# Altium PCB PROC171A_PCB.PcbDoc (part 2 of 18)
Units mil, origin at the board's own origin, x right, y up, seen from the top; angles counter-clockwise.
Board outline 7700 x 2300 mil, 6 copper layers (Top Layer, GND 1, SIG 1, SIG 2, GND 2, Bottom Layer), stack 61.062 mil thick; 945 components, 692 nets, 11945 pads, 1734 vias.

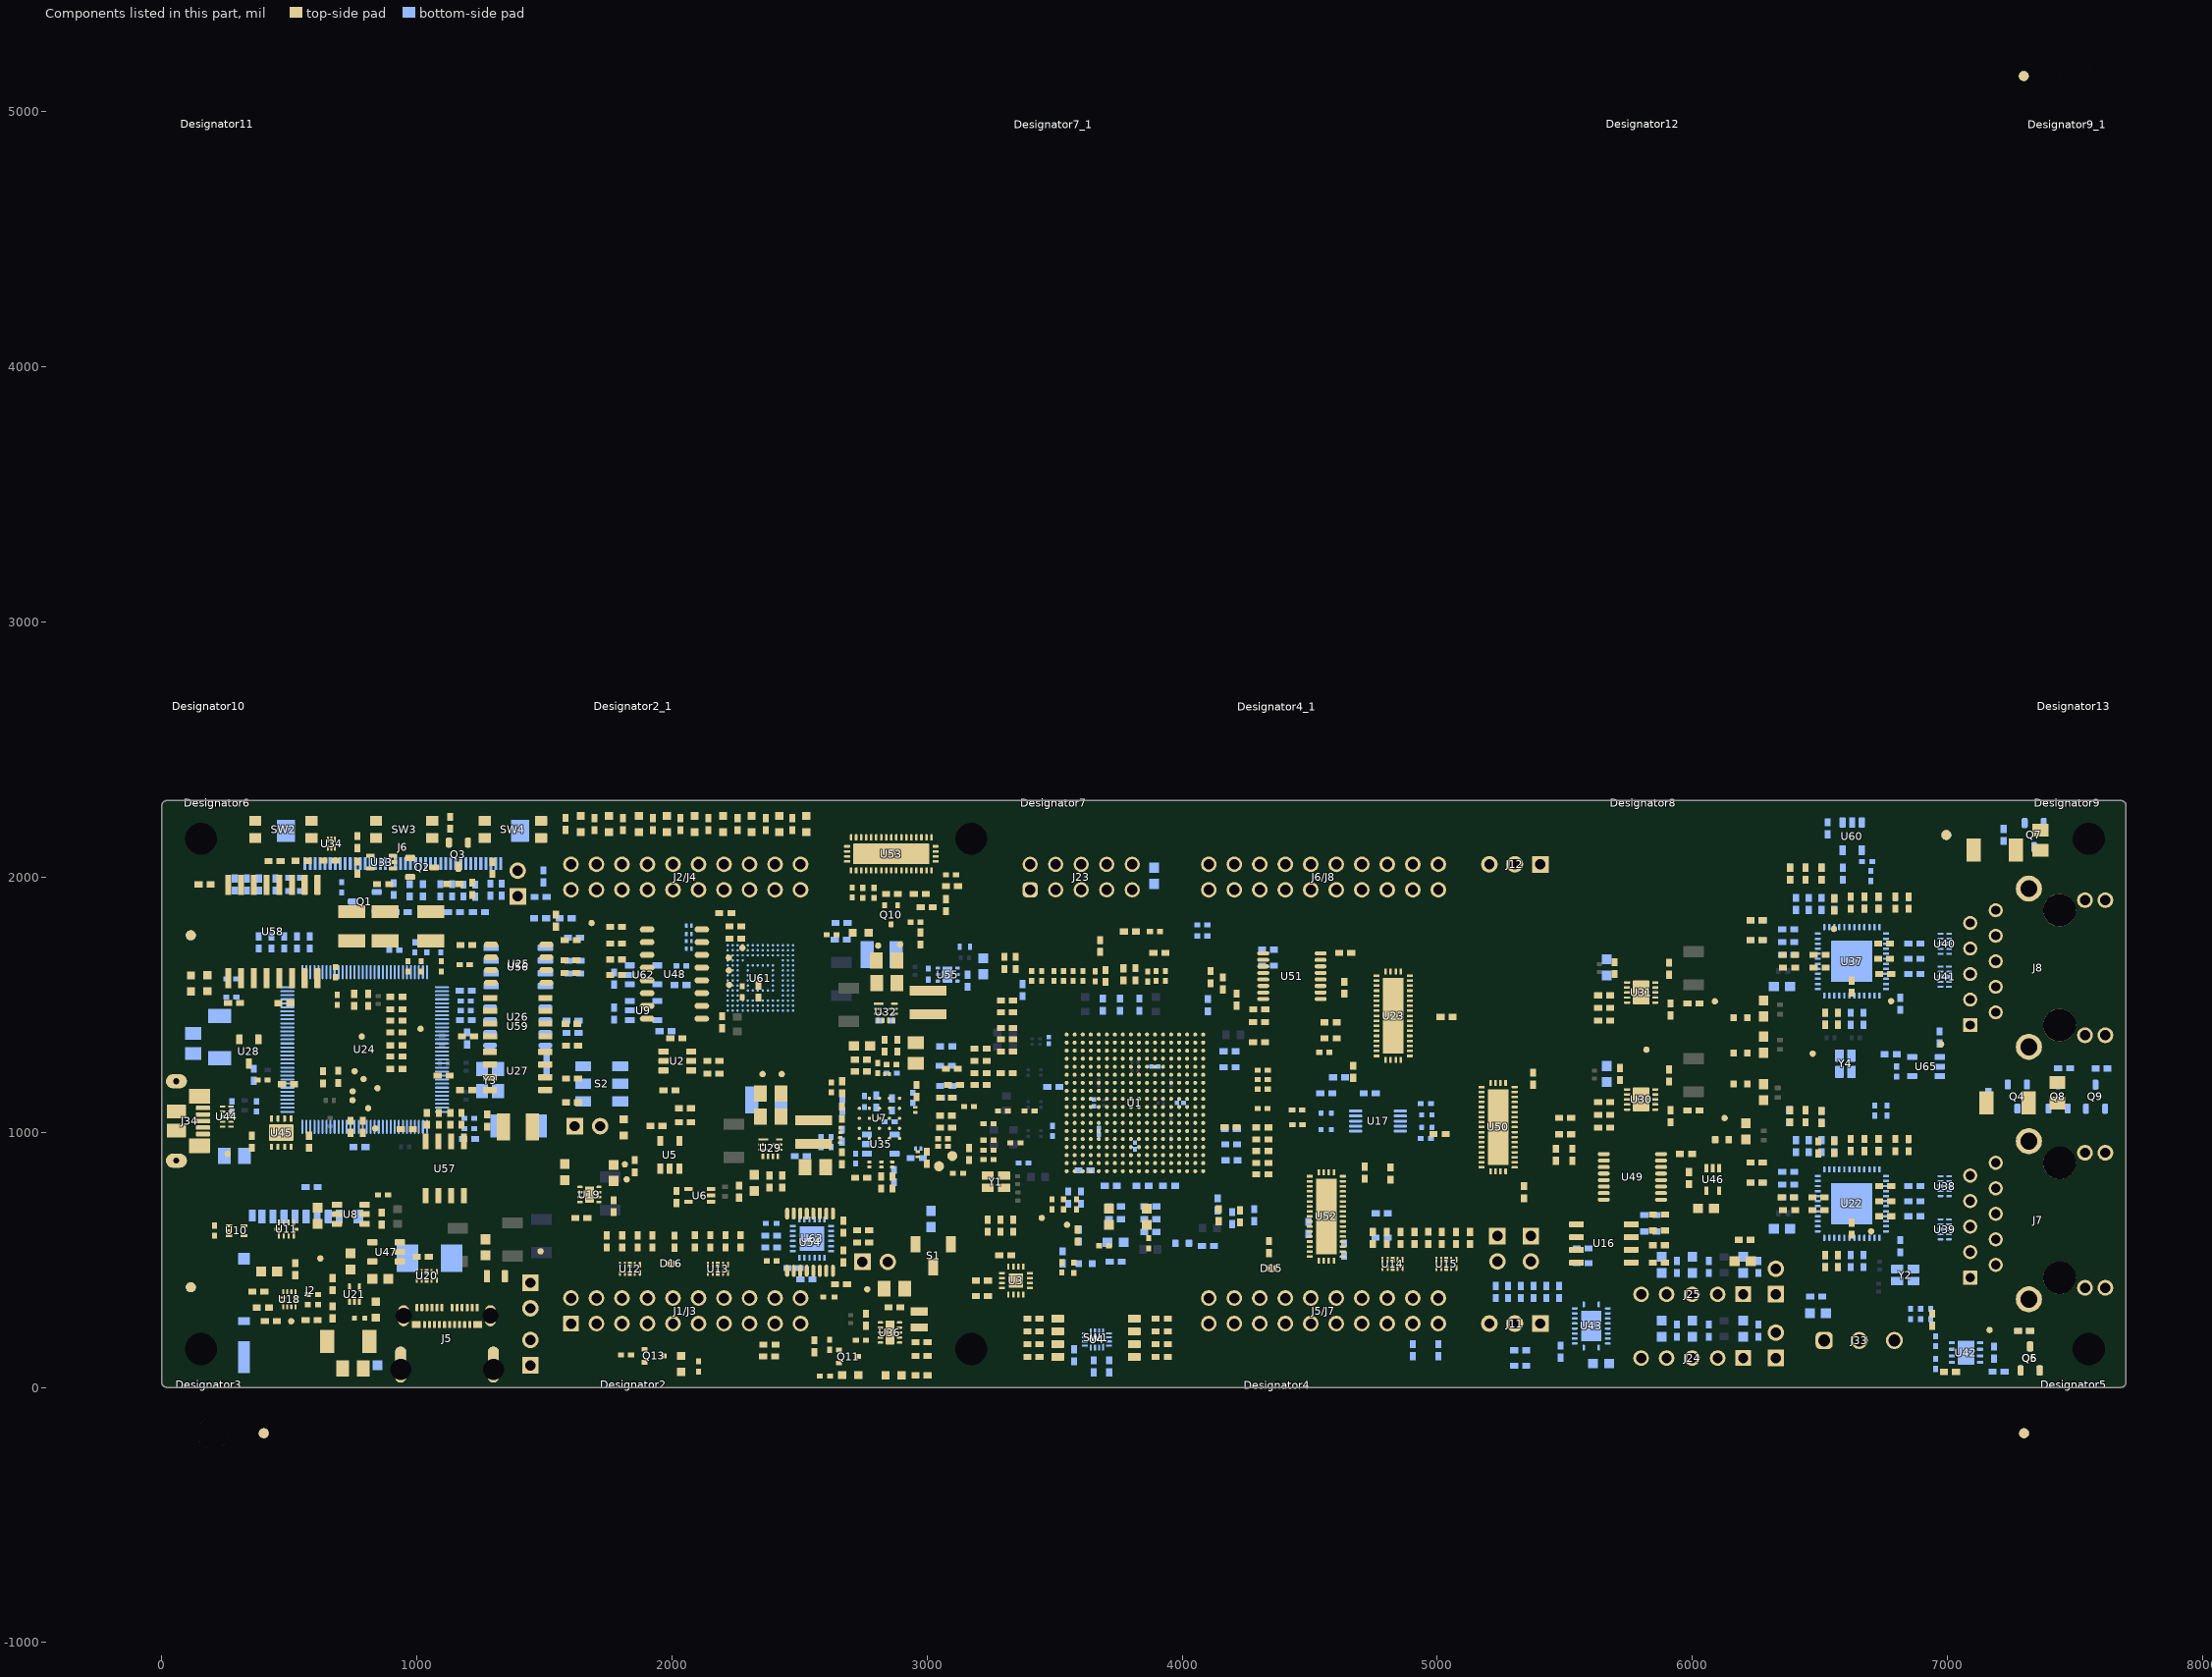
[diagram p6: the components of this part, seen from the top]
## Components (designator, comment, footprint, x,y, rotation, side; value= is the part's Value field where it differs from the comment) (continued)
C257 "GRM155R71E104KE14D" 0402 3617.11,851 r180 bottom value=0.1uF
C258 "KGM05CR51A106MH" FP-KGM05CR51A106MH_0402-MFG 2754.67,1120.32 r90 bottom value=10µF
C259 "885012105010" 0402 2870.35,828.59 r270 bottom value=0.1uF
C260 "885012105010" 0402 2662.59,404.5 r0 top value=0.1uF
C261 "KGM05CR51A106MH" FP-KGM05CR51A106MH_0402-MFG 2615.34,354.8 r180 top value=10µF
C262 "GRM155R71E104KE14D" 0402 168.23,1971.27 r180 top value=0.1uF
C263 "885012105010" 0402 6589.21,2013.14 r270 bottom value=0.1uF
C264 "885012105010" 0402 2338.77,1551.57 r270 top value=0.1uF
C265 "KGM05CR51A106MH" FP-KGM05CR51A106MH_0402-MFG 2274.78,1550.65 r270 top value=10µF
C266 "C1005X6S1C105K050BC" 0402 2664.95,1820.24 r0 bottom value=1uF
C267 "885012105010" 0402 2033.53,1577 r0 bottom value=0.1uF
C268 "885012105010" 0402 2389,548.03 r180 bottom value=0.1uF
C269 "KGM05CR51A106MH" FP-KGM05CR51A106MH_0402-MFG 2389,642.68 r180 bottom value=10µF
C270 "885012105010" 0402 6777.35,1305.89 r180 bottom value=0.1uF
C271 "885012105010" 0402 2862.44,1108.7 r90 bottom value=0.1uF
C272 "885012105010" 0402 2667.72,1107.14 r270 bottom value=0.1uF
"CAUTION HOT SURFACE" "CAUTION HOT SURFACE" IEC_HotSurface_Small 4010.45,1541.41 r0 top
D1 "SMBJ6.5CA" SMB-Bi 1049.65,505.45 r0 bottom value=6.5V
D2 "150060VS75000" WL-SMCW_GREEN 1810.94,1018.81 r270 top value=Green
D3 "150060VS75000" WL-SMCW_GREEN 178.78,1584.03 r90 top value=Green
D4 "150060VS75000" WL-SMCW_GREEN 2526.43,2208.3 r90 top value=Green
D5 "150060VS75000" WL-SMCW_GREEN 2036.27,91.9 r270 top value=Green
D6 "150060VS75000" WL-SMCW_GREEN 2868.49,47.06 r0 top value=Green
D7 "150060VS75000" WL-SMCW_GREEN 2421.16,2208.3 r90 top value=Green
D8 "150060VS75000" WL-SMCW_GREEN 2312.35,2208.3 r90 top value=Green
D9 "150060VS75000" WL-SMCW_GREEN 2200.52,2208.3 r90 top value=Green
D10 "150060VS75000" WL-SMCW_GREEN 2088.59,2208.3 r90 top value=Green
D11 "150060VS75000" WL-SMCW_GREEN 1980.11,2208.3 r90 top value=Green
D12 "150060VS75000" WL-SMCW_GREEN 1870.7,2208.3 r90 top value=Green
D13 "150060VS75000" WL-SMCW_GREEN 1753.16,2208.3 r90 top value=Green
D14 "150060VS75000" WL-SMCW_GREEN 1642.17,2208.3 r90 top value=Green
D15 "TPD1E01B04DPYR" DPY0002A 4351.58,466.66 r180 top
D16 "TPD1E01B04DPYR" DPY0002A 1997.72,485.1 r180 top
Designator2 "Comment" BRAKE_WAY_HOLES1X3 1848.57,-39.37 r0 top
Designator2_1 "Comment" BRAKE_WAY_HOLES1X3 1848.57,2620.63 r0 top
Designator3 "Comment" BRAKE_WAY_HOLES1X3 184.09,-39.37 r0 top
Designator4 "Comment" BRAKE_WAY_HOLES1X3 4372.53,-40.63 r0 top
Designator4_1 "Comment" BRAKE_WAY_HOLES1X3 4372.53,2619.37 r0 top
Designator5 "Comment" BRAKE_WAY_HOLES1X3 7494.59,-39.37 r0 top
Designator6 "Comment" BRAKE_WAY_HOLES1X3 218.32,2340.63 r180 top
Designator7 "Comment" BRAKE_WAY_HOLES1X3 3496.1,2339.37 r180 top
Designator7_1 "Comment" BRAKE_WAY_HOLES1X3 3496.1,4999.37 r180 top
Designator8 "Comment" BRAKE_WAY_HOLES1X3 5807.39,2340.63 r180 top
Designator9 "Comment" BRAKE_WAY_HOLES1X3 7469.96,2339.37 r180 top
Designator9_1 "Comment" BRAKE_WAY_HOLES1X3 7469.96,4999.37 r180 top
Designator10 "Comment" BRAKE_WAY_HOLES1X3 184.09,2620.63 r0 top
Designator11 "Comment" BRAKE_WAY_HOLES1X3 217.32,5000.63 r180 top
Designator12 "Comment" BRAKE_WAY_HOLES1X3 5806.39,5000.63 r180 top
Designator13 "Comment" BRAKE_WAY_HOLES1X3 7494.59,2620.63 r0 top
DS1 "150060RS75000" WL-SMCW_RED 2739.41,1781.37 r180 top value=Red
DS2 "150060RS75000" WL-SMCW_RED 2698.87,47.97 r180 top value=Red
DS3 "150060RS75000" WL-SMCW_RED 115.08,1583.47 r90 top value=Red
DS4 "150060RS75000" WL-SMCW_RED 838.68,304.16 r270 top value=Red
FB1 "BLM18EG121SN1D" FP-BLM18EG121SN1D_0603-MFG 4000.08,564.71 r180 bottom
FB2 "BLM18EG121SN1D" FP-BLM18EG121SN1D_0603-MFG 3621.02,485 r180 bottom
FB3 "BLM18EG121SN1D" FP-BLM18EG121SN1D_0603-MFG 6188.68,1310.55 r0 top
FB4 "BLM18EG121SN1D" FP-BLM18EG121SN1D_0603-MFG 6115.92,970.9 r0 top
FB5 "BLM18EG121SN1D" FP-BLM18EG121SN1D_0603-MFG 6188.68,1449.44 r0 top
FB6 "BLM18EG121SN1D" FP-BLM18EG121SN1D_0603-MFG 6188.68,1188.64 r0 top
FID1 "Fiducial" Fiducial10-20 6995.38,2165 r90 top
FID2 "Fiducial" Fiducial10-20 113.79,392.07 r90 top
FID3 "Fiducial" Fiducial10-20 113.79,1771.83 r90 top
FID4 "Fiducial" Fiducial10-20 6995.38,2165 r90 bottom
FID5 "Fiducial" Fiducial10-20 113.79,392.07 r90 bottom
FID6 "Fiducial" Fiducial10-20 113.79,1771.83 r90 bottom
FID7 "Fiducial" Fiducial10-20 400,-180 r90 top
FID8 "Fiducial" Fiducial10-20 7300,-180 r270 top
FID9 "Fiducial" Fiducial10-20 7299,5140 r270 top
FID10 "Fiducial" Fiducial10-20 7299,5140 r90 bottom
FID11 "Fiducial" Fiducial10-20 7300,-180 r90 bottom
FID12 "Fiducial" Fiducial10-20 400,-180 r270 bottom
J1 "PBC02SAAN" Sullins_PBC02SAAN 1395.54,1975 r180 top locked
J1/J3 "SSQ-110-03-T-D" BoosterPack_40pin_J1J3 2054.17,300 r270 bottom locked
J2 "DM3BT-DSF-PEJS" Hirose_DM3BT-DSF-PEJS 570,362.52 r180 bottom locked
J2/J4 "SSQ-110-03-T-D" BoosterPack_40pin_J2J4 2054.17,2000 r270 bottom locked
J5 "2012670005" FP-2012670005_CONN_USB_9MM39_8MM21-MFG 1118.35,154.53 r0 top locked
J5/J7 "SSQ-110-03-T-D" BoosterPack_40pin_J5J7 4554.17,300 r270 bottom locked
J6 "FH12A-40S-0.5SH(55)" FP-FH12A-40S-0.5SH(55)_FFC40-MFG 945.63,2200 r180 bottom locked
J6/J8 "SSQ-110-03-T-D" BoosterPack_40pin_J6J8 4554.17,2000 r270 bottom locked
J7 "LPJG16314A4NL" FP-LPJG16314A4NL_CONN_RJ45-MFG 7444,655 r90 top locked
J8 "LPJG16314A4NL" FP-LPJG16314A4NL_CONN_RJ45-MFG 7444,1645 r90 top locked
J9 "PBC02SAAN" Sullins_PBC02SAAN 1445,136.05 r180 top
J10 "PBC02SAAN" Sullins_PBC02SAAN 1445,360 r0 top
J11 "PBC03SAAN" PBC03SAAN 5304.17,250 r180 top locked
J12 "PBC03SAAN" PBC03SAAN 5304.17,2050 r180 top locked
J13 "PBC02SAAN" Sullins_PBC02SAAN 5235.83,543.25 r0 top
J14 "PBC02SAAN" Sullins_PBC02SAAN 5367.11,543.25 r0 top
J15 "PBC02SAAN" Sullins_PBC02SAAN 6327.06,165 r180 top
J16 "PBC02SAAN" Sullins_PBC02SAAN 6327.06,415 r180 top
J17 "PBC02SAAN" Sullins_PBC02SAAN 1668.62,1023.77 r90 top
J18 "PBC02SAAN" Sullins_PBC02SAAN 2796.34,491.93 r90 top
J23 "PRPC005DAAN-RC" Sullins_xxPC005DAAN-RC 3604.17,2000 r90 top locked
J24 "PEC05SAAN" Sullins_PxC05SAAN 5999.18,115 r180 top locked
J25 "PEC05SAAN" Sullins_PxC05SAAN 5999.18,365 r180 top locked
J33 "OSTTE030161" On-Shore_OSTTE030161 6654.17,183.86 r0 top locked
J34 "1051640001" Molex_1051640001 0,1044.08 r270 top
L1 "BLM21PG300SN1D" FP-BLM21PG300SN1D_0805-MFG 1309.67,435.62 r0 top
L2 "74438356022" WE-MAPI_4020 2555.75,1000.74 r90 top value=2.2uH
L3 "74438356022" WE-MAPI_4020 3003.77,1508.9 r90 top value=2.2uH
L4 "74405020100" FP-74405020100_SMT_IND_2MM0_1MM6-MFG 2968.49,266.14 r90 top
LBL1 "THT-14-423-10" Label_650x200 6610,2187.06 r0 top
Logo1 "CE Mark" CE_Mark_5mm 564.56,1375.69 r0 top
Logo2 "Texas Instruments" TI_Stacked_Overlay_Small 5135,1778.31 r0 top locked
Logo3 "FCC disclaimer" FCC_disclaimer 9836.36,4289 r270 bottom
Logo4 "WEEE logo" WEEE_Minimum 6005,838.02 r180 bottom
Q1 "IRLML6401TRPBF" SOT-23 795.63,1904.12 r180 bottom value=-12V
Q2 "IRLML6401TRPBF" SOT-23 1021,2038 r0 top value=-12V
Q3 "IRLML6401TRPBF" SOT-23 1163.12,2088.08 r270 top value=-12V
Q4 "BSS123" SOT-23 7274.1,1140 r270 bottom value=100V
Q5 "BSS123" SOT-23 7324,113.66 r90 top value=100V
Q6 "BSS123" SOT-23 7324,113.66 r90 bottom value=100V
Q7 "BSS123" SOT-23 7340,2165 r270 bottom value=100V
Q8 "BSS123" SOT-23 7433.87,1140.67 r90 bottom value=100V
Q9 "BSS123" SOT-23 7580.33,1139.39 r90 bottom value=100V
Q10 "BSS223PWH6327" SOT-323 2859.06,1852.03 r270 top value=-20V
Q11 "BSS123W-7-F" SOT-323 2692.53,120.9 r0 top value=100V
Q13 "BSS123W-7-F" SOT-323 1930,123.39 r0 top value=100V
R1 "ERJ-2RKF1002X" 0402 3237.47,633.24 r270 top value=10.0k
R2 "CRCW04022K67FKED" 0402 3337.66,633.24 r90 top value=2.67k
R3 "ERJ-2GE0R00X" 0402L 3575.19,468.53 r90 top value=0
R4 "ERJ-2GE0R00X" 0402L 3240.9,969.06 r180 top value=0
R5 "ERJ-2GE0R00X" 0402 1773.66,1464.57 r270 bottom value=0
R6 "ERJ-2RKF1002X" 0402 2162.72,1229.13 r180 top value=10.0k
R7 "ERJ-2GE0R00X" 0402L 3410,1612.48 r270 top value=0
R8 "ERJ-2RKF1002X" 0402 3576.64,125.28 r90 bottom value=10.0k
R9 "CRCW040222R0JNED" 0402 3097.27,1248.26 r0 top value=22
R10 "ERJ-2RKF1002X" 0402 3215,358.58 r0 top value=10.0k
R11 "ERJ-2RKF1002X" 0402 3306.84,517.07 r0 top value=10.0k
R12 "CRCW040222R0JNED" 0402 3074.77,1135.05 r0 top value=22
R13 "CRCW040222R0JNED" 0402 3105.15,1185.36 r0 top value=22
R14 "ERJ-2RKF1002X" 0402 3417.2,119.51 r0 top value=10.0k
R15 "ERJ-2RKF1002X" 0402 3417.2,169.51 r0 top value=10.0k
R16 "ERJ-2RKF1002X" 0402 3417.2,219.51 r0 top value=10.0k
R17 "ERJ-2RKF1002X" 0402 3417.2,269.43 r0 top value=10.0k
R18 "ERJ-2GE0R00X" 0402 2050.8,1039.07 r0 top value=0
R19 "ERJ-2RKF49R9X" 0402 2262.84,767.39 r270 top value=49.9
R20 "ERJ-2RKF1002X" 0402 2050.8,1094.07 r180 top value=10.0k
R21 "ERJ-2GEJ102X" 0402 1545,1829.63 r90 top value=1.0k
R22 "ERJ-2GEJ102X" 0402 3920,119.51 r180 top value=1.0k
R23 "ERJ-2GEJ102X" 0402 3920,169.51 r180 top value=1.0k
R24 "ERJ-2GEJ102X" 0402 3920,219.51 r180 top value=1.0k
R25 "ERJ-2GEJ102X" 0402 3920,269.51 r180 top value=1.0k
R26 "ERJ-2GE0R00X" 0402L 2624.76,1175.79 r90 top value=0
R27 "CRCW020122R0FNED" "FP-CRCW020122R0FNED_0201 (0603 metric)-MFG" 2820.72,873.38 r90 top
R28 "CRCW020122R0FNED" "FP-CRCW020122R0FNED_0201 (0603 metric)-MFG" 2660.72,1008.32 r270 top
R29 "CRCW020122R0FNED" "FP-CRCW020122R0FNED_0201 (0603 metric)-MFG" 2954.22,1087.86 r270 top
R30 "CRCW020122R0FNED" "FP-CRCW020122R0FNED_0201 (0603 metric)-MFG" 2965.47,935.56 r180 bottom
R31 "CRCW040210K0FKED" 0402L 3240.9,893.53 r0 top value=10.0k
R32 "ERJ-6GEY0R00V" 0805_HV 749.55,73.93 r180 top value=0
R33 "ERJ-2GE0R00X" 0402L 3659.54,1611.36 r90 top value=0
R34 "ERJ-2GE0R00X" 0402L 3573,1612.48 r90 top value=0
R35 "ERJ-2GE0R00X" 0402L 3611,1612.48 r90 top value=0
R36 "ERJ-2GE0R00X" 0402L 3535,1612.48 r90 top value=0
R37 "ERJ-2GE0R00X" 0402L 3497,1612.48 r90 top value=0
R38 "ERJ-2GE0R00X" 0402L 3449,1612.48 r90 top value=0
R39 "CRCW040210K0FKED" 0402L 867.24,754.8 r180 top value=10.0k
R40 "CRCW040210K0FKED" 0402L 206.73,614.21 r90 top value=10.0k
R41 "CRCW040210K0FKED" 0402L 3678.01,1730 r90 bottom value=10.0k
R42 "ERJ-2RKF1002X" 0402 3164.53,914.8 r270 top value=10.0k
R43 "ERJ-2RKF1002X" 0402 2665.66,987 r270 bottom value=10.0k
R44 "ERJ-2GE0R00X" 0402L 3869.54,564.73 r90 top value=0
R45 "ERJ-2GE0R00X" 0402L 3528.72,469.92 r90 top value=0
R46 "CRCW040222R0JNED" 0402 3347.99,1663.62 r270 top value=22
R47 "CRCW040222R0JNED" 0402 3303.11,1663.55 r270 top value=22
R48 "CRCW040222R0JNED" 0402 3373.91,1557.47 r270 bottom value=22
R49 "CRCW040222R0JNED" 0402 3312.84,1409.18 r0 top value=22
R50 "CRCW040222R0JNED" 0402 3312.84,1516.7 r0 top value=22
R51 "CRCW040222R0JNED" 0402 3312.84,1469.53 r0 top value=22
R52 "CRCW040222R0JNED" 0402 3313.3,1316.91 r0 top value=22
R53 "CRCW040222R0JNED" 0402 3075,1336.34 r0 bottom value=22
R54 "CRCW040222R0JNED" 0402 3209.68,1327.26 r0 top value=22
R55 "CRCW04024K70JNED" 0402 2382.33,167.34 r180 top value=4.7k
R56 "CRCW04024K70JNED" 0402 2380.96,121 r180 top value=4.7k
R57 "CRCW040222R0JNED" 0402 3209.68,1279.26 r0 top value=22
R58 "CRCW040222R0JNED" 0402 3209.68,1231.26 r0 top value=22
R59 "CRCW040222R0JNED" 0402 3075,1181.51 r0 bottom value=22
R60 "CRCW040222R0JNED" 0402 3077.77,1135.05 r0 bottom value=22
R61 "ERJ-2RKF33R0X" 0402L 4955.28,975.79 r0 bottom value=33.0
R62 "ERJ-2RKF33R0X" 0402L 4955.28,1111.7 r0 bottom value=33.0
R63 "ERJ-2GEJ152X" FP-ERJ-2GEJ152X_0402-MFG 4959.21,1019.06 r0 bottom value=1.5k
R64 "ERJ-2GEJ152X" FP-ERJ-2GEJ152X_0402-MFG 4959.21,1068.43 r0 bottom value=1.5k
R65 "CRCW040222R0JNED" 0402 4314.45,834.48 r180 top value=22
R66 "CRCW040222R0JNED" 0402 4314.45,878.82 r180 top value=22
R67 "CRCW040222R0JNED" 0402 4314.45,926.55 r180 top value=22
R68 "CRCW040222R0JNED" 0402 4314.45,972.1 r180 top value=22
R69 "CRCW040222R0JNED" 0402 4189.92,1020.57 r180 top value=22
R70 "CRCW040222R0JNED" 0402 4314.45,1019.06 r180 top value=22
R71 "ERJ-2RKF33R0X" 0402L 4315.34,1092.85 r180 top value=33.0
R72 "ERJ-2RKF33R0X" 0402L 4451.61,1086.73 r180 top value=33.0
R73 "ERJ-2GEJ152X" FP-ERJ-2GEJ152X_0402-MFG 4564.79,1010.55 r180 bottom value=1.5k
R74 "ERJ-2GEJ152X" FP-ERJ-2GEJ152X_0402-MFG 4564.79,1074.9 r180 bottom value=1.5k
R75 "ERJ-2GE0R00X" 0402L 4451.61,1029.87 r180 bottom value=0
R76 "ERJ-2GE0R00X" 0402L 4452.24,1029.87 r180 top value=0
R77 "ERJ-2GE0R00X" 0402L 4315.93,1205.86 r180 top value=0
R78 "ERJ-2GE0R00X" 0402L 4557.16,1313.21 r180 top value=0
R79 "ERJ-2GE0R00X" 0402L 4449.67,1086.88 r180 bottom value=0
R80 "ERJ-2GE0R00X" 0402L 4315.93,1168.86 r180 top value=0
R81 "CRCW040222R0JNED" 0402 4302.01,1481.77 r180 top value=22
R82 "CRCW040222R0JNED" 0402 4212.87,1519.61 r270 top value=22
R83 "CRCW040222R0JNED" 0402 4301.24,1353.13 r180 top value=22
R84 "CRCW040222R0JNED" 0402 4301.24,1431.45 r180 top value=22
R85 "CRCW040222R0JNED" 0402 4159.49,1583.39 r270 top value=22
R86 "CRCW040222R0JNED" 0402 4110.9,1607.92 r270 top value=22
R87 "ERJ-2GE0R00X" 0402L 4078.97,1769.24 r180 bottom value=0
R88 "ERJ-2GE0R00X" 0402L 4078.97,1812.24 r180 bottom value=0
R89 "ERJ-2GE0R00X" 0402L 592.82,324.31 r0 top value=0
R90 "ERJ-2GE0R00X" 0402L 592.82,364.41 r0 top value=0
R91 "CRCW0402200KJNED" 0402 587.51,263.69 r0 top value=200k
R92 "ERJ-2RKF1002X" 0402 669.95,404.69 r270 top value=10.0k
R93 "ERJ-2RKF1002X" 0402 669.95,294.31 r90 top value=10.0k
R94 "CRCW0402909KFKED" 0402 427.85,260.08 r180 top value=909k
R95 "CRCW04024K70JNED" 0402 396.4,312.6 r0 top value=4.7k
R96 "ERJ-2GEJ102X" 0402 5986.5,820 r270 top value=1.0k
R97 "ERJ-2GEJ102X" 0402 523.29,463.41 r270 top value=1.0k
R98 "ERJ-2RKF1002X" 0402 1645,663.27 r0 top value=10.0k
R99 "CRCW040222R0JNED" 0402 3074.04,1064.94 r0 top value=22
R100 "ERJ-2GE0R00X" 0402 6375.51,745.04 r0 bottom value=0
R101 "ERJ-2GE0R00X" 0402 6506.28,945 r270 bottom value=0
R102 "ERJ-2GE0R00X" 0402 6375.51,795.04 r0 bottom value=0
R103 "ERJ-2GE0R00X" 0402 6375.51,845.04 r0 bottom value=0
R104 "ERJ-2GE0R00X" 0402 6406.28,945 r270 bottom value=0
R105 "ERJ-2GE0R00X" 0402 6456.28,945 r270 bottom value=0
R106 "ERJ-2GE0R00X" 0402 6493.31,940.44 r90 top value=0
R107 "ERJ-2RKF1152X" 0402 6815,553.37 r90 bottom value=11.5k
R108 "CRCW04022K49FKED" 0402 6251.3,802.65 r180 top value=2.49k
R109 "CRCW04022K49FKED" 0402 6251.38,880.96 r180 top value=2.49k
R110 "CRCW04022K49FKED" 0402 6729.39,950.08 r90 top value=2.49k
R111 "CRCW04022K49FKED" 0402 6796.28,949.68 r90 top value=2.49k
R112 "CRCW04022K49FKED" 0402 6674.39,950.08 r90 top value=2.49k
R113 "CRCW04022K49FKED" 0402 6506.28,1059.68 r90 top value=2.49k
R114 "CRCW04022K49FKED" 0402 6520,495 r270 top value=2.49k
R115 "CRCW04022K49FKED" 0402 6383.01,1062.96 r90 top value=2.49k
R116 "CRCW04022K49FKED" 0402 6443.01,1062.97 r90 top value=2.49k
R117 "ERJ-2GE0R00X" 0402 6570,495 r90 bottom value=0
R118 "ERJ-2GE0R00X" 0402 6520,495 r90 bottom value=0
R119 "ERJ-2GE0R00X" 0402 6620,495 r90 bottom value=0
R120 "CRCW04022K49FKED" 0402 6251.3,802.65 r0 bottom value=2.49k
R121 "CRCW04022K49FKED" 0402 6251.49,880.85 r0 bottom value=2.49k
R122 "CRCW04022K49FKED" 0402 6729.39,950.08 r270 bottom value=2.49k
R123 "CRCW04022K49FKED" 0402 6848,949.68 r270 top value=2.49k
R124 "CRCW04022K49FKED" 0402 6674.39,950.08 r270 bottom value=2.49k
R125 "CRCW04022K49FKED" 0402 6506.28,1059.68 r270 bottom value=2.49k
R126 "CRCW04022K49FKED" 0402 6570.85,495 r90 top value=2.49k
R127 "CRCW04022K49FKED" 0402 6379.14,1062.97 r270 bottom value=2.49k
R128 "CRCW04022K49FKED" 0402 6443.01,1062.97 r270 bottom value=2.49k
R129 "ERJ-2GE0R00X" 0402 380.5,1744.01 r270 bottom value=0
R130 "ERJ-2GE0R00X" 0402L 1205.5,1054.21 r180 bottom value=0
R131 "ERJ-2GE0R00X" 0402 430.5,1744.01 r270 bottom value=0
R132 "ERJ-2GEJ101X" 0402L 1205.5,1014.22 r0 bottom value=100
R133 "CRCW040233R2FKED" 0402 480.5,1744.01 r270 bottom value=33.2
R134 "CRCW040233R2FKED" 0402 530.5,1744.01 r270 bottom value=33.2
R135 "CRCW040233R2FKED" 0402 580.5,1744.01 r270 bottom value=33.2
R136 "CRCW0402330KFKED" 0402L 275.17,1101.38 r90 bottom value=330k
R137 "CRCW0402330KFKED" 0402L 371.47,1101.38 r270 bottom value=330k
R138 "CRCW04021K00FKED" 0402L 1187.62,1656.39 r0 bottom value=1.00k
R139 "CRCW04021K00FKED" 0402L 1093.35,1724.68 r90 bottom value=1.00k
R140 "CRCW04021K00FKED" 0402L 1039.13,1724.68 r90 bottom value=1.00k
R141 "CRCW04021K00FKED" 0402L 992.24,1724.68 r90 bottom value=1.00k
R142 "CRCW040249R9FKED" 0402L 1191.36,1514.93 r0 bottom value=49.9
R143 "CRCW040210K0FKED" 0402L 1191.36,1476.93 r0 bottom value=10.0k
R144 "CRCW04021K00FKED" 0402L 395.32,1204.12 r180 top value=1.00k
R145 "CRCW04024K87FKED" 0402L 911.79,1713.62 r0 bottom value=4.87k
R146 "ERJ-2RKF1002X" 0402 2504.87,906.39 r0 bottom value=10.0k
R147 "ERJ-2RKF1002X" 0402 5654.13,1117.63 r180 top value=10.0k
R148 "ERJ-6ENF1822V" 0805_HV 2562.66,862.92 r180 top value=18.2k
R149 "ERJ-2GE0R00X" 0402 5654.13,1017.63 r0 top value=0
R150 "ERJ-2GE0R00X" 0402 5654.13,1067.63 r0 top value=0
R151 "CRCW04023K57FKED" 0402 6004.13,1085.98 r0 top value=3.57k
R152 "CRCW04021K69FKED" 0402 5914.13,1062.36 r90 top value=1.69k
R153 "CRCW04022K49FKED" 0402 2432.33,806.68 r270 top value=2.49k
R154 "CRCW04024K99FKED" 0402 2382.33,806.68 r90 top value=4.99k
R155 "ERJ-2RKF1002X" 0402 5654.13,1536.82 r180 top value=10.0k
R156 "ERJ-2RKF1002X" 0402 2836.57,1437.88 r180 bottom value=10.0k
R157 "ERJ-2GE0R00X" 0402 5654.13,1436.82 r0 top value=0
R158 "ERJ-2GE0R00X" 0402 5654.13,1486.82 r0 top value=0
R159 "CRCW04021K87FKED" 0402 6004.13,1505.17 r0 top value=1.87k
R160 "ERJ-6ENF1822V" 0805_HV 2956.47,1310.85 r90 top value=18.2k
R161 "CRCW04024K99FKED" 0402 5914.13,1481.55 r90 top value=4.99k
R162 "CRCW040215K4FKED" 0402 2884,1339.3 r270 top value=15.4k
R163 "CRCW04024K99FKED" 0402 2834,1339.3 r90 top value=4.99k
R164 "CRCW040222R0JNED" 0402 3699.91,1612.61 r270 top value=22
R165 "ERJ-2GE0R00X" 0402L 3491.78,1005.11 r90 bottom value=0
R166 "CRCW040222R0JNED" 0402 3769.66,1618.82 r270 top value=22
R167 "ERJ-2GE0R00X" 0402L 3240.9,1034.08 r0 top value=0
R168 "ERJ-2GE0R00X" 0402L 3297.5,1083.59 r0 top value=0
R169 "ERJ-2GE0R00X" 0402L 3935,1612.48 r270 top value=0
R170 "ERJ-2GE0R00X" 0402L 3893.31,1786.65 r0 top value=0
R171 "ERJ-2GE0R00X" 0402L 3897,1612.48 r270 top value=0
R172 "ERJ-2GE0R00X" 0402L 3864.43,1609.98 r270 top value=0
R173 "ERJ-2RKF1002X" 0402 3910.59,1702.62 r180 top value=10.0k
R174 "ERJ-2RKF1002X" 0402 3795.44,1786.65 r180 top value=10.0k
R175 "CRCW04024K70JNED" 0402 4904.17,146.03 r270 bottom value=4.7k
R176 "CRCW04024K70JNED" 0402 5004.17,146.03 r270 bottom value=4.7k
R177 "ERJ-2RKF1002X" 0402 909.28,1953.16 r270 bottom value=10.0k
R178 "ERJ-2RKF1002X" 0402 868,1973 r180 top value=10.0k
R179 "ERJ-2RKF1002X" 0402 766.92,2137.39 r90 top value=10.0k
R180 "ERJ-2GE0R00X" 0402L 706,1960 r90 bottom value=0
R181 "ERJ-2RKF1002X" 0402 1130,2213 r90 top value=10.0k
R182 "ERJ-2RKF1002X" 0402 1228.48,1946.94 r270 bottom value=10.0k
R183 "ERJ-2RKF1002X" 0402 1616,1762 r180 bottom value=10.0k
R184 "ERJ-2RKF1002X" 0402 1216.66,1954.05 r270 top value=10.0k
R185 "ERJ-2RKF1002X" 0402 1243.82,1862.94 r180 bottom value=10.0k
R186 "ERJ-2RKF1002X" 0402 1145.21,1862.94 r180 bottom value=10.0k
R187 "ERJ-2RKF1002X" 0402 1049.67,1862.94 r180 bottom value=10.0k
R188 "ERJ-2RKF1002X" 0402 940.27,1862.94 r0 bottom value=10.0k
R189 "ERJ-2GE0R00X" 0402L 3586.2,717.13 r270 top value=0
R190 "ERJ-2GE0R00X" 0402L 3535,717.13 r270 top value=0
R191 "CRCW04024K70JNED" 0402 1483.38,1838.89 r180 bottom value=4.7k
R192 "CRCW04024K70JNED" 0402 1583.39,1838.79 r0 bottom value=4.7k
R193 "ERJ-2GE0R00X" 0402L 2740.82,184.29 r180 top value=0
R194 "ERJ-2RKF1002X" 0402 2978.49,177.56 r0 top value=10.0k
R195 "ERJ-2RKF1003X" 0402 2978.49,122.56 r0 top value=100k
R196 "ERJ-2GE0R00X" 0402 6375.51,1695.04 r0 bottom value=0
R197 "ERJ-2GE0R00X" 0402 6506.28,1895 r270 bottom value=0
R198 "ERJ-2GE0R00X" 0402 6375.51,1745.04 r0 bottom value=0
R199 "ERJ-2GE0R00X" 0402 6375.51,1795.04 r0 bottom value=0
R200 "ERJ-2GE0R00X" 0402 6406.28,1895 r270 bottom value=0
R201 "ERJ-2GE0R00X" 0402 6456.28,1895 r270 bottom value=0
R202 "ERJ-2RKF1152X" 0402 6815,1503.37 r90 bottom value=11.5k
R203 "CRCW04022K49FKED" 0402 6251.38,1752.65 r180 top value=2.49k
R204 "CRCW04022K49FKED" 0402 6251.38,1830.96 r180 top value=2.49k
R205 "CRCW04022K49FKED" 0402 6506.28,2013.05 r90 top value=2.49k
R206 "CRCW04022K49FKED" 0402 6796.28,1899.68 r90 top value=2.49k
R207 "CRCW04022K49FKED" 0402 6674.39,1900.08 r90 top value=2.49k
R208 "CRCW04022K49FKED" 0402 6729.39,1900.08 r90 top value=2.49k
R209 "CRCW04022K49FKED" 0402 6520,1445 r270 top value=2.49k
R210 "CRCW04022K49FKED" 0402 6383.01,2012.97 r90 top value=2.49k
R211 "CRCW04022K49FKED" 0402 6443.01,2012.97 r90 top value=2.49k
R212 "ERJ-2GE0R00X" 0402 6570,1445 r90 bottom value=0
R213 "ERJ-2GE0R00X" 0402 6520,1445 r90 bottom value=0
R214 "ERJ-2GE0R00X" 0402 6620,1445 r90 bottom value=0
R215 "CRCW04022K49FKED" 0402 6251.3,1752.65 r0 bottom value=2.49k
R216 "CRCW04022K49FKED" 0402 6251.38,1830.96 r0 bottom value=2.49k
R217 "CRCW04022K49FKED" 0402 6506.28,2013.05 r270 bottom value=2.49k
R218 "CRCW04022K49FKED" 0402 6848,1899.68 r270 top value=2.49k
R219 "CRCW04022K49FKED" 0402 6674.39,1900.08 r270 bottom value=2.49k
R220 "CRCW04022K49FKED" 0402 6729.39,1900.08 r270 bottom value=2.49k
R221 "CRCW04022K49FKED" 0402 6570.97,1444.88 r90 top value=2.49k
R222 "CRCW04022K49FKED" 0402 6383.01,2012.97 r270 bottom value=2.49k
R223 "CRCW04022K49FKED" 0402 6443.01,2012.97 r270 bottom value=2.49k
R224 "CRCW0402220RJNED" 0402 7160.2,1135 r270 bottom value=220
R225 "ERJ-2GE0R00X" 0402L 6715,1084.62 r270 bottom value=0
R226 "CRCW0402220RJNED" 0402 7300.38,221.46 r180 top value=220
R227 "ERJ-2GE0R00X" 0402L 6762.73,1085 r270 bottom value=0
R228 "CRCW0402220RJNED" 0402 7300.38,221.46 r180 bottom value=220
R229 "ERJ-2GE0R00X" 0402L 6846.59,947.67 r270 bottom value=0
R230 "CRCW0402220RJNED" 0402 7220,2165 r270 bottom value=220
R231 "ERJ-2GE0R00X" 0402L 6700,2004.69 r270 bottom value=0
R232 "CRCW0402220RJNED" 0402 7457.49,1251.28 r0 bottom value=220
R233 "ERJ-2GE0R00X" 0402L 6795,1896.38 r270 bottom value=0
R234 "CRCW0402220RJNED" 0402 7603.95,1250 r0 bottom value=220
R235 "ERJ-2GE0R00X" 0402L 6848,1896.38 r270 bottom value=0
R236 "ERJ-2RKF4992X" 0402 6259.18,222.12 r90 bottom value=49.9k
R237 "ERJ-2RKF4992X" 0402 6064.18,222.13 r90 bottom value=49.9k
R238 "ERJ-2RKF4992X" 0402 5940,222.13 r90 bottom value=49.9k
R239 "ERJ-2RKF4992X" 0402 6259.18,472.12 r90 bottom value=49.9k
R240 "ERJ-2RKF4992X" 0402 6064.18,472.13 r90 bottom value=49.9k
R241 "ERJ-2RKF4992X" 0402 5940,472.13 r90 bottom value=49.9k
R242 "ERJ-2RKF4992X" 0402 6485.13,355.53 r0 bottom value=49.9k
R243 "ERJ-2RKF4992X" 0402 6205,578.2 r180 top value=49.9k
R244 "CRCW040210K0FKED" 0402L 6935,287.55 r90 bottom value=10.0k
R245 "ERJ-2GE0R00X" 0402L 3377.95,879.39 r180 bottom value=0
R246 "CRCW040261R9FKED" 0402L 6952.8,91.77 r90 bottom value=61.9
R247 "CRCW040261R9FKED" 0402L 6952.8,181.14 r270 bottom value=61.9
R248 "ERJ-2GE0R00X" 0402L 6855,287.55 r90 bottom value=0
R249 "CRCW040222R0JNED" 0402 7200,61.46 r180 bottom value=22
R250 "CRCW040210K0FKED" 0402L 6895,287.55 r270 bottom value=10.0k
R251 "CRCW040251K1FKED" 0402 631.97,1215.23 r90 top value=51.1k
R252 "CRCW040230K0FKED" 0402 691.97,1217.17 r270 top value=30.0k
R253 "ERJ-6GEY0R00V" 0805_HV 122.89,1348.06 r90 bottom value=0
R254 "ERJ-6ENF1004V" 0805_HV 7430.57,1155 r90 top value=1.00Meg
R255 "ERJ-6ENF1004V" 0805_HV 7364,2145 r90 top value=1.00Meg
R256 "ERJ-2GEJ102X" 0402 4816.77,838.02 r90 top value=1.0k
R257 "ERJ-2RKF5100X" 0402 1853.71,866.9 r270 top value=510
R258 "ERJ-2RKF1002X" 0402 2998.31,1881.79 r0 top value=10.0k
R259 "ERJ-2GEJ361X" 0402L 272.6,1530 r0 bottom value=360
R260 "ERJ-2GEJ361X" 0402L 272.6,1601.11 r0 bottom value=360
R261 "CRCW04021K00FKED" 0402L 965,1650 r270 top value=1.00k
R262 "ERJ-2RKF2200X" 0402 2367.5,2207.37 r270 top value=220
R263 "ERJ-2RKF2200X" 0402 2257.41,2207.37 r270 top value=220
R264 "ERJ-2RKF2200X" 0402 2142.37,2207.37 r270 top value=220
R265 "ERJ-2GEJ361X" 0402L 2625.92,1774.32 r180 top value=360
R266 "ERJ-2RKF2200X" 0402 2033.08,2207.37 r270 top value=220
R267 "ERJ-2RKF2200X" 0402 1925,2207.37 r270 top value=220
R268 "ERJ-2RKF1002X" 0402 2973.53,1759.53 r270 top value=10.0k
R269 "ERJ-2RKF1002X" 0402 2248.54,1807.28 r180 top value=10.0k
R270 "ERJ-2RKF1002X" 0402 1780.93,1676.88 r0 top value=10.0k
R271 "ERJ-2RKF1002X" 0402 1780.93,1804.54 r0 top value=10.0k
R272 "ERJ-2GEJ511X" 0402L 2955,1823.35 r180 top value=510
R273 "ERJ-2RKF2200X" 0402 1807.38,2207.37 r270 top value=220
R274 "ERJ-2RKF1002X" 0402 1780.93,1739.85 r0 top value=10.0k
R275 "ERJ-2RKF1002X" 0402 2248.54,1759.04 r180 top value=10.0k
R276 "ERJ-2RKF1002X" 0402 1780.93,1616.57 r0 top value=10.0k
R277 "ERJ-2RKF2200X" 0402 1696.59,2207.37 r270 top value=220
R278 "ERJ-2GEJ102X" 0402 2209.15,1859.15 r180 top value=1.0k
R279 "ERJ-2RKF2200X" 0402 1583.17,2208.5 r270 top value=220
R280 "CRCW040222R0JNED" 0402 3074.69,1018.53 r0 top value=22
R281 "CRCW040222R0JNED" 0402 3073.87,1260.59 r0 bottom value=22
R282 "CRCW040222R0JNED" 0402 4143,674.68 r90 top value=22
R283 "CRCW040222R0JNED" 0402 4195.58,663.32 r90 bottom value=22
R284 "CRCW040222R0JNED" 0402 4282.93,674.68 r90 bottom value=22
R285 "CRCW040222R0JNED" 0402 4226.22,670 r90 top value=22
R286 "ERJ-2GE0R00X" 0402L 4315.93,1243.37 r180 top value=0
R287 "ERJ-2RKF1002X" 0402 5530,911.55 r90 top value=10.0k
R288 "ERJ-2RKF1002X" 0402 4581.73,1430.9 r0 top value=10.0k
R289 "ERJ-2GEJ102X" 0402 5465.31,911.55 r90 top value=1.0k
R290 "ERJ-2GEJ102X" 0402 4581.73,1367.93 r0 top value=1.0k
R291 "ERJ-2RKF1002X" 0402 4565,1152.36 r0 bottom value=10.0k
R292 "ERJ-2RKF1002X" 0402 5501.38,1057.02 r180 top value=10.0k
R293 "ERJ-2GEJ102X" 0402 4615.26,1215.33 r180 bottom value=1.0k
R294 "ERJ-2GEJ102X" 0402 5501.38,992.02 r180 top value=1.0k
R295 "ERJ-2RKF1002X" 0402 1990,1163.59 r0 top value=10.0k
R296 "ERJ-2RKF1002X" 0402 2017.48,1367.85 r180 top value=10.0k
R297 "CRCW040222R0JNED" 0402 3817.25,1619.25 r270 top value=22
R298 "ERJ-2RKF1002X" 0402 4336.51,1715.49 r180 bottom value=10.0k
R299 "ERJ-2RKF1002X" 0402 1023.5,512.5 r0 top value=10.0k
R300 "ERJ-2GEJ102X" 0402 4336.51,1652.52 r180 bottom value=1.0k
R301 "ERJ-2RKF1002X" 0402 919.69,1437.81 r0 top value=10.0k
R302 "ERJ-2GEJ361X" 0402L 2599.61,45 r180 top value=360
R303 "ERJ-2GEJ511X" 0402L 2617.63,167.05 r270 top value=510
R304 "ERJ-2GEJ102X" 0402 2558.18,161.5 r90 top value=1.0k
R305 "ERJ-2RKF1002X" 0402 6620,950 r270 top value=10.0k
R306 "ERJ-2RKF1002X" 0402 6620,1900.08 r270 top value=10.0k
R307 "ERJ-2GE0R00X" 0402L 3693.94,555 r0 top value=0
R308 "CRCW04021K00FKED" 0402L 1016.99,1650 r270 top value=1.00k
R309 "CRCW04021K00FKED" 0402L 1095.89,1650 r270 top value=1.00k
R310 "CRCW04021K00FKED" 0402L 1186.77,1656.39 r0 top value=1.00k
R311 "CRCW04021K00FKED" 0402L 681.33,1627.52 r270 top value=1.00k
R312 "CRCW04021K00FKED" 0402L 688.16,1518.99 r270 top value=1.00k
R313 "CRCW0402130RFKED" 0402 2471.37,2207.37 r270 top value=130
R314 "ERJ-2GEJ361X" 0402L 2103.52,81.9 r90 top value=360
R315 "CRCW0402130RFKED" 0402 2978.49,47.31 r0 top value=130
R316 "ERJ-2RKF1002X" 0402 5570,545.04 r0 bottom value=10.0k
R317 "ERJ-2GEJ511X" 0402L 1819.99,127.49 r0 top value=510
R318 "ERJ-2RKF1002X" 0402 5868.93,488.21 r180 top value=10.0k
R319 "ERJ-2RKF1002X" 0402 5835.31,675 r180 bottom value=10.0k
R320 "ERJ-2RKF1002X" 0402 5868.93,676.73 r180 top value=10.0k
R321 "ERJ-2RKF1002X" 0402 5868.93,556.99 r180 top value=10.0k
R322 "ERJ-2RKF1002X" 0402 5835.31,611.02 r180 bottom value=10.0k
R323 "ERJ-2RKF1002X" 0402 5868.93,615 r180 top value=10.0k
R324 "CRCW040233R2FKED" 0402 1602.32,1674.24 r180 top value=33.2
R325 "CRCW040233R2FKED" 0402 1602.74,1624.01 r180 top value=33.2
R326 "CRCW040233R2FKED" 0402 1605.89,1424.77 r180 top value=33.2
R327 "CRCW040233R2FKED" 0402 1607.87,1210 r180 top value=33.2
R328 "CRCW040233R2FKED" 0402 5325,85 r0 bottom value=33.2
R329 "CRCW040233R2FKED" 0402 5325,145.09 r0 bottom value=33.2
R330 "CRCW040233R2FKED" 0402 5229.44,373.51 r270 bottom value=33.2
R331 "CRCW040233R2FKED" 0402 5277.45,373.51 r270 bottom value=33.2
R332 "CRCW040233R2FKED" 0402 5327.45,373.51 r270 bottom value=33.2
R333 "CRCW040233R2FKED" 0402 5377.45,373.51 r270 bottom value=33.2
R334 "CRCW040233R2FKED" 0402 5428.06,373.51 r270 bottom value=33.2
R335 "CRCW040233R2FKED" 0402 5478.01,373.51 r270 bottom value=33.2
R336 "ERJ-2RKF1002X" 0402 919.69,1248.06 r0 top value=10.0k
R337 "ERJ-2RKF1002X" 0402 919.69,1340.53 r0 top value=10.0k
R338 "ERJ-2RKF1002X" 0402 919.69,1296.56 r0 top value=10.0k
R339 "ERJ-2RKF1002X" 0402 919.69,1530.84 r0 top value=10.0k
R340 "ERJ-2RKF1002X" 0402 919.69,1481.93 r0 top value=10.0k
R341 "ERJ-2RKF1002X" 0402 919.69,1390.96 r0 top value=10.0k
R342 "ERJ-2GE0R00X" 0402 287,1971 r90 bottom value=0
R343 "ERJ-2GE0R00X" 0402 334.13,1971 r90 bottom value=0
R344 "ERJ-2GE0R00X" 0402 381.31,1971.27 r90 bottom value=0
R345 "ERJ-2GE0R00X" 0402 445,1971 r90 bottom value=0
R346 "ERJ-2GE0R00X" 0402 971.74,1948.38 r90 bottom value=0
R347 "ERJ-2GE0R00X" 0402 1024.02,1948.38 r90 bottom value=0
R348 "ERJ-2GE0R00X" 0402 1092.26,1948.38 r90 bottom value=0
R349 "ERJ-2GE0R00X" 0402 442.38,2063 r180 top value=0
R350 "ERJ-2GE0R00X" 0402 1138.11,1948.38 r90 bottom value=0
R351 "ERJ-2GE0R00X" 0402 1142.74,1973.49 r180 top value=0
R352 "ERJ-2GE0R00X" 0402 1296,2036 r90 top value=0
R353 "ERJ-2GE0R00X" 0402 548.38,2064 r180 top value=0
R354 "ERJ-2GE0R00X" 0402 1182.29,1947.37 r90 bottom value=0
R355 "ERJ-2GE0R00X" 0402 1288.1,1951.05 r90 bottom value=0
R356 "ERJ-2GE0R00X" 0402 1331.93,1951.05 r90 bottom value=0
R357 "ERJ-2GE0R00X" 0402 1496,2003 r90 bottom value=0
R358 "ERJ-2GE0R00X" 0402 1485,1923 r180 bottom value=0
R359 "ERJ-2GE0R00X" 0402 1610.28,1389.97 r0 bottom value=0
R360 "ERJ-2GE0R00X" 0402L 3489.29,717.13 r270 top value=0
R361 "CRCW020122R0FNED" "FP-CRCW020122R0FNED_0201 (0603 metric)-MFG" 2964.2,913.72 r270 top
R362 "RC0603FR-073K16L" 0603 3220.04,1650.81 r90 bottom value=3.16k
R363 "CRCW04021K50FKED" 0402 3159.18,1594.03 r90 bottom value=1.50k
R364 "ERJ-2RKF1002X" 0402 3019,1550.16 r0 bottom value=10.0k
R365 "CRCW020122R0FNED" "FP-CRCW020122R0FNED_0201 (0603 metric)-MFG" 2863.91,873.38 r90 top
R366 "CRCW020122R0FNED" "FP-CRCW020122R0FNED_0201 (0603 metric)-MFG" 2773.92,873.38 r90 top
R367 "ERJ-2RKF4992X" 0402 2666.59,898.31 r90 top value=49.9k
R368 "ERJ-2RKF4992X" 0402 2741.8,822.18 r0 top value=49.9k
R369 "ERJ-2RKF4992X" 0402 2863.91,802.7 r90 top value=49.9k
R370 "ERJ-2RKF4992X" 0402 2999.42,900.18 r90 top value=49.9k
R371 "ERJ-2RKF4992X" 0402 2959.45,898.17 r0 bottom value=49.9k
R372 "CRCW04024K70JNED" 0402 2959.2,1162.07 r90 top value=4.7k
R373 "ERJ-2RKF4992X" 0402 2666.41,1076.56 r270 top value=49.9k
R374 "ERJ-2RKF4992X" 0402 2820.1,802.7 r90 top value=49.9k
R375 "CRCW040210K0FKED" 0402L 2860.31,1265.09 r0 top value=10.0k
R376 "CRCW020122R0FNED" "FP-CRCW020122R0FNED_0201 (0603 metric)-MFG" 2659.78,969.17 r90 top
R377 "ERJ-2GE0R00X" 0402L 3240.9,929.6 r0 top value=0
R378 "ERJ-2GE0R00X" 0402L 3346.47,958.84 r0 top value=0
R379 "ERJ-2GE0R00X" 0402L 3401.94,1083.62 r0 top value=0
R380 "ERJ-2GE0R00X" 0402L 3121.15,838.71 r0 top value=0
R381 "CRCW020122R0FNED" "FP-CRCW020122R0FNED_0201 (0603 metric)-MFG" 2843.19,1227.66 r180 top
R382 "CRCW040222R0JNED" 0402 2740.42,1238.46 r0 top value=22
R383 "CRCW040210K0FKED" 0402L 3093.74,2009.27 r0 top value=10.0k
R384 "CRCW040210K0FKED" 0402L 2792.16,1938.42 r270 top value=10.0k
R385 "CRCW040210K0FKED" 0402L 2748.06,1938.42 r270 top value=10.0k
R386 "CRCW040210K0FKED" 0402L 2706.97,1939.68 r270 top value=10.0k
R387 "CRCW040210K0FKED" 0402L 2719.82,896.93 r270 bottom value=10.0k
R388 "CRCW040210K0FKED" 0402L 2853.37,1041.46 r180 bottom value=10.0k
R389 "ERJ-2RKF1002X" 0402 3074.01,1890.2 r90 top value=10.0k
R390 "ERJ-2RKF1002X" 0402 2971.45,1933.65 r180 top value=10.0k
R391 "ERJ-2GEJ102X" 0402 3097.34,1964.83 r180 top value=1.0k
R392 "ERJ-2GEJ102X" 0402 2862.46,1934.22 r0 top value=1.0k
R393 "CRCW040222R0JNED" 0402 3210.21,1184.7 r0 top value=22
R394 "ERJ-2GE0R00X" 0402L 2390.85,495.6 r0 top value=0
R395 "ERJ-2RKF1002X" 0402 2749.31,615.17 r0 top value=10.0k
R396 "ERJ-2RKF1002X" 0402 2749.3,567.58 r0 top value=10.0k
R397 "ERJ-2GEJ102X" 0402 2671.47,629.92 r270 top value=1.0k
R398 "ERJ-2GEJ102X" 0402 2671.47,513.6 r90 top value=1.0k
R399 "CRCW04024K70JNED" 0402 754.13,1518.67 r270 top value=4.7k
R400 "CRCW04024K70JNED" 0402 809.19,1518.67 r270 top value=4.7k
R401 "CRCW040222R0JNED" 0402 3678.01,1730 r270 top value=22
R402 "ERJ-2GE0R00X" 0402L 3164.64,1100.9 r0 top value=0
R403 "ERJ-2GE0R00X" 0402L 3062.78,944.62 r0 top value=0
R404 "ERJ-2GE0R00X" 0402L 3062.78,974.88 r0 top value=0
R405 "ERJ-2GE0R00X" 0402 960.54,1011.75 r180 top value=0
R406 "CRCW12100000Z0EAHP" 1210 1054.16,1807.58 r90 top value=0
R407 "CRCW04024K70JNED" 0402 1131.33,1052.57 r90 top value=4.7k
R408 "CRCW04024K70JNED" 0402 1039.15,1052.57 r90 top value=4.7k
R409 "ERJ-2GE0R00X" 0402 1617.41,1622.73 r0 bottom value=0
R410 "CRCW12100000Z0EAHP" 1210 875.14,1807.58 r90 top value=0
R411 "ERJ-2GE0R00X" 0402 1617.87,1672.84 r0 bottom value=0
R412 "CRCW12100000Z0EAHP" 1210 745.39,1807.58 r90 top value=0
R413 "ERJ-2GE0R00X" 0402 1085.82,1052.57 r90 top value=0
R414 "ERJ-2GE0R00X" 0402 1174.89,1052.57 r90 top value=0
R415 "CRCW12100000Z0EAHP" 1210 1396.11,1021.01 r0 top value=0
R416 "ERJ-2GE0R00X" 0402 1275.96,1046.03 r90 top value=0
R417 "ERJ-2RKF1002X" 0402 6530.67,2191.29 r90 bottom value=10.0k
R418 "CRCW040210K0FKED" 0402L 6684.93,2060.88 r0 bottom value=10.0k
R419 "ERJ-2RKF1002X" 0402 2661.94,1755.01 r0 bottom value=10.0k
R420 "ERJ-2RKF1002X" 0402 1773.53,1602.86 r270 bottom value=10.0k
R421 "CRCW040210K0FKED" 0402L 2036.82,1652.21 r0 bottom value=10.0k
R422 "ERJ-2RKF1002X" 0402 2527.03,423.89 r0 bottom value=10.0k
R423 "ERJ-2RKF1002X" 0402 2476.41,468.17 r0 bottom value=10.0k
R424 "ERJ-2RKF1002X" 0402 6968.46,1371.69 r270 bottom value=10.0k
R425 "CRCW040210K0FKED" 0402L 6800.32,1237.87 r90 bottom value=10.0k
R426 "ERJ-2RKF1002X" 0402 2389,595.1 r180 bottom value=10.0k
R427 "ERJ-2GE0R00X" 0402 1192.08,1439.56 r180 bottom value=0
R428 "ERJ-2GE0R00X" 0402 1610.28,1437.67 r180 bottom value=0
R429 "CRCW020122R0FNED" "FP-CRCW020122R0FNED_0201 (0603 metric)-MFG" 2066.55,1776.94 r180 bottom
R430 "CRCW020122R0FNED" "FP-CRCW020122R0FNED_0201 (0603 metric)-MFG" 2066.55,1749.33 r180 bottom
R431 "CRCW020122R0FNED" "FP-CRCW020122R0FNED_0201 (0603 metric)-MFG" 2066.55,1719.72 r180 bottom
R432 "CRCW020122R0FNED" "FP-CRCW020122R0FNED_0201 (0603 metric)-MFG" 2066.55,1810.15 r180 bottom
R433 "CRCW040222R0JNED" 0402 3312.81,1364.34 r0 top value=22
R434 "ERA-2APB621X" FP-ERA-2APB621X_0402-MFG 776.05,270.76 r180 top value=620
R435 "CRCW040210K0FKED" 0402L 2861.34,1230.99 r0 bottom value=10.0k
R436 "CRCW040222R0JNED" 0402 3312.39,1231.67 r0 top value=22
R437 "ERJ-2GEJ102X" 0402 2740.42,1284.43 r0 top value=1.0k
R438 "ERJ-2RKF1003X" 0402 2667.19,1176.34 r270 top value=100k
R439 "ERJ-2RKF1002X" 0402 378.9,374.61 r0 top value=10.0k
R440 "ERJ-2GE0R00X" 0402L 2807.13,1251.1 r90 top value=0
R441 "ERJ-2RKF1002X" 0402 4782.43,682.33 r180 bottom value=10.0k
R442 "ERJ-2GEJ102X" 0402 4781.84,586.3 r180 bottom value=1.0k
R443 "ERJ-2GE0R00X" 0402L 2944.26,1135.05 r270 bottom value=0
R444 "ERJ-2GE0R00X" 0402L 2624.41,961.88 r270 bottom value=0
R445 "ERJ-2GE0R00X" 0402L 2584.41,961.88 r270 bottom value=0
S1 "CAS-120TA" SW_CAS-120TA 3024.1,515.79 r270 top
S2 "CAS-D20TA" SW_CAS-D20TA 1724.71,1190 r180 bottom
SW1 "416131160804" FP-416131160804_SMT_SW-MFG 3662.3,194.51 r90 top
SW2 "434351045816" FP-434351045816_SMT_SW_4MM7_4MM5-MFG 477,2187 r180 top
SW3 "434351045816" FP-434351045816_SMT_SW_4MM7_4MM5-MFG 950,2187 r180 top
SW4 "434351045816" FP-434351045816_SMT_SW_4MM7_4MM5-MFG 1376.76,2187 r180 top
TP1 "TP_SM_1MM" TP_SM_1MM 3099.06,906.94 r90 top
TP2 "TP_SM_1MM" TP_SM_1MM 3046.89,866.63 r90 top
TP3 "TESTPOINT" TP_25MIL-SMT 621.55,505.45 r90 top
TP4 "TESTPOINT" TP_25MIL-SMT 1485,533.1 r180 top
TP5 "TESTPOINT" TP_25MIL-SMT 507.51,259.31 r90 top
TP6 "TESTPOINT" TP_25MIL-SMT 2765.45,384.45 r90 top
TP7 "TESTPOINT" TP_25MIL-SMT 6700.57,611.5 r180 top
TP8 "TESTPOINT" TP_25MIL-SMT 1822.57,815.29 r90 top
TP9 "TESTPOINT" TP_25MIL-SMT 2893.73,1735.51 r90 top
TP10 "TESTPOINT" TP_25MIL-SMT 2430,1228.07 r90 top
TP11 "TESTPOINT" TP_25MIL-SMT 6088.14,1513.04 r90 top
TP12 "TESTPOINT" TP_25MIL-SMT 6126.43,1055.82 r90 top
TP13 "TESTPOINT" TP_25MIL-SMT 1815.59,873.93 r90 top
TP14 "TESTPOINT" TP_25MIL-SMT 2808.54,1731.68 r90 top
TP15 "TESTPOINT" TP_25MIL-SMT 2355,1228.07 r90 top
TP16 "TESTPOINT" TP_25MIL-SMT 6471.65,1308.13 r90 top
TP17 "TESTPOINT" TP_25MIL-SMT 5820,1323.71 r90 top
TP18 "TESTPOINT" TP_25MIL-SMT 1685,1820 r90 top
TP19 "TESTPOINT" TP_25MIL-SMT 6779.03,1513.91 r0 top
TP20 "TESTPOINT" TP_25MIL-SMT 6555,1797.09 r270 top
TP21 "TESTPOINT" TP_25MIL-SMT 6975,1345.45 r90 top
TP22 "TESTPOINT" TP_25MIL-SMT 7165,225 r90 top
TP23 "TESTPOINT" TP_25MIL-SMT 258.56,915 r0 top
TP24 "TESTPOINT" TP_25MIL-SMT 748.48,1160.35 r0 top
TP25 "TESTPOINT" TP_25MIL-SMT 809.21,1094.23 r90 top
TP26 "TESTPOINT" TP_25MIL-SMT 756.03,1239.11 r0 top
TP27 "TESTPOINT" TP_25MIL-SMT 837.37,1015 r180 top
TP28 "TESTPOINT" TP_25MIL-SMT 791.17,1208.54 r270 top
TP29 "TESTPOINT" TP_25MIL-SMT 747.83,1125.66 r270 top
TP30 "TESTPOINT" TP_25MIL-SMT 845.57,1172.78 r270 top
TP31 "TESTPOINT" TP_25MIL-SMT 1014.53,1405.29 r90 top
TP32 "TESTPOINT" TP_25MIL-SMT 784.17,1375 r270 top
TP33 "TESTPOINT" TP_25MIL-SMT 3449.69,663.97 r90 top
TP34 "TESTPOINT" TP_25MIL-SMT 3548.66,637.21 r90 top
TP35 "TESTPOINT" TP_25MIL-SMT 2276.01,1722.81 r0 top
TP36 "TESTPOINT" TP_25MIL-SMT 2223.1,1683.84 r0 top
TP37 "TESTPOINT" TP_25MIL-SMT 2223.1,1634.27 r0 top
TP38 "TESTPOINT" TP_25MIL-SMT 2224.18,1577.6 r0 top
U1 "AM263PxC" ZCZ0324A-MFG 3814.85,1115.08 r0 top locked
U2 "SN74LVC1G11DBVR" DBV0006A_N 2021.24,1279.45 r0 top
U3 "TCA6408ARGTR" RGT0016A 3348.05,418.7 r90 top
U4 "SN74AVC4T245RSVR" RSV0016A 3666.07,187.78 r90 bottom
U5 "SN74LVC1G08DBVR" DBV0005A_N 1991.31,911.4 r90 top
U6 "SN74LVC1G17DCKR" DCK0005A_N 2108.67,752.39 r180 top
U7 "IS25LX256-JHLE" FP-IS25LX256-JHLE_TFBGA24-IPC_C 2813.29,1054.55 r0 top locked
U8 "TPS22918TDBVTQ1" DBV0006A_N 741.03,678.6 r180 top
U9 "SN74LVC1G08DBVR" DBV0005A_N 1888.61,1477.4 r0 bottom
U10 "TPD2E001DRLR" DRL0005A 292.78,614.21 r0 top
U11 "TPD6E001RSER" RSE0010A 488.2,620 r270 top
U12 "TPD4E02B04DQAR" DQA0010A#1 1835,464.48 r90 top
U13 "TPD4E02B04DQAR" DQA0010A#1 2180,465 r90 top
U14 "TPD4E02B04DQAR" DQA0010A#1 4825,484.12 r90 top
U15 "TPD4E02B04DQAR" DQA0010A#1 5035.4,484.26 r90 top
U16 "CAT24M01WI-GT3" SOIC-8 5652.8,564.14 r180 top
U17 "TS5A23159DGSR" DGS0010A_N 4767.68,1043.75 r0 bottom
U18 "TUSB320LIRWBR" RWB0012A 500.2,345.08 r0 top
U19 "TPS22965TDSGRQ1" DSG0008B 1676.92,755.91 r0 top
U20 "TPD4E02B04DQAR" DQA0010A#1 1038.54,436.99 r270 top
U21 "SN74AHC1G02DRLR" DRL0005A 755.3,365 r90 top
U22 "DP83869HMRGZT" RGZ0048B-MFG 6625.18,720.04 r180 bottom
U23 "TS3DDR3812RUAR" RUA0042A-MFG 4827.2,1456.5 r0 top
U24 "TM4C1294NCPDTT3" PDT0128A 795.5,1324.37 r0 bottom locked
U25 "ISO7220CDR" D0008B_N 1398.97,1660.47 r0 top
U26 "ISO7721DR" D0008B_HV 1395.62,1451.5 r180 top
U27 "ISO7721DR" D0008B_HV 1395,1240.27 r180 top
U28 "LM4040C25QDBZR" DBZ0003A_N 341.5,1316.65 r270 top
U29 "TPS62913RPUR" RPU0010A-MFG 2385.89,941.68 r180 top
U30 "TPS74801DRCR" DRC0010J 5799.13,1128.43 r0 top
U31 "TPS74801DRCR" DRC0010J 5799.13,1547.62 r0 top
U32 "TPS62913RPUR" RPU0010A-MFG 2837.56,1474.3 r180 top
U33 "SN74LVC1G07DCKT" DCK0005A_N 862,2059 r180 top
U34 "SN74LVC2G17DSF2" DSF0006A 665,2131.22 r270 top
U35 "SN74LVC1G08DBVR" DBV0005A_N 2818.52,953.35 r0 bottom
U36 "TPS62177DQCR" DQC0010A 2854.71,214.96 r0 top
U37 "DP83869HMRGZT" RGZ0048B-MFG 6625.18,1670.04 r180 bottom
U38 "TPD4E05U06DQAR" DQA0010A#2 6989.58,788.94 r180 bottom
U39 "TPD4E05U06DQAR" DQA0010A#2 6989.31,619.6 r180 bottom
U40 "TPD4E05U06DQAR" DQA0010A#2 6989.58,1738.94 r180 bottom
U41 "TPD4E05U06DQAR" DQA0010A#2 6989.31,1609.6 r180 bottom
U42 "TCAN1044VDRBTQ1" DRB0008J 7072.8,136.46 r180 bottom
U43 "TXB0108RGYR" RGY0020A 5603.66,240.62 r0 bottom
U44 "TPD4E02B04DQAR" DQA0010A#1 255,1060.81 r180 top
U45 "TPS79601DRBR" DRB0008B 468.69,998.32 r90 top
U46 "SN74LVC1G04DCKR" DCK0005A_N 6080,815 r270 top
U47 "SN74LVC1G08DBVR" DBV0005A_N 879.5,531 r180 top
U48 "TPIC2810D" D0016A_N 2010,1620 r180 top locked
U49 "SN74CB3Q3257PWR" PW0016A_L 5765,825.23 r0 top
U50 "TS3DDR3812RUAR" RUA0042A-MFG 5238.39,1020.04 r180 top
U51 "SN74CB3Q3257PWR" PW0016A_L 4430.26,1611.66 r0 top
U52 "TS3DDR3812RUAR" RUA0042A-MFG 4565,670 r180 top
U53 "TS3DDR3812RUAR" RUA0042A-MFG 2859.79,2091.04 r90 top locked
U54 "SN74CB3Q3257PWR" PW0016A_L 2541.2,569.21 r270 top
U55 "TLV75801PDRVR" DRV0006A 3080.26,1618 r180 bottom
U56 "ISO1641BDR" D0008A-MFG 1397.72,1648.36 r0 bottom
U57 "ISO1641BDR" D0008A-MFG 1109.51,857.47 r90 top
U58 "ISO6760DWR" DW0016A-MFG 435.25,1786.67 r90 top
U59 "ISO7220CDR" D0008B_N 1395.39,1415 r0 bottom
U60 "SN74LVC1G08DBVR" DBV0005A_N 6626.26,2159.77 r270 bottom
U61 "MTFC8GAMALBH-AAT" FP-MTFC8GAMALBH-AAT_TFBGA153-MFG 2346.33,1604.8 r270 bottom locked
U62 "SN74LVC1G08DBVR" DBV0005A_N 1888.61,1616.57 r0 bottom
U63 "TCA6416ARTWR" RTW0024B 2548.96,583.47 r270 bottom
U65 "SN74LVC1G08DBVR" DBV0005A_N 6915.81,1257.25 r180 bottom
Y1 "ABM10W-25.0000MHZ-4-D1X-T3" Abracon_ABM10W 3270,806.21 r90 top
Y2 "ABM10W-25.0000MHZ-4-D1X-T3" Abracon_ABM10W 6834.6,440.5 r90 bottom
Y3 "NX3225GA-16.000M-STD-CRG-1" NDK_NX3225GA 1287.13,1204.32 r180 bottom
Y4 "ABM10W-25.0000MHZ-4-D1X-T3" Abracon_ABM10W 6600,1268.41 r0 bottom
ZZ1 "This Assembly Note is for PCB labels only" AssemblyNoteLabel 139,3742 r0 top
ZZ2 "These assemblies are ESD sensitive, ESD precautions shall be observed." AssemblyNote 139,3642 r0 top
ZZ3 "These assemblies must be clean and free from flux and all contaminants. Use of no clean flux is not acceptable." AssemblyNote 139,3542 r0 top
ZZ4 "These assemblies must comply with workmanship standards IPC-A-610 Class 2, unless otherwise specified." AssemblyNote 139,3442 r0 top
? "Comment" MISTRAL_LOGO_25 6689.32,1155.04 r0 top
? "Comment" MHNP_M3_PANHEAD_PHILLIPS 3173.18,150 r0 top
? "Comment" MHNP_M3_PANHEAD_PHILLIPS 7554.17,150 r0 top
? "Comment" MHNP_M3_PANHEAD_PHILLIPS 7554.17,2150 r0 top locked
? "Comment" MHNP_M3_PANHEAD_PHILLIPS 3173.18,2150 r0 top locked
? "Comment" MHNP_M3_PANHEAD_PHILLIPS 154.17,2150 r0 top
? "Comment" MHNP_M3_PANHEAD_PHILLIPS 154.17,150 r0 top locked

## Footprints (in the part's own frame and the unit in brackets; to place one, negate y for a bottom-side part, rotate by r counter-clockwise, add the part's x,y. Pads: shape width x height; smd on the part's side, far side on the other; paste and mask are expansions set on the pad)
0201 [mm] "Data from Kemet datasheet CC101_COM dated 7/28/11"
  rect 0.46x0.42 smd mask+0.048: 1(-0.33,0) 2(0.33,0)
  body extent -0.31,-0.16 0.31,0.16, height 0.26
0402 [mm] "0402 from SM-752 data"
  rect 0.8x0.6 smd: 1(-0.6,0) 2(0.6,0)
  silkscreen extent -1.22,-0.52 1.22,0.52, body extent -0.55,-0.3 0.55,0.3, height 0.6
0402_070 [mil] "SMD, 2-Leads, Body 1.2x0.7mm, Height 0.7mm"
  rect 15x24 smd: 1(-20,0) 2(20,0)
  body extent -24,-14 24,14, height 28
0402L [mm] "0402 from SM-752 data"
  rect 0.6x0.5 smd: 1(-0.5,0) 2(0.5,0)
  body extent -0.55,-0.3 0.55,0.3, height 0.6
0603 [mm] "0603 from SM-752 data"
  rect 1x0.95 smd: 1(-0.8,0) 2(0.8,0)
  silkscreen extent -1.52,-0.69 1.52,0.69, body extent -0.87,-0.47 0.87,0.47, height 1
0805_HV [mil] "0805 with 30mil clearance between pads"
  rect 50x63 smd: 1(-40,0) 2(40,0)
  silkscreen extent -74,-40 74,40, body extent -43,-29 43,29, height 57
1210 [mm] "1210 from SM-752 data"
  rect 1.3x2.7 smd: 1(-1.45,0) 2(1.45,0)
  silkscreen extent -2.32,-1.57 2.32,1.57, body extent -1.7,-1.35 1.7,1.35, height 1.35
1210_270 [mm] "1210"
  rect 1.3x2.7 smd: 1(-1.45,0) 2(1.45,0)
  silkscreen extent -2.32,-1.57 2.32,1.57, body extent -1.7,-1.35 1.7,1.35, height 2.7
1808 [mm] "Chip Capacitor, Body 4.6x2.0mm, IPC Medium Density"
  rect 1.4x2.3 smd: 1(-2.1,0) 2(2.1,0)
  silkscreen extent -3.1,-1.45 3.1,1.45, body extent -2.47,-1.2 2.47,1.2, height 2.03
Abracon_ABM10W [mm] "SMD, 4-Leads, Body 2x2.5mm"
  rrect12% 0.85x1.2 smd: 1(-0.6,0.813) 2(-0.6,-0.813) 3(0.6,-0.813) 4(0.6,0.813)
  body extent -1.05,-1.3 1.05,1.3, height 0.6
AssemblyNote [mil] "Assembly Note"
AssemblyNoteLabel [mil] "Assembly Note for PCB Labels"
BoosterPack_40pin_J1J3 [mm] "Receptacle, 2.54mm, 10x2, TH"
  rrect6% 1.55x1.55 hole 1.02: 1(1.27,11.43)
  round 1.55 hole 1.02: 2(1.27,8.89) 3(1.27,6.35) 4(1.27,3.81) 5(1.27,1.27) 6(1.27,-1.27) 7(1.27,-3.81) 8(1.27,-6.35) 9(1.27,-8.89) 10(1.27,-11.43) 21(-1.27,11.43) 22(-1.27,8.89) 23(-1.27,6.35) 24(-1.27,3.81) 25(-1.27,1.27) 26(-1.27,-1.27) 27(-1.27,-3.81) 28(-1.27,-6.35) 29(-1.27,-8.89) 30(-1.27,-11.43)
  silkscreen extent -7.62,-12.95 7.62,12.95, body extent -2.48,-12.95 2.48,12.95, height 8.51
BoosterPack_40pin_J2J4 [mm] "Receptacle, 2.54mm, 10x2, TH"
  round 1.55 hole 1.02: 11(-1.27,-11.43) 12(-1.27,-8.89) 13(-1.27,-6.35) 14(-1.27,-3.81) 15(-1.27,-1.27) 16(-1.27,1.27) 17(-1.27,3.81) 18(-1.27,6.35) 19(-1.27,8.89) 20(-1.27,11.43) 31(1.27,-11.43) 32(1.27,-8.89) 33(1.27,-6.35) 34(1.27,-3.81) 35(1.27,-1.27) 36(1.27,1.27) 37(1.27,3.81) 38(1.27,6.35) 39(1.27,8.89) 40(1.27,11.43)
  silkscreen extent -7.62,-12.95 2.48,12.95, body extent -2.48,-12.95 2.48,12.95, height 8.51
BoosterPack_40pin_J5J7 [mm] "Receptacle, 2.54mm, 10x2, TH"
  round 1.55 hole 1.02: 41(1.27,11.43) 42(1.27,8.89) 43(1.27,6.35) 44(1.27,3.81) 45(1.27,1.27) 46(1.27,-1.27) 47(1.27,-3.81) 48(1.27,-6.35) 49(1.27,-8.89) 50(1.27,-11.43) 61(-1.27,11.43) 62(-1.27,8.89) 63(-1.27,6.35) 64(-1.27,3.81) 65(-1.27,1.27) 66(-1.27,-1.27) 67(-1.27,-3.81) 68(-1.27,-6.35) 69(-1.27,-8.89) 70(-1.27,-11.43)
  silkscreen extent -2.48,-12.95 7.62,12.95, body extent -2.48,-12.95 2.48,12.95, height 8.51
BoosterPack_40pin_J6J8 [mm] "Receptacle, 2.54mm, 10x2, TH"
  round 1.55 hole 1.02: 51(-1.27,-11.43) 52(-1.27,-8.89) 53(-1.27,-6.35) 54(-1.27,-3.81) 55(-1.27,-1.27) 56(-1.27,1.27) 57(-1.27,3.81) 58(-1.27,6.35) 59(-1.27,8.89) 60(-1.27,11.43) 71(1.27,-11.43) 72(1.27,-8.89) 73(1.27,-6.35) 74(1.27,-3.81) 75(1.27,-1.27) 76(1.27,1.27) 77(1.27,3.81) 78(1.27,6.35) 79(1.27,8.89) 80(1.27,11.43)
  silkscreen extent -7.62,-12.95 2.48,12.95, body extent -2.48,-12.95 2.48,12.95, height 8.51
BRAKE_WAY_HOLES1X3 [mil]
  round 27 hole 32 unplated mask+5.5: ""(-50,49.37) ""(0,49.37) ""(50,49.37)
CE_Mark_5mm [mil] "Minimum text height for CE Mark"
  silkscreen extent -138,-98 138,98
D0008A-MFG [mm]
  rrect17% 1.55x0.6 smd paste+0 mask+0: 1(-2.7,1.905) 2(-2.7,0.635) 3(-2.7,-0.635) 4(-2.7,-1.905) 5(2.7,-1.905) 6(2.7,-0.635) 7(2.7,0.635) 8(2.7,1.905)
  silkscreen extent -4.17,-2.5 1.5,2.5, body extent -3,-2.45 3,2.45, height 1.75
D0008B_HV [mm] "SOIC, 8-Leads, Body 4.9x3.9mm, Pitch 1.27mm, HV / Isolation option"
  rrect17% 1.4x0.6 smd: 1(-2.75,1.905) 2(-2.75,0.635) 3(-2.75,-0.635) 4(-2.75,-1.905) 5(2.75,-1.905) 6(2.75,-0.635) 7(2.75,0.635) 8(2.75,1.905)
  silkscreen extent -3.3,-2.5 0.9,2.5, body extent -3,-2.45 3,2.45, height 1.63
D0008B_N [mil] "SOIC, 8-Leads, Body 4.9x3.9mm, Pitch 1.27mm, IPC Medium Density"
  oval 55x23.62 smd: 1(-108.5,75) 2(-108.5,25) 3(-108.5,-25) 4(-108.5,-75) 5(108.5,-75) 6(108.5,-25) 7(108.5,25) 8(108.5,75)
  silkscreen extent -130,-98 35,98, body extent -118,-96 118,96, height 64
D0016A_N [mm] "SOIC, 16-Leads, Body 9.9x3.9mm, Pitch 1.27mm, IPC Medium Density"
  oval 1.45x0.6 smd: 1(-2.725,4.445) 2(-2.725,3.175) 3(-2.725,1.905) 4(-2.725,0.635) 5(-2.725,-0.635) 6(-2.725,-1.905) 7(-2.725,-3.175) 8(-2.725,-4.445) 9(2.725,-4.445) 10(2.725,-3.175) 11(2.725,-1.905) 12(2.725,-0.635) 13(2.725,0.635) 14(2.725,1.905) 15(2.725,3.175) 16(2.725,4.445)
  silkscreen extent -3.3,-5 0.9,5, body extent -3,-4.95 3,4.95, height 1.6
DBV0005A_N [mm] "SOT23, 5-Leads, Body 2.9x1.6mm, Pitch 0.95mm, Lead Span 2.8mm, IPC Medium Density"
  rrect17% 1x0.6 smd: 1(-1.375,0.95) 2(-1.375,0) 3(-1.375,-0.95) 4(1.375,-0.95) 5(1.375,0.95)
  silkscreen extent -0.25,-1.55 0.25,1.55, body extent -1.42,-1.46 1.42,1.46, height 1.09
DBV0006A_N [mm] "SOT23, 6-Leads, Body 2.9x1.6mm, Pitch 0.95mm, Lead Span 2.8mm, IPC Medium Density"
  rrect17% 1x0.6 smd: 1(-1.375,0.95) 2(-1.375,0) 3(-1.375,-0.95) 4(1.375,-0.95) 5(1.375,0) 6(1.375,0.95)
  silkscreen extent -1.68,-1.55 0.5,1.55, body extent -1.42,-1.46 1.42,1.46, height 1.12
DBZ0003A_N [mm] "SOT23, 3-Leads, Body 2.9x1.3mm, Pitch 0.95mm, Lead Span 2.4mm, IPC Medium Density"
  rrect17% 1x0.6 smd: 1(-1.2,0.95) 2(-1.2,-0.95) 3(1.2,0)
  silkscreen extent 0.2,-1.5 0.7,1.5, body extent -1.26,-1.46 1.26,1.46, height 0.98
DCK0005A_N [mm] "SOT353, 5-Leads, Body 2x1.3mm, Pitch 0.65mm, Lead Span 2.1mm, IPC Medium Density"
  rrect25% 0.85x0.4 smd: 1(-1.125,0.65) 2(-1.125,0) 3(-1.125,-0.65) 4(1.125,-0.65) 5(1.125,0.65)
  silkscreen extent -1.48,-1.02 0.55,1.1, body extent -1.14,-1 1.14,1, height 0.95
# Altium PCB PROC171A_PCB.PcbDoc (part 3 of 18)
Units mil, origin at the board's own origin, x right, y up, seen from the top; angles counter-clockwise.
Board outline 7700 x 2300 mil, 6 copper layers (Top Layer, GND 1, SIG 1, SIG 2, GND 2, Bottom Layer), stack 61.062 mil thick; 945 components, 692 nets, 11945 pads, 1734 vias.

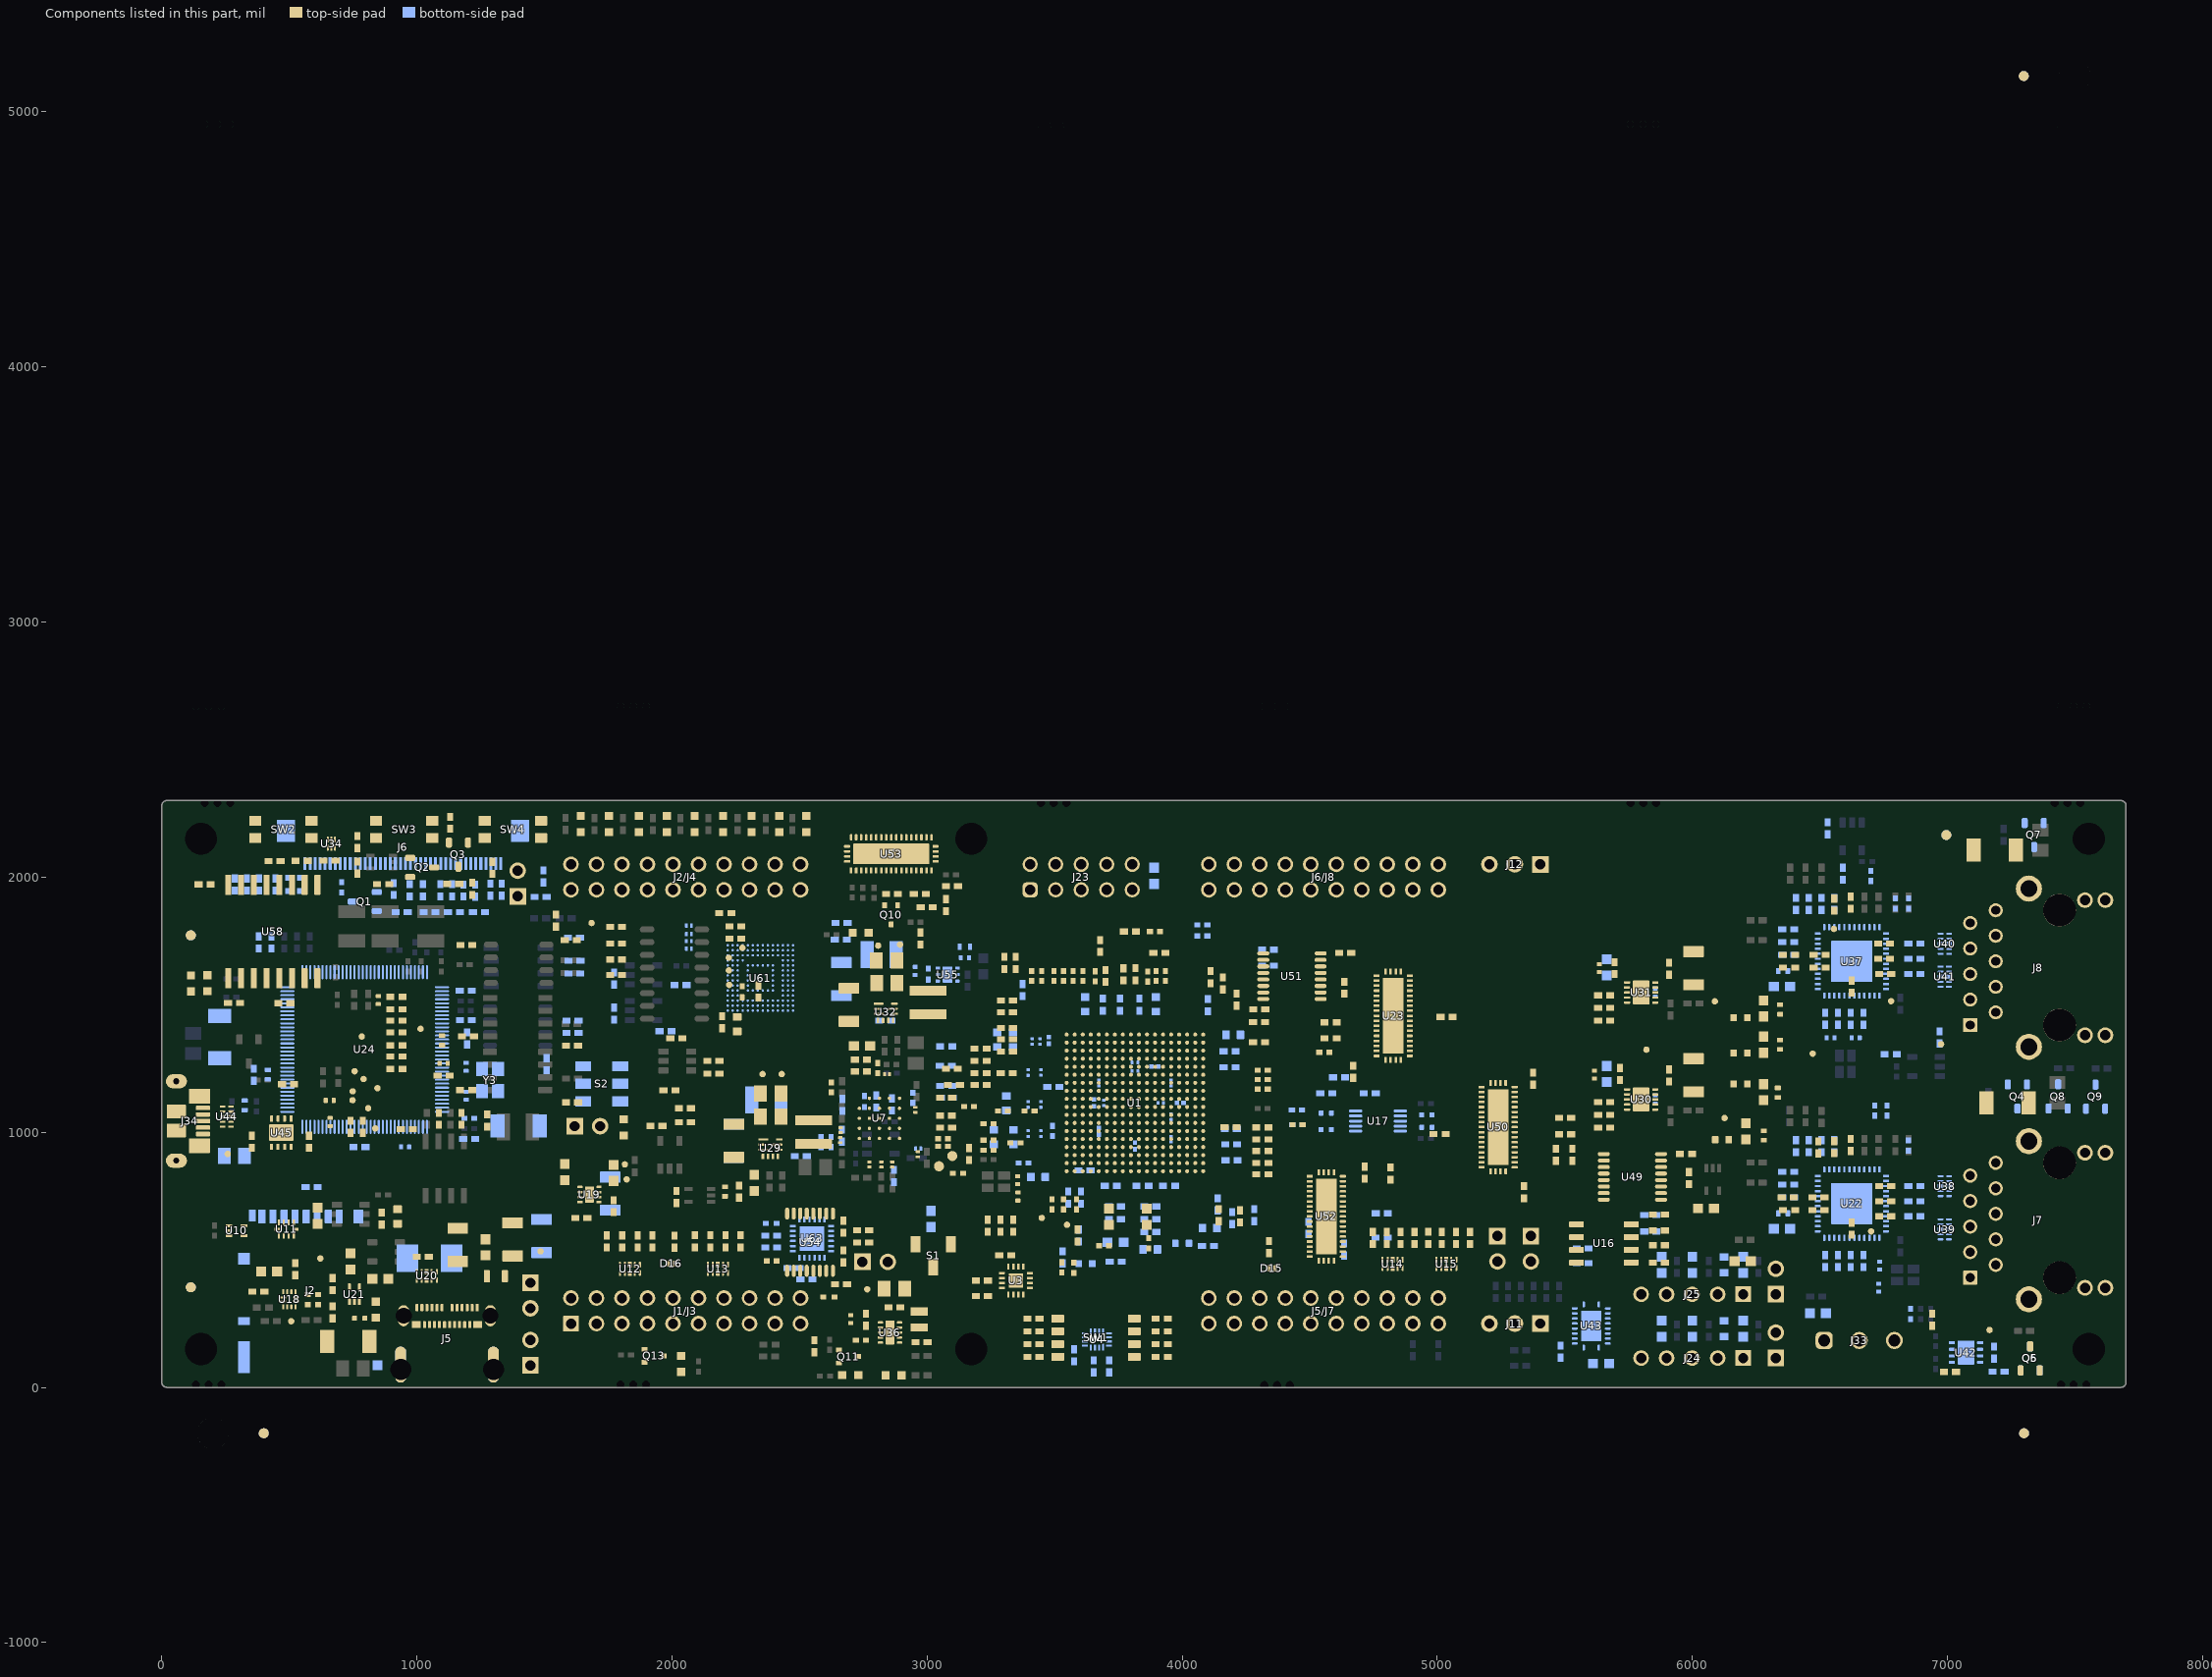
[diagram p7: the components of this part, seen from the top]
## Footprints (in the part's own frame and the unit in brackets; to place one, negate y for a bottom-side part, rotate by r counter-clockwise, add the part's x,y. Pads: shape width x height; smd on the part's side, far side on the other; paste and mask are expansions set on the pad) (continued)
DGS0010A_N [mm] "TSSOP, 10-Leads, Body 3x3mm, Pitch 0.5mm, IPC Medium Density"
  oval 1.35x0.3 smd: 1(-2.225,1) 2(-2.225,0.5) 3(-2.225,0) 4(-2.225,-0.5) 5(-2.225,-1) 6(2.225,-1) 7(2.225,-0.5) 8(2.225,0) 9(2.225,0.5) 10(2.225,1)
  silkscreen extent -2.75,-1.55 0.9,1.55, body extent -2.45,-1.5 2.45,1.5, height 0.96
DPY0002A [mm] "X1SON-2"
  rrect57% 0.35x0.6 smd paste-0.5 mask-0.05: 1(-0.325,0) 2(0.325,0)
  rrect50% 0.3x0.5 on Top Paste: 1S(-0.35,0) 2S(0.35,0)
  silkscreen extent -0.85,-0.02 -0.8,0.02, body extent -0.5,-0.3 0.5,0.3, height 0.45
DQA0010A#1 [mm] "SON, 10-Leads, Body 1x2.5mm, Pitch 0.5mm, TI Recommended"
  rrect50% 0.565x0.2 smd: 1(-0.417,1) 2(-0.417,0.5) 4(-0.417,-0.5) 5(-0.417,-1) 6(0.417,-1) 7(0.417,-0.5) 9(0.417,0.5) 10(0.417,1)
  rrect28% 0.565x0.36 on Top Paste: 3(-0.417,0) 8(0.417,0)
  rrect25% 0.565x0.4 smd paste-0.2: 3(-0.417,0) 8(0.417,0)
  silkscreen extent -0.67,-1.45 0.55,1.45, body extent -0.55,-1.3 0.55,1.3, height 0.56
DQA0010A#2 [mm] "SON, 10-Leads, Body 1x2.5mm, Pitch 0.5mm, TI Recommended"
  rrect50% 0.565x0.2 smd: 1(-0.417,1) 2(-0.417,0.5) 4(-0.417,-0.5) 5(-0.417,-1) 6(0.417,-1) 7(0.417,-0.5) 9(0.417,0.5) 10(0.417,1)
  rrect28% 0.565x0.36 on Bottom Paste: 3(-0.417,0) 8(0.417,0)
  rrect25% 0.565x0.4 smd paste-0.2: 3(-0.417,0) 8(0.417,0)
  silkscreen extent -0.67,-1.45 0.55,1.45, body extent -0.55,-1.3 0.55,1.3, height 0.56
DQC0010A [mm] "SON, 10-Leads, Body 2x3mm, Pitch 0.5mm, Thermal Pad 2.4x0.84mm"
  rrect40% 0.5x0.25 smd: 1(-0.95,1) 2(-0.95,0.5) 3(-0.95,0) 4(-0.95,-0.5) 5(-0.95,-1) 6(0.95,-1) 7(0.95,-0.5) 8(0.95,0) 9(0.95,0.5) 10(0.95,1)
  rrect12% 0.8x1.08 on Top Paste: 11(0,-0.64) 11(0,0.64)
  rrect12% 0.84x2.4 smd paste-0.42: 11(0,0)
  silkscreen extent -1.18,-1.68 1.17,1.68, body extent -1,-1.5 1,1.5, height 0.77
DRB0008B [mm] "SON, 8-Leads, Body 3x3mm, Pitch 0.65mm, Thermal Pad 2.4x1.65mm, TI Recommended"
  rrect33% 0.6x0.3 smd: 1(-1.4,0.975) 2(-1.4,0.325) 3(-1.4,-0.325) 4(-1.4,-0.975) 5(1.4,-0.975) 6(1.4,-0.325) 7(1.4,0.325) 8(1.4,0.975)
  rrect50% 1.47x1.06 on Top Paste: 9(0,0.63) 9(0,-0.63)
  rrect6% 1.65x2.4 smd paste-1.2: 9(0,0)
  silkscreen extent -1.73,-1.73 1.73,1.73, body extent -1.5,-1.5 1.5,1.5, height 0.96
DRB0008J [mm] "VSON-8"
  rrect33% 0.6x0.31 smd: 1(-1.4,0.975) 2(-1.4,0.325) 3(-1.4,-0.325) 4(-1.4,-0.975) 5(1.4,-0.975) 6(1.4,-0.325) 7(1.4,0.325) 8(1.4,0.975)
  rrect6% 1.65x2.4 smd paste-1.2: 9(0,0)
  silkscreen extent -1.73,-1.73 1.73,1.73, body extent -1.55,-1.55 1.55,1.55, height 1.01
DRC0010J [mm] "VSON-10"
  rrect42% 0.6x0.24 smd: 1(-1.4,1) 2(-1.4,0.5) 3(-1.4,0) 4(-1.4,-0.5) 5(-1.4,-1) 6(1.4,-1) 7(1.4,-0.5) 8(1.4,0) 9(1.4,0.5) 10(1.4,1)
  rrect12% 1.65x2.4 smd paste-1 mask-2: 11(0,0)
  Top Layer region: -0.375,-1.65 -0.375,-1.2 -0.775,-1.2 -0.794,-1.196 -0.81,-1.185 -0.821,-1.169 -0.825,-1.15 -0.825,-1.15 -0.825,1.15 -0.821,1.169 -0.81,1.185 -0.794,1.196 -0.775,1.2 -0.775,1.2 -0.375,1.2 -0.375,1.65 -0.371,1.669 -0.36,1.685 -0.344,1.696 -0.325,1.7 -0.325,1.7 -0.325,1.7 -0.175,1.7 -0.175,1.7 -0.156,1.696 -0.14,1.685 -0.129,1.669 -0.125,1.65 -0.125,1.65 -0.125,1.2 0.125,1.2 0.125,1.65 0.129,1.669 0.14,1.685 0.156,1.696 0.175,1.7 0.175,1.7 0.175,1.7 0.325,1.7 0.325,1.7 0.344,1.696 0.36,1.685 0.371,1.669 0.375,1.65 0.375,1.65 0.375,1.2 0.775,1.2 0.794,1.196 0.81,1.185 0.821,1.169 0.825,1.15 0.825,1.15 0.825,-1.15 0.821,-1.169 0.81,-1.185 0.794,-1.196 0.775,-1.2 0.775,-1.2 0.375,-1.2 0.375,-1.65 0.371,-1.669 0.36,-1.685 0.344,-1.696 0.325,-1.7 0.325,-1.7 0.175,-1.7 0.156,-1.696 0.14,-1.685 0.129,-1.669 0.125,-1.65 0.125,-1.65 0.125,-1.2 -0.125,-1.2 -0.125,-1.65 -0.129,-1.669 -0.14,-1.685 -0.156,-1.696 -0.175,-1.7 -0.175,-1.7 -0.325,-1.7 -0.344,-1.696 -0.36,-1.685 -0.371,-1.669 -0.375,-1.65
  body extent -1.5,-1.5 1.5,1.5, height 1
DRL0005A [mm] "SOTFL, 5-Flat Leads, Body 1.2x1.6x0.6mm, Pitch 0.5mm, TI recommended"
  rrect33% 0.67x0.3 smd: 1(-0.74,0.5) 2(-0.74,0) 3(-0.74,-0.5) 4(0.74,-0.5) 5(0.74,0.5)
  silkscreen extent -0.9,-0.95 0.5,0.95, body extent -0.85,-0.85 0.85,0.85, height 0.62
DRV0006A [mm] "SON, 6-Leads, Body 2x2mm, Pitch 0.65mm, Thermal Pad 1.6x1mm, TI Recommended"
  rrect33% 0.45x0.3 smd: 1(-0.975,0.65) 2(-0.975,0) 3(-0.975,-0.65) 4(0.975,-0.65) 5(0.975,0) 6(0.975,0.65)
  rrect14% 1x0.7 on Bottom Paste: 7(0,-0.45) 7(0,0.45)
  rrect10% 1x1.6 smd paste-0.5: 7(0,0)
  silkscreen extent -1.05,-1.2 1.05,1.2, body extent -1.05,-1.05 1.05,1.05, height 0.81
DSF0006A [mm] "TI recommended land pattern"
  rrect59% 0.6x0.17 smd mask+0.045: 1(-0.4,0.35) 2(-0.4,0) 3(-0.4,-0.35) 4(0.4,-0.35) 5(0.4,0) 6(0.4,0.35)
  silkscreen extent -0.6,-0.63 0.6,0.63, body extent -0.5,-0.5 0.5,0.5, height 0.48
DSG0008B [mm] "SON, 8-Leads, Body 2x2mm, Pitch 0.5mm, Thermal Pad 1.6x0.9mm, TI Recommended"
  rrect14% 0.9x0.7 on Top Paste: 0(0,-0.45) 0(0,0.45)
  rrect40% 0.5x0.25 smd: 1(-0.95,0.75) 2(-0.95,0.25) 3(-0.95,-0.25) 4(-0.95,-0.75) 5(0.95,-0.75) 6(0.95,-0.25) 7(0.95,0.25) 8(0.95,0.75)
  rrect11% 0.9x1.6 smd paste-0.45: 9(0,0)
  silkscreen extent -1.07,-1.15 1.07,1.15, body extent -1,-1 1,1, height 0.77
DW0016A-MFG [mm]
  rrect17% 2x0.6 smd paste+0 mask+0: 1(-4.65,4.445) 2(-4.65,3.175) 3(-4.65,1.905) 4(-4.65,0.635) 5(-4.65,-0.635) 6(-4.65,-1.905) 7(-4.65,-3.175) 8(-4.65,-4.445) 9(4.65,-4.445) 10(4.65,-3.175) 11(4.65,-1.905) 12(4.65,-0.635) 13(4.65,0.635) 14(4.65,1.905) 15(4.65,3.175) 16(4.65,4.445)
  silkscreen extent -6.32,-5.25 3.15,5.25, body extent -5.16,-5.15 5.17,5.15, height 2.6
FCC_disclaimer [mil]
Fiducial10-20 [mm]
  round 1 smd mask+0.5: 1(0,0)
  Top Layer keep-out circle w1.178: c0,0 r0.5
FP-2012670005_CONN_USB_9MM39_8MM21-MFG [mm]
  rrect100% 1.1x2.1 hole 1.6 slot 0.6 at 0 deg paste-2539.97 mask+0: 1(-4.32,3.205) 2(4.32,3.205)
  rrect100% 0.6x2.1 hole 2.1 slot 0.6 at 0 deg paste-2539.97 mask+0: 3(-4.62,-2.155) 4(4.62,-2.155)
  rrect100% 1.1x3.6 smd paste-1000 mask+0: 3(-4.62,-1.655) 4(4.62,-1.655)
  rrect100% 1.1x3.6 smd far side paste-1000 mask+0: 3(-4.62,-1.655) 4(4.62,-1.655)
  rrect33% 0.3x0.7 smd paste+0 mask+0: A1(-3,4.015) A2(-2.5,4.015) A3(-2,4.015) A4(-1.5,4.015) A5(-1,4.015) A6(-0.5,4.015) A7(0.5,4.015) A8(1,4.015) A9(1.5,4.015) A10(2,4.015) A11(2.5,4.015) A12(3,4.015) B2(2.25,2.315) B3(1.75,2.315) B4(1.25,2.315) B5(0.75,2.315) B6(0.25,2.315) B7(-0.25,2.315) B8(-0.75,2.315) B9(-1.25,2.315) B10(-1.75,2.315) B11(-2.25,2.315)
  rrect14% 0.9x0.7 smd paste+0 mask+0: B1(3.05,2.315) B12(-3.05,2.315)
  silkscreen extent -4.77,0.52 4.77,5.03, body extent -5.27,-4.33 5.27,4.46, height 0.25
FP-74405020100_SMT_IND_2MM0_1MM6-MFG [mm]
  rect 0.8x1.7 smd paste+0 mask+0: 1(-0.8,0) 2(0.8,0)
  body extent -1.3,-1 1.3,1, height 0.25
FP-416131160804_SMT_SW-MFG [mm]
  rrect13% 0.76x1.27 smd paste+0 mask+0: 1(-1.905,-3.81) 2(-0.635,-3.81) 3(0.635,-3.81) 4(1.905,-3.81) 5(1.905,3.81) 6(0.635,3.81) 7(-0.635,3.81) 8(-1.905,3.81)
  silkscreen extent -3.27,-4.12 3.27,2.93, body extent -3.37,-4.54 3.37,4.54, height 0.25
FP-434351045816_SMT_SW_4MM7_4MM5-MFG [mm]
  rrect10% 1.2x1 smd paste+0 mask+0: 1(2.8,0.85) 2(2.8,-0.85) 3(-2.8,0.85) 4(-2.8,-0.85)
  silkscreen extent -2.4,0.73 4.07,1.85, body extent -3.5,-2.95 3.5,1.95, height 0.25
FP-BLM18EG121SN1D_0603-MFG [mm]
  rrect15% 0.65x0.7 smd paste+0 mask+0: 1(-0.675,0) 2(0.675,0)
  silkscreen extent -0.87,-0.8 0.87,0.8, body extent -0.8,-0.4 0.8,0.4, height 0.95
FP-BLM21PG300SN1D_0805-MFG [mm]
  rrect17% 0.6x1.2 smd paste-1000 mask-1000: 1(-0.9,0) 2(0.9,0)
  silkscreen extent -0.23,-0.72 0.23,0.72, body extent -1.3,-0.82 1.3,0.82, height 0.25
FP-CL10A335KP8NNNC_0603-MFG [mm]
  rrect13% 0.76x0.85 smd paste+0 mask+0: 1(-0.72,0) 2(0.72,0)
  silkscreen extent -0.85,-0.8 0.85,0.8, body extent -0.8,-0.4 0.8,0.4, height 0.9
"FP-CRCW020122R0FNED_0201 (0603 metric)-MFG" [mm]
  rrect36% 0.28x0.43 smd paste+0 mask+0: 1(-0.255,0) 2(0.255,0)
  body extent -0.5,-0.32 0.5,0.32, height 0.25
FP-ERA-2APB621X_0402-MFG [mm]
  rrect21% 0.475x0.5 smd paste+0 mask+0: 1(-0.512,0) 2(0.512,0)
  silkscreen extent -0.5,-0.63 0.5,0.63, body extent -0.85,-0.4 0.85,0.4, height 0.25
FP-ERJ-2GEJ152X_0402-MFG [mm]
  rrect21% 0.475x0.5 smd paste+0 mask+0: 1(-0.512,0) 2(0.513,0)
  silkscreen extent -0.53,-0.63 0.53,0.63, body extent -0.5,-0.25 0.5,0.25, height 0.4
FP-FH12A-40S-0.5SH(55)_FFC40-MFG [mm]
  rrect33% 0.3x1.3 smd paste-1000 mask+0: 1(9.75,-3.725) 2(9.25,-3.725) 3(8.75,-3.725) 4(8.25,-3.725) 5(7.75,-3.725) 6(7.25,-3.725) 7(6.75,-3.725) 8(6.25,-3.725) 9(5.75,-3.725) 10(5.25,-3.725) 11(4.75,-3.725) 12(4.25,-3.725) 13(3.75,-3.725) 14(3.25,-3.725) 15(2.75,-3.725) 16(2.25,-3.725) 17(1.75,-3.725) 18(1.25,-3.725) 19(0.75,-3.725) 20(0.25,-3.725) 21(-0.25,-3.725) 22(-0.75,-3.725) 23(-1.25,-3.725) 24(-1.75,-3.725) 25(-2.25,-3.725) 26(-2.75,-3.725) 27(-3.25,-3.725) 28(-3.75,-3.725) 29(-4.25,-3.725) 30(-4.75,-3.725) 31(-5.25,-3.725) 32(-5.75,-3.725) 33(-6.25,-3.725) 34(-6.75,-3.725) 35(-7.25,-3.725) 36(-7.75,-3.725) 37(-8.25,-3.725) 38(-8.75,-3.725) 39(-9.25,-3.725) 40(-9.75,-3.725)
  rrect6% 1.8x2.2 smd paste+0 mask+0: 41(-11.65,-0.475) 42(11.65,-0.475)
  silkscreen extent -12.35,-4.32 12.35,3.2, body extent -12.25,-3.82 12.25,2.95, height 3.5
FP-GCM155R72A272KA37D_0402-MFG [mm]
  rrect25% 0.4x0.5 smd paste+0 mask+0: 1(-0.4,0) 2(0.4,0)
  silkscreen extent -0.53,-0.65 0.53,0.65, body extent -0.5,-0.25 0.5,0.25, height 0.55
FP-GJM1555C1H8R0DB01D_0402-MFG [mm]
  rrect25% 0.4x0.5 smd paste+0 mask+0: 1(-0.4,0) 2(0.4,0)
  silkscreen extent -0.53,-0.63 0.53,0.63, body extent -0.5,-0.25 0.5,0.25, height 0.55
FP-GJM1555C1H120JB01D_0402-MFG [mm]
  rrect25% 0.4x0.5 smd paste+0 mask+0: 1(-0.4,0) 2(0.4,0)
  silkscreen extent -0.53,-0.63 0.53,0.63, body extent -0.7,-0.38 0.7,0.38, height 0.25
FP-GJM1555C1H150FB01D_0402-MFG [mm]
  rrect25% 0.4x0.5 smd paste+0 mask+0: 1(-0.4,0) 2(0.4,0)
  silkscreen extent -0.53,-0.63 0.53,0.63, body extent -0.7,-0.38 0.7,0.38, height 0.25
FP-GQM1875C2E101JB12D_0603-MFG [mm]
  rrect13% 0.75x0.9 smd paste+0 mask+0: 1(-0.775,0) 2(0.775,0)
  silkscreen extent -1,-0.67 1,0.67, body extent -0.8,-0.4 0.8,0.4, height 0.8
FP-GRM32EC72A106KE05L_1210-MFG [mm]
  rrect9% 1.1x2.05 smd paste+0 mask+0: 1(-1.65,0) 2(1.65,0)
  silkscreen extent -0.72,-1.35 0.72,1.35, body extent -2.3,-1.45 2.3,1.45, height 0.25
FP-GRM033C80J105ME05D_0201-MFG [mm]
  rrect33% 0.3x0.35 smd paste+0 mask+0: 1(-0.282,0) 2(0.282,0)
  silkscreen extent -0.35,-0.58 0.35,0.58, body extent -0.3,-0.15 0.3,0.15, height 0.39
FP-GRM155C71A105KE11D_0402-MFG [mm]
  rrect25% 0.4x0.5 smd paste+0 mask+0: 1(-0.4,0) 2(0.4,0)
  silkscreen extent -0.55,-0.65 0.55,0.65, body extent -0.5,-0.25 0.5,0.25, height 0.6
FP-GRM155R71H104KE14D_0402-MFG [mm]
  rrect25% 0.4x0.5 smd paste+0 mask+0: 1(-0.4,0) 2(0.4,0)
  silkscreen extent -0.5,-0.65 0.5,0.65, body extent -0.5,-0.25 0.5,0.25, height 0.55
FP-GRM1555C1E103JE01D_0402-MFG [mm]
  rrect22% 0.45x0.6 smd paste+0 mask+0: 1(-0.475,0) 2(0.475,0)
  silkscreen extent -0.58,-0.73 0.58,0.72, body extent -0.8,-0.43 0.8,0.43, height 0.25
FP-IS25LX256-JHLE_TFBGA24-IPC_C [mm]
  round 0.34 smd paste+0 mask+0: A2(-1,2) A3(0,2) A4(1,2) A5(2,2) B1(-2,1) B2(-1,1) B3(0,1) B4(1,1) B5(2,1) C1(-2,0) C2(-1,0) C3(0,0) C4(1,0) C5(2,0) D1(-2,-1) D2(-1,-1) D3(0,-1) D4(1,-1) D5(2,-1) E1(-2,-2) E2(-1,-2) E3(0,-2) E4(1,-2) E5(2,-2)
  silkscreen extent -3.62,-4 3,4, body extent -3,-4 3,4, height 1.2
FP-KGM05CR51A106MH_0402-MFG [mm]
  rrect20% 0.6x0.5 smd paste+0 mask+0: 1(-0.55,0) 2(0.55,0)
  silkscreen extent -0.6,-0.63 0.6,0.63, body extent -0.5,-0.25 0.5,0.25, height 0.7
FP-LPJG16314A4NL_CONN_RJ45-MFG [mm]
  rrect7% 1.4x1.4 hole 0.9 paste-2539.97 mask+0: 1(-5.715,9.015)
  round 1.4 hole 0.9 paste-2539.97 mask+0: 2(-4.445,6.475) 3(-3.175,9.015) 4(-1.905,6.475) 5(-0.635,9.015) 6(0.635,6.475) 7(1.905,9.015) 8(3.175,6.475) 9(4.445,9.015) 10(5.715,6.475)
  round 1.57 hole 1.02 paste-2539.97 mask+0: 11(6.725,-2.415) 12(6.725,-4.445) 13(-6.725,-2.415) 14(-6.725,-4.445)
  round 2.6 hole 1.7 paste-2539.97 mask+0: 15(-7.875,3.175) 16(7.875,3.175)
  round 3.25 hole 3.25 unplated paste-2539.97 mask+0: ""(-5.715,0.125) ""(5.715,0.125)
  silkscreen extent -9.65,-10.75 8.1,10.75, body extent -9.28,-10.85 9.28,10.85, height 0.25
FP-MTFC8GAMALBH-AAT_TFBGA153-MFG [mm]
  round 0.24 smd paste+0 mask+0: A1(-3.25,3.25) A2(-2.75,3.25) A3(-2.25,3.25) A4(-1.75,3.25) A5(-1.25,3.25) A6(-0.75,3.25) A7(-0.25,3.25) A8(0.25,3.25) A9(0.75,3.25) A10(1.25,3.25) A11(1.75,3.25) A12(2.25,3.25) A13(2.75,3.25) A14(3.25,3.25) B1(-3.25,2.75) B2(-2.75,2.75) B3(-2.25,2.75) B4(-1.75,2.75) B5(-1.25,2.75) B6(-0.75,2.75) B7(-0.25,2.75) B8(0.25,2.75) B9(0.75,2.75) B10(1.25,2.75) B11(1.75,2.75) B12(2.25,2.75) B13(2.75,2.75) B14(3.25,2.75) C1(-3.25,2.25) C2(-2.75,2.25) C3(-2.25,2.25) C4(-1.75,2.25) C5(-1.25,2.25) C6(-0.75,2.25) C7(-0.25,2.25) C8(0.25,2.25) C9(0.75,2.25) C10(1.25,2.25) C11(1.75,2.25) C12(2.25,2.25) C13(2.75,2.25) C14(3.25,2.25) D1(-3.25,1.75) D2(-2.75,1.75) D3(-2.25,1.75) D4(-1.75,1.75) D12(2.25,1.75) D13(2.75,1.75) D14(3.25,1.75) E1(-3.25,1.25) E2(-2.75,1.25) E3(-2.25,1.25) E5(-1.25,1.25) E6(-0.75,1.25) E7(-0.25,1.25) E8(0.25,1.25) E9(0.75,1.25) E10(1.25,1.25) E12(2.25,1.25) E13(2.75,1.25) E14(3.25,1.25) F1(-3.25,0.75) F2(-2.75,0.75) F3(-2.25,0.75) F5(-1.25,0.75) F10(1.25,0.75) F12(2.25,0.75) F13(2.75,0.75) F14(3.25,0.75) G1(-3.25,0.25) G2(-2.75,0.25) G3(-2.25,0.25) G5(-1.25,0.25) G10(1.25,0.25) G12(2.25,0.25) G13(2.75,0.25) G14(3.25,0.25) H1(-3.25,-0.25) H2(-2.75,-0.25) H3(-2.25,-0.25) H5(-1.25,-0.25) H10(1.25,-0.25) H12(2.25,-0.25) H13(2.75,-0.25) H14(3.25,-0.25) J1(-3.25,-0.75) J2(-2.75,-0.75) J3(-2.25,-0.75) J5(-1.25,-0.75) J10(1.25,-0.75) J12(2.25,-0.75) J13(2.75,-0.75) J14(3.25,-0.75) K1(-3.25,-1.25) K2(-2.75,-1.25) K3(-2.25,-1.25) K5(-1.25,-1.25) K6(-0.75,-1.25) K7(-0.25,-1.25) K8(0.25,-1.25) K9(0.75,-1.25) K10(1.25,-1.25) K12(2.25,-1.25) K13(2.75,-1.25) K14(3.25,-1.25) L1(-3.25,-1.75) L2(-2.75,-1.75) L3(-2.25,-1.75) L12(2.25,-1.75) L13(2.75,-1.75) L14(3.25,-1.75) M1(-3.25,-2.25) M2(-2.75,-2.25) M3(-2.25,-2.25) M4(-1.75,-2.25) M5(-1.25,-2.25) M6(-0.75,-2.25) M7(-0.25,-2.25) M8(0.25,-2.25) M9(0.75,-2.25) M10(1.25,-2.25) M11(1.75,-2.25) M12(2.25,-2.25) M13(2.75,-2.25) M14(3.25,-2.25) N1(-3.25,-2.75) N2(-2.75,-2.75) N3(-2.25,-2.75) N4(-1.75,-2.75) N5(-1.25,-2.75) N6(-0.75,-2.75) N7(-0.25,-2.75) N8(0.25,-2.75) N9(0.75,-2.75) N10(1.25,-2.75) N11(1.75,-2.75) N12(2.25,-2.75) N13(2.75,-2.75) N14(3.25,-2.75) P1(-3.25,-3.25) P2(-2.75,-3.25) P3(-2.25,-3.25) P4(-1.75,-3.25) P5(-1.25,-3.25) P6(-0.75,-3.25) P7(-0.25,-3.25) P8(0.25,-3.25) P9(0.75,-3.25) P10(1.25,-3.25) P11(1.75,-3.25) P12(2.25,-3.25) P13(2.75,-3.25) P14(3.25,-3.25)
  silkscreen extent -6.42,-6.55 5.8,6.55, body extent -5.75,-6.5 5.75,6.5, height 1.1
Hirose_DM3BT-DSF-PEJS [mm] "Conncetor, micro SD, 8+2 Pos, R/A, SMT"
  rrect14% 0.7x1.4 smd: 1(-3.2,7.8) 2(-2.1,7.8) 3(-1,7.8) 4(0.1,7.8) 5(1.2,7.8) 6(2.3,7.8) 7(3.4,7.8) 8(4.5,7.8)
  rrect8% 1.2x0.8 smd: 9(6.3,-2.6)
  rrect14% 0.7x1.2 smd: 10(5.45,7.9)
  rrect10% 1x1.4 smd: S1(-5.1,7.8)
  rrect8% 1.2x1.2 smd: S2(6.3,3.6)
  rrect8% 1.2x3.2 smd: S3(6.3,-6.2)
  rrect8% 1x1 smd: S4(-7,-7)
  Top Layer region: -7.75,-8.15 -5.75,-8.15 -5.75,-7.65 -6.1,-7.65 -6.25,-7.5 -6.25,-6.25 -7.75,-6.25
  body extent -6.93,-7.98 6.93,7.98, height 2.38
IEC_HotSurface_Small [mil]
  silkscreen extent -107,-93 107,92
Label_650x200 [mil] "Thermal Transfer Label"
  round 1 on Mech13: 0(0,0)
  silkscreen extent -325,-100 325,100, body extent -325,-100 325,100, height 1
MHNP_M3_PANHEAD_PHILLIPS [mil]
  round 121 hole 126 unplated mask+5.5: ""(0,0)
  Keep-Out Layer circle w1: c0,0 r126
MISTRAL_LOGO_25 [mil]
  silkscreen extent 0,0 297,162
Molex_1051640001 [mm] "Receptacle, USB 2.0, Micro B, 5 Pos, 0.65mm Pitch, R/A, SMT"
  rrect22% 0.45x1.38 smd: 1(1.3,4.11) 2(0.65,4.11) 3(0,4.11) 4(-0.65,4.11) 5(-1.3,4.11)
  rrect7% 1.475x2.1 smd: 6(-2.462,3.75) 11(2.462,3.75)
  rrect100% 1.4x2.1 hole 0.6 slot 1.3 at 90 deg: 7(-3.95,1.45) 10(3.95,1.45)
  rrect7% 1.375x1.9 smd: 8(-0.937,1.45) 9(0.937,1.45)
  silkscreen extent 1.2,5.1 1.4,5.4, body extent -4.1,-0.7 4.1,4.47, height 2.45
NDK_NX3225GA [mm] "NDK"
  rect 1.2x1.4 smd: 1(-0.8,1.1) 2(-0.8,-1.1) 3(0.8,-1.1) 4(0.8,1.1)
  silkscreen extent -1.9,-0.1 1.4,2, body extent -1.3,-1.65 1.3,1.65, height 0.9
On-Shore_OSTTE030161 [mm] "Terminal Block, 3.5mm, 3x1, TH"
  rrect50% 1.7x1.7 hole 1.2: 1(-3.5,0)
  round 1.7 hole 1.2: 2(0,0) 3(3.5,0)
  silkscreen extent -5.25,-3.6 5.25,4.05, body extent -5.75,-3.6 5.75,3.4, height 8.4
PBC03SAAN [mm] "Sullins 100mil, 1x3, 230 mil above insulator"
  rect 1.65x1.65 hole 1.016: 1(-2.54,0)
  round 1.65 hole 1.016: 2(0,0) 3(2.54,0)
  silkscreen extent -3.81,-1.27 3.81,1.27, body extent -3.81,-1.27 3.81,1.27, height 8.38
PDT0128A [mm] "Thin QFP, 128-Leads, Body 14x14mm, Pitch 0.4mm"
  oval 1.4x0.2 smd: 1(-7.7,6.2) 2(-7.7,5.8) 3(-7.7,5.4) 4(-7.7,5) 5(-7.7,4.6) 6(-7.7,4.2) 7(-7.7,3.8) 8(-7.7,3.4) 9(-7.7,3) 10(-7.7,2.6) 11(-7.7,2.2) 12(-7.7,1.8) 13(-7.7,1.4) 14(-7.7,1) 15(-7.7,0.6) 16(-7.7,0.2) 17(-7.7,-0.2) 18(-7.7,-0.6) 19(-7.7,-1) 20(-7.7,-1.4) 21(-7.7,-1.8) 22(-7.7,-2.2) 23(-7.7,-2.6) 24(-7.7,-3) 25(-7.7,-3.4) 26(-7.7,-3.8) 27(-7.7,-4.2) 28(-7.7,-4.6) 29(-7.7,-5) 30(-7.7,-5.4) 31(-7.7,-5.8) 32(-7.7,-6.2) 65(7.7,-6.2) 66(7.7,-5.8) 67(7.7,-5.4) 68(7.7,-5) 69(7.7,-4.6) 70(7.7,-4.2) 71(7.7,-3.8) 72(7.7,-3.4) 73(7.7,-3) 74(7.7,-2.6) 75(7.7,-2.2) 76(7.7,-1.8) 77(7.7,-1.4) 78(7.7,-1) 79(7.7,-0.6) 80(7.7,-0.2) 81(7.7,0.2) 82(7.7,0.6) 83(7.7,1) 84(7.7,1.4) 85(7.7,1.8) 86(7.7,2.2) 87(7.7,2.6) 88(7.7,3) 89(7.7,3.4) 90(7.7,3.8) 91(7.7,4.2) 92(7.7,4.6) 93(7.7,5) 94(7.7,5.4) 95(7.7,5.8) 96(7.7,6.2)
  oval 0.2x1.4 smd: 33(-6.2,-7.7) 34(-5.8,-7.7) 35(-5.4,-7.7) 36(-5,-7.7) 37(-4.6,-7.7) 38(-4.2,-7.7) 39(-3.8,-7.7) 40(-3.4,-7.7) 41(-3,-7.7) 42(-2.6,-7.7) 43(-2.2,-7.7) 44(-1.8,-7.7) 45(-1.4,-7.7) 46(-1,-7.7) 47(-0.6,-7.7) 48(-0.2,-7.7) 49(0.2,-7.7) 50(0.6,-7.7) 51(1,-7.7) 52(1.4,-7.7) 53(1.8,-7.7) 54(2.2,-7.7) 55(2.6,-7.7) 56(3,-7.7) 57(3.4,-7.7) 58(3.8,-7.7) 59(4.2,-7.7) 60(4.6,-7.7) 61(5,-7.7) 62(5.4,-7.7) 63(5.8,-7.7) 64(6.2,-7.7) 97(6.2,7.7) 98(5.8,7.7) 99(5.4,7.7) 100(5,7.7) 101(4.6,7.7) 102(4.2,7.7) 103(3.8,7.7) 104(3.4,7.7) 105(3,7.7) 106(2.6,7.7) 107(2.2,7.7) 108(1.8,7.7) 109(1.4,7.7) 110(1,7.7) 111(0.6,7.7) 112(0.2,7.7) 113(-0.2,7.7) 114(-0.6,7.7) 115(-1,7.7) 116(-1.4,7.7) 117(-1.8,7.7) 118(-2.2,7.7) 119(-2.6,7.7) 120(-3,7.7) 121(-3.4,7.7) 122(-3.8,7.7) 123(-4.2,7.7) 124(-4.6,7.7) 125(-5,7.7) 126(-5.4,7.7) 127(-5.8,7.7) 128(-6.2,7.7)
  silkscreen extent -7.7,-6.3 6.3,6.99, body extent -8,-8 8,8, height 1.07
PW0016A_L [mm] "TSOP, 16-Leads, Body 5x4.4mm, Pitch 0.65mm, IPC High Density"
  oval 1.2x0.4 smd: 1(-2.85,2.275) 2(-2.85,1.625) 3(-2.85,0.975) 4(-2.85,0.325) 5(-2.85,-0.325) 6(-2.85,-0.975) 7(-2.85,-1.625) 8(-2.85,-2.275) 9(2.85,-2.275) 10(2.85,-1.625) 11(2.85,-0.975) 12(2.85,-0.325) 13(2.85,0.325) 14(2.85,0.975) 15(2.85,1.625) 16(2.85,2.275)
  silkscreen extent -2,-2.55 1.85,2.55, body extent -3.21,-2.5 3.21,2.5, height 1
RGT0016A [mm] "QFN, 16-Leads, Body 3x3mm, Pitch 0.5mm, Thermal Pad 1.45x1.45mm, TI Recommended"
  rrect42% 0.6x0.24 smd: 1(-1.4,0.75) 2(-1.4,0.25) 3(-1.4,-0.25) 4(-1.4,-0.75) 9(1.4,-0.75) 10(1.4,-0.25) 11(1.4,0.25) 12(1.4,0.75)
  rrect42% 0.24x0.6 smd: 5(-0.75,-1.4) 6(-0.25,-1.4) 7(0.25,-1.4) 8(0.75,-1.4) 13(0.75,1.4) 14(0.25,1.4) 15(-0.25,1.4) 16(-0.75,1.4)
  rrect7% 1.34x1.34 on Top Paste: 17(0,0)
  rrect7% 1.45x1.45 smd paste-0.725: 17(0,0)
  silkscreen extent -1.72,-1.73 1.72,1.73, body extent -1.5,-1.5 1.5,1.5, height 1
RGY0020A [mm] "QFN, 20-Leads, Body 4.5x3.5mm, Pitch 0.5mm, Thermal Pad 3.05x2.05mm, TI Recommended"
  oval 0.24x0.6 smd: 1(-0.75,2.15) 10(-0.75,-2.15) 11(0.75,-2.15) 20(0.75,2.15)
  oval 0.6x0.24 smd: 2(-1.65,1.75) 3(-1.65,1.25) 4(-1.65,0.75) 5(-1.65,0.25) 6(-1.65,-0.25) 7(-1.65,-0.75) 8(-1.65,-1.25) 9(-1.65,-1.75) 12(1.65,-1.75) 13(1.65,-1.25) 14(1.65,-0.75) 15(1.65,-0.25) 16(1.65,0.25) 17(1.65,0.75) 18(1.65,1.25) 19(1.65,1.75)
  rect 2.05x3.05 smd paste-1.025: 21(0,0)
  silkscreen extent -1.97,-2.47 1.97,2.48, body extent -1.75,-2.25 1.75,2.25, height 1
RGZ0048B-MFG [mm]
  rrect42% 0.6x0.24 smd paste+0 mask+0: 1(-3.4,2.75) 2(-3.4,2.25) 3(-3.4,1.75) 4(-3.4,1.25) 5(-3.4,0.75) 6(-3.4,0.25) 7(-3.4,-0.25) 8(-3.4,-0.75) 9(-3.4,-1.25) 10(-3.4,-1.75) 11(-3.4,-2.25) 12(-3.4,-2.75) 25(3.4,-2.75) 26(3.4,-2.25) 27(3.4,-1.75) 28(3.4,-1.25) 29(3.4,-0.75) 30(3.4,-0.25) 31(3.4,0.25) 32(3.4,0.75) 33(3.4,1.25) 34(3.4,1.75) 35(3.4,2.25) 36(3.4,2.75)
  rrect42% 0.24x0.6 smd paste+0 mask+0: 13(-2.75,-3.4) 14(-2.25,-3.4) 15(-1.75,-3.4) 16(-1.25,-3.4) 17(-0.75,-3.4) 18(-0.25,-3.4) 19(0.25,-3.4) 20(0.75,-3.4) 21(1.25,-3.4) 22(1.75,-3.4) 23(2.25,-3.4) 24(2.75,-3.4) 37(2.75,3.4) 38(2.25,3.4) 39(1.75,3.4) 40(1.25,3.4) 41(0.75,3.4) 42(0.25,3.4) 43(-0.25,3.4) 44(-0.75,3.4) 45(-1.25,3.4) 46(-1.75,3.4) 47(-2.25,3.4) 48(-2.75,3.4)
  rrect2% 4.1x4.1 smd paste-1000 mask+0: 49(0,0)
  silkscreen extent -4.38,-3.57 3.57,3.57, body extent -3.5,-3.5 3.5,3.5, height 1.02
RPU0010A-MFG [mm]
  rrect50% 0.65x0.2 smd paste+0 mask+0: 1(-0.875,0.25) 3(-0.875,-0.75) 5(0.875,-0.25)
  rrect50% 1x0.2 smd paste+0 mask+0: 2(-0.7,-0.25) 4(0.7,-0.75) 6(0.7,0.25)
  rrect40% 0.25x0.55 smd paste+0 mask+0: 7(0.75,0.925) 8(0.25,0.925) 9(-0.25,0.925) 10(-0.75,0.925)
  silkscreen extent -1.97,-1.5 1,1.6, body extent -1.3,-1.15 1.3,1.3, height 0.25
RSE0010A [mm] "QFN, 10-Leads, Body 1.5x2mm, Pitch 0.5mm, TI Recommended"
  rect 0.55x0.2 smd: 1(-0.675,0.75) 2(-0.675,0.25) 3(-0.675,-0.25) 4(-0.675,-0.75) 6(0.675,-0.75) 7(0.675,-0.25) 8(0.675,0.25) 9(0.675,0.75)
  rect 0.3x0.6 smd: 5(0,-0.9) 10(0,0.9)
  silkscreen extent -1.07,-1.17 0.77,1.18, body extent -0.77,-1.02 0.78,1.03, height 0.61
RSV0016A [mm] "QFN, 16-Leads, Body 1.8x2.6mm, Pitch 0.4mm, TI Recommended"
  rect 0.7x0.2 smd: 1(-0.75,0.6)
  rect 0.6x0.2 smd: 2(-0.8,0.2) 3(-0.8,-0.2) 4(-0.8,-0.6) 9(0.8,-0.6) 10(0.8,-0.2) 11(0.8,0.2) 12(0.8,0.6)
  rect 0.2x0.6 smd: 5(-0.6,-1.2) 6(-0.2,-1.2) 7(0.2,-1.2) 8(0.6,-1.2) 13(0.6,1.2) 14(0.2,1.2) 15(-0.2,1.2) 16(-0.6,1.2)
  silkscreen extent -1.08,-1.33 1.08,1.45, body extent -0.92,-1.32 0.92,1.33, height 0.56
RTW0024B [mm] "QFN, 24-Leads, Body 4x4mm, Pitch 0.5mm, Thermal Pad 2.45x2.45mm, TI Recommended"
  rrect42% 0.6x0.24 smd: 1(-1.9,1.25) 2(-1.9,0.75) 3(-1.9,0.25) 4(-1.9,-0.25) 5(-1.9,-0.75) 6(-1.9,-1.25) 13(1.9,-1.25) 14(1.9,-0.75) 15(1.9,-0.25) 16(1.9,0.25) 17(1.9,0.75) 18(1.9,1.25)
  rrect42% 0.24x0.6 smd: 7(-1.25,-1.9) 8(-0.75,-1.9) 9(-0.25,-1.9) 10(0.25,-1.9) 11(0.75,-1.9) 12(1.25,-1.9) 19(1.25,1.9) 20(0.75,1.9) 21(0.25,1.9) 22(-0.25,1.9) 23(-0.75,1.9) 24(-1.25,1.9)
  rrect4% 2.45x2.45 smd paste-1.225: 25(0,0)
  silkscreen extent -2.22,-2.22 2.22,2.22, body extent -2.07,-2.07 2.07,2.07, height 0.81
RUA0042A-MFG [mm]
  rrect40% 0.6x0.25 smd paste+0 mask+0: 1(-1.65,4) 2(-1.65,3.5) 3(-1.65,3) 4(-1.65,2.5) 5(-1.65,2) 6(-1.65,1.5) 7(-1.65,1) 8(-1.65,0.5) 9(-1.65,0) 10(-1.65,-0.5) 11(-1.65,-1) 12(-1.65,-1.5) 13(-1.65,-2) 14(-1.65,-2.5) 15(-1.65,-3) 16(-1.65,-3.5) 17(-1.65,-4) 22(1.65,-4) 23(1.65,-3.5) 24(1.65,-3) 25(1.65,-2.5) 26(1.65,-2) 27(1.65,-1.5) 28(1.65,-1) 29(1.65,-0.5) 30(1.65,0) 31(1.65,0.5) 32(1.65,1) 33(1.65,1.5) 34(1.65,2) 35(1.65,2.5) 36(1.65,3) 37(1.65,3.5) 38(1.65,4)
  rrect40% 0.25x0.6 smd paste+0 mask+0: 18(-0.75,-4.4) 19(-0.25,-4.4) 20(0.25,-4.4) 21(0.75,-4.4) 39(0.75,4.4) 40(0.25,4.4) 41(-0.25,4.4) 42(-0.75,4.4)
  rrect5% 2.05x7.55 smd paste-1000 mask+0: 43(0,0)
  silkscreen extent -2.65,-4.55 1.8,4.55, body extent -2.05,-4.8 2.05,4.8, height 0.25
RWB0012A [mm] "QFN, 12-Leads, Body 1.6x1.6mm, Pitch 0.4mm"
  rrect57% 0.7x0.2 smd paste-0.1: 1(-0.65,0.2) 2(-0.65,-0.2) 7(0.65,-0.2) 8(0.65,0.2)
  rrect57% 0.2x0.5 smd: 3(-0.6,-0.75) 4(-0.2,-0.75) 5(0.2,-0.75) 6(0.6,-0.75) 9(0.6,0.75) 10(0.2,0.75) 11(-0.2,0.75) 12(-0.6,0.75)
  silkscreen extent -0.92,-0.91 0.92,0.91, body extent -0.8,-0.8 0.8,0.8, height 0.4
SMB-Bi [mil] "Molded Diode, 2-Leads, Body 5.4x3.6mm, IPC Medium Density, based on OnSemi component dimensions"
  rect 85x107.99 smd: 1(-87.01,0) 2(87.01,0)
  silkscreen extent -125,-79 125,79, body extent -104,-73 104,73, height 89
SOIC-8 [mm] "duplicate of SO-8.  SOIC, 8-Leads, Body 5.0x4.0mm (max), Pitch 1.27mm, IPC Medium Density"
  rrect17% 1.45x0.6 smd: 1(-2.725,1.905) 2(-2.725,0.635) 3(-2.725,-0.635) 4(-2.725,-1.905) 5(2.725,-1.905) 6(2.725,-0.635) 7(2.725,0.635) 8(2.725,1.905)
  silkscreen extent -3.5,-2.5 0.9,2.5, body extent -3,-2.45 3,2.45, height 1.63
SOT-23 [mm] "SOT23, 3-Leads, Body 2.9x1.3mm, Pitch 0.95mm, Lead Span 2.5mm, IPC Medium Density"
  rrect50% 1x0.6 smd: 1(-1.2,0.95) 2(-1.2,-0.95) 3(1.2,0)
  silkscreen extent -1.63,-1.5 0.7,1.5, body extent -1.16,-1.45 1.21,1.45, height 1
SOT-323 [mm] "Diodes Inc recommended land pattern.  2016-02-24"
  rrect21% 0.6x0.47 smd: 1(-0.95,0.65) 2(-0.95,-0.65) 3(0.95,0)
  silkscreen extent -1.14,-1.22 0.77,1.22, body extent -1.13,-1.13 1.12,1.12, height 1.13
Sullins_PBC02SAAN [mm] "Sullins 100mil, 1x2, 230 mil above insulator"
  rect 1.65x1.65 hole 1.016: 1(0,1.27)
  round 1.65 hole 1.016: 2(0,-1.27)
  silkscreen extent -1.37,-2.54 1.27,3.1, body extent -1.27,-2.54 1.27,2.54, height 8.38
Sullins_PxC05SAAN [mm] "Header, 2.54mm, 5x1, TH"
  rect 1.55x1.55 hole 1.016: 1(-5.08,0)
  round 1.55 hole 1.016: 2(-2.54,0) 3(0,0) 4(2.54,0) 5(5.08,0)
  silkscreen extent -6.35,-1.75 6.35,1.27, body extent -6.35,-1.27 6.35,1.27, height 5.84
Sullins_xxPC005DAAN-RC [mm] "Header, 2.54mm, 5x2, TH"
  rrect50% 1.5x1.5 hole 1: 1(-1.27,5.08)
  round 1.5 hole 1: 2(1.27,5.08) 3(-1.27,2.54) 4(1.27,2.54) 5(-1.27,0) 6(1.27,0) 7(-1.27,-2.54) 8(1.27,-2.54) 9(-1.27,-5.08) 10(1.27,-5.08)
  body extent -2.5,-6.35 2.5,6.35, height 8.34
SW_CAS-120TA [mm] "COPAL ELECTRONICS"
  rect 1.6x1 smd: 1(-1.15,1.75) 2(1.15,0) 3(-1.15,-1.75)
  silkscreen extent -2,-2.85 1.4,2.93, body extent -1.4,-2.85 1.4,2.85, height 2.51
SW_CAS-D20TA [mm] "SMD, 6-Leads, Body 5.4x3.9mm, Pitch 1.75mm"
  rect 1.6x1 smd: 1(-1.85,1.75) 2(-1.85,0) 3(-1.85,-1.75) 4(1.85,1.75) 5(1.85,0) 6(1.85,-1.75)
  silkscreen extent -1.95,-2.7 1.95,2.9, body extent -2.1,-2.7 2.1,2.7, height 2.5
TI_Stacked_Overlay_Small [mil]
  silkscreen extent -418,-98 418,98
TP_25MIL-SMT [mil]
  round 25 smd mask-2.5: 1(0,0)
TP_SM_1MM [mm] "1mm Test Point, SMT"
  round 1 smd paste-0.5: 1(0,0)
WE-MAPI_4020 [mm] "SMD, 2-Leads, Body 4.1x4.1mm"
  rect 0.98x3.7 smd: 1(-1.185,0) 2(1.185,0)
  silkscreen extent -2.15,-2.15 2.15,2.15, body extent -2.15,-2.15 2.15,2.15, height 2.1
WEEE_Minimum [mil] "WEEElie bin"
  silkscreen extent -95,-172 99,104
WL-SMCW_GREEN [mm] "WURTH"
  rect 0.8x0.8 smd: 1(-0.8,0) 2(0.8,0)
  silkscreen extent -1.9,-0.8 1.2,0.8, body extent -0.85,-0.45 0.85,0.45, height 0.8
WL-SMCW_RED [mm] "WURTH"
  rect 0.8x0.8 smd: 1(-0.8,0) 2(0.8,0)
  silkscreen extent -1.9,-0.8 1.2,0.8, body extent -0.85,-0.45 0.85,0.45, height 0.8
ZCZ0324A-MFG [mm]
  round 0.4 smd paste+0 mask+0.05: A1(-6.8,6.8) A2(-6,6.8) A3(-5.2,6.8) A4(-4.4,6.8) A5(-3.6,6.8) A6(-2.8,6.8) A7(-2,6.8) A8(-1.2,6.8) A9(-0.4,6.8) A10(0.4,6.8) A11(1.2,6.8) A12(2,6.8) A13(2.8,6.8) A14(3.6,6.8) A15(4.4,6.8) A16(5.2,6.8) A17(6,6.8) A18(6.8,6.8) B1(-6.8,6) B2(-6,6) B3(-5.2,6) B4(-4.4,6) B5(-3.6,6) B6(-2.8,6) B7(-2,6) B8(-1.2,6) B9(-0.4,6) B10(0.4,6) B11(1.2,6) B12(2,6) B13(2.8,6) B14(3.6,6) B15(4.4,6) B16(5.2,6) B17(6,6) B18(6.8,6) C1(-6.8,5.2) C2(-6,5.2) C3(-5.2,5.2) C4(-4.4,5.2) C5(-3.6,5.2) C6(-2.8,5.2) C7(-2,5.2) C8(-1.2,5.2) C9(-0.4,5.2) C10(0.4,5.2) C11(1.2,5.2) C12(2,5.2) C13(2.8,5.2) C14(3.6,5.2) C15(4.4,5.2) C16(5.2,5.2) C17(6,5.2) C18(6.8,5.2) D1(-6.8,4.4) D2(-6,4.4) D3(-5.2,4.4) D4(-4.4,4.4) D5(-3.6,4.4) D6(-2.8,4.4) D7(-2,4.4) D8(-1.2,4.4) D9(-0.4,4.4) D10(0.4,4.4) D11(1.2,4.4) D12(2,4.4) D13(2.8,4.4) D14(3.6,4.4) D15(4.4,4.4) D16(5.2,4.4) D17(6,4.4) D18(6.8,4.4) E1(-6.8,3.6) E2(-6,3.6) E3(-5.2,3.6) E4(-4.4,3.6) E5(-3.6,3.6) E6(-2.8,3.6) E7(-2,3.6) E8(-1.2,3.6) E9(-0.4,3.6) E10(0.4,3.6) E11(1.2,3.6) E12(2,3.6) E13(2.8,3.6) E14(3.6,3.6) E15(4.4,3.6) E16(5.2,3.6) E17(6,3.6) E18(6.8,3.6) F1(-6.8,2.8) F2(-6,2.8) F3(-5.2,2.8) F4(-4.4,2.8) F5(-3.6,2.8) F6(-2.8,2.8) F7(-2,2.8) F8(-1.2,2.8) F9(-0.4,2.8) F10(0.4,2.8) F11(1.2,2.8) F12(2,2.8) F13(2.8,2.8) F14(3.6,2.8) F15(4.4,2.8) F16(5.2,2.8) F17(6,2.8) F18(6.8,2.8) G1(-6.8,2) G2(-6,2) G3(-5.2,2) G4(-4.4,2) G5(-3.6,2) G6(-2.8,2) G7(-2,2) G8(-1.2,2) G9(-0.4,2) G10(0.4,2) G11(1.2,2) G12(2,2) G13(2.8,2) G14(3.6,2) G15(4.4,2) G16(5.2,2) G17(6,2) G18(6.8,2) H1(-6.8,1.2) H2(-6,1.2) H3(-5.2,1.2) H4(-4.4,1.2) H5(-3.6,1.2) H6(-2.8,1.2) H7(-2,1.2) H8(-1.2,1.2) H9(-0.4,1.2) H10(0.4,1.2) H11(1.2,1.2) H12(2,1.2) H13(2.8,1.2) H14(3.6,1.2) H15(4.4,1.2) H16(5.2,1.2) H17(6,1.2) H18(6.8,1.2) J1(-6.8,0.4) J2(-6,0.4) J3(-5.2,0.4) J4(-4.4,0.4) J5(-3.6,0.4) J6(-2.8,0.4) J7(-2,0.4) J8(-1.2,0.4) J9(-0.4,0.4) J10(0.4,0.4) J11(1.2,0.4) J12(2,0.4) J13(2.8,0.4) J14(3.6,0.4) J15(4.4,0.4) J16(5.2,0.4) J17(6,0.4) J18(6.8,0.4) K1(-6.8,-0.4) K2(-6,-0.4) K3(-5.2,-0.4) K4(-4.4,-0.4) K5(-3.6,-0.4) K6(-2.8,-0.4) K7(-2,-0.4) K8(-1.2,-0.4) K9(-0.4,-0.4) K10(0.4,-0.4) K11(1.2,-0.4) K12(2,-0.4) K13(2.8,-0.4) K14(3.6,-0.4) K15(4.4,-0.4) K16(5.2,-0.4) K17(6,-0.4) K18(6.8,-0.4) L1(-6.8,-1.2) L2(-6,-1.2) L3(-5.2,-1.2) L4(-4.4,-1.2) L5(-3.6,-1.2) L6(-2.8,-1.2) L7(-2,-1.2) L8(-1.2,-1.2) L9(-0.4,-1.2) L10(0.4,-1.2) L11(1.2,-1.2) L12(2,-1.2) L13(2.8,-1.2) L14(3.6,-1.2) L15(4.4,-1.2) L16(5.2,-1.2) L17(6,-1.2) L18(6.8,-1.2) M1(-6.8,-2) M2(-6,-2) M3(-5.2,-2) M4(-4.4,-2) M5(-3.6,-2) M6(-2.8,-2) M7(-2,-2) M8(-1.2,-2) M9(-0.4,-2) M10(0.4,-2) M11(1.2,-2) M12(2,-2) M13(2.8,-2) M14(3.6,-2) M15(4.4,-2) M16(5.2,-2) M17(6,-2) M18(6.8,-2) N1(-6.8,-2.8) N2(-6,-2.8) N3(-5.2,-2.8) N4(-4.4,-2.8) N5(-3.6,-2.8) N6(-2.8,-2.8) N7(-2,-2.8) N8(-1.2,-2.8) N9(-0.4,-2.8) N10(0.4,-2.8) N11(1.2,-2.8) N12(2,-2.8) N13(2.8,-2.8) N14(3.6,-2.8) N15(4.4,-2.8) N16(5.2,-2.8) N17(6,-2.8) N18(6.8,-2.8) P1(-6.8,-3.6) P2(-6,-3.6) P3(-5.2,-3.6) P4(-4.4,-3.6) P5(-3.6,-3.6) P6(-2.8,-3.6) P7(-2,-3.6) P8(-1.2,-3.6) P9(-0.4,-3.6) P10(0.4,-3.6) P11(1.2,-3.6) P12(2,-3.6) P13(2.8,-3.6) P14(3.6,-3.6) P15(4.4,-3.6) P16(5.2,-3.6) P17(6,-3.6) P18(6.8,-3.6) R1(-6.8,-4.4) R2(-6,-4.4) R3(-5.2,-4.4) R4(-4.4,-4.4) R5(-3.6,-4.4) R6(-2.8,-4.4) R7(-2,-4.4) R8(-1.2,-4.4) R9(-0.4,-4.4) R10(0.4,-4.4) R11(1.2,-4.4) R12(2,-4.4) R13(2.8,-4.4) R14(3.6,-4.4) R15(4.4,-4.4) R16(5.2,-4.4) R17(6,-4.4) R18(6.8,-4.4) T1(-6.8,-5.2) T2(-6,-5.2) T3(-5.2,-5.2) T4(-4.4,-5.2) T5(-3.6,-5.2) T6(-2.8,-5.2) T7(-2,-5.2) T8(-1.2,-5.2) T9(-0.4,-5.2) T10(0.4,-5.2) T11(1.2,-5.2) T12(2,-5.2) T13(2.8,-5.2) T14(3.6,-5.2) T15(4.4,-5.2) T16(5.2,-5.2) T17(6,-5.2) T18(6.8,-5.2) U1(-6.8,-6) U2(-6,-6) U3(-5.2,-6) U4(-4.4,-6) U5(-3.6,-6) U6(-2.8,-6) U7(-2,-6) U8(-1.2,-6) U9(-0.4,-6) U10(0.4,-6) U11(1.2,-6) U12(2,-6) U13(2.8,-6) U14(3.6,-6) U15(4.4,-6) U16(5.2,-6) U17(6,-6) U18(6.8,-6) V1(-6.8,-6.8) V2(-6,-6.8) V3(-5.2,-6.8) V4(-4.4,-6.8) V5(-3.6,-6.8) V6(-2.8,-6.8) V7(-2,-6.8) V8(-1.2,-6.8) V9(-0.4,-6.8) V10(0.4,-6.8) V11(1.2,-6.8) V12(2,-6.8) V13(2.8,-6.8) V14(3.6,-6.8) V15(4.4,-6.8) V16(5.2,-6.8) V17(6,-6.8) V18(6.8,-6.8)
  silkscreen extent -8.15,-7.55 7.55,7.55, body extent -8.05,-8.05 8.05,8.05, height 0.25

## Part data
C1 C2 C3 C4 C5 C6 C14 C23 C25 C52 C53 C68 C236: library part CMP-0042976-1, "Cap Ceramic 3.3uF 10V X5R ±10% Pad SMD 0603 +85°C T/R", Digikey Part Number=1276-1892-1-ND, Manufacturer=Samsung, Mouser Part Number=187-CL10A335KP8NNNC, Operating Temperature Range="-55°C to +85°C", TempCo=15%, Temperature Characteristic=X5R, Tolerance_%=10%, ValueDisplayed=3.3uF
C7 C8 C9 C10 C11 C12 C13 C15 C16 C17 C18 C24 C26 C27 C28 C34 C35 C36 C37 C38 C43 C48 C57 C60 C61 C62 C64 C65 C69 C70 C71 C78 C79 C80 C90 C91 C98 C99 C100 C111 C117 C119 C121 C125 C127 C131 C133 C134 C136 C137 C138 C139 C140 C141 C142 C145 C147 C150 C151 C154 C155 C163 C165 C174 C176 C181 C182 C183 C184 C186 C188 C194 C196 C198 C202 C204 C208 C210 C223 C225 C226 C233 C237 C238 C239 C240 C241 C242 C243 C244 C245 C246 C250 C251 C252 C257 C262: library part CMP-0006659-2, "CAP, CERM, 0.1 uF, 25 V, +/- 10%, X7R, 0402", Cap_Case=0402, Manufacturer=MuRata, Supplier Part Number 1=490-10698-1-ND, TempCo=X7R, Tolerance_%=10%, Value1=Unknown, Value2=25V, ValueDisplayed=0.1uF
C19 C20 C21 C22 C29 C30 C31 C32 C39 C40 C41 C42 C44 C45 C46 C47: library part CMP-0093721-1, "Chip Multilayer Ceramic Capacitors for General Purpose, 0201, 1.0uF, X6S, 22%, 20%, 6.3V", Manufacturer=Murata, Operating Temperature Range="-55°C to +105°C", TempCo=22%, Temperature Characteristic=X6S, Tolerance_%=20%, ValueDisplayed=1.0uF
C33 C76 C77 C89: library part CMP-0007498-4, "CAP, CERM, 4.7 uF, 10 V, +/- 20%, X7R, 0603", Cap_Case=0603, Manufacturer=MuRata, TempCo=X7R, Tolerance_%=20%, Value1=Unknown, Value2=10V, ValueDisplayed=4.7uF
C49 C50 C51 C54 C55 C56: library part CMP-0064970-1, "CAP, CERM, 0.1 uF, 16 V,+/- 10%, X7R, 0201", Cap_Case=0201, Manufacturer=MuRata, Supplier Part Number 1=81-GRM033Z71C104KE4D, TempCo=X7R, Tolerance_%=10%, Value1=Unknown, Value2=16V, ValueDisplayed=0.1uF
C58 C59 C112 C113 C189 C190: library part CMP-0035228-1, "Multi-Layer Ceramic Capacitor 12pF C0G  ±5% 0402 Paper T/R", Manufacturer=Murata, Operating Temperature Range="-55°C to +125°C", TempCo=30ppm/°C, Temperature Characteristic=C0G, Tolerance_%=5%, ValueDisplayed=12pF
C63 C115 C123 C129 C135 C149 C152 C192 C200 C206: library part CMP-0035343-1, "Chip Multilayer Ceramic Capacitors for General Purpose, 0402, 10000pF, C0G, 30ppm/°C, 5%, 25V", Manufacturer=Murata, Operating Temperature Range="-55°C to +125°C", TempCo=30ppm/°C, Temperature Characteristic=C0G, Tolerance_%=5%, ValueDisplayed=10000pF
C66 C259 C260 C263 C264 C267 C268 C270 C271 C272: library part CMP-0006221-2, "CAP, CERM, 0.1 uF, 10 V, +/- 20%, X5R, 0402", Cap_Case=0402, Manufacturer="Wurth Elektronik", Supplier Part Number 1=732-7487-1-ND, TempCo=X5R, Tolerance_%=20%, Value1=Unknown, Value2=10V, ValueDisplayed=0.1uF
C67 C161 C172: library part CMP-0064936-4, "CAP, CERM, 4.7 uF, 16 V,+/- 10%, X7R, 0603", Cap_Case=0603, Manufacturer=MuRata, TempCo=X7R, Tolerance_%=10%, Value1=Unknown, Value2=16V, ValueDisplayed=4.7uF
C72 C73 C74 C75 C81 C82 C83 C84 C85 C86 C87 C88 C92 C93 C94 C95 C96 C97: library part CMP-0006456-2, "CAP, CERM, 330 pF, 50 V, +/- 5%, C0G/NP0, 0402", Cap_Case=0402, Manufacturer=MuRata, Supplier Part Number 1=490-1295-1-ND, TempCo=C0G/NP0, Tolerance_%=5%, Value1=Unknown, Value2=50V, ValueDisplayed=330pF
C101 C106 C108 C110 C211 C212 C213 C224 C248 C249: library part CMP-0007469-4, "CAP, CERM, 0.1 uF, 100 V, +/- 10%, X7R, 0603", Cap_Case=0603, Manufacturer=MuRata, Supplier Part Number 1=490-3285-1-ND, TempCo=X7R, Tolerance_%=10%, Value1=Unknown, Value2=100V, ValueDisplayed=0.1uF
C102 C104 C105 C107 C164 C167 C168 C175 C179 C180: library part CMP-0087970-1, "10µF ±10% 100V Ceramic Capacitor X7S 1210 (3225 Metric)", Manufacturer=Murata, TempCo=22%, Tolerance_%=10%, ValueDisplayed=10uF
C103: library part CMP-0007470-5, "CAP, CERM, 0.1 uF, 100 V, +/- 10%, X7R, 0603", Cap_Case=0603, Manufacturer=MuRata, Supplier Part Number 1=490-6439-1-ND, TempCo=X7R, Tolerance_%=10%, Value1=Unknown, Value2=100V, ValueDisplayed=0.1uF
C109: library part CMP-0006412-2, "CAP, CERM, 1000 pF, 50 V, +/- 5%, C0G/NP0, 0402", Cap_Case=0402, Manufacturer=MuRata, Supplier Part Number 1=490-3244-1-ND, TempCo=C0G/NP0, Tolerance_%=5%, Value1=Unknown, Value2=50V, ValueDisplayed=1000pF
C114 C122 C128 C191 C199 C205: library part CMP-0007497-5, "CAP, CERM, 10 uF, 10 V, +/- 20%, X7R, 0603", Cap_Case=0603, Manufacturer=MuRata, Supplier Part Number 1=81-GRM188Z71A106MA3D, TempCo=X7R, Tolerance_%=20%, Value1=Unknown, Value2=10V, ValueDisplayed=10uF
C116 C118 C120 C124 C126 C130 C132 C193 C195 C197 C201 C203 C207 C209: library part CMP-0006624-2, "CAP, CERM, 1 uF, 6.3 V, +/- 20%, X7R, 0402", Cap_Case=0402, Manufacturer=MuRata, Supplier Part Number 1=490-9665-1-ND, TempCo=X7R, Tolerance_%=20%, Value1=Unknown, Value2=6.3V, ValueDisplayed=1uF
C143 C144: library part CMP-0035284-1, "Multi-Layer Ceramic Capacitor 8pF C0G  ±0.5pF 0402 Paper T/R", Manufacturer=Murata, Operating Temperature Range="-55°C to +125°C", TempCo=30ppm/°C, Temperature Characteristic=C0G, ValueDisplayed=8pF
C146 C148 C156 C162 C173 C187 C232: library part CMP-0035346-1, "1µF ±10% 10V Ceramic Capacitor X7S 0402 (1005 Metric)", Digikey Part Number=490-14457-1-ND, Manufacturer=Murata, Mouser Part Number=81-GRM155C71A105KE1D, Operating Temperature Range="-55°C to +125°C", TempCo=22%, Temperature Characteristic=X7S, Tolerance_%=10%, ValueDisplayed=1uF
C153 C231: library part CMP-0006526-2, "CAP, CERM, 2.2 uF, 16 V, +/- 10%, X6S, 0402", Cap_Case=0402, Manufacturer=MuRata, Supplier Part Number 1=GRM155C81C225KE11D-ND, TempCo=X6S, Tolerance_%=10%, Value1=Unknown, Value2=16V, ValueDisplayed=2.2uF
C157 C158 C169 C170 C185: library part CMP-0008377-2, "CAP, CERM, 22 uF, 10 V, +/- 20%, X7R, 0805", Cap_Case=0805, Manufacturer=MuRata, Supplier Part Number 1=81-GRM21BZ71A226ME5L, TempCo=X7R, Tolerance_%=20%, Value1=Unknown, Value2=10V, ValueDisplayed=22uF
C159 C171: library part CMP-0009221-2, "CAP, CERM, 47 uF, 10 V, +/- 20%, X7R, 1210", Cap_Case=1210, Manufacturer=MuRata, Supplier Part Number 1=490-6543-1-ND, TempCo=X7R, Tolerance_%=20%, Value1=Unknown, Value2=10V, ValueDisplayed=47uF
C160 C177: library part CMP-0007424-4, "CAP, CERM, 0.47 uF, 25 V, +/- 10%, X7R, 0603", Cap_Case=0603, Manufacturer=MuRata, Supplier Part Number 1=490-3291-1-ND, TempCo=X7R, Tolerance_%=10%, Value1=Unknown, Value2=25V, ValueDisplayed=0.47uF
C166 C178: library part CMP-0035196-1, "Ceramic Capacitor for Automotive 2.7nF ±10% 100VDC X7R 0402 Paper T/R", Manufacturer=Murata, Operating Temperature Range="-55°C to +125°C", TempCo=15%, Temperature Characteristic=X7R, Tolerance_%=0.1%, ValueDisplayed=2.7nF
C214 C216 C217 C219 C220 C221: library part CMP-0007173-4, "CAP, CERM, 1000 pF, 50 V, +/- 5%, C0G/NP0, 0603", Cap_Case=0603, Manufacturer=MuRata, Supplier Part Number 1=490-1451-1-ND, TempCo=C0G/NP0, Tolerance_%=5%, Value1=Unknown, Value2=50V, ValueDisplayed=1000pF
C215 C218: library part CMP-0035320-1, "Ceramic Capacitor 100pF ±5% 250VDC C0G 0603 Paper T/R", Manufacturer=Murata, Operating Temperature Range="-55°C to +125°C", TempCo=30ppm/°C, Temperature Characteristic=C0G, Tolerance_%=0.05%, ValueDisplayed=100pF
C222: library part CMP-0006692-2, "CAP, CERM, 4700 pF, 50 V, +/- 10%, X7R, 0402", Cap_Case=0402, Manufacturer=MuRata, Supplier Part Number 1=490-1308-1-ND, TempCo=X7R, Tolerance_%=10%, Value1=Unknown, Value2=50V, ValueDisplayed=4700pF
C227: library part CMP-0008378-2, "CAP, CERM, 10 uF, 25 V, +/- 10%, X7R, 0805", Cap_Case=0805, Manufacturer=MuRata, Supplier Part Number 1=81-GRM21BZ71E106KE5L, TempCo=X7R, Tolerance_%=10%, Value1=Unknown, Value2=25V, ValueDisplayed=10uF
C228: library part CMP-0035231-1, "Multi-Layer Ceramic Capacitor 15pF C0G  ±1% 0402 Paper T/R", Manufacturer=Murata, Operating Temperature Range="-55°C to +125°C", TempCo=30ppm/°C, Temperature Characteristic=C0G, Tolerance_%=1%, ValueDisplayed=15pF
C229 C230 C234 C235 C247: library part CMP-0009436-2, "CAP, CERM, 1000 pF, 2000 V, +/- 10%, X7R, 1808", Cap_Case=1808, Manufacturer=MuRata, Supplier Part Number 1=490-8145-1-ND, TempCo=X7R, Tolerance_%=10%, Value1=Unknown, Value2=2000V, ValueDisplayed=1000pF
C253 C255: library part CMP-0096855-1, "Chip Multilayer Ceramic Capacitors for General Purpose, 0402, 0.10uF, X7R, 15%, 10%, 50V", Manufacturer=Murata, Operating Temperature Range="-55°C to +125°C", TempCo=15%, Temperature Characteristic=X7R, Tolerance_%=10%, ValueDisplayed=0.10uF
C254 C258 C261 C265 C269: library part CMP-0043010-1, "10 µF ±20% 10V Ceramic Capacitor X5R 0402 (1005 Metric)", Digikey Part Number=478-KGM05CR51A106MHCT-ND, Manufacturer="KYOCERA AVX", Mouser Part Number=581-KGM05CR51A106MH, Operating Temperature Range="-55°C to +85°C", TempCo=15%, Temperature Characteristic=X5R, Tolerance_%=20%, ValueDisplayed=10uF
C256: library part CMP-0006610-2, "CAP, CERM, 2.2 uF, 25 V, +/- 10%, X5R, 0402", Cap_Case=0402, Manufacturer=MuRata, Supplier Part Number 1=GRM155R61E225KE11D-ND, TempCo=X5R, Tolerance_%=10%, Value1=Unknown, Value2=25V, ValueDisplayed=2.2uF
C266: library part CMP-0006286-2, "CAP, CERM, 1 uF, 16 V, +/- 10%, X6S, 0402", Cap_Case=0402, Manufacturer=TDK, Supplier Part Number 1=445-9086-1-ND, TempCo=X6S, Tolerance_%=10%, Value1="0.011416 ohm", Value2=16V, ValueDisplayed=1uF
"CAUTION HOT SURFACE": library part CMP-0074837-2, "IEC 61010-1 Hot Surface Warning", Manufacturer="Texas Instruments"
D1: library part CMP-0005599-2, "Diode, TVS, Bi, 6.5 V, SMB", Manufacturer=Littelfuse, Value1=600W
D2 D3 D4 D5 D6 D7 D8 D9 D10 D11 D12 D13 D14: library part CMP-0002894-2, "LED, Green, SMD", Color=green, Manufacturer="Wurth Elektronik", Value1=W, Value2=2V
D15 D16: library part CMP-0073602-3, "1-Channel ESD Protection Diode for USB Type-C and Thunderbolt 3, DPY0002A (X1SON-2)", Alternate Manufacturer="Texas Instruments", Alternate PartNumber=TPD1E01B04DPYT, Operating Temperature Range="-40 to 125 C", Rating=Catalog
DS1 DS2 DS3 DS4: library part CMP-0002947-3, "LED, Red, SMD", Color=Red, Manufacturer="Wurth Elektronik", Power_TotalModule=72mW, Value1=0.072W, Value2=2V
FB1 FB2 FB3 FB4 FB5 FB6: library part CMP-0089199-1, "120 Ohms @ 100MHz 1  Ferrite Bead 0603 (1608 Metric) 2A 40mOhm", Digikey Part Number=490-3991-1-ND, Impedance At Frequency="120Ω @ 100MHz", Manufacturer=Murata, Mouser Part Number=81-BLM18EG121SN1D, Operating Temperature Range="-55°C to +125°C", Tolerance_%=25%
FID1 FID2 FID3 FID4 FID5 FID6 FID7 FID8 FID9 FID10 FID11 FID12: library part CMP-0077181-1, "Fiducial mark.  There is nothing to buy or mount.", Manufacturer=N/A
J1 J9 J10 J13 J14 J15 J16 J17 J18: library part CMP-0054566-1, "Header, 100mil, 2x1, Gold, TH", Color=Black, Current_A=3A, Manufacturer="Sullins Connector Solutions", Supplier Part Number 1=S1011E-02-ND, Voltage_V=1.8kV
J1/J3: library part CMP-0003837-4, "Receptacle, 2.54mm, 10x2, Tin, TH", Alternate Manufacturer="Major League Electronics", Alternate PartNumber=CRD-081413-A-G, Manufacturer=Samtec, Supplier Part Number 1=SAM1204-10-ND
J2: library part CMP-0080007-1, "Conncetor, micro SD, 8+2 Pos, R/A, SMT", Manufacturer="Hirose Electric Co. Ltd.", Supplier Part Number 1=HR1942CT-ND
J2/J4: library part CMP-0078266-4, "Receptacle, 2.54mm, 10x2, Tin, TH", Alternate Manufacturer="Major League Electronics", Alternate PartNumber=CRD-081413-A-G, Manufacturer=Samtec, Supplier Part Number 1=SAM1204-10-ND
J5: library part CMP-0093552-1, "USB-C (USB TYPE-C) USB 3.2 Gen 2 (USB 3.1 Gen 2, Superspeed + (USB 3.1)) Receptacle Connector 24 Position Surface Mount, Right Angle; Through Hole", Digikey Part Number=WM17992CT-ND, Manufacturer=Molex, Mouser Part Number=538-201267-0005, Operating Temperature Range="-40°C to +105°C", Voltage_V=30V
J5/J7: library part CMP-0081070-3, "Receptacle, 2.54mm, 10x2, Tin, TH", Alternate Manufacturer="Major League Electronics", Alternate PartNumber=CRD-081413-A-G, Manufacturer=Samtec, Supplier Part Number 1=SAM1204-10-ND
J6: library part CMP-0093156-1, Current_A=500mA, Digikey Part Number=HFK140CT-ND, Manufacturer=Hirose, Mouser Part Number=798-FH12A-40S0.5SH55, Operating Temperature Range="-40°C to +85°C", Voltage_V=50V
J6/J8: library part CMP-0081071-3, "Receptacle, 2.54mm, 10x2, Tin, TH", Alternate Manufacturer="Major League Electronics", Alternate PartNumber=CRD-081413-A-G, Manufacturer=Samtec, Supplier Part Number 1=SAM1204-10-ND
J7 J8: library part CMP-0093483-1, "RJ45 Connector with 1000 Base-TX Inetgrated Magnetic", Manufacturer=Link-PP, Operating Temperature Range="0°C to +70°C"
J11 J12: library part CMP-0002334-1, "Header, 100mil, 3x1, Gold, TH", Manufacturer="Sullins Connector Solutions", Supplier Part Number 1=S1011E-03-ND
J23: library part CMP-0080722-2, "Header, 2.54mm, 5x2, Gold, TH", Color=Black, Current_A=3A, Manufacturer="Sullins Connector Solutions", Supplier Part Number 1=S2011EC-05-ND, Voltage_V=1kV
J24 J25: library part CMP-0054597-1, "Header, 2.54mm, 5x1, Tin, TH", Color=Black, Current_A=3A, Manufacturer="Sullins Connector Solutions", Supplier Part Number 1=S1012E-05-ND, Voltage_V=1.8kV
J33: library part CMP-0075352-1, "Terminal Block, 3.5mm, 3x1, Tin, R/A, TH", Color=Blue, Current_A=10A, Manufacturer="On-Shore Technology", Supplier Part Number 1=ED2636-ND, Voltage_V=125V
J34: library part CMP-0055311-1, "Receptacle, USB 2.0, Micro B, 5 Position, R/A, SMT", Color=Black, Current_A=1.8A, Manufacturer=Molex, Supplier Part Number 1=WM11263CT-ND, Voltage_V=30V
L1: library part CMP-0098084-1, "Chip Ferrite Bead, 0805, 30Ω @ 100MHz, 0.014Ω, , 4A", Impedance At Frequency="30Ω @ 100MHz", Manufacturer=Murata, Operating Temperature Range="-55°C to +125°C", Test Frequency=100MHz
L2 L3: library part CMP-0064169-1, "Inductor, Shielded, 2.2 uH, 4.7 A, 0.029 ohm, SMD", Manufacturer="Wurth Elektronik", Supplier Part Number 1=732-8232-1-ND, Value1="0.029 ohm", Value2=4.7A, ValueDisplayed=2.2uH
L4: library part CMP-0078538-1, "10µH Semi-Shielded Wirewound Inductor 580mA 816 mOhm Max Nonstandard", Manufacturer="Wurth Electronics"
LBL1: library part CMP-0003625-1, "Thermal Transfer Printable Labels, 0.650\" W x 0.200\" H - 10,000 per roll", Manufacturer=Brady, Supplier Part Number 1=97C5133
Logo1: library part CMP-0074844-1
Logo2: library part CMP-0074838-1, "Texas Instrument Corporate Signature"
Logo3: library part CMP-0074847-1, "FCC_disclaimer"
Logo4: library part CMP-0074769-1
Q1 Q2 Q3: library part CMP-0078819-2, "MOSFET, P-CH, -12 V, -4.3 A, SOT-23", Alternate Manufacturer=None, Manufacturer="Infineon Technologies", Value1="0.05 ohm", Value2="10 nC"
Q4 Q5 Q6 Q7 Q8 Q9: library part CMP-0000947-2, "MOSFET, N-CH, 100 V, 0.17 A, SOT-23", Alternate Manufacturer=None, Manufacturer="Fairchild Semiconductor", Supplier Part Number 1=BSS123NCT-ND, Value1=1, Value2="1.8 nC"
Q10: library part CMP-0000010-3, "MOSFET, P-CH, -20 V, -0.39 A, SOT-323", Alternate Manufacturer=None, Manufacturer="Infineon Technologies", Value1=1
Q11 Q13: library part CMP-0000948-2, "MOSFET, N-CH, 100 V, 0.17 A, SOT-323", Alternate Manufacturer=None, Manufacturer="Diodes Inc.", Supplier Part Number 1=BSS123W-FDICT-ND, Value1=1
R1 R6 R8 R10 R11 R14 R15 R16 R17 R20 R42 R43 R92 R93 R98 R146 R147 R155 R156 R173 R174 R177 R178 R179 R181 R182 R183 R184 R185 R186 R187 R188 R194 R258 R268 R269 R270 R271 R274 R275 R276 R287 R288 R291 R292 R295 R296 R298 R299 R301 R305 R306 R316 R318 R319 R320 R321 R322 R323 R336 R337 R338 R339 R340 R341 R364 R389 R390 R395 R396 R417 R419 R420 R422 R423 R424 R426 R439 R441: library part CMP-0026658-1, "RES, 10.0 k, 1%, 0.1 W, 0402", Manufacturer=Panasonic, Power_W=100mW, Supplier Part Number 1=P10.0KLCT-ND, TempCo="100 ppm/C", Tolerance_%=1%, Value2=0.1W, Value_Code=10k0, ValueDisplayed=10.0k
R2: library part CMP-0026240-2, "RES, 2.67 k, 1%, 0.063 W, AEC-Q200 Grade 0, 0402", Manufacturer=Vishay-Dale, Power_W=63mW, Supplier Part Number 1=541-2.67KLCT-ND, TempCo="100 ppm/C", Tolerance_%=1%, Value2=0.063W, Value_Code=2k67, ValueDisplayed=2.67k
R3 R4 R5 R7 R18 R26 R33 R34 R35 R36 R37 R38 R44 R45 R75 R76 R77 R78 R79 R80 R87 R88 R89 R90 R100 R101 R102 R103 R104 R105 R106 R117 R118 R119 R129 R130 R131 R149 R150 R157 R158 R165 R167 R168 R169 R170 R171 R172 R180 R189 R190 R193 R196 R197 R198 R199 R200 R201 R212 R213 R214 R225 R227 R229 R231 R233 R235 R245 R248 R286 R307 R342 R343 R344 R345 R346 R347 R348 R349 R350 R351 R352 R353 R354 R355 R356 R357 R358 R359 R360 R377 R378 R379 R380 R394 R402 R403 R404 R405 R409 R411 R413 R414 R416 R427 R428 R440 R443 R444 R445: library part CMP-0026992-3, "RES, 0, 5%, 0.1 W, AEC-Q200 Grade 0, 0402", Manufacturer=Panasonic, Power_W=100mW, Supplier Part Number 1=P0.0JCT-ND, TempCo="600 ppm/C", Tolerance_%=5%, Value2=0.1W, Value_Code=0000, ValueDisplayed=0
R9 R12 R13 R46 R47 R48 R49 R50 R51 R52 R53 R54 R57 R58 R59 R60 R65 R66 R67 R68 R69 R70 R81 R82 R83 R84 R85 R86 R99 R164 R166 R249 R280 R281 R282 R283 R284 R285 R297 R382 R393 R401 R433 R436: library part CMP-0026880-3, "RES, 22, 5%, 0.063 W, AEC-Q200 Grade 0, 0402", Manufacturer=Vishay-Dale, Power_W=63mW, Supplier Part Number 1=541-22JCT-ND, TempCo="200 ppm/C", Tolerance_%=5%, Value2=0.063W, Value_Code=22R0, ValueDisplayed=22
R19: library part CMP-0026703-1, "RES, 49.9, 1%, 0.1 W, AEC-Q200 Grade 0, 0402", Manufacturer=Panasonic, Power_W=100mW, Supplier Part Number 1=P49.9LCT-ND, TempCo="100 ppm/C", Tolerance_%=1%, Value2=0.1W, Value_Code=49R9, ValueDisplayed=49.9
R21 R22 R23 R24 R25 R96 R97 R256 R278 R289 R290 R293 R294 R300 R304 R391 R392 R397 R398 R437 R442: library part CMP-0078193-1, "RES, 1.0 k, 5%, 0.1 W, AEC-Q200 Grade 0, 0402", Manufacturer=Panasonic, Power_W=100mW, Supplier Part Number 1=P1.0KJCT-ND, TempCo="200 ppm/C", Tolerance_%=5%, Value2=0.1W, Value_Code=1k00, ValueDisplayed=1.0k
R27 R28 R29 R30 R361 R365 R366 R376 R381 R429 R430 R431 R432: library part CMP-0087090-2, "RES Thick Film SMD 22Ω 1% 1/20W 0201 200ppm/°C", Manufacturer=Vishay, Power_W=50mW, TempCo=200ppm/°C, Tolerance_%=1%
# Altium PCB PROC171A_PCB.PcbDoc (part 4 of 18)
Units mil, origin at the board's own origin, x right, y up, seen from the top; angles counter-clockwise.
Board outline 7700 x 2300 mil, 6 copper layers (Top Layer, GND 1, SIG 1, SIG 2, GND 2, Bottom Layer), stack 61.062 mil thick; 945 components, 692 nets, 11945 pads, 1734 vias.

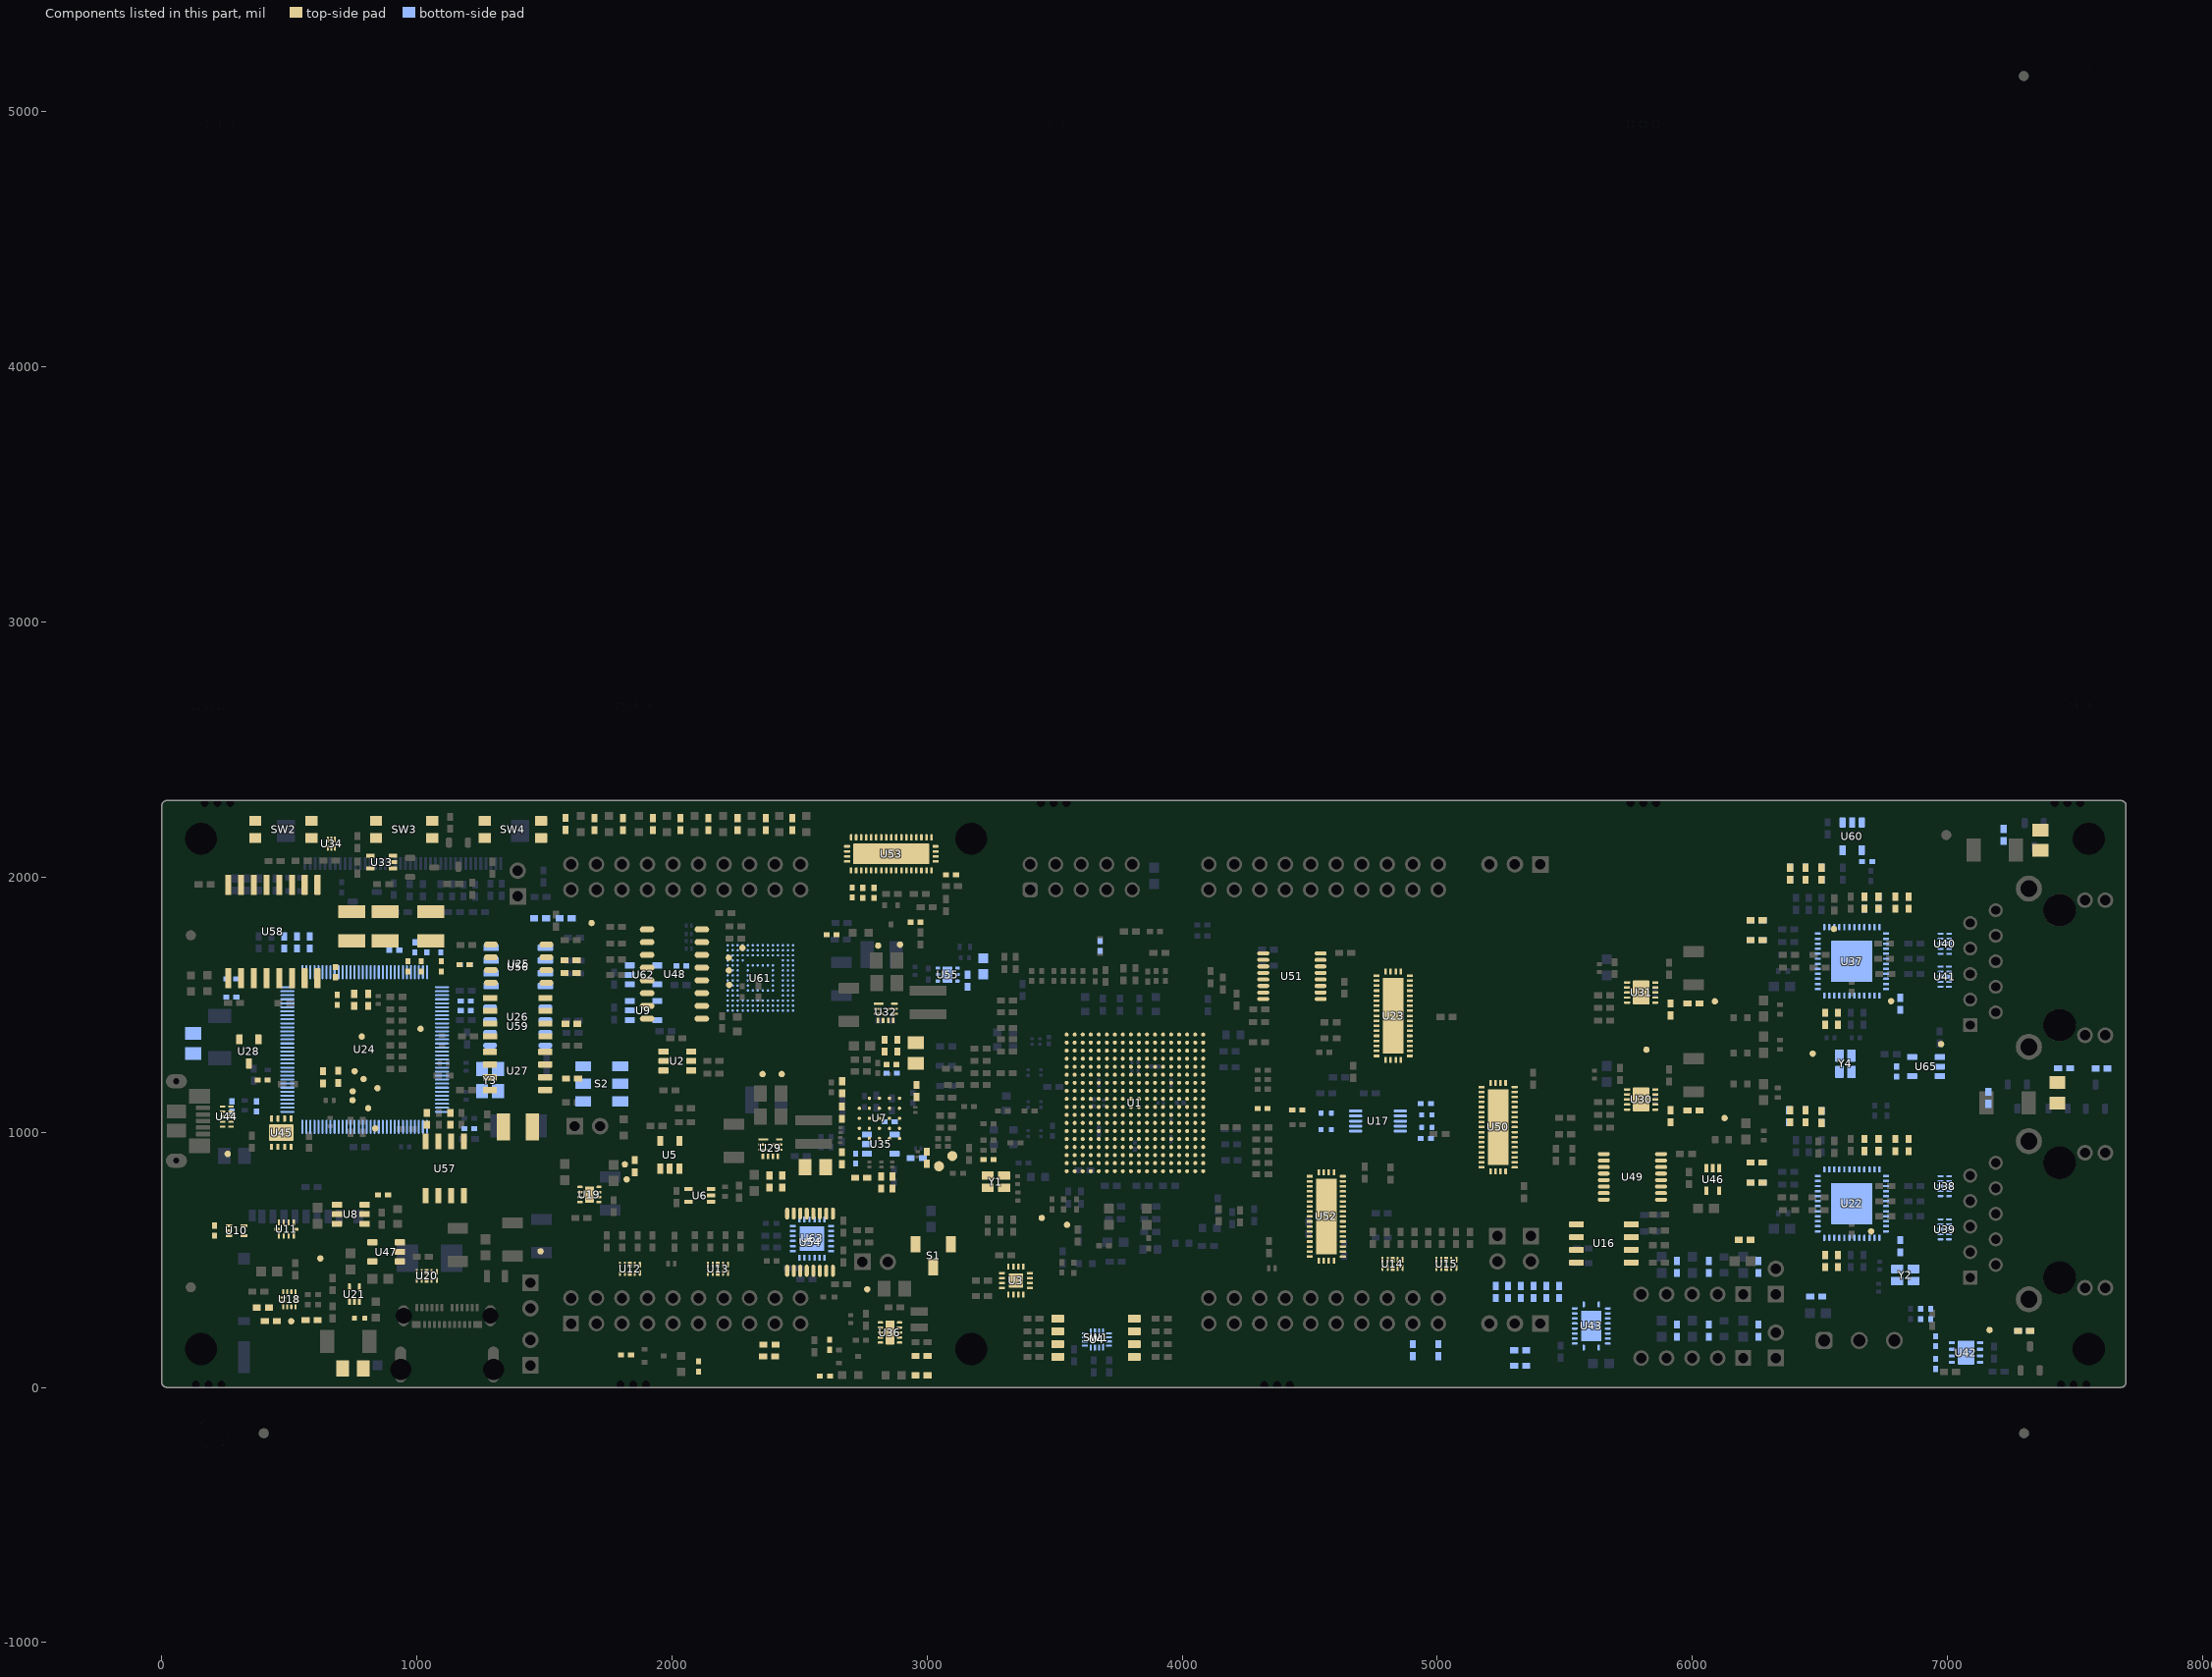
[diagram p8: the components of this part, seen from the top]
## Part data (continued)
R31 R39 R40 R41 R143 R244 R250 R375 R383 R384 R385 R386 R387 R388 R418 R421 R425 R435: library part CMP-0025958-3, "RES, 10.0 k, 1%, 0.063 W, AEC-Q200 Grade 0, 0402", Manufacturer=Vishay-Dale, Power_W=63mW, Supplier Part Number 1=541-10.0KLCT-ND, TempCo="100 ppm/C", Tolerance_%=1%, Value2=0.063W, Value_Code=10k0, ValueDisplayed=10.0k
R32 R253: library part CMP-0020616-3, "RES, 0, 5%, 0.125 W, AEC-Q200 Grade 0, 0805", Manufacturer=Panasonic, Power_W=125mW, Supplier Part Number 1=P0.0ACT-ND, TempCo="600 ppm/C", Tolerance_%=5%, Value2=0.125W, Value_Code=0000, ValueDisplayed=0
R55 R56 R95 R175 R176 R191 R192 R372 R399 R400 R407 R408: library part CMP-0026938-5, "RES, 4.7 k, 5%, 0.063 W, AEC-Q200 Grade 0, 0402", Manufacturer=Vishay-Dale, Power_W=63mW, Supplier Part Number 1=541-4.7KJCT-ND, TempCo="200 ppm/C", Tolerance_%=5%, Value2=0.063W, Value_Code=4k70, ValueDisplayed=4.7k
R61 R62 R71 R72: library part CMP-0026696-1, "RES, 33.0, 1%, 0.1 W, 0402", Manufacturer=Panasonic, Power_W=100mW, Supplier Part Number 1=P33.0LCT-ND, TempCo="100 ppm/C", Tolerance_%=1%, Value2=0.1W, Value_Code=33R0, ValueDisplayed=33.0
R63 R64 R73 R74: library part CMP-0042990-1, "Res Thick Film 0402 1.5K Ohm 5% 1/10W ±200ppm/°C Molded SMD Punched Carrier T/R", Digikey Part Number=P1.5KJCT-ND, Manufacturer=Panasonic, Mouser Part Number=667-ERJ-2GEJ152X, Octopart Part Number=cecc048b4d5c110b, Operating Temperature Range="-55°C to +155°C", Power_W=100mW, TempCo=200ppm/°C, Tolerance_%=5%, Voltage=50V
R91: library part CMP-0026873-2, "RES, 200 k, 5%, 0.063 W, AEC-Q200 Grade 0, 0402", Manufacturer=Vishay-Dale, Power_W=63mW, Supplier Part Number 1=541-200KJCT-ND, TempCo="200 ppm/C", Tolerance_%=5%, Value2=0.063W, Value_Code=200k
R94: library part CMP-0026603-2, "RES, 909 k, 1%, 0.063 W, AEC-Q200 Grade 0, 0402", Manufacturer=Vishay-Dale, Power_W=63mW, Supplier Part Number 1=541-909KLCT-ND, TempCo="100 ppm/C", Tolerance_%=1%, Value2=0.063W, Value_Code=909k
R107 R202: library part CMP-0082348-1, "RES, 11.5 k, 1%, 0.1 W, AEC-Q200 Grade 0, 0402", Manufacturer=Panasonic, Power_W=100mW, TempCo="100 ppm/C", Tolerance_%=1%, Value2=0.1W, Value_Code=11k5, ValueDisplayed=11.5k
R108 R109 R110 R111 R112 R113 R114 R115 R116 R120 R121 R122 R123 R124 R125 R126 R127 R128 R153 R203 R204 R205 R206 R207 R208 R209 R210 R211 R215 R216 R217 R218 R219 R220 R221 R222 R223: library part CMP-0026237-2, "RES, 2.49 k, 1%, 0.063 W, AEC-Q200 Grade 0, 0402", Manufacturer=Vishay-Dale, Power_W=63mW, Supplier Part Number 1=541-2.49KLCT-ND, TempCo="100 ppm/C", Tolerance_%=1%, Value2=0.063W, Value_Code=2k49, ValueDisplayed=2.49k
R132: library part CMP-0026993-2, "RES, 100, 5%, 0.1 W, AEC-Q200 Grade 0, 0402", Manufacturer=Panasonic, Power_W=100mW, Supplier Part Number 1=P100JCT-ND, TempCo="200 ppm/C", Tolerance_%=5%, Value2=0.1W, Value_Code=100R, ValueDisplayed=100
R133 R134 R135 R324 R325 R326 R327 R328 R329 R330 R331 R332 R333 R334 R335: library part CMP-0026299-2, "RES, 33.2, 1%, 0.063 W, AEC-Q200 Grade 0, 0402", Manufacturer=Vishay-Dale, Power_W=63mW, Supplier Part Number 1=541-33.2LCT-ND, TempCo="100 ppm/C", Tolerance_%=1%, Value2=0.063W, Value_Code=33R2, ValueDisplayed=33.2
R136 R137: library part CMP-0078210-2, "RES, 330 k, 1%, 0.063 W, AEC-Q200 Grade 0, 0402", Manufacturer=Vishay-Dale, Power_W=63mW, Supplier Part Number 1=541-330KLCT-ND, TempCo="100 ppm/C", Tolerance_%=1%, Value2=0.063W, Value_Code=330k
R138 R139 R140 R141 R144 R261 R308 R309 R310 R311 R312: library part CMP-0026071-3, "RES, 1.00 k, 1%, 0.063 W, AEC-Q200 Grade 0, 0402", Manufacturer=Vishay-Dale, Power_W=63mW, Supplier Part Number 1=541-1.00KLCT-ND, TempCo="100 ppm/C", Tolerance_%=1%, Value2=0.063W, Value_Code=1k00, ValueDisplayed=1.00k
R142: library part CMP-0026404-2, "RES, 49.9, 1%, 0.063 W, AEC-Q200 Grade 0, 0402", Manufacturer=Vishay-Dale, Power_W=63mW, Supplier Part Number 1=541-49.9LCT-ND, TempCo="100 ppm/C", Tolerance_%=1%, Value2=0.063W, Value_Code=49R9, ValueDisplayed=49.9
R145: library part CMP-0026413-2, "RES, 4.87 k, 1%, 0.063 W, AEC-Q200 Grade 0, 0402", Manufacturer=Vishay-Dale, Power_W=63mW, Supplier Part Number 1=541-4.87KLCT-ND, TempCo="100 ppm/C", Tolerance_%=1%, Value2=0.063W, Value_Code=4k87, ValueDisplayed=4.87k
R148 R160: library part CMP-0021602-3, "RES, 18.2 k, 1%, 0.125 W, AEC-Q200 Grade 0, 0805", Manufacturer=Panasonic, Power_W=125mW, Supplier Part Number 1=P18.2KCCT-ND, TempCo="100 ppm/C", Tolerance_%=1%, Value2=0.125W, Value_Code=18k2, ValueDisplayed=18.2k
R151: library part CMP-0026336-2, "RES, 3.57 k, 1%, 0.063 W, AEC-Q200 Grade 0, 0402", Manufacturer=Vishay-Dale, Power_W=63mW, Supplier Part Number 1=541-3.57KLCT-ND, TempCo="100 ppm/C", Tolerance_%=1%, Value2=0.063W, Value_Code=3k57, ValueDisplayed=3.57k
R152: library part CMP-0026093-3, "RES, 1.69 k, 1%, 0.063 W, AEC-Q200 Grade 0, 0402", Manufacturer=Vishay-Dale, Power_W=63mW, Supplier Part Number 1=541-1.69KLCT-ND, TempCo="100 ppm/C", Tolerance_%=1%, Value2=0.063W, Value_Code=1k69, ValueDisplayed=1.69k
R154 R161 R163: library part CMP-0026414-2, "RES, 4.99 k, 1%, 0.063 W, AEC-Q200 Grade 0, 0402", Manufacturer=Vishay-Dale, Power_W=63mW, Supplier Part Number 1=541-4.99KLCT-ND, TempCo="100 ppm/C", Tolerance_%=1%, Value2=0.063W, Value_Code=4k99, ValueDisplayed=4.99k
R159: library part CMP-0026097-2, "RES, 1.87 k, 1%, 0.063 W, AEC-Q200 Grade 0, 0402", Manufacturer=Vishay-Dale, Power_W=63mW, Supplier Part Number 1=541-1.87KLCT-ND, TempCo="100 ppm/C", Tolerance_%=1%, Value2=0.063W, Value_Code=1k87, ValueDisplayed=1.87k
R162: library part CMP-0026028-3, "RES, 15.4 k, 1%, 0.063 W, AEC-Q200 Grade 0, 0402", Manufacturer=Vishay-Dale, Power_W=63mW, Supplier Part Number 1=541-15.4KLCT-ND, TempCo="100 ppm/C", Tolerance_%=1%, Value2=0.063W, Value_Code=15k4, ValueDisplayed=15.4k
R195 R438: library part CMP-0026659-2, "RES, 100 k, 1%, 0.1 W, 0402", Manufacturer=Panasonic, Power_W=100mW, TempCo="100 ppm/C", Tolerance_%=1%, Value2=0.1W, Value_Code=100k
R224 R226 R228 R230 R232 R234: library part CMP-0026878-3, "RES, 220, 5%, 0.063 W, AEC-Q200 Grade 0, 0402", Manufacturer=Vishay-Dale, Power_W=63mW, Supplier Part Number 1=541-220JCT-ND, TempCo="200 ppm/C", Tolerance_%=5%, Value2=0.063W, Value_Code=220R, ValueDisplayed=220
R236 R237 R238 R239 R240 R241 R242 R243 R367 R368 R369 R370 R371 R373 R374: library part CMP-0026702-1, "RES, 49.9 k, 1%, 0.1 W, AEC-Q200 Grade 0, 0402", Manufacturer=Panasonic, Power_W=100mW, Supplier Part Number 1=P49.9KLCT-ND, TempCo="100 ppm/C", Tolerance_%=1%, Value2=0.1W, Value_Code=49k9, ValueDisplayed=49.9k
R246 R247: library part CMP-0026491-2, "RES, 61.9, 1%, 0.063 W, AEC-Q200 Grade 0, 0402", Manufacturer=Vishay-Dale, Power_W=63mW, Supplier Part Number 1=541-61.9LCT-ND, TempCo="100 ppm/C", Tolerance_%=1%, Value2=0.063W, Value_Code=61R9, ValueDisplayed=61.9
R251: library part CMP-0026437-2, "RES, 51.1 k, 1%, 0.063 W, AEC-Q200 Grade 0, 0402", Manufacturer=Vishay-Dale, Power_W=63mW, Supplier Part Number 1=541-51.1KLCT-ND, TempCo="100 ppm/C", Tolerance_%=1%, Value2=0.063W, Value_Code=51k1, ValueDisplayed=51.1k
R252: library part CMP-0078244-2, "RES, 30.0 k, 1%, 0.063 W, AEC-Q200 Grade 0, 0402", Manufacturer=Vishay-Dale, Power_W=63mW, Supplier Part Number 1=541-30.0KLCT-ND, TempCo="100 ppm/C", Tolerance_%=1%, Value2=0.063W, Value_Code=30k0, ValueDisplayed=30.0k
R254 R255: library part CMP-0021522-3, "RES, 1.00 M, 1%, 0.125 W, AEC-Q200 Grade 0, 0805", Manufacturer=Panasonic, Power_W=125mW, Supplier Part Number 1=P1.00MCCT-ND, TempCo="100 ppm/C", Tolerance_%=1%, Value2=0.125W, Value_Code=1M00, ValueDisplayed=1.00M
R257: library part CMP-0026704-1, "RES, 510, 1%, 0.1 W, 0402", Manufacturer=Panasonic, Power_W=100mW, Supplier Part Number 1=P510LCT-ND, TempCo="100 ppm/C", Tolerance_%=1%, Value2=0.1W, Value_Code=510R, ValueDisplayed=510
R259 R260 R265 R302 R314: library part CMP-0078194-1, "RES, 360, 5%, 0.1 W, AEC-Q200 Grade 0, 0402", Manufacturer=Panasonic, Power_W=100mW, Supplier Part Number 1=P360JCT-ND, TempCo="200 ppm/C", Tolerance_%=5%, Value2=0.1W, Value_Code=360R, ValueDisplayed=360
R262 R263 R264 R266 R267 R273 R277 R279: library part CMP-0026680-1, "RES, 220, 1%, 0.1 W, AEC-Q200 Grade 0, 0402", Manufacturer=Panasonic, Power_W=100mW, Supplier Part Number 1=P220LCT-ND, TempCo="100 ppm/C", Tolerance_%=1%, Value2=0.1W, Value_Code=220R, ValueDisplayed=220
R272 R303 R317: library part CMP-0078212-1, "RES, 510, 5%, 0.1 W, AEC-Q200 Grade 0, 0402", Manufacturer=Panasonic, Power_W=100mW, Supplier Part Number 1=P510JCT-ND, TempCo="200 ppm/C", Tolerance_%=5%, Value2=0.1W, Value_Code=510R, ValueDisplayed=510
R313 R315: library part CMP-0025998-3, "RES, 130, 1%, 0.063 W, AEC-Q200 Grade 0, 0402", Manufacturer=Vishay-Dale, Power_W=63mW, Supplier Part Number 1=541-130LCT-ND, TempCo="100 ppm/C", Tolerance_%=1%, Value2=0.063W, Value_Code=130R, ValueDisplayed=130
R362: library part CMP-0023078-5, "RES, 3.16 k, 1%, 0.1 W, 0603", Manufacturer=Yageo, Power_W=100mW, Supplier Part Number 1=311-3.16KHRCT-ND, TempCo="100 ppm/C", Tolerance_%=1%, Value2=0.1W, Value_Code=3k16, ValueDisplayed=3.16k
R363: library part CMP-0026088-3, "RES, 1.50 k, 1%, 0.063 W, AEC-Q200 Grade 0, 0402", Manufacturer=Vishay-Dale, Power_W=63mW, Supplier Part Number 1=541-1.50KLCT-ND, TempCo="100 ppm/C", Tolerance_%=1%, Value2=0.063W, Value_Code=1k50, ValueDisplayed=1.50k
R406 R410 R412 R415: library part CMP-0015017-3, "RES, 0, 1%, 0.75 W, AEC-Q200 Grade 0, 1210", Manufacturer=Vishay-Dale, Power_W=750mW, Supplier Part Number 1=541-0.0NCT-ND, TempCo=ppm/C, Tolerance_%=1%, Value2=0.75W, Value_Code=0
R434: library part CMP-0093717-1, "620 Ohms ±0.1% 0.063W, 1/16W Chip Resistor 0402 (1005 Metric) Automotive AEC-Q200 Thin Film", Digikey Part Number=P620CNCT-ND, Manufacturer=Panasonic, Mouser Part Number=667-ERA-2APB621X, Operating Temperature Range="-55°C to +155°C", Power_W=63mW, TempCo=15ppm/°C, Tolerance_%=0.1%
S1: library part CMP-0002139-2, "Switch, Slide, SPDT  100mA, SMT", CurrentRating_mA=100A, Manufacturer="Copal Electronics", Supplier Part Number 1=CAS120JCT-ND
S2: library part CMP-0002233-1, "Switch, Dual SPDT,  2 Pos, 0.1A, 6VDC, SMD", CurrentRating_mA=100A, Manufacturer="Copal Electronics", Supplier Part Number 1=CASD20JCT-ND
SW1: library part CMP-0093176-1, "Dip Switch SPST 4 Position Surface Mount Slide (Standard) Actuator 25mA 24VDC", Coil Resistance_ohm=100mΩ, Contact Current Rating=25mA, Digikey Part Number=732-3854-1-ND, Manufacturer=Wurth, Mouser Part Number=710-416131160804, Operating Temperature Range="-40°C to +85°C"
SW2 SW3 SW4: library part CMP-0093456-1, "Tactile Switch SPST-NO Side Actuated Surface Mount, Right Angle", Coil Resistance_ohm=100mΩ, Contact Current Rating=50mA, Digikey Part Number=732-7057-1-ND, Manufacturer="Wurth Electronics", Mouser Part Number=710-434351045816, Operating Force=160gf, Operating Temperature Range="-40°C to +85°C"
TP1 TP2: library part CMP-0003825-1, "1mm Test Point, SMT", Manufacturer=Any
TP3 TP4 TP5 TP6 TP7 TP8 TP9 TP10 TP11 TP12 TP13 TP14 TP15 TP16 TP17 TP18 TP19 TP20 TP21 TP22 TP23 TP24 TP25 TP26 TP27 TP28 TP29 TP30 TP31 TP32 TP33 TP34 TP35 TP36 TP37 TP38: library part CMP-0078143-3, "TEST POINT.  No entry in BOM.", Manufacturer=N/A
U1: library part CMP-0001698-2, "Sitara™ Microcontroller", Frequency_Fixed=200MHz, Manufacturer="Texas Instruments", Max Supply Voltage=3.465V, Min Supply Voltage=1.14V, Operating Temperature Range=to
U2: library part CMP-0051219-1, "Single 3-Input Positive-AND Gate, DBV0006A, LARGE T&R", F @ Nom Voltage(Max)(Mhz)=150, Generic Part Number=SN74LVC1G11, ICC @ Nom Voltage(Max)(mA)=0.01, Manufacturer="Texas Instruments", Operating Temperature Range(C)="-40 to 125,-40 to 85", Rating=Catalog, tpd @ Nom Voltage(Max)(ns)=20,7.8,6.2,4.6, Voltage(Nom)(V)=1.8,2.5,3.3,5
U3: library part CMP-0043157-2, "Low-Voltage 8-Bit I2C and SMBus I/O Expander, 1.65 to 5.5 V, -40 to 85 degC, 16-pin QFN (RGT), Green (RoHS & no Sb/Br)", 5V Tolerant I/O=Yes, Manufacturer="Texas Instruments", Max Frequency(kHz)=400
U4: library part CMP-0066450-2, "4-Bit Dual-Supply Bus Transceiver with Configurable Voltage-Level Shifting and 3-State Outputs, RSV0016A (UQFN-16)", Alternate Manufacturer="Texas Instruments"
U5 U9 U35 U47 U60 U62 U65: library part CMP-0051588-2, "Single 2-Input Positive-AND Gate, DBV0005A, LARGE T&R", Alternate Manufacturer="Texas Instruments", F @ Nom Voltage(Max)(Mhz)=150, Generic Part Number=SN74LVC1G08, ICC @ Nom Voltage(Max)(mA)=0.01, Operating Temperature Range(C)="-40 to 125,-40 to 85", Rating=Catalog, tpd @ Nom Voltage(Max)(ns)=4.5,6,4,5, Voltage(Nom)(V)=1.8,2.5,3.3,5
U6: library part CMP-0051704-3, "Single Schmitt-Trigger Buffer, DCK0005A, LARGE T&R", F @ Nom Voltage(Max)(Mhz)=150, Generic Part Number=SN74LVC1G17, ICC @ Nom Voltage(Max)(mA)=0.01, Manufacturer="Texas Instruments", Operating Temperature Range(C)="-40 to 125,-40 to 85", Rating=Catalog, tpd @ Nom Voltage(Max)(ns)=11,6.5,5.5,5, Voltage(Nom)(V)=1.8,2.5,3.3,5
U7: library part CMP-0125522-1, "FLASH Memory IC 256Mbit SPI - Octal I/O 133 MHz 6 ns 24-TFBGA (6x8)", Digikey Part Number=706-IS25LX256-JHLE-ND, Frequency_Fixed=133MHz, Manufacturer=ISSI, Max Supply Voltage=3.6V, Min Supply Voltage=2.7V, Mouser Part Number=870-IS25LX256-JHLE, Nominal Supply Current=0.13-48mA, Operating Temperature Range="-40°C to +105°C"
U8: library part CMP-0081995-1, "5.5V, 2A, 52mΩ Automotive High-Side Load Switch with Adjustable Rise Time & Quick Output Discharge, DBV0006A (SOT-23-6)", Alternate Manufacturer="Texas Instruments", Alternate PartNumber=TPS22918TDBVRQ1, Operating Temperature Range="-40 to 105 C", Rating=Automotive
U10: library part CMP-0043096-2, "Low-Capacitance + / - 15 kV ESD-Protection Array for High-Speed Data Interfaces, 2 Channels, -40 to +85 degC, 5-pin SOT (DRL), Green (RoHS & no Sb/Br)", Breakdown Voltage(Min)(V)=11, IO Capacitance(Typ)(pF)=1.5, IO Leakage Current(nA)=1, Manufacturer="Texas Instruments"
U11: library part CMP-0043123-1, "Low-Capacitance + / - 15 kV ESD Protection Array for High-Speed Data Interfaces, 6 Channels, -40 to +85 degC, 10-pin UQFN (RSE), Green (RoHS & no Sb/Br)", Breakdown Voltage(Min)(V)=11, IO Capacitance(Typ)(pF)=1.5, IO Leakage Current(nA)=1, Manufacturer="Texas Instruments"
U12 U13 U14 U15 U20 U44: library part CMP-0073612-3, "4-Channel ESD Protection Diode for USB Type-C and HDMI 2.0, DQA0010A (USON-10)", Alternate Manufacturer="Texas Instruments"
U16: library part CMP-0005327-2, "1024-Kb I2C CMOS Serial EEPROM, SOIC-8", Manufacturer="ON Semiconductor", Supplier Part Number 1=CAT24M01WI-GT3OSTR-ND
U17: library part CMP-0067419-2, "2-Channel, 2:1 Analog Switch with Low On-State Resistance (1ohm) and Powered Off Protection, DGS0010A (VSSOP-10)", Alternate Manufacturer="Texas Instruments", Alternate PartNumber=TS5A23159DGST, Operating Temperature Range="-40 to 85 C", Rating=Catalog
U18: library part CMP-0073635-2, "USB Type-C Configuration Channel Logic and Port Control, RWB0012A (X2QFN-12)", Alternate Manufacturer="Texas Instruments", Operating Temperature Range="-40 to 85 C", Rating=Catalog
U19: library part CMP-0073678-3, "5.5V, 4A, 16mΩ Automotive Load Switch With Adjustable Rise Time and Optional Quick Output Discharge, DSG0008B (WSON-8)", Alternate Manufacturer="Texas Instruments", Alternate PartNumber=TPS22965TDSGTQ1
U21: library part CMP-0051530-2, "Single 2-Input Positive-NOR Gate, DRL0005A, LARGE T&R", Alternate Manufacturer="Texas Instruments", F @ Nom Voltage(Max)(Mhz)=75, Generic Part Number=SN74AHC1G02, ICC @ Nom Voltage(Max)(mA)=0.01, Operating Temperature Range(C)="-40 to 125,-40 to 85", Rating=Catalog, tpd @ Nom Voltage(Max)(ns)=11.4,7.5, Voltage(Nom)(V)=3.3,5
U22 U37: library part CMP-0091377-1, "1/1 Transceiver Ethernet 48-VQFN (7x7)", Digikey Part Number=296-53377-1-ND, Manufacturer="Texas Instruments", Max Supply Voltage=3.45V, Min Supply Voltage=990mV, Mouser Part Number=595-DP83869HMRGZT, Operating Temperature Range="-40°C to +125°C"
U23 U50 U52 U53: library part CMP-0093539-2, "IC MUX/DEMUX DDR3 1:2 42WQFN", Digikey Part Number=296-28307-1-ND, Manufacturer="Texas Instruments", Max Supply Voltage=3.6V, Min Supply Voltage=3V, Mouser Part Number=595-TS3DDR3812RUAR, Nominal Supply Current=300uA, On State Resistance=8Ω, Operating Temperature Range="-40°C to +85°C"
U24: library part CMP-0029856-2, "Tiva C Series Microcontroller, 1024 KB Flash, 256 KB SRAM, 12 Bit, 20 Channels, -40 to 105 degC, 128-Pin TQFP (PDT), Green (RoHS & no Sb/Br), Tray", Manufacturer="Texas Instruments", Temperature Range="-40 to 105 degC"
U25 U59: library part CMP-0029369-1, "25 Mbps Dual Channels, 2 / 0, Digital Isolator, 3.3 V / 5 V, -40 to +125 degC, 8-pin SOIC (D), Green (RoHS & no Sb/Br)", Insulation Rating(VRMS)=2500, Manufacturer="Texas Instruments", Rating=Catalog, Supply Voltage(s)(V)="3.3, 5"
U26 U27: library part CMP-0076059-2, "High Speed, Robust EMC Dual-Channel Digital Isolator, D0008B (SOIC-8)", Alternate Manufacturer="Texas Instruments", Alternate PartNumber=ISO7721D, Operating Temperature Range="-55 to 125 C", Rating=Catalog
U28: library part CMP-0033001-1, "Precision Micropower Shunt Voltage Reference, 0.5% accuracy, 2.5 V, 15 ppm / degC, 15 mA, -40 to 125 degC, 3-pin SOT-23 (DBZ), Green (RoHS & no Sb/Br)", Manufacturer="Texas Instruments", Rating=Catalog, Temp Coeff(Max)(ppm/ degree C)=100, Temp Coeff(Typ)(ppm/ degree C)=15
U29 U32: library part CMP-0089785-1, "3V to 17V, 3A Micro Noise (20µVRMS) and Micro Ripple (200µVPP) buck converter", Manufacturer="Texas Instruments", Max Supply Voltage=17V, Min Supply Voltage=3V, Nominal Supply Current=5mA, Operating Temperature Range="-40°C to +150°C", Output Voltage=0.8-5.5V, Switching Frequency=1/2.2MHz
U30 U31: library part CMP-0036365-5, "Single Output LDO, 1.5A, Adj. (0.8 to 3.6V), Programmable Soft-Start, DRC0010J (VSON-10)", Manufacturer="Texas Instruments", Operating Temperature Range="-40 to 125 C", Power Good=TRUE, Rating=Catalog
U33: library part CMP-0051392-2, "Single Buffer/Driver With Open-Drain Output, DCK0005A, SMALL T&R", F @ Nom Voltage(Max)(Mhz)=150, Generic Part Number=SN74LVC1G07, ICC @ Nom Voltage(Max)(mA)=0.01, Manufacturer="Texas Instruments", Operating Temperature Range(C)="-40 to 125,-40 to 85", Rating=Catalog, tpd @ Nom Voltage(Max)(ns)=8.6,6,4.7,4, Voltage(Nom)(V)=1.8,2.5,3.3,5
U34: library part CMP-0051904-4, "Dual Schmitt-Trigger Buffer, DSF0006A, LARGE T&R", F @ Nom Voltage(Max)(Mhz)=150, Generic Part Number=SN74LVC2G17, ICC @ Nom Voltage(Max)(mA)=0.01, Manufacturer="Texas Instruments", Operating Temperature Range(C)="-40 to 125,-40 to 85", Rating=Catalog, tpd @ Nom Voltage(Max)(ns)=9.3,5.7,5.4,4.3, Voltage(Nom)(V)=1.8,2.5,3.3,5
U36: library part CMP-0067107-3, "28V, 0.5A Step-Down Converter with SNOOZE Mode, DQC0010A (WSON-10)", Alternate Manufacturer="Texas Instruments", Alternate PartNumber=TPS62177DQCT
U38 U39 U40 U41: library part CMP-0073613-3, "4-Channel Ultra-Low-Capacitance IEC ESD Protection Diode, DQA0010A (USON-10)", Alternate Manufacturer="Texas Instruments"
U42: library part CMP-0079884-2, "Automotive High Speed CAN Transceiver, DRB0008J (VSON-8)", Alternate Manufacturer="Texas Instruments", Alternate PartNumber=TCAN1044VDRBRQ1
U43: library part CMP-0074359-2, "8-Bit Bidirectional Voltage-Level Shifter with Auto Direction Sensing and +/-15-kV ESD Protect, RGY0020A (VQFN-20)", Alternate Manufacturer="Texas Instruments"
U45: library part CMP-0036402-3, "Single Output High PSRR LDO, 1 A, Adjustable 1.2 to 5.5 V Output, 2.7 to 5.5 V Input, 8-pin SON (DRB), -40 to 125 degC, Green (RoHS & no Sb/Br)", Manufacturer="Texas Instruments"
U46: library part CMP-0051684-3, "Single Inverter, DCK0005A, LARGE T&R", F @ Nom Voltage(Max)(Mhz)=150, Generic Part Number=SN74LVC1G04, ICC @ Nom Voltage(Max)(mA)=0.01, Manufacturer="Texas Instruments", Operating Temperature Range(C)="-40 to 125,-40 to 85", Rating=Catalog, tpd @ Nom Voltage(Max)(ns)=7.5,5.2,4.2,3.7, Voltage(Nom)(V)=1.8,2.5,3.3,5
U48: library part CMP-0044782-1, "8-Bit LED Driver with I2C Interface, D0016A, TUBE", Generic Part Number=TPIC2810, Manufacturer="Texas Instruments", Operating Temperature Range(C)="-40 to 125", Rating=Catalog
U49 U51 U54: library part CMP-0076540-1, "4-Bit One-of-2 FET Multiplexer/Demultiplexer 2.5-V/3.3-V Low-Voltage, High-Bandwidth Bus Switch, PW0016A (TSSOP-16)", Alternate Manufacturer="Texas Instruments"
U55: library part CMP-0084398-1, "500-mA LDO, DRV0006A (WSON-6)", Alternate Manufacturer="Texas Instruments", Alternate PartNumber=TLV75801PDRVT, Operating Temperature Range="-40 to 125 C", Rating=Catalog
U56 U57: library part CMP-0031336-1, "Hot-swappable, robust-EMC bidirectional I2C isolator with unidirectional clock 8-SOIC -40 to 125", Digikey Part Number=296-ISO1641BDRCT-ND, Manufacturer="Texas Instruments", Max Supply Voltage=5.5V, Min Supply Voltage=2.25V, Mouser Part Number=595-ISO1641BDR, Operating Temperature Range="-40°C to +125°C"
U58: library part CMP-0096103-1, "General purpose, 50-Mbps, six-channel (6/0) digital isolator 16-SOIC -40 to 125", Digikey Part Number=296-ISO6760DWRCT-ND, Manufacturer="Texas Instruments", Max Supply Voltage=5.5V, Min Supply Voltage=1.71V, Mouser Part Number=595-ISO6760DWR, Operating Temperature Range="-40°C to +125°C"
U61: library part CMP-0091989-1, "FLASH - NAND Memory IC 64Gb (8G x 8) MMC 153-TFBGA (11.5x13)", Digikey Part Number=MTFC8GAMALBH-AAT-ND, Manufacturer="Micron Technology", Max Supply Voltage=3.6V, Min Supply Voltage=2.7V, Mouser Part Number=340-349135-TRAY, Operating Temperature Range="-40°C to +105°C"
U63: library part CMP-0043175-2, "Low-Voltage 16-Bit I2C and SMBus I/O Expander, 16 Outputs, 1.65 to 5.5 V, -40 to 85 degC, 24-pin QFN (RTW), Green (RoHS & no Sb/Br)", 5V Tolerant I/O=Yes, Manufacturer="Texas Instruments", Max Frequency(kHz)=400
Y1: library part CMP-0084811-1, "Crystal, 25 MHz, 10 ppm, 4 pF, SMD", Frequency Stability="20 ppm", Frequency Tolerance="10 ppm", Frequency_Fixed=25MHz, Load Capacitance="4 pF", Manufacturer="Abracon Corporation", PartNumber=ABM10W-25.0000MHZ-8-K1Z-T3
Y2 Y4: library part CMP-0084811-1, "Crystal, 25 MHz, 10 ppm, 4 pF, SMD", Frequency_Fixed=25MHz, Frequency Stability="20 ppm", Frequency Tolerance="10 ppm", Load Capacitance="4 pF", Manufacturer="Abracon Corporation"
Y3: library part CMP-0004635-3, "Crystal, 16 MHz, 8pF, SMD", Frequency_Fixed=16MHz, Frequency Stability=+/-30ppm, Manufacturer=NDK, Supplier Part Number 1=644-1157-1-ND
ZZ1: library part CMP-0003616-3
ZZ2: library part CMP-0077236-1
ZZ3: library part CMP-0077237-1
ZZ4: library part CMP-0077238-1

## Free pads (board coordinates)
  round 65.36 on Mech16: 1(-281.58,414) 1(249.42,53) 1(1196.42,275) 1(1203.42,-873) 1(1504.42,253)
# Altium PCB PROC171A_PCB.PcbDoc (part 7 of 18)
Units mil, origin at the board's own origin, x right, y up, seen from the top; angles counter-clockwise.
Board outline 7700 x 2300 mil, 6 copper layers (Top Layer, GND 1, SIG 1, SIG 2, GND 2, Bottom Layer), stack 61.062 mil thick; 945 components, 692 nets, 11945 pads, 1734 vias.

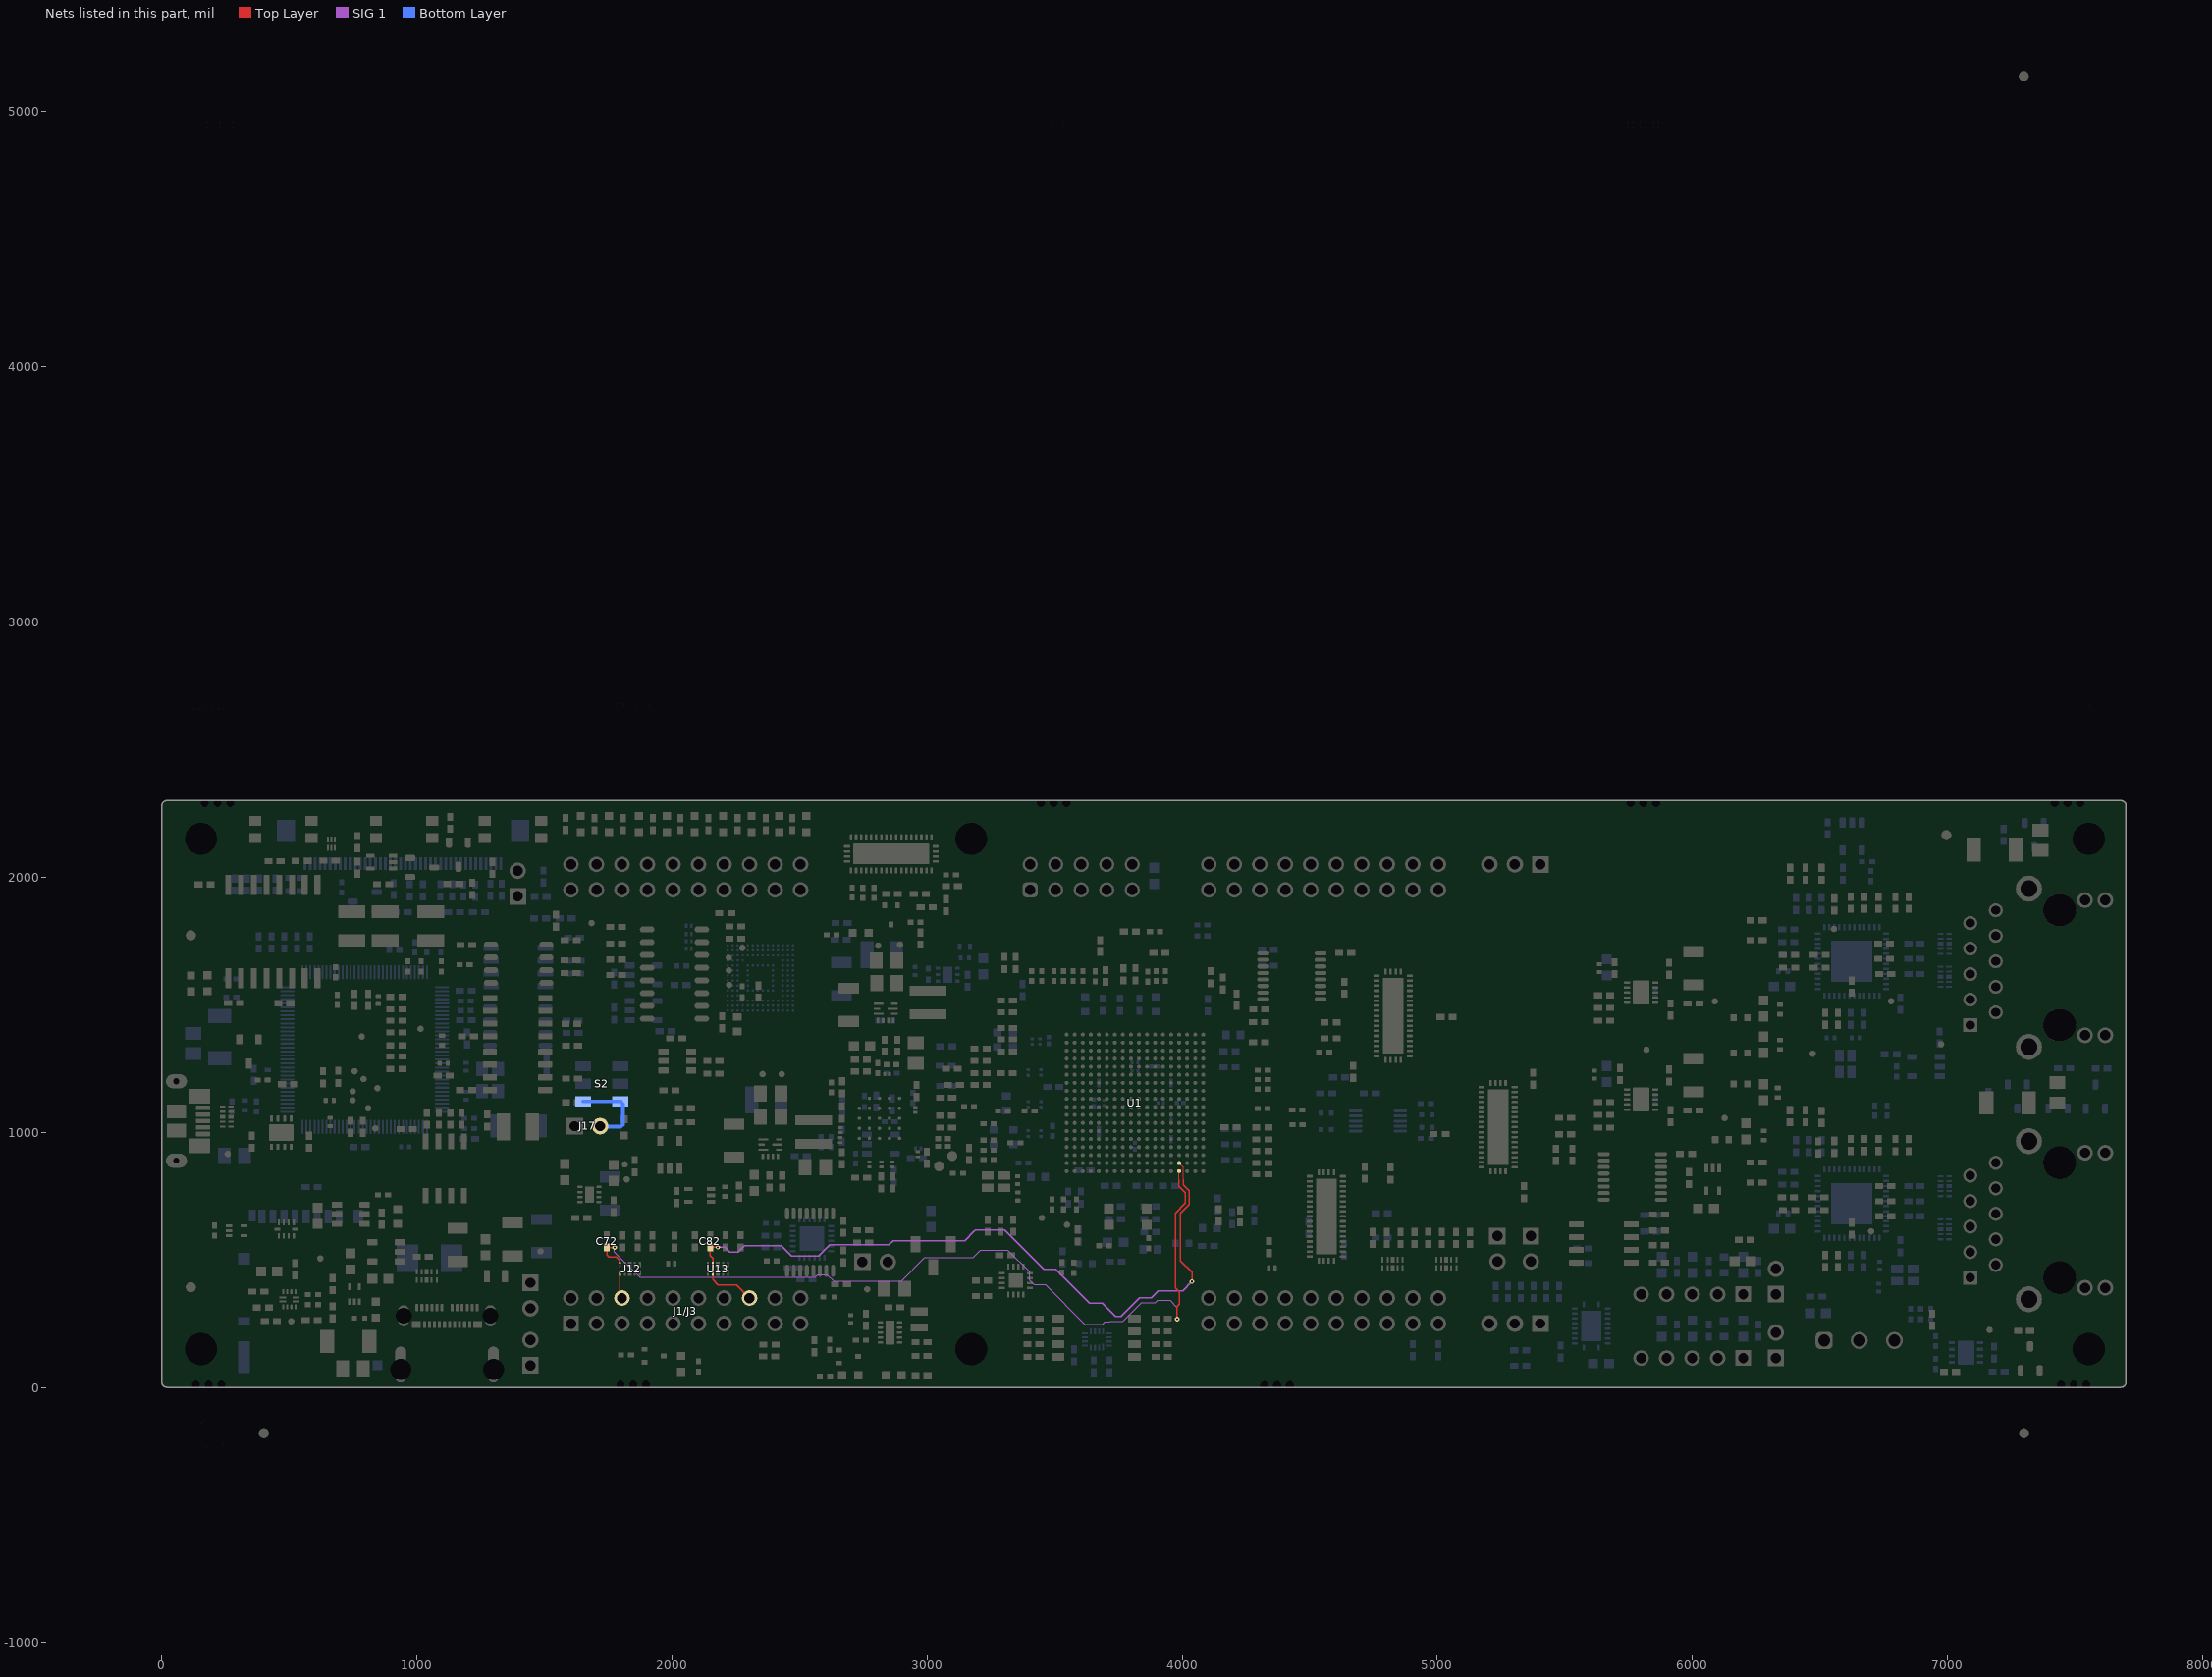
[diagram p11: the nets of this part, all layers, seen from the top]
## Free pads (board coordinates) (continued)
  round 1 on Mech16: 1(4842.79,1050) 1(4842.79,1050) 1(4842.79,1060) 1(4842.79,1060) 1(4842.79,1070) 1(4842.79,1070) 1(4843.42,1369) 1(4843.42,1369) 1(4843.42,1375) 1(4843.42,1375) 1(4843.42,1381) 1(4843.42,1381) 1(4843.58,590.78) 1(4843.58,590.78) 1(4843.58,600.78) 1(4843.58,600.78) 1(4843.58,610.78) 1(4843.58,610.78) 1(4843.58,820.79) 1(4843.58,820.79) 1(4843.58,830.79) 1(4843.58,830.79) 1(4843.58,840.79) 1(4843.58,840.79) 1(4843.79,1054) 1(4843.79,1054) 1(4843.79,1057) 1(4843.79,1057) 1(4843.79,1063) 1(4843.79,1063) 1(4843.79,1066) 1(4843.79,1066) 1(4844.17,1530) 1(4844.17,1530) 1(4844.17,1532) 1(4844.17,1532) 1(4844.17,1538) 1(4844.17,1538) 1(4844.17,1540) 1(4844.17,1540) 1(4844.17,1615) 1(4844.17,1615) 1(4844.17,1620) 1(4844.17,1620) 1(4844.17,1630) 1(4844.17,1630) 1(4844.17,1635) 1(4844.17,1635) 1(4844.32,1459.06) 1(4844.32,1459.06) 1(4844.32,1461.06) 1(4844.32,1461.06) 1(4844.32,1467.06) 1(4844.32,1467.06) 1(4844.32,1469.06) 1(4844.32,1469.06) 1(4844.58,594.78) 1(4844.58,594.78) 1(4844.58,597.78) 1(4844.58,597.78) 1(4844.58,603.78) 1(4844.58,603.78) 1(4844.58,606.78) 1(4844.58,606.78) 1(4844.58,824.79) 1(4844.58,824.79) 1(4844.58,827.79) 1(4844.58,827.79) 1(4844.58,833.79) 1(4844.58,833.79) 1(4844.58,836.79) 1(4844.58,836.79) 1(4846.42,1370) 1(4846.42,1370) 1(4846.42,1372) 1(4846.42,1372) 1(4846.42,1378) 1(4846.42,1378) 1(4846.42,1380) 1(4846.42,1380) 1(4847.17,1529) 1(4847.17,1529) 1(4847.17,1535) 1(4847.17,1535) 1(4847.17,1541) 1(4847.17,1541) 1(4847.32,1458.06) 1(4847.32,1458.06) 1(4847.32,1464.06) 1(4847.32,1464.06) 1(4847.32,1470.06) 1(4847.32,1470.06) 1(4847.79,1050) 1(4847.79,1050) 1(4847.79,1055) 1(4847.79,1055) 1(4847.79,1065) 1(4847.79,1065) 1(4847.79,1070) 1(4847.79,1070) 1(4848.17,1619) 1(4848.17,1619) 1(4848.17,1622) 1(4848.17,1622) 1(4848.17,1628) 1(4848.17,1628) 1(4848.17,1631) 1(4848.17,1631) 1(4848.58,590.78) 1(4848.58,590.78) 1(4848.58,595.78) 1(4848.58,595.78) 1(4848.58,605.78) 1(4848.58,605.78) 1(4848.58,610.78) 1(4848.58,610.78) 1(4848.58,820.79) 1(4848.58,820.79) 1(4848.58,825.79) 1(4848.58,825.79) 1(4848.58,835.79) 1(4848.58,835.79) 1(4848.58,840.79) 1(4848.58,840.79) 1(4849.17,1525) 1(4849.17,1525) 1(4849.17,1535) 1(4849.17,1535) 1(4849.17,1545) 1(4849.17,1545) 1(4849.17,1615) 1(4849.17,1615) 1(4849.17,1625) 1(4849.17,1625) 1(4849.17,1635) 1(4849.17,1635) 1(4849.32,1454.06) 1(4849.32,1454.06) 1(4849.32,1464.06) 1(4849.32,1464.06) 1(4849.32,1474.06) 1(4849.32,1474.06) 1(4849.42,1369) 1(4849.42,1369) 1(4849.42,1375) 1(4849.42,1375) 1(4849.42,1381) 1(4849.42,1381) 1(4850.17,1529) 1(4850.17,1529) 1(4850.17,1532) 1(4850.17,1532) 1(4850.17,1538) 1(4850.17,1538) 1(4850.17,1541) 1(4850.17,1541) 1(4850.32,1458.06) 1(4850.32,1458.06) 1(4850.32,1461.06) 1(4850.32,1461.06) 1(4850.32,1467.06) 1(4850.32,1467.06) 1(4850.32,1470.06) 1(4850.32,1470.06) 1(4851.17,1619) 1(4851.17,1619) 1(4851.17,1625) 1(4851.17,1625) 1(4851.17,1631) 1(4851.17,1631) 1(4851.42,1365) 1(4851.42,1365) 1(4851.42,1375) 1(4851.42,1375) 1(4851.42,1385) 1(4851.42,1385) 1(4852.42,1369) 1(4852.42,1369) 1(4852.42,1372) 1(4852.42,1372) 1(4852.42,1378) 1(4852.42,1378) 1(4852.42,1381) 1(4852.42,1381) 1(4854.17,1525) 1(4854.17,1525) 1(4854.17,1530) 1(4854.17,1530) 1(4854.17,1540) 1(4854.17,1540) 1(4854.17,1545) 1(4854.17,1545) 1(4854.17,1620) 1(4854.17,1620) 1(4854.17,1622) 1(4854.17,1622) 1(4854.17,1628) 1(4854.17,1628) 1(4854.17,1630) 1(4854.17,1630) 1(4854.32,1454.06) 1(4854.32,1454.06) 1(4854.32,1459.06) 1(4854.32,1459.06) 1(4854.32,1469.06) 1(4854.32,1469.06) 1(4854.32,1474.06) 1(4854.32,1474.06) 1(4856.42,1365) 1(4856.42,1365) 1(4856.42,1370) 1(4856.42,1370) 1(4856.42,1380) 1(4856.42,1380) 1(4856.42,1385) 1(4856.42,1385) 1(4857.17,1619) 1(4857.17,1619) 1(4857.17,1625) 1(4857.17,1625) 1(4857.17,1631) 1(4857.17,1631) 1(4859.17,1615) 1(4859.17,1615) 1(4859.17,1625) 1(4859.17,1625) 1(4859.17,1635) 1(4859.17,1635) 1(4860.17,1619) 1(4860.17,1619) 1(4860.17,1622) 1(4860.17,1622) 1(4860.17,1628) 1(4860.17,1628) 1(4860.17,1631) 1(4860.17,1631) 1(4864.17,1615) 1(4864.17,1615) 1(4864.17,1620) 1(4864.17,1620) 1(4864.17,1630) 1(4864.17,1630) 1(4864.17,1635) 1(4864.17,1635) 1(4876.02,1220) 1(4876.02,1224) 1(4876.02,1236) 1(4876.02,1240) 1(4876.02,1760) 1(4876.02,1764) 1(4876.02,1776) 1(4876.02,1780) 1(4894.17,240) 1(4894.17,240) 1(4894.17,260) 1(4894.17,260) 1(4894.17,340) 1(4894.17,340) 1(4894.17,360) 1(4894.17,360) 1(4894.17,1940) 1(4894.17,1940) 1(4894.17,1960) 1(4894.17,1960) 1(4894.17,2040) 1(4894.17,2040) 1(4894.17,2060) 1(4894.17,2060) 1(4898.17,244) 1(4898.17,244) 1(4898.17,256) 1(4898.17,256) 1(4898.17,344) 1(4898.17,344) 1(4898.17,356) 1(4898.17,356) 1(4898.17,1944) 1(4898.17,1944) 1(4898.17,1956) 1(4898.17,1956) 1(4898.17,2044) 1(4898.17,2044) 1(4898.17,2056) 1(4898.17,2056) 1(4910.17,244) 1(4910.17,244) 1(4910.17,256) 1(4910.17,256) 1(4910.17,344) 1(4910.17,344) 1(4910.17,356) 1(4910.17,356) 1(4910.17,1944) 1(4910.17,1944) 1(4910.17,1956) 1(4910.17,1956) 1(4910.17,2044) 1(4910.17,2044) 1(4910.17,2056) 1(4910.17,2056) 1(4914.17,240) 1(4914.17,240) 1(4914.17,260) 1(4914.17,260) 1(4914.17,340) 1(4914.17,340) 1(4914.17,360) 1(4914.17,360) 1(4914.17,1940) 1(4914.17,1940) 1(4914.17,1960) 1(4914.17,1960) 1(4914.17,2040) 1(4914.17,2040) 1(4914.17,2060) 1(4914.17,2060) 1(4994.17,240) 1(4994.17,240) 1(4994.17,260) 1(4994.17,260) 1(4994.17,340) 1(4994.17,340) 1(4994.17,360) 1(4994.17,360) 1(4994.17,1940) 1(4994.17,1940) 1(4994.17,1960) 1(4994.17,1960) 1(4998.17,244) 1(4998.17,244) 1(4998.17,256) 1(4998.17,256) 1(4998.17,344) 1(4998.17,344) 1(4998.17,356) 1(4998.17,356) 1(4998.17,1944) 1(4998.17,1944) 1(4998.17,1956) 1(4998.17,1956) 1(5010.17,244) 1(5010.17,244) 1(5010.17,256) 1(5010.17,256) 1(5010.17,344) 1(5010.17,344) 1(5010.17,356) 1(5010.17,356) 1(5010.17,1944) 1(5010.17,1944) 1(5010.17,1956) 1(5010.17,1956) 1(5014.17,240) 1(5014.17,240) 1(5014.17,260) 1(5014.17,260) 1(5014.17,340) 1(5014.17,340) 1(5014.17,360) 1(5014.17,360) 1(5014.17,1940) 1(5014.17,1940) 1(5014.17,1960) 1(5014.17,1960) 1(5079.17,637.95) 1(5079.17,637.95) 1(5079.17,642.95) 1(5079.17,642.95) 1(5079.17,652.95) 1(5079.17,652.95) 1(5079.17,657.95) 1(5079.17,657.95) 1(5083.17,641.95) 1(5083.17,641.95) 1(5083.17,644.95) 1(5083.17,644.95) 1(5083.17,650.95) 1(5083.17,650.95) 1(5083.17,653.95) 1(5083.17,653.95) 1(5084.17,637.95) 1(5084.17,637.95) 1(5084.17,647.95) 1(5084.17,647.95) 1(5084.17,657.95) 1(5084.17,657.95) 1(5086.17,641.95) 1(5086.17,641.95) 1(5086.17,647.95) 1(5086.17,647.95) 1(5086.17,653.95) 1(5086.17,653.95) 1(5089.17,642.95) 1(5089.17,642.95) 1(5089.17,644.95) 1(5089.17,644.95) 1(5089.17,650.95) 1(5089.17,650.95) 1(5089.17,652.95) 1(5089.17,652.95) 1(5092.17,641.95) 1(5092.17,641.95) 1(5092.17,647.95) 1(5092.17,647.95) 1(5092.17,653.95) 1(5092.17,653.95) 1(5094.17,637.95) 1(5094.17,637.95) 1(5094.17,647.95) 1(5094.17,647.95) 1(5094.17,657.95) 1(5094.17,657.95) 1(5095.17,641.95) 1(5095.17,641.95) 1(5095.17,644.95) 1(5095.17,644.95) 1(5095.17,650.95) 1(5095.17,650.95) 1(5095.17,653.95) 1(5095.17,653.95) 1(5099.17,637.95) 1(5099.17,637.95) 1(5099.17,642.95) 1(5099.17,642.95) 1(5099.17,652.95) 1(5099.17,652.95) 1(5099.17,657.95) 1(5099.17,657.95) 1(5104.17,655) 1(5104.17,655) 1(5104.17,660) 1(5104.17,660) 1(5104.17,670) 1(5104.17,670) 1(5104.17,675) 1(5104.17,675) 1(5108.17,659) 1(5108.17,659) 1(5108.17,662) 1(5108.17,662) 1(5108.17,668) 1(5108.17,668) 1(5108.17,671) 1(5108.17,671) 1(5109.17,655) 1(5109.17,655) 1(5109.17,665) 1(5109.17,665) 1(5109.17,675) 1(5109.17,675) 1(5111.17,659) 1(5111.17,659) 1(5111.17,665) 1(5111.17,665) 1(5111.17,671) 1(5111.17,671) 1(5114.17,660) 1(5114.17,660) 1(5114.17,662) 1(5114.17,662) 1(5114.17,668) 1(5114.17,668) 1(5114.17,670) 1(5114.17,670) 1(5117.17,659) 1(5117.17,659) 1(5117.17,665) 1(5117.17,665) 1(5117.17,671) 1(5117.17,671) 1(5119.17,655) 1(5119.17,655) 1(5119.17,665) 1(5119.17,665) 1(5119.17,675) 1(5119.17,675) 1(5120.17,659) 1(5120.17,659) 1(5120.17,662) 1(5120.17,662) 1(5120.17,668) 1(5120.17,668) 1(5120.17,671) 1(5120.17,671) 1(5124.17,655) 1(5124.17,655) 1(5124.17,660) 1(5124.17,660) 1(5124.17,670) 1(5124.17,670) 1(5124.17,675) 1(5124.17,675) 1(5131.17,1496) 1(5131.17,1496) 1(5131.17,1501) 1(5131.17,1501) 1(5131.17,1511) 1(5131.17,1511) 1(5131.17,1516) 1(5131.17,1516) 1(5135.17,1500) 1(5135.17,1500) 1(5135.17,1503) 1(5135.17,1503) 1(5135.17,1509) 1(5135.17,1509) 1(5135.17,1512) 1(5135.17,1512) 1(5136.17,1496) 1(5136.17,1496) 1(5136.17,1506) 1(5136.17,1506) 1(5136.17,1516) 1(5136.17,1516) 1(5138.17,1500) 1(5138.17,1500) 1(5138.17,1506) 1(5138.17,1506) 1(5138.17,1512) 1(5138.17,1512) 1(5141.17,1501) 1(5141.17,1501) 1(5141.17,1503) 1(5141.17,1503) 1(5141.17,1509) 1(5141.17,1509) 1(5141.17,1511) 1(5141.17,1511) 1(5144.17,1500) 1(5144.17,1500) 1(5144.17,1506) 1(5144.17,1506) 1(5144.17,1512) 1(5144.17,1512) 1(5146.17,1496) 1(5146.17,1496) 1(5146.17,1506) 1(5146.17,1506) 1(5146.17,1516) 1(5146.17,1516) 1(5147.17,1500) 1(5147.17,1500) 1(5147.17,1503) 1(5147.17,1503) 1(5147.17,1509) 1(5147.17,1509) 1(5147.17,1512) 1(5147.17,1512) 1(5149.17,845) 1(5149.17,845) 1(5149.17,850) 1(5149.17,850) 1(5149.17,860) 1(5149.17,860) 1(5149.17,865) 1(5149.17,865) 1(5149.17,2146.26) 1(5149.17,2146.26) 1(5149.17,2151.26) 1(5149.17,2151.26) 1(5149.17,2161.26) 1(5149.17,2161.26) 1(5149.17,2166.26) 1(5149.17,2166.26) 1(5151.17,1496) 1(5151.17,1496) 1(5151.17,1501) 1(5151.17,1501) 1(5151.17,1511) 1(5151.17,1511) 1(5151.17,1516) 1(5151.17,1516) 1(5153.17,849) 1(5153.17,849) 1(5153.17,852) 1(5153.17,852) 1(5153.17,858) 1(5153.17,858) 1(5153.17,861) 1(5153.17,861) 1(5153.17,2150.26) 1(5153.17,2150.26) 1(5153.17,2153.26) 1(5153.17,2153.26) 1(5153.17,2159.26) 1(5153.17,2159.26) 1(5153.17,2162.26) 1(5153.17,2162.26) 1(5154.17,210) 1(5154.17,210) 1(5154.17,215) 1(5154.17,215) 1(5154.17,225) 1(5154.17,225) 1(5154.17,230) 1(5154.17,230) 1(5154.17,845) 1(5154.17,845) 1(5154.17,855) 1(5154.17,855) 1(5154.17,865) 1(5154.17,865) 1(5154.17,1957.77) 1(5154.17,1957.77) 1(5154.17,1962.77) 1(5154.17,1962.77) 1(5154.17,1972.77) 1(5154.17,1972.77) 1(5154.17,1977.77) 1(5154.17,1977.77) 1(5154.17,2146.26) 1(5154.17,2146.26) 1(5154.17,2156.26) 1(5154.17,2156.26) 1(5154.17,2166.26) 1(5154.17,2166.26) 1(5156.17,849) 1(5156.17,849) 1(5156.17,855) 1(5156.17,855) 1(5156.17,861) 1(5156.17,861) 1(5156.17,2150.26) 1(5156.17,2150.26) 1(5156.17,2156.26) 1(5156.17,2156.26) 1(5156.17,2162.26) 1(5156.17,2162.26) 1(5158.17,214) 1(5158.17,214) 1(5158.17,217) 1(5158.17,217) 1(5158.17,223) 1(5158.17,223) 1(5158.17,226) 1(5158.17,226) 1(5158.17,1961.77) 1(5158.17,1961.77) 1(5158.17,1964.77) 1(5158.17,1964.77) 1(5158.17,1970.77) 1(5158.17,1970.77) 1(5158.17,1973.77) 1(5158.17,1973.77) 1(5159.17,210) 1(5159.17,210) 1(5159.17,220) 1(5159.17,220) 1(5159.17,230) 1(5159.17,230) 1(5159.17,850) 1(5159.17,850) 1(5159.17,852) 1(5159.17,852) 1(5159.17,858) 1(5159.17,858) 1(5159.17,860) 1(5159.17,860) 1(5159.17,1957.77) 1(5159.17,1957.77) 1(5159.17,1967.77) 1(5159.17,1967.77) 1(5159.17,1977.77) 1(5159.17,1977.77) 1(5159.17,2151.26) 1(5159.17,2151.26) 1(5159.17,2153.26) 1(5159.17,2153.26) 1(5159.17,2159.26) 1(5159.17,2159.26) 1(5159.17,2161.26) 1(5159.17,2161.26) 1(5161.17,214) 1(5161.17,214) 1(5161.17,220) 1(5161.17,220) 1(5161.17,226) 1(5161.17,226) 1(5161.17,1961.77) 1(5161.17,1961.77) 1(5161.17,1967.77) 1(5161.17,1967.77) 1(5161.17,1973.77) 1(5161.17,1973.77) 1(5162.17,849) 1(5162.17,849) 1(5162.17,855) 1(5162.17,855) 1(5162.17,861) 1(5162.17,861) 1(5162.17,2150.26) 1(5162.17,2150.26) 1(5162.17,2156.26) 1(5162.17,2156.26) 1(5162.17,2162.26) 1(5162.17,2162.26) 1(5164.17,215) 1(5164.17,215) 1(5164.17,217) 1(5164.17,217) 1(5164.17,223) 1(5164.17,223) 1(5164.17,225) 1(5164.17,225) 1(5164.17,845) 1(5164.17,845) 1(5164.17,855) 1(5164.17,855) 1(5164.17,865) 1(5164.17,865) 1(5164.17,1962.77) 1(5164.17,1962.77) 1(5164.17,1964.77) 1(5164.17,1964.77) 1(5164.17,1970.77) 1(5164.17,1970.77) 1(5164.17,1972.77) 1(5164.17,1972.77) 1(5164.17,2146.26) 1(5164.17,2146.26) 1(5164.17,2156.26) 1(5164.17,2156.26) 1(5164.17,2166.26) 1(5164.17,2166.26) 1(5165.17,849) 1(5165.17,849) 1(5165.17,852) 1(5165.17,852) 1(5165.17,858) 1(5165.17,858) 1(5165.17,861) 1(5165.17,861) 1(5165.17,2150.26) 1(5165.17,2150.26) 1(5165.17,2153.26) 1(5165.17,2153.26) 1(5165.17,2159.26) 1(5165.17,2159.26) 1(5165.17,2162.26) 1(5165.17,2162.26) 1(5166.17,1498) 1(5166.17,1498) 1(5166.17,1503) 1(5166.17,1503) 1(5166.17,1513) 1(5166.17,1513) 1(5166.17,1518) 1(5166.17,1518) 1(5167.17,214) 1(5167.17,214) 1(5167.17,220) 1(5167.17,220) 1(5167.17,226) 1(5167.17,226) 1(5167.17,1961.77) 1(5167.17,1961.77) 1(5167.17,1967.77) 1(5167.17,1967.77) 1(5167.17,1973.77) 1(5167.17,1973.77) 1(5167.65,1360) 1(5167.65,1360) 1(5167.65,1365) 1(5167.65,1365) 1(5167.65,1375) 1(5167.65,1375) 1(5167.65,1380) 1(5167.65,1380) 1(5169.17,210) 1(5169.17,210) 1(5169.17,220) 1(5169.17,220) 1(5169.17,230) 1(5169.17,230) 1(5169.17,845) 1(5169.17,845) 1(5169.17,850) 1(5169.17,850) 1(5169.17,860) 1(5169.17,860) 1(5169.17,865) 1(5169.17,865) 1(5169.17,1957.77) 1(5169.17,1957.77) 1(5169.17,1967.77) 1(5169.17,1967.77) 1(5169.17,1977.77) 1(5169.17,1977.77) 1(5169.17,2146.26) 1(5169.17,2146.26) 1(5169.17,2151.26) 1(5169.17,2151.26) 1(5169.17,2161.26) 1(5169.17,2161.26) 1(5169.17,2166.26) 1(5169.17,2166.26) 1(5170.17,214) 1(5170.17,214) 1(5170.17,217) 1(5170.17,217) 1(5170.17,223) 1(5170.17,223) 1(5170.17,226) 1(5170.17,226) 1(5170.17,1502) 1(5170.17,1502) 1(5170.17,1505) 1(5170.17,1505) 1(5170.17,1511) 1(5170.17,1511) 1(5170.17,1514) 1(5170.17,1514) 1(5170.17,1961.77) 1(5170.17,1961.77) 1(5170.17,1964.77) 1(5170.17,1964.77) 1(5170.17,1970.77) 1(5170.17,1970.77) 1(5170.17,1973.77) 1(5170.17,1973.77) 1(5171.17,1498) 1(5171.17,1498) 1(5171.17,1508) 1(5171.17,1508) 1(5171.17,1518) 1(5171.17,1518) 1(5171.65,1364) 1(5171.65,1364) 1(5171.65,1367) 1(5171.65,1367) 1(5171.65,1373) 1(5171.65,1373) 1(5171.65,1376) 1(5171.65,1376) 1(5172.65,1360) 1(5172.65,1360) 1(5172.65,1370) 1(5172.65,1370) 1(5172.65,1380) 1(5172.65,1380) 1(5173.17,1502) 1(5173.17,1502) 1(5173.17,1508) 1(5173.17,1508) 1(5173.17,1514) 1(5173.17,1514) 1(5174.17,210) 1(5174.17,210) 1(5174.17,215) 1(5174.17,215) 1(5174.17,225) 1(5174.17,225) 1(5174.17,230) 1(5174.17,230) 1(5174.17,863.56) 1(5174.17,863.56) 1(5174.17,868.56) 1(5174.17,868.56) 1(5174.17,878.56) 1(5174.17,878.56) 1(5174.17,883.56) 1(5174.17,883.56) 1(5174.17,1957.77) 1(5174.17,1957.77) 1(5174.17,1962.77) 1(5174.17,1962.77) 1(5174.17,1972.77) 1(5174.17,1972.77) 1(5174.17,1977.77) 1(5174.17,1977.77) 1(5174.65,1364) 1(5174.65,1364) 1(5174.65,1370) 1(5174.65,1370) 1(5174.65,1376) 1(5174.65,1376) 1(5176.17,1503) 1(5176.17,1503) 1(5176.17,1505) 1(5176.17,1505) 1(5176.17,1511) 1(5176.17,1511) 1(5176.17,1513) 1(5176.17,1513) 1(5177.65,1365) 1(5177.65,1365) 1(5177.65,1367) 1(5177.65,1367) 1(5177.65,1373) 1(5177.65,1373) 1(5177.65,1375) 1(5177.65,1375) 1(5178.17,867.56) 1(5178.17,867.56) 1(5178.17,870.56) 1(5178.17,870.56) 1(5178.17,876.56) 1(5178.17,876.56) 1(5178.17,879.56) 1(5178.17,879.56) 1(5179.17,863.56) 1(5179.17,863.56) 1(5179.17,873.56) 1(5179.17,873.56) 1(5179.17,883.56) 1(5179.17,883.56) 1(5179.17,1502) 1(5179.17,1502) 1(5179.17,1508) 1(5179.17,1508) 1(5179.17,1514) 1(5179.17,1514) 1(5180.65,1364) 1(5180.65,1364) 1(5180.65,1370) 1(5180.65,1370) 1(5180.65,1376) 1(5180.65,1376) 1(5181.17,867.56) 1(5181.17,867.56) 1(5181.17,873.56) 1(5181.17,873.56) 1(5181.17,879.56) 1(5181.17,879.56) 1(5181.17,1498) 1(5181.17,1498) 1(5181.17,1508) 1(5181.17,1508) 1(5181.17,1518) 1(5181.17,1518) 1(5182.17,-117) 1(5182.17,-117) 1(5182.17,-97) 1(5182.17,-97) 1(5182.17,1502) 1(5182.17,1502) 1(5182.17,1505) 1(5182.17,1505) 1(5182.17,1511) 1(5182.17,1511) 1(5182.17,1514) 1(5182.17,1514) 1(5182.65,1360) 1(5182.65,1360) 1(5182.65,1370) 1(5182.65,1370) 1(5182.65,1380) 1(5182.65,1380) 1(5183.65,1364) 1(5183.65,1364) 1(5183.65,1367) 1(5183.65,1367) 1(5183.65,1373) 1(5183.65,1373) 1(5183.65,1376) 1(5183.65,1376) 1(5184.17,631.96) 1(5184.17,631.96) 1(5184.17,636.96) 1(5184.17,636.96) 1(5184.17,646.96) 1(5184.17,646.96) 1(5184.17,651.96) 1(5184.17,651.96) 1(5184.17,868.56) 1(5184.17,868.56) 1(5184.17,870.56) 1(5184.17,870.56) 1(5184.17,876.56) 1(5184.17,876.56) 1(5184.17,878.56) 1(5184.17,878.56) 1(5184.17,950) 1(5184.17,950) 1(5184.17,955) 1(5184.17,955) 1(5184.17,965) 1(5184.17,965) 1(5184.17,970) 1(5184.17,970) 1(5186.17,-113) 1(5186.17,-113) 1(5186.17,-101) 1(5186.17,-101) 1(5186.17,1498) 1(5186.17,1498) 1(5186.17,1503) 1(5186.17,1503) 1(5186.17,1513) 1(5186.17,1513) 1(5186.17,1518) 1(5186.17,1518) 1(5187.17,-107) 1(5187.17,-107) 1(5187.17,867.56) 1(5187.17,867.56) 1(5187.17,873.56) 1(5187.17,873.56) 1(5187.17,879.56) 1(5187.17,879.56) 1(5187.65,1360) 1(5187.65,1360) 1(5187.65,1365) 1(5187.65,1365) 1(5187.65,1375) 1(5187.65,1375) 1(5187.65,1380) 1(5187.65,1380) 1(5188.17,635.96) 1(5188.17,635.96) 1(5188.17,638.96) 1(5188.17,638.96) 1(5188.17,644.96) 1(5188.17,644.96) 1(5188.17,647.96) 1(5188.17,647.96) 1(5188.17,954) 1(5188.17,954) 1(5188.17,957) 1(5188.17,957) 1(5188.17,963) 1(5188.17,963) 1(5188.17,966) 1(5188.17,966) 1(5189.17,-107) 1(5189.17,-107) 1(5189.17,631.96) 1(5189.17,631.96) 1(5189.17,641.96) 1(5189.17,641.96) 1(5189.17,651.96) 1(5189.17,651.96) 1(5189.17,863.56) 1(5189.17,863.56) 1(5189.17,873.56) 1(5189.17,873.56) 1(5189.17,883.56) 1(5189.17,883.56) 1(5189.17,950) 1(5189.17,950) 1(5189.17,960) 1(5189.17,960) 1(5189.17,970) 1(5189.17,970) 1(5189.17,1240) 1(5189.17,1240) 1(5189.17,1245) 1(5189.17,1245) 1(5189.17,1255) 1(5189.17,1255) 1(5189.17,1260) 1(5189.17,1260) 1(5190.17,867.56) 1(5190.17,867.56) 1(5190.17,870.56) 1(5190.17,870.56) 1(5190.17,876.56) 1(5190.17,876.56) 1(5190.17,879.56) 1(5190.17,879.56) 1(5191.17,635.96) 1(5191.17,635.96) 1(5191.17,641.96) 1(5191.17,641.96) 1(5191.17,647.96) 1(5191.17,647.96) 1(5191.17,954) 1(5191.17,954) 1(5191.17,960) 1(5191.17,960) 1(5191.17,966) 1(5191.17,966) 1(5192.17,-112) 1(5192.17,-112) 1(5192.17,-110) 1(5192.17,-110) 1(5192.17,-104) 1(5192.17,-104) 1(5192.17,-102) 1(5192.17,-102) 1(5193.17,1244) 1(5193.17,1244) 1(5193.17,1247) 1(5193.17,1247) 1(5193.17,1253) 1(5193.17,1253) 1(5193.17,1256) 1(5193.17,1256) 1(5194.17,636.96) 1(5194.17,636.96) 1(5194.17,638.96) 1(5194.17,638.96) 1(5194.17,644.96) 1(5194.17,644.96) 1(5194.17,646.96) 1(5194.17,646.96) 1(5194.17,863.56) 1(5194.17,863.56) 1(5194.17,868.56) 1(5194.17,868.56) 1(5194.17,878.56) 1(5194.17,878.56) 1(5194.17,883.56) 1(5194.17,883.56) 1(5194.17,955) 1(5194.17,955) 1(5194.17,957) 1(5194.17,957) 1(5194.17,963) 1(5194.17,963) 1(5194.17,965) 1(5194.17,965) 1(5194.17,1240) 1(5194.17,1240) 1(5194.17,1250) 1(5194.17,1250) 1(5194.17,1260) 1(5194.17,1260) 1(5195.17,-107) 1(5195.17,-107) 1(5196.17,1244) 1(5196.17,1244) 1(5196.17,1250) 1(5196.17,1250) 1(5196.17,1256) 1(5196.17,1256) 1(5197.17,-107) 1(5197.17,-107) 1(5197.17,635.96) 1(5197.17,635.96) 1(5197.17,641.96) 1(5197.17,641.96) 1(5197.17,647.96) 1(5197.17,647.96) 1(5197.17,954) 1(5197.17,954) 1(5197.17,960) 1(5197.17,960) 1(5197.17,966) 1(5197.17,966) 1(5198.17,-113) 1(5198.17,-113) 1(5198.17,-101) 1(5198.17,-101) 1(5199.17,631.96) 1(5199.17,631.96) 1(5199.17,641.96) 1(5199.17,641.96) 1(5199.17,651.96) 1(5199.17,651.96) 1(5199.17,950) 1(5199.17,950) 1(5199.17,960) 1(5199.17,960) 1(5199.17,970) 1(5199.17,970) 1(5199.17,1245) 1(5199.17,1245) 1(5199.17,1247) 1(5199.17,1247) 1(5199.17,1253) 1(5199.17,1253) 1(5199.17,1255) 1(5199.17,1255) 1(5200.17,635.96) 1(5200.17,635.96) 1(5200.17,638.96) 1(5200.17,638.96) 1(5200.17,644.96) 1(5200.17,644.96) 1(5200.17,647.96) 1(5200.17,647.96) 1(5200.17,954) 1(5200.17,954) 1(5200.17,957) 1(5200.17,957) 1(5200.17,963) 1(5200.17,963) 1(5200.17,966) 1(5200.17,966) 1(5202.17,-117) 1(5202.17,-117) 1(5202.17,-97) 1(5202.17,-97) 1(5202.17,1244) 1(5202.17,1244) 1(5202.17,1250) 1(5202.17,1250) 1(5202.17,1256) 1(5202.17,1256) 1(5204.17,631.96) 1(5204.17,631.96) 1(5204.17,636.96) 1(5204.17,636.96) 1(5204.17,646.96) 1(5204.17,646.96) 1(5204.17,651.96) 1(5204.17,651.96) 1(5204.17,950) 1(5204.17,950) 1(5204.17,955) 1(5204.17,955) 1(5204.17,965) 1(5204.17,965) 1(5204.17,970) 1(5204.17,970) 1(5204.17,1240) 1(5204.17,1240) 1(5204.17,1250) 1(5204.17,1250) 1(5204.17,1260) 1(5204.17,1260) 1(5205.17,1244) 1(5205.17,1244) 1(5205.17,1247) 1(5205.17,1247) 1(5205.17,1253) 1(5205.17,1253) 1(5205.17,1256) 1(5205.17,1256) 1(5207.17,1763) 1(5207.17,1763) 1(5207.17,1768) 1(5207.17,1768) 1(5207.17,1778) 1(5207.17,1778) 1(5207.17,1783) 1(5207.17,1783) 1(5209.1,126) 1(5209.1,126) 1(5209.1,131) 1(5209.1,131) 1(5209.1,141) 1(5209.1,141) 1(5209.1,146) 1(5209.1,146) 1(5209.17,1240) 1(5209.17,1240) 1(5209.17,1245) 1(5209.17,1245) 1(5209.17,1255) 1(5209.17,1255) 1(5209.17,1260) 1(5209.17,1260) 1(5211.17,1767) 1(5211.17,1767) 1(5211.17,1770) 1(5211.17,1770) 1(5211.17,1776) 1(5211.17,1776) 1(5211.17,1779) 1(5211.17,1779) 1(5212.17,1763) 1(5212.17,1763) 1(5212.17,1773) 1(5212.17,1773) 1(5212.17,1783) 1(5212.17,1783) 1(5213.1,130) 1(5213.1,130) 1(5213.1,133) 1(5213.1,133) 1(5213.1,139) 1(5213.1,139) 1(5213.1,142) 1(5213.1,142) 1(5214.1,126) 1(5214.1,126) 1(5214.1,136) 1(5214.1,136) 1(5214.1,146) 1(5214.1,146) 1(5214.17,1767) 1(5214.17,1767) 1(5214.17,1773) 1(5214.17,1773) 1(5214.17,1779) 1(5214.17,1779) 1(5216.1,130) 1(5216.1,130) 1(5216.1,136) 1(5216.1,136) 1(5216.1,142) 1(5216.1,142) 1(5217.17,1768) 1(5217.17,1768) 1(5217.17,1770) 1(5217.17,1770) 1(5217.17,1776) 1(5217.17,1776) 1(5217.17,1778) 1(5217.17,1778) 1(5219.1,131) 1(5219.1,131) 1(5219.1,133) 1(5219.1,133) 1(5219.1,139) 1(5219.1,139) 1(5219.1,141) 1(5219.1,141) 1(5220.17,1767) 1(5220.17,1767) 1(5220.17,1773) 1(5220.17,1773) 1(5220.17,1779) 1(5220.17,1779) 1(5222.1,130) 1(5222.1,130) 1(5222.1,136) 1(5222.1,136) 1(5222.1,142) 1(5222.1,142) 1(5222.17,1763) 1(5222.17,1763) 1(5222.17,1773) 1(5222.17,1773) 1(5222.17,1783) 1(5222.17,1783) 1(5223.17,1767) 1(5223.17,1767) 1(5223.17,1770) 1(5223.17,1770) 1(5223.17,1776) 1(5223.17,1776) 1(5223.17,1779) 1(5223.17,1779) 1(5224.1,126) 1(5224.1,126) 1(5224.1,136) 1(5224.1,136) 1(5224.1,146) 1(5224.1,146) 1(5225.1,130) 1(5225.1,130) 1(5225.1,133) 1(5225.1,133) 1(5225.1,139) 1(5225.1,139) 1(5225.1,142) 1(5225.1,142) 1(5227.17,1763) 1(5227.17,1763) 1(5227.17,1768) 1(5227.17,1768) 1(5227.17,1778) 1(5227.17,1778) 1(5227.17,1783) 1(5227.17,1783) 1(5229.1,126) 1(5229.1,126) 1(5229.1,131) 1(5229.1,131) 1(5229.1,141) 1(5229.1,141) 1(5229.1,146) 1(5229.1,146) 1(5235.97,1752.36) 1(5235.97,1752.36) 1(5235.97,1757.36) 1(5235.97,1757.36) 1(5235.97,1767.36) 1(5235.97,1767.36) 1(5235.97,1772.36) 1(5235.97,1772.36) 1(5239.97,1756.36) 1(5239.97,1756.36) 1(5239.97,1759.36) 1(5239.97,1759.36) 1(5239.97,1765.36) 1(5239.97,1765.36) 1(5239.97,1768.36) 1(5239.97,1768.36) 1(5240.97,1752.36) 1(5240.97,1752.36) 1(5240.97,1762.36) 1(5240.97,1762.36) 1(5240.97,1772.36) 1(5240.97,1772.36) 1(5242.97,1756.36) 1(5242.97,1756.36) 1(5242.97,1762.36) 1(5242.97,1762.36) 1(5242.97,1768.36) 1(5242.97,1768.36) 1(5245.97,1757.36) 1(5245.97,1757.36) 1(5245.97,1759.36) 1(5245.97,1759.36) 1(5245.97,1765.36) 1(5245.97,1765.36) 1(5245.97,1767.36) 1(5245.97,1767.36) 1(5248.97,1756.36) 1(5248.97,1756.36) 1(5248.97,1762.36) 1(5248.97,1762.36) 1(5248.97,1768.36) 1(5248.97,1768.36) 1(5250.97,1752.36) 1(5250.97,1752.36) 1(5250.97,1762.36) 1(5250.97,1762.36) 1(5250.97,1772.36) 1(5250.97,1772.36) 1(5251.97,1756.36) 1(5251.97,1756.36) 1(5251.97,1759.36) 1(5251.97,1759.36) 1(5251.97,1765.36) 1(5251.97,1765.36) 1(5251.97,1768.36) 1(5251.97,1768.36) 1(5255.97,1752.36) 1(5255.97,1752.36) 1(5255.97,1757.36) 1(5255.97,1757.36) 1(5255.97,1767.36) 1(5255.97,1767.36) 1(5255.97,1772.36) 1(5255.97,1772.36) 1(5274.17,-3.86) 1(5274.17,-3.86) 1(5274.17,1.14) 1(5274.17,1.14) 1(5274.17,11.14) 1(5274.17,11.14) 1(5274.17,16.14) 1(5274.17,16.14) 1(5278.17,0.14) 1(5278.17,0.14) 1(5278.17,3.14) 1(5278.17,3.14) 1(5278.17,9.14) 1(5278.17,9.14) 1(5278.17,12.14) 1(5278.17,12.14) 1(5278.17,770) 1(5278.17,770) 1(5278.17,775) 1(5278.17,775) 1(5278.17,785) 1(5278.17,785) 1(5278.17,790) 1(5278.17,790) 1(5279.17,-3.86) 1(5279.17,-3.86) 1(5279.17,6.14) 1(5279.17,6.14) 1(5279.17,16.14) 1(5279.17,16.14) 1(5281.17,0.14) 1(5281.17,0.14) 1(5281.17,6.14) 1(5281.17,6.14) 1(5281.17,12.14) 1(5281.17,12.14) 1(5282.17,774) 1(5282.17,774) 1(5282.17,777) 1(5282.17,777) 1(5282.17,783) 1(5282.17,783) 1(5282.17,786) 1(5282.17,786) 1(5283.17,770) 1(5283.17,770) 1(5283.17,780) 1(5283.17,780) 1(5283.17,790) 1(5283.17,790) 1(5284.17,1.14) 1(5284.17,1.14) 1(5284.17,3.14) 1(5284.17,3.14) 1(5284.17,9.14) 1(5284.17,9.14) 1(5284.17,11.14) 1(5284.17,11.14) 1(5285.17,774) 1(5285.17,774) 1(5285.17,780) 1(5285.17,780) 1(5285.17,786) 1(5285.17,786) 1(5287.17,0.14) 1(5287.17,0.14) 1(5287.17,6.14) 1(5287.17,6.14) 1(5287.17,12.14) 1(5287.17,12.14) 1(5288.17,775) 1(5288.17,775) 1(5288.17,777) 1(5288.17,777) 1(5288.17,783) 1(5288.17,783) 1(5288.17,785) 1(5288.17,785) 1(5289.17,-3.86) 1(5289.17,-3.86) 1(5289.17,6.14) 1(5289.17,6.14) 1(5289.17,16.14) 1(5289.17,16.14) 1(5290.17,0.14) 1(5290.17,0.14) 1(5290.17,3.14) 1(5290.17,3.14) 1(5290.17,9.14) 1(5290.17,9.14) 1(5290.17,12.14) 1(5290.17,12.14) 1(5291.17,774) 1(5291.17,774) 1(5291.17,780) 1(5291.17,780) 1(5291.17,786) 1(5291.17,786) 1(5293.17,770) 1(5293.17,770) 1(5293.17,780) 1(5293.17,780) 1(5293.17,790) 1(5293.17,790) 1(5294.17,-3.86) 1(5294.17,-3.86) 1(5294.17,1.14) 1(5294.17,1.14) 1(5294.17,11.14) 1(5294.17,11.14) 1(5294.17,16.14) 1(5294.17,16.14) 1(5294.17,774) 1(5294.17,774) 1(5294.17,777) 1(5294.17,777) 1(5294.17,783) 1(5294.17,783) 1(5294.17,786) 1(5294.17,786) 1(5298.17,770) 1(5298.17,770) 1(5298.17,775) 1(5298.17,775) 1(5298.17,785) 1(5298.17,785) 1(5298.17,790) 1(5298.17,790) 1(5314.93,-147.71) 1(5314.93,-147.71) 1(5314.93,-127.71) 1(5314.93,-127.71) 1(5314.93,-47.71) 1(5314.93,-47.71) 1(5314.93,-27.71) 1(5314.93,-27.71) 1(5314.93,303.47) 1(5314.93,303.47) 1(5314.93,323.47) 1(5314.93,323.47) 1(5314.93,403.47) 1(5314.93,403.47) 1(5314.93,423.47) 1(5314.93,423.47) 1(5315.17,773) 1(5315.17,773) 1(5315.17,778) 1(5315.17,778) 1(5315.17,788) 1(5315.17,788) 1(5315.17,793) 1(5315.17,793) 1(5315.43,528.04) 1(5315.43,528.04) 1(5315.43,548.04) 1(5315.43,548.04) 1(5315.43,628.04) 1(5315.43,628.04) 1(5315.43,648.04) 1(5315.43,648.04) 1(5315.43,979.22) 1(5315.43,979.22) 1(5315.43,999.22) 1(5315.43,999.22) 1(5315.43,1079.22) 1(5315.43,1079.22) 1(5315.43,1099.22) 1(5315.43,1099.22) 1(5315.43,1198.55) 1(5315.43,1198.55) 1(5315.43,1218.55) 1(5315.43,1218.55) 1(5315.43,1298.55) 1(5315.43,1298.55) 1(5315.43,1318.55) 1(5315.43,1318.55) 1(5315.43,1649.73) 1(5315.43,1649.73) 1(5315.43,1669.73) 1(5315.43,1669.73) 1(5315.43,1749.73) 1(5315.43,1749.73) 1(5315.43,1769.73) 1(5315.43,1769.73) 1(5315.43,1877.68) 1(5315.43,1877.68) 1(5315.43,1897.68) 1(5315.43,1897.68) 1(5315.43,1977.68) 1(5315.43,1977.68) 1(5315.43,1997.68) 1(5315.43,1997.68) 1(5315.43,2328.86) 1(5315.43,2328.86) 1(5315.43,2348.86) 1(5315.43,2348.86) 1(5315.43,2428.86) 1(5315.43,2428.86) 1(5315.43,2448.86) 1(5315.43,2448.86) 1(5319.17,777) 1(5319.17,777) 1(5319.17,780) 1(5319.17,780) 1(5319.17,786) 1(5319.17,786) 1(5319.17,789) 1(5319.17,789) 1(5320.17,773) 1(5320.17,773) 1(5320.17,783) 1(5320.17,783) 1(5320.17,793) 1(5320.17,793) 1(5322.17,777) 1(5322.17,777) 1(5322.17,783) 1(5322.17,783) 1(5322.17,789) 1(5322.17,789) 1(5325.17,778) 1(5325.17,778) 1(5325.17,780) 1(5325.17,780) 1(5325.17,786) 1(5325.17,786) 1(5325.17,788) 1(5325.17,788) 1(5328.17,777) 1(5328.17,777) 1(5328.17,783) 1(5328.17,783) 1(5328.17,789) 1(5328.17,789) 1(5330.17,773) 1(5330.17,773) 1(5330.17,783) 1(5330.17,783) 1(5330.17,793) 1(5330.17,793) 1(5331.17,777) 1(5331.17,777) 1(5331.17,780) 1(5331.17,780) 1(5331.17,786) 1(5331.17,786) 1(5331.17,789) 1(5331.17,789) 1(5334.93,-147.71) 1(5334.93,-147.71) 1(5334.93,-127.71) 1(5334.93,-127.71) 1(5334.93,-47.71) 1(5334.93,-47.71) 1(5334.93,-27.71) 1(5334.93,-27.71) 1(5334.93,303.47) 1(5334.93,303.47) 1(5334.93,323.47) 1(5334.93,323.47) 1(5334.93,403.47) 1(5334.93,403.47) 1(5334.93,423.47) 1(5334.93,423.47) 1(5335.17,773) 1(5335.17,773) 1(5335.17,778) 1(5335.17,778) 1(5335.17,788) 1(5335.17,788) 1(5335.17,793) 1(5335.17,793) 1(5335.43,528.04) 1(5335.43,528.04) 1(5335.43,548.04) 1(5335.43,548.04) 1(5335.43,628.04) 1(5335.43,628.04) 1(5335.43,648.04) 1(5335.43,648.04) 1(5335.43,979.22) 1(5335.43,979.22) 1(5335.43,999.22) 1(5335.43,999.22) 1(5335.43,1079.22) 1(5335.43,1079.22) 1(5335.43,1099.22) 1(5335.43,1099.22) 1(5335.43,1198.55) 1(5335.43,1198.55) 1(5335.43,1218.55) 1(5335.43,1218.55) 1(5335.43,1298.55) 1(5335.43,1298.55) 1(5335.43,1318.55) 1(5335.43,1318.55) 1(5335.43,1649.73) 1(5335.43,1649.73) 1(5335.43,1669.73) 1(5335.43,1669.73) 1(5335.43,1749.73) 1(5335.43,1749.73) 1(5335.43,1769.73) 1(5335.43,1769.73) 1(5335.43,1877.68) 1(5335.43,1877.68) 1(5335.43,1897.68) 1(5335.43,1897.68) 1(5335.43,1977.68) 1(5335.43,1977.68) 1(5335.43,1997.68) 1(5335.43,1997.68) 1(5335.43,2328.86) 1(5335.43,2328.86) 1(5335.43,2348.86) 1(5335.43,2348.86) 1(5335.43,2428.86) 1(5335.43,2428.86) 1(5335.43,2448.86) 1(5335.43,2448.86) 1(5344.17,10) 1(5344.17,10) 1(5344.17,15) 1(5344.17,15) 1(5344.17,25) 1(5344.17,25) 1(5344.17,30) 1(5344.17,30) 1(5348.17,14) 1(5348.17,14) 1(5348.17,17) 1(5348.17,17) 1(5348.17,23) 1(5348.17,23) 1(5348.17,26) 1(5348.17,26) 1(5349.17,10) 1(5349.17,10) 1(5349.17,20) 1(5349.17,20) 1(5349.17,30) 1(5349.17,30) 1(5351.17,14) 1(5351.17,14) 1(5351.17,20) 1(5351.17,20) 1(5351.17,26) 1(5351.17,26) 1(5354.17,15) 1(5354.17,15) 1(5354.17,17) 1(5354.17,17) 1(5354.17,23) 1(5354.17,23) 1(5354.17,25) 1(5354.17,25) 1(5357.17,14) 1(5357.17,14) 1(5357.17,20) 1(5357.17,20) 1(5357.17,26) 1(5357.17,26) 1(5359.17,10) 1(5359.17,10) 1(5359.17,20) 1(5359.17,20) 1(5359.17,30) 1(5359.17,30) 1(5360.17,14) 1(5360.17,14) 1(5360.17,17) 1(5360.17,17) 1(5360.17,23) 1(5360.17,23) 1(5360.17,26) 1(5360.17,26) 1(5364.17,10) 1(5364.17,10) 1(5364.17,15) 1(5364.17,15) 1(5364.17,25) 1(5364.17,25) 1(5364.17,30) 1(5364.17,30) 1(5374.17,2195.58) 1(5374.17,2195.58) 1(5374.17,2200.58) 1(5374.17,2200.58) 1(5374.17,2210.58) 1(5374.17,2210.58) 1(5374.17,2215.58) 1(5374.17,2215.58) 1(5378.17,2199.58) 1(5378.17,2199.58) 1(5378.17,2202.58) 1(5378.17,2202.58) 1(5378.17,2208.58) 1(5378.17,2208.58) 1(5378.17,2211.58) 1(5378.17,2211.58) 1(5379.17,2195.58) 1(5379.17,2195.58) 1(5379.17,2205.58) 1(5379.17,2205.58) 1(5379.17,2215.58) 1(5379.17,2215.58) 1(5381.17,2199.58) 1(5381.17,2199.58) 1(5381.17,2205.58) 1(5381.17,2205.58) 1(5381.17,2211.58) 1(5381.17,2211.58) 1(5384.17,2200.58) 1(5384.17,2200.58) 1(5384.17,2202.58) 1(5384.17,2202.58) 1(5384.17,2208.58) 1(5384.17,2208.58) 1(5384.17,2210.58) 1(5384.17,2210.58) 1(5387.17,2199.58) 1(5387.17,2199.58) 1(5387.17,2205.58) 1(5387.17,2205.58) 1(5387.17,2211.58) 1(5387.17,2211.58) 1(5389.17,714.63) 1(5389.17,714.63) 1(5389.17,719.63) 1(5389.17,719.63) 1(5389.17,729.63) 1(5389.17,729.63) 1(5389.17,734.63) 1(5389.17,734.63) 1(5389.17,2195.58) 1(5389.17,2195.58) 1(5389.17,2205.58) 1(5389.17,2205.58) 1(5389.17,2215.58) 1(5389.17,2215.58) 1(5390.17,2199.58) 1(5390.17,2199.58) 1(5390.17,2202.58) 1(5390.17,2202.58) 1(5390.17,2208.58) 1(5390.17,2208.58) 1(5390.17,2211.58) 1(5390.17,2211.58) 1(5393.17,718.63) 1(5393.17,718.63) 1(5393.17,721.63) 1(5393.17,721.63) 1(5393.17,727.63) 1(5393.17,727.63) 1(5393.17,730.63) 1(5393.17,730.63) 1(5394.17,714.63) 1(5394.17,714.63) 1(5394.17,724.63) 1(5394.17,724.63) 1(5394.17,734.63) 1(5394.17,734.63) 1(5394.17,2195.58) 1(5394.17,2195.58) 1(5394.17,2200.58) 1(5394.17,2200.58) 1(5394.17,2210.58) 1(5394.17,2210.58) 1(5394.17,2215.58) 1(5394.17,2215.58) 1(5396.17,718.63) 1(5396.17,718.63) 1(5396.17,724.63) 1(5396.17,724.63) 1(5396.17,730.63) 1(5396.17,730.63) 1(5399.17,719.63) 1(5399.17,719.63) 1(5399.17,721.63) 1(5399.17,721.63) 1(5399.17,727.63) 1(5399.17,727.63) 1(5399.17,729.63) 1(5399.17,729.63) 1(5402.17,718.63) 1(5402.17,718.63) 1(5402.17,724.63) 1(5402.17,724.63) 1(5402.17,730.63) 1(5402.17,730.63) 1(5404.17,714.63) 1(5404.17,714.63) 1(5404.17,724.63) 1(5404.17,724.63) 1(5404.17,734.63) 1(5404.17,734.63) 1(5405.17,718.63) 1(5405.17,718.63) 1(5405.17,721.63) 1(5405.17,721.63) 1(5405.17,727.63) 1(5405.17,727.63) 1(5405.17,730.63) 1(5405.17,730.63) 1(5409.17,714.63) 1(5409.17,714.63) 1(5409.17,719.63) 1(5409.17,719.63) 1(5409.17,729.63) 1(5409.17,729.63) 1(5409.17,734.63) 1(5409.17,734.63) 1(5414.17,1390) 1(5414.17,1390) 1(5414.17,1395) 1(5414.17,1395) 1(5414.17,1405) 1(5414.17,1405) 1(5414.17,1410) 1(5414.17,1410) 1(5418.17,1394) 1(5418.17,1394) 1(5418.17,1397) 1(5418.17,1397) 1(5418.17,1403) 1(5418.17,1403) 1(5418.17,1406) 1(5418.17,1406) 1(5419.17,1390) 1(5419.17,1390) 1(5419.17,1400) 1(5419.17,1400) 1(5419.17,1410) 1(5419.17,1410) 1(5421.17,1394) 1(5421.17,1394) 1(5421.17,1400) 1(5421.17,1400) 1(5421.17,1406) 1(5421.17,1406) 1(5424.17,1395) 1(5424.17,1395) 1(5424.17,1397) 1(5424.17,1397) 1(5424.17,1403) 1(5424.17,1403) 1(5424.17,1405) 1(5424.17,1405) 1(5427.17,1394) 1(5427.17,1394) 1(5427.17,1400) 1(5427.17,1400) 1(5427.17,1406) 1(5427.17,1406) 1(5429.17,1390) 1(5429.17,1390) 1(5429.17,1400) 1(5429.17,1400) 1(5429.17,1410) 1(5429.17,1410) 1(5430.17,1394) 1(5430.17,1394) 1(5430.17,1397) 1(5430.17,1397) 1(5430.17,1403) 1(5430.17,1403) 1(5430.17,1406) 1(5430.17,1406) 1(5434.17,1390) 1(5434.17,1390) 1(5434.17,1395) 1(5434.17,1395) 1(5434.17,1405) 1(5434.17,1405) 1(5434.17,1410) 1(5434.17,1410) 1(5504.7,-12.67) 1(5504.7,-12.67) 1(5504.7,7.33) 1(5504.7,7.33) 1(5504.7,67.64) 1(5504.7,67.64) 1(5504.7,87.64) 1(5504.7,87.64) 1(5504.7,147.96) 1(5504.7,147.96) 1(5504.7,167.96) 1(5504.7,167.96) 1(5504.7,228.27) 1(5504.7,228.27) 1(5504.7,248.27) 1(5504.7,248.27) 1(5505.2,663.07) 1(5505.2,663.07) 1(5505.2,683.07) 1(5505.2,683.07) 1(5505.2,743.39) 1(5505.2,743.39) 1(5505.2,763.39) 1(5505.2,763.39) 1(5505.2,823.7) 1(5505.2,823.7) 1(5505.2,843.7) 1(5505.2,843.7) 1(5505.2,904.02) 1(5505.2,904.02) 1(5505.2,924.02) 1(5505.2,924.02) 1(5505.2,1333.59) 1(5505.2,1333.59) 1(5505.2,1353.59) 1(5505.2,1353.59) 1(5505.2,1413.9) 1(5505.2,1413.9) 1(5505.2,1433.9) 1(5505.2,1433.9) 1(5505.2,1494.22) 1(5505.2,1494.22) 1(5505.2,1514.22) 1(5505.2,1514.22) 1(5505.2,1574.53) 1(5505.2,1574.53) 1(5505.2,1594.53) 1(5505.2,1594.53) 1(5505.2,2012.72) 1(5505.2,2012.72) 1(5505.2,2032.72) 1(5505.2,2032.72) 1(5505.2,2093.04) 1(5505.2,2093.04) 1(5505.2,2113.04) 1(5505.2,2113.04) 1(5505.2,2173.35) 1(5505.2,2173.35) 1(5505.2,2193.35) 1(5505.2,2193.35) 1(5505.2,2253.67) 1(5505.2,2253.67) 1(5505.2,2273.67) 1(5505.2,2273.67) 1(5524.7,-12.67) 1(5524.7,-12.67) 1(5524.7,7.33) 1(5524.7,7.33) 1(5524.7,67.64) 1(5524.7,67.64) 1(5524.7,87.64) 1(5524.7,87.64) 1(5524.7,147.96) 1(5524.7,147.96) 1(5524.7,167.96) 1(5524.7,167.96) 1(5524.7,228.27) 1(5524.7,228.27) 1(5524.7,248.27) 1(5524.7,248.27) 1(5525.2,663.07) 1(5525.2,663.07) 1(5525.2,683.07) 1(5525.2,683.07) 1(5525.2,743.39) 1(5525.2,743.39) 1(5525.2,763.39) 1(5525.2,763.39) 1(5525.2,823.7) 1(5525.2,823.7) 1(5525.2,843.7) 1(5525.2,843.7) 1(5525.2,904.02) 1(5525.2,904.02) 1(5525.2,924.02) 1(5525.2,924.02) 1(5525.2,1333.59) 1(5525.2,1333.59) 1(5525.2,1353.59) 1(5525.2,1353.59) 1(5525.2,1413.9) 1(5525.2,1413.9) 1(5525.2,1433.9) 1(5525.2,1433.9) 1(5525.2,1494.22) 1(5525.2,1494.22) 1(5525.2,1514.22) 1(5525.2,1514.22) 1(5525.2,1574.53) 1(5525.2,1574.53) 1(5525.2,1594.53) 1(5525.2,1594.53) 1(5525.2,2012.72) 1(5525.2,2012.72) 1(5525.2,2032.72) 1(5525.2,2032.72) 1(5525.2,2093.04) 1(5525.2,2093.04) 1(5525.2,2113.04) 1(5525.2,2113.04) 1(5525.2,2173.35) 1(5525.2,2173.35) 1(5525.2,2193.35) 1(5525.2,2193.35) 1(5525.2,2253.67) 1(5525.2,2253.67) 1(5525.2,2273.67) 1(5525.2,2273.67) 1(5539.73,-131.57) 1(5539.73,-131.57) 1(5539.73,-111.57) 1(5539.73,-111.57) 1(5539.73,387.33) 1(5539.73,387.33) 1(5539.73,407.33) 1(5539.73,407.33) 1(5540.23,544.18) 1(5540.23,544.18) 1(5540.23,564.18) 1(5540.23,564.18) 1(5540.23,1063.07) 1(5540.23,1063.07) 1(5540.23,1083.07) 1(5540.23,1083.07) 1(5540.23,1214.69) 1(5540.23,1214.69) 1(5540.23,1234.69) 1(5540.23,1234.69) 1(5540.23,1733.59) 1(5540.23,1733.59) 1(5540.23,1753.59) 1(5540.23,1753.59) 1(5540.23,1893.82) 1(5540.23,1893.82) 1(5540.23,1913.82) 1(5540.23,1913.82) 1(5540.23,2412.72) 1(5540.23,2412.72) 1(5540.23,2432.72) 1(5540.23,2432.72) 1(5559.73,-121.57) 1(5559.73,-121.57) 1(5559.73,397.33) 1(5559.73,397.33) 1(5560.23,554.18) 1(5560.23,554.18) 1(5560.23,1073.07) 1(5560.23,1073.07) 1(5560.23,1224.69) 1(5560.23,1224.69) 1(5560.23,1743.59) 1(5560.23,1743.59) 1(5560.23,1903.82) 1(5560.23,1903.82) 1(5560.23,2422.72) 1(5560.23,2422.72) 1(5574.77,27.49) 1(5574.77,27.49) 1(5574.77,47.49) 1(5574.77,47.49) 1(5574.77,107.8) 1(5574.77,107.8) 1(5574.77,127.8) 1(5574.77,127.8) 1(5574.77,188.12) 1(5574.77,188.12) 1(5574.77,208.12) 1(5574.77,208.12) 1(5574.77,268.43) 1(5574.77,268.43) 1(5574.77,288.43) 1(5574.77,288.43) 1(5575.27,703.23) 1(5575.27,703.23) 1(5575.27,723.23) 1(5575.27,723.23) 1(5575.27,783.55) 1(5575.27,783.55) 1(5575.27,803.55) 1(5575.27,803.55) 1(5575.27,863.86) 1(5575.27,863.86) 1(5575.27,883.86) 1(5575.27,883.86) 1(5575.27,944.18) 1(5575.27,944.18) 1(5575.27,964.18) 1(5575.27,964.18) 1(5575.27,1373.75) 1(5575.27,1373.75) 1(5575.27,1393.75) 1(5575.27,1393.75) 1(5575.27,1454.06) 1(5575.27,1454.06) 1(5575.27,1474.06) 1(5575.27,1474.06) 1(5575.27,1534.38) 1(5575.27,1534.38) 1(5575.27,1554.38) 1(5575.27,1554.38) 1(5575.27,1614.69) 1(5575.27,1614.69) 1(5575.27,1634.69) 1(5575.27,1634.69) 1(5575.27,2052.88) 1(5575.27,2052.88) 1(5575.27,2072.88) 1(5575.27,2072.88) 1(5575.27,2133.19) 1(5575.27,2133.19) 1(5575.27,2153.19) 1(5575.27,2153.19) 1(5575.27,2213.51) 1(5575.27,2213.51) 1(5575.27,2233.51) 1(5575.27,2233.51) 1(5575.27,2293.82) 1(5575.27,2293.82) 1(5575.27,2313.82) 1(5575.27,2313.82) 1(5594.77,27.49) 1(5594.77,27.49) 1(5594.77,47.49) 1(5594.77,47.49) 1(5594.77,107.8) 1(5594.77,107.8) 1(5594.77,127.8) 1(5594.77,127.8) 1(5594.77,188.12) 1(5594.77,188.12) 1(5594.77,208.12) 1(5594.77,208.12) 1(5594.77,268.43) 1(5594.77,268.43) 1(5594.77,288.43) 1(5594.77,288.43) 1(5595.27,703.23) 1(5595.27,703.23) 1(5595.27,723.23) 1(5595.27,723.23) 1(5595.27,783.55) 1(5595.27,783.55) 1(5595.27,803.55) 1(5595.27,803.55) 1(5595.27,863.86) 1(5595.27,863.86) 1(5595.27,883.86) 1(5595.27,883.86) 1(5595.27,944.18) 1(5595.27,944.18) 1(5595.27,964.18) 1(5595.27,964.18) 1(5595.27,1373.75) 1(5595.27,1373.75) 1(5595.27,1393.75) 1(5595.27,1393.75) 1(5595.27,1454.06) 1(5595.27,1454.06) 1(5595.27,1474.06) 1(5595.27,1474.06) 1(5595.27,1534.38) 1(5595.27,1534.38) 1(5595.27,1554.38) 1(5595.27,1554.38) 1(5595.27,1614.69) 1(5595.27,1614.69) 1(5595.27,1634.69) 1(5595.27,1634.69) 1(5595.27,2052.88) 1(5595.27,2052.88) 1(5595.27,2072.88) 1(5595.27,2072.88) 1(5595.27,2133.19) 1(5595.27,2133.19) 1(5595.27,2153.19) 1(5595.27,2153.19) 1(5595.27,2213.51) 1(5595.27,2213.51) 1(5595.27,2233.51) 1(5595.27,2233.51) 1(5595.27,2293.82) 1(5595.27,2293.82) 1(5595.27,2313.82) 1(5595.27,2313.82) 1(5674.77,-114.09) 1(5674.77,-114.09) 1(5674.77,389.85) 1(5674.77,389.85) 1(5675.27,561.66) 1(5675.27,561.66) 1(5675.27,1065.59) 1(5675.27,1065.59) 1(5675.27,1232.17) 1(5675.27,1232.17) 1(5675.27,1736.11) 1(5675.27,1736.11) 1(5675.27,1911.3) 1(5675.27,1911.3) 1(5675.27,2415.24) 1(5675.27,2415.24) 1(5679.77,-124.09) 1(5679.77,-124.09) 1(5679.77,-119.09) 1(5679.77,-119.09) 1(5679.77,-109.09) 1(5679.77,-109.09) 1(5679.77,-104.09) 1(5679.77,-104.09) 1(5679.77,379.85) 1(5679.77,379.85) 1(5679.77,384.85) 1(5679.77,384.85) 1(5679.77,394.85) 1(5679.77,394.85) 1(5679.77,399.85) 1(5679.77,399.85) 1(5680.27,551.66) 1(5680.27,551.66) 1(5680.27,556.66) 1(5680.27,556.66) 1(5680.27,566.66) 1(5680.27,566.66) 1(5680.27,571.66) 1(5680.27,571.66) 1(5680.27,1055.59) 1(5680.27,1055.59) 1(5680.27,1060.59) 1(5680.27,1060.59) 1(5680.27,1070.59) 1(5680.27,1070.59) 1(5680.27,1075.59) 1(5680.27,1075.59) 1(5680.27,1222.17) 1(5680.27,1222.17) 1(5680.27,1227.17) 1(5680.27,1227.17) 1(5680.27,1237.17) 1(5680.27,1237.17) 1(5680.27,1242.17) 1(5680.27,1242.17) 1(5680.27,1726.11) 1(5680.27,1726.11) 1(5680.27,1731.11) 1(5680.27,1731.11) 1(5680.27,1741.11) 1(5680.27,1741.11) 1(5680.27,1746.11) 1(5680.27,1746.11) 1(5680.27,1901.3) 1(5680.27,1901.3) 1(5680.27,1906.3) 1(5680.27,1906.3) 1(5680.27,1916.3) 1(5680.27,1916.3) 1(5680.27,1921.3) 1(5680.27,1921.3) 1(5680.27,2405.24) 1(5680.27,2405.24) 1(5680.27,2410.24) 1(5680.27,2410.24) 1(5680.27,2420.24) 1(5680.27,2420.24) 1(5680.27,2425.24) 1(5680.27,2425.24) 1(5684.77,-119.09) 1(5684.77,-119.09) 1(5684.77,-109.09) 1(5684.77,-109.09) 1(5684.77,384.85) 1(5684.77,384.85) 1(5684.77,394.85) 1(5684.77,394.85) 1(5685.27,556.66) 1(5685.27,556.66) 1(5685.27,566.66) 1(5685.27,566.66) 1(5685.27,1060.59) 1(5685.27,1060.59) 1(5685.27,1070.59) 1(5685.27,1070.59) 1(5685.27,1227.17) 1(5685.27,1227.17) 1(5685.27,1237.17) 1(5685.27,1237.17) 1(5685.27,1731.11) 1(5685.27,1731.11) 1(5685.27,1741.11) 1(5685.27,1741.11) 1(5685.27,1906.3) 1(5685.27,1906.3) 1(5685.27,1916.3) 1(5685.27,1916.3) 1(5685.27,2410.24) 1(5685.27,2410.24) 1(5685.27,2420.24) 1(5685.27,2420.24) 1(5689.77,-124.09) 1(5689.77,-124.09) 1(5689.77,-119.09) 1(5689.77,-119.09) 1(5689.77,-109.09) 1(5689.77,-109.09) 1(5689.77,-104.09) 1(5689.77,-104.09) 1(5689.77,379.85) 1(5689.77,379.85) 1(5689.77,384.85) 1(5689.77,384.85) 1(5689.77,394.85) 1(5689.77,394.85) 1(5689.77,399.85) 1(5689.77,399.85) 1(5690.27,551.66) 1(5690.27,551.66) 1(5690.27,556.66) 1(5690.27,556.66) 1(5690.27,566.66) 1(5690.27,566.66) 1(5690.27,571.66) 1(5690.27,571.66) 1(5690.27,1055.59) 1(5690.27,1055.59) 1(5690.27,1060.59) 1(5690.27,1060.59) 1(5690.27,1070.59) 1(5690.27,1070.59) 1(5690.27,1075.59) 1(5690.27,1075.59) 1(5690.27,1222.17) 1(5690.27,1222.17) 1(5690.27,1227.17) 1(5690.27,1227.17) 1(5690.27,1237.17) 1(5690.27,1237.17) 1(5690.27,1242.17) 1(5690.27,1242.17) 1(5690.27,1726.11) 1(5690.27,1726.11) 1(5690.27,1731.11) 1(5690.27,1731.11) 1(5690.27,1741.11) 1(5690.27,1741.11) 1(5690.27,1746.11) 1(5690.27,1746.11) 1(5690.27,1901.3) 1(5690.27,1901.3) 1(5690.27,1906.3) 1(5690.27,1906.3) 1(5690.27,1916.3) 1(5690.27,1916.3) 1(5690.27,1921.3) 1(5690.27,1921.3) 1(5690.27,2405.24) 1(5690.27,2405.24) 1(5690.27,2410.24) 1(5690.27,2410.24) 1(5690.27,2420.24) 1(5690.27,2420.24) 1(5690.27,2425.24) 1(5690.27,2425.24) 1(5694.77,-114.09) 1(5694.77,-114.09) 1(5694.77,389.85) 1(5694.77,389.85) 1(5695.27,561.66) 1(5695.27,561.66) 1(5695.27,1065.59) 1(5695.27,1065.59) 1(5695.27,1232.17) 1(5695.27,1232.17) 1(5695.27,1736.11) 1(5695.27,1736.11) 1(5695.27,1911.3) 1(5695.27,1911.3) 1(5695.27,2415.24) 1(5695.27,2415.24)
  round 20 on Mech16: 1(3152.22,641.96) 1(3670.75,-89.16) 1(3764.17,1537.19) 1(3774.17,1769.09) 1(3854.17,1562.19) 1(3867.6,-89.16) 1(4329.17,1090) 1(4364.17,2250) 1(4394.17,71.38) 1(4534.17,1075) 1(4569.17,1085) 1(4574.17,495) 1(4594.17,1310) 1(4624.17,1334) 1(4646.17,1415) 1(4691.93,2250) 1(4692.74,48.88) 1(4703.85,1019.68) 1(4876.02,1230) 1(4876.02,1770)
  round 12 on Mech16: 1(3152.22,641.96) 1(3764.17,1537.19) 1(3774.17,1769.09) 1(3854.17,1562.19) 1(4329.17,1090) 1(4364.17,2250) 1(4394.17,71.38) 1(4534.17,1075) 1(4569.17,1085) 1(4574.17,495) 1(4594.17,1310) 1(4624.17,1334) 1(4646.17,1415) 1(4691.93,2250) 1(4692.74,48.88) 1(4703.85,1019.68) 1(4876.02,1230) 1(4876.02,1770)
  round 2.5 on Mech16: 1(3286.65,783.06) 1(3286.65,783.06) 1(3286.65,931.06) 1(3286.65,931.06) 1(3366.65,783.06) 1(3366.65,783.06) 1(3366.65,931.06) 1(3366.65,931.06) 1(3954.17,348.4) 1(3954.17,348.4) 1(3954.17,496.4) 1(3954.17,496.4) 1(4034.17,348.4) 1(4034.17,348.4) 1(4034.17,496.4) 1(4034.17,496.4) 1(4910.94,835) 1(4910.94,835) 1(4910.94,1435) 1(4910.94,1435) 1(4935.94,810) 1(4935.94,810) 1(4935.94,1460) 1(4935.94,1460) 1(5085.94,810) 1(5085.94,810) 1(5085.94,1460) 1(5085.94,1460) 1(5110.94,835) 1(5110.94,835) 1(5110.94,1435) 1(5110.94,1435) 1(5218.5,215.99) 1(5218.5,215.99) 1(5238.41,166.3) 1(5238.41,166.3) 1(5249.54,155.16) 1(5249.54,155.16) 1(5253.3,181.19) 1(5253.3,181.19) 1(5254.69,252.18) 1(5254.69,252.18) 1(5263.04,243.83) 1(5263.04,243.83) 1(5264.44,170.06) 1(5264.44,170.06) 1(5274.18,232.7) 1(5274.18,232.7) 1(5277.94,258.72) 1(5277.94,258.72) 1(5285,86.59) 1(5285,86.59) 1(5289.07,247.59) 1(5289.07,247.59) 1(5299.23,135.26) 1(5299.23,135.26) 1(5304.91,36.89) 1(5304.91,36.89) 1(5315.94,190.94) 1(5315.94,190.94) 1(5316.04,25.76) 1(5316.04,25.76) 1(5319.8,51.79) 1(5319.8,51.79) 1(5321.19,122.78) 1(5321.19,122.78) 1(5327.07,179.8) 1(5327.07,179.8) 1(5329.55,114.42) 1(5329.55,114.42) 1(5330.83,205.83) 1(5330.83,205.83) 1(5330.94,40.65) 1(5330.94,40.65) 1(5335.42,171.45) 1(5335.42,171.45) 1(5336.84,1418.42) 1(5336.84,1418.42) 1(5336.84,1469.61) 1(5336.84,1469.61) 1(5340.68,103.29) 1(5340.68,103.29) 1(5341.97,194.7) 1(5341.97,194.7) 1(5342.07,708.42) 1(5342.07,708.42) 1(5342.07,759.61) 1(5342.07,759.61) 1(5344.44,129.32) 1(5344.44,129.32) 1(5348.65,1469.61) 1(5348.65,1469.61) 1(5348.65,1490.67) 1(5348.65,1490.67) 1(5353.88,759.61) 1(5353.88,759.61) 1(5353.88,780.67) 1(5353.88,780.67) 1(5355.57,118.18) 1(5355.57,118.18) 1(5357.23,2135.39) 1(5357.23,2135.39) 1(5357.23,2186.57) 1(5357.23,2186.57) 1(5364.4,1469.61) 1(5364.4,1469.61) 1(5364.4,1490.67) 1(5364.4,1490.67) 1(5365.74,5.85) 1(5365.74,5.85) 1(5369.04,2114.33) 1(5369.04,2114.33) 1(5369.04,2135.39) 1(5369.04,2135.39) 1(5369.63,759.61) 1(5369.63,759.61) 1(5369.63,780.67) 1(5369.63,780.67) 1(5382.44,61.53) 1(5382.44,61.53) 1(5384.78,2114.33) 1(5384.78,2114.33) 1(5384.78,2135.39) 1(5384.78,2135.39) 1(5386.05,1397.36) 1(5386.05,1397.36) 1(5386.05,1418.42) 1(5386.05,1418.42) 1(5391.28,687.36) 1(5391.28,687.36) 1(5391.28,708.42) 1(5391.28,708.42) 1(5393.57,50.4) 1(5393.57,50.4) 1(5397.33,76.42) 1(5397.33,76.42) 1(5401.8,1397.36) 1(5401.8,1397.36) 1(5401.8,1418.42) 1(5401.8,1418.42) 1(5401.93,42.04) 1(5401.93,42.04) 1(5406.44,2186.57) 1(5406.44,2186.57) 1(5406.44,2207.64) 1(5406.44,2207.64) 1(5407.03,687.36) 1(5407.03,687.36) 1(5407.03,708.42) 1(5407.03,708.42) 1(5408.47,65.29) 1(5408.47,65.29) 1(5422.19,2186.57) 1(5422.19,2186.57) 1(5422.19,2207.64) 1(5422.19,2207.64) 1(5423.45,1469.61) 1(5423.45,1469.61) 1(5423.45,1490.67) 1(5423.45,1490.67) 1(5428.68,759.61) 1(5428.68,759.61) 1(5428.68,780.67) 1(5428.68,780.67) 1(5439.2,1469.61) 1(5439.2,1469.61) 1(5439.2,1490.67) 1(5439.2,1490.67) 1(5443.84,2114.33) 1(5443.84,2114.33) 1(5443.84,2135.39) 1(5443.84,2135.39) 1(5444.43,759.61) 1(5444.43,759.61) 1(5444.43,780.67) 1(5444.43,780.67) 1(5451.01,1418.42) 1(5451.01,1418.42) 1(5451.01,1469.61) 1(5451.01,1469.61) 1(5456.24,708.42) 1(5456.24,708.42) 1(5456.24,759.61) 1(5456.24,759.61) 1(5459.59,2114.33) 1(5459.59,2114.33) 1(5459.59,2135.39) 1(5459.59,2135.39) 1(5471.4,2135.39) 1(5471.4,2135.39) 1(5471.4,2186.57) 1(5471.4,2186.57)
  round 15.62 on Mech16: 1(3783.19,-279.05)

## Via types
v1: diameter 18, hole 8, Top Layer to Bottom Layer, tented both sides, 1603 vias
v2: diameter 19.68, hole 7.87, Top Layer to Bottom Layer, tented both sides, 104 vias
v3: diameter 19.68, hole 7.87, Top Layer to Bottom Layer, 24 vias
v4: diameter 18, hole 8, Top Layer to Bottom Layer, 3 vias

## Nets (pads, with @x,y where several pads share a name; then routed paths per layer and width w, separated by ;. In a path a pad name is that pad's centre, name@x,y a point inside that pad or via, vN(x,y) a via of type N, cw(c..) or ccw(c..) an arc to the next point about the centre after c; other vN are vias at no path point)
ADC_EXT_VREF: J17.2 S2.3 S2.6 | length 334.2
  Bottom Layer w15: S2.6@1651.87,1121.1 S2.3@1797.54,1121.1 1807.32,1111.33 1807.32,1030.01 1798.53,1021.22 1721.17,1021.22 J17.2@1718.62,1023.77
AM263P_ADC0_AIN0: C72.1 J1/J3.23 U1.V15 U12.1 U12.10 | length 3450.6
  Top Layer w4: 3988.08,815.87 U1.V15@3988.08,847.36
  Top Layer w5.3: v1(1775,548.33) C72.1@1745,548.33 1745,519.48 1753.65,510.82 1781.73,510.82 1795.63,496.93 U12.10@1795.63,480.91 U12.1@1795.63,448.04 1795.63,358.54 J1/J3.23@1804.17,350 ; v1(3980.2,267.5) 3980.2,316.28 3989.69,325.77 3989.69,373 3983.32,379.37 3972.78,389.91 3972.78,683.06 4012.02,722.3 4012.02,763.67 3988.08,787.62 3988.08,815.87
  SIG 1 w4.75: v1(1775,548.33) 1775,530.95 1873.95,432 2560.61,432 2571.02,442.4 2608.08,442.4 2633.76,416.72 2899.13,416.72 2990.57,508.16 3180.34,508.16 3210.71,538.54 3316.31,538.54 3401.85,453 3401.85,420.82 3420.39,402.28 3463.11,402.28 3618,247.39 3688.62,247.39 3697.57,256.33 3715.03,256.33 3717.18,258.48 3768.57,258.48 3841.31,331.22 3894.22,331.22 3903.95,340.95 3952.45,340.95 3980.2,313.2 v1(3980.2,267.5)
AM263P_ADC0_AIN1: C82.1 J1/J3.28 U1.U15 U13.2 U13.9 | length 2981.4
  Top Layer w4: U1.U15@3988.08,878.86 4003.83,863.11 4003.83,815.87
  Top Layer w5.3: v1@2180,548.85 C82.1@2150,548.85 2150,516.35 2160.31,506.03 U13.9@2160.31,481.44 U13.2@2160.31,448.56 2160.31,421.62 2180.83,401.1 2253.07,401.1 J1/J3.28@2304.17,350 ; 4003.98,815.87 4003.98,794.2 4028.17,770.01 4028.17,716.33 3993.84,681.99 3993.84,495.65 4038.32,451.17 4038.32,415.19 v1(4037.93,414.81)
  SIG 1 w5.3: v1(2180,548.85) 2207.48,548.85 2227,529.33 2258.52,529.33 2284.77,555.57 2428.12,555.57 2469.39,514.3 2574.61,514.3 2619.67,559.36 2850.55,559.36 2866.48,575.28 3148.64,575.28 3185.4,612.05 ; 3185.43,612.05 3190.42,617.03 3304.13,617.03 3458.93,462.23 3503.62,462.23 3636.27,329.58 3687.8,329.58 3738.51,278.86 3760.13,278.86 3833.19,351.92 3879.92,351.92 3906.69,378.69 4001.81,378.69 v1(4037.93,414.81)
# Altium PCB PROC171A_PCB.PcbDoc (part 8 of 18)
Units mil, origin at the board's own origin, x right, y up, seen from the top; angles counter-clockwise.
Board outline 7700 x 2300 mil, 6 copper layers (Top Layer, GND 1, SIG 1, SIG 2, GND 2, Bottom Layer), stack 61.062 mil thick; 945 components, 692 nets, 11945 pads, 1734 vias.

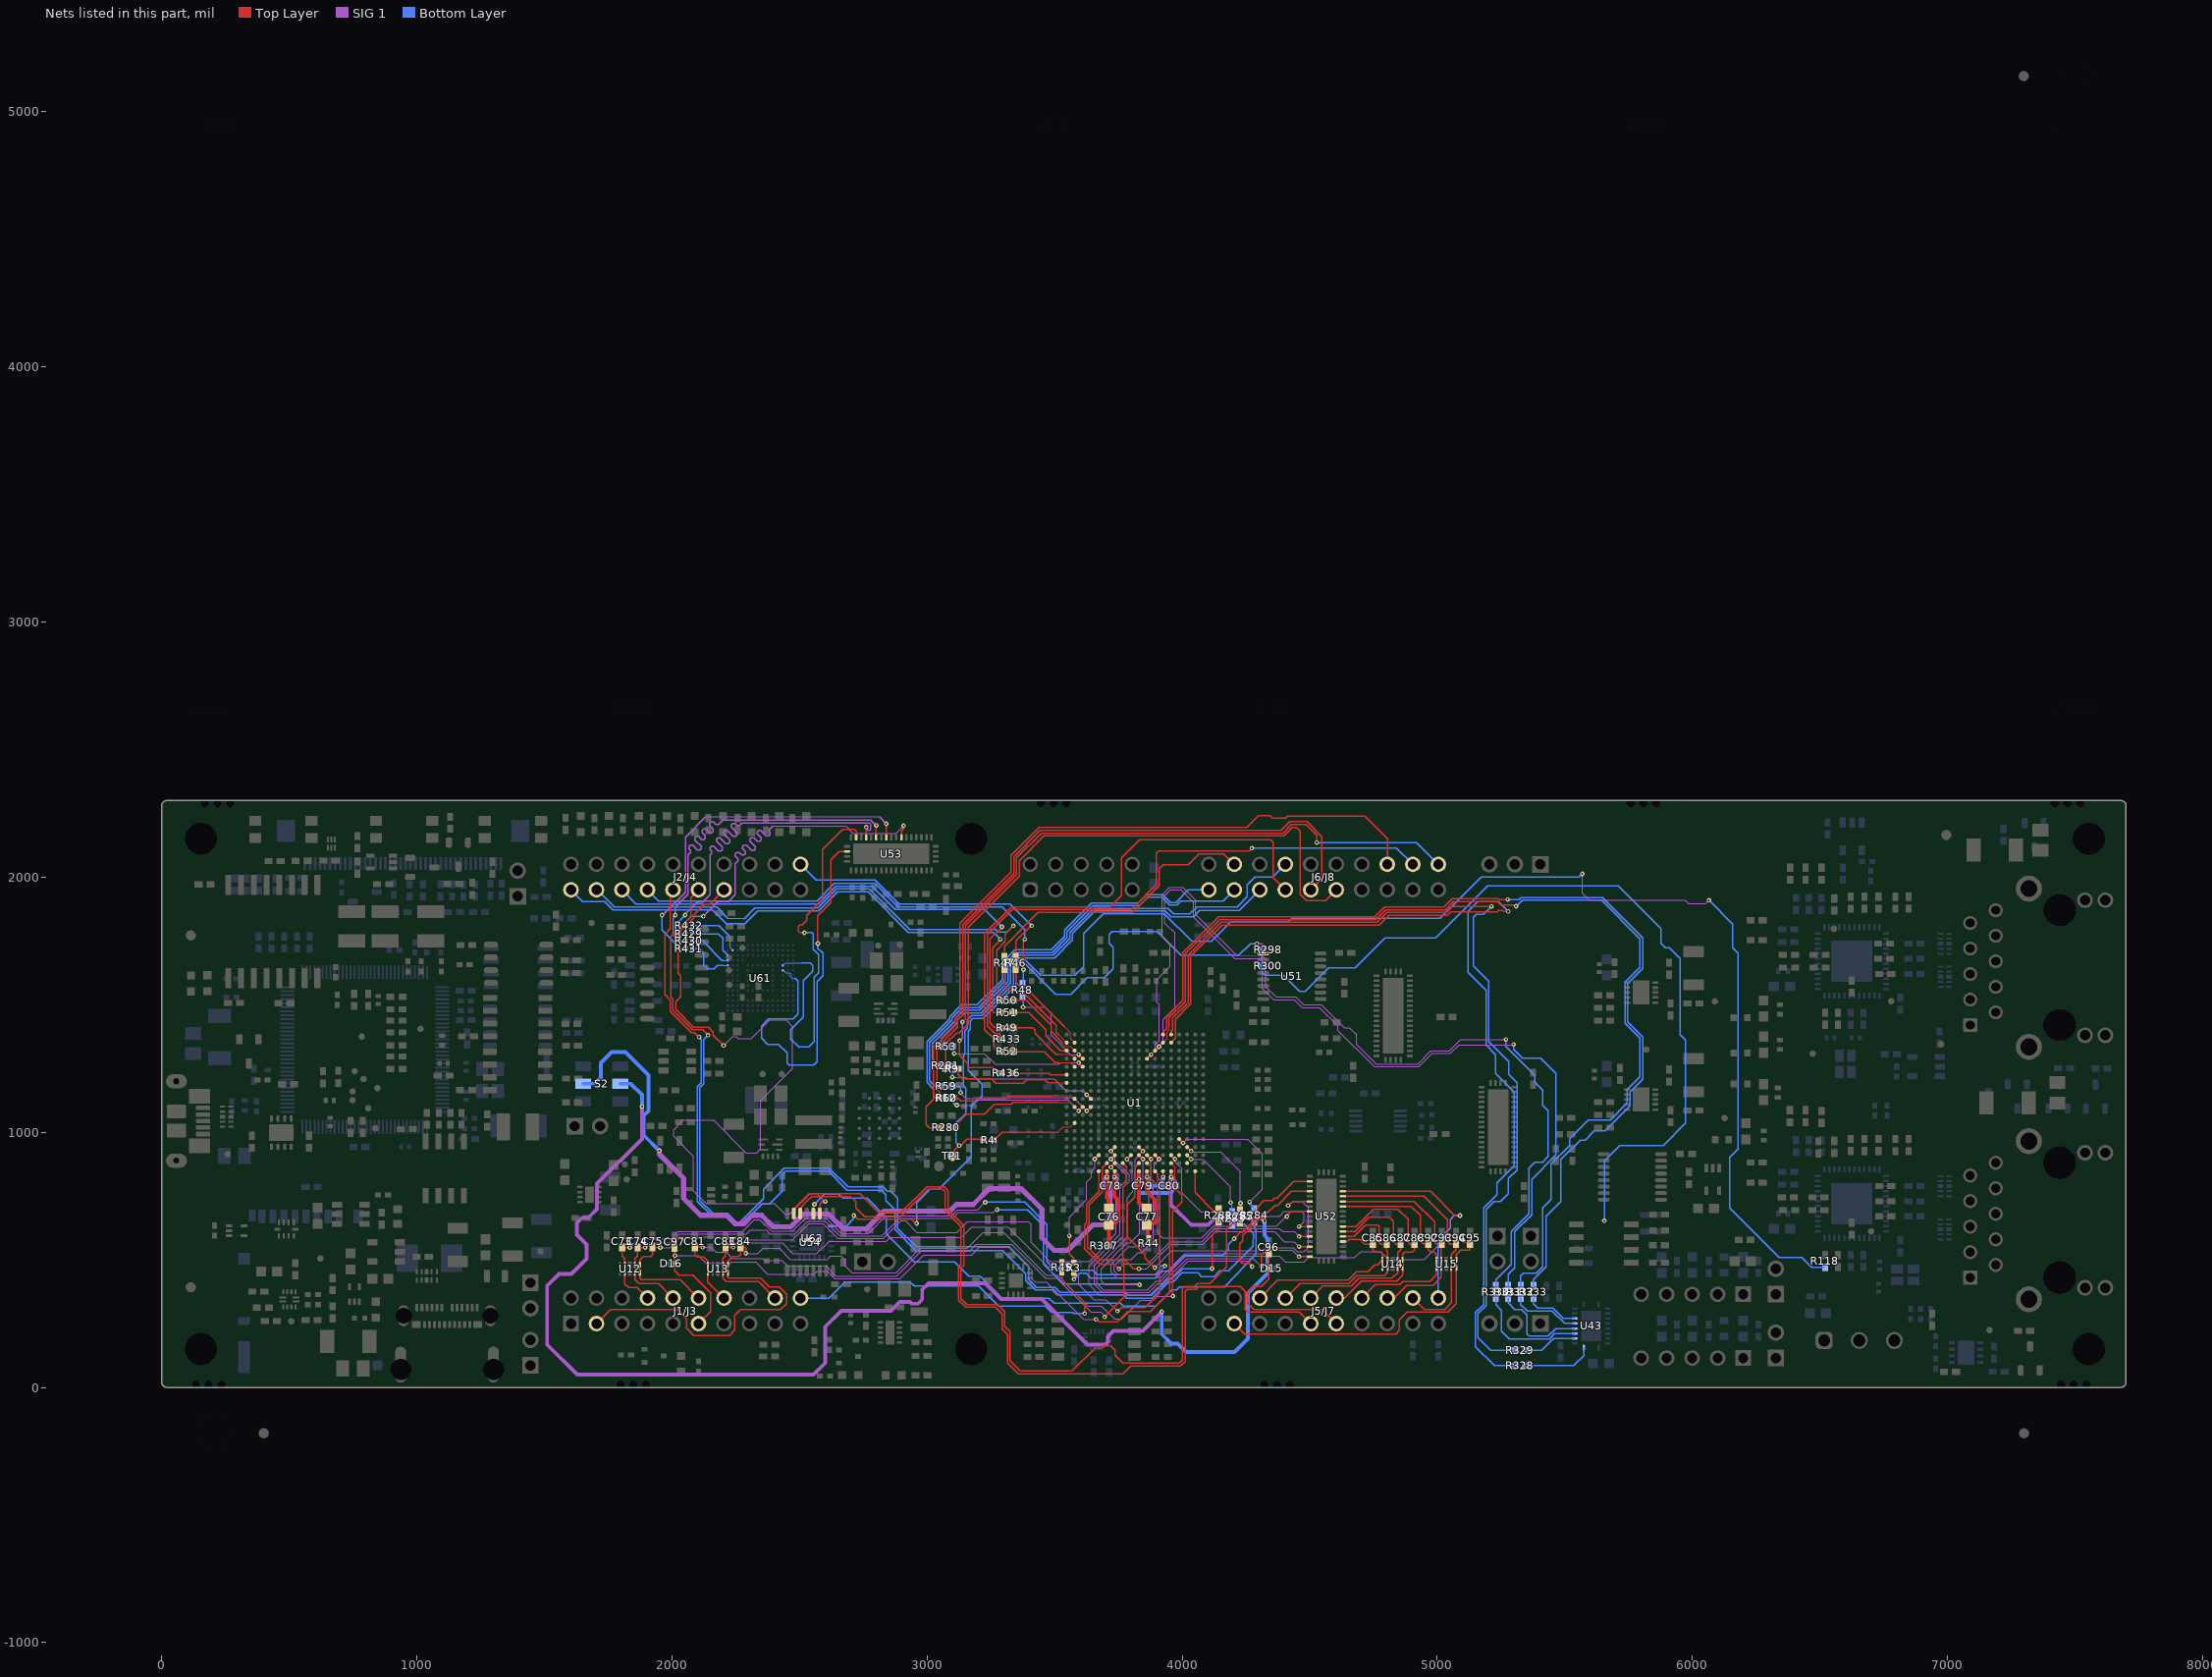
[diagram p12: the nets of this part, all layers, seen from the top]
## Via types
v1: diameter 18, hole 8, Top Layer to Bottom Layer, tented both sides, 1603 vias
v2: diameter 19.68, hole 7.87, Top Layer to Bottom Layer, tented both sides, 104 vias
v3: diameter 19.68, hole 7.87, Top Layer to Bottom Layer, 24 vias
v4: diameter 18, hole 8, Top Layer to Bottom Layer, 3 vias

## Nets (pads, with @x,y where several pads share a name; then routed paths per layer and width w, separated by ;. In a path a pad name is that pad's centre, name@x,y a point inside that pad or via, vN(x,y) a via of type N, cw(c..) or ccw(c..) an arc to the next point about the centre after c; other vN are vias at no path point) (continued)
AM263P_ADC0_AIN2: U1.T14 U52.32 | length 790.2
  Top Layer w5.3: v1(4458.39,630.63) U52.32@4500.04,630.63
  Top Layer w10: U1.T14@3956.58,910.35 v1(3972.33,894.61)
  SIG 1 w4.75: v1(3972.33,894.61) 3972.33,885.08 3999.43,857.98 3999.43,762.5 4073.08,688.86 4305.29,688.86 4323.32,670.83 4381.38,670.83 4399.8,689.25 4465.75,689.25 4477.03,677.97 4477.03,649.27 v1(4458.39,630.63)
AM263P_ADC0_AIN2_LIN1_TXD: C88.1 J5/J7.66 U14.5 U14.6 U52.7 | length 873.4
  Top Layer w5.3: J5/J7.66@4604.17,350 4635.87,350 4703.06,417.19 4841.67,417.19 4864.37,439.89 U14.5@4864.37,467.68 U14.6@4864.37,500.55 4864.37,521.74 4871.94,529.31 4902.1,529.31 4910,537.21 4910,560.42 C88.1@4911.11,561.53 4893.47,561.53 4885,570 4885,658.91 4846.33,697.58 4749.37,697.58 4682.42,630.63 U52.7@4629.96,630.63
AM263P_ADC0_AIN3: C84.1 J1/J3.2 U1.U14 U13.5 U13.6 | length 3949.2
  Top Layer w4: U1.U14@3956.58,878.86 3972.4,863.04 3972.4,816.09 3972.18,815.87
  Top Layer w5.3: J1/J3.2@1704.17,250 1759.17,305 2022.85,305 2057.7,270.15 2057.7,231.07 2085.4,203.37 2226.16,203.37 2246.16,223.37 2246.16,281.95 2269.09,304.88 2424.91,304.88 2449.05,329.02 2449.05,363.97 2420.06,392.97 2382.1,392.97 2347.72,427.35 2224.46,427.35 2219.37,432.44 U13.6@2219.37,481.44 2219.37,494.53 2238.22,513.38 2261.62,513.38 2269,520.76 C84.1@2269,548.85 2286.31,548.85 2289.41,545.75 v1(2289.41,525.59) ; v1(3963.8,357.77) 3962.18,359.38 3962.18,688.13 3999.52,725.47 3999.52,753.11 3972.18,780.46 3972.18,815.87
  SIG 1 w4.75: v1(2289.41,525.59) 2290.99,524.01 2336.11,524.01 2357.35,545.25 2420.66,545.25 2463.73,502.18 2609.18,502.18 2621.48,514.47 2663.63,514.47 2679.36,498.75 2679.36,475.87 2706.03,449.2 2878,449.2 2973.79,544.99 3157.68,544.99 3219.4,606.71 3299.85,606.71 3467.48,439.08 3512.17,439.08 3632,319.25 3683.52,319.25 3734.24,268.53 3764.4,268.53 3837.47,341.6 3887.89,341.6 3904.06,357.77 v1(3963.8,357.77)
AM263P_ADC1_AIN0: C73.1 J1/J3.24 U1.T11 U12.2 U12.9 | length 3548.7
  Top Layer w5.3: v1(1835,548.33) C73.1@1805,548.33 1805,515.82 1815.31,505.51 1815.31,405.72 1830,391.04 1863.14,391.04 J1/J3.24@1904.17,350
  Top Layer w10: U1.T11@3862.09,910.35 v1(3877.84,894.61)
  SIG 1 w4.75: v1(1835,548.33) 1868.5,581.83 1994.64,581.83 2024.06,611.25 2276.97,611.25 2322.58,656.86 2344.56,656.86 2389.37,612.05 2472.24,612.05 2522.24,662.05 2604.38,662.05 2662.51,603.92 2770.23,603.92 2839.23,672.92 3096,672.92 3118.98,695.9 3198.34,695.9 v1(3228.03,725.58) ; v1(3877.84,894.61) 3877.84,792.22 3888.06,782 3888.06,574.31 3842.27,528.52 3827.48,528.52 3799.98,501.02 3757.27,501.02 3738.02,481.78 3736.78,480.54 3732.87,476.63 3732.87,456.31 3747.29,441.9 3900.58,441.9 3932.06,473.38 v1(3932.06,475.69)
  Bottom Layer w5.3: v1(3228.03,725.58) 3382.64,725.58 3469.57,638.65 3469.57,493.7 3504.61,458.66 3649.62,458.66 3665.84,442.44 3894,442.44 3912.56,461 3912.56,469.38 3918.78,475.6 3931.97,475.6 v1(3932.06,475.69)
AM263P_ADC1_AIN1: C83.1 J1/J3.29 U1.U11 U13.4 U13.7 | length 2844.3
  Top Layer w4: U1.U11@3862.09,878.86 3877.84,863.11 3877.84,818.36 3880.34,815.87
  Top Layer w5.3: v1@2240,548.85 C83.1@2210,548.85 2210,515.31 2199.68,505 U13.7@2199.68,481.44 U13.4@2199.68,448.56 2199.68,428.15 2213.11,414.72 2339.45,414.72 J1/J3.29@2404.17,350 ; v1(3746.24,298.98) 3747.96,298.98 3761.59,312.6 3854.57,312.6 3912.24,370.28 3912.24,600.79 3912.15,600.88 3912.15,717.06 3912.24,717.15 3912.24,783.96 3880.34,815.87
  SIG 1 w4.75: v1(2240,548.85) 2258.02,566.87 2431.42,566.87 2473.67,524.63 2567.66,524.63 2616.46,573.42 2840.97,573.42 2854.95,587.4 3134.6,587.4 3175.66,628.47 3317.88,628.47 3473.79,472.55 3554.06,472.55 3574.45,452.16 3594.84,431.77 3594.84,403.13 3653.65,344.32 3700.9,344.32 v1(3746.24,298.98)
AM263P_ADC1_AIN2: U1.T12 U52.29 | length 973.5
  Top Layer w5.3: v1(4411.13,670) 4411.13,673.36 4427.46,689.69 U52.29@4500.04,689.68
  Top Layer w10: U1.T12@3893.59,910.35 v1(3909.34,894.61)
  SIG 1 w4: 3890.46,850 3890.46,874.7 3909.34,893.58 v1(3909.34,894.61)
  SIG 1 w4.75: 3890.46,850 3904.9,835.56 3904.9,605 3923.79,586.11 4077.9,586.11 4123.81,632.03 4369.81,632.03 4407.78,670 v1(4411.13,670)
AM263P_ADC1_AIN2_SDFM0_D2: C92.1 J5/J7.67 U15.1 U15.10 U52.11 | length 926.3
  Top Layer w5.3: U52.11@4629.96,709.37 4897.79,709.37 4933.44,673.72 4933.44,574.11 4945.18,562.38 C92.1@4965,562.38 4965,540 4975,530 4988.59,530 4996.03,522.56 U15.10@4996.03,500.69 U15.1@4996.03,467.82 4996.03,440.53 4970.21,414.7 4865.21,414.7 4852.93,402.43 4756.6,402.43 J5/J7.67@4704.17,350
AM263P_ADC1_AIN3: C97.1 D16.1 J1/J3.6 U1.V12 | length 3136.8
  Top Layer w4: U1.V12@3893.59,847.36 3905,835.95 3905,822.02 3911.16,815.87
  Top Layer w5.3: C97.1@2010,547.76 2011.57,546.19 v1(2011.57,516.57) 2011.04,516.04 2011.04,490.55 2010.51,490.03 2010.51,457.6 2028.08,440.03 2082.25,440.03 2151,371.28 2151,296.83 J1/J3.6@2104.17,250 ; v1(3662.42,266.64) 3665.23,266.64 3675.81,256.06 3745.82,256.06 3787.78,298.02 3876.43,298.02 3951.58,373.17 3951.58,775.44 3911.16,815.87
  SIG 1 w4.75: v1(2011.57,516.57) 2102.93,516.57 2134.4,485.1 2227.96,485.1 2233.72,490.87 2327.69,490.87 2374.29,444.26 2557.26,444.26 2568.43,455.43 2609.27,455.43 2637.92,426.77 2894.97,426.77 2986.41,518.21 3174.31,518.21 3204.95,548.85 3320.22,548.85 3411.9,457.17 3411.9,424.98 3424.55,412.33 3467.27,412.33 3612.97,266.64 v1(3662.42,266.64)
AM263P_ADC2_AIN0: C74.1 J1/J3.25 U1.R10 U12.4 U12.7 | length 3387.4
  Top Layer w5.3: v1(1895,548.33) C74.1@1865,548.33 1865,514.79 1854.68,504.48 U12.7@1854.68,480.91 U12.4@1854.68,448.04 1854.68,422.25 1870,406.94 1947.24,406.94 J1/J3.25@2004.17,350
  Top Layer w10: U1.R10@3830.6,941.85 v1(3846.35,926.1)
  SIG 1 w4.75: v1(1895,548.33) 1914.25,567.58 1995.86,567.58 2029.49,601.2 2291.98,601.2 2307.72,616.95 2370.26,616.95 2385.21,602 2481.74,602 2531.74,652 2598.93,652 2657.06,593.87 2822.53,593.87 2891.52,662.87 3100.16,662.87 3123.14,685.85 3260.71,685.85 3271.36,696.5 v1(3274.95,696.5) ; v1(3832.75,402.43) 3696.51,402.43 3682.23,416.7 3682.23,464.48 3783.89,566.14 3796.1,566.14 3832.75,602.79 3832.75,778.4 3815,796.15 3815,894.76 v1(3846.35,926.1)
  Bottom Layer w5.3: v1(3274.95,696.5) 3393.99,696.5 3455.71,634.78 3455.71,484.14 3535.56,404.29 3830.88,404.29 v1(3832.75,402.43)
AM263P_ADC2_AIN1: U1.T10 U52.38 | length 1406.9
  Top Layer w5.3: v1(4458.39,512.52) U52.38@4500.04,512.52
  Top Layer w10: U1.T10@3830.6,910.35 v1(3846.35,894.61)
  SIG 1 w4: v1(3846.35,894.61) 3847,893.95 3847,815.87
  SIG 1 w4.75: 3847,815.87 3847,799.35 3870.75,775.6 3870.75,581.13 3841.51,551.89 3791.41,551.89 3722.31,482.79 3722.31,450.92 3742.28,430.95 3916.07,430.95 4010.44,525.32 4319.85,525.32 4331.45,536.92 4431.9,536.92 4456.3,512.52 v1(4458.39,512.52)
AM263P_ADC2_AIN1_MCAN5_RX: C85.1 J5/J7.63 U14.1 U14.10 U52.4 | length 798.2
  Top Layer w5.3: J5/J7.63@4304.17,350 4374.17,420 4650.72,420 4683.57,452.85 4728.83,452.85 4755.22,479.24 4765.78,479.24 4778.42,491.88 4778.42,495.68 4783.39,500.66 4785.53,500.66 U14.10@4785.63,500.55 ; U52.4@4629.96,571.57 4630.14,571.76 4646,571.76 4654.69,580.45 4696.71,580.45 4715.63,561.53 C85.1@4747.11,561.53 4747.11,538.93 4755.01,531.03 4778.29,531.03 4785.63,523.69 U14.10@4785.63,500.55 ; U14.1@4785.63,467.68 U14.10@4785.63,500.55
AM263P_ADC2_AIN2: U1.U10 U52.27 | length 1464.1
  Top Layer w5.3: U1.U10@3830.6,878.86 3813.63,861.89 3813.63,745.2 3785.48,717.06 3785.48,589.52 3854.78,520.22 3854.78,507.45 v1(3892.72,469.51) ; v1(4415.63,712.91) 4416.63,712.91 4432.77,729.06 U52.27@4500.04,729.06
  SIG 1 w4.75: v1(3892.72,469.51) 3958.79,535.58 4315.89,535.58 4328.49,548.18 4434.86,548.18 4451.27,531.77 4477.64,531.77 4495.75,549.88 4495.75,703.31 4470,729.06 4432.77,729.06 4429.21,725.5 v1(4415.63,712.91)
AM263P_ADC2_AIN2_SDFM0_CLK2: C93.1 J5/J7.68 U15.2 U15.9 U52.12 | length 879.3
  Top Layer w5.3: U52.12@4629.96,729.06 4909.46,729.06 4990,648.51 4990,570 4998.33,561.67 5015.48,561.67 C93.1@5017.97,561.67 5015.72,559.42 U15.2@5015.72,467.82 5015.72,432.26 4983.46,400 4879.37,400 4829.37,350 J5/J7.68@4804.17,350
AM263P_ADC2_AIN3: C95.1 J5/J7.42 U1.T9 U15.5 U15.6 | length 3419
  Top Layer w5.3: J5/J7.42@4204.17,250 4245.85,208.32 4836.86,208.32 4852.06,223.52 4852.06,265 4881.8,294.74 5041.07,294.74 5074.77,328.45 U15.5@5074.77,467.82 U15.6@5074.77,500.69 5074.77,519.94 5092.55,537.72 5123.8,537.72 5128.54,542.46 C95.1@5128.54,561.67 5124.09,566.12 5111.88,566.12 v1(5101.72,576.29)
  Top Layer w10: v1(3783.35,894.61) U1.T9@3799.1,910.35
  SIG 1 w4.75: v1(3783.35,894.61) 3804.95,873.01 3804.95,791.99 3806.82,790.12 3806.82,766.43 3785,744.61 3785,587.4 3665.68,468.08 3665.68,406.97 3690.28,382.37 3864.55,382.37 3899.48,417.3 3916.63,417.3 4014.6,515.27 4380.93,515.27 4404.26,491.94 4478.29,491.94 4495.4,509.06 4676.74,509.06 4700.21,532.53 4777.82,532.53 4809.77,500.59 4948.7,500.59 5024.4,576.29 v1(5101.72,576.29)
AM263P_ADC3_AIN0: C75.1 J1/J3.26 U1.U7 U12.5 U12.6 | length 2824.4
  Top Layer w5.3: v1(1954,548.33) C75.1@1924,548.33 1924,520.24 1916.62,512.86 1887.02,512.86 1874.37,500.2 U12.6@1874.37,480.91 U12.5@1874.37,448.04 1874.37,428.47 1880,422.84 2031.34,422.84 J1/J3.26@2104.17,350
  Top Layer w10: v1(3720.36,863.11) U1.U7@3736.11,878.86
  SIG 1 w4: v1@3720.36,862.49 v1(3720.36,863.11)
  SIG 1 w4.75: v1(1954,548.33) 1990.82,548.33 2032.75,590.25 2286.87,590.25 2298.68,578.45 2472.4,578.45 2535.9,641.95 2591.84,641.95 2650.31,583.47 2829.03,583.47 2898.38,652.82 2914.87,652.82 2959.62,608.07 3116.64,608.07 3157.14,648.57 3397.39,648.57 3407.02,638.93 3407.02,567.96 3481,493.99 3637.06,493.99 3695.11,552.04 3741.83,604.69 3741.83,786.42 3750.08,794.67 3750.08,832.77 v1@3720.36,862.49
AM263P_ADC3_AIN1: U1.U8 U52.36 | length 1218
  Top Layer w5.3: U1.U8@3767.61,878.86 3782.13,864.33 3782.13,798.59 3768.05,784.5 3768.05,506.27 3809.61,464.7 v1(3830.03,464.7) ; v1(4458.39,551.89) U52.36@4500.04,551.89
  SIG 1 w4.75: v1(3830.03,464.7) 3860.69,464.7 3957.08,561.09 4081.3,561.09 4130.17,609.96 4136.7,609.96 4136.84,610.1 4362.33,610.1 4401.28,571.14 4439.14,571.14 v1(4458.39,551.89)
AM263P_ADC3_AIN1_MCAN5_TX: C86.1 J5/J7.64 U14.2 U14.9 U52.5 | length 812.1
  Top Layer w5.3: J5/J7.64@4404.17,350 4462.03,407.86 4653.57,407.86 4684.1,438.39 4792.53,438.39 4805.31,451.17 U14.2@4805.31,467.68 U14.9@4805.31,500.55 4805.31,533.2 4802.11,536.4 C86.1@4802.11,561.53 4780.42,561.53 4772.38,569.58 4772.38,630 4765.84,636.54 4719.02,636.54 4673.74,591.26 U52.5@4629.96,591.26
AM263P_ADC3_AIN2: U1.T7 U52.25 | length 1817.1
  Top Layer w5.3: v1(4274.32,473.35) 4274,473.35 4262.17,485.18 4235.93,485.18 4226.54,494.58 4226.54,563.49 4237.5,574.46 4237.5,595.21 4325.55,683.26 4333.87,683.26 4364,713.38 4373.5,713.38 4428.54,768.43 U52.25@4500.04,768.43
  Top Layer w10: v1(3720.36,894.61) U1.T7@3736.11,910.35
  SIG 1 w4.75: v1(3720.36,894.61) 3720.36,893.05 3781.11,832.3 3781.11,811.39 3756.08,786.36 3756.08,598.79 3634.41,477.12 3634.41,402.25 3674.38,362.27 3875.67,362.27 3906.97,393.58 3921.53,393.58 4023.13,495.17 4252.49,495.17 v1(4274.32,473.35)
AM263P_ADC3_AIN2_SDFM0_D3: C94.1 J5/J7.69 U15.4 U15.7 U52.13 | length 987.1
  Top Layer w5.3: U52.13@4629.96,748.74 4948.18,748.74 5040.31,656.61 5040.31,573.23 5051.87,561.67 C94.1@5073,561.67 5073,538 5055.09,520.09 U15.7@5055.09,500.69 U15.4@5055.09,467.82 5055.09,331.25 5029.53,305.69 4948.48,305.69 J5/J7.69@4904.17,350
AM263P_ADC3_AIN3: C96.1 D15.2 J5/J7.46 U1.R7 | length 2071.7
  Top Layer w5.3: v1(4310.31,473.53) 4310.31,518.74 4317.89,526.31 C96.1@4339.72,526.31 4339.72,467.6 D15.2@4338.78,466.66 4338.78,423.78 4310,395 4282.16,395 4257.41,370.25 4257.41,329.77 4281.66,305.53 4548.64,305.53 J5/J7.46@4604.17,250
  Top Layer w10: v1(3720.36,926.1) U1.R7@3736.11,941.85
  SIG 1 w4: v1(3720.36,926.1) 3736.86,909.61 3736.86,888.39 3791.97,833.28 3791.97,815.87 3791.97,808.04
  SIG 1 w4.75: 3791.97,808.04 3768.32,784.39 3768.32,590.88 3655.63,478.18 3655.63,402.81 3686.12,372.32 3870.48,372.32 3905.14,406.97 3920.72,406.97 4018.96,505.22 4278.62,505.22 v1(4310.31,473.53)
AM263P_ADC4_AIN0: C81.1 J1/J3.27 U1.U6 U13.1 U13.10 | length 2855.7
  Top Layer w5.3: v1@2120,548.85 C81.1@2090,548.85 2090,520 2098.65,511.35 2124.65,511.35 2140.63,495.36 U13.10@2140.63,481.44 U13.1@2140.63,448.56 2140.63,413.54 J1/J3.27@2204.17,350 ; v1(3696.42,275.58) 3696.42,278.47 3771.65,353.7 3771.65,485.44 3757.09,500 3679.58,500 3629.29,550.3 3629.29,634.29 3635.93,640.93 3635.93,714.5 3687.64,766.21 3687.64,861.89 U1.U6@3704.61,878.86
  SIG 1 w4.75: v1(2120,548.85) 2152.78,548.85 2172.03,529.6 2212.13,529.6 2236.64,505.09 2355.91,505.09 2363.18,497.82 2430.85,497.82 2452.96,475.71 2603.2,475.71 2642.08,436.82 2879.84,436.82 2977.54,534.52 3166.56,534.52 3193.23,561.19 3330.96,561.19 3463.64,428.52 3508.52,428.52 3642.53,294.5 3680.39,294.5 3696.42,278.47 v1(3696.42,275.58)
AM263P_ADC4_AIN1: U1.V5 U52.34 | length 1318.7
  Top Layer w5.3: U1.V5@3673.12,847.36 3673.12,766.68 3625.33,718.89 3625.33,645.32 3618.69,638.68 3618.69,544.2 3680.24,482.64 3733.79,482.64 v1(3752.12,464.31) ; v1(4458.39,591.26) U52.34@4500.04,591.26
  SIG 1 w4.75: v1(3752.12,464.31) 3752.12,465.22 3770.85,483.95 3865.73,483.95 3952.91,571.14 4077.13,571.14 4127.98,621.98 4382.08,621.98 4393.55,610.51 4439.14,610.51 v1(4458.39,591.26)
AM263P_ADC4_AIN1_LIN1_RXD: C87.1 J5/J7.65 U14.4 U14.7 U52.6 | length 837
  Top Layer w5.3: J5/J7.65@4504.17,350 4551.43,397.26 4662,397.26 4692.53,427.79 4822.45,427.79 4844.69,450.03 U14.4@4844.69,467.68 U14.7@4844.69,500.55 4844.69,527.99 4856.7,540 C87.1@4856.7,561.53 4838.47,561.53 4827.2,572.8 4827.2,651.1 4812.48,665.82 4732.61,665.82 4677.73,610.94 U52.6@4629.96,610.94
AM263P_ADC_CAL0: U1.U16
AM263P_ADC_CAL1: U1.T15
AM263P_ADC_VREFHI_G01: C77.1 C79.1 C80.1 S2.2 U1.V10 U1.V14 | length 6137.1
  Top Layer w15: U1.V10@3830.6,847.36 3831.11,846.85 v1(3831.11,816.77) 3831.11,810.33 3830.6,809.82 3830.6,723.99 3841.97,712.62 3850.13,712.62 3853.51,709.23 C77.1@3853.51,701.07 ; v1(3956.58,825) U1.V14@3956.58,847.36
  SIG 1 w15: v1(1882.41,1100.31) 1882.41,974.18 1706.52,798.29 1706.52,699.08 1672.28,664.84 1647.46,664.84 1627.34,644.73 1627.34,598.77 1665.77,560.34 1665.77,503.94 1606.09,444.26 1557.23,444.26 1510.73,397.76 1510.73,167.42 1628.33,49.82 2555.01,49.82 2600.42,95.23 2600.42,237.51 2663.58,300.67 2858.14,300.67 2892.09,334.63 2933.05,334.63 2939.75,327.93 2964.08,327.93 2980.76,344.62 2980.76,382.28 3006.98,408.5 3227.15,408.5 3288.73,346.92 3448.85,346.92 3627.73,168.03 3699.21,168.03 3709.39,178.21 3709.39,200.81 3730.44,221.86 3845.61,221.86 v1(3920,296.24) ; v1(3956.58,825) 3956.01,824.43 3956.01,822.3 3955.63,821.92 3955.63,719.49 3956.05,719.06 3956.05,716.42 4035.38,637.09 4101.11,637.09 4128.47,664.46 4308.23,664.46 4317.03,655.65 4317.17,655.65 4321.54,651.28 v1(4322.35,651.28)
  Bottom Layer w15: S2.2@1797.54,1190 1839.19,1190 1882.41,1146.78 v1(1882.41,1100.31) ; v1(3831.11,816.77) 3823.14,808.8 3823.14,789.94 3825.13,789.94 3829.44,785.63 3829.44,771.54 3838.22,762.75 3955.21,762.75 3964,771.54 3964,785.63 3968.31,789.94 C80.1@3972.24,789.94 3972.24,809.34 v1(3956.58,825) ; v1(3920,296.24) 3920,208.77 3957.29,171.48 3983.03,171.48 4016.69,137.82 4204.86,137.82 4257.94,190.9 4257.94,355 4258.29,355.35 4258.29,369.71 4334.93,446.35 4334.93,583.65 4322.35,596.23 v1(4322.35,651.28)
AM263P_ADC_VREFHI_G2: C76.1 C78.1 S2.5 U1.V6 | length 3368.9
  Top Layer w15: U1.V6@3704.61,847.36 v1(3704.61,825) 3704.61,742.32 3713.32,733.62 3713.32,698.14 C76.1@3713.17,698
  SIG 1 w8: 3704.49,800.8 3707.05,798.24 ; v1@3704.49,824.87 v1(3704.61,825)
  SIG 1 w20: v1(1950.75,927.95) 1950.75,914.12 2045.27,819.6 2045.27,741.3 2112.03,674.54 2214.47,674.54 2247.99,641.02 2281.74,641.02 2315.26,674.54 2351.88,674.54 2396.69,629.72 2464.91,629.72 2514.92,679.72 2613.41,679.72 2671.54,621.6 2762.14,621.6 2831.48,690.94 3089.02,690.94 3114.63,716.55 3180.64,716.55 3243.26,779.17 3369.01,779.17 3450,698.18 3450,585.76 3498.56,537.2 3550.76,537.2 3650.66,637.09 3700.33,637.09 3715.62,652.38 3715.62,789.67 3707.05,798.24 ; 3704.49,800.8 v1@3704.49,824.87
  Bottom Layer w15: S2.5@1651.87,1190 1697.96,1190 1721.8,1213.85 1721.8,1272.05 1763.82,1314.08 1816.93,1314.08 1907.31,1223.69 1907.31,1083.75 1889.85,1066.3 1889.85,988.19 v1@1950.09,927.95 ; C78.1@3696.74,789.94 3696.74,817.13 v1(3704.61,825)
AM263P_ADC_VREFLO_G01: C77.2 C79.2 C80.2 R44.2 U1.V11 U1.V13 | length 450
  Top Layer w4: v1(3925.09,825) U1.V13@3925.09,847.36
  Top Layer w15: C77.2@3861.07,637.7 3868.69,645.32 3893.65,645.32 3894.93,646.6 3894.93,733.21 3862.67,765.48 3862.67,815.87 3862.67,824.43 v1(3862.09,825) U1.V11@3862.09,847.36 ; C77.2@3864.29,628.58 3864.29,597.52 3867.19,594.61 3867.19,586.76 R44.2@3869.54,584.42
  Bottom Layer w15: v1(3862.09,825) 3862.09,824.19 3868.43,817.85 C79.2@3868.43,789.94 C80.2@3925,789.94 3925,824.91 v1(3925.09,825)
AM263P_ADC_VREFLO_G2: C76.2 C78.2 R307.2 U1.V7 | length 362.7
  Top Layer w15: R307.2@3713.62,555 3713.17,555.45 3713.17,635.99 3724.37,647.19 3740.05,647.19 3748.83,655.98 3748.83,733.91 3734.71,748.04 3734.71,815.87 3734.71,825.81 3736.11,827.21 U1.V7@3736.11,847.36
  Bottom Layer w15: v1(3734.71,825) 3735.28,824.43 3736.68,824.43 3743.98,817.13 C78.2@3743.98,789.94
AM263P_BP_MUX_SEL: R298.2 R300.2 U51.1 U63.7 | length 6337
  Top Layer w5.3: v1(2712.86,673.84) 2728.46,658.23 2940.7,658.23 2956.38,642.55 v1(2959.07,642.55) ; v1(4293.16,1739.19) 4294.02,1738.32 4312.76,1738.32 4317.8,1733.28 4317.8,1701.49 U51.1@4318.06,1701.23
  Bottom Layer w5.3: U63.7@2623.77,632.69 2683.9,632.69 2712.27,661.06 2712.27,673.24 v1(2712.86,673.84) ; v1(2959.07,642.55) 2959.07,723.56 3011.71,776.2 3045.69,776.2 3173.69,904.21 3173.69,1100.96 3215.19,1142.45 3215.19,1188.62 3161.21,1242.6 3161.21,1396.25 3169.22,1404.26 3169.22,1436.23 3179.91,1446.92 3219.93,1446.92 3348.77,1575.76 3348.77,1644.44 3366.83,1662.51 3382.13,1662.51 3503.4,1541.24 3562.92,1541.24 3627.8,1606.12 3694.35,1606.12 3729.57,1641.35 3729.57,1724.32 3713.62,1740.28 3713.62,1775.16 3725.58,1787.12 3902.05,1787.12 3994.92,1694.25 4222.83,1694.25 4267.91,1739.33 4309.78,1739.33 4312.89,1736.22 R298.2@4312.89,1715.49 R300.2@4312.89,1652.52 4312.89,1626.91 4324,1615.8 4397.07,1615.8 4461.07,1551.8 4481.43,1551.8 4573.29,1643.66 4677.59,1643.66 4795.94,1762 4993.86,1762 5197.32,1965.47 5710.03,1965.47 5876.5,1799 5876.5,1741.5 5894,1724 5908.74,1724 5951,1681.74 5951,1383.57 5972.85,1361.72 5972.85,1035.35 5885.7,948.2 5714.61,948.2 5655,888.59 5655,653.69 v1(5654.39,653.09)
AM263P_CLKOUT0: R4.2 R118.1 TP1.1 | length 5917
  Top Layer w5.3: TP1.1@3099.06,906.94 3105.3,913.18 3105.3,929.18 3126.31,950.19 3134.53,950.19 3142.67,958.33 3156.79,972.45 3217.83,972.45 R4.2@3221.22,969.06
  SIG 1 w4.75: v1(5568.36,2012.89) 5568.36,1937.74 5596.85,1909.25 5970.75,1909.25 5984.25,1895.75 6051.33,1895.75 v1(6065,1909.42)
  Bottom Layer w5.3: v1(3126.08,947.76) 3114.14,959.7 3114.14,1035.32 3151.1,1072.28 3151.1,1172.52 3141.87,1181.75 3141.87,1300.8 3148.67,1307.6 3148.67,1398.7 3158.48,1408.5 3158.48,1440.98 3175.02,1457.52 3215.54,1457.52 3338.17,1580.15 3338.17,1648.83 3362.44,1673.11 3386.52,1673.11 3444.63,1615 3580,1615 3613.9,1648.9 3613.9,1778.89 3691.48,1856.47 3929.07,1856.47 4038.21,1747.34 4113.29,1747.34 4190.89,1824.93 4415.03,1824.93 4429.02,1838.92 5010.58,1838.92 5172.52,2000.87 5556.33,2000.87 v1(5568.36,2012.89) ; v1(6065,1909.42) 6157.91,1816.51 6157.91,1723.92 6179.31,1702.52 6179.31,934.87 6146.9,902.46 6146.9,703.11 6340.09,509.92 6428.75,509.92 6467.3,471.38 R118.1@6520,471.38
AM263P_CLKOUT0_R: R4.1 U1.M2 | length 345.9
  Top Layer w4: 3515.64,1002.84 3533.39,1020.59 3562.88,1020.59 U1.M2@3578.63,1036.34
  Top Layer w5.3: R4.1@3260.59,969.06 3262.56,969.06 3293.6,1000.11 3512.9,1000.11 3515.64,1002.84
AM263P_DAC_OUT1: J1/J3.30 R45.1 | length 1389.3
  Top Layer w5.3: R45.1@3528.72,450.24 3528.72,420.58 3617.7,331.6 3617.7,289.13 v1(3617.78,289.05)
  Bottom Layer w5.3: J1/J3.30@2504.17,350 2615.95,350 2679.17,413.22 2933.13,413.22 2949.15,397.2 3202.61,397.2 3281.82,317.98 3464.43,317.98 3488.94,293.47 3571.12,293.47 3575.55,289.05 v1(3617.78,289.05)
AM263P_DAC_OUT2: R3.1 U52.23 | length 1158.8
  Top Layer w5.3: R3.1@3575.19,448.84 3575.58,448.46 v1(3575.58,423.81) ; v1(4204.17,583.26) 4227.69,606.78 4234.08,606.78 4294.17,666.87 4294.17,705.98 4319.99,731.8 4352.43,731.8 4362.41,741.77 4371.91,741.77 4437.93,807.8 U52.23@4500.04,807.8
  Bottom Layer w5.3: v1(3575.58,423.81) 3598.94,447.15 3623.25,447.15 3641.79,428.61 3895.16,428.61 3922.22,455.67 3945.93,455.67 4006.84,516.57 4157.73,516.57 4182.08,540.92 4182.08,561.18 v1(4204.17,583.26)
AM263P_DAC_OUT2_SDFM0_CLK3: J5/J7.70 U52.14 | length 870.1
  Top Layer w5.3: U52.14@4629.96,768.43 4973.69,768.43 5069.14,672.97 5087.95,672.97 v1(5088.74,673.76)
  Bottom Layer w5.3: J5/J7.70@5004.17,350 5004.17,577.29 5050.6,623.72 5050.6,657.19 5067.17,673.76 v1(5088.74,673.76)
AM263P_DAC_OUT_R: R3.2 R45.2 U1.T5 | length 523.2
  Top Layer w5.3: R45.2@3528.72,489.61 3573.8,489.61 R3.2@3574.55,488.85 ; v1(3557.81,594.15) 3557.81,521.62 3574.55,504.87 R3.2@3574.55,488.85 ; R3.2@3575.19,488.21 R3.2@3574.55,488.85
  Top Layer w10: v1(3657.37,894.61) U1.T5@3673.12,910.35
  SIG 1 w4: 3636.96,815.87 3645,823.91 3645,848.34 3657.37,860.71 v1(3657.37,894.61)
  SIG 1 w4.75: v1(3557.81,594.15) 3557.81,667.03 3626.32,735.54 3626.32,805.23 3636.96,815.87
AM263P_EMMC0_CLK_MUX: U53.40 U61.M6 | length 1619
  Top Layer w5.3: v1(2571.7,1739.46) 2571.7,1848.92 2622.73,1899.94 2622.73,2067.48 2656.13,2100.88 U53.40@2686.56,2100.88
  Bottom Layer w3.4: U61.M6@2435.29,1634.18 2444.97,1624.5 2460.46,1624.5 2464.47,1620.49 ; 2464.43,1620.49 2464.43,1610.75 2464.46,1610.71 2464.46,1610.57 2470.22,1604.82 2481.93,1604.82
  Bottom Layer w5.3: 2481.93,1604.82 2494.42,1592.33 2494.42,1463.14 2475.34,1444.06 2379.32,1444.06 2350.74,1415.48 2350.74,1382.11 2350.74,1368.63 2374.92,1344.45 2417.67,1344.45 2451.55,1310.56 2451.55,1270.73 2458.63,1263.66 2554.86,1263.66 2568.83,1277.63 2568.83,1590.29 2591.82,1613.28 2591.82,1701.57 2571.7,1721.69 v1(2571.7,1739.46)
AM263P_EMMC0_CMD_MUX: U53.37 U61.M5 | length 1619.6
  Top Layer w5.3: v1(2519.19,1782.19) 2499.54,1782.19 2495.38,1786.35 2495.38,1808.38 2498.48,1811.49 2509.14,1811.49 2528.12,1830.46 2528.12,1850.31 2590.93,1913.12 2590.93,2107.74 2669.77,2186.59 2714.68,2186.59 2721.99,2179.27 U53.37@2721.99,2156
  Bottom Layer w3.4: U61.M5@2434.92,1654.01 2441.81,1660.91 ; 2441.9,1660.82 2444.91,1663.84 2507.2,1663.84 2508.01,1663.03
  Bottom Layer w5.3: 2508.01,1663.77 2542.76,1663.77 2552.39,1654.15 2552.39,1630.83 2514.92,1593.36 2514.92,1451.26 2465.98,1402.32 2465.98,1382.11 2465.98,1365.72 2497.14,1334.56 2536.55,1334.56 2557.58,1355.6 2557.58,1382.11 2557.58,1608.21 2574.89,1625.52 2574.89,1695.83 2553.79,1716.93 2553.79,1776.2 2547.81,1782.19 v1(2519.19,1782.19)
AM263P_EMMC0_D0: R429.1 U61.A3 | length 204.6
  Bottom Layer w5.3: R429.1@2076.59,1776.94 2182.95,1776.94 2198.63,1761.25 2198.63,1714.22 2218.38,1694.48 U61.A3@2218.38,1693.38
AM263P_EMMC0_D0_MUX: R429.2 U53.35 | length 1418
  Top Layer w5.3: U53.35@2761.36,2156 v1(2761.37,2196)
  SIG 1 w5.3: v1(2051.87,1851.18) 2051.87,1854.41 2100.05,1902.59 2121.44,1902.59 2149.2,1930.35 2149.2,2087.06 2155.26,2093.12 2155.26,2101.73 2149.22,2107.77 2149.22,2116.38 2154.96,2122.12 2163.58,2122.12 2183.11,2102.59 2191.72,2102.59 2197.46,2108.33 2197.46,2116.94 2174.55,2139.86 2174.55,2148.47 2180.29,2154.21 2188.9,2154.21 2211.82,2131.3 2220.43,2131.3 2226.17,2137.04 2226.17,2145.65 2203.26,2168.56 2203.26,2177.18 2209,2182.92 2217.61,2182.92 2240.53,2160 2249.14,2160 2254.88,2165.75 2254.88,2174.36 2232.95,2196.29 2232.95,2204.9 2238.69,2210.64 2247.3,2210.64 2255.74,2202.21 2264.35,2202.21 2273.8,2211.66 2776.14,2211.66 2779.62,2208.18 2779.62,2187.11 2775.89,2183.38 2771.5,2183.38 2761.37,2193.51 v1(2761.37,2196)
  Bottom Layer w5.3: v1(2051.87,1851.18) 2025.55,1824.86 2025.55,1788.8 2037.41,1776.94 R429.2@2056.51,1776.94
AM263P_EMMC0_D1: R430.1 U61.A4 | length 173.1
  Bottom Layer w3.4: 2204.66,1673.7 U61.A4@2218.38,1673.7
  Bottom Layer w5.3: R430.1@2076.59,1749.33 2120.2,1749.33 2195.84,1673.7 2204.66,1673.7
AM263P_EMMC0_D1_MUX: R430.2 U53.33 | length 1444.7
  Top Layer w5.3: U53.33@2800.73,2156 v1(2800.74,2202.71)
  SIG 1 w5.3: v1@2013.35,1849.94 2013.35,1882.68 2063.14,1932.47 2063.14,2067 2063.16,2087.76 2072.28,2096.87 2072.28,2105.49 2067.44,2110.32 2067.44,2118.93 2073.19,2124.67 2081.8,2124.67 2099.8,2106.67 2108.41,2106.67 2114.15,2112.41 2114.15,2121.03 2090.27,2144.91 2090.27,2153.52 2096.01,2159.27 2104.62,2159.27 2116.45,2147.44 2125.06,2147.44 2130.8,2153.18 2130.8,2161.79 2118.98,2173.62 2118.98,2182.23 2124.72,2187.97 2133.33,2187.97 2147.21,2174.1 2155.82,2174.1 2161.56,2179.84 2161.56,2188.45 2147.68,2202.33 2147.68,2210.94 2153.43,2216.68 2162.04,2216.68 2172.76,2205.97 2181.37,2205.97 2199.43,2224.03 2779.41,2224.03 v1(2800.74,2202.71)
  Bottom Layer w5.3: v1(2013.35,1851.18) 2005.33,1843.15 2005.33,1773.06 2029.06,1749.33 R430.2@2056.51,1749.33
AM263P_EMMC0_D2: R431.1 U61.A5 | length 208.4
  Bottom Layer w3.4: 2201.3,1654.01 U61.A5@2218.38,1654.01
  Bottom Layer w5.3: R431.1@2076.59,1719.72 2107.64,1719.72 2125,1702.37 2125,1654.55 2139.29,1640.25 2164.28,1640.25 2178.04,1654.01 2201.3,1654.01
AM263P_EMMC0_D2_MUX: R431.2 U53.31 | length 1414
  Top Layer w5.3: U53.31@2840.1,2156 v1(2840.09,2208.88)
  SIG 1 w4.75: 2132.04,2236.15 2812.82,2236.15
  SIG 1 w5.3: v1(1960.83,1851.18) 1963.38,1851.18 2052.54,1940.33 2052.54,2126.92 ; 2052.56,2126.95 2052.56,2156.68 2132.04,2236.15 ; 2812.82,2236.15 v1(2840.09,2208.88)
  Bottom Layer w5.3: v1(1960.83,1851.18) 1960.83,1792.68 2033.8,1719.72 R431.2@2056.51,1719.72
AM263P_EMMC0_D3: R432.1 U61.B2 | length 226.7
  Bottom Layer w3.4: 2228.53,1765.41 2228.2,1765.09 2228.2,1722.93 U61.B2@2238.07,1713.07
  Bottom Layer w5.3: R432.1@2076.59,1810.15 2183.49,1810.15 2228.22,1765.41
AM263P_EMMC0_D3_MUX: R432.2 U53.28 | length 1395
  Top Layer w5.3: U53.28@2899.16,2156 2899.22,2156.06 2899.22,2179.04 2908.2,2188.02 v1(2908.21,2201.38)
  SIG 1 w4.75: 2395.73,2199.77 2681.56,2199.77 2710.13,2171.2 2878.53,2171.2 v1@2908.21,2200.88
  SIG 1 w5.3: v1(2122.97,1846.47) 2180.73,1904.23 2222.64,1904.23 2248.52,1930.11 2248.52,2052.55 2259.21,2063.25 2259.21,2071.86 2248.03,2083.05 2248.03,2091.66 2253.77,2097.4 2262.38,2097.4 2273.66,2086.13 2282.27,2086.13 2288.01,2091.87 2288.01,2100.48 2276.74,2111.76 2276.74,2120.37 2282.48,2126.11 2291.09,2126.11 2312.15,2105.06 2320.76,2105.06 2326.5,2110.8 2326.5,2119.41 2305.45,2140.47 2305.45,2149.08 2311.19,2154.82 2319.8,2154.82 2334.76,2139.86 2343.37,2139.86 2349.12,2145.6 2349.12,2154.21 2334.15,2169.18 2334.15,2177.79 2339.9,2183.53 2348.51,2183.53 2369.56,2162.47 2378.18,2162.47 2383.92,2168.22 2383.92,2176.83 2382.66,2178.09 2382.66,2186.7 2395.73,2199.77 ; v1@2908.21,2200.88 v1(2908.21,2201.38)
  Bottom Layer w5.3: R432.2@2056.51,1810.15 2056.51,1827.07 2075.91,1846.47 v1(2122.97,1846.47)
AM263P_EPWM0_A: J2/J4.11 R46.1 | length 1153.3
  Top Layer w5.3: R46.1@3347.99,1687.24 3347.99,1750.3 v1@3407.86,1810.17
  Bottom Layer w5.3: J2/J4.11@2504.17,2050 2564.82,1989.36 2795.63,1989.36 2891.06,1893.93 3325.41,1893.93 v1(3410.06,1809.27)
AM263P_EPWM0_A_R: R46.2 U1.B2 | length 396.2
  Top Layer w4: 3538.93,1414.29 3562.88,1390.34 3562.88,1367.05 U1.B2@3578.63,1351.3
  Top Layer w5.3: R46.2@3348.42,1641.72 3348.42,1587.04 3363.41,1572.05 3381.17,1572.05 3538.93,1414.29
AM263P_EPWM0_B: J6/J8.59 R47.1 | length 1148.9
  Top Layer w5.3: R47.1@3303.11,1687.17 3303.11,1729.93 3435.86,1862.69 3805.98,1862.69 3910.48,1967.18 3910.48,2032.84 3926.33,2048.69 4024.01,2048.69 4066.36,2091.04 4163.14,2091.04 J6/J8.59@4204.17,2050
AM263P_EPWM0_B_R: R47.2 U1.B1 | length 419.9
  Top Layer w4: 3515.26,1382.42 3516.01,1382.42 U1.B1@3547.13,1351.3
  Top Layer w5.3: R47.2@3303.11,1639.93 3303.11,1572.56 3323.1,1552.57 3373.87,1552.57 3506.5,1419.93 3506.5,1391.18 3515.26,1382.42
AM263P_EPWM1_A: J2/J4.37 R48.1 | length 1820.9
  Top Layer w5.3: v1(3377.87,1637.38) 3377.87,1747.78 3383,1752.91 v1(3383,1756.35)
  Bottom Layer w5.3: J2/J4.37@1904.17,1950 1948.04,1906.14 2568.11,1906.14 2636.76,1974.78 2795.21,1974.78 2886.67,1883.33 3293.67,1883.33 3383,1794 v1(3383,1756.35) ; R48.1@3373.91,1577.15 3377.87,1581.11 v1(3377.87,1637.38)
AM263P_EPWM1_A_R: R48.2 U1.D3 | length 413.8
  Top Layer w10: v1(3594.38,1304.06) U1.D3@3610.13,1288.31
  SIG 1 w4: v1(3376.47,1490.47) 3462.55,1490.47 3486.2,1466.82 3486.2,1380.22 3562.36,1304.06 v1(3594.38,1304.06)
  Bottom Layer w5.3: R48.2@3373.91,1533.84 3376.83,1530.93 v1@3376.83,1489.38
AM263P_EPWM1_B: J2/J4.38 R49.1 | length 2053.1
  Top Layer w5.3: R49.1@3289.22,1409.18 3265.83,1409.18 3247.06,1427.96 3247.06,1758.17 v1(3293.79,1804.9)
  Bottom Layer w5.3: J2/J4.38@1804.17,1950 1858.96,1895.21 2572.18,1895.21 2641.15,1964.18 2784.11,1964.18 2875.57,1872.73 3225.96,1872.73 v1(3293.79,1804.9)
AM263P_EPWM1_B_R: R49.2 U1.D2 | length 299.1
  Top Layer w4: 3515.64,1305.38 3561.56,1305.38 U1.D2@3578.63,1288.31
  Top Layer w5.3: R49.2@3336.46,1409.18 3413.55,1409.18 3423.09,1399.65 3423.09,1387.86 3491,1319.95 3505.57,1305.38 3515.64,1305.38
AM263P_EPWM2_A: J2/J4.39 R50.1 | length 2135.7
  Top Layer w5.3: R50.1@3289.22,1516.7 3289.22,1547.2 3272.65,1563.78 3272.65,1714.54 3306.37,1748.26 3306.37,1777.37 v1(3338.27,1809.27)
  Bottom Layer w5.3: J2/J4.39@1704.17,1950 1706.96,1950 1774.19,1882.77 2176.41,1882.77 2219.63,1839.55 2221.17,1838.02 2223.33,1838 2282.08,1837.44 2284.3,1837.44 2325.4,1878.54 2570.5,1878.54 2645.54,1953.58 2772.57,1953.58 2931.96,1794.19 3269.36,1794.19 3279.32,1784.23 3313.22,1784.23 v1(3338.27,1809.27)
AM263P_EPWM2_A_R: R50.2 U1.C2 | length 341
  Top Layer w4: 3529.96,1345.78 3540.19,1335.55 3562.88,1335.55 U1.C2@3578.63,1319.8
  Top Layer w5.3: R50.2@3336.46,1516.7 3388.62,1516.7 3486.25,1419.07 3486.25,1396.25 3529.96,1352.54 3529.96,1345.78
AM263P_EPWM2_B: J2/J4.40 R51.1 | length 2191.6
  Top Layer w5.3: v1@3285.67,1751.24 3285.17,1751.24 3282.13,1748.2 3282.13,1747.7 3257.66,1723.23 3257.66,1472.63 3260.76,1469.53 R51.1@3291.14,1469.53
  Bottom Layer w5.3: J2/J4.40@1604.17,1950 1649.13,1905.04 1736.24,1905.04 1769.12,1872.17 2158.57,1872.17 2212.62,1818.12 2285.61,1818.12 2335.43,1867.94 2574.89,1867.94 2649.93,1942.98 2768.18,1942.98 2927.57,1783.59 3259.6,1783.59 3274.69,1768.5 v1(3286.84,1756.35)
AM263P_EPWM2_B_R: R51.2 U1.C1 | length 286
  Top Layer w5.3: R51.2@3336.88,1469.02 3398.5,1469.02 3465.77,1401.75 3465.77,1377.91 3523.87,1319.8 U1.C1@3547.13,1319.8
AM263P_EPWM3_A: J6/J8.77 R52.1 | length 2074.5
  Top Layer w5.3: R52.1@3289.68,1316.91 3280.52,1326.07 3273.27,1326.07 3259.11,1340.23 3259.11,1369.14 3225.68,1402.56 3225.68,1779.4 3330.17,1883.89 3718.55,1883.89 3761.17,1926.51 3761.17,2075 3833.3,2147.13 4346.71,2147.13 4356.72,2137.13 4356.72,1997.46 J6/J8.77@4404.17,1950
AM263P_EPWM3_A_R: R52.2 U1.E2 | length 266.6
  Top Layer w4: 3515.64,1272.56 3562.88,1272.56 U1.E2@3578.63,1256.81
  Top Layer w5.3: R52.2@3336.92,1316.91 3338.39,1315.44 3459.09,1315.44 3501.97,1272.56 3515.64,1272.56
AM263P_EPWM3_B: J6/J8.78 R53.1 | length 1593.8
  Bottom Layer w5.3: R53.1@3055.32,1341.34 3055.32,1367.06 3119.43,1431.17 3119.43,1439.67 3147.88,1468.12 3211.15,1468.12 3327.57,1584.54 3327.57,1653.22 3358.05,1683.71 3499.45,1683.71 3570.48,1754.74 3570.48,1778.89 3658.66,1867.07 3933.76,1867.07 3955.93,1844.91 4044.74,1844.91 4068.75,1868.92 4223.09,1868.92 J6/J8.78@4304.17,1950
AM263P_EPWM3_B_R: R53.2 U1.E3 | length 563.6
  Top Layer w10: v1(3594.38,1272.56) U1.E3@3610.13,1256.81
  SIG 1 w4: 3523,1272.56 v1(3594.38,1272.56)
  SIG 1 w4.75: v1(3106.04,1308.64) 3106.46,1308.22 3226,1308.22 3267.22,1267 3518,1267 3523,1272
  Bottom Layer w5.3: R53.2@3094.69,1336.34 3096.87,1336.34 3106.04,1327.18 v1(3106.04,1308.64)
AM263P_EPWM4_A: J6/J8.52 R433.1 | length 2347.7
  Top Layer w5.3: 3242.84,1781.56 3236.28,1775.01 3236.28,1416.77 3268.14,1384.91 3284.23,1384.91 3288.52,1380.62 3288.52,1365.01 R433.1@3289.18,1364.34 ; 3243.5,1782.22 3334.56,1873.29 3801.59,1873.29 3899.52,1971.22 3899.52,2094.24 3908.34,2103.06 4263.05,2103.06 v1(4273.66,2113.67)
  Bottom Layer w5.3: v1(4273.66,2113.67) 4840.5,2113.67 J6/J8.52@4904.17,2050
AM263P_EPWM7_B: J6/J8.51 R436.1 | length 2854.8
  Top Layer w5.3: v1(3127.18,1359.13) 3126.58,1306.53 3126.58,1302.14 3160.26,1268.46 3160.26,1259.22 3166.37,1253.12 3256.09,1253.12 3268.38,1240.83 3280.91,1240.83 R436.1@3290.61,1231.13 ; v1(3138.95,1431.58) 3150.74,1443.36 3150.74,1809.39 3350.4,2009.05 3350.4,2074.89 3447.93,2172.42 4394.69,2172.42 4428.24,2205.96 4485.25,2205.96 4527.81,2163.41 v1(4527.81,2135.25)
  SIG 1 w5.3: v1@3127.03,1356.69 3138.95,1368.61 v1(3138.95,1431.58)
  Bottom Layer w5.3: v1(4527.81,2135.25) 4918.92,2135.25 J6/J8.51@5003.54,2050.64
AM263P_EPWM7_B_R: R436.2 U1.F1 | length 203.5
  Top Layer w5.3: R436.2@3341.77,1231.15 3477.47,1231.15 3483.99,1224.63 U1.F1@3542.6,1224.63
AM263P_EPWM9_A: J6/J8.75 R9.1 | length 2519.7
  Top Layer w5.3: R9.1@3073.65,1248.26 3073.65,1348.2 3114.71,1389.25 3125.59,1389.25 3161.34,1425 3161.34,1804.99 3361,2004.66 3361,2064.29 3458.53,2161.82 4399.09,2161.82 4432.04,2194.77 4449.25,2194.77 4462.95,2181.07 4462.95,1933.19 4487.68,1908.46 4562.63,1908.46 J6/J8.75@4604.17,1950
AM263P_EPWM9_A_R: R9.2 U1.G1 | length 473.1
  Top Layer w4: 3515.64,1193.82 U1.G1@3547.13,1193.82
  Top Layer w5.3: R9.2@3120.89,1248.26 3120.89,1226.7 3138.19,1209.4 3252.26,1209.4 3269.78,1191.88 3376.97,1191.88 3391.03,1205.95 3461.92,1205.95 3474.05,1193.82 3515.64,1193.82
AM263P_EPWM9_B: J6/J8.76 R12.1 | length 2589.6
  Top Layer w5.3: R12.1@3051.15,1135.05 3051.15,1154.05 3038.86,1166.34 3038.86,1331.24 3119.18,1411.57 3119.18,1412.19 3119.43,1412.43 3119.43,1439.67 3130.86,1451.11 3131.03,1451.11 3140.14,1460.22 3140.14,1813.78 3339.8,2013.44 3339.8,2079.28 3443.54,2183.02 4387.26,2183.02 4421.4,2217.16 4489.05,2217.16 4547.34,2158.87 4547.34,1993.16 J6/J8.76@4504.17,1950
AM263P_EPWM9_B_R: R12.2 U1.J2 | length 500.8
  Top Layer w4: 3515.64,1144.7 3564.76,1144.7 U1.J2@3578.63,1130.83
  Top Layer w5.3: R12.2@3098.4,1135.05 3118.95,1135.05 3131.99,1122 3185.18,1122 3193.51,1130.34 3306.41,1130.34 3317.49,1141.43 3491,1141.43 3496.43,1141.43 3499.7,1144.7 3515.64,1144.7
AM263P_EPWM12_A: J6/J8.53 R280.1 | length 2935.6
  Top Layer w5.3: R280.1@3049.29,1017.58 3009.05,1017.58 2996.12,1030.51 2996.12,1099.74 3025.35,1128.97 3025.35,1333.35 3108.83,1416.82 3108.83,1444.06 3129.35,1464.58 3129.35,1582.91 ; 3129.54,1582.91 3129.54,1819.46 3329.2,2019.12 3329.2,2085.2 3438.81,2194.81 4252.63,2194.81 4299.39,2241.58 4344.03,2241.58 4354.92,2230.69 4404.13,2230.69 4412.04,2238.61 4716.05,2238.61 4804.17,2150.49 J6/J8.53@4804.17,2050
AM263P_EPWM12_A_R: R280.2 U1.K2 | length 526.8
  Top Layer w4: 3515.64,1116.95 3561.01,1116.95 U1.K2@3578.63,1099.33
  Top Layer w5.3: R280.2@3100.47,1017.58 3153.11,1070.22 3165.45,1070.22 3165.64,1070.41 3225.88,1070.41 3264.61,1109.14 3329.71,1109.14 3337.7,1117.13 3512.82,1117.13 3512.99,1116.95 3515.64,1116.95
AM263P_EPWM12_B: J6/J8.57 R281.1 | length 1873.8
  Bottom Layer w5.3: R281.1@3037.12,1269.75 3020.86,1286.01 3020.86,1347.59 3108.83,1435.56 3108.83,1444.06 3143.49,1478.72 3205.72,1478.72 3316.97,1589.96 3316.97,1657.61 3353.66,1694.31 3495.06,1694.31 3559.88,1759.13 3559.88,1783.28 3654.27,1877.67 3944.31,1877.67 3966.21,1855.77 4030.05,1855.77 4057.93,1883.66 4215.5,1883.66 4254.82,1922.98 4254.82,1970 4284.82,2000 4354.17,2000 J6/J8.57@4404.17,2050 ; R281.1@3037.15,1269.75 R281.1@3044.58,1262.32
AM263P_EPWM12_B_R: R281.2 U1.J4 | length 623.1
  Top Layer w10: v1(3625.87,1146.57) U1.J4@3641.62,1130.83
  SIG 1 w4: 3578.32,1162.63 3609.82,1162.63 v1(3625.87,1146.57)
  SIG 1 w4.75: v1(3099.4,1215.66) 3152.36,1215.66 3157.66,1210.36 3497.79,1210.36 3545.53,1162.63 3578.32,1162.63
  Bottom Layer w5.3: R281.2@3097.49,1260.59 3099.4,1258.68 v1(3099.4,1215.66)
AM263P_EPWM13_A: J6/J8.79 R59.1 | length 1725.8
  Bottom Layer w5.3: R59.1@3051.38,1181.51 3030.75,1181.51 3010.26,1202 3010.26,1351.98 3098.23,1439.95 3098.23,1448.45 3139.1,1489.32 3201.33,1489.32 3306.37,1594.35 3306.37,1662.01 3349.27,1704.91 3490.67,1704.91 3549.28,1763.52 3549.28,1787.67 3649.88,1888.27 3832.78,1888.27 3865.62,1921.12 3919,1921.12 3950.24,1889.88 3979.5,1889.88 3995.45,1905.82 4159.99,1905.82 J6/J8.79@4204.17,1950
AM263P_EPWM13_A_R: R59.2 U1.K4 | length 609.7
  Top Layer w10: v1(3625.87,1083.58) U1.K4@3641.62,1099.33
  SIG 1 w4.75: v1(3131.58,1155.59) 3128.48,1155.59 3130.03,1154.04 3151.19,1132.88 3182.23,1132.88 3185.4,1136.05 3515.64,1136.05 3573.4,1136.05 3575.85,1133.61 v1(3625.87,1083.58)
  Bottom Layer w5.3: R59.2@3098.62,1181.51 3124.1,1181.51 3131.58,1174.03 v1(3131.58,1155.59)
AM263P_EPWM13_B: J6/J8.80 R60.1 | length 1694.6
  Bottom Layer w5.3: R60.1@3056.12,1135.05 3030.7,1135.05 3025.58,1140.16 3025.58,1169.7 2999.66,1195.62 2999.66,1356.38 3087.63,1444.34 3087.63,1452.84 3134.71,1499.92 3196.94,1499.92 3295.77,1598.74 3295.77,1666.4 3344.88,1715.51 3486.28,1715.51 3538.68,1767.91 3538.68,1792.06 3645.49,1898.87 3826.85,1898.87 3859.69,1931.72 3923.39,1931.72 3954.63,1900.48 3975.11,1900.48 4024.64,1950 J6/J8.80@4104.17,1950
AM263P_EPWM13_B_R: R60.2 U1.K3 | length 564.7
  Top Layer w10: v1(3594.38,1083.58) U1.K3@3610.13,1099.33
  SIG 1 w4.75: v1(3116.11,1106.47) 3116.22,1106.36 3169.92,1106.36 3189.56,1126 3491,1126 3551.96,1126 3579.87,1098.09 v1(3594.38,1083.58)
  Bottom Layer w5.3: R60.2@3101.4,1135.05 3101.4,1114.84 3107.33,1108.9 3113.68,1108.9 v1(3116.11,1106.47)
AM263P_EPWM14_A: J2/J4.35 R282.1 | length 4057.2
  Top Layer w5.3: J2/J4.35@2104.17,1950 2074.62,1920.45 2074.62,1846.32 1994.67,1766.37 1994.67,1531.6 2003.88,1522.4 2003.88,1478.04 2080.36,1401.56 2120.72,1401.56 v1(2141.83,1380.45) ; v1(4117.05,465.61) 4117.89,466.45 4117.89,597.56 4143,622.67 R282.1@4143,651.06
  Bottom Layer w5.3: v1(2141.83,1380.45) v1(2141.83,1380.45) 2125,1363.69 2125,1190.1 2109.83,1174.93 2109.83,733.1 2160.62,682.31 2217.09,682.31 2251.04,648.37 2267.21,648.37 2358.7,739.86 2358.7,777.37 2440.56,859.22 2615.5,859.22 2689.43,785.29 2826.91,785.29 2843.64,768.57 2857.72,768.57 2885.15,741.15 2885.15,622.6 2956.87,550.87 3320.62,550.87 3397.72,473.77 3397.72,423.25 3428.79,392.18 3502.7,392.18 3522.4,372.48 3776.04,372.48 3788.12,360.39 3878.65,360.39 3942.12,423.87 3959.1,423.87 4000.84,465.61 v1(4117.05,465.61)
AM263P_EPWM14_A_R: R282.2 U1.V17 | length 204.1
  Top Layer w5.3: U1.V17@4051.07,847.36 4051.07,763.99 4120.69,694.37 R282.2@4143,694.37
AM263P_EPWM14_B: J2/J4.36 R283.1 | length 4174.8
  Top Layer w5.3: J2/J4.36@2004.17,1950 1993.83,1939.66 1993.83,1797.86 1971.59,1775.63 1971.59,1539.69 1993.28,1518.01 1993.28,1473.65 2075.97,1390.96 2088.59,1390.96 v1(2106.62,1372.93)
  Bottom Layer w5.3: v1(2106.62,1372.93) 2106.62,1371.24 2114.4,1363.47 2114.4,1194.49 2099.23,1179.32 2099.23,728.71 2156.22,671.71 2156.83,671.71 2157.32,671.23 2213.19,671.23 2246.65,637.77 2271.6,637.77 2352.91,719.08 2382.08,719.08 2431.73,768.73 2431.73,832.09 2446.46,846.83 2612.91,846.83 2686.59,773.15 2821.31,773.15 2839.16,755.3 2839.16,731.91 2874.55,696.52 2874.55,618.2 2956.16,536.59 3296.37,536.59 3387.12,445.84 3387.12,418.86 3424.4,381.58 3490.77,381.58 3510.48,361.88 3771.65,361.88 3783.73,349.79 3883.04,349.79 3946.51,413.27 3963.49,413.27 3998.62,448.39 4061.7,448.39 4076.06,434.02 4125.13,434.02 4147.39,456.29 4181.34,456.29 4277.77,552.71 4279.6,603.95 4243.85,639.7 R283.1@4195.58,639.7
AM263P_EPWM14_B_R: R283.2 U1.T16 | length 321.7
  Top Layer w10: U1.T16@4019.57,910.35 v1(4035.32,894.61)
  SIG 1 w4.75: v1(4035.32,894.61) 4081.83,894.61 4190,786.43 v1(4190,724.36)
  Bottom Layer w4.75: v1@4192.03,723.35 4192.03,718.75 4195.58,715.19 R283.2@4195.58,686.94
AM263P_EPWM15_A: R284.1 U54.4 | length 2227.5
  Top Layer w5.3: U54.4@2554,681.41 2554,709.92 2558.64,714.57 v1(2558.64,718.01)
  Bottom Layer w5.3: v1(2558.64,718.01) 2598.51,757.87 2654.05,757.87 2670.73,741.18 2765.21,741.18 2841.2,665.2 2841.2,601.15 2949.85,492.5 3108.36,492.5 3164.31,436.55 3208.23,436.55 3294.99,349.78 3477.6,349.78 3497.53,329.85 3758.7,329.85 3770.56,317.99 3896.21,317.99 3959.68,381.47 3976.67,381.47 3988.27,393.07 4165.98,393.07 4167.58,394.67 4288.65,521.52 4288.73,521.6 4290.2,523.14 4290.2,618.62 4283.14,625.67 R284.1@4283.14,654.64
AM263P_EPWM15_A_BP: J2/J4.34 U54.3 | length 3029.9
  Top Layer w5.3: v1(2202.56,1340.16) 2161.35,1381.37 2161.35,1382.11 2161.35,1392.76 2143.18,1410.94 2141.96,1412.16 2084.75,1412.16 2014.48,1482.43 2014.48,1511.23 2033.72,1530.48 2033.72,1613.06 2023.5,1623.28 2023.5,1778.33 2085.22,1840.06 2085.22,1851.32 2129.23,1895.33 2149.5,1895.33 J2/J4.34@2204.17,1950 ; U54.3@2579.59,681.41 2579.59,719.53 2587.9,727.83 2599.56,727.83 v1(2600.42,728.69)
  SIG 1 w4.75: v1(2202.56,1340.16) 2238.16,1375.76 2251.18,1375.76 2258.79,1368.15 2311.86,1368.15 2383.32,1439.61 2447.08,1439.61 2472.42,1414.27 2472.42,1249.49 2348.3,1125.37 2348.3,935.59 2332.34,919.63 2290.88,919.63 2162.26,1048.26 2044.3,1048.26 2006.22,1010.18 2006.22,983.52 2083.51,906.24 2083.51,771 2134.64,719.87 2400.88,719.87 2441.24,679.51 2463.31,679.51 2542.61,758.81 2568.42,758.81 2598.54,728.69 v1(2600.42,728.69)
AM263P_EPWM15_A_R: R284.2 U1.P15 | length 611.6
  Top Layer w10: U1.P15@3988.08,973.35 v1(4003.83,957.6)
  SIG 1 w4: v1(4003.83,957.6) 4018.83,972.6 4041.54,972.6
  SIG 1 w4.75: 4041.8,972.86 4255.88,972.86 4314.45,914.29 4314.45,777.05 v1(4264.2,726.8)
  Bottom Layer w5.3: v1(4264.2,726.8) 4266.63,724.37 4266.63,718.54 4282.93,702.24 R284.2@4282.93,694.37
AM263P_EPWM15_B: R285.1 U54.7 | length 3049.8
  Top Layer w5.3: U54.7@2477.23,681.41 2477.23,697.16 2538.88,758.81 2735.45,758.81 2808.71,685.56 2898.09,685.56 2999.55,787.02 3066.87,787.02 3082.49,771.39 3082.49,695.98 3143.93,634.53 3143.93,478.25 3133.45,467.77 3133.45,346.61 3155.63,324.43 3276.55,324.43 3304.62,296.36 3304.62,240.26 3325.74,219.14 3325.74,104.04 3365.93,63.85 3568.5,63.85 3657.33,152.67 3681.89,152.67 3691.98,162.76 3719.43,162.76 3736.48,145.71 3736.48,126.66 3768.64,94.5 3988.89,94.5 4000.29,105.9 4000.29,387.36 4007.93,395 4048.05,395 4060.32,407.26 4108.58,407.26 4173.1,471.79 4173.1,618.19 4201.3,646.38 R285.1@4226.22,646.38
AM263P_EPWM15_B_BP: J5/J7.45 U54.6 | length 3164.7
  Top Layer w5.3: U54.6@2502.82,681.41 2504.82,683.41 2504.82,706.02 2531.13,732.34 2547.01,748.21 2700.1,748.21 2720.55,727.76 2720.55,702.97 2754.69,668.83 2896.81,668.83 3004.4,776.42 3062.48,776.42 3071.89,767 3071.89,691.59 3133.33,630.14 3133.33,482.64 3122.85,472.16 3122.85,342.22 3151.24,313.83 3267.82,313.83 3294.02,287.63 3294.02,228.21 3315.14,207.08 3315.14,95.39 3357.28,53.25 3768.41,53.25 3798.5,83.34 3993.84,83.34 4012.02,101.53 4012.02,376.85 4019.57,384.4 4053.64,384.4 4064.24,395 4227.85,395 4246.81,376.04 4246.81,307.48 4259.42,294.88 4459.3,294.88 J5/J7.45@4504.17,250
AM263P_EPWM15_B_R: R285.2 U1.R16 | length 402.2
  Top Layer w4.75: R285.2@4226.22,693.62 4226.22,719.42 v1(4228.56,721.75)
  Top Layer w10: U1.R16@4019.57,941.85 v1(4035.32,926.1)
  SIG 1 w4.75: v1(4035.32,926.1) 4037.75,923.67 4151.15,923.67 4228.56,846.27 v1(4228.56,721.75)
AM263P_EQEP0_A: R328.1 U1.B14 | length 3909
  Top Layer w5.3: U1.B14@3956.58,1351.3 3973.55,1368.27 3973.55,1442.96 4034.3,1503.71 4034.3,1690.61 4156.26,1812.57 4773.13,1812.57 4811.66,1851.09 5040.05,1851.09 5052.65,1863.69 5234.89,1863.69 5240.3,1869.1 5256.43,1869.1 5259.88,1865.65 v1(5278.53,1865.65)
  Bottom Layer w5.3: v1(5278.53,1865.65) 5239.36,1904.82 5159.86,1904.82 5120.1,1865.06 5120.1,1626.91 5191.17,1555.84 5191.17,1341.71 5228.38,1304.5 5228.38,1230 5301.68,1156.71 5301.68,867.97 5234.87,801.16 5234.87,756.18 5181.28,702.59 5181.28,325.13 5149.33,293.18 5149.33,159.5 5223.84,85 R328.1@5301.38,85
AM263P_EQEP0_A_R: R328.2 U43.1 | length 273.1
  Bottom Layer w5.3: R328.2@5348.62,85 5534.13,85 5574.13,125 U43.1@5574.13,155.98
AM263P_EQEP0_B: R329.1 U1.A14 | length 3654
  Top Layer w5.3: U1.A14@3956.58,1382.8 3956.85,1383.06 3956.85,1396.15 3962.95,1402.25 3962.95,1447.35 4023.7,1508.1 4023.7,1695 4151.87,1823.17 4765.54,1823.17 4804.06,1861.69 5035.66,1861.69 5059.26,1885.3 v1(5212.73,1885.3)
  Bottom Layer w5.3: v1(5212.73,1885.3) 5180.67,1853.25 5153.42,1853.25 5141.98,1841.81 5141.98,1652.51 5201.77,1592.72 5201.77,1354.98 5279.52,1277.22 5279.52,1226.22 5312.28,1193.47 5312.28,852.44 5277.71,817.88 5277.71,759.1 5247.88,729.26 5222.94,729.26 5191.88,698.2 5191.88,320.74 5159.93,288.79 5159.93,194.63 5209.47,145.09 R329.1@5301.38,145.09
AM263P_EQEP0_B_R: R329.2 U43.3 | length 209.3
  Bottom Layer w5.3: R329.2@5348.62,145.09 5409.09,145.09 5455.41,191.41 U43.3@5538.7,191.41
AM263P_EQEP0_INDEX: R330.1 U1.D11 | length 3645
  Top Layer w10: U1.D11@3862.09,1288.31 v1(3877.84,1304.06)
  SIG 1 w4: v1(3877.84,1304.06) 3894.34,1320.55 3894.34,1343.12 3910.09,1358.87 3910.09,1414.29
  SIG 1 w4.75: 3910.09,1414.29 3910.09,1501.49 3901.4,1510.18 3901.4,1598.41 3953.46,1650.48 3953.46,1735.45 3921.52,1767.39 3921.52,1931.31 3950.58,1960.37 4002.35,1960.37 4053.33,1909.4 4053.33,1853.66 4216.22,1690.77 4312.87,1692.8 4328.67,1677.01 4328.67,1569.21 4367.73,1530.14 4445.76,1530.14 4475.69,1500.21 4545.06,1500.21 4635.28,1410 4654.74,1410 4682.9,1381.84 4682.9,1344.88 4760.88,1266.9 4923.45,1266.9 4975.26,1318.71 5047.28,1318.71 5092.57,1364 5269.03,1364 v1(5269.14,1363.89)
  Bottom Layer w5.3: R330.1@5229.44,397.13 5229.44,421.97 5289.73,482.26 5289.73,611.02 5359.88,681.17 5359.88,860.04 5382.23,882.4 5412.4,882.4 5435,905 5435,1084.57 5413.5,1106.07 5413.5,1165.36 5382.23,1196.63 5382.23,1222.76 5269.14,1335.86 v1(5269.14,1363.89)
AM263P_EQEP0_INDEX_R: R330.2 U43.4 | length 447
  Bottom Layer w5.3: R330.2@5229.44,349.89 5229.44,323.53 5251.92,301.05 5251.92,219.93 5281.63,190.23 5439.23,190.23 5460.1,211.1 U43.4@5538.7,211.1
AM263P_EQEP0_STROBE: R331.1 U1.C12 | length 3598
  Top Layer w10: U1.C12@3893.59,1319.8 v1(3909.34,1335.55)
  SIG 1 w4: v1(3909.34,1335.55) 3925.83,1352.05 3925.83,1430
  SIG 1 w4.75: 3925.83,1430 3925.83,1442.32 3971.39,1487.88 3971.39,1780.89 3932.05,1820.23 3932.05,1927.63 3954.74,1950.32 3995.05,1950.32 4042.42,1902.95 4043.39,1844 4206.84,1680.55 4303.35,1680.55 4314.45,1669.45 4314.45,1563.43 4357.91,1519.97 4438.89,1519.97 4469.49,1489.37 4537.62,1489.37 4610.15,1416.84 4610.15,1398.81 4678.19,1330.76 4679.12,1330.76 4753.03,1256.85 4927.61,1256.85 4979.43,1308.66 5051.44,1308.66 5085.28,1342.5 5297.17,1342.5 v1(5299.19,1344.52)
  Bottom Layer w5.3: R331.1@5277.45,397.13 5277.45,442.72 5304.1,469.37 5304.1,610.4 5370.48,676.78 5370.48,815.42 5465.38,910.33 5465.38,1229.97 5405.35,1290 5334.9,1290 5299.19,1325.71 v1(5299.19,1344.52)
AM263P_EQEP0_STROBE_R: R331.2 U43.5 | length 389.8
  Bottom Layer w5.3: R331.2@5277.45,349.89 5277.45,331.1 5303.54,305 5330,305 5351.33,283.67 5351.33,209.7 5360.2,200.83 5434.84,200.83 5464.8,230.78 U43.5@5538.7,230.78
AM263P_EQEP2_A: R332.1 U1.B13 | length 4013.9
  Top Layer w4: U1.B13@3925.09,1351.3 3940.83,1367.05 3940.83,1392.36 3949.66,1401.19 3949.66,1414.29
  Top Layer w5.3: 3949.66,1414.29 3949.66,1449.05 4013.1,1512.49 4013.1,1699.39 4147.48,1833.77 4758.43,1833.77 4796.95,1872.29 5031.26,1872.29 5063.8,1904.82 5236.7,1904.82 5250.28,1891.24 5300.05,1891.24 5305.32,1885.97 v1(5308.76,1885.97)
  Bottom Layer w5.3: v1(5308.76,1885.97) 5310.2,1885.97 5333.66,1909.42 5643.13,1909.42 5794.52,1758.03 5794.52,1646.1 5736.23,1587.8 5736.23,1427.78 5794.52,1369.49 5794.52,1217.08 5744.4,1166.96 5744.4,1114.36 5678.15,1048.11 5591.4,1048.11 5518.6,975.3 5518.6,948.55 5445.79,875.74 5445.79,735.68 5413.06,702.96 5413.06,473.21 5387.95,448.1 5338.15,448.1 5327.45,437.4 R332.1@5327.45,397.13
AM263P_EQEP2_A_R: R332.2 U43.6 | length 266.9
  Bottom Layer w5.3: R332.2@5327.45,349.89 5327.45,325.16 5352.6,300 5449.54,300 5499.07,250.47 U43.6@5538.7,250.47
AM263P_EQEP2_B: R333.1 U1.A13 | length 3939.4
  Top Layer w5.3: U1.A13@3925.09,1382.8 3926.32,1384.03 3926.32,1393.32 3938.37,1405.37 3938.37,1452.75 4002.5,1516.88 4002.5,1703.79 4143.09,1844.37 4754.04,1844.37 4792.56,1882.89 5026.87,1882.89 5059.41,1915.42 5241.09,1915.42 5244.49,1912.02 v1(5276.04,1912.02)
  Bottom Layer w5.3: v1(5276.04,1912.02) 5321.26,1912.02 5329.27,1920.02 5647.52,1920.02 5805.12,1762.42 5805.12,1641.71 5746.83,1583.41 5746.83,1432.17 5805.12,1373.88 5805.12,1207.45 5755,1157.33 5755,1102.72 5657.28,1005 5614.98,1005 5579.67,969.69 5561.6,969.69 5484.84,892.93 5484.84,727.99 5426.85,670 5426.85,472.01 5377.45,422.6 R333.1@5377.45,397.13
AM263P_EQEP2_B_R: R333.2 U43.7 | length 207.4
  Bottom Layer w5.3: R333.2@5377.45,349.89 5377.45,327.55 5394.4,310.6 5453.93,310.6 5494.38,270.15 U43.7@5538.7,270.15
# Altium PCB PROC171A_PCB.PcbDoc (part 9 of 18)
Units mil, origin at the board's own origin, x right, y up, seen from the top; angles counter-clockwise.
Board outline 7700 x 2300 mil, 6 copper layers (Top Layer, GND 1, SIG 1, SIG 2, GND 2, Bottom Layer), stack 61.062 mil thick; 945 components, 692 nets, 11945 pads, 1734 vias.

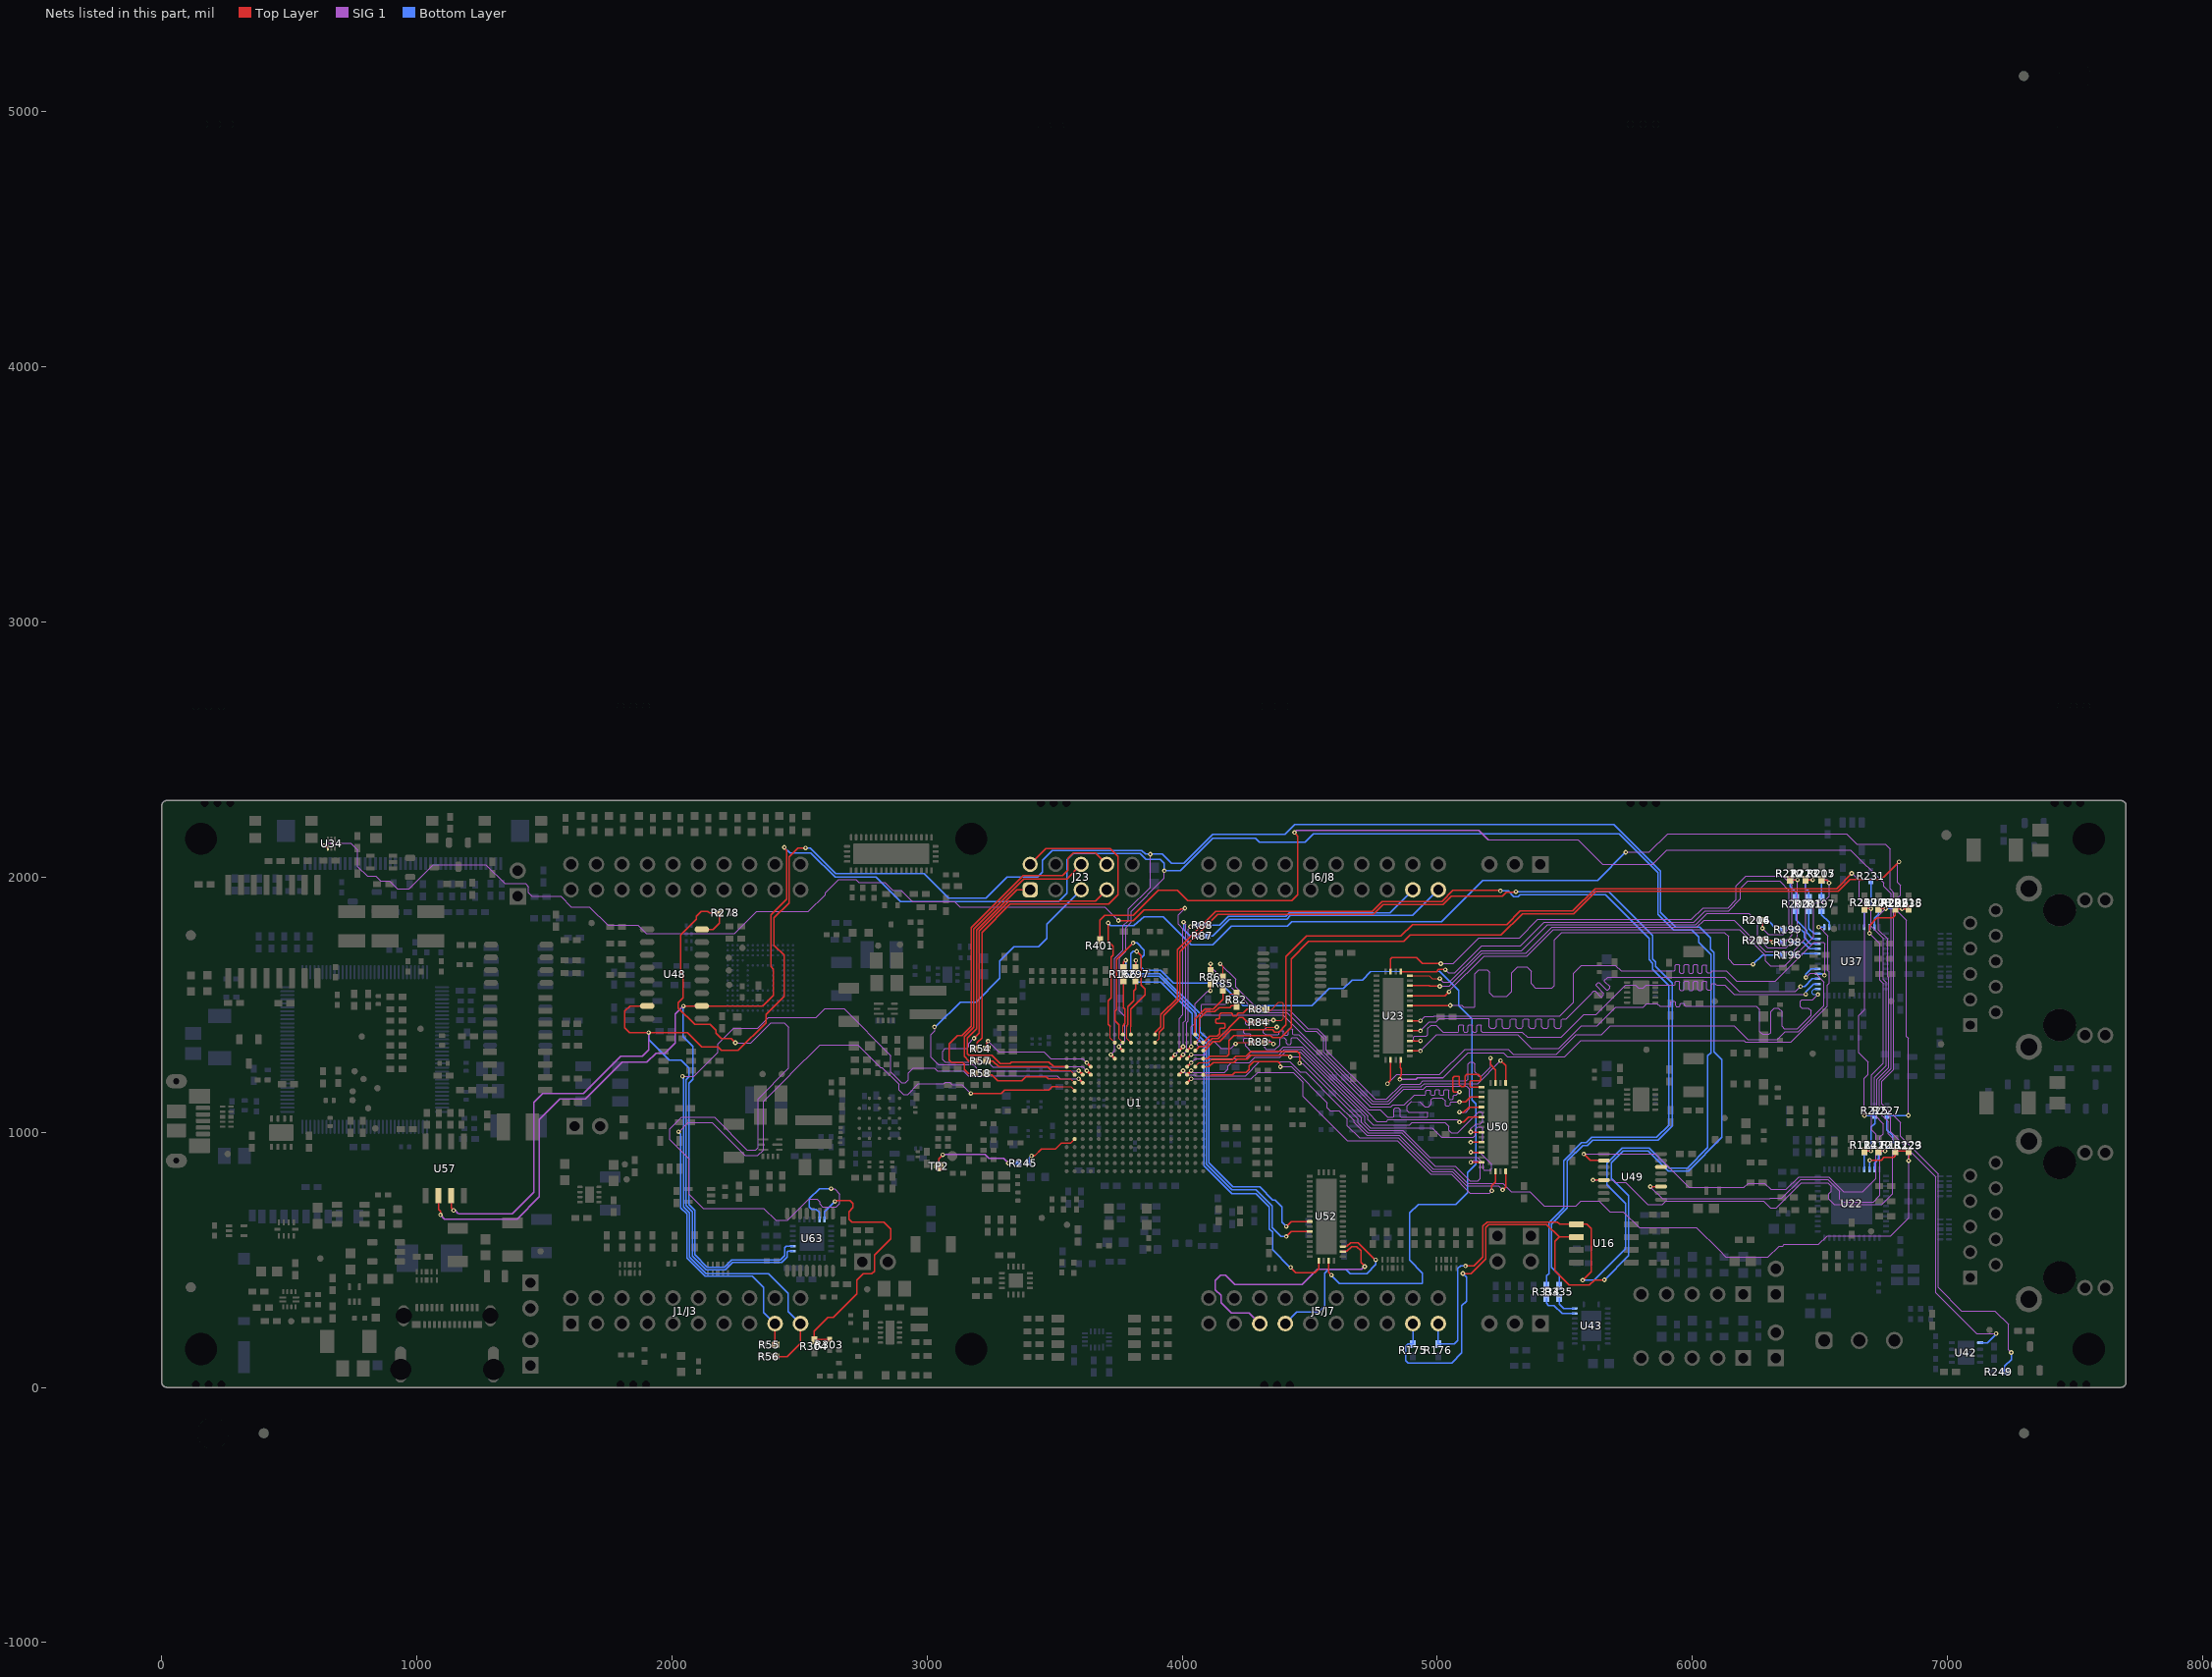
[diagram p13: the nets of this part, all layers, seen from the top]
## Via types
v1: diameter 18, hole 8, Top Layer to Bottom Layer, tented both sides, 1603 vias
v2: diameter 19.68, hole 7.87, Top Layer to Bottom Layer, tented both sides, 104 vias
v3: diameter 19.68, hole 7.87, Top Layer to Bottom Layer, 24 vias
v4: diameter 18, hole 8, Top Layer to Bottom Layer, 3 vias

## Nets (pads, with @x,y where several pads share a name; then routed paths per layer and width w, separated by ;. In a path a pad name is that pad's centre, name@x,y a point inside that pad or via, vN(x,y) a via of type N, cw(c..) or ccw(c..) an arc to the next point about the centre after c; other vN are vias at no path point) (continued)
AM263P_EQEP2_INDEX: R334.1 U1.A12 | length 4151.6
  Top Layer w5.3: U1.A12@3893.59,1382.8 3895.28,1384.49 3895.28,1392.88 3916.69,1414.29 3916.69,1461.05 3980.57,1524.93 3980.57,1715.51 4130.63,1865.57 4745.26,1865.57 4783.78,1904.09 5018.09,1904.09 5061.62,1947.62 5246.01,1947.62 v1(5247.69,1945.94)
  Bottom Layer w5.3: v1(5247.69,1945.94) 5277.72,1945.94 5300.15,1923.52 5317.77,1923.52 5324.87,1930.62 5659.38,1930.62 5830,1760 5830,1676.8 5844.52,1662.28 5844.52,1637.83 5907.5,1574.85 5907.5,1027.26 5860.24,980 5604.97,980 5584.06,959.09 5565.99,959.09 5495.44,888.54 5495.44,702.96 5437.45,644.97 5437.45,446.35 5428.06,436.97 R334.1@5428.06,397.13
AM263P_EQEP2_INDEX_R: R334.2 U43.8 | length 147.2
  Bottom Layer w5.3: R334.2@5428.06,349.89 5428.06,330 5436.86,321.2 5458.32,321.2 5489.68,289.84 U43.8@5538.7,289.84
AM263P_EQEP2_STROBE: R335.1 U1.B12 | length 4192.7
  Top Layer w4: U1.B12@3893.59,1351.3 3910,1367.71 3910,1385
  Top Layer w5.3: 3910,1385 3910,1391.99 3927.64,1409.63 3927.64,1457.01 3991.29,1520.66 3991.29,1707.56 4138.7,1854.97 4749.65,1854.97 4788.17,1893.49 5022.48,1893.49 5055.01,1926.02 5255.38,1926.02 5270.45,1941.1 5306.3,1941.1 v1(5308.24,1943.04)
  Bottom Layer w5.3: v1(5308.24,1943.04) 5671.96,1943.04 5843.5,1771.5 5843.5,1679.5 5855.48,1667.52 5855.48,1650.65 5921,1585.12 5921,1025.46 5865,969.46 5865,969.4 5609.36,969.4 5588.45,948.49 5570.38,948.49 5510,888.11 5510,702.53 5448.05,640.58 5448.05,469.67 5478.01,439.71 R335.1@5478.01,397.13
AM263P_EQEP2_STROBE_R: R335.2 U43.9 | length 91.1
  Bottom Layer w5.3: R335.2@5478.01,349.89 5478.01,326.51 5495,309.52 U43.9@5538.7,309.52
AM263P_EXT_REFCLK0: R245.2 TP2.1 | length 363.6
  Top Layer w5.3: TP2.1@3046.89,866.63 3046.89,896.68 v1(3061.63,911.42)
  SIG 1 w5.3: v1(3061.63,911.42) 3062.87,912.67 3227.95,912.67 3243.11,897.5 3299.9,897.5 v1(3318.54,878.86)
  Bottom Layer w5.3: v1@3317.75,877.43 3356.3,877.43 R245.2@3358.26,879.39
AM263P_EXT_REFCLK0_R: R245.1 U1.P2 | length 230.8
  Top Layer w6: v1@3409.5,905.14 3412.6,908.24 3422.07,908.24 3448.46,934.62 3491,934.62 3503.71,934.62 3526.16,957.07 3563.22,957.07 3578.63,972.48 U1.P2@3578.63,973.35
  Bottom Layer w6: R245.1@3397.63,879.39 3399.6,881.36 3399.6,897.62 v1(3409.42,907.44)
AM263P_FSIRX1_CLK: J23.1 U1.E1 | length 1191.5
  Top Layer w5.3: J23.1@3404.17,1950 3351.31,1950 3193.88,1792.57 3193.88,1406.29 3157.31,1369.72 3157.31,1308.22 3164.4,1301.12 3254.65,1301.12 3287.22,1268.54 3324.45,1268.54 3330.96,1275.05 3477.96,1275.05 3496.2,1256.81 U1.E1@3547.13,1256.81
AM263P_FSIRX1_DATA0: J23.5 U1.F3 | length 1619.4
  Top Layer w10: v1(3594.38,1241.06) U1.F3@3610.13,1225.32
  SIG 1 w4: 3515.64,1241.06 v1(3594.38,1241.06)
  SIG 1 w4.75: v1(3028.75,1413.07) 3030.54,1411.28 3030.54,1397.07 3015.66,1382.19 3015.66,1293.34 3044.56,1264.44 3181.29,1264.44 3204.67,1241.06 3515.64,1241.06
  Bottom Layer w5.3: v1(3028.75,1413.07) 3032.18,1413.07 3036.81,1417.7 3037.49,1417.7 3130.32,1510.52 3192.55,1510.52 3285.17,1603.14 3285.17,1670.79 3340.49,1726.11 3436.11,1726.11 3470,1760 3470,1815.83 J23.5@3604.17,1950
AM263P_FSIRX1_DATA1: J23.7 U1.F4 | length 1786.4
  Top Layer w5.3: v1(3184.29,1368.47) 3204.48,1388.67 3204.48,1788.18 3321.8,1905.5 3659.67,1905.5 J23.7@3704.17,1950
  Top Layer w10: v1(3625.87,1241.06) U1.F4@3641.62,1225.32
  SIG 1 w4: 3538.18,1257.18 3604.95,1257.18 3605.32,1256.81 3610.13,1256.81 v1(3625.87,1241.06)
  SIG 1 w4.75: v1(3184.29,1368.47) 3183.67,1368.47 3163.43,1348.23 3163.43,1336.01 3155.32,1327.89 3071.12,1327.89 3060.93,1317.71 3060.93,1284.83 3071.27,1274.49 3238,1274.49 3257.49,1255 3515.64,1255 3536,1255 3538.18,1257.18
AM263P_FSITX1_CLK: J23.2 R54.1 | length 1595.6
  Top Layer w5.3: R54.1@3186.06,1327.26 3187.98,1327.26 3197.14,1336.42 3197.14,1351.52 3215.08,1369.46 3215.08,1783.79 3325.78,1894.49 3711.88,1894.49 3748.22,1930.82 3748.22,2080.28 3717,2111.5 3465.67,2111.5 J23.2@3404.17,2050
AM263P_FSITX1_CLK_R: R54.2 U1.E4 | length 476.6
  Top Layer w5.3: R54.2@3233.31,1327.26 3233.31,1347.96 3239.25,1353.91 v1(3239.25,1357.34)
  Top Layer w10: v1(3625.87,1272.56) U1.E4@3641.62,1256.81
  SIG 1 w4: 3516.64,1288.5 3609.93,1288.5 v1(3625.87,1272.56)
  SIG 1 w4.75: v1(3239.25,1357.34) 3281.1,1315.5 3458.5,1315.5 3485.5,1288.5 3516.64,1288.5
AM263P_FSITX1_DATA0: J23.6 R57.1 | length 1087.5
  Top Layer w5.3: R57.1@3186.06,1279.26 3164.45,1279.26 3146.71,1297 3146.71,1368.05 3146.71,1374.11 3183.28,1410.68 3183.28,1796.96 3379.82,1993.5 3547.67,1993.5 J23.6@3604.17,2050
AM263P_FSITX1_DATA0_R: R57.2 U1.F2 | length 367.7
  Top Layer w4: 3515.64,1242.94 3561.01,1242.94 U1.F2@3578.63,1225.32
  Top Layer w5.3: R57.2@3233.31,1279.26 3258.46,1279.26 3280.45,1257.28 3472.21,1257.28 3486.55,1242.94 3515.64,1242.94
AM263P_FSITX1_DATA1: J23.8 R58.1 | length 1395.3
  Top Layer w5.3: R58.1@3186.06,1231.26 3162.28,1231.26 3146.69,1246.85 3146.69,1266.68 3140.31,1273.07 3096.41,1273.07 3086.08,1283.4 3086.08,1345.64 3119.1,1378.65 3136.26,1378.65 3172.68,1415.07 3172.68,1801.35 3377.83,2006.5 3532,2006.5 3553,2027.5 3553,2074 3573,2094 3660.17,2094 J23.8@3704.17,2050
AM263P_FSITX1_DATA1_R: R58.2 U1.G2 | length 372.7
  Top Layer w4: 3515.64,1209.57 3562.88,1209.57 U1.G2@3578.63,1193.82
  Top Layer w5.3: R58.2@3233.31,1231.26 3239.42,1225.14 3253.53,1225.14 3276.19,1202.48 3372.36,1202.48 3386.66,1216.78 3468.18,1216.78 3475.39,1209.57 3515.64,1209.57
AM263P_I2C1_SCL: J5/J7.49 R175.1 U1.D7 U16.6 U48.15 U57.3 U63.19 | length 12956
  Top Layer w5.3: U57.3@1134.51,751.17 1134.51,703.27 v1(1144.22,693.57) ; U48.15@1902.72,1495 1836.12,1495 1815.31,1474.19 1815.31,1409.36 1834.1,1390.57 v1(1908.57,1390.57) 2061.37,1390.57 2116.89,1335.05 2180.06,1335.05 2194.47,1320.63 2259.71,1320.63 2368.82,1429.75 2368.82,1461.98 2439.32,1532.48 2439.32,1694.13 2400.25,1733.2 2400.25,1840.08 2459.36,1899.19 2459.36,2078.89 2494.29,2113.81 2523.18,2113.81 v1(2523.43,2114.06) ; v1(5100.26,446.35) 5132.72,446.35 5189.5,503.14 5189.5,626.88 5200.52,637.89 5429.02,637.89 5477.76,589.14 ; U16.6@5545.51,589.14 5477.76,589.14 ; v1(5655,421.38) 5617.19,421.38 5596.29,400.48 5516.71,400.48 5460.6,456.59 5460.6,571.98 5477.76,589.14
  Top Layer w10: v1(3720.36,1304.06) U1.D7@3736.11,1288.31
  SIG 1 w4: v1(3720.36,1304.06) 3735.36,1319.06 3735.36,1414.29
  SIG 1 w4.75: 3735.36,1414.29 3735.36,1681.04 3768.42,1714.1 3768.42,1809.46 3788.96,1830 3788.96,1874.36 3875.05,1960.45 v1(3875.05,2090.05)
  SIG 1 w5.3: v1(1144.22,693.57) 1144.52,693.87 1150.08,693.87 1161.1,682.86 1161.23,682.86 1164.08,680 1374.68,680 1458.96,764.27 1458.96,1117.01 1493.24,1151.3 1652.8,1151.3 1800.19,1298.68 1884.78,1298.68 1908.57,1322.47 v1(1908.57,1390.57)
  Bottom Layer w5.3: v1(1908.57,1390.57) 1908.57,1364.17 1990.18,1282.56 2036.19,1282.56 2066.43,1252.31 2066.43,1216.29 2055.87,1205.73 2055.87,712.1 2079.4,688.57 2079.4,515.53 2134.33,460.6 2210.09,460.6 2238.88,489.39 2430.65,489.39 2451.91,510.65 2451.91,529.97 2456.2,534.26 U63.19@2474.16,534.26 ; v1(2523.43,2114.06) 2525.03,2113.81 2542.42,2113.81 2641.86,2014.38 2988.14,2014.38 3085.39,1917.13 3231.37,1917.13 3314.22,1999.98 3433.73,1999.98 3452.63,2018.87 3452.63,2064.92 3491.48,2103.78 3841.8,2103.78 3855.52,2090.05 v1(3875.05,2090.05) 3920.9,2090.05 3957.41,2053.54 4006.05,2053.54 4119.88,2167.38 4402.11,2167.38 4441,2206.27 5691.94,2206.27 5875.6,2022.6 5875.6,1861.33 5933.8,1803.13 6029.61,1803.13 6070.97,1761.78 6070.97,1716.79 6083.8,1703.95 6083.8,1316.2 6115.71,1284.29 6115.71,979.72 5984.47,848.48 5905.04,848.48 5827.42,926.1 5728.23,926.1 5682.27,880.14 5682.27,819.31 5749.4,752.17 5749.4,515.78 v1(5655,421.38) ; J5/J7.49@4904.17,250 4904.17,169.65 4885.38,169.65 4876.63,160.91 4876.63,104.53 4885.51,95.65 5056.73,95.65 5096.33,135.25 5096.33,320.86 5113.88,338.4 5113.88,432.22 5100.26,445.84 v1(5100.26,446.35)
AM263P_I2C1_SDA: J5/J7.50 R176.1 U1.C8 U16.5 U48.2 U57.2 U63.20 | length 12349.3
  Top Layer w5.3: U57.2@1084.51,751.17 1084.51,698.33 1092.5,690.34 v1(1092.5,675.88) ; v1(2044.99,1494.52) 2045.03,1494.57 2116.85,1494.57 U48.2@2117.28,1495 2355.72,1495 2397.81,1537.09 2397.81,1638.97 2387.33,1649.45 2387.33,1851.36 2448.76,1912.79 2448.76,2104.87 2440.58,2113.06 v1(2440.58,2116.49) ; v1(5110.77,475.86) 5143.13,475.86 5178.9,511.64 5178.9,631.27 5196.12,648.49 5471.25,648.49 5480.59,639.14 U16.5@5545.51,639.14 5586.18,639.14 5603.66,621.66 5603.66,453.66 v1(5570,420)
  Top Layer w10: v1(3751.86,1335.55) U1.C8@3767.61,1319.8
  SIG 1 w4: v1(3751.86,1335.55) 3775.62,1359.32 3775.62,1425.57
  SIG 1 w4.75: 3775.62,1425.57 3775.62,1453.13 3753.75,1475 3753.75,1685.22 3778.47,1709.93 3778.47,1802.62 3800,1824.15 3800,1866.12 3930,1996.12 v1(3930,2024.75)
  SIG 1 w5.3: v1(1092.5,675.88) 1109.03,659.35 1392.53,659.35 1480.31,747.13 1480.31,1050.57 1560.38,1130.65 1661.35,1130.65 1805.82,1275.11 1902.04,1275.11 1938.03,1310.45 1973.07,1310.45 2012.52,1349.9 2012.52,1462.69 2044.35,1494.52 v1(2044.99,1494.52)
  Bottom Layer w5.3: v1(2044.99,1494.52) 2043.96,1493.49 2043.96,1374.31 2082.6,1335.67 2082.6,1207.77 2066.47,1191.65 2066.47,716.49 2090,692.97 2090,519.92 2138.72,471.2 2205.7,471.2 2234.49,499.99 2424.35,499.99 2441.31,516.95 2441.31,547.87 2447.39,553.95 U63.20@2474.16,553.95 ; v1(2440.58,2116.49) 2460.98,2096.09 2462.53,2094.54 2545.02,2094.54 2546.57,2092.98 2639.6,1999.96 2800.02,1999.96 2895.45,1904.53 3516.69,1904.53 3548.85,1936.68 3548.85,2067.88 3574.14,2093.18 3835.03,2093.18 3857.68,2070.53 3913.88,2070.53 3930,2054.41 v1(3930,2024.75) 3993.14,2024.75 4120.54,2152.16 4287.38,2152.16 4302.31,2137.22 4481.18,2137.22 4514.52,2170.56 5712.65,2170.56 5865,2018.21 5865,1854.37 5926.84,1792.53 5998.02,1792.53 6025,1765.56 6025,1744.48 6073.2,1696.28 6073.2,1311.78 6060.48,1299.05 6060.48,939.48 5980.08,859.08 5909.44,859.08 5830.92,937.6 5724.74,937.6 5665.6,878.46 5665.6,793.26 5738.8,720.06 5738.8,543.9 5614.9,420 v1(5570,420) ; J5/J7.50@5004.17,250 R176.1@5004.17,169.65 5066.82,169.65 5080.73,183.56 5080.73,465.72 5090.88,475.86 v1(5110.77,475.86)
AM263P_I2C3_SCL: J1/J3.9 R55.1 U1.H2 | length 3158.9
  Top Layer w4: 3515.64,1177.69 3563.27,1177.69 U1.H2@3578.63,1162.32
  Top Layer w5.3: R55.1@2404.17,170 J1/J3.9@2404.17,250 ; v1(3171.61,1152.13) 3191.21,1151.54 3290.55,1151.54 3303.47,1164.47 3477.91,1164.47 3491.13,1177.69 3515.64,1177.69
  SIG 1 w4.75: v1(2025.75,1002.09) 2028.24,1002.09 2063.81,1037.66 2157.87,1037.66 2286.49,909.03 2336.73,909.03 2358.9,931.2 2358.9,1120.98 2465.35,1227.43 2465.35,1227.82 2580.45,1342.92 2727.97,1342.92 2816.37,1254.51 2823.95,1254.51 2890.83,1187.63 2890.83,1165.62 2907.96,1148.48 2924.07,1148.48 2964.95,1189.36 3065.88,1189.36 3073.32,1196.8 3088.21,1196.8 3098.1,1186.91 3136.83,1186.91 v1(3171.61,1152.13)
  Bottom Layer w5.3: v1(2025.75,1002.09) 2025.75,1001.56 2034.67,992.64 2034.67,703.32 2058.2,679.79 2058.2,506.75 2129.9,435.06 2315.8,435.06 2360,390.85 2360,294.17 J1/J3.9@2404.17,250
AM263P_I2C3_SDA: J1/J3.10 R56.1 U1.G3 | length 3420.5
  Top Layer w5.3: R56.1@2404.59,121 2452.33,121 2504.17,172.84 J1/J3.10@2504.17,250
  Top Layer w10: v1(3594.38,1209.57) U1.G3@3610.13,1193.82
  SIG 1 w4.75: v1(2041.52,1218.99) 2085.81,1218.99 2180.61,1313.79 2180.61,1345.43 2242.1,1406.92 2336.03,1406.92 2379.04,1449.94 2565.75,1449.94 2599.52,1483.71 2674.26,1483.71 2857.96,1300.01 2857.96,1235.47 2899.29,1194.13 2915.24,1194.13 2926.56,1205.45 2926.56,1232.74 2945.4,1251.58 3028.21,1251.58 3039.58,1240.21 3142.02,1240.21 3161.82,1220.41 3509.8,1220.41 3520.64,1209.57 v1(3594.38,1209.57)
  Bottom Layer w5.3: v1(2041.52,1218.99) 2043.95,1216.56 2043.95,1210.86 2045.27,1209.53 2045.27,707.71 2068.8,684.18 2068.8,511.14 2134.29,445.66 2379.01,445.66 2456.13,368.54 2456.13,298.04 J1/J3.10@2504.17,250
AM263P_ICSSM_MII0_COL: R207.1 R219.2 R231.2 U37.45 U49.11 | length 2477.7
  Top Layer w5.3: v1(5835,786.84) U49.11@5877.2,786.84 ; R207.1@6674.39,1876.46 v1(6700,1876.46)
  SIG 1 w4.75: v1(5835,786.84) 5881.84,740 6304.59,740 6305.65,741.06 6350.52,741.06 6424.46,815 6531.49,815 6578.11,768.37 6578.11,738.69 6589.88,726.92 6710,726.92 6735.75,752.67 6735.75,981.83 6748.64,994.71 6748.64,1033.27 6713.34,1068.57 6713.34,1215.64 6759.37,1261.68 6759.37,1322.67 6759.37,1586.7 6748.64,1597.44 6748.64,1759.67 6700,1808.31 v1(6700,1876.46)
  Bottom Layer w5.3: U37.45@6674.39,1803.9 R219.2@6674.39,1876.46 v1(6700,1876.46) R231.2@6700,1985
AM263P_ICSSM_MII0_CRS: U49.14
AM263P_ICSSM_MII0_RXCLK: R196.1 U23.32 | length 2156.6
  Top Layer w5.3: U23.32@4892.17,1495.87 4892.57,1496.28 5049.85,1496.28 v1(5050.92,1497.34)
  SIG 1 w4.75: v1(5050.92,1497.34) 5096.12,1497.34 5103.05,1490.42 5144.66,1490.42 5147.45,1493.2 5147.45,1621.09 5162.18,1635.82 5196.45,1635.82 5205,1627.27 5205,1547.01 5218.7,1533.31 5272.43,1533.31 5290.93,1551.81 5290.93,1625.68 5314.12,1648.88 5351.12,1648.88 5368.7,1631.3 5368.7,1581.93 5384.34,1566.3 5450.46,1566.3 5458.38,1574.22 5458.38,1753.76 5488.38,1783.75 6124.51,1783.75 6141.53,1766.73 6141.53,1678.12 6161.56,1658.09 v1(6237.52,1658.09)
  Bottom Layer w5.3: v1(6237.52,1658.09) 6274.47,1695.04 R196.1@6351.89,1695.04
AM263P_ICSSM_MII0_RXCLK_R: R196.2 U37.32 | length 94.1
  Bottom Layer w5.3: R196.2@6399.14,1695.04 6426.76,1695.04 6431.29,1699.57 U37.32@6491.32,1699.57
AM263P_ICSSM_MII0_RXD0: R198.1 R203.1 R215.2 U23.41 | length 2227.8
  Top Layer w5.3: U23.41@4817.36,1629.73 4817.36,1679.09 4822.25,1683.98 4918.59,1683.98 4941.56,1661.01 v1(5014.04,1661.01) ; R203.1@6275,1752.65 6307.35,1752.65 v1(6315,1745)
  SIG 1 w4.75: v1(5014.04,1661.01) 5062.28,1661.01 5163.5,1762.24 5322.96,1762.24 5394.72,1834 5996.48,1834 6042.48,1880 6140,1880 6172.02,1912.02 6172.02,1966.31 6210.46,2004.75 6354.09,2004.75 6390,1968.84 6390,1773.91 6361.09,1745 v1(6315,1745)
  Bottom Layer w5.3: R215.2@6274.92,1752.65 6305.55,1752.65 6313.2,1745 v1(6315,1745) v1(6315,1745) R198.1@6351.89,1745.04
AM263P_ICSSM_MII0_RXD0_R: R198.2 U37.33 | length 102.9
  Bottom Layer w5.3: R198.2@6399.14,1745.04 6434.21,1745.04 6460,1719.25 U37.33@6491.32,1719.25
AM263P_ICSSM_MII0_RXD1: R199.1 R204.1 R216.2 U23.39 | length 2149.4
  Top Layer w5.3: U23.39@4856.73,1629.73 4996.54,1629.73 5005.11,1638.3 5030.46,1638.3 v1(5031.87,1636.89) ; v1(6274.92,1798.96) 6275,1799.04 R204.1@6275,1830.96
  SIG 1 w4.75: v1(5031.87,1636.89) 5043.57,1625.19 5068.45,1625.19 5173.76,1730.5 5326.09,1730.5 5419.54,1823.95 6004.95,1823.95 6049.09,1868.09 6142.3,1868.09 6189.44,1915.22 6189.44,1956.52 6217.87,1984.95 6341.59,1984.95 6379.95,1946.59 6379.95,1799.18 6355.77,1775 6298.88,1775 v1(6274.92,1798.96)
  Bottom Layer w5.3: v1@6275,1799.04 R216.2@6275,1830.96 6295.59,1830.95 6331.3,1795.25 6351.68,1795.25 R199.1@6351.89,1795.04
AM263P_ICSSM_MII0_RXD1_R: R199.2 U37.34 | length 126.8
  Bottom Layer w5.3: R199.2@6399.14,1795.04 6425.12,1795.04 6438.01,1782.15 6438.01,1762.74 6461.81,1738.94 U37.34@6491.32,1738.94
AM263P_ICSSM_MII0_RXD2: R200.1 R210.1 R222.2 U23.38 | length 2114.9
  Top Layer w4.75: U23.38@4892.17,1613.98 4941.61,1613.98 4941.72,1614.09 4968.32,1614.09 4980.06,1602.34 v1(5010.25,1602.34)
  Top Layer w5.3: R210.1@6383.01,1989.35 6411.65,1989.35 v1(6411.73,1989.27)
  SIG 1 w4.75: v1(5010.25,1602.34) 5010.25,1599.98 5022.18,1588.05 5048.35,1588.05 5171.92,1711.62 5329.69,1711.62 5431.97,1813.9 6013.95,1813.9 6058.09,1858.04 6221.19,1858.04 6255.67,1823.56 6255.67,1760.83 6293.55,1722.95 6367.95,1722.95 6411.73,1766.73 v1(6411.73,1989.27)
  Bottom Layer w5.3: R200.1@6406.28,1918.62 6406.28,1941.33 6383.01,1964.61 R222.2@6383.01,1989.35 6411.65,1989.35 v1(6411.73,1989.27)
AM263P_ICSSM_MII0_RXD2_R: R200.2 U37.35 | length 159.3
  Bottom Layer w5.3: R200.2@6406.28,1871.38 6406.28,1833.72 6448.61,1791.39 6448.61,1781.98 6471.97,1758.62 U37.35@6491.32,1758.62
AM263P_ICSSM_MII0_RXD3: R201.1 R211.1 R223.2 U23.36 | length 2156.2
  Top Layer w5.3: U23.36@4892.4,1574.37 4969.35,1574.37 4971.38,1572.34 v1(5010.25,1572.34) ; R211.1@6443.01,1989.35 v1(6471.73,1989.27) v1(6471.73,1989.27)
  SIG 1 w4.75: v1(5010.25,1572.34) 5010.67,1572.76 5047.82,1572.76 5176.63,1701.57 5348.06,1701.57 5450.34,1803.85 6018.14,1803.85 6045.92,1831.62 6163.39,1831.62 6286.61,1708.4 6393.83,1708.4 6444.47,1759.03 6444.47,1999.47 6455,2010 6467.22,2010 6471.73,2005.49 v1(6471.73,1989.27)
  Bottom Layer w5.3: R201.1@6456.28,1918.62 6456.28,1943.72 6443.01,1956.99 R223.2@6443.01,1989.35 v1(6471.73,1989.27) v1(6471.73,1989.27)
AM263P_ICSSM_MII0_RXD3_R: R201.2 U37.36 | length 116.2
  Bottom Layer w5.3: R201.2@6456.28,1871.38 6456.28,1798.71 6476.68,1778.31 U37.36@6491.32,1778.31
AM263P_ICSSM_MII0_RXDV: R197.1 R205.1 R217.2 U23.34 | length 2205.4
  Top Layer w5.3: U23.34@4892.17,1535.24 4929.51,1535.24 4929.6,1535.33 5029.41,1535.33 5030.09,1534.65 v1(5045.81,1550.37) ; R205.1@6506.28,1989.43 6526.56,1989.43 6536.12,1979.87 v1(6536.12,1977.35)
  SIG 1 w4.75: v1(5045.81,1550.37) 5045.81,1553.33 5183.53,1691.06 5351.76,1691.06 5454.5,1793.8 6185.09,1793.8 6286.6,1692.28 6286.6,1671.06 6305.11,1652.56 6362.57,1652.56 6475.75,1765.74 6475.75,1890 6485.75,1900 6510.53,1900 6536.12,1925.59 v1(6536.12,1977.35)
  Bottom Layer w5.3: R197.1@6506.28,1918.62 R217.2@6506.28,1989.43 6526.56,1989.43 6536.12,1979.87 v1(6536.12,1977.35)
AM263P_ICSSM_MII0_RXDV_R: R197.2 U37.38 | length 80
  Bottom Layer w5.3: R197.2@6506.28,1871.38 6506.28,1852.66 6536.59,1822.35 U37.38@6536.59,1803.9
AM263P_ICSSM_MII0_RXER: R206.1 R218.2 R235.2 U37.46 U49.2 | length 2656.3
  Top Layer w5.3: v1(5574.59,914.8) 5600.18,889.2 U49.2@5652.8,889.2 ; v1(6694.59,1779.98) 6694.07,1780.5 6694.07,1810.03 6724.04,1840 6785,1840 6795,1850 6795,1874.79 R206.1@6796.28,1876.06 v1(6822.14,1876.06) R218.2@6848,1876.06
  SIG 1 w4.75: v1(5574.59,914.8) 5854.89,914.8 5986.39,783.3 6203.03,783.3 6219.76,800.03 6282.75,800.03 6307.03,775.75 6367.49,775.75 6416.79,825.05 6535.65,825.05 6593.6,767.1 6667.1,767.1 6719.25,819.25 6719.25,992.92 6703.29,1008.88 6703.29,1224.29 6749.32,1270.33 6749.32,1318.51 6749.32,1582.54 6735.75,1596.11 6735.75,1738.3 6694.59,1779.46 v1(6694.59,1779.98)
  Bottom Layer w5.3: U37.46@6694.07,1803.9 6694.33,1803.64 6694.33,1780.24 v1(6694.59,1779.98) ; v1(6822.14,1876.06) 6822.77,1876.69 R235.2@6848,1876.69
AM263P_ICSSM_MII0_RXLINK: R208.1 R220.2 R233.2 U37.47 U49.5 | length 2771.9
  Top Layer w5.3: v1(5610.59,812.43) U49.5@5652.8,812.43 ; R208.1@6729.39,1876.46 v1(6758,1876.46)
  SIG 1 w4.75: v1(5610.59,812.43) 5689.53,812.43 5697.98,803.98 5737.42,803.98 5824.99,716.41 5881.68,716.41 5895.21,729.95 6278.26,729.95 6305.65,702.56 6329.24,702.56 6427.29,800.6 6531.62,800.6 6544.25,787.97 6544.25,768.34 6534.22,758.31 6534.22,738.69 6556.04,716.87 6741.87,716.87 6785,760 6785,975.92 6766.98,993.94 6766.98,1041.66 6723.39,1085.25 6723.39,1208.39 6769.42,1254.42 6769.42,1326.83 6769.42,1605.75 6765,1610.18 6765,1757.52 6730,1792.52 6730,1848.46 v1(6758,1876.46)
  Bottom Layer w5.3: U37.47@6713.76,1803.9 6713.76,1839.3 6729.39,1854.93 R220.2@6729.39,1876.46 v1(6758,1876.46) 6794.76,1876.46 R233.2@6795,1876.69
AM263P_ICSSM_MII0_TXCLK: U23.19 U37.29 | length 2250.5
  Top Layer w5.3: v1(4804.9,1190.34) 4817.36,1202.8 U23.19@4817.36,1283.27
  SIG 1 w4.75: v1(4804.9,1190.34) 4841.27,1226.7 5009.86,1226.7 5108.33,1325.17 5277.83,1325.17 5297.25,1305.75 5466.76,1305.75 5543.63,1382.62 5644.01,1382.62 5678.77,1417.39 6163.72,1417.39 6218.11,1363 6332.22,1363 6364.23,1395 6414.93,1395 6516.08,1496.16 6516.08,1589.48 6482.59,1622.97 6461.5,1622.97 v1(6445,1606.47)
  Bottom Layer w5.3: v1(6445,1606.47) 6445,1619.87 6465.64,1640.51 U37.29@6491.32,1640.51
AM263P_ICSSM_MII0_TXD0: U23.29 U37.28 | length 2253.4
  Top Layer w5.3: U23.29@4892.17,1436.81 v1(4933.82,1436.81)
  SIG 1 w4.75: v1(4933.82,1436.81) 4951.16,1454.15 4985.94,1454.15 4987.44,1455.65 5384.83,1455.65 5480,1456.02 5533.72,1509.74 5533.72,1623.69 5564.22,1654.19 5698.3,1654.19 5720.16,1632.33 5926.54,1632.33 5928.91,1632.33 5932.47,1635.88 5932.47,1654.01 5936.02,1657.56 5946.66,1657.56 5950.22,1654.01 5950.22,1627.66 5953.77,1624.11 5964.41,1624.11 5967.97,1627.66 5967.97,1654.01 5971.52,1657.56 5982.16,1657.56 5985.72,1654.01 5985.72,1627.66 5989.27,1624.11 5999.91,1624.11 6003.47,1627.66 6003.47,1654.01 6007.02,1657.56 6017.66,1657.56 6021.22,1654.01 6021.22,1627.66 6024.77,1624.11 6035.41,1624.11 6038.97,1627.66 6038.97,1651.88 6042.52,1655.43 6053.16,1655.43 6056.72,1651.88 6056.72,1628.78 6060.27,1625.23 6070.91,1625.23 6074.47,1628.78 6078.02,1632.33 6082.5,1632.33 6132.92,1632.33 6172.92,1592.34 6325.23,1592.34 6477.9,1745 6514.23,1745 6520,1739.23 6520,1617.22 v1(6517.78,1615)
  Bottom Layer w5.3: U37.28@6491.32,1620.83 6508.81,1620.83 6514.64,1615 v1(6517.78,1615)
AM263P_ICSSM_MII0_TXD1: U23.27 U37.27 | length 2254.7
  Top Layer w5.3: U23.27@4892.17,1397.44 v1(4933.82,1397.44)
  SIG 1 w4.75: v1(4933.82,1397.44) 4969.53,1433.15 4996.28,1433.15 5008.72,1445.6 5200.6,1445.6 5204.29,1441.91 5204.29,1413.41 5210,1407.7 5225,1407.7 5231.71,1414.41 5231.71,1439.62 5237.09,1445 5250,1445 5255,1440 5255,1412.7 5260,1407.7 5280,1407.7 5286.71,1414.41 5286.71,1439.62 5292.09,1445 5305,1445 5310,1440 5310,1412.7 5315,1407.7 5330,1407.7 5336.71,1414.41 5336.71,1439.62 5342.09,1445 5355,1445 5360,1440 5360,1412.7 5365,1407.7 5380,1407.7 5386.71,1414.41 5386.71,1439.62 5392.09,1445 5405,1445 5410,1440 5410,1412.7 5415,1407.7 5430,1407.7 5436.71,1414.41 5436.71,1439.62 5442.09,1445 5455,1445 5460,1440 5460,1412.7 5465,1407.7 5480,1407.7 5486.71,1414.41 5486.71,1439.62 5492.09,1445 5505,1445 5599.1,1539.1 5613.34,1553.34 5618.36,1553.34 5640.03,1531.66 5645.05,1531.66 5652.58,1539.19 5652.58,1544.21 5622.33,1574.46 5622.33,1579.48 5629.86,1587.01 5634.89,1587.01 5663.28,1558.62 5668.3,1558.62 5675.83,1566.15 5675.83,1571.17 5656.01,1590.99 5656.01,1596.01 5666.73,1606.73 5668.66,1608.66 6126.07,1608.66 6182.43,1552.3 6404.57,1552.3 v1(6423.51,1571.24)
  Bottom Layer w5.3: v1(6423.51,1571.24) 6439.75,1571.24 6469.65,1601.14 U37.27@6491.32,1601.14
AM263P_ICSSM_MII0_TXD2: U23.25 U37.26 | length 2254.7
  Top Layer w5.3: U23.25@4892.17,1358.07 v1(4933.82,1358.07)
  SIG 1 w4.75: v1(4933.82,1358.07) 4908.92,1358.07 4906.14,1360.86 4906.14,1373.15 4910.04,1377.05 4957.85,1377.05 4963.44,1382.64 4963.44,1407.18 4976.14,1419.88 4996.1,1419.88 5022.78,1393.19 5078.8,1393.19 5081.17,1393.19 5084.72,1396.74 5084.72,1417.04 5088.27,1420.59 5098.92,1420.59 5102.47,1417.04 5102.47,1396.74 5106.02,1393.19 5116.67,1393.19 5120.22,1396.74 5120.22,1417.04 5123.77,1420.59 5134.42,1420.59 5137.97,1417.04 5137.97,1396.74 5141.52,1393.19 5152.17,1393.19 5155.72,1396.74 5155.72,1417.04 5159.27,1420.59 5169.92,1420.59 5173.47,1417.04 5173.47,1396.74 5177.02,1393.19 5183.53,1393.19 5333.11,1393.19 5353.14,1373.15 5485.56,1373.15 5573.81,1461.41 5623,1461.41 5737.67,1576.08 5776.45,1576.08 5787.59,1564.93 5807.45,1564.93 5818.58,1576.06 5926.54,1576.06 5928.91,1576.06 5932.47,1579.61 5932.47,1589.43 5936.02,1592.98 5946.66,1592.98 5950.22,1589.43 5950.22,1559.61 5953.77,1556.06 5964.41,1556.06 5967.97,1559.61 5967.97,1589.43 5971.52,1592.98 5982.16,1592.98 5985.72,1589.43 5985.72,1559.61 5989.27,1556.06 5999.91,1556.06 6003.47,1559.61 6003.47,1589.43 6007.02,1592.98 6017.66,1592.98 6021.22,1589.43 6021.22,1559.61 6024.77,1556.06 6035.41,1556.06 6038.97,1559.61 6038.97,1589.43 6042.52,1592.98 6053.16,1592.98 6056.72,1589.43 6056.72,1561.68 6060.27,1558.12 6070.91,1558.12 6074.47,1561.68 6074.47,1579.62 6078.02,1583.17 6088.66,1583.17 6092.22,1579.62 6095.77,1576.06 6106.72,1576.06 6127.94,1576.06 6163.16,1540.85 v1(6444.47,1540.85)
  Bottom Layer w5.3: v1(6444.47,1540.85) 6444.47,1550.71 6475.21,1581.46 U37.26@6491.32,1581.46
AM263P_ICSSM_MII0_TXD3: U23.23 U37.25 | length 2252.6
  Top Layer w5.3: U23.23@4892.17,1318.7 v1(4933.82,1318.7)
  SIG 1 w4.75: v1(4933.82,1318.7) 4998.25,1383.14 5315.23,1383.14 5369,1329.37 5476.17,1329.37 5564.37,1417.57 5626.34,1417.57 5698.9,1490.13 5807.45,1490.13 5821.55,1504.23 5862.22,1504.23 5872.1,1494.36 5910.18,1494.36 5912.56,1494.36 5916.11,1497.91 5916.11,1510.81 5919.66,1514.36 5930.31,1514.36 5933.86,1510.81 5933.86,1495.44 5937.41,1491.89 5948.06,1491.89 5951.61,1495.44 5951.61,1502.56 5955.16,1506.11 5965.81,1506.11 5969.36,1502.56 5969.36,1497.91 5972.91,1494.36 6003.33,1494.36 6250.2,1494.36 6263.7,1480.85 6263.7,1394.54 6274.46,1383.78 6299.87,1383.78 6307.32,1391.23 6307.32,1472.4 6321.29,1486.37 6337.56,1486.37 6351.36,1472.57 6351.36,1415.04 6360.4,1406 6411.71,1406 6465,1459.29 6465,1476.21 6454.84,1486.37 6428.68,1486.37 6422.79,1492.26 6422.79,1514.18 6428.61,1520 6472.17,1520 v1(6492.17,1540)
  Bottom Layer w4.75: U37.25@6491.32,1561.77 6476.68,1561.77 6469.65,1554.74 6469.65,1544.44 6474.09,1540 v1(6492.17,1540)
AM263P_ICSSM_MII0_TXEN: U23.21 U37.37 | length 2248.8
  Top Layer w5.3: v1(4853.2,1207.31) 4854.5,1208.6 4854.5,1219.38 4859.49,1224.38 4859.49,1248 4854.51,1252.98 4854.51,1281.05 U23.21@4856.73,1283.27
  SIG 1 w4.75: 5022.3,1212.99 5120.15,1310.83 5259.44,1310.83 5275.2,1295.08 5499.02,1295.08 5563.8,1359.85 6201.23,1359.85 6208.14,1352.95 6387.47,1352.95 6529.4,1494.88 6529.4,1577.5 6537.03,1585.13 6537.03,1628.1 6532,1633.13 6532,1769.81 6497.91,1803.9 v1(6495,1803.9)
  SIG 1 w5.3: v1(4853.2,1207.31) 4916.62,1207.31 4922.3,1212.99 5022.3,1212.99
  Bottom Layer w5.3: v1(6495,1803.9) U37.37@6516.91,1803.9
AM263P_ICSSM_MII1_COL: R112.1 R124.2 R225.2 U1.C18 U22.45 | length 4305.1
  Top Layer w5.3: U1.C18@4082.57,1319.8 4086.6,1319.8 4122.5,1355.7 4146.29,1355.7 4191.74,1401.15 4354.6,1401.15 4362.85,1392.9 4379.03,1392.9 4406.55,1420.41 4406.55,1688.5 4487.14,1769.1 4857.79,1769.1 4902.74,1814.05 5272.23,1814.05 5325.08,1866.9 5530.18,1866.9 5618.28,1955 6564.92,1955 v1(6624.77,2014.85) ; R112.1@6674.39,926.46 v1(6700,926.46)
  SIG 1 w4.75: v1(6624.77,2014.85) 6655.14,1984.49 6655.14,1912.02 6675.34,1891.82 6675.34,1481.02 6652.14,1457.82 6652.14,1311.31 6689.32,1274.13 6689.32,1225.94 6674.39,1211 v1(6674.39,1065)
  Bottom Layer w5.3: U22.45@6674.39,853.9 R124.2@6674.39,926.46 v1(6700,926.46) 6700,1020 6715,1035 R225.2@6715,1064.94 6674.45,1064.94 v1(6674.39,1065)
AM263P_ICSSM_MII1_RXCLK: U1.E16 U50.31 | length 1530.3
  Top Layer w5.3: v1(5131.16,1000.35) U50.31@5173.43,1000.35
  Top Layer w10: U1.E16@4019.57,1256.81 v1(4035.32,1272.56)
  SIG 1 w4: v1(4035.32,1272.56) 4051.82,1289.06 4114.06,1289.06
  SIG 1 w4.75: 4114.06,1289.06 4250.66,1289.06 4265.61,1304 4379.88,1304 4400.29,1324.4 4466.88,1324.4 4728.5,1062.79 4728.5,1048.88 4749.39,1027.99 4891.44,1027.99 4901.66,1038.21 5029.44,1038.21 5045,1022.66 5045,1007.89 5055.05,997.84 5080.12,997.84 5163.56,1081.29 5170.68,1081.29 5177.73,1074.24 5177.73,1041.58 5168.72,1032.57 5150.46,1032.57 5131.16,1013.27 v1(5131.16,1000.35)
AM263P_ICSSM_MII1_RXD0: U1.F18 U50.42 | length 1523.7
  Top Layer w4: U1.F18@4082.57,1225.32 4113.77,1225.32 4114.06,1225.03
  Top Layer w5.3: 4114.06,1225.03 4115.16,1223.93 4196.2,1223.93 4206.8,1234.53 4250.64,1234.53 4262.08,1245.97 4262.08,1260.07 4279.71,1277.7 4375.74,1277.7 4384.12,1269.32 4384.12,1257.69 v1(4384.99,1256.82) ; v1(5256.31,774.31) 5256.31,775.07 5267.91,786.67 U50.42@5267.91,846.81
  SIG 1 w4.75: v1(4384.99,1256.82) 4427.22,1256.82 4569.17,1114.87 4569.17,1096.28 4580.55,1084.9 4614.61,1084.9 4647.95,1051.56 4647.95,1025.3 4695.51,977.74 4847.67,977.74 4979.44,845.97 5058.54,845.97 5114.71,789.8 5239.39,789.8 5254.89,774.31 v1(5256.31,774.31)
AM263P_ICSSM_MII1_RXD1: U1.G16 U50.40 | length 1526
  Top Layer w5.3: v1(5213.86,770.56) 5213.86,790.31 5228.54,805 U50.40@5228.54,846.81
  Top Layer w10: U1.G16@4019.57,1193.82 v1(4035.32,1209.57)
  SIG 1 w4.75: v1(4035.32,1209.57) 4270.86,1209.57 4296.38,1235.08 4434.74,1235.08 4474.51,1195.31 4474.51,1140.59 4647.41,967.69 4843.5,967.69 4975.28,835.92 5054.38,835.92 5129.22,761.08 5204.38,761.08 v1(5213.86,770.56)
AM263P_ICSSM_MII1_RXD2: U1.E17 U50.37 | length 1529.3
  Top Layer w4: U1.E17@4051.07,1256.81 4066.82,1272.56 4101.95,1272.56 4113.62,1284.23 4114.06,1284.23
  Top Layer w5.3: 4114.06,1284.23 4197.31,1284.23 4210.63,1297.55 4250.64,1297.55 4270.36,1317.28 4450.47,1317.28 4460,1307.75 v1(4460,1271.09) ; v1(5131.77,882.24) U50.37@5173.43,882.24
  SIG 1 w4.75: v1(4460,1271.09) 4461.55,1269.54 4471.38,1269.54 4690.23,1050.69 4690.23,1036.35 4728.73,997.84 4860.42,997.84 4990.73,867.53 5070.26,867.53 5127.8,810 5158.56,810 5167.94,819.38 5167.94,876.31 5154.35,889.89 5141.18,889.89 5133.53,882.24 v1(5131.77,882.24)
AM263P_ICSSM_MII1_RXD3: U1.E18 U50.35 | length 1525.8
  Top Layer w4: U1.E18@4082.57,1256.81 4104.96,1256.81
  Top Layer w5.3: 4104.96,1256.81 4121.72,1273.58 4202.45,1273.58 4215.82,1286.95 4255.03,1286.95 4270.57,1302.49 4414.23,1302.49 4421.61,1295.1 v1(4423.69,1295.1) ; v1(5131.77,921.61) U50.35@5173.43,921.61
  SIG 1 w4.75: v1(4423.69,1295.1) 4463.21,1295.1 4702.13,1056.19 4702.13,1038.66 4732.9,1007.89 4864.58,1007.89 4970.98,901.49 5157.7,901.49 5180,879.19 5180,854.78 5182.78,851.99 5211.08,851.99 5213.86,854.78 5213.86,875 5167.25,921.61 v1(5131.77,921.61)
AM263P_ICSSM_MII1_RXDV: U1.F16 U50.33 | length 1526.7
  Top Layer w5.3: v1(5131.16,960.98) U50.33@5173.43,960.98
  Top Layer w10: U1.F16@4019.57,1225.32 v1(4035.32,1241.06)
  SIG 1 w4.75: v1(4035.32,1241.06) 4041.58,1234.81 4166.03,1234.81 4180,1248.78 4180,1259.38 4193.93,1273.3 4265,1273.3 4285.64,1293.95 4384.05,1293.95 4404.45,1314.35 4462.72,1314.35 4716.57,1060.5 4716.57,1038.43 4737.06,1017.94 4979.18,1017.94 5016.02,981.1 5142.47,981.1 5150.41,989.04 5150.41,1010.7 5159.71,1020 5173.32,1020 5177.73,1015.59 5177.73,969.09 5169.62,960.98 v1(5131.16,960.98)
AM263P_ICSSM_MII1_RXER: R111.1 R123.2 R229.2 U1.F15 U22.46 | length 3814.2
  Top Layer w5.3: v1(6695,890) 6740,890 6751.09,901.09 6789.71,901.09 6795,906.38 6795,924.79 R111.1@6796.28,926.06 R123.2@6848,926.06 v1(6848,888.56)
  Top Layer w10: U1.F15@3988.08,1225.32 v1(4003.83,1241.06)
  SIG 1 w4.75: v1(4003.83,1241.06) 4019.95,1224.94 4048.81,1224.94 4051.93,1221.82 4248.36,1221.82 4302.6,1276.07 4415.5,1276.07 4415.71,1275.85 4422.39,1275.85 4461.67,1236.58 4483.31,1236.58 4607.66,1112.23 ; 4607.66,1112.2 4674.65,1045.21 4674.65,1037.26 4724.12,987.79 4851.83,987.79 4983.6,856.02 5062.71,856.02 5118.87,799.85 5257.98,799.85 5290.49,767.35 5362.68,767.35 5418.23,711.81 5544.89,711.81 5563.54,730.46 5635.19,730.46 5676.79,688.86 5729.23,688.86 5791.46,626.63 6015.33,626.63 6104.93,537.03 6131.2,510.75 6296.63,510.75 6340.08,554.2 6354.6,554.2 6360.4,560 6494.35,560 6528.88,594.53 6777.57,594.53 6848,664.96 v1(6848,888.56)
  Bottom Layer w5.3: U22.46@6694.07,853.9 6694.07,889.07 v1(6695,890) ; R229.2@6846.59,927.98 6846.59,889.97 v1(6848,888.56)
AM263P_ICSSM_MII1_RXLINK: R110.1 R122.2 R227.2 U1.D18 U22.47 | length 4641
  Top Layer w5.3: U1.D18@4082.57,1288.31 4100.01,1288.31 4109.25,1297.55 4175.56,1297.55 4184.2,1306.2 4184.2,1360.45 4202.39,1378.64 4347.13,1378.64 4354.07,1371.7 4387.81,1371.7 4427.75,1411.63 4428.14,1678.54 4495.93,1747.9 4869.42,1747.9 4893.95,1772.43 5250.17,1772.43 5334.04,1856.3 5534.57,1856.3 5622.67,1944.4 6571.07,1944.4 6617.06,1990.39 6740.39,1990.39 v1(6810,2060) ; R110.1@6729.39,926.46 v1(6755,926.46)
  SIG 1 w4.75: v1(6810,2060) 6803.55,2053.55 6803.55,1979.56 6815.53,1967.58 6815.53,1930 6802.89,1917.36 6802.89,1868.09 6839.95,1831.03 6839.95,1375.84 6846.59,1369.2 v1(6846.59,1065.8)
  Bottom Layer w5.3: U22.47@6713.76,853.9 6713.76,879.37 6729.39,895 R122.2@6729.39,926.46 v1(6755,926.46) 6785,956.46 6785,987.75 6762.73,1010.01 R227.2@6762.73,1065.31 6846.11,1065.31 v1(6846.59,1065.8)
AM263P_ICSSM_MII1_TXCLK: R86.1 U50.18 | length 1588.1
  Top Layer w5.3: R86.1@4111,1632.17 v1(4111,1660.23) ; v1(5248.23,1280.53) 5267.91,1260.84 U50.18@5267.91,1193.26
  SIG 1 w4.75: v1(4111,1660.23) 4111.4,1659.82 4111.4,1648.85 4291.44,1468.82 4411.16,1468.82 4484.34,1395.64 4525.74,1395.64 4555,1366.38 4555,1313.14 4747.54,1120.59 4806.54,1120.59 4864.96,1179.01 4937.09,1179.04 4938.49,1180.43 4949.07,1191.02 5158.72,1191.02 v1(5248.23,1280.53)
AM263P_ICSSM_MII1_TXCLK_R: R86.2 U1.C16 | length 308.1
  Top Layer w4: v1(4110.55,1554.46) 4110.55,1583.95 R86.2@4110.9,1584.29
  Top Layer w10: U1.C16@4019.57,1319.8 v1(4035.32,1335.55)
  SIG 1 w4: v1(4035.32,1335.55) 4035.32,1413.17 4049.91,1427.76 4049.91,1430
  SIG 1 w4.75: 4049.91,1430 4049.91,1503.64 4098.14,1551.88 4104.38,1551.88 4106.97,1554.46 v1(4110.55,1554.46)
AM263P_ICSSM_MII1_TXD0: R81.1 U50.28 | length 1555.1
  Top Layer w4.75: R81.1@4325.63,1481.77 4327.71,1479.69 4348.19,1479.69 4377.41,1508.92 4391.48,1508.92 4396.22,1504.18 4396.22,1446.09 4389.36,1439.24 v1(4357.49,1439.24)
  Top Layer w5.3: v1(5086.77,1039.72) 5087.15,1040.1 5103.84,1040.1 5123.15,1059.41 U50.28@5173.43,1059.41
  SIG 1 w4.75: v1(4357.49,1439.24) 4254.79,1439.24 4252.63,1437.07 4248.78,1433.22 4248.78,1425.1 4252.33,1421.55 4261.58,1421.55 4265.13,1418 4265.13,1407.35 4261.58,1403.8 4244.1,1403.8 4240.55,1400.25 4240.55,1389.6 4244.1,1386.05 4265.23,1386.05 4268.78,1382.5 4268.78,1371.85 4265.23,1368.3 4244.1,1368.3 4240.55,1364.75 4240.55,1354.1 4244.1,1350.55 4245.23,1350.55 4248.78,1347 4248.78,1344.63 4248.78,1337.85 4272.58,1314.05 4375.72,1314.05 4396.13,1334.45 4471.04,1334.45 4729.37,1076.13 4730,1076.13 4763.46,1042.67 4800.88,1042.67 4807.3,1049.09 5077.41,1049.09 v1(5086.77,1039.72)
AM263P_ICSSM_MII1_TXD0_R: R81.2 U1.B18 | length 368.2
  Top Layer w5.3: U1.B18@4082.57,1351.3 4108.55,1377.29 4137.9,1377.29 4139.04,1378.42 4147.27,1386.66 4147.27,1404.55 4150.93,1408.21 4163.61,1408.21 4167.27,1411.87 4167.27,1422.85 4163.61,1426.51 4134.66,1426.51 4131,1430.17 4131,1441.15 4134.66,1444.81 4143.61,1444.81 4147.27,1448.47 4147.27,1462.16 4150.21,1465.11 4152,1466.89 4173.1,1466.89 4194.06,1466.89 4197.72,1463.23 4197.72,1459.06 4201.38,1455.4 4212.35,1455.4 4216.02,1459.06 4216.02,1463.23 4219.68,1466.89 4231.37,1466.89 4238.92,1466.89 4253.81,1481.77 R81.2@4278.38,1481.77
AM263P_ICSSM_MII1_TXD1: R82.1 U50.26 | length 1651.1
  Top Layer w4.75: v1(4177.48,1512.71) 4178.8,1514.04 4178.8,1531.21 4190.82,1543.23 R82.1@4212.87,1543.23
  Top Layer w5.3: v1(5086.77,1079.09) 5104.16,1079.09 5123.85,1098.78 U50.26@5173.43,1098.78
  SIG 1 w4.75: v1(4177.48,1512.71) 4177.48,1509.18 4169.78,1501.48 4169.78,1501.19 4077.69,1501.19 4074.9,1498.41 4074.9,1465.84 4082.02,1458.72 4395.2,1458.72 4743.38,1110.54 4810.7,1110.54 4869.12,1168.96 4945.63,1168.96 4957.64,1180.97 5114.87,1180.97 5127.21,1168.63 5127.21,1094.1 5112.19,1079.09 v1(5086.77,1079.09)
AM263P_ICSSM_MII1_TXD1_R: R82.2 U1.B17 | length 266.9
  Top Layer w4: U1.B17@4051.07,1351.3 4068.69,1368.92 4068.69,1414.29
  Top Layer w5.3: 4068.69,1414.29 4068.69,1446.09 4095.14,1472.55 4127.82,1472.55 4144.59,1489.32 4186.44,1489.32 4193.11,1495.98 R82.2@4212.87,1495.98
AM263P_ICSSM_MII1_TXD2: R83.1 U50.24 | length 1503.9
  Top Layer w4.75: R83.1@4324.87,1353.13 4348.14,1353.13 4354.85,1346.42 v1@4357.02,1346.42
  Top Layer w5.3: v1(5086.77,1118.46) 5110.31,1118.46 5130,1138.15 U50.24@5173.43,1138.15
  SIG 1 w4.75: v1(4357.55,1346.15) 4343.27,1360.42 4327.71,1360.42 4319.2,1351.91 4319.2,1335.51 4330.61,1324.1 4364.69,1324.1 4383.16,1342.57 4383.16,1365.86 4387.84,1370.54 4399.37,1370.54 4407.78,1362.14 4407.78,1350 4413.15,1344.63 4423.05,1344.63 4428.41,1349.98 4428.41,1367.11 4431.84,1370.54 4449.17,1370.54 4730.7,1089.01 4776.07,1089.01 4805.95,1059.14 4826.97,1059.14 4829.75,1061.92 4829.75,1090.18 4836.29,1096.72 4847.67,1096.72 4855.63,1088.76 4855.63,1062.14 4858.63,1059.14 4960.56,1059.14 4963.34,1061.92 4963.34,1075.99 4960.56,1078.78 4888.64,1078.78 4882.39,1085.02 4882.39,1103.87 4898.81,1120.29 4931.51,1119.67 4951.55,1099.63 4966,1099.63 4976.85,1110.49 4976.85,1127.67 4984.19,1135 5019.14,1135 5031.47,1122.67 5031.47,1105.62 5034.26,1102.84 5045.64,1102.84 5050.6,1107.8 5050.6,1115.68 5053.38,1118.46 v1(5086.77,1118.46)
AM263P_ICSSM_MII1_TXD2_R: R83.2 U1.D16 | length 396.3
  Top Layer w4.75: v1@4206.88,1351.06 4208.96,1348.98 4215.3,1348.98 4217.39,1351.06 4275.55,1351.06 R83.2@4277.62,1353.13
  Top Layer w10: U1.D16@4019.57,1288.31 v1(4035.32,1304.06)
  SIG 1 w4.75: v1(4035.32,1304.06) 4089.18,1304.06 4093.43,1308.3 4093.43,1330.34 4087,1336.78 4063.44,1336.78 4059.87,1340.35 4059.87,1351.72 4064.35,1356.2 4125.54,1356.2 4152.86,1328.88 4191.63,1328.88 v1(4209.18,1346.44)
AM263P_ICSSM_MII1_TXD3: R84.1 U50.22 | length 1628.8
  Top Layer w4.75: R84.1@4324.87,1431.45 4324.87,1415.2 4327.65,1412.42 v1(4370.94,1412.42)
  Top Layer w5.3: v1(5086.77,1157.83) 5065.63,1157.83 5060,1163.46 5060,1212.97 5066.68,1219.65 5083.67,1219.65 5086.77,1216.55 5086.77,1186.62 5094.7,1178.69 5102.75,1178.69 5108.69,1184.63 5108.69,1219.52 5115,1225.83 5160.62,1225.83 5169.97,1216.48 5169.97,1205.57 5166.86,1202.46 5131.69,1202.46 5128.59,1199.36 5128.59,1180.62 5131.69,1177.52 U50.22@5173.43,1177.52
  SIG 1 w4.75: v1(4370.94,1412.42) 4331.04,1412.42 4319.11,1400.49 4319.11,1390.44 4327.6,1381.95 4368.31,1381.95 4376.55,1381.95 4380.1,1385.5 4380.1,1395.23 4383.65,1398.78 4394.3,1398.78 4397.85,1395.23 4397.85,1384.14 4401.4,1380.59 4412.05,1380.59 4415.6,1384.14 4415.6,1402.81 4419.15,1406.36 4429.8,1406.36 4433.35,1402.81 4433.35,1385.5 4436.9,1381.95 4457.03,1381.95 4738.48,1100.49 4819.27,1100.49 4825.55,1106.77 4870.64,1106.77 4910.14,1146.27 4939.95,1146.27 4952.48,1146.27 4956.03,1149.82 4956.03,1161.59 4959.58,1165.14 4970.23,1165.14 4973.78,1161.59 4973.78,1148.6 4977.33,1145.05 4987.98,1145.05 4991.53,1148.6 4991.53,1162.72 4995.08,1166.27 5005.73,1166.27 5009.28,1162.72 5009.28,1148.6 5012.83,1145.05 5023.48,1145.05 5027.03,1148.6 5027.03,1162.72 5030.58,1166.27 5041.23,1166.27 5044.78,1162.72 5044.78,1132.06 5048.33,1128.51 5058.98,1128.51 5062.53,1132.06 5062.53,1142.72 5066.08,1146.27 5068.45,1146.27 5075.21,1146.27 v1(5086.77,1157.83)
AM263P_ICSSM_MII1_TXD3_R: R84.2 U1.C17 | length 288.8
  Top Layer w5.3: U1.C17@4051.07,1319.8 4068.04,1336.78 4088.58,1336.78 4118.11,1366.3 4141.9,1366.3 4182.58,1406.98 4182.58,1408.83 4223.26,1449.5 4238.09,1449.5 4256.14,1431.45 R84.2@4277.62,1431.45
AM263P_ICSSM_MII1_TXEN: R85.1 U50.20 | length 1674.4
  Top Layer w4.75: v1(4149,1660.23) 4159.49,1649.74 R85.1@4159.49,1607.02
  Top Layer w5.3: v1(5208.86,1290.74) 5208.86,1264.69 5228.54,1245 U50.20@5228.54,1193.26
  SIG 1 w4.75: v1(4149,1660.23) 4209.95,1599.28 4209.95,1569.19 4300.27,1478.87 4419.59,1478.87 4492.77,1405.69 4529.9,1405.69 4565.05,1370.54 4565.05,1321.78 4756.14,1130.69 4801.06,1130.69 4860.7,1189.09 4862.63,1189.09 4931.65,1189.22 4933.04,1190.61 4943.5,1201.07 5113.45,1201.07 5120.2,1207.82 5120.2,1267.78 5127.41,1275 5139.58,1275 5146.74,1267.84 5146.74,1236.57 5163.5,1219.8 5173.29,1219.8 5208.86,1255.37 v1(5208.86,1290.74)
AM263P_ICSSM_MII1_TXEN_R: R85.2 U1.A17 | length 240.8
  Top Layer w5.3: U1.A17@4051.07,1382.8 4051.07,1414.29 4051.07,1444.18 4090.03,1483.15 4122.33,1483.15 4159.49,1520.3 R85.2@4159.49,1559.77
AM263P_IEP0_EDC_SYNC_OUT0: J6/J8.72 R88.1 | length 862.6
  Bottom Layer w5.3: R88.1@4098.66,1812.24 4147.24,1812.24 4181.13,1846.13 4406.25,1846.13 4420.63,1860.51 4814.68,1860.51 J6/J8.72@4904.17,1950
AM263P_IEP0_EDC_SYNC_OUT0_R: R88.2 U1.D15 | length 565.3
  Top Layer w10: U1.D15@3988.08,1288.31 v1(4003.83,1304.06)
  SIG 1 w4: v1(4003.83,1304.06) 4018.83,1319.06 4018.83,1429.96 4018.86,1430
  SIG 1 w4.75: 4018.86,1430 4024.42,1435.56 4024.42,1796.45 4032.72,1804.75 v1(4032.72,1805.86)
  Bottom Layer w5.3: v1(4032.72,1805.86) 4035.31,1805.86 4041.69,1812.24 R88.2@4059.29,1812.24
AM263P_IEP0_EDIO_DATA_IN_OUT31: J6/J8.71 R87.1 | length 980.4
  Bottom Layer w5.3: R87.1@4098.66,1769.24 4119.24,1769.24 4185.53,1835.53 4410.64,1835.53 4424.63,1849.52 4903.7,1849.52 J6/J8.71@5004.17,1950
AM263P_IEP0_EDIO_DATA_IN_OUT31_R: R87.2 U1.C15 | length 610.4
  Top Layer w10: U1.C15@3988.08,1319.8 v1(4003.83,1335.55)
  SIG 1 w4: v1(4003.83,1335.55) 4004.65,1336.38 4004.65,1430
  SIG 1 w4.75: 4004.65,1430 4013.47,1438.82 4013.47,1814.12 4005.66,1821.93 v1(4005.66,1823.53)
  Bottom Layer w5.3: v1(4005.66,1823.53) 4005.66,1794.87 4031.29,1769.24 R87.2@4059.29,1769.24
AM263P_INT1_PB_GPIO123: U1.D14 U34.4 | length 4481.6
  Top Layer w5.3: v1(635.66,2123.71) 643.9,2115.47 U34.4@651.22,2115.47 ; v1(3750,1830) 3809.17,1830 3850.45,1871.28 3990.85,1871.28 3994.98,1875.42 4008.02,1875.42 v1(4010.45,1877.85)
  Top Layer w10: U1.D14@3956.58,1288.31 v1(3972.33,1304.06)
  SIG 1 w4: v1(3972.33,1304.06) 3988.83,1320.55 3988.83,1414.29 3988.83,1430
  SIG 1 w4.75: v1(635.66,2123.71) 645.95,2134 741.21,2134 768.33,2106.89 768.33,2041.51 805.98,2003.85 838.93,2003.85 858.19,1984.59 893.41,1984.59 923,1955 970,1955 1063.74,2048.74 1270.43,2048.74 1344.17,1975 1424.99,1975 1438.27,1961.73 1438.27,1937.91 1451.32,1924.87 1563.87,1924.87 1605.23,1883.5 1676.77,1883.5 1748.63,1811.63 1867.13,1811.63 1900,1778.77 2246.64,1778.77 2332.82,1864.94 2534.39,1864.94 2601.44,1932 2601.44,1939.47 2653.02,1991.05 2720.59,1991.05 2732.05,1979.58 2835.23,1978.96 2865.57,1948.62 2898.8,1948.62 2942.89,1904.53 3106.89,1904.53 3129.43,1881.99 3386.15,1881.99 3386.67,1882.51 3697.49,1882.51 v1(3750,1830) ; 3988.83,1430 3988.83,1446.08 4003.42,1460.68 4003.42,1795.87 3984.52,1814.77 3984.52,1851.49 4010.45,1877.41 v1(4010.45,1877.85)
AM263P_LED_DRIVER_EN: R278.2 U48.8 U63.5 | length 3362.8
  Top Layer w5.3: U48.8@2117.28,1795 2161.53,1795 2185.53,1819 R278.2@2185.53,1859.15 2147.08,1859.15 2140.23,1866 2114.88,1866 2095.82,1846.93 2095.82,1835.67 2034.1,1773.94 2034.1,1627.67 2044.32,1617.45 2044.32,1526.08 2025.08,1506.84 2025.08,1486.83 2089.14,1422.76 2143.18,1422.76 2148.94,1422.76 2171.95,1399.75 2171.95,1388.2 2178.05,1382.11 2193.4,1366.75 2232.97,1366.75 v1(2248.87,1350.85)
  SIG 1 w4.75: v1(2248.87,1350.85) 2309.54,1350.85 2387.71,1429.01 2439.88,1429.01 2457.52,1411.37 2457.52,1251.27 2337.7,1131.45 2337.7,939.98 2328.92,931.2 2294.31,931.2 2166.65,1058.86 2037.46,1058.86 1991.12,1012.52 1991.12,970.66 2066.47,895.31 2066.47,757.91 2122.22,702.17 2359.29,702.17 2406.84,654.62 2453.41,654.62 2536.75,737.96 2569.03,737.96 2579.67,727.33 2579.67,718.22 2590.68,707.2 2644.38,707.2 2658.44,721.26 2658.44,757.59 2638.35,777.68 2624.47,777.68 v1(2623.53,778.61)
  Bottom Layer w5.3: U63.5@2578.49,658.28 2578.49,685.5 2565.51,698.48 2547.79,698.48 2539.12,707.15 2539.12,739.76 2577.98,778.61 v1(2623.53,778.61)
AM263P_LED_EN: R303.1 R304.2 U63.6 | length 1063.6
  Top Layer w5.3: R303.1@2617.63,186.73 2559.79,186.73 R304.2@2558.18,185.12 2558.18,219.86 2612.1,273.78 2631.56,273.78 2724.79,367 2724.79,420.38 2749.79,445.37 2783.46,445.37 2794.1,456.01 2794.1,519.21 2857.2,582.31 2857.2,620.33 2829.89,647.63 2705.1,647.63 2693.33,659.39 2693.33,688.45 2709.7,704.82 2709.7,721.25 2698.27,732.69 2646.08,732.69 2642.08,728.69 v1(2638.64,728.69)
  Bottom Layer w5.3: U63.6@2598.18,658.28 2598.18,688.22 v1(2638.64,728.69)
AM263P_LIN1_RXD: U1.A9 U52.33 | length 1970
  Top Layer w4: 3797.83,1414.29 3797.83,1384.07 U1.A9@3799.1,1382.8
  Top Layer w5.3: 3797.83,1414.29 3797.83,1483.15 3853.82,1539.13 3853.82,1561.66 3839.11,1576.37 3839.11,1691.5 v1(3821.76,1708.85) ; v1(4408.39,591.26) 4428.07,610.95 U52.33@4500.04,610.94
  Bottom Layer w5.3: v1(3821.76,1708.85) 3807.98,1708.85 3798.35,1699.22 3798.35,1633.95 3821.58,1610.73 3909.32,1610.73 4055,1465.05 4055,1388.67 4095.15,1348.52 4095.15,874.56 4194.89,774.82 4289.15,774.82 4352.47,711.5 4352.47,625.82 4387.04,591.26 v1(4408.39,591.26)
AM263P_LIN1_TXD: R297.1 U52.31 | length 1532.8
  Top Layer w5.3: R297.1@3817.25,1638.93 3817.85,1655.39 3818.03,1655.56 v1(3818.03,1673.05) ; v1(4408.39,630.63) 4428.07,650.32 U52.31@4500.04,650.32
  Bottom Layer w5.3: v1(3818.03,1673.05) 3819.95,1638.17 3835.96,1622.15 3912.89,1622.15 4070,1465.04 4070,1395 4104.45,1360.55 4104.45,880.25 4199.2,785.5 4304.49,785.5 4355.15,734.84 4364.5,734.84 4391.61,707.74 4391.61,646.83 4407.81,630.63 v1(4408.39,630.63)
AM263P_LIN1_TXD_R: R297.2 U1.B9 | length 264.9
  Top Layer w4: 3783.35,1414.29 3783.35,1367.05 U1.B9@3799.1,1351.3
  Top Layer w5.3: 3783.35,1414.29 3783.35,1418.8 3786.5,1421.94 3786.5,1492.41 3809.52,1515.44 3809.52,1553.6 3817.25,1561.33 R297.2@3817.25,1595.63
AM263P_LIN2_RXD: U1.B8 U52.41 | length 3777.4
  Top Layer w4: 3751.86,1380 3751.86,1367.05 U1.B8@3767.61,1351.3
  Top Layer w5.3: 3751.86,1380 3751.86,1422.06 3736.85,1437.07 3736.85,1474.86 3743.45,1481.47 3743.45,1565.9 3743.22,1566.14 3743.22,1677.47 v1(3807.77,1742.01) ; U52.41@4574.84,496.77 4574.84,451.2 4585.49,440.55 v1(4585.49,440)
  Bottom Layer w5.3: v1(3807.77,1742.01) 3823.05,1742.01 3850.95,1714.12 3850.95,1693.84 3839.11,1682 3839.11,1645.82 3850.65,1634.28 3915.75,1634.28 3965.77,1584.26 4150.61,1584.26 4238.54,1496.32 4509.56,1496.32 4576.21,1562.97 4632.03,1562.97 4665.99,1596.94 4706,1596.94 4737.99,1628.93 5009.74,1630.47 5084.02,1556.18 5084.02,1496.18 5135.82,1444.38 5135.82,1127.43 5151.3,1111.96 5151.3,874.15 5118.23,841.09 5118.23,762.55 5073.07,717.39 4925.48,717.39 4891.59,683.5 4891.59,498.74 4942.57,447.75 4942.57,409.76 4939.47,406.65 4616.96,406.65 4585.49,438.13 v1(4585.49,440)
AM263P_LIN2_RXD_PR0_PRU0_GPIO11: J5/J7.43 U52.2 | length 1074.8
  Top Layer w5.3: U52.2@4629.96,532.2 4630.93,533.17 4645.22,533.17 4664.1,552.06 4684.53,552.06 4700.22,536.37 4700.22,489.3 4715.7,473.82 v1(4715.7,473.21)
  SIG 1 w5.3: J5/J7.43@4304.17,250 4263.14,291.04 4193.44,291.04 4152.16,332.32 4152.16,360.05 4130.17,382.03 4130.17,418.52 4151.57,439.92 4169.33,439.92 4206.34,402.91 4470.24,402.91 4530.66,463.33 4702.37,463.33 4712.26,473.21 v1(4715.7,473.21)
AM263P_LIN2_TXD: R166.1 U52.39 | length 1780.6
  Top Layer w5.3: R166.1@3769.66,1642.44 3769.66,1665.2 v1(3778.82,1674.36) ; v1(4425.58,470.61) 4425.58,468.04 4445.11,448.5 4519.71,448.5 4535.47,464.27 U52.39@4535.47,496.77
  Bottom Layer w5.3: v1(3778.82,1674.36) 3778.82,1629.06 3819.32,1588.57 3916.48,1588.57 3918.04,1587.02 4040,1465.06 4040,1388.66 4085.85,1342.81 4085.85,868.87 4195.74,758.98 4290,758.98 4341.87,707.11 4341.87,621.43 4354.64,608.66 4354.64,538.97 4423.01,470.61 v1(4425.58,470.61)
AM263P_LIN2_TXD_PR0_PRU0_GPIO9: J5/J7.44 U52.3 | length 720.1
  Top Layer w5.3: U52.3@4629.96,551.89 4630.45,552.37 4645.7,552.37 4660.26,566.94 4689.63,566.94 4756.6,499.96 v1(4758.89,499.96)
  Bottom Layer w5.3: J5/J7.44@4404.17,250 4449.17,295 4535.31,295 4558.86,318.54 4558.86,446.75 4575.01,462.9 4644.11,461.75 4659.51,446.35 4723.37,446.35 4758.89,481.88 v1(4758.89,499.96)
AM263P_LIN2_TXD_R: R166.2 U1.A8 | length 218.4
  Top Layer w4: U1.A8@3767.61,1382.8 3767.61,1414.29
  Top Layer w5.3: 3767.61,1414.29 3767.61,1418.04 3775.9,1426.33 3775.9,1481.99 3769.66,1488.22 R166.2@3769.66,1595.2
AM263P_MCAN3_RX: R249.1 U1.B7 | length 6198.1
  Top Layer w4: 3718.3,1414.47 3718.54,1414.23 3718.54,1369.1 U1.B7@3736.16,1351.48
  Top Layer w5.3: v1(3710,1820.18) 3710.05,1820.13 3710.05,1748.76 3729.52,1729.29 3729.52,1724.38 3729.57,1724.32 3729.57,1693.81 3721.77,1686.01 3721.77,1569.08 3721.56,1568.87 3721.56,1527.25 3710.06,1515.75 3710.06,1422.71 3718.3,1414.47
  SIG 1 w4.75: v1(5738.52,2097.5) 5831.21,2097.5 5903.56,2169.85 6604.05,2169.85 6643.91,2129.99 6756.07,2129.99 6775.28,2110.79 6775.28,1953.39 6789.52,1939.14 6789.52,1335.16 6789.52,1246.1 6743.49,1200.06 6743.49,1110.67 6815.53,1038.63 6815.53,984.47 6964.3,835.7 6964.3,390.66 7054.96,300 7185.73,300 7238.93,246.79 7238.93,147.52 v1(7250,136.46)
  Bottom Layer w5.3: v1(3710,1820.18) 3720.07,1810.11 3808.02,1810.11 3809.93,1810.11 3811.4,1811.32 3850.38,1843.52 3926.48,1843.52 4035.14,1734.86 4120.54,1735.72 4192.3,1807.48 4412.57,1807.48 4430.26,1825.18 5015.92,1825.18 5177.59,1986.84 5627.87,1986.84 v1(5738.52,2097.5) ; R249.1@7223.62,61.46 7223.62,83.21 7250,109.59 v1(7250,136.46)
AM263P_MCAN3_TX: R401.1 U42.1 | length 5731.2
  Top Layer w5.3: R401.1@3678.01,1749.69 R401.1@3679.98,1751.65 ; R401.1@3678.01,1753.62 3678.01,1830.11 3697.42,1849.52 3807.81,1849.52 3907.15,1948.86 3981.85,1948.86 4022.13,1908.59 4429.83,1908.59 4452.32,1931.08 4452.32,2160.37 v1(4440.49,2175.15)
  SIG 1 w4.75: 5200,2146.14 5552.02,2146.14 5647.16,2051 5844,2051 5899.97,2106.97 6620.38,2106.97 6750,1977.35 6750,1964.45 6779.47,1934.98 6779.47,1330.99 6779.47,1250.26 6733.44,1204.22 6733.44,1101.56 6777.03,1057.97 6777.03,1001.63 6954.25,824.41 6954.25,370.75 7114.32,210.68 v1(7190.65,210.68)
  SIG 1 w5.3: v1(4440.49,2175.15) 4442.45,2175.15 4449.94,2182.64 5163.5,2182.64 5165.06,2181.09 5200,2146.14
  Bottom Layer w5.3: U42.1@7127.91,174.84 7155.75,174.84 7190.65,209.75 v1(7190.65,210.68)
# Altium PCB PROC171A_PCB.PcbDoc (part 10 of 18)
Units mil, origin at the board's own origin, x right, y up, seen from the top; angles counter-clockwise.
Board outline 7700 x 2300 mil, 6 copper layers (Top Layer, GND 1, SIG 1, SIG 2, GND 2, Bottom Layer), stack 61.062 mil thick; 945 components, 692 nets, 11945 pads, 1734 vias.

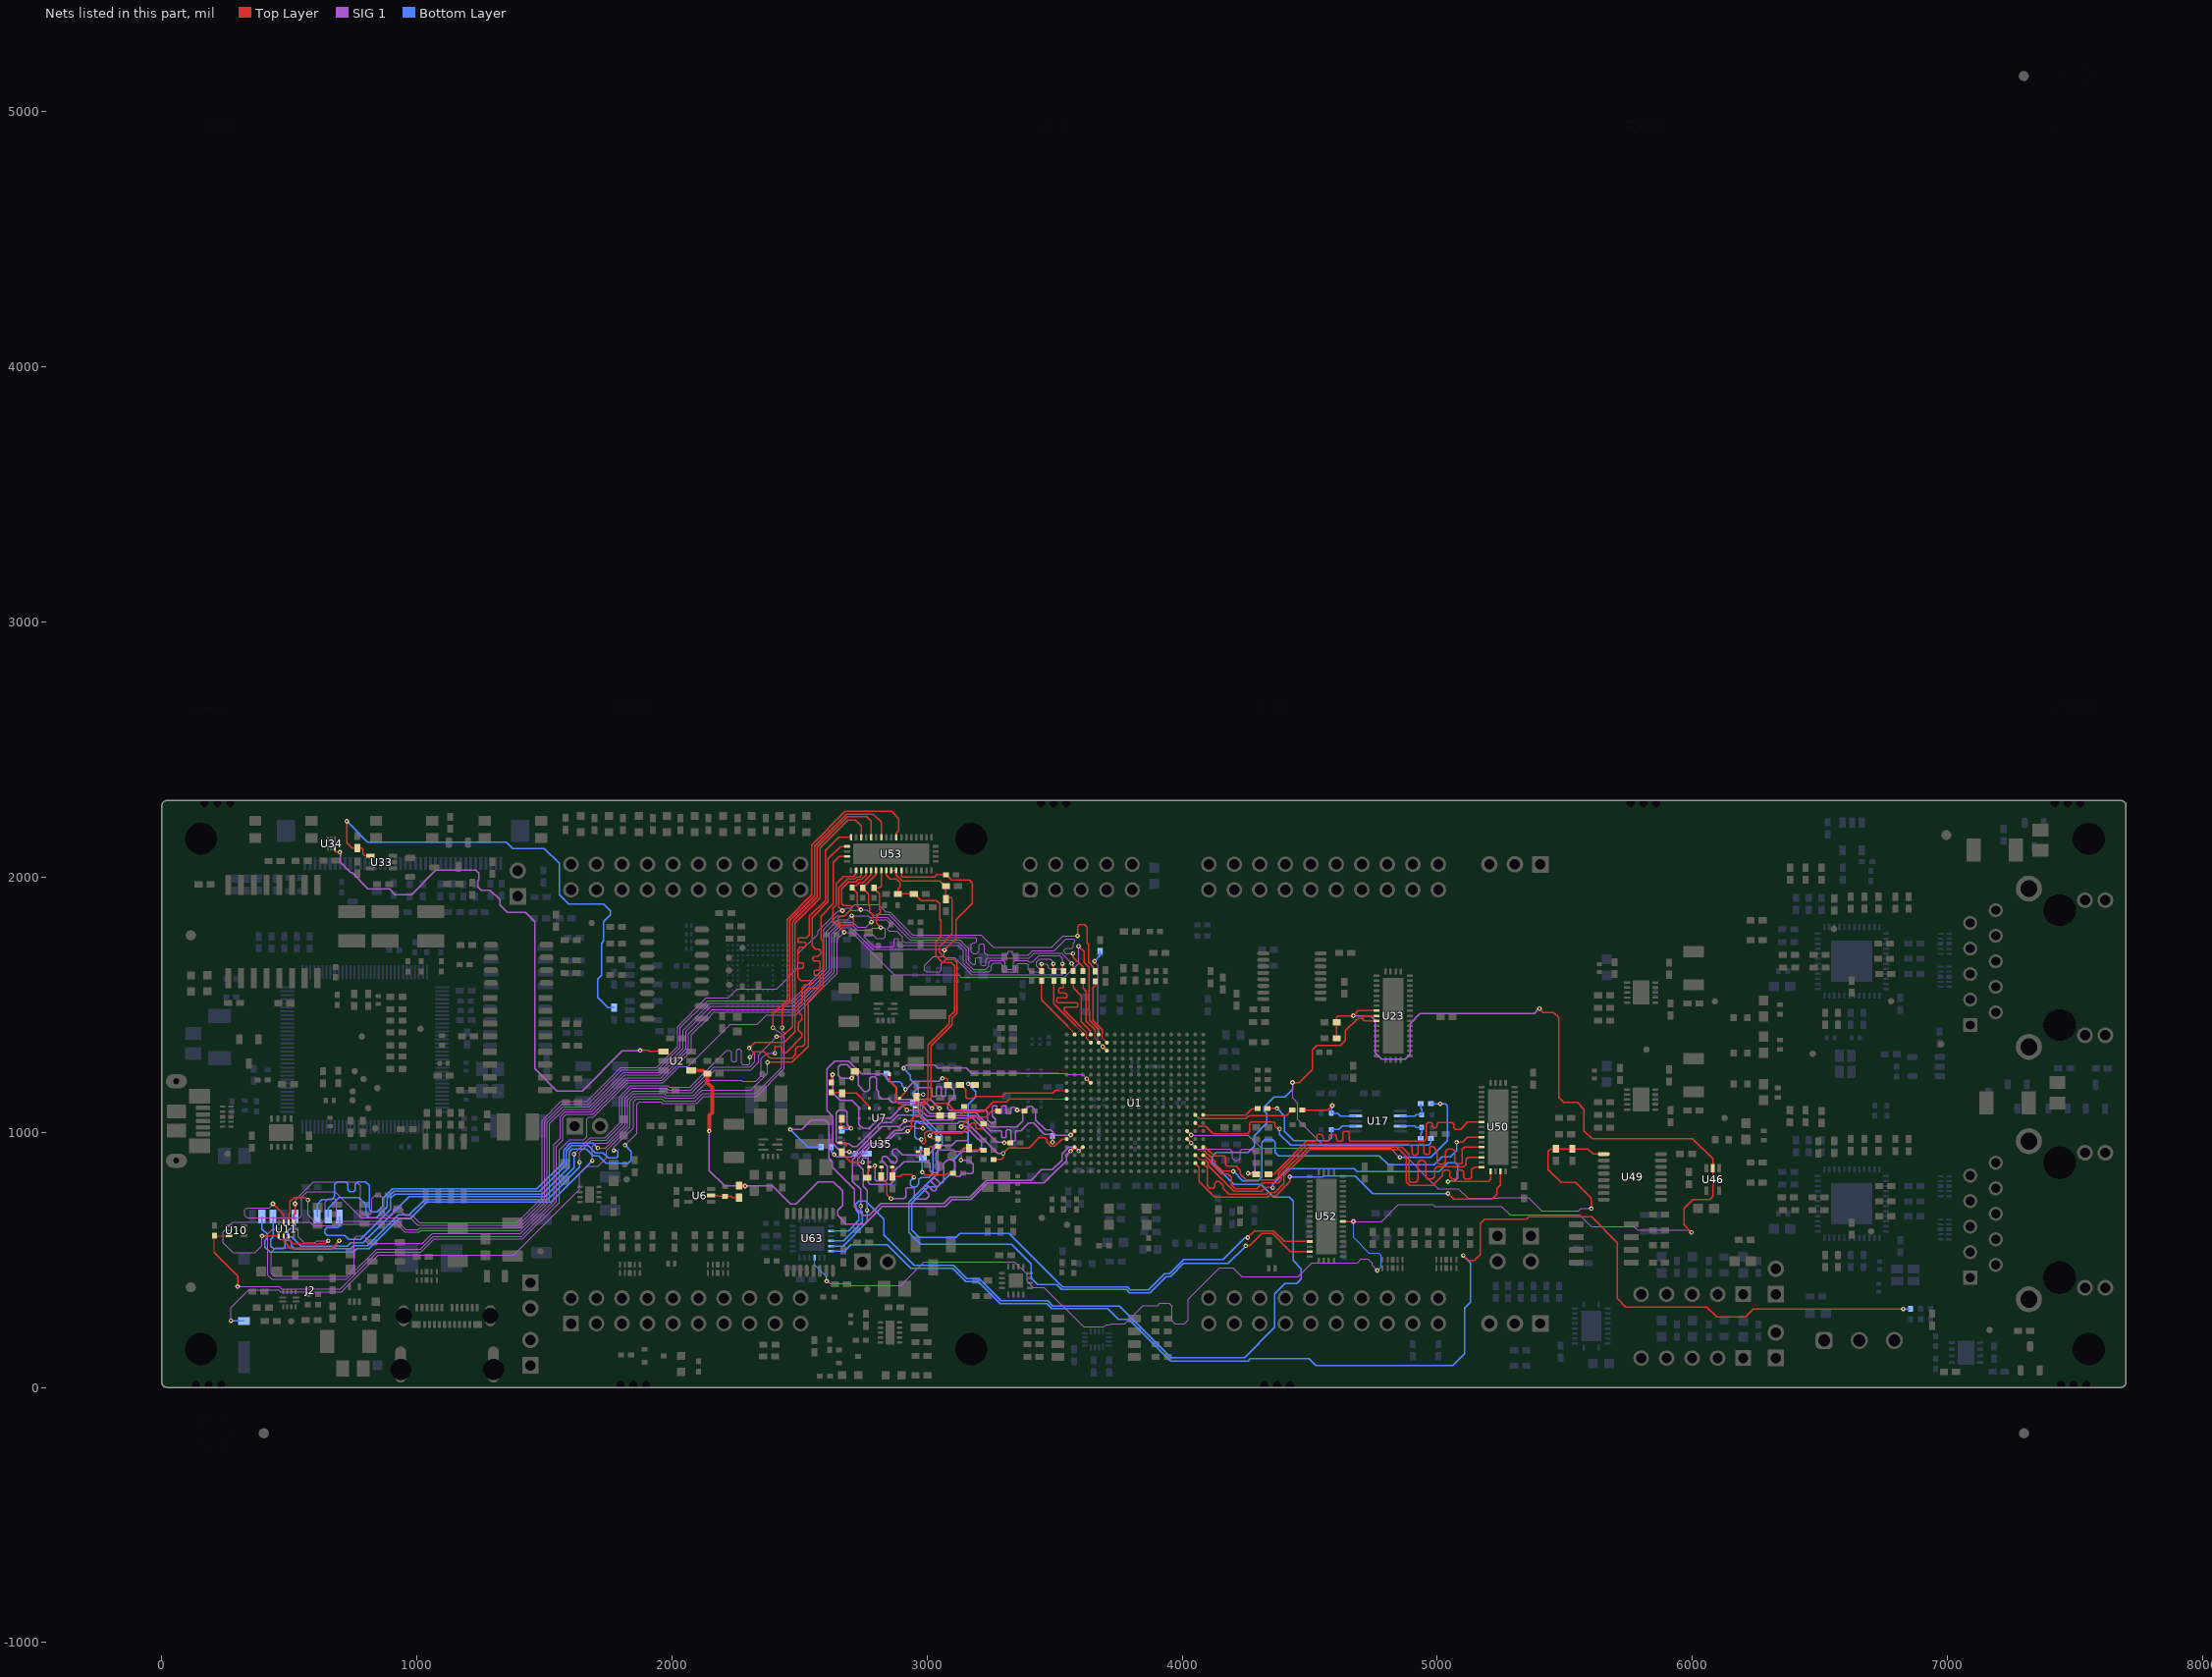
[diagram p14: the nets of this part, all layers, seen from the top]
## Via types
v1: diameter 18, hole 8, Top Layer to Bottom Layer, tented both sides, 1603 vias
v2: diameter 19.68, hole 7.87, Top Layer to Bottom Layer, tented both sides, 104 vias
v3: diameter 19.68, hole 7.87, Top Layer to Bottom Layer, 24 vias
v4: diameter 18, hole 8, Top Layer to Bottom Layer, 3 vias

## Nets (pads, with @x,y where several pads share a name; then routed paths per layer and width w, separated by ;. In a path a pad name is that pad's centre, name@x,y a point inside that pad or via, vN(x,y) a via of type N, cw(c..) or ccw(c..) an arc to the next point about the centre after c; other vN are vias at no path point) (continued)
AM263P_MCAN5_RX: U1.G4 U52.37 | length 3355.3
  Top Layer w5.3: v1(4248.9,554.83) 4263.88,554.83 4312.25,603.19 4353.85,603.19 4424.84,532.2 U52.37@4500.04,532.2
  Top Layer w10: v1(3625.87,1209.57) U1.G4@3641.62,1193.82
  SIG 1 w4: 3515.64,1230.74 3548.57,1230.74 3553.24,1226.06 3609.38,1226.06 v1(3625.87,1209.57)
  SIG 1 w5.3: v1(2908.1,1250.85) 2919.9,1262.64 3031.75,1262.64 3042.39,1252.01 3153.29,1252.01 3174.56,1230.74 3515.64,1230.74
  Bottom Layer w5.3: v1(2908.1,1250.85) 2935.33,1223.62 2935.33,1207.2 2964.58,1177.95 2964.58,1079.48 3059.43,984.63 3059.43,950.66 3042.1,933.34 3042.1,839.53 2928.94,726.37 2928.94,606.73 2974.2,561.47 3330.22,561.47 3408.32,483.36 3408.32,427.64 3433.18,402.78 3507.09,402.78 3526.79,383.08 3780.43,383.08 3792.51,370.99 3874.26,370.99 3937.73,434.47 3954.71,434.47 4005.38,485.13 4180.17,485.13 4248.9,553.86 v1(4248.9,554.83)
AM263P_MCAN5_TX: R393.1 U52.35 | length 2523.5
  Top Layer w5.3: v1(3161.4,1189.84) 3181.45,1189.84 R393.1@3186.59,1184.7 ; v1(4257.03,587.12) 4283.7,613.79 4358.24,613.79 4400.46,571.57 U52.35@4500.04,571.57
  Bottom Layer w5.3: v1(3161.4,1189.84) 3161.51,1189.84 3191.13,1160.22 3191.13,1139.17 3161.94,1109.98 3161.94,949.51 3108.72,896.29 3108.72,854.23 3041.29,786.8 3004.36,786.8 2939.54,721.98 2939.54,616.01 2968.44,587.12 3113.75,587.12 3129.26,602.64 3322.22,602.64 3531.18,393.68 3784.82,393.68 3796.9,381.59 3868.21,381.59 3931.69,445.07 3950.32,445.07 4006.23,500.98 4160.67,500.98 4245.23,585.54 4255.45,585.54 v1(4257.03,587.12)
AM263P_MCAN_STB: R248.2 U63.12 | length 5330.3
  Top Layer w5.3: v1(5101.72,516.99) 5121.65,497.06 5145.27,497.06 5168.3,520.09 5168.3,640.94 5186.45,659.09 5350.16,659.09 5359.07,668 5604.62,668 5705.96,566.66 5705.96,348.37 5739.06,315.27 6056.52,315.27 6096.31,275.48 6207.26,275.48 6239.03,307.24 v1(6826.84,307.24)
  Bottom Layer w5.3: U63.12@2624.13,534.62 2677.25,534.62 2701.47,558.84 2843.98,558.84 2936.34,466.48 3100.81,466.48 3152.4,414.89 3199.9,414.89 3286.21,328.58 3468.82,328.58 3488.82,308.57 3708.92,308.57 3751.32,266.17 3791.66,266.17 3954.71,103.13 4257.79,103.13 4266.49,111.82 4497.18,111.82 4523.95,85.05 5061.12,85.05 5106.93,130.86 5106.93,310.74 5130.3,334.11 5130.3,488.41 v1(5101.72,516.99) ; v1@6826.26,307.24 v1(6826.84,307.24) R248.2@6855,307.24
AM263P_MDIO0_MDC: R61.1 R63.1 U17.9 | length 130.6
  Bottom Layer w5.3: U17.9@4855.28,1024.06 4912.4,1024.06 4917.49,1018.97 4938.94,1018.97 R63.1@4939.04,1019.06 4939.04,998.96 4935.59,995.52 R61.1@4935.59,975.79
AM263P_MDIO0_MDC_R: R61.2 U1.M17 | length 1058.9
  Top Layer w4: U1.M17@4051.07,1036.34 4065.59,1021.81
  Top Layer w5.3: 4065.59,1021.81 4093.28,1021.81 4114.06,1001.03 4121.4,993.69 4255.66,993.69 4265.03,1003.07 4265.03,1035.03 4270.92,1040.92 4357.99,1040.92 4363.87,1035.03 4363.87,1022.8 4366.98,1019.7 4371.75,1019.7 4378.4,1013.04 v1(4381.84,1013.04)
  Bottom Layer w5.3: v1(4381.84,1013.04) 4381.84,992.8 4425.41,949.23 4967.26,949.23 4974.96,956.94 R61.2@4974.96,975.79
AM263P_MDIO0_MDIO: R62.1 R64.1 U17.7 | length 130.5
  Bottom Layer w5.3: U17.7@4855.28,1063.43 4912.49,1063.43 4917.49,1068.43 R64.1@4939.04,1068.43 4939.04,1091.03 4935.59,1094.48 R62.1@4935.59,1111.7
AM263P_MDIO0_MDIO_R: R62.2 U1.N16 | length 1294.4
  Top Layer w10: U1.N16@4019.57,1004.84 v1(4035.32,989.09)
  SIG 1 w4: v1(4035.32,989.09) 4114.06,989.09 4131,989.09
  SIG 1 w4.75: 4131,989.09 4258.35,989.09 4309.9,937.54 4815.65,937.54 4851.26,901.93 v1(4853.62,901.93)
  Bottom Layer w5.3: v1(4853.62,901.93) 4974.46,901.93 5040,967.46 5040,1103 5031.39,1111.61 v1(5011.92,1111.61) 5011.82,1111.7 R62.2@4974.96,1111.7
AM263P_MMC0_CD: R40.1 U1.A5 U10.3 U53.2 | length 5275.8
  Top Layer w4.75: 206.73,527.27 R40.1@206.73,594.53 U10.3@263.65,594.53
  Top Layer w5.3: 206.73,527.27 297.36,436.64 v1(297.36,395) ; v1(2675.17,1783.7) 2658.92,1799.95 2630,1828.87 2630,1838.8 2630,1877.23 2643.93,1891.16 2643.93,1972.58 2673.77,2002.43 2711.32,2002.43 2720.37,2011.48 2720.37,2024.45 U53.2@2721.99,2026.07 ; v1(3593.34,1728.9) 3615,1707.24 3615,1666.25 3635.54,1645.71 3635.54,1515.34 3635.55,1515.28 3636.55,1438.26 3673.12,1401.69 U1.A5@3673.12,1382.8
  SIG 1 w4.75: v1@297.59,394.77 459.45,394.77 469.24,384.98 699.94,384.98 844.57,529.61 1015.56,529.61 1067.88,581.93 1414.98,581.93 1557.84,724.79 1557.84,929.75 1599.1,971 1654.47,971 1666.71,983.24 1666.71,1051.71 1674,1059 1692,1059 1826.76,1193.76 1965.21,1193.76 2028.85,1257.4 2062.18,1257.4 2228.28,1423.5 2334.78,1423.5 2371.71,1460.43 2485.62,1460.43 2648.8,1623.61 2648.8,1757.33 v1(2675.17,1783.7) 2704.67,1783.7 2871.93,1616.44 3124.21,1616.44 3133.71,1606.94 3539.39,1606.94 3594.06,1661.61 3594.06,1728.18 v1(3593.34,1728.9)
AM263P_MMC0_CD_MUX: J2.9 U53.41 | length 3771
  Top Layer w5.3: v1(2374.56,1274.02) 2470.81,1274.02 2533.98,1337.18 2533.98,1376.45 2533.98,1511.43 2592.56,1570.01 2592.56,1749.19 2583.63,1758.11 2583.63,1833.15 2583.63,1845.86 2633.33,1895.55 2633.33,2058.59 2655.93,2081.19 U53.41@2686.56,2081.19
  SIG 1 w4.75: v1(271.44,261.02) 271.44,312.62 341.13,382.31 457.69,382.31 465.35,374.65 704.22,374.65 849.12,519.56 1379.7,519.56 1637.5,777.36 1637.5,837.94 1665.63,866.06 1709.86,866.06 1743.85,900.05 1743.85,928.21 1836.74,1021.11 1836.74,1122.46 1855.31,1141.04 1965.77,1141.04 1972.5,1134.31 2087.91,1134.31 2118.97,1165.38 2309.98,1165.38 2374.56,1229.95 v1(2374.56,1274.02)
  Bottom Layer w5.3: v1(271.44,261.02) 272.3,260.16 J2.9@321.97,260.16
AM263P_MMC0_CLK: R33.2 U11.1 U53.3 | length 4833
  Top Layer w5.3: U11.1@517.72,646.57 517.72,676.24 522.76,681.27 v1(522.76,719.45) ; v1(2668.36,1868.5) 2668.17,1868.5 2654.53,1882.15 2654.53,1957.78 2688.57,1991.83 2715.71,1991.83 2725.05,2001.17 2735.53,2001.17 2741.68,2007.32 U53.3@2741.68,2026.07 ; v1(3590,1770) 3590,1805.93 3597.16,1813.09 3617.68,1813.09 3627.54,1803.23 3627.54,1742.08 3632.71,1736.91 3632.71,1666.46 3652.35,1646.82 3652.35,1638.24 R33.2@3659.54,1631.05
  SIG 1 w4.75: v1(522.76,719.45) 524.7,721.39 524.7,735.57 595.21,806.09 764.45,806.09 780,790.54 780,689.1 791.64,677.46 815.94,677.46 823.99,685.51 823.99,739.81 835.39,751.21 858.79,751.21 871.44,738.56 871.44,680.97 878.15,674.26 900,674.26 907.66,681.93 907.66,698.12 915,705.46 935.75,705.46 945,696.21 945,684.26 955,674.26 982.34,674.26 1010.41,646.19 1393.97,646.19 1490.63,742.85 1490.63,1046.3 1564.66,1120.32 1665.63,1120.32 1799.37,1254.06 1939.62,1254.06 2022.85,1337.29 2022.85,1414.16 2134.82,1526.14 2143.18,1526.14 2219.72,1526.14 2256.12,1562.54 2410.68,1562.54 2494.16,1646.02 2494.16,1699.41 2572.18,1777.43 2572.18,1789.03 2621.95,1838.8 2651.46,1868.31 2668.17,1868.31 v1(2668.36,1868.5) ; v1@2668.45,1868.22 2671.59,1868.22 2682.25,1878.88 2704.53,1878.88 2717.25,1891.6 2808.88,1891.6 2810.79,1889.69 2835.79,1864.7 2836.85,1863.64 2852.91,1863.64 2941.55,1775 2942.94,1773.61 3211.39,1773.61 3260.01,1724.99 3488.2,1724.99 3533.21,1770 v1(3590,1770)
AM263P_MMC0_CLK_MUX: J2.5 U53.39 | length 3761.6
  Top Layer w5.3: v1(2305.75,1294.59) 2326.61,1315.45 2360.73,1315.45 2385.77,1290.42 2470.46,1290.42 2485.1,1305.05 2485.1,1326.89 2494.5,1336.29 2510.53,1336.29 2520.65,1346.41 2520.65,1550.44 2535.68,1565.47 2573.03,1565.47 2581.43,1573.87 2581.43,1609.25 2574.89,1615.78 2560.89,1615.78 2557.78,1618.89 2557.78,1632.28 2560.89,1635.38 2575.45,1635.38 2581.43,1641.35 2581.43,1665.96 2576.68,1670.71 2558.11,1670.71 2552.12,1676.7 2552.12,1682.82 2557.99,1688.69 2571.83,1688.69 2581.96,1698.82 2581.96,1711.43 2576.68,1716.71 2563.49,1716.71 2549.32,1730.88 2549.32,1833.15 2549.32,1841.52 2612.13,1904.34 2612.13,2071.87 2660.82,2120.56 U53.39@2686.56,2120.56
  SIG 1 w4.75: v1(1615.98,914.12) 1615.98,914.45 1679.34,977.81 1680.12,977.81 1680.33,978.02 1736.73,978.02 1795,1036.29 1795,1140.68 1837.75,1183.44 1983.34,1183.44 1990.06,1176.71 2070.35,1176.71 2214.27,1320.63 2227.09,1320.63 2234.25,1313.48 2234.25,1280.57 2238.3,1276.53 2248.73,1276.53 2252.53,1280.32 2252.53,1320.14 2258.78,1326.4 2265.47,1326.4 2271.96,1319.91 2271.96,1270.43 2276.34,1266.06 2300.9,1266.06 2305.75,1270.91 v1(2305.75,1294.59)
  Bottom Layer w5.3: J2.5@522.76,669.61 522.76,634.79 509.41,621.44 502.92,621.44 491.43,609.95 491.43,599.14 501.08,589.49 510.38,589.49 546.06,553.81 728.34,553.81 740.29,565.76 788.8,565.76 970.06,747.02 1502.58,747.02 1615.98,860.43 v1(1615.98,914.12)
AM263P_MMC0_CLK_R: R33.1 U1.B6 | length 266.1
  Top Layer w4: 3687.64,1387.89 3687.64,1368.27 U1.B6@3704.61,1351.3
  Top Layer w5.3: R33.1@3659.54,1591.68 3659.54,1575.93 3650.97,1567.36 3650.97,1438.83 3687.64,1402.16 3687.64,1387.89
AM263P_MMC0_CMD: R34.2 U11.2 U53.4 | length 4896
  Top Layer w5.3: U11.2@498.04,646.57 498.04,678.5 503.23,683.69 503.23,727.54 519.46,743.77 563.58,743.77 v1(573.09,734.25) ; v1(2704.82,1848.92) 2704.82,1845.48 2710.75,1839.55 2710.75,1815.86 2704.08,1809.19 2664.67,1809.19 2658.92,1814.94 2651.41,1822.45 2651.41,1838.8 2651.41,1841.04 2659.16,1848.78 2676.45,1848.78 2703.78,1876.11 2703.78,1886.11 2700.67,1889.22 2672.73,1889.22 2665.13,1896.82 2665.13,1953.39 2692.96,1981.23 2720.1,1981.23 2729.44,1990.57 2743.02,1990.57 2761.36,2008.91 U53.4@2761.36,2026.07 ; v1(3566.83,1661.6) 3566.83,1658.16 3573,1651.99 R34.2@3573,1632.17
  SIG 1 w4.75: v1(573.09,734.25) 573.09,677.22 605.31,645 628.72,645 640,656.28 640,727.32 652.68,740 676.6,740 685,731.6 685,655 689.31,650.69 925.2,650.69 957.03,618.86 1005.9,618.86 1012,624.97 1401.17,624.97 1510.73,734.53 1510.73,1037.97 1572.98,1100.22 1676.37,1100.22 1810.11,1233.96 1948.56,1233.96 2042.95,1328.35 2042.95,1400.05 2143.18,1500.28 2148.21,1505.31 2473.31,1505.31 2606,1638 2606,1787.43 2626.92,1808.35 2651.87,1833.3 2689.19,1833.3 v1(2704.82,1848.92) 2768.24,1848.92 2774.04,1843.12 2782.57,1843.12 2782.64,1843.05 2845.07,1843.05 2846.98,1841.15 2933.23,1754.9 2934.62,1753.51 3129.7,1753.51 3163.48,1719.74 3163.48,1671.72 3178.14,1657.05 3186.14,1657.05 3191.15,1662.07 3191.15,1682.48 3193.93,1685.26 3209.52,1685.26 3212.3,1682.48 3212.3,1656.28 3215.08,1653.5 3228.41,1653.5 3231.19,1656.28 3231.19,1677.22 3237.62,1683.64 3400.47,1683.64 3418.77,1701.95 3526.48,1701.95 v1(3566.83,1661.6)
AM263P_MMC0_CMD_MUX: J2.3 U53.38 | length 3765.4
  Top Layer w5.3: v1(2403.69,1309.94) 2403.69,1333.19 2406.8,1336.29 2426.66,1336.29 2429.76,1333.19 2429.76,1317.74 2435.64,1311.86 2446.9,1311.86 2510.05,1375.01 2510.05,1385.95 2496.52,1399.48 2496.52,1429.36 2510.05,1442.89 2510.05,1458.33 2496.52,1471.86 2496.52,1497.11 2509.57,1510.17 2509.57,1564.57 2522.98,1577.98 2542.9,1577.98 2546,1581.08 2546,1591.98 2542.83,1595.14 2504.59,1595.14 2493.16,1606.58 2493.16,1638.81 2496.86,1642.52 2510.66,1642.52 2515.43,1647.29 2515.43,1660.98 2512.63,1663.77 2496.94,1663.77 2493.16,1667.56 2493.16,1716.21 2501.29,1724.35 2517.73,1724.35 2523.98,1730.6 2523.98,1740.19 2520.64,1743.53 2497.9,1743.53 2493.16,1748.27 2493.16,1758.05 2497.77,1762.66 2527.28,1762.66 2538.72,1774.1 2538.72,1833.15 2538.72,1845.91 2601.53,1908.73 2601.53,2103.35 2654.17,2156 U53.38@2702.31,2156
  SIG 1 w4.75: v1(1709.17,938.04) 1739.4,938.04 1826.05,1024.7 1826.05,1025.41 1826.14,1025.5 1826.14,1126.85 1850.92,1151.64 1970.16,1151.64 1976.89,1144.91 2083.52,1144.91 2143.03,1204.42 2273.09,1204.42 2277.03,1200.48 2329.29,1200.48 2349.67,1220.86 2349.67,1287.4 2372.22,1309.94 v1(2403.69,1309.94)
  Bottom Layer w5.3: J2.3@609.37,669.61 609.37,717.57 628,736.2 666.72,736.2 677.39,746.87 677.39,795.06 688.42,806.09 720.7,806.09 728.57,798.22 728.57,773.79 736.24,766.13 751.5,766.13 758.91,773.54 758.91,796.04 768.97,806.09 799.28,806.09 813.89,791.48 813.89,697.22 822.5,688.61 845.2,688.61 865.47,708.88 865.47,739.37 904.92,778.82 1470.84,778.82 1575.26,883.24 1575.26,930.99 1601.77,957.5 1689.71,957.5 v1(1709.17,938.04)
AM263P_MMC0_CMD_R: R34.1 U1.A4 | length 238.4
  Top Layer w5.3: R34.1@3573,1592.8 3573,1567.42 3605,1535.42 3605,1433.11 3639.62,1398.48 3639.62,1384.79 U1.A4@3641.62,1382.8
AM263P_MMC0_D0: R35.2 R386.1 U11.3 U53.5 | length 5121.3
  Top Layer w5.3: v1(436.14,719.45) 478.35,677.24 U11.3@478.35,646.57 ; v1(2740.42,1872.35) 2740.42,1872.63 2726.86,1886.19 2726.86,1937.51 2706.97,1957.4 2706.97,1961.33 2714.16,1968.53 2722.61,1968.53 2734.05,1979.97 2750.52,1979.97 2781.05,2010.5 U53.5@2781.05,2026.07 ; v1(3571.76,1700) 3572.49,1699.27 3572.49,1687.36 3611,1648.84 R35.2@3611,1632.17
  SIG 1 w4.75: v1(436.14,719.45) 420.83,704.14 334.14,704.14 325,695 325,675 335,665 539.81,665 549.08,674.26 549.08,745.74 569.32,765.98 680,765.98 781.77,664.21 973.75,664.21 1001.82,636.14 1398.14,636.14 1500.68,738.69 1500.68,1042.13 1568.82,1110.27 1669.79,1110.27 1803.53,1244.01 1944.4,1244.01 2032.9,1332.52 2032.9,1408.94 2139.32,1515.36 2468.36,1515.36 2595,1642 2595,1795.68 2638.12,1838.8 2648.58,1849.25 2677.56,1849.25 2697.14,1868.83 2720.09,1868.83 2723.62,1872.35 v1(2740.42,1872.35) 2765.55,1872.35 2784.73,1853.17 2786.73,1853.17 2786.8,1853.1 2806.41,1853.1 2806.56,1853.26 2849.08,1853.26 2937.39,1764.95 2938.78,1763.56 3188.99,1763.56 3193.88,1758.67 3193.88,1748 3188.96,1743.08 3180.09,1743.08 3173.53,1736.52 3173.53,1708.22 3181.71,1700.04 3194.5,1700.04 3204.48,1710.02 3204.48,1734.45 3209.44,1739.41 3222.09,1739.41 3225.68,1735.81 3225.68,1704.29 3236.28,1693.69 3308.07,1693.69 3316.97,1702.59 3316.97,1707.55 3319.75,1710.34 3332.9,1710.34 3335.68,1707.55 3335.68,1696.48 3338.46,1693.69 3396.31,1693.69 3414.61,1712 3497.75,1712 3544.42,1758.67 3574.11,1758.67 3579.33,1753.45 3579.33,1745.49 3574.09,1740.25 3574.09,1724.22 3571.3,1721.44 3544.9,1721.44 3537.18,1713.71 3537.18,1707 3544.18,1700 v1(3571.76,1700)
AM263P_MMC0_D0_MUX: J2.7 U53.36 | length 3764
  Top Layer w5.3: v1(2302.92,1330.48) 2324.88,1352.44 2440.17,1352.44 2464.18,1376.45 2482.56,1394.83 2482.56,1819.74 2495.97,1833.15 2580.33,1917.51 2580.33,2113.16 2690.78,2223.61 2718.42,2223.61 2741.84,2200.18 2741.84,2158.1 U53.36@2743.95,2156
  SIG 1 w4.75: v1(1638.2,882.48) 1638.2,921.68 1684.49,967.97 1740.9,967.97 1805.05,1032.12 1805.05,1135.74 1842.14,1172.84 1978.95,1172.84 1985.67,1166.11 2074.74,1166.11 2164.08,1255.46 2304.51,1255.46 2325.28,1276.22 2325.28,1307.19 2302.92,1329.55 v1(2302.92,1330.48)
  Bottom Layer w5.3: J2.7@436.14,669.61 436.14,589.22 427.31,580.39 427.31,553.97 438.06,543.21 475.59,543.21 482.69,550.32 482.69,569.23 489.55,576.09 501.35,576.09 507.69,569.75 507.69,555.14 519.62,543.21 740.75,543.21 752.7,555.16 806.7,555.16 927.5,675.96 970.21,675.96 1030.67,736.42 1512.41,736.42 1638.2,862.21 v1(1638.2,882.48)
AM263P_MMC0_D0_R: R35.1 U1.B5 | length 267.2
  Top Layer w4: 3657.37,1390.67 3657.37,1367.05 U1.B5@3673.12,1351.3
  Top Layer w5.3: R35.1@3611,1592.8 3611,1566 3624.4,1552.6 3624.4,1435.42 3657.37,1402.45 3657.37,1390.67
AM263P_MMC0_D1: R36.2 R385.1 U11.6 U53.6 | length 5020.7
  Top Layer w5.3: v1(393.42,593.25) 393.59,593.43 U11.6@458.67,593.43 ; v1(2781.35,1823.85) 2781.35,1836.36 2787.97,1842.98 2787.97,1851.54 2775.25,1864.27 2775.25,1887.05 2771.05,1891.25 2771.05,1933.14 2748.06,1956.14 2748.06,1960.07 2755.25,1967.27 2757.22,1967.27 2800.73,2010.78 U53.6@2800.73,2026.07 ; v1(3530.86,1660.05) 3530.86,1636.3 R36.2@3535,1632.17
  SIG 1 w4.75: v1(393.42,593.25) 393.42,554.93 366.39,527.91 278.68,527.91 240,566.59 240,610 276.98,646.98 581.73,646.98 595.25,633.46 676.72,633.46 683.9,640.64 921.04,640.64 952.86,608.81 1010.06,608.81 1015.95,614.7 1405.12,614.7 1520.78,730.36 1520.78,1033.81 1577.14,1090.17 1680.53,1090.17 1814.27,1223.91 1952.72,1223.91 2055.08,1326.27 2055.08,1395.68 2143.18,1483.78 2154.21,1494.81 2477.36,1494.81 2617,1634.45 2617,1781.18 2658.87,1823.05 2661.16,1823.05 2661.36,1823.25 2709.1,1823.25 2728.7,1803.65 2761.15,1803.65 v1(2781.35,1823.85) 2790.51,1833 2840.91,1833 2856.24,1817.68 2856.24,1810.16 2846.37,1800.29 2846.37,1793.92 2852.56,1787.72 2881.1,1787.72 2904.17,1764.65 2904.17,1750.06 2910.77,1743.46 3125.54,1743.46 3153.43,1715.57 3153.43,1666.19 3180.41,1639.21 3229.93,1639.21 3241.53,1650.81 3241.53,1667.52 3247.6,1673.59 3298.34,1673.59 3305.82,1666.12 3305.82,1644.5 3311.58,1638.74 3335.38,1638.74 3338.72,1642.07 3338.72,1666.7 3344.57,1672.56 3395.28,1672.56 3401.22,1666.61 3413.95,1666.61 3439.23,1691.9 3519.54,1691.9 3530.86,1680.58 v1(3530.86,1660.05)
AM263P_MMC0_D1_MUX: J2.8 U53.34 | length 3763.4
  Top Layer w5.3: v1(2410.24,1374.64) 2432.79,1374.64 2471.96,1413.81 2471.96,1824.13 2480.98,1833.15 2569.73,1921.9 2569.73,2117.55 2688.33,2236.15 2764.22,2236.15 2781.05,2219.32 U53.34@2781.05,2156
  SIG 1 w4.75: v1(1688.2,888.4) 1688.2,944.69 1701.41,957.9 1743.55,957.9 1745.06,957.92 1816,1028.86 1816,1131.7 1846.53,1162.24 1974.55,1162.24 1981.28,1155.51 2079.13,1155.51 2168.47,1244.86 2308.91,1244.86 2339.07,1275.02 2339.07,1303.48 v1(2410.24,1374.64)
  Bottom Layer w5.3: J2.8@392.83,669.61 392.83,621.44 412.94,601.34 412.94,585.16 405.02,577.25 405.02,549.54 424.8,529.76 750.7,529.76 765.5,544.56 812.22,544.56 928.51,660.86 973.54,660.86 1038.51,725.82 1525.63,725.82 v1(1688.2,888.4)
AM263P_MMC0_D1_R: R36.1 U1.B4 | length 490
  Top Layer w4: 3601.58,1414.29 3625.87,1390 3625.87,1367.05 U1.B4@3641.62,1351.3
  Top Layer w5.3: R36.1@3535,1592.8 3535.16,1592.64 3535.16,1580.99 3535.12,1580.94 3535.12,1568.69 3532.01,1565.58 3517.93,1565.58 3514.83,1562.48 3514.83,1549.97 3517.93,1546.87 3540.93,1546.87 3547.57,1540.23 3547.57,1530.56 3544.46,1527.46 3511.96,1527.46 3508.85,1524.35 3508.85,1512.26 3513.35,1507.77 3587.55,1507.77 3590.65,1504.66 3590.65,1494.1 3586.1,1489.55 3541.65,1489.55 3536.18,1484.08 3536.18,1479.69 3552.93,1462.95 3601.58,1414.29
AM263P_MMC0_D2: R37.2 R384.1 U11.7 U53.7 | length 5531.2
  Top Layer w5.3: U11.7@478.35,593.43 478.35,571.65 505.48,544.52 665.86,544.52 v1(695.98,574.65) ; R384.1@2792.16,1958.1 2812.53,1958.1 2820.42,1966 U53.7@2820.42,2026.07 ; R384.1@2792.16,1960.07 2792.16,1956.14 2813.04,1935.25 2813.04,1881.69 2814.17,1880.57 2814.17,1874.6 2817.62,1871.14 2817.62,1861.71 2800.88,1844.96 2800.88,1819.59 v1(2818.2,1802.27) ; v1(3494.86,1660.24) 3494.86,1634.3 R37.2@3497,1632.17
  SIG 1 w4.75: v1(695.98,574.65) 687.35,566.01 687.35,557.12 676.74,546.51 446.51,546.51 430.11,530.11 430.11,447.99 441.64,436.46 723,436.46 755,468.46 755,583.25 765,593.25 791.75,593.25 800,585 800,572.73 808.85,563.88 1021.4,563.88 1059.98,602.46 1407.09,602.46 1537.74,733.11 1537.74,951.54 1561.89,975.68 1561.89,1060.7 1581.31,1080.12 1684.69,1080.12 1818.44,1213.86 1956.88,1213.86 2065.13,1322.1 2065.13,1387.4 2143.18,1465.45 2158.25,1480.53 2477.29,1480.53 2627.05,1630.29 2627.05,1777.01 2663.03,1813 2705.14,1813 2725.85,1792.29 2778.84,1792.29 2786.33,1799.78 2815.71,1799.78 v1(2818.2,1802.27) 2829.92,1802.27 2836.32,1795.87 2836.32,1768.02 2828.2,1759.9 2802.74,1759.9 2786.85,1775.79 2758.05,1775.79 2752.97,1770.7 2752.97,1765.17 2791.39,1726.74 2864.95,1726.74 2871.68,1733.47 2871.68,1755.76 2875.82,1759.9 2884.34,1759.9 2888.8,1755.44 2888.8,1729.53 2891.58,1726.74 2904.55,1726.74 2911.21,1733.41 3121.38,1733.41 3143.38,1711.41 3143.38,1662.03 3176.25,1629.16 3243.42,1629.16 3251.58,1637.32 3251.58,1653.74 3261.38,1663.54 3287.1,1663.54 3295.77,1654.88 3295.77,1634.13 3301.21,1628.69 3342.08,1628.69 3348.77,1635.38 3348.77,1654.22 3357.06,1662.51 3391.11,1662.51 3397.12,1656.5 3397.12,1637.97 3406.36,1628.73 3443.78,1628.73 3446.56,1631.51 3446.56,1635.44 3429.75,1652.26 3429.75,1668.2 3441.03,1679.48 3483.07,1679.48 3492.33,1670.22 3492.33,1662.78 v1(3494.86,1660.24)
AM263P_MMC0_D2_MUX: J2.1 U53.32 | length 3762.2
  Top Layer w5.3: v1(2431.8,1409.49) 2431.8,1484.2 2461.36,1513.76 2461.36,1828.52 2465.98,1833.15 2559.13,1926.29 2559.13,2121.94 2683.94,2246.75 2788.94,2246.75 2820.42,2215.27 U53.32@2820.42,2156
  SIG 1 w4.75: v1(1816.37,949.19) 1862.83,995.64 1862.83,1110.01 1872.66,1119.84 1956.99,1119.84 1963.72,1113.11 2096.69,1113.11 2124.66,1141.08 2332.34,1141.08 2440.36,1249.1 2440.36,1387.98 2431.8,1396.55 v1(2431.8,1409.49)
  Bottom Layer w5.3: J2.1@695.98,669.61 695.98,633.83 688.52,626.36 648.03,626.36 639.26,617.59 639.26,604.48 647.69,596.06 717.09,596.06 733.11,580.04 779.9,580.04 897.49,697.63 897.49,741.41 913.7,757.62 1491.33,757.62 1596.46,862.75 1596.46,922.21 1607.89,933.64 1665.49,933.64 1691.21,907.92 1712.5,907.92 1741.9,878.52 1828.28,878.52 1840.53,890.77 1840.53,925.02 v1(1816.37,949.19)
AM263P_MMC0_D2_R: R37.1 U1.A3 | length 257.6
  Top Layer w4: 3584.29,1415.65 3610.12,1389.82 U1.A3@3610.13,1382.8
  Top Layer w5.3: R37.1@3497,1592.8 3496.11,1591.91 3496.11,1572.59 3496.07,1572.55 3496.07,1503.87 3584.29,1415.65
AM263P_MMC0_D3: R38.2 R383.1 U11.8 U53.11 | length 5777.3
  Top Layer w5.3: U11.8@498.04,593.43 498.04,577.3 513.12,562.22 640.25,562.22 v1(652.68,574.65) ; U53.11@2899.16,2026.07 2899.16,2004.24 2903.17,2000.23 3028.68,2000.23 3037.72,2009.27 3076.02,2009.27 3095.92,1989.38 3165.37,1989.38 3177.32,1977.42 3177.32,1897.18 3113.15,1833.01 3113.15,1759.04 v1(3068.27,1714.16) ; R38.2@3449,1632.17 v1(3449,1660.23)
  SIG 1 w4.75: v1(652.68,574.65) 651.96,573.93 607.59,573.93 599.42,565.76 558.64,565.76 535,589.4 535,614.59 524.59,625 504.26,625 495.34,616.08 495.34,589.74 485,579.4 463.85,579.4 455,588.25 455,614.15 450.29,618.86 432.51,618.86 415.82,602.17 415.82,439.18 431.52,423.48 724.23,423.48 842.26,541.51 1013.25,541.51 1064.15,592.41 1411.25,592.41 1547.79,728.95 1547.79,944.32 1571.94,968.46 1571.94,1056.54 1585.47,1070.07 1688.86,1070.07 1822.6,1203.81 1961.05,1203.81 2077.07,1319.84 2077.07,1382.85 2143.18,1448.95 2164.7,1470.48 2481.45,1470.48 2637.1,1626.13 2637.1,1772.85 2667.2,1802.95 2700.98,1802.95 2787.23,1716.69 3065.74,1716.69 v1(3068.27,1714.16) 3068.27,1696.45 3059.46,1687.63 3024.43,1687.63 2990.9,1654.1 2990.9,1635.38 2997.59,1628.68 3047.94,1628.68 3056.58,1637.32 3056.58,1660.34 3080.45,1684.22 3106.98,1684.22 3174.21,1616.99 3530.25,1616.99 3533.03,1619.77 3533.03,1637.2 3530.25,1639.99 3481.5,1639.99 3475.46,1646.02 3475.46,1652.8 3468.03,1660.23 v1(3449,1660.23)
AM263P_MMC0_D3_MUX: J2.2 U53.29 | length 3772.1
  Top Layer w5.3: v1@2395.8,1409.72 2395.8,1463.19 2450.76,1518.15 2450.76,1832.91 2450.99,1833.15 2548.53,1930.68 2548.53,2126.33 2679.55,2257.35 2861.18,2257.35 2888.64,2229.89 2888.64,2181.62 2879.47,2172.45 U53.29@2879.47,2156
  SIG 1 w4.75: v1(1772.09,928.85) 1773.12,929.88 1773.12,941.12 1848.96,1016.96 1848.96,1118.34 1861.05,1130.44 1961.38,1130.44 1968.11,1123.71 2092.3,1123.71 2120.27,1151.68 2327.95,1151.68 2429.76,1253.49 2429.76,1383.59 2417.77,1395.59 2412.71,1395.59 v1(2395.8,1409.49)
  Bottom Layer w5.3: J2.2@652.68,669.61 652.66,702.16 695.03,744.52 772.3,744.52 800.52,716.3 800.52,676.5 812.81,664.21 841.67,664.21 883.75,706.3 883.75,742.67 909.31,768.22 1481.68,768.22 1585.86,872.4 1585.86,926.6 1606.05,946.79 1671.84,946.79 1700.11,918.52 1730.94,918.52 1750.31,899.15 1782.62,899.15 1787.66,904.18 1787.66,924.1 1783.74,928.01 1772.92,928.01 v1(1772.09,928.85)
AM263P_MMC0_D3_R: R38.1 U1.A2 | length 263.7
  Top Layer w4: 3552.24,1414.29 3552.24,1414.13 3572.18,1394.19 3572.18,1390.31 3578.63,1383.86 U1.A2@3578.63,1382.8
  Top Layer w5.3: R38.1@3449,1592.8 3449,1519.25 3552.24,1416.01 3552.24,1414.29
AM263P_MMC0_WP: R41.1 U1.C6 | length 419.3
  Top Layer w10: v1(3688.87,1335.55) U1.C6@3704.61,1319.8
  SIG 1 w4: 3669.62,1414.29 3669.62,1354.8 v1(3688.87,1335.55)
  SIG 1 w4.75: v1(3656.59,1670.19) 3656.59,1668.1 3669.62,1655.07 3669.62,1430 3669.62,1414.29
  Bottom Layer w5.3: v1(3656.59,1670.19) 3678.01,1691.61 R41.1@3678.01,1710.32
AM263P_MMC_MUX_EN: R390.2 R392.2 U53.8 U63.11 | length 2034.7
  Top Layer w5.3: U53.8@2840.1,2026.07 2840.1,2008.48 2855.49,1993.1 2879.58,1993.1 2893.92,1978.76 2893.92,1961.82 2886.08,1953.99 R392.2@2886.08,1934.22 2947.25,1934.22 R390.2@2947.83,1933.65 2951.77,1933.65 2976.89,1908.52 3036.96,1908.52 3049.74,1895.75 3049.74,1834.27 3054.23,1829.78 3054.23,1820.75 3054.34,1820.64 3054.34,1767.74 3033.75,1747.15 3033.75,1692.02 3060.58,1665.2 3093.94,1665.2 3107.13,1652.01 3107.13,1472.83 3087.38,1453.09 3087.38,1425.36 3004.15,1342.13 3004.15,1138.44 2972.79,1107.08 2972.79,1064.49 2969.69,1061.39 2950.26,1061.39 2938.05,1049.18 2938.05,1016.01 2925.72,1003.69 v1(2924,1003.69)
  SIG 1 w5.3: v1(2764.66,693.87) 2764.66,772.99 2749.16,788.49 2749.16,853.7 2739.9,862.96 2739.66,862.96 2728.23,874.4 2728.23,895.53 2779.7,947 2828.2,947 2876.61,995.42 2912.3,995.42 2920.57,1003.69 v1(2924,1003.69)
  Bottom Layer w5.3: U63.11@2623.77,553.95 2670.1,553.95 2764.66,648.51 v1(2764.66,693.87)
AM263P_MMC_MUX_SEL: R389.2 R391.2 U53.9 U53.10 U63.10 | length 2075.3
  Top Layer w5.3: U53.9@2859.79,2026.07 U53.10@2879.47,2026.07 2879.47,2008.94 2903.02,1985.39 3049.22,1985.39 3069.78,1964.83 R391.2@3073.72,1964.83 ; v1(2983.42,1015.2) 2983.42,1102.72 3014.75,1134.05 3014.75,1337.74 3098.23,1421.21 3098.23,1448.45 3117.73,1467.95 3117.73,1664.7 3105.51,1676.92 3077.9,1676.92 3048.75,1706.07 3048.75,1727.83 3099.07,1778.16 3099.07,1916.02 3095.97,1919.12 R389.2@3077.57,1919.12 ; R391.2@3072.15,1962.75 3073.18,1961.72 R389.2@3073.18,1927.45
  SIG 1 w5.3: v1(2740.08,711.06) 2740.08,776.18 2708.26,807.99 2708.26,891.22 2774.64,957.6 2822.39,957.6 2872.65,1007.86 2899.12,1007.86 2914.62,1023.36 2950.03,1023.36 2958.47,1014.92 2983.14,1014.92 v1(2983.42,1015.2)
  Bottom Layer w5.3: U63.10@2623.77,573.63 2672.14,573.63 2745.61,647.1 2745.61,685.86 2740.08,691.4 v1(2740.08,711.06)
AM263P_OSPI0_CLK: R26.1 R438.2 U7.B2 | length 179.1
  Top Layer w5.3: R26.1@2624.76,1156.11 2663.8,1156.11 R438.2@2667.19,1152.72 2722.35,1152.72 2772.48,1102.59 2772.48,1095.36 U7.B2@2773.92,1093.92
AM263P_OSPI0_CLK_R: R26.2 U1.N2 | length 1356.5
  Top Layer w5.3: R26.2@2624.76,1195.48 2624.76,1217.12 2629.76,1222.12 v1(2629.76,1225.55) ; v1(3562.88,989.09) U1.N2@3578.63,1004.84
  SIG 1 w5.3: v1(2629.76,1225.55) 2629.76,1154.43 2658.83,1125.37 2704.88,1125.37 2719.13,1111.12 2719.13,1110.7 2732.96,1096.87 2732.96,1031.05 2749.33,1014.68 2772.94,1014.68 2814.57,1056.3 2856.72,1056.3 2907.01,1106.6 2978.55,1106.6 3011.81,1073.34 3083.82,1073.34 3086.24,1075.75 3193.19,1075.75 3204.95,1063.99 3248.8,1020.14 3351.3,1020.14 3374.44,1043.29 3374.44,1080.27 3396.67,1102.49 3410.57,1102.49 3426.17,1086.9 3426.17,1048.39 3465.36,1009.19 3484.88,1009.19 3504.97,989.09 v1(3562.88,989.09)
AM263P_OSPI0_CSN0: R31.2 R443.2 R444.2 U1.P1 | length 1275
  Top Layer w5.3: R31.2@3261.19,894.73 3292.38,894.73 3298.22,900.56 v1(3298.22,917.02) 3319.86,938.67 3399.68,938.67 3439.14,978.13 3462.41,978.13 3469.85,970.7 3469.85,961.02 3485.3,945.57 3501.01,945.57 3528.79,973.35 U1.P1@3547.13,973.35
  SIG 1 w5.3: v1(2635.9,912.67) 2637.08,912.67 2645.96,903.79 2703.36,903.79 2703.96,904.39 2704.03,904.39 2823,1023.36 2892.41,1023.36 v1(2913.92,1044.87) 2960.89,1044.87 2971.04,1034.72 3118.87,1034.72 3126.88,1042.74 3151.93,1042.74 3277.64,917.02 v1(3298.22,917.02)
  Bottom Layer w5.3: R444.2@2624.41,942.2 2624.41,923.97 v1@2635.71,912.67 ; v1(2913.92,1044.87) 2935.26,1044.87 2945.36,1054.97 R443.2@2945.36,1115.36
AM263P_OSPI0_CSN1: R445.2 U1.R3 | length 1735.3
  Top Layer w5.3: v1(3594.38,926.1) U1.R3@3610.13,941.85
  SIG 1 w5.3: v1(2463.67,1011.01) 2509.93,1011.01 2546.04,1047.12 2601.91,1047.12 2615.24,1033.78 2615.24,897.86 2629.26,883.84 2629.26,862.86 2714.99,777.14 2714.99,708.54 2749.61,673.92 2772.93,673.92 2819.26,720.25 3065.39,720.25 3091.15,746.01 3167.52,746.01 3233.55,812.04 3408.3,812.04 3449.05,852.79 3469.73,852.79 3470.03,852.49 3490.71,852.49 3491,852.79 3529.15,890.94 3529.15,914.51 3556.4,941.75 3578.73,941.75 v1(3594.38,926.1)
  Bottom Layer w5.3: v1(2463.67,1011.01) 2532.48,942.2 R445.2@2584.41,942.2
AM263P_OSPI0_D0: R27.1 R42.1 R374.2 R377.1 | length 1051.3
  Top Layer w5.3: R374.2@2820.1,826.33 2829.26,817.17 2829.26,811.69 2842.05,798.9 2842.05,754.95 2857,740 v1(2858.68,740) ; R374.2@2820.72,826.33 R27.1@2820.72,863.34 ; v1(3132.76,890.89) 3134.63,892.76 3134.63,928.7 3144.34,938.42 R42.1@3164.53,938.42 3173.35,929.6 R377.1@3221.22,929.6
  SIG 1 w5.3: v1(2858.68,740) 2910.31,740 2917.97,747.66 2917.97,779.88 2921.08,782.98 2946.42,782.98 2949.53,779.88 2949.53,741.97 2952.63,738.87 2996.94,738.87 3005.74,747.66 3007.61,749.54 3007.61,758.15 2989.24,776.53 2989.24,785.14 2994.98,790.88 3003.59,790.88 3022.94,771.53 3031.55,771.53 3037.29,777.27 3037.29,785.89 3017.94,805.24 3017.94,813.85 3023.69,819.59 3032.3,819.59 3050.68,801.21 3059.29,801.21 3064.65,806.58 3066.39,808.32 3066.39,878.09 3080.2,891.9 3099.73,891.9 3109.69,881.94 3109.69,832.32 3114.94,827.07 3126.16,827.07 3137.54,838.46 3175.85,838.46 3180.29,842.91 3180.29,874.2 3163.61,890.89 v1(3132.76,890.89)
AM263P_OSPI0_D1: R28.1 R43.1 R373.2 R378.1 | length 1142.7
  Top Layer w5.3: R373.2@2666.41,1052.94 2663.09,1049.63 2663.09,1032.35 2660.72,1029.97 R28.1@2660.72,1018.36 2695.52,1018.36 2698.7,1015.18 v1(2702.13,1015.18) ; v1(3303,958.84) R378.1@3326.79,958.84
  SIG 1 w5.3: v1(2702.13,1015.18) 2685.88,1031.43 2685.88,1078.9 2678.42,1086.37 2654.37,1086.37 2644.59,1076.58 2644.59,962.16 2650.98,955.77 2694.27,955.77 2706.9,943.14 2723.07,943.14 2723.84,943.91 2724.73,943.91 2818.48,1037.66 2858.43,1037.66 2887.18,1066.41 2965.15,1066.41 2983.86,1047.71 3102.53,1047.71 3109.37,1054.55 3178.94,1054.55 3272.76,960.74 3301.11,960.74 v1(3303,958.84)
  Bottom Layer w5.3: R43.1@2665.66,1010.62 2697.58,1010.62 v1(2702.13,1015.18)
AM263P_OSPI0_D2: R29.1 R372.1 R379.1 | length 1054.7
  Top Layer w5.3: R29.1@2954.22,1097.9 2954.22,1109.22 2959.2,1114.2 R372.1@2959.2,1138.44 2959.2,1138.8 2968.36,1147.96 v1(2984.63,1147.96) ; v1(3353.38,1086.92) 3356.82,1086.92 3360.12,1083.62 R379.1@3382.25,1083.62
  SIG 1 w5.3: v1(2984.63,1147.96) 2969.18,1147.96 2959.62,1138.4 2948.46,1138.4 2943.54,1143.31 2943.54,1153.35 2965.69,1175.5 2994.23,1175.5 3015.18,1175.5 3018.84,1171.84 3018.84,1143.15 3022.5,1139.49 3033.48,1139.49 3037.14,1143.15 3037.14,1175.38 3040.8,1179.04 3051.78,1179.04 3055.44,1175.38 3055.44,1143.15 3059.1,1139.49 3070.08,1139.49 3073.74,1143.15 3073.74,1171.84 3077.4,1175.5 3093.98,1175.5 3100.22,1169.26 3105.02,1164.46 3105.02,1137.36 3080.04,1112.37 3080.04,1093.72 3087.4,1086.35 3229.98,1086.35 3237.57,1078.76 3237.57,1048.29 3250.41,1035.45 3262.38,1035.45 3267.6,1040.68 3267.6,1050.76 3255.87,1062.49 3255.87,1100.82 3259.53,1104.48 3270.51,1104.48 3274.17,1100.82 3274.17,1075.89 3277.83,1072.23 3288.81,1072.23 3292.47,1075.89 3292.47,1100.82 3296.13,1104.48 3307.11,1104.48 3310.77,1100.82 3310.77,1075.88 3314.43,1072.22 3325.41,1072.22 3329.07,1075.88 3329.07,1093.71 3332.73,1097.37 3342.93,1097.37 v1(3353.38,1086.92)
AM263P_OSPI0_D3: R30.1 R371.2 R380.1 | length 223.3
  Top Layer w5.3: v1(2981.2,843.58) 2992.29,832.49 3071.9,832.49 3078.11,838.71 R380.1@3101.46,838.71
  Bottom Layer w5.3: R30.1@2975.51,935.56 2975.51,905.73 R371.2@2983.07,898.17 2981.2,896.29 v1(2981.2,843.58)
AM263P_OSPI0_D4: R361.1 R370.2 R403.1 | length 92.5
  Top Layer w5.3: R361.1@2964.2,923.76 R370.2@2999.42,923.81 3008.58,932.97 3008.58,941.52 3011.68,944.62 R403.1@3043.1,944.62
AM263P_OSPI0_D5: R167.1 R365.1 R369.2 | length 1006.3
  Top Layer w5.3: R365.1@2863.91,863.34 R369.2@2863.91,826.33 2893.51,826.33 2901.18,834.01 2937.49,834.01 v1(2948.27,823.24) ; v1(2977.41,972.03) 2978.05,971.39 2978.05,959.38 2981.16,956.27 2989.02,956.27 2994.12,961.38 2994.12,975.2 2990.71,978.62 2990.71,994.88 3001.97,1006.14 3021.4,1006.14 3029.74,997.8 3030.02,997.8 3031.15,996.66 3136.03,996.66 3152.25,1012.88 3161.4,1012.88 3164.05,1012.88 3170.14,1018.97 3170.14,1029.75 3176.23,1035.84 3184.35,1035.84 3190.44,1029.75 3190.44,1018.97 3196.53,1012.88 3210.05,1012.88 3217.03,1012.88 3221.22,1017.07 R167.1@3221.22,1034.08
  Bottom Layer w5.3: v1@2947.88,823.24 2934.61,809.97 2934.61,793.44 2941.34,786.71 2956.83,786.71 2967.34,797.22 2967.34,814.41 2976.17,823.24 3007.61,823.24 3023.7,839.32 3023.7,941.39 3045.69,963.38 3045.69,980.54 2984.76,1041.46 2959.77,1041.46 2951.34,1033.03 2951.34,981.8 2961.1,972.03 v1(2977.41,972.03)
AM263P_OSPI0_D6: R366.1 R368.2 R404.1 | length 948.5
  Top Layer w5.3: R368.2@2765.43,822.18 2765.43,839.99 2773.92,848.48 R366.1@2773.92,863.34 2775.29,864.72 2788.2,864.72 2792.02,868.53 v1(2795.45,868.53) ; v1(3010.32,986.62) 3022.06,974.88 R404.1@3043.1,974.88
  SIG 1 w5.3: v1(2795.45,868.53) 2795.45,814.05 2801.07,808.43 2836.77,808.43 2844.21,815.88 2844.21,867.31 2822.04,889.47 2822.04,897.26 2829.68,904.9 2839.92,904.9 2865.87,878.95 2874.12,878.95 2882.88,887.72 2882.88,897.58 2862.78,917.69 2862.78,926.97 2869.33,933.52 2881.46,933.52 2904.42,910.57 3003.16,910.57 3040.61,948.02 3095.41,948.02 3114.68,967.29 3156.75,967.29 3159.85,970.39 3159.85,996.03 3154.88,1001.01 3024.71,1001.01 v1(3010.32,986.62)
AM263P_OSPI0_D7: R168.1 R367.2 R376.1 | length 1240.4
  Top Layer w5.3: R376.1@2659.78,959.13 2659.87,959.13 2682,959.13 2685.11,956.03 2685.11,950.59 2675.62,941.1 2675.62,930.97 R367.2@2666.59,921.93 2666.59,917.99 2701.37,883.22 2747.02,883.22 v1(2747.75,882.48) ; v1(3133.67,1021.91) 3133.67,1023.45 3170.03,1059.81 3230.27,1059.81 3254.79,1084.33 3277.08,1084.33 R168.1@3277.81,1083.59
  SIG 1 w5.3: v1(2747.75,882.48) 2746.51,883.73 2746.51,896.95 2749.61,900.05 2766.73,900.05 2769.84,896.95 2769.84,802.48 2776.93,795.39 2855.33,795.39 2865.77,805.82 2865.77,840.96 2908.74,883.93 3003.88,883.93 3011.84,875.97 3011.84,850 3020.23,841.61 3039.2,841.61 3047.14,849.55 3047.14,875.74 3034.01,888.87 3034.01,917.84 3047.11,930.94 3102.74,930.94 3109,924.69 3195.72,924.69 3213.87,942.84 3213.87,959.21 3212.74,960.35 3212.74,961.01 3201.3,972.45 3200.64,972.45 3151.18,1021.91 v1(3133.67,1021.91)
AM263P_OSPI0_DQS: R165.1 R381.1 | length 987.5
  Top Layer w5.3: R381.1@2853.23,1227.66 2853.23,1200.02 2878.18,1175.07 2878.18,1152.16 2875.28,1149.26 2875.28,1126.35 2890.98,1110.66 2898.96,1110.66 2921.16,1088.46 v1(2921.16,1086.99)
  SIG 1 w5.3: v1(2921.16,1086.99) 2975.09,1086.99 2999.41,1062.67 3102.5,1062.67 3104.98,1065.15 3188.8,1065.15 3248.73,1005.22 3267.22,1005.22 3288.17,1005.22 3291.83,1001.56 3291.83,982.03 3295.49,978.37 3306.47,978.37 3310.13,982.03 3310.13,1005.88 3313.79,1009.54 3324.77,1009.54 3328.43,1005.88 3328.43,968.79 3332.09,965.13 3343.07,965.13 3346.73,968.79 3346.73,1001.56 3350.39,1005.22 3366.75,1005.22 3367.9,1005.22 3398.39,1035.71 3416.98,1035.71 3460.8,991.9 3481.62,991.9 3491.78,981.74 v1(3491.78,961.22)
  Bottom Layer w5.3: v1(3491.78,961.22) R165.1@3491.78,985.43
AM263P_OSPI0_LBCLK: R382.1 R402.1 | length 841.5
  Top Layer w5.3: v1(2704.37,1212.03) 2714.14,1221.8 2714.14,1235.8 R382.1@2716.8,1238.46 ; v1(3018.97,1093.78) 3018.97,1094.99 3037.16,1113.18 3080.16,1113.18 3106.51,1086.84 3130.89,1086.84 3135.79,1091.74 3135.79,1093.71 3142.99,1100.9 R402.1@3144.95,1100.9
  SIG 1 w5.3: v1(2704.37,1212.03) 2662.72,1212.03 2651.29,1223.46 2651.29,1255.09 2661.24,1265.03 2685.41,1265.03 2730.99,1219.46 2730.99,1183.5 2754.27,1160.22 2766.02,1160.22 2775.29,1169.49 2775.29,1209.57 2782.26,1216.54 2795.1,1216.54 2802.02,1209.61 2802.02,1167.02 2808.82,1160.22 2808.82,1144.84 2822.21,1131.46 2849.05,1131.46 2863.31,1117.2 2994.85,1117.2 3018.26,1093.78 v1(3018.97,1093.78)
AM263P_OSPI0_RST: R99.1 R387.1 U35.1 | length 1039.9
  Top Layer w5.3: v1(3048.97,1093.66) 3049.97,1092.65 3049.97,1085.49 3050.42,1085.04 R99.1@3050.42,1064.94
  SIG 1 w5.3: v1(2695.27,923.31) 2662.42,923.31 2631.19,954.53 2631.19,1062.08 2606.85,1086.43 2606.85,1247.2 2639.18,1279.52 2692.82,1279.52 2743.75,1228.6 2827.4,1228.6 2880.5,1175.5 2880.5,1130.9 2883.61,1127.8 3013.41,1127.8 3047.55,1093.66 v1(3048.97,1093.66)
  Bottom Layer w5.3: v1(2695.27,923.31) 2697.55,923.31 2704.25,916.61 2763.72,916.61 U35.1@2764.38,915.95
AM263P_OSPI0_RST_R: R99.2 U1.J1 | length 479
  Top Layer w4: 3491,1130.83 3515.64,1130.83 U1.J1@3547.13,1130.83
  Top Layer w5.3: R99.2@3095.05,1066.26 3129.63,1066.26 3138.27,1074.9 ; 3138.04,1075.13 3143.92,1081.01 3220.94,1081.01 3259.67,1119.74 3312.7,1119.74 3323.78,1130.83 3491,1130.83
AM263P_OSPI_ECS: R13.1 R435.1 U7.A5 | length 369.2
  Top Layer w5.3: U7.A5@2892.03,1133.29 2913.5,1154.77 2913.5,1165.3 v1(2915.93,1167.73) ; v1(3060.2,1210.91) 3078.11,1210.91 3081.53,1207.49 R13.1@3081.53,1185.36
  SIG 1 w5.3: v1(2915.93,1167.73) 2917.81,1167.73 2949.76,1199.69 3045.88,1199.69 v1@3059.57,1213.38
  Bottom Layer w5.3: R435.1@2841.65,1230.99 2841.65,1209.87 2852.72,1198.8 2892.76,1198.8 2902.13,1189.43 2902.13,1181.54 v1(2915.93,1167.73)
AM263P_OSPI_ECS_R: R13.2 U1.H1 | length 469
  Top Layer w4: 3515.64,1162.32 U1.H1@3547.13,1162.32
  Top Layer w5.3: R13.2@3128.78,1185.36 3132.71,1185.36 3151.1,1166.97 3151.1,1138.91 3157.41,1132.6 3179.7,1132.6 3188.04,1140.94 3295.83,1140.94 3308.75,1153.87 3491,1153.87 3493.88,1153.87 3502.33,1162.32 3515.64,1162.32
AM263P_PORZ: R6.2 R19.1 U1.R2 U2.4 | length 2301.6
  Top Layer w10: v1(3562.88,926.1) U1.R2@3578.63,941.85
  Top Layer w15: U2.4@2075.37,1242.05 2122.24,1242.05 2135.16,1229.13 R6.2@2139.09,1229.13 2139.09,1193.43 2157.4,1175.12 2157.4,1076.8 2146.04,1065.44 v1(2146.04,1005) ; R19.1@2262.84,791.01 2266.35,791.01 2267.16,790.2 2285.24,790.2 2286.45,788.99 v1(2287.26,788.99)
  SIG 1 w5.3: v1(2146.04,1005) 2146.04,849.67 2206.72,788.99 v1(2287.26,788.99) 2288.47,790.2 2393.71,790.2 2464.28,719.64 2486.13,719.64 2572.75,806.25 2633.14,806.25 2669.32,770.06 2669.32,713.38 2649.08,693.14 2649.08,673.74 2683.27,639.55 2754.71,639.55 2824.29,709.13 3071.44,709.13 3097.71,735.41 3171.91,735.41 3237.55,801.05 3458.24,801.05 3491,833.81 3545.62,888.43 3545.62,910.4 3561.32,926.1 v1(3562.88,926.1)
AM263P_PORZ_PB: U2.1 U34.6 | length 2242.4
  Top Layer w5.3: U34.6@678.78,2115.47 679.48,2114.78 679.48,2102.52 683,2099 697,2099 v1(698,2098) ; v1(1875.01,1320.45) 1906.2,1320.45 1909.97,1316.68 1966.94,1316.68 U2.1@1967.11,1316.85
  SIG 1 w5.3: v1@700,2096 700,2058 740.43,2017.57 745.72,2017.57 808.81,1954.48 892.52,1954.48 915,1932 978.74,1932 1074.55,2027.82 1231.57,2027.82 1243.01,2016.38 1243.01,1991.05 1239.4,1987.44 1239.4,1962.11 1252.69,1948.82 1287.83,1948.82 1325.66,1911 1325.66,1891.33 1355.44,1861.54 1426.3,1861.54 1462.32,1825.53 1462.32,1249.63 1550.05,1161.9 1648.41,1161.9 1805.97,1319.46 1874.02,1319.46 v1(1875.01,1320.45)
AM263P_PORZ_RC: C63.2 R19.2 U6.2 | length 113.5
  Top Layer w5.3: U6.2@2152.96,752.39 2178.18,752.39 2181.88,748.69 C63.2@2207.84,748.69 2232.45,748.69 2237.37,743.77 R19.2@2262.84,743.77
AM263P_PR0_MDIO0_MDC: R71.1 R73.1 U17.2 | length 476.9
  Top Layer w5.3: R71.1@4335.03,1092.85 4335.77,1093.59 v1(4371.9,1093.59)
  Bottom Layer w5.3: v1(4371.9,1093.59) 4401.36,1064.13 4401.36,1002.6 4437.25,966.71 4573.86,966.71 4584.97,977.82 R73.1@4584.97,1010.55 4614.85,1010.55 4628.36,1024.06 U17.2@4680.08,1024.06
AM263P_PR0_MDIO0_MDC_R: R71.2 U1.L18 | length 223.4
  Top Layer w5.3: U1.L18@4082.57,1067.84 4249.17,1067.84 4267.46,1086.12 ; 4267.49,1086.09 4274.26,1092.85 R71.2@4295.66,1092.85
AM263P_PR0_MDIO0_MDIO: R72.1 R74.1 U17.4 | length 255
  Top Layer w5.3: R72.1@4471.3,1086.73 4570.89,1086.73 v1(4588.41,1104.25)
  Bottom Layer w5.3: v1(4588.41,1104.25) 4588.41,1100.82 4584.97,1097.37 R74.1@4584.97,1074.9 4608.57,1074.9 4620.04,1063.43 U17.4@4680.08,1063.43
AM263P_PR0_MDIO0_MDIO_R: R72.2 U1.L17 | length 400.7
  Top Layer w5.3: U1.L17@4051.07,1067.84 4065.59,1053.31 4114.06,1053.31 4249.7,1053.31 4261.47,1065.07 4408.3,1065.07 4429.96,1086.73 R72.2@4431.93,1086.73
AM263P_PRU/BP_MUX_EN: R288.2 R290.2 U23.8 U46.2 U52.8 U63.15 | length 7262.1
  Top Layer w5.3: R290.2@4605.35,1367.93 R288.2@4605.35,1430.9 4605.35,1449.54 4612.31,1456.5 v1(4670.59,1456.5) 4690.28,1476.18 U23.8@4762.24,1476.18 ; U52.8@4638.9,650.1 4639.12,650.32 v1(4671.61,650.32) ; v1(5400.67,1484.48) 5415.73,1469.42 5455.79,1469.42 5475.91,1449.3 5475.91,1136.22 5495.85,1116.28 5549.4,1116.28 5575.39,1090.3 5575.39,1006.33 5606.79,974.93 6000.49,974.93 6080,895.42 U46.2@6080,859.29 6080,749 6067.5,736.5 6001.5,736.5 5966.5,701.5 5966.5,637.37 v1(5996.69,607.19)
  SIG 1 w4.75: v1(2606.34,416.42) 2609.66,416.42 2619.4,406.67 2697.11,406.67 2704.11,399.68 2896.3,399.68 2988.55,491.93 3342.83,491.93 3391.8,442.96 3391.8,416.66 3416.22,392.23 3458.95,392.23 3613.84,237.34 3692.78,237.34 3701.73,246.28 3719.19,246.28 3721.34,248.43 3774.66,248.43 3847.4,321.17 3903.49,321.17 3912.55,330.23 3948.14,330.23 3959.37,319 3959.37,260.2 3971.31,248.25 4008.26,248.25 4024.15,264.14 4024.15,345.49 4147.76,469.09 4198.36,469.09 4233.16,434.28 4455.26,434.28 4509.39,488.41 4686.88,488.41 4701.7,503.23 4728.41,503.23 4744.99,486.65 4744.99,477.75 v1(4764.83,457.91) ; v1(4671.61,650.32) 4782.02,650.32 4847.94,716.24 4982.38,716.24 4988.89,709.74 5252.04,709.74 5286.12,675.65 5557.96,675.65 5603.62,629.99 5770.65,629.99 5784.29,616.35 5987.28,616.35 5996.44,607.19 v1(5996.69,607.19)
  SIG 1 w5.3: v1(4670.59,1456.5) 4738.07,1456.5 4756.61,1437.96 4756.61,1311.94 4781.28,1287.28 4874.62,1287.28 4892.92,1305.57 4892.92,1425.59 4931.81,1464.48 4981.67,1464.48 4983.16,1465.97 5380.55,1465.97 v1@5400.26,1485.68
  Bottom Layer w4.75: U63.15@2558.81,508.67 2558.81,481.06 2606.34,433.52 v1(2606.34,416.42) ; v1(4671.61,650.32) 4671.61,587.16 4732.71,526.07 4769.44,526.07 4779.15,516.36 4779.15,472.23 v1(4764.83,457.91)
AM263P_PRU_MUX_SEL: R287.2 R289.2 U23.9 U23.10 U49.1 U63.8 | length 6279.9
  Top Layer w5.3: v1(4432.87,1194.81) 4459.49,1194.81 4511.32,1246.64 4511.32,1323.6 4528.38,1340.65 4620.51,1340.65 4640.24,1360.38 4640.24,1397.6 4689.41,1446.77 4704.17,1446.77 ; U23.10@4762.24,1436.81 4714.13,1436.81 4704.17,1446.77 ; U23.9@4762.24,1456.5 4713.9,1456.5 4704.17,1446.77 ; R289.2@5465.31,934.34 5466.14,935.17 R287.2@5530,935.17 5530.85,934.32 5591.07,934.32 5610.59,914.8 U49.1@5652.8,914.8 ; R289.2@5465.31,935.17 5445,935.17 5435,925.17 5435,853.97 5485.91,803.06 5541.94,803.06 5603.51,741.49 v1(5603.51,701.16)
  SIG 1 w4.75: v1(4432.87,1194.81) 4432.87,1133.78 4452.68,1113.97 4452.68,1048.98 4554.07,947.59 4835.18,947.59 5003.52,779.25 5082.63,779.25 5120.9,740.98 5239.67,740.98 5242.55,743.86 5357.75,743.86 5409.9,691.71 5553.22,691.71 5562.67,701.16 v1(5603.51,701.16)
  Bottom Layer w5.3: U63.8@2623.77,613 2691.82,613 2733.39,654.56 2733.39,683.1 2720.55,695.93 2720.55,719.15 2731.99,730.58 2759.42,730.58 2830.6,659.41 2830.6,596.76 2949.85,477.51 3104.78,477.51 3156.79,425.49 3204.29,425.49 3290.6,339.18 3473.21,339.18 3493.14,319.25 3753.58,319.25 3956.2,116.62 4244.2,116.62 4363.14,235.56 4363.14,367 4402.34,406.2 4449.17,406.2 4467.17,424.2 4467.17,465.63 4436.24,496.57 4436.24,729.76 4420.55,745.45 4359.54,745.45 4308.88,796.1 4203.59,796.1 4115.57,884.12 4115.57,902.28 4133.42,920.12 4258.29,920.12 4283.46,945.29 4283.46,986.56 4332.45,1035.55 4332.45,1072.99 4320.31,1085.13 4320.31,1098.64 4360.22,1138.55 4402.38,1138.55 4432.87,1169.04 v1(4432.87,1194.81)
AM263P_RESETN_PB: R5.1 R179.1 U33.4 | length 1899.2
  Top Layer w5.3: v1(725.32,2218.82) 725.32,2135.29 746.84,2113.77 783.99,2113.77 789.35,2108.41 789.35,2089.41 794.17,2084.59 U33.4@817.71,2084.59
  Bottom Layer w5.3: v1(725.32,2218.82) 807.15,2137 1351,2137 1375.88,2112.12 1499.65,2112.12 1558.18,2053.59 1558.18,1931.13 1595.21,1894.1 1732.2,1894.1 1758.79,1867.51 1758.79,1851.33 1732.8,1825.34 1732.8,1749.23 1725.06,1741.49 1725.06,1615.81 1709.52,1600.27 1709.52,1528.15 1749.48,1488.19 R5.1@1773.66,1488.19
AM263P_RGMII1_RD0: U1.U17 U50.41 | length 1456.4
  Top Layer w5.3: U1.U17@4051.07,878.86 4066.92,863.01 4066.92,807.86 4128.46,746.32 4335.88,746.32 4341.94,752.37 4367.52,752.37 4421.61,806.46 v1(4421.61,825.44) ; v1(5042.25,760) 5064.19,738.05 5214.98,738.05 5234.87,757.94 5234.87,780.48 5248.23,793.84 U50.41@5248.23,846.81
  Bottom Layer w5.3: v1(4421.61,825.44) 4550.1,825.44 4553.31,828.66 4678.37,828.66 4747.02,760 v1(5042.25,760)
AM263P_RGMII1_RD1: U1.T17 U50.39 | length 1458.8
  Top Layer w4: U1.T17@4051.07,910.35 4068.04,893.38 4088.58,893.38
  Top Layer w5.3: 4088.58,893.38 4100.07,881.9 4100.07,871.48 4114.06,857.49 4203.62,767.93 4310.43,767.93 4325.97,783.46 4354.08,783.46 v1(4355.04,782.5) ; v1(5042.25,806.62) 5200.48,806.62 5208.86,815 U50.39@5208.86,846.81
  Bottom Layer w5.3: v1(4355.04,782.5) 4355.04,795.46 4417.19,857.6 4674.33,857.6 4685.56,846.38 5007.17,846.38 5041.65,880.85 5071.86,880.85 5080,872.72 5080,821.62 5065,806.62 v1(5042.25,806.62)
AM263P_RGMII1_RD2: U1.U18 U50.38 | length 1573.6
  Top Layer w5.3: U1.U18@4082.57,878.86 4082.57,876.03 4086.94,871.66 4086.94,871.45 4098.22,860.18 4098.22,815.87 4098.22,791.55 4108.91,780.87 4122.22,780.87 4127.72,786.36 4127.72,800 4135.42,807.7 4145,807.7 4160,792.7 4160,780.71 4183.79,756.92 4331.49,756.92 4337.55,762.97 4363.13,762.97 4398.86,798.71 4398.86,830.3 4500.61,932.05 4851.59,932.05 4878.64,905 4878.64,805.54 4891.48,792.7 4981.47,792.7 5019.79,831.02 5019.79,843.75 5027.3,851.27 5043.73,851.27 5050,845 5050,826.48 5059.26,817.22 5070.4,817.22 5076.16,822.99 5076.16,845 5082.43,851.27 5096.48,851.27 5102.75,845 5102.75,824.02 5109.55,817.22 5128.99,817.22 5135,823.23 5135,852.56 5145,862.56 U50.38@5173.43,862.56
AM263P_RGMII1_RD3: U1.T18 U50.36 | length 1572.6
  Top Layer w5.3: U1.T18@4082.57,910.35 4084.56,908.36 4090.01,908.36 4109.5,888.87 4109.5,881.36 4114.06,876.8 4154.46,836.4 4180.44,836.4 4193.62,823.23 4193.62,792.92 4208.01,778.53 4293.29,778.53 4316.78,802.02 4377.63,802.02 4388.26,812.66 4388.26,834.69 4496.22,942.65 4860,942.65 4890,912.65 4890,809.17 4895.88,803.3 4916.09,803.3 4923.6,810.8 4923.6,881.71 4932.37,890.49 4945.79,890.49 4955,881.28 4955,825 4963.5,816.5 4980.44,816.5 4990,826.05 4990,855 4999.32,864.32 5098.42,864.32 5098.46,864.28 5103.12,864.28 5112.25,873.41 5112.25,894.17 5120,901.93 U50.36@5173.43,901.93
AM263P_RGMII1_RX_CTL: U1.R18 U50.34 | length 1576.4
  Top Layer w4: U1.R18@4082.57,941.85 4084.69,939.73 4092.07,939.73
  Top Layer w5.3: 4092.07,939.73 4125.21,906.59 4131,906.59 4164.72,906.59 4170.33,900.98 4170.33,873.94 4177.75,866.53 4211.68,866.53 4228.03,849.41 4228.03,836.28 4251.68,812.62 4363.79,812.62 4377.66,826.49 4377.66,839.09 4491.83,953.25 4890.02,953.25 4900.6,942.67 4900.6,916.3 4906.9,910 4916.73,910 4923.6,916.86 4923.6,948.6 4928.27,953.27 4943.52,953.27 4948.18,948.61 4948.18,918.55 4954.21,912.53 4965.46,912.53 4970.21,917.28 4970.21,939.73 4974.59,944.11 4983.35,944.11 5000.27,927.2 5000.27,882.83 5008.18,874.92 5024.92,874.92 5032.8,882.8 5032.8,924.97 5042.58,934.75 5059.85,934.75 5068.18,926.42 5068.18,881.61 5073.45,876.34 5093.6,876.34 5097,879.73 5097,931.84 5106.46,941.3 U50.34@5173.43,941.3
AM263P_RGMII1_RXC: U1.R17 U50.32 | length 1456.5
  Top Layer w4: U1.R17@4051.07,941.85 4065.27,927.65 4083.18,927.65
  Top Layer w5.3: 4082.85,927.33 4087.86,927.33 4114.06,901.12 4130.35,884.84 4130.35,875.5 4158.85,847 v1(4200.6,847) ; v1(5076.16,960.98) 5098.77,960.98 5118.46,980.67 U50.32@5173.43,980.67
  Bottom Layer w5.3: v1(4200.6,847) 4238.27,809.34 4297.21,809.34 4312.89,825.02 4312.89,959.86 4323.88,970.85 4354.64,970.85 4365,960.5 4365,921.1 4378.24,907.86 4772.26,907.86 4808.32,871.8 4986.98,871.8 5019.2,904.01 5050.8,904.01 5076.16,929.37 v1(5076.16,960.98)
AM263P_RGMII1_TD0: R65.1 U50.29 | length 1155.5
  Top Layer w5.3: R65.1@4338.08,834.48 4338.67,835.08 4358.67,835.08 4488.37,964.78 4521.39,964.78 4528.28,971.67 4528.28,987.74 4532.77,992.22 4546.12,992.22 4552.9,985.45 4552.9,968.99 4557.11,964.78 4568.94,964.78 4575.18,971.02 4575.18,984.91 4579.44,989.16 4600.29,989.16 4604.81,984.65 4604.81,969.97 4610,964.78 4624.12,964.78 4630,970.65 4630,998.02 4635.87,1003.89 4648.58,1003.89 4654.4,998.07 4654.4,970.1 4659.72,964.78 4948.5,964.78 4957.98,974.26 4957.98,1032.47 4964,1038.49 4975,1038.49 4980,1033.49 4980,1022.95 4985,1017.95 4993.22,1017.95 5000.27,1025 5000.27,1033.76 5005,1038.49 5057.49,1038.49 5064.19,1031.78 5064.19,1019.4 5071.52,1012.07 5090.8,1012.07 5118.46,1039.72 U50.29@5173.43,1039.72
AM263P_RGMII1_TD0_R: R65.2 U1.P16 | length 491.9
  Top Layer w5.3: v1(4257.94,839.32) 4261.38,839.32 4266.22,834.48 R65.2@4290.83,834.48
  Top Layer w10: U1.P16@4019.57,973.35 v1(4035.32,957.6)
  SIG 1 w4.75: v1(4035.32,957.6) 4059.2,933.72 4185.46,933.72 4196.74,922.44 4196.74,898.46 4205.21,890 4220.39,890 4227.97,897.58 4227.97,926.69 4235,933.72 4272.73,933.72 4284.95,921.51 4284.95,878.82
  SIG 1 w5.3: v1(4257.94,839.32) 4274.19,839.32 4284.95,850.08 4284.95,878.82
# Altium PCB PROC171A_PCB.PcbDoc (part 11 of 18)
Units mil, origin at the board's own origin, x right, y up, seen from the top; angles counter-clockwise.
Board outline 7700 x 2300 mil, 6 copper layers (Top Layer, GND 1, SIG 1, SIG 2, GND 2, Bottom Layer), stack 61.062 mil thick; 945 components, 692 nets, 11945 pads, 1734 vias.

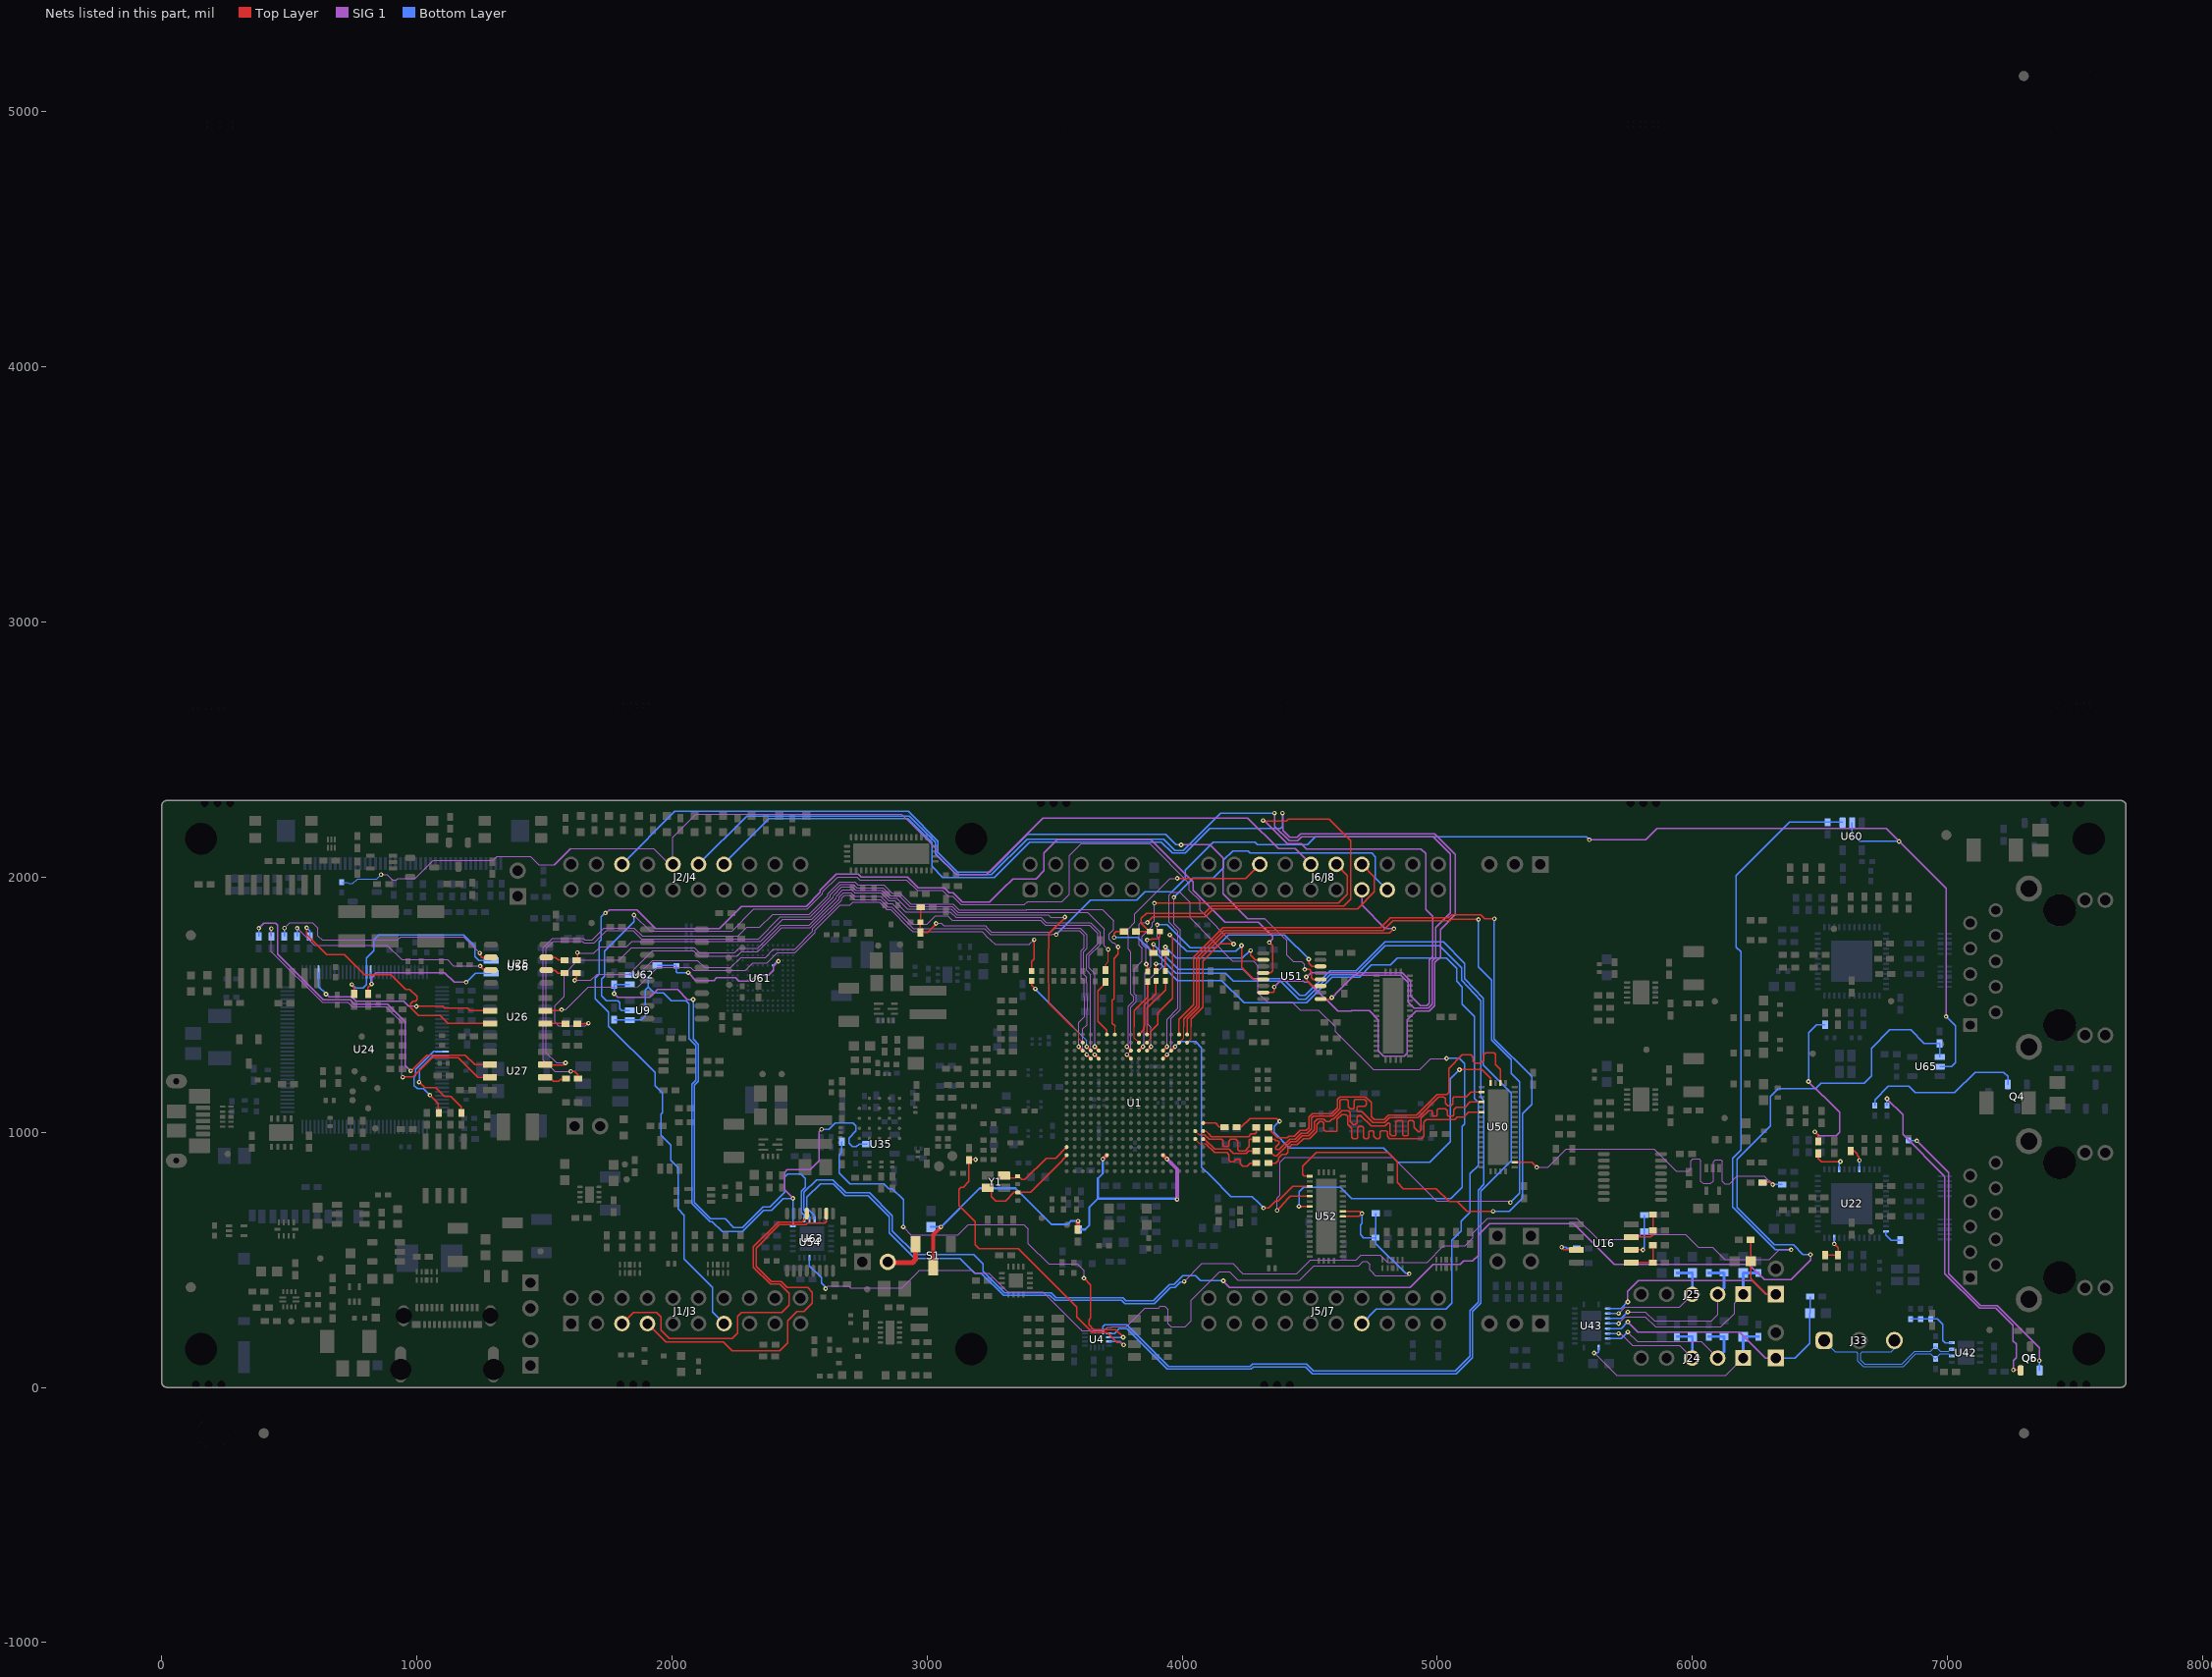
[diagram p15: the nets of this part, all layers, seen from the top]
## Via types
v1: diameter 18, hole 8, Top Layer to Bottom Layer, tented both sides, 1603 vias
v2: diameter 19.68, hole 7.87, Top Layer to Bottom Layer, tented both sides, 104 vias
v3: diameter 19.68, hole 7.87, Top Layer to Bottom Layer, 24 vias
v4: diameter 18, hole 8, Top Layer to Bottom Layer, 3 vias

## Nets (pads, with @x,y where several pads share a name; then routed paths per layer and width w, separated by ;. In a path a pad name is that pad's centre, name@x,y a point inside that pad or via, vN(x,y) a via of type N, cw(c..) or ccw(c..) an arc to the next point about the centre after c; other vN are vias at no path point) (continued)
AM263P_RGMII1_TD1: R66.1 U50.27 | length 1348.4
  Top Layer w5.3: R66.1@4338.08,878.82 4366.99,878.82 4377.59,889.43 4377.59,898.96 4391.9,913.27 4407.24,913.27 4415,921.02 4415,936.37 4430.46,951.83 4451.73,951.83 4475.28,975.38 4500,975.38 4528.28,1003.66 4528.28,1030.56 4539.56,1041.84 4550,1041.84 4555,1036.84 4555,1009.76 4562.01,1002.75 4604.57,1002.75 4607.68,1005.85 4607.68,1050.93 4626.25,1069.5 4641.65,1069.5 4648.23,1062.92 4648.23,1031.26 4665,1014.49 4665,981.36 4670.98,975.38 4684.53,975.38 4687.63,978.48 4687.63,1015.47 4694.23,1022.07 4706.18,1022.07 4711.41,1016.84 4711.41,980.71 4716.74,975.38 4726.97,975.38 4731.5,979.91 4731.5,1001.04 4736.17,1005.7 4747.53,1005.7 4752,1001.23 4752,984.9 4761.52,975.38 4771.27,975.38 4776.02,980.14 4776.02,1002.28 4780,1006.26 4799.14,1006.26 4804.17,1001.23 4804.17,984.39 4813.19,975.38 4937.77,975.38 4947.38,984.99 4947.38,1039.9 4956.57,1049.09 5068.18,1049.09 5078.65,1059.57 5102.75,1059.57 5122.28,1079.09 U50.27@5173.43,1079.09
AM263P_RGMII1_TD1_R: R66.2 U1.P17 | length 315.9
  Top Layer w4: U1.P17@4051.07,973.35 4068.04,956.37 4090.82,956.37
  Top Layer w5.3: 4090.82,956.37 4127.07,920.12 4175,920.12 4183.47,911.65 4183.47,891.36 4189.8,885.03 4202.05,885.03 4210.82,893.79 4224.18,893.79 4227.99,889.99 4227.99,876.22 4237.18,867.03 4255.35,867.03 4267.13,878.82 R66.2@4290.83,878.82
AM263P_RGMII1_TD2: R67.1 U50.25 | length 1436.4
  Top Layer w5.3: R67.1@4338.08,926.55 4347.24,917.38 4351.62,917.38 4361.99,907.01 4370.65,907.01 4426.07,962.43 4447.34,962.43 4470.95,986.04 4494.62,986.04 4517.68,1009.1 4517.68,1039.31 4530.8,1052.44 4554.39,1052.44 4564.79,1042.04 4577.87,1042.04 4588.27,1052.44 4594.19,1052.44 4625.75,1084 4651.75,1084 4658.83,1076.92 4658.83,1041.12 4669.57,1030.38 4678.37,1030.38 4685,1037.01 4685,1059.57 4691.27,1065.83 4700.12,1065.83 4741.89,1024.06 4795.35,1024.06 4807.07,1035.79 4811.46,1035.79 4815.1,1032.15 4815.1,992.82 4821.94,985.98 4833.69,985.98 4838.47,990.75 4838.47,1040.74 4844.36,1046.63 4860,1046.63 4865,1041.63 4865,990.98 4870,985.98 4881.9,985.98 4885,989.08 4885,1041.63 4890,1046.63 4903.09,1046.63 4909.46,1040.27 4909.46,1018.34 4925.39,1002.41 4930.33,1002.41 4936.63,1008.7 4936.63,1055.28 4966.35,1085 4977.8,1085 4980.91,1081.9 4980.91,1066.49 4984.37,1063.04 4995.73,1063.04 5000.27,1067.58 5000.27,1087.35 5005,1092.09 5032.11,1092.09 5039.32,1084.88 5039.32,1067.71 5043.99,1063.04 5060,1063.04 5065.76,1068.79 5065.76,1089.06 5075.31,1098.62 5108.69,1098.62 5128.54,1118.46 U50.25@5173.43,1118.46
AM263P_RGMII1_TD2_R: R67.2 U1.P18 | length 235.7
  Top Layer w5.3: U1.P18@4082.57,973.35 4087.82,973.35 4127.72,933.45 4184.23,933.45 4200.86,916.82 4250.85,916.82 4260.58,926.55 R67.2@4290.83,926.55
AM263P_RGMII1_TD3: R68.1 U50.23 | length 1294.7
  Top Layer w5.3: R68.1@4338.08,972.1 4361.77,972.1 4366.87,967.01 4374.36,967.01 4378.87,962.5 4378.87,954.49 4365.66,941.27 4365.66,936.88 4370.62,931.92 4380.57,931.92 4421.68,973.03 4442.95,973.03 4466.56,996.64 4490.22,996.64 4507.08,1013.49 4507.08,1054.85 4515.27,1063.04 4589.8,1063.04 4618.54,1091.78 4618.54,1122.48 4624.4,1128.34 4645,1128.34 4651.03,1122.31 4651.03,1099.71 4658.2,1092.53 4669.43,1092.53 4673.46,1096.56 4673.46,1123.4 4678.4,1128.34 4714.51,1128.34 4722.01,1120.84 4722.01,1108.44 4716.07,1102.5 4689.76,1102.5 4686.48,1099.22 4686.48,1083.1 4689.58,1080 4704.92,1080 4747.37,1037.55 4793.84,1037.55 4813.53,1057.23 4923.6,1057.23 5004.51,1138.15 5025,1138.15 5031.47,1131.67 5031.47,1113.66 5040.88,1104.25 5053.23,1104.25 5060,1111.03 5060,1133.15 5065,1138.15 5112.09,1138.15 5131.77,1157.83 U50.23@5173.43,1157.83
AM263P_RGMII1_TD3_R: R68.2 U1.N17 | length 369
  Top Layer w4: U1.N17@4051.07,1004.84 4065.59,990.32
  Top Layer w5.3: 4065.59,990.32 4088.13,990.32 4105.96,972.49 4155,972.49 4161.05,966.45 4161.05,947.15 4164.15,944.05 4179.9,944.05 4183,947.15 4183,965.49 4190,972.49 4211.14,972.49 4218.5,965.14 4218.5,932.7 4223.78,927.42 4246.46,927.42 4263,943.96 4263,967.93 4267.17,972.1 R68.2@4290.83,972.1
AM263P_RGMII1_TX_CTL: R69.1 U50.21 | length 1462.6
  Top Layer w5.3: R69.1@4213.54,1020.57 4231.96,1020.57 4265.86,1054.47 4370.41,1054.47 v1(4381.84,1043.04) ; v1(5087.15,1245.35) 5174.44,1245.35 5208.86,1210.94 U50.21@5208.86,1193.26
  Bottom Layer w5.3: v1(4381.84,1043.04) 4360.69,1021.89 4360.69,998.96 4421.02,938.63 4789.3,938.63 4845.53,882.4 4969.93,882.4 5050.6,963.07 5050.6,1208.8 v1(5087.15,1245.35)
AM263P_RGMII1_TX_CTL_R: R69.2 U1.M18 | length 90.3
  Top Layer w5.3: U1.M18@4082.57,1036.34 4130.89,1036.34 4131,1036.23 4145.71,1021.52 4165.35,1021.52 R69.2@4166.3,1020.57
AM263P_RGMII1_TXC: R70.1 U50.19 | length 1424.4
  Top Layer w5.3: R70.1@4338.08,1019.06 4340.76,1019.06 4349.92,1009.9 4349.92,1002.7 4373.75,978.87 4412.53,978.87 4417.29,983.63 4438.56,983.63 4462.17,1007.24 4485.83,1007.24 4496.48,1017.88 4496.48,1059.94 4510.17,1073.64 4585.41,1073.64 4607.94,1096.17 4607.94,1127.68 4619.2,1138.94 4718.92,1138.94 4740.76,1117.1 4740.76,1061.29 4752.55,1049.5 4790.8,1049.5 4809.14,1067.83 4919.21,1067.83 5000.12,1148.75 5038.44,1148.75 5045.12,1155.43 5045.12,1249.61 5098.38,1302.86 5132.07,1302.86 5140.23,1294.7 5140.23,1278.92 5148.05,1271.09 5171.09,1271.09 5180,1280 5180,1301.31 5190,1311.31 5221.82,1311.31 5228.38,1304.75 5228.38,1266.01 5248.23,1246.17 U50.19@5248.23,1193.26
AM263P_RGMII1_TXC_R: R70.2 U1.N18 | length 243.2
  Top Layer w4: U1.N18@4082.57,1004.84 4093.26,1004.84 4104.3,993.8
  Top Layer w5.3: 4104.3,993.8 4115,983.09 4260.05,983.09 4270.92,993.96 4284.6,993.96 4290.65,1000.01 4290.65,1018.88 R70.2@4290.83,1019.06
AM263P_SAFETY_ERRORN: R258.1 R268.1 R272.1 U1.D4 | length 1315.4
  Top Layer w5.3: R258.1@2974.68,1881.79 R272.1@2974.68,1823.35 2973.53,1822.19 R268.1@2973.53,1783.15 3002.13,1783.15 3034.82,1815.84 v1(3034.82,1818.68)
  Top Layer w10: v1(3625.87,1304.06) U1.D4@3641.62,1288.31
  SIG 1 w4: 3610.87,1374.13 3610.87,1325.63 3625.87,1310.63 v1(3625.87,1304.06)
  SIG 1 w4.75: v1(3034.82,1818.68) 3056.69,1818.68 3065.78,1809.59 3229.03,1809.59 3237.62,1800.99 3252.96,1785.65 3486.96,1785.65 3502.41,1801.11 3600.33,1801.11 3625.38,1776.05 3626.77,1774.66 3626.77,1720.91 3614.18,1708.31 3614.18,1619.32 3625.8,1607.7 3625.8,1586.15 3626.61,1480 3626.61,1420.74 3610.87,1405 3610.87,1374.13
AM263P_SD_ENABLE_GPIO122: U1.B16 U9.2 | length 3912.2
  Top Layer w4: U1.B16@4019.57,1351.3 4035.32,1367.05 4035.32,1414.29
  Top Layer w5.3: 4035.32,1414.29 4035.32,1444.77 4081.16,1490.6 4081.16,1671.41 4147.6,1737.85 v1(4201.68,1737.85)
  SIG 1 w4.75: v1(1851.22,1851.18) 1851.75,1851.18 1914.11,1788.82 2235.29,1788.82 2321.46,1874.99 2530.22,1874.99 2591.07,1935.83 2591.39,1943.63 2648.86,2001.1 2724.75,2001.1 2736.21,1989.63 2919.01,1989.63 2960.79,1947.85 3060.16,1947.85 3081.98,1926.03 3099.6,1926.03 3133.59,1892.04 3381.99,1892.04 3394.93,1904.99 3529.31,1904.99 3558.06,1933.74 3558.06,2085 3603.65,2130.59 3872.88,2130.59 4028.48,1974.99 4028.48,1948.47 4069.27,1907.67 4069.27,1871.79 4201.68,1739.38 v1(4201.68,1737.85)
  Bottom Layer w5.3: U9.2@1834.48,1477.4 1803.62,1477.4 1796.09,1484.93 1796.09,1507.54 1788.2,1515.42 1742.97,1515.42 1723.39,1535 1723.39,1599.15 1735.66,1611.42 1735.66,1709.66 1851.22,1825.22 v1(1851.22,1851.18)
AM263P_SDFM0_CLK1: J6/J8.74 U1.A16 | length 1351.8
  Top Layer w5.3: U1.A16@4019.57,1382.8 4019.57,1444.01 4066.16,1490.59 4066.16,1676.88 4170.05,1780.77 4812.99,1780.77 v1(4830.12,1797.9)
  SIG 1 w5.3: J6/J8.74@4704.17,1950 4704.17,1889.68 4795.95,1797.9 v1(4830.12,1797.9)
AM263P_SDFM0_CLK2: U1.B15 U52.26 | length 4049.7
  Top Layer w4: U1.B15@3988.08,1351.3 4005.7,1368.92 4005.7,1414.29
  Top Layer w5.3: 4005.7,1414.29 4005.7,1445.12 4055.56,1494.98 4055.56,1681.89 4165.04,1791.37 4787.96,1791.37 4826.49,1829.89 5048.83,1829.89 5053.7,1834.76 5160.31,1834.76 v1(5161.5,1833.57) ; v1(4372.09,693.86) 4372.19,693.86 4390.85,712.52 4390.85,715.74 4423.85,748.74 U52.26@4500.04,748.74
  SIG 1 w4.75: v1(4372.09,693.86) 4372.09,741.95 4384.05,753.91 4384.05,883.09 4402.89,901.93 4825.9,901.93 4997.44,730.39 5277.27,730.39 5283.04,724.61 v1(5286.63,724.61)
  Bottom Layer w5.3: v1(5161.5,1833.57) 5161.5,1647.98 5212.37,1597.11 5212.37,1361.64 5290.12,1283.89 5290.12,1230.61 5322.88,1197.86 5322.88,760.86 v1(5286.63,724.61)
AM263P_SDFM0_CLK3: U1.A15 U52.22 | length 3867.9
  Top Layer w5.3: U1.A15@3988.08,1382.8 3988.08,1442.49 4044.9,1499.32 4044.9,1686.22 4160.65,1801.97 4778.16,1801.97 4816.68,1840.49 5044.44,1840.49 5057.04,1853.09 5169.74,1853.09 5185.98,1836.86 v1(5224.12,1836.86) ; U52.22@4500.04,827.48 4477.74,827.48 4471.48,833.74 4471.48,867.38 4525.54,921.45 4806.49,921.45 4842.94,885 4842.94,803.2 4867.11,779.03 4995.61,779.03 5047.18,727.45 5079.19,727.45 5116.15,690.49 v1(5218.7,690.49)
  Bottom Layer w5.3: v1(5218.7,690.49) 5282.06,690.49 5333.48,741.9 5333.48,1072.35 5370.37,1109.25 5370.37,1218.63 5222.97,1366.03 5222.97,1835.71 v1(5224.12,1836.86)
AM263P_SDFM0_D2: U1.C13 U52.28 | length 3504.3
  Top Layer w5.3: v1(4457.78,709.37) U52.28@4500.04,709.37
  Top Layer w10: U1.C13@3925.09,1319.8 v1(3940.83,1335.55)
  SIG 1 w4: v1(3940.83,1335.55) 3940.83,1430
  SIG 1 w4.75: 3940.83,1430 3940.83,1443.11 3983.32,1485.6 3983.32,1787.55 3948.21,1822.66 3948.21,1929.58 3958.91,1940.27 3990.89,1940.27 4030.72,1900.44 4030.72,1840.88 4197.69,1670.5 4278.87,1670.5 4297.56,1651.81 4297.56,1547.01 4335.15,1509.43 4432.26,1509.43 4463.19,1478.5 4534.28,1478.5 4600.1,1412.68 4600.1,1394.64 4674.03,1320.71 4674.95,1320.71 4748.86,1246.8 4931.78,1246.8 4974.03,1289.06 v1@5036.55,1289.06
  Bottom Layer w5.3: v1(4457.78,709.37) 4457.78,766.95 4475.83,785 4619.38,785 4663.91,740.48 5053.89,740.48 5097.03,783.61 5097.03,1022.37 5106.67,1032.01 5106.67,1268.33 5085.59,1289.41 v1(5036.55,1289.41)
AM263P_SDFM0_D3: U1.C14 U52.24 | length 1139.6
  Top Layer w5.3: v1(4318.59,702.78) 4338.41,702.78 4366.8,731.17 4376.3,731.17 4433.24,788.11 U52.24@4500.04,788.11
  Top Layer w10: U1.C14@3956.58,1319.8 v1(3972.33,1335.55)
  Bottom Layer w5.3: v1(3972.33,1335.55) 3992.66,1355.88 4052.2,1355.88 4076.55,1331.53 4076.55,863.18 4114.06,825.67 4191.35,748.38 4274.64,748.38 4298.91,724.1 4318.59,704.43 v1(4318.59,702.78)
AM263P_SFDM0_D1: J6/J8.73 U1.D13 | length 1712.4
  Top Layer w10: U1.D13@3925.09,1288.31 v1(3940.83,1304.06)
  SIG 1 w4: v1(3940.83,1304.06) 3957.33,1320.55 3957.33,1414.29 3957.33,1430
  SIG 1 w4.75: 3957.33,1430 3957.33,1445.39 3993.37,1481.43 3993.37,1791.71 3967.46,1817.62 v1(3967.46,1921.03)
  Bottom Layer w5.3: v1(3967.46,1921.03) 3967.9,1921.03 4042.66,1995.78 4121.38,1995.78 4163.14,2037.54 4163.14,2067 4198.17,2102.03 4257.69,2102.03 4265.57,2094.14 4743.17,2094.14 4757.29,2080.03 4757.29,1996.89 J6/J8.73@4804.17,1950
AM263P_SOP0: R42.2 U4.15 | length 1236.4
  Top Layer w5.3: v1(3190.18,893.14) 3166.49,893.13 R42.2@3164.53,891.17 3164.53,807.88 3141.71,785.06 3133.07,785.06 3124.89,776.89 3124.89,713.54 3188.7,649.73 3188.7,558.44 3204.01,543.14 3358.81,543.14 3587.63,314.31 3587.63,275.94 3647.06,216.52 3648.61,214.96 3706.68,214.96 3745.09,176.56 3756.8,176.56 3766.99,166.37 v1(3770.43,166.37)
  Bottom Layer w5.3: U4.15@3713.32,179.91 3756.89,179.91 v1(3770.43,166.37)
AM263P_SOP1: R43.2 U4.14 | length 1814.1
  Top Layer w5.3: v1(3615.16,427.62) 3641.62,401.16 3641.62,271.57 3634.13,264.08 3634.13,244.44 3653.01,225.56 3739.76,225.56 v1(3768.99,196.34)
  SIG 1 w4.75: v1(2906.79,628.56) 2906.79,628.12 2936.89,598.02 3120.8,598.02 3161.3,638.52 3379.5,638.52 3396.97,621.04 3396.97,563.8 3476.84,483.94 3587.94,483.94 3615.16,456.72 v1(3615.16,427.62)
  Bottom Layer w5.3: R43.2@2665.66,963.38 2665.66,922.26 2655.43,912.02 2655.43,839.5 2697.29,797.64 2830.62,797.64 2849.09,779.17 2864.18,779.17 2906.79,736.56 v1(2906.79,628.56) ; U4.14@3713.32,195.65 3768.3,195.65 v1(3768.99,196.34)
AM263P_SOP2: R173.2 U4.13 | length 4681
  Top Layer w5.3: R173.2@3886.97,1702.62 3887.31,1702.96 v1(3887.31,1736.9)
  Bottom Layer w5.3: U4.13@3713.32,211.4 3734.89,211.4 3752.91,229.43 3783.43,229.43 3941.54,71.33 4270.97,71.33 4279.66,80.02 4484.01,80.02 4510.78,53.25 5075.07,53.25 5138.73,116.91 5138.73,297.57 5170.68,329.52 5170.68,768.89 5289.73,887.94 5289.73,1153.66 5180.57,1262.82 5180.57,1525.76 5107.63,1601.94 5107.63,1661.93 5023.54,1746.02 4794.94,1746.02 4681.98,1633.06 4579.39,1633.06 4482.62,1536.29 4460.47,1536.29 4394.44,1602.32 4276.39,1602.32 4240.1,1638.6 3985.61,1638.6 v1(3887.31,1736.9)
AM263P_SOP3: R174.2 U4.12 | length 4789.7
  Top Layer w5.3: v1(3733.14,1763.52) 3733.14,1779.8 3740,1786.65 R174.2@3771.82,1786.65
  Bottom Layer w5.3: U4.12@3689.69,219.28 3689.69,238.19 3696.47,244.97 3782.88,244.97 3945.93,81.93 4266.58,81.93 4275.27,90.62 4488.4,90.62 4515.17,63.85 5069.9,63.85 5128.13,122.08 5128.13,301.96 5160.08,333.91 5160.08,773.28 5183.1,796.3 5183.1,1125.57 5169.97,1138.7 5169.97,1514.46 5095.04,1596.94 5095.04,1645.05 5008.85,1731.24 4795.15,1731.24 4682.05,1618.14 4580.7,1618.14 4483.36,1520.8 4456.85,1520.8 4385.93,1591.72 4201.63,1591.72 4169.31,1624.04 3976.31,1624.04 3892.86,1707.49 3880.67,1707.49 3824.64,1763.52 v1(3733.14,1763.52)
AM263P_SPI0_CLK: R169.1 R173.1 U51.2 | length 534.4
  Top Layer w5.3: v1(3934.01,1726.26) 3934.01,1702.82 R173.1@3934.21,1702.62 3934.21,1632.95 R169.1@3935,1632.17 ; v1(4268.27,1712.07) 4268.64,1711.7 4268.64,1694.82 4287.83,1675.64 U51.2@4318.06,1675.64
  Bottom Layer w5.3: v1(3934.01,1726.26) 3978.4,1681.88 4235.06,1681.88 4265.26,1712.07 v1(4268.27,1712.07)
AM263P_SPI0_CLK_PR0_PRU0_GPIO16: J1/J3.7 U51.4 | length 5135
  Top Layer w5.3: U51.4@4318.06,1624.46 4347.13,1624.46 4355.3,1632.62 4355.3,1730.12 4341.51,1743.9 v1(4341.37,1743.9)
  SIG 1 w5.3: v1(1739.26,1859.42) 1741.49,1859.42 1754.23,1872.17 1863.41,1872.17 1936.44,1799.14 2185.72,1799.14 2271.89,1885.32 2525.95,1885.32 2580.89,1940.26 2581.22,1948.05 2644.59,2011.42 2731.11,2011.42 2742.58,1999.96 2923.63,1999.96 2965.41,1958.18 3066.46,1958.18 3085.73,1938.9 3101.33,1938.9 3137.87,1902.36 3244.87,1902.36 3297.32,1954.81 3336,1993.5 3427.25,1993.5 3458.5,2024.75 3458.5,2094.5 3510.42,2146.42 3877.3,2146.42 4043.24,1980.48 4043.24,1948.31 4167.38,1824.16 4299.5,1824.16 4355.3,1768.36 4355.3,1757.66 4341.55,1743.9 v1(4341.37,1743.9)
  Bottom Layer w5.3: v1(1739.26,1859.42) 1737.65,1859.42 1722.2,1843.97 1722.2,1753.62 1714.46,1745.88 1714.46,1620.2 1698.92,1604.66 1698.92,1523.76 1751.8,1470.88 1751.8,1416.04 1933.36,1234.48 1933.36,1183.2 1962.38,1154.17 1962.38,1075.83 1957.28,1070.72 1957.28,987.66 1995.62,949.32 1995.62,890.05 2024.07,861.6 2024.07,698.93 2047.6,675.4 2047.6,502.36 2158.95,391.01 2158.95,295.22 J1/J3.7@2204.17,250
AM263P_SPI0_CLK_R: R169.2 U1.A11 | length 240.2
  Top Layer w5.3: U1.A11@3862.09,1382.8 3862.09,1485.78 3935,1558.69 R169.2@3935,1592.8
AM263P_SPI0_CS0: U1.C11 U51.14 | length 1295.5
  Top Layer w5.3: v1(4496.18,1678.05) 4496.18,1661.84 4507.97,1650.05 U51.14@4542.46,1650.05
  Top Layer w10: U1.C11@3862.09,1319.8 v1(3877.84,1335.55) ; v1@4496.18,1677.5 v1(4496.18,1678.05)
  SIG 1 w4: 3874.64,1414.29 3877.84,1411.09 v1(3877.84,1335.55)
  SIG 1 w4.75: 3874.64,1414.29 3866.86,1422.07 3866.86,1593.68 3922.14,1648.97 3922.14,1692.38 3910.09,1704.44 3910.09,1756.96 3902.23,1764.82 v1(3902.23,1813.37)
  Bottom Layer w5.3: v1(3902.23,1813.37) 3940.23,1813.37 4030.74,1722.86 4132.02,1723.89 4181.91,1773.78 4400.45,1773.78 4400.87,1773.35 v1(4496.18,1678.05)
AM263P_SPI0_CS0_PR0_PRU0_GPIO8: J2/J4.18 U51.12 | length 3386.6
  Top Layer w5.3: v1(4480.51,1638.13) 4498.23,1638.13 4507.35,1629.01 4507.35,1605.17 4513.65,1598.87 U51.12@4542.46,1598.87
  SIG 1 w4.75: 4324.49,1836.83 4391.49,1769.83 4409.76,1751.56 4409.76,1694.95 4435.66,1669.05 4468.53,1669.05 4479.15,1658.44 4480.54,1657.04 4480.54,1653.11 v1(4480.51,1638.13)
  SIG 1 w5.3: v1(3995.76,2126.62) 4109.15,2126.62 4160,2075.77 4160,1934.19 4257.36,1836.83 4324.49,1836.83
  Bottom Layer w5.3: J2/J4.18@1804.17,2050 2011.52,2257.35 2926.59,2257.35 3043.03,2140.91 3043.03,2096.09 3119.27,2019.85 3245.77,2019.85 3393.3,2167.38 3935.65,2167.38 3976.41,2126.62 v1(3995.76,2126.62)
AM263P_SPI0_D0: R170.1 R174.1 U51.11 | length 3535.7
  Top Layer w5.3: R174.1@3819.23,1786.49 R170.1@3873.46,1786.49 ; R170.1@3873.62,1786.65 3871.65,1786.65 3864.46,1793.84 3864.46,1793.93 3839.85,1818.53 3839.85,1838.11 3859.89,1858.15 4087.87,1858.15 4116.5,1886.77 4633.16,1886.77 4659.76,1913.38 4659.76,2143.38 4579.04,2224.1 4575.22,2227.92 4416.35,2227.92 4408.47,2220.05 4319.52,2220.05 v1(4317.51,2222.05) ; v1(4486.7,1608.71) 4489.13,1606.28 4489.13,1594.95 4510.81,1573.27 U51.11@4542.46,1573.27
  SIG 1 w5.3: v1(4317.51,2222.05) 4320.95,2222.05 4325.55,2217.45 4326.28,2217.45 4411.79,2131.94 4466.73,2131.94 4488.06,2110.6 4936.41,2110.6 4954.28,2092.73 4954.28,1874.01 4982.09,1846.2 4982.09,1688.76 4969.22,1675.89 4969.22,1505.81 4959.68,1496.28 4933.91,1496.28 4896.12,1534.07 4896.12,1591.89 4861.98,1626.02 4504.01,1626.02 v1(4486.7,1608.71)
AM263P_SPI0_D0_PR0_PRU0_GPIO13: J2/J4.15 U51.9 | length 4591.1
  Top Layer w5.3: U51.9@4542.46,1522.09 4581.02,1522.09 v1(4586.69,1527.77)
  SIG 1 w5.3: v1@4362.57,2250.65 4362.57,2199.39 4419.42,2142.54 4453.32,2142.54 4468.11,2157.32 4984.11,2157.32 5050.6,2090.83 5050.6,1859.14 4993.42,1801.97 4993.42,1685.1 4979.82,1671.5 4979.82,1501.42 4964.07,1485.68 4908.91,1485.68 4885.37,1509.22 4885.37,1586.62 4856.57,1615.42 4674.3,1615.42 4614.58,1555.71 ; v1(4586.69,1527.77) 4614.58,1555.66
  Bottom Layer w5.3: J2/J4.15@2104.17,2050 2293.17,2239 2929.95,2239 3032.43,2136.52 3032.43,2091.7 3114.87,2009.25 3252.67,2009.25 3392.5,2149.09 3927,2149.09 3971.34,2104.74 4004.05,2104.74 4150.03,2250.73 v1@4361.94,2250.73
  other v1: 4362.22,2251
AM263P_SPI0_D0_R: R170.2 U1.C10 | length 536.9
  Top Layer w5.3: v1(3862.3,1753.47) 3864.64,1755.81 3879.25,1755.81 3881.9,1758.46 3906.01,1758.46 3912.99,1765.44 R170.2@3912.99,1786.65
  Top Layer w10: U1.C10@3830.6,1319.8 v1(3846.35,1335.55)
  SIG 1 w4: v1(3846.35,1335.55) 3846.35,1339.14 3850.91,1343.7 3850.91,1414.29
  SIG 1 w4.75: 3850.91,1414.29 3853.54,1416.93 3853.54,1625.93 3878.31,1650.69 3878.31,1660.12 3878.31,1670.17 3878.25,1670.22 3878.25,1716.4 3862.28,1732.37 v1@3862.28,1753.44
AM263P_SPI0_D1: U1.B11 U51.5 | length 975.2
  Top Layer w4: U1.B11@3862.09,1351.3 3877.84,1367.05 3877.84,1396.17
  Top Layer w5.3: 3877.84,1396.17 3905,1423.33 3905,1466.97 3962.95,1524.93 3962.95,1761.45 3951.3,1773.11 v1(3951.3,1773.76) ; v1(4232.78,1731.81) 4232.78,1647.19 4281.1,1598.87 U51.5@4318.06,1598.87
  Bottom Layer w5.3: v1(3951.3,1773.76) 4017.42,1710.01 4210.98,1710.01 v1(4232.78,1731.81)
AM263P_SPI0_D1_PR0_PRU0_GPIO14: J2/J4.14 U51.7 | length 5059.3
  Top Layer w5.3: U51.7@4318.06,1547.68 4356.2,1547.68 4360.89,1552.38 v1(4360.89,1569.39)
  SIG 1 w5.3: v1(4360.89,1569.39) 4383.94,1592.44 4475.36,1592.44 4478.61,1589.19 4495.71,1589.19 4609.89,1475 4662.99,1475 4664.01,1476.02 4733.81,1476.02 4769.18,1440.65 4769.18,1318.18 4789.48,1297.88 4869.56,1297.88 4881.97,1310.28 4881.97,1441.07 4915.97,1475.08 4968.46,1475.08 4990.42,1497.03 4990.42,1665.53 5012.13,1687.24 5012.13,1795.11 5070.26,1853.25 5070.26,2089.34 4990.22,2169.38 4464.97,2169.38 4451.21,2155.62 4422.55,2155.62 4395,2183.17 4395,2249.11 v1(4393.11,2251)
  Bottom Layer w5.3: J2/J4.14@2204.17,2050 2204.17,2052.99 2379.58,2228.4 2925.56,2228.4 3018.84,2135.12 3018.84,2041.79 3061.98,1998.65 3264.31,1998.65 3402.18,2136.52 3918.84,2136.52 3961.22,2094.14 4012.62,2094.14 4108.45,2189.97 4385.26,2189.97 4393.1,2197.82 v1(4393.11,2251)
AM263P_SPI1_CLK: J5/J7.47 R171.1 | length 3138
  Top Layer w5.3: R171.1@3897,1632.17 3897.56,1632.72 v1(3897.56,1660.25)
  Bottom Layer w5.3: v1@3897.6,1660.44 3915.69,1660.44 3981.27,1594.86 4155,1594.86 4242.93,1506.92 4486.83,1506.92 4587.44,1607.54 4694.9,1607.54 4740.75,1656.28 4816.64,1655.37 4843.15,1681.88 5036.87,1681.88 5076.16,1642.59 5076.16,1592.12 5098.21,1570.08 5098.21,1501.43 5146.42,1453.22 5146.42,1132.27 5161.9,1116.79 5161.9,869.76 5129.22,837.08 5129.22,686.63 5093.44,650.85 5093.44,612.15 5056.84,575.55 5056.84,329.87 5034.08,307.11 4761.29,307.11 J5/J7.47@4704.17,250
AM263P_SPI1_CLK_R: R171.2 U1.A10 | length 237.5
  Top Layer w5.3: U1.A10@3830.6,1382.8 3851.32,1403.52 3851.32,1497.38 3897,1543.06 R171.2@3897,1592.8
AM263P_SPI1_CS0: J6/J8.58 U1.C9 | length 1143
  Top Layer w5.3: v1(3981.07,1995.18) 4249.35,1995.18 J6/J8.58@4304.17,2050
  Top Layer w10: v1(3783.35,1335.55) U1.C9@3799.1,1319.8
  SIG 1 w4: v1(3783.35,1335.55) 3783.35,1339.14 3788.3,1344.09 3788.3,1414.29
  SIG 1 w4.75: 3788.3,1414.29 3788.3,1494.61 3809.25,1515.55 3809.25,1531.5 3800.17,1540.58 3798.78,1541.97 3798.78,1707.14 3797.39,1708.53 3788.52,1717.4 3788.52,1796.52 3814.95,1822.95 3814.95,1856.66 3952.91,1994.62 3980.52,1994.62 v1(3981.07,1995.18)
AM263P_SPI1_D0: J6/J8.55 R172.1 | length 1203.6
  Top Layer w5.3: v1(3859.06,1658.67) 3859.06,1655.23 3864.43,1649.86 R172.1@3864.43,1629.67 ; v1@3891.27,1897.37 4613.05,1897.37 4647.7,1932.02 4647.7,2006.69 J6/J8.55@4604.39,2050
  SIG 1 w4.75: v1(3859.06,1658.67) 3859.06,1721.38 3842.83,1737.61 3842.83,1767.17 3882.98,1807.32 3882.98,1821.36 3890.9,1829.28 v1(3890.9,1897.74)
AM263P_SPI1_D0_R: R172.2 U1.B10 | length 273.9
  Top Layer w4: 3812.98,1414.29 3812.98,1368.92 U1.B10@3830.6,1351.3
  Top Layer w5.3: 3812.98,1414.29 3812.27,1414.99 3812.27,1476.12 3864.6,1528.44 3864.6,1585.2 R172.2@3857,1592.8
AM263P_SPI1_D1: J6/J8.54 U1.D9 | length 1674.2
  Top Layer w5.3: v1(3863.73,1822.27) 3863.73,1824.15 3884.3,1844.72 4090.28,1844.72 4121.73,1876.17 4688.38,1876.17 4754,1941.79 4754,2000.17 J6/J8.54@4704.17,2050
  Top Layer w10: v1(3783.35,1304.06) U1.D9@3799.1,1288.31
  SIG 1 w4: v1(3783.35,1304.06) 3798.35,1319.06 3798.35,1414.29
  SIG 1 w4.75: 3798.35,1414.29 3798.35,1490.45 3819.3,1511.39 3819.3,1535.66 3812.3,1542.66 3812.3,1639.47 3843.27,1670.44 3843.27,1720.98 3830.63,1733.62 3830.63,1814.72 3835.51,1819.6 3836.91,1821 v1(3863.73,1822.27)
AM263P_TCK: R324.1 U1.B3 | length 2678
  Top Layer w4: 3568.95,1414.29 3594.38,1388.86 3594.38,1367.05 U1.B3@3610.13,1351.3
  Top Layer w5.3: R324.1@1625.94,1674.24 1629.47,1677.78 v1(1629.47,1703.97) ; v1(3540.26,1843.16) 3540.26,1840.9 3478.19,1778.83 3476.63,1777.28 3475.34,1660.46 ccw(c3494.86,1660.24) 3475.34,1660.07 3476.63,1508.82 3476.63,1506.61 3568.95,1414.29
  SIG 1 w4.75: v1(1629.47,1703.97) 1632,1701.44 1693.97,1701.44 1719.97,1727.45 1822.62,1727.45 1843.79,1748.62 2348.58,1748.62 2434.76,1834.79 2546.88,1834.79 2633.23,1921.15 2633.56,1928.94 2665.51,1960.9 2708.1,1960.9 2720.18,1948.81 2822.74,1948.81 2854.15,1917.4 2880.03,1917.4 2923.05,1874.38 3094.4,1874.38 3116.94,1851.84 3474.78,1851.84 3484.59,1842.03 3539.13,1842.03 v1(3540.26,1843.16)
AM263P_TCK_R: R324.2 U25.7 | length 75.9
  Top Layer w5.3: U25.7@1507.47,1685.47 1543.98,1685.47 1555.2,1674.24 R324.2@1578.69,1674.24
AM263P_TCK_XDS: R133.1 U25.2 | length 940.7
  Top Layer w5.3: v4(1246.75,1702.37) 1249.18,1699.94 1249.18,1691.93 1255.64,1685.47 U25.2@1290.47,1685.47
  SIG 1 w4.75: v1(481.2,1800.12) 481.2,1800.47 501.74,1821.01 591.39,1821.01 611.61,1800.78 611.61,1770.01 628.42,1753.2 923.44,1753.2 936.59,1766.35 1182.77,1766.35 v4(1246.75,1702.37)
  Bottom Layer w5.3: R133.1@480.5,1767.63 480.5,1799.41 v1(481.2,1800.12)
AM263P_TDI: R326.1 U1.C5 | length 3214.3
  Top Layer w5.3: R326.1@1629.51,1424.77 1656.09,1424.77 1658.78,1427.46 v1(1672.63,1427.46)
  Top Layer w10: v1(3657.37,1335.55) U1.C5@3673.12,1319.8
  SIG 1 w4: v1(3657.37,1335.55) 3657.37,1414.29
  SIG 1 w4.75: v1(1672.63,1427.46) 1670.49,1427.46 1660.16,1417.13 1555.65,1417.13 1540.75,1432.03 1540.75,1495.39 1577.73,1532.37 1577.73,1620.11 1631.81,1674.18 1793.58,1674.18 1841.94,1722.55 2088.46,1722.55 2107.71,1703.3 2245.02,1703.3 2263.39,1721.68 2335.86,1721.68 2425.67,1811.49 2537.78,1811.49 2644.68,1918.38 2645.01,1926.18 2668.32,1949.49 2705.29,1949.49 2705.48,1949.3 2714.63,1940.15 2716.02,1938.76 2818.58,1938.76 2849.99,1907.35 2872.41,1907.35 2915.43,1864.33 3090.24,1864.33 3112.78,1841.79 3447.4,1841.79 3467.99,1821.21 3641.7,1821.21 3679.24,1783.66 3679.24,1735.33 3635.58,1691.67 3635.58,1643.45 3657.37,1621.66 3657.37,1414.29
AM263P_TDI_R: R326.2 U26.2 | length 79.1
  Top Layer w5.3: U26.2@1503.89,1426.5 1580.54,1426.5 R326.2@1582.27,1424.77
AM263P_TDI_XDS: R135.1 U26.7 | length 994.6
  Top Layer w5.3: v1(568.29,1801.76) 568.29,1775.5 647.02,1696.77 715.44,1696.77 795.29,1616.92 899,1616.92 955.57,1560.35 972.24,1560.35 1000.34,1532.25 1000.34,1518.38 994.78,1512.82 985.63,1512.82 976.21,1503.4 976.21,1487.82 1005.8,1458.23 1091.02,1458.23 1122.75,1426.5 U26.7@1287.35,1426.5
  Bottom Layer w5.3: v1(568.29,1801.76) 580.5,1789.55 R135.1@580.5,1767.63
AM263P_TDO: R7.1 U26.3 | length 2308
  Top Layer w5.3: U26.3@1503.89,1476.5 1563.4,1476.5 v1(1567.18,1480.27) ; R7.1@3410,1632.17 3410,1668.5 3420,1678.5 v1(3420,1754.42)
  SIG 1 w4.75: v1(1567.18,1480.27) 1583.36,1480.27 1672.1,1569.01 1769.47,1569.01 1868.97,1570.7 1944.53,1646.26 2072.26,1646.26 2084.34,1634.18 2287.89,1634.18 2316.97,1663.26 2371.91,1663.26 2412.56,1703.91 2482.35,1703.91 2562.13,1783.69 2562.13,1793.2 2607.74,1838.8 2659.23,1890.3 2697.6,1890.3 2708.95,1901.65 2813.05,1901.65 2814.96,1899.74 2839.95,1874.75 2841.01,1873.69 2857.08,1873.69 2929.66,1801.11 2944.87,1785.89 3215.7,1785.89 3224.89,1776.7 3233.17,1768.43 3266.61,1737.1 3397.25,1737.1 3400.1,1737.28 ccw(c3399.8,1742.02) 3403.16,1738.66 3418.92,1754.42 v1(3420,1754.42)
AM263P_TDO_R: R7.2 U1.C4 | length 368.9
  Top Layer w5.3: R7.2@3410,1592.8 3410.06,1592.74 3410.06,1576.14 v1(3424.12,1562.07)
  Top Layer w10: v1(3625.87,1335.55) U1.C4@3641.62,1319.8
  Bottom Layer w4: 3570.71,1414.29 3625.87,1359.13 v1(3625.87,1335.55)
  Bottom Layer w5.3: v1(3424.12,1562.07) 3424.12,1560.88 3570.71,1414.29
AM263P_TDO_XDS: U24.37 U26.6 | length 768.7
  Top Layer w5.3: v1(998.32,1493.32) 1102.03,1493.32 1109.33,1486.02 1198.12,1486.02 1207.64,1476.5 U26.6@1287.35,1476.5
  SIG 1 w5.3: v1(643.78,1541.58) 655.48,1529.88 744.76,1529.88 761.6,1513.05 948.43,1513.05 968.18,1493.29 v1(998.32,1493.32)
  Bottom Layer w5.3: U24.37@614.4,1627.52 614.4,1570.96 v1(643.78,1541.58)
AM263P_TMS: R325.1 U1.D5 | length 2869.5
  Top Layer w5.3: v1(1618.67,1595.4) 1618.67,1596.47 1626.37,1604.17 R325.1@1626.37,1624.01
  Top Layer w10: v1(3657.37,1304.06) U1.D5@3673.12,1288.31
  SIG 1 w4: 3640.87,1414.29 3640.87,1320.55 v1(3657.37,1304.06)
  SIG 1 w4.75: v1(1618.67,1595.4) 1681.73,1595.4 1706.01,1619.67 1831.73,1619.67 1923.89,1711.84 2084.27,1711.84 2104.93,1691.17 2255.95,1691.17 2271.96,1707.18 2335.57,1707.18 2429.83,1801.44 2541.95,1801.44 2579.31,1838.8 2655.06,1914.55 2655.06,1922.02 2672.49,1939.44 2701.12,1939.44 2714.55,1926.02 2817.11,1926.02 2846.84,1896.29 2862.9,1896.29 2943.35,1815.84 3000.87,1815.84 3033.5,1848.46 3081.36,1848.46 3098.08,1831.74 3443.24,1831.74 3444.63,1830.35 3463.83,1811.16 3637.53,1811.16 3669.19,1779.5 3669.19,1739.5 3624.47,1694.77 3624.47,1634.39 3640.87,1617.99 3640.87,1414.29
AM263P_TMS_R: R325.2 U25.6 | length 76.4
  Top Layer w5.3: U25.6@1507.47,1635.47 1542.07,1635.47 1553.53,1624.01 R325.2@1579.12,1624.01
AM263P_TMS_XDS: R134.1 U25.3 | length 861.1
  Top Layer w5.3: v1(1248.43,1651.45) 1260.92,1638.95 1286.99,1638.95 U25.3@1290.47,1635.47
  SIG 1 w4.75: v1(530.73,1800) 598.57,1732.16 884.17,1732.16 940.1,1676.24 1120.19,1676.24 1142.45,1651.45 v1(1248.43,1651.45)
  Bottom Layer w5.3: v1@530.5,1799.77 v1(530.73,1800) R134.1@530.73,1767.86
AM263P_U52_MUX_SEL: R441.2 R442.2 U52.9 U52.10 U63.16 | length 3500.8
  Top Layer w5.3: U52.9@4629.96,670 4693.86,670 4705,681.14 v1(4705,681.99) 4702.7,681.99 4695,689.68 U52.10@4629.96,689.68
  SIG 1 w4.75: v1(2602.28,386.69) 2612.21,396.62 2692.95,396.62 2699.94,389.63 2901.59,389.63 2964.08,452.12 ; 2964.08,452.16 2970.15,458.24 3177.22,458.24 3187.77,447.69 3242.2,447.69 3314.73,375.15 3454.51,375.15 3601.25,228.41 3601.95,228.41 3607.13,223.22 3695.28,223.22 3708.29,236.23 3723.36,236.23 3724.46,237.34 3781.44,237.34 3854.92,310.82 3907.35,310.82 3914.32,317.78 3932.35,317.78 3945.56,304.57 3945.56,248.36 3956.58,237.34 4011.56,237.34 4034.58,260.35 4034.58,340.75 4097.56,403.72 4097.56,403.9 4146.66,453 4185.05,453 4217.23,420.82 4460.98,420.82 4515.99,475.83 4691.09,475.83 4708.44,493.18 4724.25,493.18 4734.94,482.48 4734.94,460.8 4749.28,446.47 4749.28,446.24 4756.86,438.66 4883.6,438.66 v1(4890,445.07)
  Bottom Layer w5.3: U63.16@2539.12,508.67 2539.12,477.2 2585.84,430.48 2585.84,409.31 2599.85,395.3 2599.85,389.12 v1(2602.28,386.69) ; v1(4705,681.99) 4705,643.01 4698.72,636.73 4698.72,599.05 4711.47,586.3 R442.2@4758.22,586.3 ; R441.2@4758.81,682.33 4758.22,681.74 R442.2@4758.22,586.3 ; v1(4890,445.07) 4888.47,446.6 4875.37,446.6 4758.22,563.75 R442.2@4758.22,586.3
AM263P_UART0_RXD: R327.1 U1.A7 | length 3541.2
  Top Layer w4: U1.A7@3736.11,1382.8 3736.11,1414.29
  Top Layer w5.3: v1(1603.45,1238.33) 1618.61,1238.33 1631.5,1225.45 R327.1@1631.5,1210 ; 3736.11,1414.29 3736.11,1416.7 3726.25,1426.56 3726.25,1516.94 3732.37,1523.07 3732.37,1681.62 3749.04,1698.29 v1(3749.04,1725.82)
  SIG 1 w4.75: v1(1603.45,1238.33) 1540.63,1238.33 1495.68,1283.28 1495.68,1723.44 1531.41,1759.17 1652.96,1759.17 1658.38,1753.75 1686.75,1753.75 1734,1801 1851,1801 1883.28,1768.72 2258.88,1768.72 2293.57,1803.41 2344.68,1803.41 2396.16,1854.89 2538.55,1854.89 2611.49,1927.83 2611.49,1935.3 2657.19,1981 2716.42,1981 2728.51,1968.91 2831.06,1968.91 2862.47,1937.5 2894.07,1937.5 2937.09,1894.48 3102.73,1894.48 3125.26,1871.94 3390.31,1871.94 3390.83,1872.46 3687.96,1872.46 3730.75,1829.67 3730.75,1794.48 3713.62,1777.35 3713.62,1755.82 3727.49,1741.95 3732.91,1741.95 v1(3749.04,1725.82)
AM263P_UART0_RXD_R: R327.2 U27.2 | length 91.8
  Top Layer w5.3: U27.2@1503.27,1215.27 1519.02,1215.27 1534.73,1199.56 1555.79,1199.56 1564.4,1208.17 1582.42,1208.17 R327.2@1584.25,1210
AM263P_UART0_RXD_XDS: R131.1 U27.7 | length 1366.3
  Top Layer w5.3: v1(944.94,1215.8) 946.88,1217.73 985.43,1217.73 1059.74,1292.05 1162.08,1292.05 1238.87,1215.27 U27.7@1286.73,1215.27
  SIG 1 w4.75: v1(429.6,1798.18) 429.6,1708.7 629.35,1508.96 729.79,1508.96 746.66,1492.08 877.83,1492.08 940.1,1429.81 940.1,1224.23 944.94,1219.39 v1(944.94,1215.8)
  Bottom Layer w5.3: R131.1@429.6,1768.53 v1(429.6,1798.18)
AM263P_UART0_TXD: R164.1 U27.3 | length 3156
  Top Layer w4.75: R164.1@3699.91,1636.23 3699.91,1658.68 3710.95,1669.72 3710.95,1715.33 v1(3710.05,1716.24)
  Top Layer w5.3: U27.3@1503.27,1265.27 1504.6,1263.94 1573.52,1263.94 1581.61,1272.03 v1(1582.97,1272.03)
  SIG 1 w4.75: v1(1582.97,1272.03) 1546.77,1272.03 1507.34,1311.46 1507.34,1720.8 1535.66,1749.12 1648.8,1749.12 1654.87,1743.05 1696.05,1743.05 1743.66,1790.66 1847.13,1790.66 1879.12,1758.67 2339.29,1758.67 2419.42,1838.8 2425.46,1844.84 2542.71,1844.84 2621.44,1923.57 2621.77,1931.36 2661.35,1970.95 2712.26,1970.95 2717.04,1966.17 2724.35,1958.86 2826.9,1958.86 2858.31,1927.45 2889.91,1927.45 2932.93,1884.43 3098.56,1884.43 3121.1,1861.89 3394.48,1861.89 3395,1862.41 3628.92,1862.41 3695.53,1795.8 3695.53,1730.76 v1(3710.05,1716.24)
AM263P_UART0_TXD_R: R164.2 U1.A6 | length 235.4
  Top Layer w5.3: R164.2@3699.91,1588.99 3699.91,1585.05 3669.34,1554.48 3669.34,1435.45 3704.61,1400.18 U1.A6@3704.61,1382.8 ; R164.2@3707,1592.8 R164.2@3708.39,1591.41
AM263P_UART0_TXD_XDS: R129.1 U27.6 | length 1395.4
  Top Layer w5.3: v1(975.93,1240.71) 977.2,1240.71 1039.13,1302.65 1189.97,1302.65 1227.35,1265.27 U27.6@1286.73,1265.27
  SIG 1 w5.3: v1(380.73,1800) 401.08,1820.35 446.66,1820.35 454.57,1812.44 454.57,1698.34 633.62,1519.28 738.25,1519.28 755.09,1502.45 885.71,1502.45 954.86,1433.29 954.86,1261.78 v1(975.93,1240.71)
  Bottom Layer w5.3: R129.1@380.5,1767.63 380.5,1799.77 v1(380.73,1800)
AM263P_UART5_RXD: J1/J3.3 U54.5 | length 1419.8
  Top Layer w5.3: J1/J3.3@1804.17,250 1848.57,294.4 1939.91,294.4 1957.79,276.52 1957.79,223.75 1989.6,191.94 2236.1,191.94 2256.93,212.77 2256.93,277.73 2273.48,294.28 2431.33,294.28 2459.65,322.6 2459.65,368.36 2424.45,403.57 2423.95,403.57 2423.02,404.5 2385.56,404.5 2319.53,470.52 2319.53,550.55 2416.72,647.74 2510.24,647.74 2528.41,665.9 U54.5@2528.41,681.41
AM263P_UART5_TXD: J1/J3.4 U54.2 | length 1543
  Top Layer w5.3: J1/J3.4@1904.17,250 1975.67,178.5 2201.29,178.5 2236.93,142.86 2423.24,142.86 2453.9,173.51 2453.9,260.63 2490.91,297.64 2516.94,297.64 2549.13,329.83 2549.13,372.54 2531.79,391.04 2451.97,391.04 2428.84,414.17 2428.77,414.17 2427.84,415.1 2389.95,415.1 2330.13,474.91 2330.13,546.16 2421.11,637.14 2523.98,637.14 2531.09,644.25 2599.47,644.25 2605.18,649.96 U54.2@2605.18,681.41
AM263P_WARMRSTN: R5.2 U1.C3 U9.1 U35.2 U60.2 U62.2 U63.24 U65.2 | length 9922.3
  Top Layer w10: v1(3594.38,1335.55) U1.C3@3610.13,1319.8
  SIG 1 w4: v1(3594.38,1335.55) 3594.38,1408.67
  SIG 1 w4.75: v1(1867.19,1616.67) 1923.86,1673.34 2100.36,1673.34 2127.83,1645.86 2231.09,1645.86 2270.23,1685 2366.01,1685 2398.58,1717.57 2481.8,1717.57 2552.08,1787.86 2552.08,1797.36 2665.16,1910.44 2665.16,1917.91 2676.65,1929.39 2696.96,1929.39 2714.65,1911.7 2817.21,1911.7 2819.12,1909.79 2844.11,1884.8 2845.17,1883.74 2861.24,1883.74 2946.43,1798.54 3225.86,1798.54 3247.14,1777.26 3248.8,1775.6 3491.12,1775.6 3492.76,1777.24 3503.86,1777.24 v1(3506.1,1775) 3522.16,1791.06 3596.17,1791.06 3615.33,1771.89 3615.33,1723.68 3604.13,1712.47 3604.13,1604.79 3615.3,1593.62 3615.3,1531.55 3615.33,1452.45 3594.38,1431.5 3594.38,1408.67
  SIG 1 w5.3: v1(2474.29,740.64) 2474.29,741.92 2441.2,775.01 2441.2,842.35 2451.8,852.95 2541.64,852.95 2576.2,887.51 2576.2,1001.01 v1(2586.31,1011.12) ; v1(5595.85,2146.14) 5816.4,2146.14 5860.88,2190.62 6759.38,2190.62 v1(6810,2140) 6994.62,1955.38 v4(6994.62,1453.26)
  Bottom Layer w5.3: R5.2@1773.66,1440.95 1833.53,1440.95 U9.1@1834.48,1440 1879.55,1440 1895,1455.45 1895,1556.9 1906.8,1568.7 ; U62.2@1834.58,1616.67 v1(1867.19,1616.67) ; v1@1867.6,1616.2 1889.51,1616.2 1906.8,1598.91 1906.8,1568.7 ; U63.24@2474.16,632.69 v1@2474.16,740.51 ; v1(2474.29,740.64) v1@2474.16,740.51 ; v1(2586.31,1011.12) 2615.1,1011.12 2640.5,1036.53 2709.82,1036.53 2721.89,1024.46 2721.89,1006.14 2693.26,977.52 2693.26,956.78 2706.9,943.14 2723.46,943.14 2733.67,953.35 U35.2@2764.38,953.35 ; v1@3506.63,1775 3641.1,1909.47 3822.46,1909.47 3855.32,1942.33 3960.79,1942.33 4012.47,1994 4012.47,2026.69 4122.79,2137.01 4284.82,2137.01 4295.22,2126.62 4491.57,2126.62 4522.44,2157.49 5584.51,2157.49 v1(5595.85,2146.14) ; U60.2@6626.26,2213.9 6626.26,2170.37 6656.63,2140 v1(6810,2140) ; U65.2@6969.94,1257.25 7016.15,1257.25 7031.57,1272.68 7031.57,1416.31 v4(6994.62,1453.26) ; 1906.8,1568.7 1929.85,1545.65 1966.41,1545.65 1996.91,1515.15 2055.41,1515.15 2066.65,1503.92 2066.65,1366.61 2093.2,1340.06 2093.2,1203.27 2078.03,1188.11 2078.03,719.93 2147.44,650.51 2148.05,650.51 2148.54,650.03 2158.09,650.03 2197.13,610.98 2276.51,610.98 2359.79,694.25 2389.69,694.25 2435.95,740.51 v1@2474.16,740.51
AM263P_XDS_I2C2_SDA: R413.2 U24.81 | length 361.2
  Top Layer w5.3: v1(1051.29,1145.5) 1084.31,1112.48 R413.2@1084.31,1073.93
  Bottom Layer w5.3: v1(1051.29,1145.5) 1026.43,1170.36 1001.88,1170.36 989.01,1183.23 989.01,1217.13 995.63,1223.75 995.63,1246.46 1065.67,1316.5 U24.81@1098.65,1316.5
AM263P_XDS_I2C_SCL: R414.2 U24.82 | length 385.9
  Top Layer w5.3: v1(1008.53,1196.29) 1010.18,1196.29 1030.79,1175.67 1073.05,1175.67 1109.26,1139.47 1133.43,1139.47 1173.39,1099.51 R414.2@1173.39,1079.98
  Bottom Layer w5.3: v1(1008.53,1196.29) 1010.18,1197.93 1010.18,1245.81 1065.12,1300.75 U24.82@1098.65,1300.75
AM263P_XTAL_XI: C58.2 U1.T1 Y1.1 | length 421.5
  Top Layer w5.3: Y1.1@3238.01,782.59 3242.89,782.59 3252.23,773.26 3252.23,747.86 3269.27,730.82 3307.28,730.82 3341.03,764.56 C58.2@3354.72,764.56 ; C58.2@3355,764.84 3405.1,764.84 3515.64,875.37 3547.13,906.87 U1.T1@3547.13,910.35
AM263P_XTAL_XO: C59.2 U1.R1 Y1.3 | length 313.3
  Top Layer w5.3: Y1.3@3301.99,829.84 3311.5,820.32 3344.61,820.32 3347.28,822.99 3347.81,822.99 3355,830.19 3355,830.71 3371.4,814.32 3383.73,814.32 3467.98,898.57 3491,898.57 3503.77,898.57 U1.R1@3547.13,941.85 U1.R1@3547.13,941.85
BOOTMODE_XDS_I2C_SCL: R399.1 U24.49 U56.3 | length 834
  Top Layer w5.3: v1(744.97,1579.34) 744.97,1575.9 755,1565.87 R399.1@755,1538.31
  Bottom Layer w5.3: v1(744.97,1579.34) 759.53,1564.78 788.71,1564.78 803.37,1579.44 U24.49@803.37,1627.52 803.37,1682.2 832.03,1710.85 832.03,1754.5 850.31,1772.78 1183.57,1772.78 1227.22,1729.12 1227.22,1689.44 1243.31,1673.36 U56.3@1291.42,1673.36
BOOTMODE_XDS_I2C_SDA: R400.1 U24.50 U56.2 | length 624
  Top Layer w5.3: R400.1@809.19,1542.29 809.19,1567.32 v1(822.9,1581.03)
  SIG 1 w5.3: v1(822.9,1581.03) 822.9,1606.73 841.17,1625 1109.24,1625 1146.01,1588.23 v1(1193.07,1588.23)
  Bottom Layer w5.3: U24.50@819.12,1627.52 819.12,1588.24 822.9,1584.47 v1(822.9,1581.03) ; v1(1193.07,1588.23) 1195.37,1588.23 1230.5,1623.36 U56.2@1291.42,1623.36
BP_PORZ: J2/J4.16 J6/J8.56 R180.2 | length 4350.2
  SIG 1 w4.75: v1(860,2010) 882.78,2010 904.03,1988.75 919.97,1988.75 925.47,1994.25 993.25,1994.25 1064.53,2065.53 1298.1,2065.53 1314.35,2081.78 1444.96,2081.78 1478.39,2048.35 1539.31,2048.35 ; 1603.62,2112.65 1927.24,2112.65 1989.89,2050 J2/J4.16@2004.17,2050 2004.17,2156.68 2094.25,2246.75 2899.97,2246.75 3038.44,2108.28 3038.44,2086.46 3084.72,2040.18 3085.11,2040.18 3115.49,2009.8 3152.36,2009.8
  SIG 1 w5.3: 1539.31,2048.35 1603.62,2112.65 ; 3152.36,2009.8 3232.09,2009.8 3453.38,2231.09 4257.1,2231.09 4377.06,2111.14 4443.04,2111.14 J6/J8.56@4504.17,2050
  Bottom Layer w4.75: R180.2@706,1979.69 727.49,1979.69 732.5,1974.68 748.52,1974.68 767.09,1993.25 843.25,1993.25 v1(860,2010)
CAN_STB: R244.1 R248.1 R250.2 U42.8 | length 238
  Bottom Layer w5.3: R248.1@6855,267.87 R250.2@6895,267.87 R244.1@6935,267.87 6960,267.87 6980.91,246.96 6980.91,184.09 6990.16,174.84 U42.8@7017.68,174.84
CANA_N: J33.1 R246.2 U42.6 | length 601.7
  Bottom Layer w4.1: J33.1@6516.38,183.86 6559.77,140.47 6642.64,140.47 6648.72,134.38 6648.72,103.22 6670.48,81.46 6826.84,81.46 6876.39,131.01 6933.25,131.01 R246.2@6952.8,111.46 6972.35,131.01 7004.62,131.01 7011.97,123.66 U42.6@7017.68,123.66
CANA_P: J33.3 R247.2 U42.7 | length 601.6
  Bottom Layer w4.1: J33.3@6791.97,183.86 6791.97,152.58 6779.86,140.47 6666.4,140.47 6659.62,133.69 6659.62,107.74 6675,92.36 6822.33,92.36 6871.87,141.91 6933.25,141.91 R247.2@6952.8,161.46 6972.35,141.91 7004.62,141.91 7011.97,149.25 U42.7@7017.68,149.25
"CPSW RGMI1/ICSSM_MII1_RST_EN": R424.2 U63.3 U65.1 | length 6447.6
  SIG 1 w5.3: v1(4161.41,417.5) 4161.41,415.26 4184.79,391.87 4893.34,391.87 4983.82,482.35 5038.07,482.35 5089.65,482.35 5102.72,495.42 5138.52,495.42 5160.42,517.32 5160.42,597.69 5204.93,642.2 5533.96,642.2 5693.44,482.72 6221.66,482.72 6282.39,422 6386,422 6462.81,498.81 v1(6462.81,520.52)
  Bottom Layer w5.3: U63.3@2539.12,658.28 2539.12,673.84 2517.92,695.04 2517.92,764.32 2567.19,813.58 2631.16,813.58 2682.36,762.38 2774,762.38 2863.95,672.43 2863.95,613.81 2957.84,519.92 3183.57,519.92 3218.83,484.66 3218.83,455.92 3303.78,370.98 3486.38,370.98 3506.09,351.28 3767.26,351.28 3779.34,339.19 3887.43,339.19 3950.9,402.67 3967.89,402.67 4003.01,437.79 4052.53,437.79 4072.33,417.99 v1@4161.41,417.99 ; v1(6462.81,520.52) 6433.89,520.52 6395.48,558.92 6321.07,558.92 6175.53,704.46 6175.53,894.56 6178.12,897.15 6306.18,1025.21 6306.18,1140 6336.76,1170.58 6483,1170.58 6505.05,1192.62 6674.39,1192.62 6702.36,1220.6 6702.36,1329.31 6774.24,1401.19 6856.03,1401.19 6909.16,1348.06 R424.2@6968.46,1348.06 6969.94,1346.58 U65.1@6969.94,1294.66
"CPSW RGMI2/ICSSM_MII0_RST_EN": R417.2 U60.1 U63.4 | length 6641
  SIG 1 w4.75: v1(4007.93,415.1) 4077.95,485.12 4198.43,485.12 4237.72,445.82 4449.78,445.82 4502.97,499.01 4681.54,499.01 4701.75,519.21 4776.02,519.21 4804.7,490.54 4960.11,490.54 5025.34,555.76 5109.39,555.76 5140.05,586.43 5140.05,606.13 5197.31,663.39 5546.81,663.39 5629.77,580.44 5778.12,580.44 5797.73,600.05 5972.56,600.05 6023.36,549.25 6078.49,549.25 6127.04,500.7 6302.33,500.7 6341.03,539.4 v1(6387.4,539.4)
  Bottom Layer w5.3: U63.4@2558.81,658.28 2558.81,672.47 2528.52,702.76 2528.52,744.72 2581.94,798.14 2631.61,798.14 2677.97,751.78 2769.61,751.78 2851.8,669.59 2851.8,605.54 2951.37,505.97 3128.75,505.97 3187.58,447.15 3212.62,447.15 3299.38,360.38 3481.99,360.38 3501.7,340.68 3762.86,340.68 3774.95,328.59 3891.82,328.59 3955.29,392.07 3972.28,392.07 3992.88,412.67 4005.5,412.67 v1(4007.93,415.1) ; v1(6387.4,539.4) 6325.6,539.4 6157.5,707.5 6157.5,898.07 6189.91,930.48 6189.91,1706.91 6171.85,1724.96 6171.85,2005.85 6380.92,2214.91 6587.85,2214.91 U60.1@6588.86,2213.9
DAC_EXT_VREF: J18.2 S1.3 | length 167.9
  Top Layer w20: J18.2@2852.18,489.31 2943.49,489.31 2955.2,501.02 S1.3@2955.2,561.06
DAC_VREF: C89.1 C90.1 C91.1 S1.2 U1.T6 U1.T13 | length 1803.3
  Top Layer w15: S1.2@3024.1,470.51 3024.1,597.74 3054.5,628.14 v1(3054.5,628.64) ; C91.1@3590,618.62 3590,648.72 3592.33,651.05 v1(3592.33,651.86) ; v1(3688.87,894.61) U1.T6@3704.61,910.35 ; U1.T13@3925.09,910.35 v1(3940.83,894.61)
  SIG 1 w15: v1(3940.83,894.61) 3980.05,855.39 3980,855.33 v1(3980,736.35)
  Bottom Layer w8: C89.1@3015,628.5 3015.14,628.64 3055,628.64 3206.65,780.29 3346.62,780.29 3487.42,639.49 3551.15,639.49 3563.52,651.86 v1(3592.33,651.86) 3592.33,649.16 3595,646.48 C90.1@3595,618.53 3619.62,618.53 3635.58,634.49 3635.58,705.94 3669.59,739.95 ; v1(3688.87,894.61) 3688.87,838.77 3669.59,819.5 3669.59,739.95 ; v1(3980,736.35) 3976.4,739.95 3669.59,739.95
EEPROM_A0: R318.2 R321.2 U16.1 | length 154.4
  Top Layer w5.3: U16.1@5760.08,489.14 5844.38,489.14 R318.2@5845.31,488.21 R321.2@5845.31,556.99
EEPROM_A1: R319.2 R322.2 U16.2 | length 185.7
  Top Layer w5.3: U16.2@5760.08,539.14 v1(5806.02,539.14)
  Bottom Layer w5.3: v1@5802.16,538.72 5811.54,548.1 R322.2@5811.54,610.87 ; R322.2@5811.54,611.17 R319.2@5811.54,674.85
EEPROM_A2: R320.2 R323.2 U16.3 | length 167.7
  Top Layer w5.3: U16.3@5760.08,589.14 5836.53,589.14 5845.31,597.92 R323.2@5845.31,615 R320.2@5845.31,676.73
EEPROM_WP: R316.1 U16.7 | length 123.7
  Top Layer w5.3: v1(5487.62,549.47) 5487.62,547.91 5496.38,539.14 U16.7@5545.51,539.14
  Bottom Layer w5.3: v1(5487.62,549.47) 5502.79,549.47 5507.22,545.04 R316.1@5546.38,545.04
EMMC_RST: R421.1 U61.K5 U62.4 | length 590.8
  SIG 1 w5.3: v1(2063.89,1625.49) 2094.44,1594.93 2143.18,1594.93 2164.41,1594.93 2174.85,1605.38 2248.98,1605.38 2262.25,1592.12 2308.92,1592.12 2331.81,1615 2378.48,1615 2397.71,1634.23 2397.71,1650.89 v1(2417.25,1670.43)
  Bottom Layer w3.4: U61.K5@2395.55,1654.01 2409.17,1667.63 2414.46,1667.63 v1(2417.25,1670.43)
  Bottom Layer w5.3: U62.4@1942.75,1653.97 R421.1@2015.37,1653.97 ; R421.1@2017.14,1652.21 2017.14,1628.59 2020.24,1625.49 v1(2063.89,1625.49)
EMMC_RST_EN: R420.2 U62.1 U63.2 | length 2028.5
  SIG 1 w5.3: v1(1773.53,1543.12) 1787.89,1528.75 1912.95,1528.75 1943.41,1559.21 2022.28,1559.21 2061.56,1519.94 v1(2083.38,1519.94)
  Bottom Layer w5.3: v1(1773.53,1543.12) R420.2@1773.53,1579.24 1773.6,1579.17 U62.1@1834.48,1579.17 ; v1(2083.38,1519.94) 2083.38,1364.87 2103.8,1344.45 2103.8,1198.88 2092.31,1187.39 2088.63,1183.71 2088.63,724.32 2092.31,720.64 2151.83,661.11 2152.44,661.11 2152.93,660.63 2208.8,660.63 2242.26,627.17 2276.65,627.17 2356.63,707.15 2385.14,707.15 2442.33,764.34 2442.33,824.94 2453.61,836.23 2505.69,836.23 2523.36,818.56 2523.36,784.74 2507.32,768.71 2507.32,685.85 2519.44,673.73 U63.2@2519.44,658.28
EQEP0_A: C214.1 J24.1 R236.1 U43.20 | length 828.4
  SIG 1 w4.75: v1(5615,135) 5702.83,47.17 6131.34,47.17 J24.1@6199.18,115
  Bottom Layer w5.3: v1(5615,135) 5615.09,135.09 5628.28,135.09 5633.19,140 U43.20@5633.19,155.98
  Bottom Layer w10: J24.1@6199.18,115 C214.1@6199.18,198.5 R236.1@6259.18,198.5
EQEP0_B: C215.2 J24.2 R237.1 U43.18 | length 637.3
  SIG 1 w4.75: v1(5746.83,217) 5783.83,180 6034.18,180 J24.2@6099.18,115
  Bottom Layer w5.3: U43.18@5668.62,191.41 5721.24,191.41 v1(5746.83,217)
  Bottom Layer w10: R237.1@6064.18,198.5 6124.18,198.5 6124.18,140 J24.2@6099.18,115
EQEP0_INDEX: C216.1 J24.3 R238.1 U43.17 | length 514.2
  SIG 1 w4.75: v1(5710.83,211.1) 5713.26,208.67 5721.33,208.67 5765,165 5949.18,165 J24.3@5999.18,115
  Bottom Layer w5.3: U43.17@5668.62,211.1 v1(5710.83,211.1)
  Bottom Layer w10: R238.1@5940,198.5 C216.1@6000,198.5 6000,115.82 J24.3@5999.18,115
EQEP0_STROBE: C220.1 J15.1 R242.1 U43.16 | length 1068.2
  SIG 1 w5.3: v1(5746.83,256.37) 5786.2,217 6184.58,217 6286.58,115 J15.1@6327.06,115
  Bottom Layer w5.3: U43.16@5668.62,230.78 5721.24,230.78 v1(5746.83,256.37) ; J15.1@6327.06,115 6402.9,115 6460.67,172.77 C220.1@6460.67,290.82 6461.51,291.66 R242.1@6461.51,355.53
EQEP2_A: C217.1 J25.1 R239.1 U43.15 | length 777.5
  SIG 1 w4.75: v1(5710.83,250.47) 5735.98,275.62 5816.23,275.62 5855,236.85 6111.85,236.85 6165,290 6165,330.82 J25.1@6199.18,365
  Bottom Layer w5.3: U43.15@5668.62,250.47 v1(5710.83,250.47)
  Bottom Layer w10: J25.1@6199.18,365 C217.1@6199.18,448.5 R239.1@6259.18,448.5
EQEP2_B: C218.2 J25.2 R240.1 U43.14 | length 700.2
  SIG 1 w4.75: v1(5746.83,295.74) 5816.12,295.74 5851.86,260 6074.18,260 6099.18,285 J25.2@6099.18,365
  Bottom Layer w5.3: U43.14@5668.62,270.15 5721.24,270.15 v1(5746.83,295.74)
  Bottom Layer w10: R240.1@6064.18,448.5 6124.18,448.5 6124.18,390 J25.2@6099.18,365
EQEP2_INDEX: C219.1 J25.3 R241.1 U43.13 | length 505.8
  SIG 1 w4.75: v1(5710.83,289.84) 5736.25,315.27 5754.91,315.27 5755.18,315 5949.18,315 J25.3@5999.18,365
  Bottom Layer w5.3: U43.13@5668.62,289.84 v1(5710.83,289.84)
  Bottom Layer w10: R241.1@5940,448.5 C219.1@6000,448.5 6000,365.82 J25.3@5999.18,365
EQEP2_STROBE: C221.1 J16.1 R243.1 U43.12 | length 1026.2
  Top Layer w5.3: R243.1@6228.62,578.2 C221.1@6228.62,494.67 6228.62,426.16 6289.78,365 J16.1@6327.06,365
  SIG 1 w5.3: v1(5746.83,335.11) 5746.83,376.91 5788.61,418.7 6234.98,418.7 6288.68,365 J16.1@6327.06,365
  Bottom Layer w5.3: U43.12@5668.62,309.52 5721.24,309.52 v1(5746.83,335.11)
ETH1_CLKOUT: R106.2 R213.1 | length 674.4
  Top Layer w5.3: v1(6480,1001.54) 6492.48,989.06 6492.48,964.89 R106.2@6493.31,964.06
  SIG 1 w5.3: v1(6455,1198.82) 6455,1198.58 6511.01,1142.57 6514.26,1142.57 6578.11,1078.71 6578.11,999.23 6564.36,985.48 6496.06,985.48 v1(6480,1001.54)
  Bottom Layer w5.3: v1(6455,1198.82) 6456.28,1200.09 6456.28,1390.04 6487.61,1421.38 R213.1@6520,1421.38
ETH1_CLKOUT_R: R106.1 U22.40 | length 143.4
  Top Layer w5.3: R106.1@6493.31,916.82 6493.31,898.47 6506.77,885 v1(6580,885)
  Bottom Layer w5.3: U22.40@6575.96,853.9 6575.96,880.96 v1(6580,885)
ETH1_GPIO_1: R114.1 R126.2 U22.22 | length 124.8
  Top Layer w5.3: R114.1@6520,518.62 R126.2@6570.85,518.62 6570.97,518.5 6570.97,547.55 v1(6556.28,562.25)
  Bottom Layer w5.3: v1(6556.28,562.25) U22.22@6556.28,586.18
ETH1_LED0: Q5.1 R227.1 | length 1372.2
  Top Layer w5.3: v1(7257.91,68.45) 7284.56,68.45 Q5.1@7286.6,66.42
  SIG 1 w5.3: v1(6762.73,1131.46) 6825.85,1068.34 6825.85,991.55 6990,827.4 6990,445.22 7124.89,310.33 7190,310.33 7257.23,243.1 7257.23,181.91 7269.52,169.62 7269.52,117.13 7257.91,105.52 v1(7257.91,68.45)
  Bottom Layer w5.3: R227.1@6762.73,1104.68 v1(6762.73,1131.46)
ETH1_LED1: Q6.1 R229.1 | length 1171.5
  SIG 1 w5.3: v1(6880,966.71) 7005,841.71 7005,445.21 7129.28,320.92 7194.39,320.92 7360,155.32 v1(7360,105)
  Bottom Layer w5.3: R229.1@6846.59,967.35 6879.36,967.35 v1(6880,966.71) ; v1(7360,105) 7361.4,103.6 Q6.1@7361.4,66.42
ETH1_LED2: Q4.1 R225.1 | length 647.5
  Bottom Layer w5.3: R225.1@6715,1104.31 6715,1126.37 6768.63,1180 6849.04,1180 6874,1155.04 7028.54,1155.04 7108.38,1234.88 7220.44,1234.88 7236.69,1218.62 Q4.1@7236.69,1187.24
ETH1_PWDN: R305.2 U22.44 | length 96
  Top Layer w5.3: R305.2@6620,926.46 6635.61,926.46 6647.07,915 6647.07,909.6 6652.43,904.23 6652.43,892.43 v1(6654.86,890)
  Bottom Layer w5.3: U22.44@6654.7,853.9 v1@6654.7,889.84
ETH1_RBIAS: R107.2 U22.12 | length 78.8
  Bottom Layer w5.3: U22.12@6759.03,611.77 6759.03,597.39 6779.43,576.99 R107.2@6815,576.99
ETH1_RD0: R102.1 R108.1 R120.2 U50.2 | length 1562.3
  Top Layer w5.3: U50.2@5303.35,882.24 5370.31,882.24 v1(5390,862.56) ; R108.1@6274.92,802.65 6307.35,802.65 v1(6315,795)
  SIG 1 w4.75: v1(5390,862.56) 5434.78,862.56 5506.27,934.04 5849.85,934.04 5936.89,847 5984.43,847 5995,857.58 5995,887.63 6002.37,895 6027,895 6033.5,888.5 6033.5,808 6042,799.5 6072,799.5 6082.5,810 6082.5,884.31 6090,891.81 6111.9,891.81 6118.31,885.4 6118.31,807.56 6127.58,798.29 6145.75,798.29 6175.76,828.31 6281.69,828.31 v1(6315,795)
  Bottom Layer w5.3: R120.2@6274.92,802.65 6305.55,802.65 6313.2,795 v1(6315,795) ; v1(6315,795) v1(6315,795) ; v1(6315,795) v1(6315,795) ; v1(6315,795) R102.1@6351.89,795.04 v1(6315,795)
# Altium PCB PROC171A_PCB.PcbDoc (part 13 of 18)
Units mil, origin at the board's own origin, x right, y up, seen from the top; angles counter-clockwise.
Board outline 7700 x 2300 mil, 6 copper layers (Top Layer, GND 1, SIG 1, SIG 2, GND 2, Bottom Layer), stack 61.062 mil thick; 945 components, 692 nets, 11945 pads, 1734 vias.

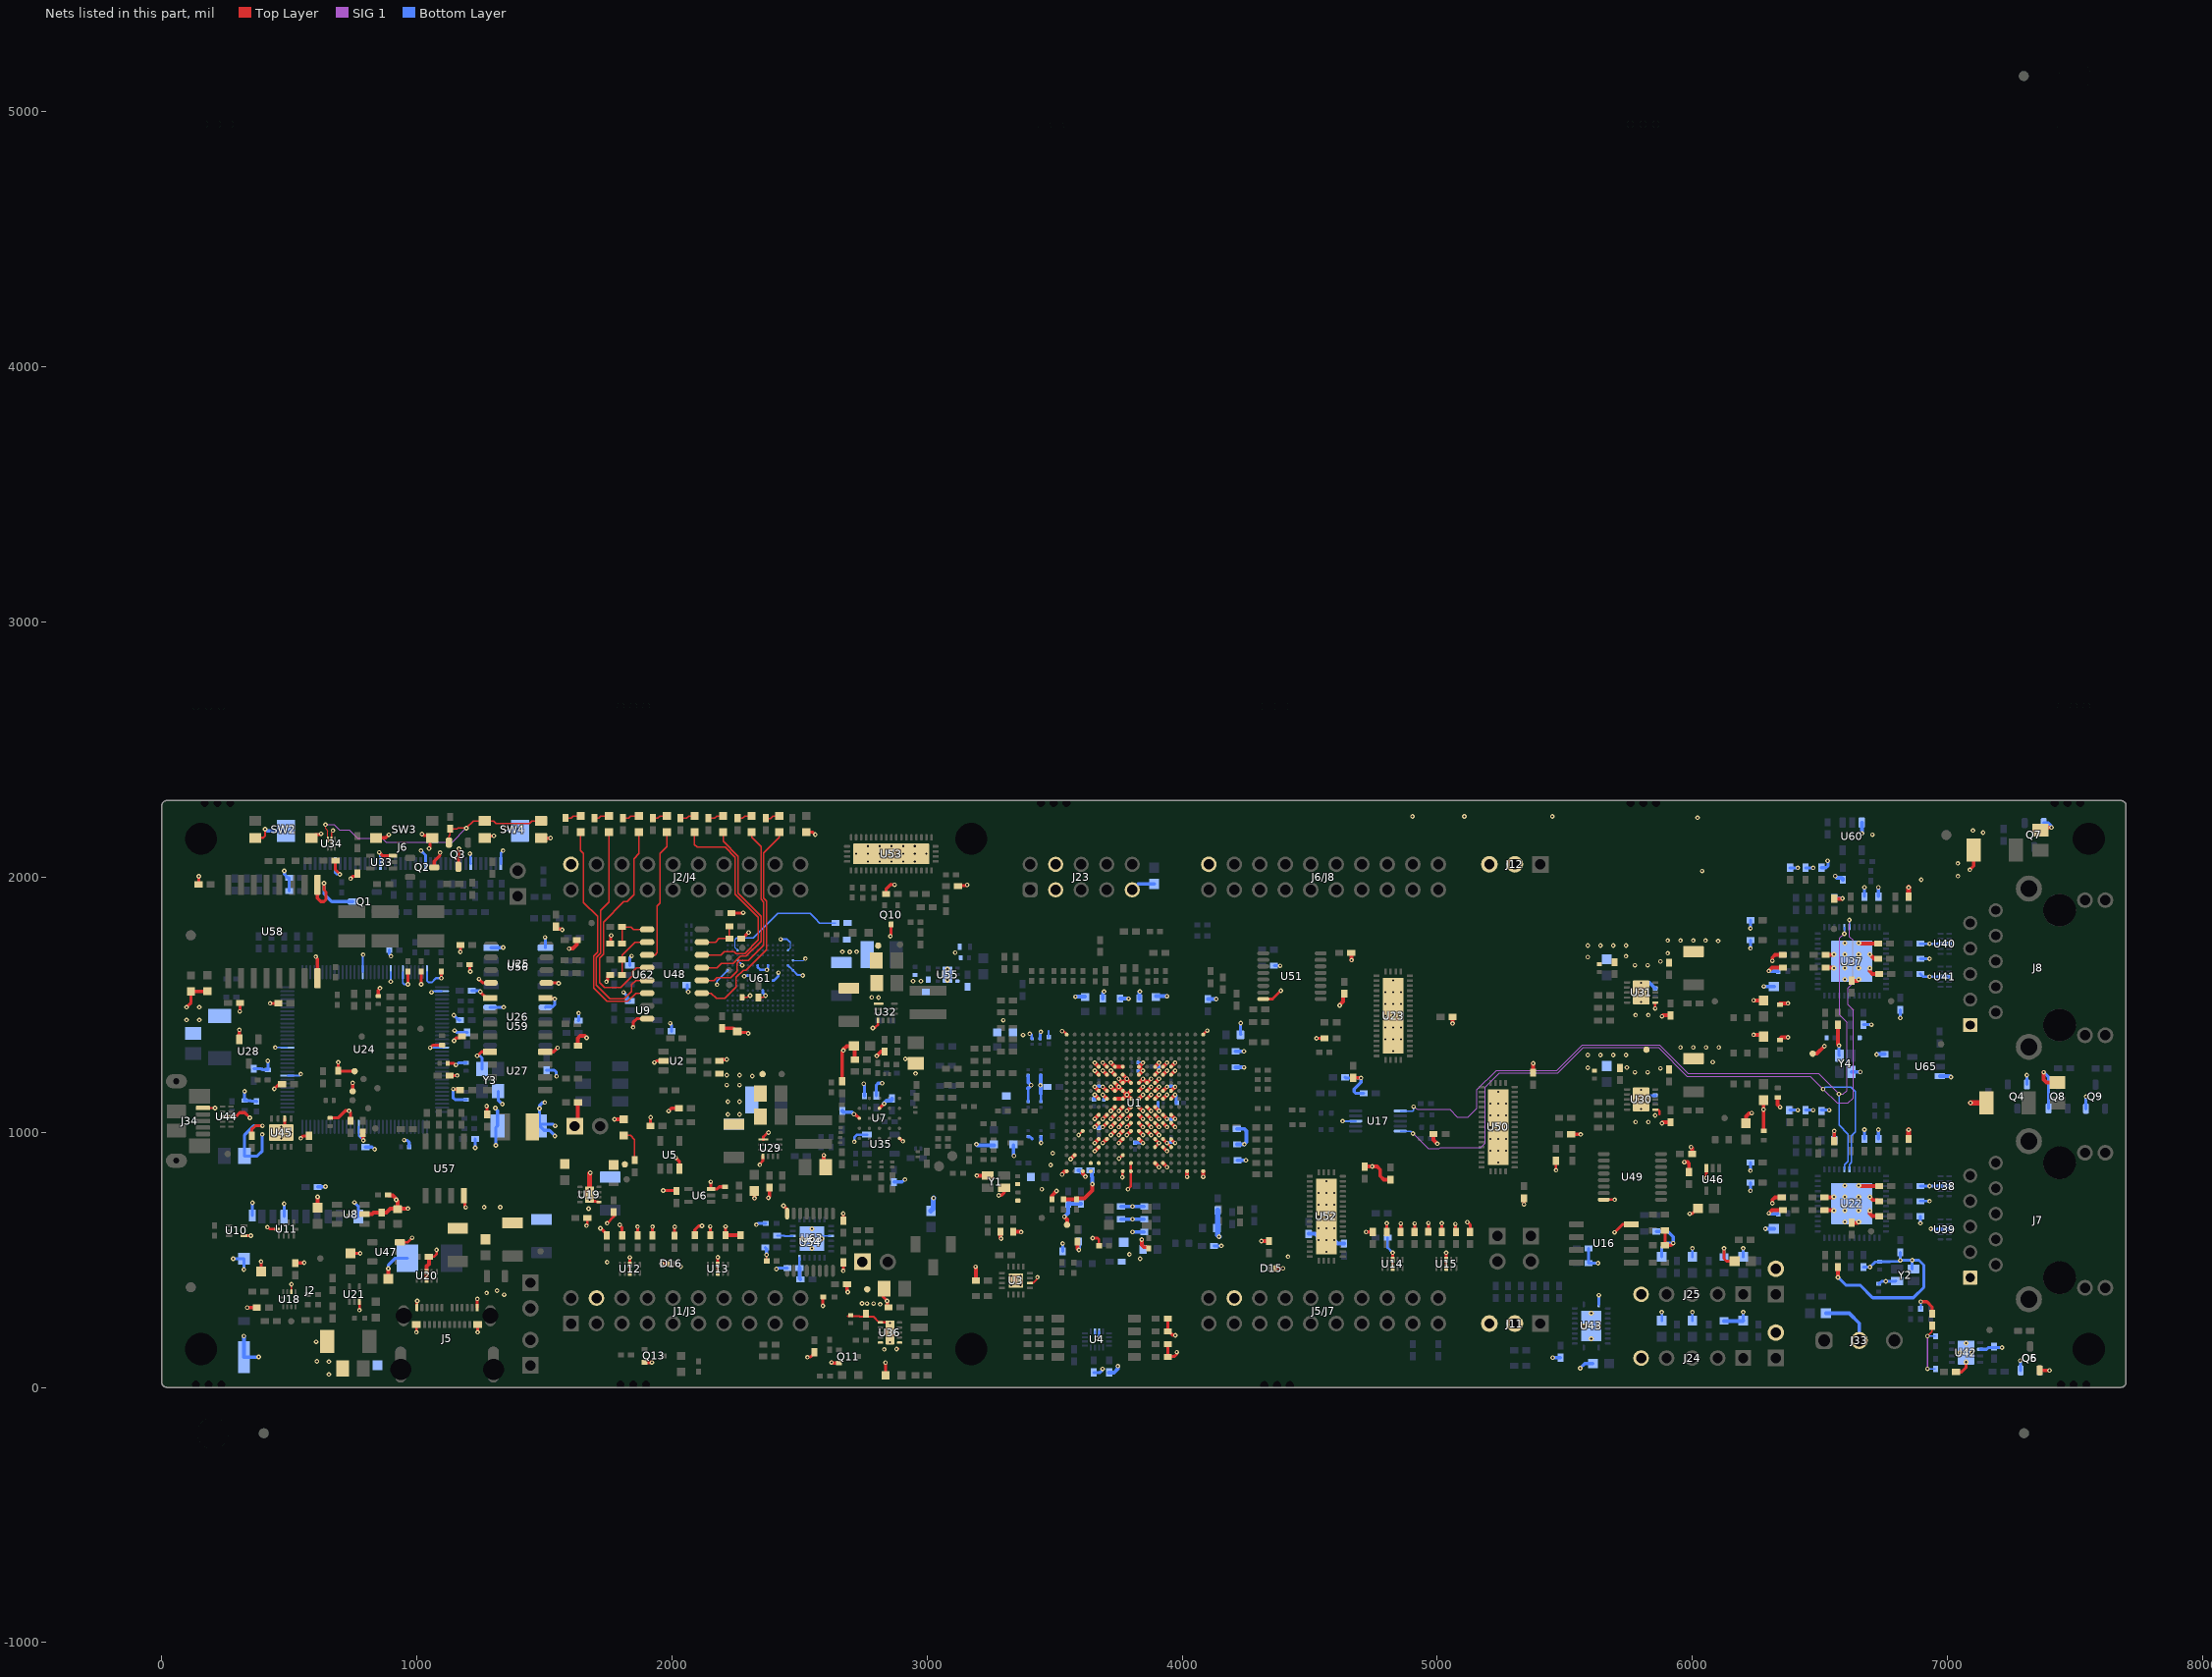
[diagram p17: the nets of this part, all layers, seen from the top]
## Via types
v1: diameter 18, hole 8, Top Layer to Bottom Layer, tented both sides, 1603 vias
v2: diameter 19.68, hole 7.87, Top Layer to Bottom Layer, tented both sides, 104 vias
v3: diameter 19.68, hole 7.87, Top Layer to Bottom Layer, 24 vias
v4: diameter 18, hole 8, Top Layer to Bottom Layer, 3 vias

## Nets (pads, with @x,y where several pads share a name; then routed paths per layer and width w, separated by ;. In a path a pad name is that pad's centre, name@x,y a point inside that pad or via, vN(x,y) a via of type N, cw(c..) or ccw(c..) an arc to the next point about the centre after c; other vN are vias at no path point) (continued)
GND: C1.2 C2.2 C3.2 C4.2 C5.2 C6.2 C7.2 C8.2 C9.2 C10.2 C11.2 C12.2 C13.2 C14.2 C15.2 C16.2 C17.2 C18.2 C19.1 C20.1 C21.1 C22.1 C23.2 C24.2 C25.2 C26.2 C27.2 C28.2 C29.1 C30.1 C31.1 C32.1 C33.2 C34.2 C35.2 C36.2 C37.2 C38.2 C39.1 C40.1 C41.1 C42.1 C43.1 C44.1 C45.1 C46.1 C47.1 C48.2 C49.2 C50.2 C51.2 C52.2 C53.2 C54.2 C55.2 C56.2 C57.1 C58.1 C59.1 C60.1 C61.1 C62.1 C63.1 C64.1 C65.1 C66.2 C67.2 C68.2 C69.2 C70.1 C71.1 C72.2 C73.2 C74.2 C75.2 C81.2 C82.2 C83.2 C84.2 C85.2 C86.2 C87.2 C88.2 C89.2 C90.2 C91.2 C92.2 C93.2 C94.2 C95.2 C96.2 C97.2 C98.2 C99.1 C100.1 C101.2 C102.1 C103.2 C104.1 C105.1 C106.2 C107.1 C108.2 C109.2 C110.2 C111.1 C112.1 C113.1 C114.2 C115.1 C116.2 C117.2 C118.2 C119.2 C120.2 C121.2 C122.2 C123.1 C124.2 C125.2 C126.2 C127.2 C128.2 C129.1 C130.2 C131.2 C132.2 C133.2 C136.1 C137.1 C138.1 C157.2 C158.2 C159.2 C160.2 C161.2 C162.1 C163.2 C164.1 C165.2 C166.1 C167.1 C168.1 C169.2 C170.2 C171.2 C172.2 C173.1 C174.2 C175.1 C176.2 C177.2 C178.1 C179.1 C180.1 C181.1 C182.1 C183.1 C184.1 C185.2 C186.2 C187.1 C188.2 C189.1 C190.1 C191.2 C192.1 C193.2 C194.2 C195.2 C196.2 C197.2 C198.2 C199.2 C200.1 C201.2 C202.2 C203.2 C204.2 C205.2 C206.1 C207.2 C208.2 C209.2 C210.2 C211.2 C212.2 C213.2 C214.2 C215.1 C216.2 C217.2 C218.1 C219.2 C220.2 C221.2 C222.2 C223.1 C224.2 C225.1 C226.1 C229.1 C234.2 C235.1 C236.2 C237.2 C238.1 C239.1 C240.1 C241.1 C242.1 C243.1 C244.1 C245.1 C246.1 C247.1 C248.2 C249.2 C252.2 C253.1 C254.2 C255.1 C256.2 C257.2 C258.2 C259.2 C260.2 C261.2 C262.2 C263.2 C264.2 C265.2 C266.2 C267.2 C268.2 C269.2 C270.2 C271.2 C272.2 D1.1 D2.1 D4.1 D6.1 D15.1 D16.2 J1/J3.22 J2.6 J2.10 J2.S1 J2.S2 J2.S3 J2.S4 J2/J4.20 J5.A1 J5.A12 J5.B1 J5.B12 J5/J7.62 J6.7 J6.16 J6.25 J6.34 J6.40 J6.41 J6.42 J6/J8.60 J7.1 J8.1 J11.2 J11.3 J12.2 J12.3 J15.2 J16.2 J17.1 J18.1 J23.3 J23.4 J23.9 J24.5 J25.5 J33.2 Q1.3 Q2.3 Q3.3 Q4.2 Q5.2 Q6.2 Q7.2 Q8.2 Q9.2 Q10.3 Q11.2 Q13.2 R2.1 R6.1 R20.2 R21.1 R22.1 R23.1 R24.1 R25.1 R32.2 R39.1 R44.1 R95.1 R96.1 R97.1 R98.2 R107.1 R120.1 R121.1 R122.1 R123.1 R124.1 R125.1 R126.1 R127.1 R128.1 R148.1 R152.1 R154.1 R160.1 R161.1 R163.1 R202.1 R215.1 R216.1 R217.1 R218.1 R219.1 R220.1 R221.1 R222.1 R223.1 R250.1 R254.2 R255.2 R256.1 R274.1 R275.1 R276.1 R278.1 R289.1 R290.1 R293.1 R294.1 R299.2 R300.1 R304.1 R307.1 R316.2 R321.1 R322.1 R323.1 R360.1 R363.1 R364.1 R391.1 R392.1 R394.1 R397.1 R398.1 R415.2 R419.2 R423.1 R428.1 R437.1 R438.1 R442.1 SW2.1 SW2.3 SW3.1 SW3.3 SW4.1 SW4.3 TP6.1 TP13.1 TP14.1 TP15.1 TP16.1 TP17.1 TP34.1 U1.A1 U1.A18 U1.E5 U1.E6 U1.E7 U1.E8 U1.E10 U1.E12 U1.E13 U1.E14 U1.F5 U1.F6 U1.F7 U1.F8 U1.F10 U1.F12 U1.F13 U1.F14 U1.G7 U1.G8 U1.G9 U1.G10 U1.G11 U1.G12 U1.H5 U1.H6 U1.H7 U1.H8 U1.H9 U1.H10 U1.H11 U1.H12 U1.H13 U1.H14 U1.J5 U1.J6 U1.J7 U1.J8 U1.J9 U1.J10 U1.J11 U1.J12 U1.J13 U1.J14 U1.K7 U1.K8 U1.K9 U1.K10 U1.K11 U1.K12 U1.L5 U1.L6 U1.L7 U1.L8 U1.L9 U1.L10 U1.L11 U1.L12 U1.L13 U1.L14 U1.M5 U1.M6 U1.M7 U1.M8 U1.M9 U1.M10 U1.M11 U1.M12 U1.M13 U1.M14 U1.N7 U1.N8 U1.N9 U1.N10 U1.N11 U1.N12 U1.P5 U1.P6 U1.P8 U1.P10 U1.P12 U1.P13 U1.P14 U1.R5 U1.R12 U1.R13 U1.R14 U1.T2 U1.T8 U1.U4 U1.U5 U1.U9 U1.U12 U1.U13 U1.V1 U1.V3 U1.V4 U1.V8 U1.V9 U1.V16 U1.V18 U2.2 U3.6 U3.17@3348.05,418.7 U4.10 U4.11 U5.3 U6.3 U7.B3 U7.C1 U7.E5 U8.2 U9.3 U10.4 U11.5 U12.3@1835,448.04 U12.8@1835,480.91 U13.3@2180,448.56 U13.8@2180,481.44 U14.3@4825,467.68 U14.8@4825,500.55 U15.3@5035.4,467.82 U15.8@5035.4,500.69 U16.4 U17.3 U18.10 U19.5 U19.9 U20.3@1038.54,453.43 U20.8@1038.54,420.56 U21.3 U22.49 U23.43 U25.5 U26.4 U27.4 U29.4 U29.7 U30.6 U30.11 U31.6 U31.11 U32.4 U32.7 U33.3 U34.2 U35.3 U36.1 U36.5 U36.6 U36.11@2854.71,214.96 U37.49 U38.3@7006.02,788.94 U38.8@6973.14,788.94 U39.3@7005.75,619.6 U39.8@6972.87,619.6 U40.3@7006.02,1738.94 U40.8@6973.14,1738.94 U41.3@7005.75,1609.6 U41.8@6972.87,1609.6 U42.2 U42.9 U43.11 U43.21 U46.3 U47.3 U48.16 U49.8 U50.43 U51.8 U52.43 U53.43 U54.8 U55.3 U55.7@3080.26,1618 U56.5 U57.4 U58.9 U59.5 U60.3 U61.A6 U61.C4 U61.E7 U61.G5 U61.H10 U61.J5 U61.K8 U61.N2 U61.N5 U61.P4 U61.P6 U62.3 U63.9 U63.25 U65.3 Y1.2 Y1.4 Y2.2 Y2.4 Y4.2 Y4.4 | length 20841.5
  Top Layer w5.3: C265.2@2274.78,1529 2296.55,1529 2303.46,1535.9 v1(2306.01,1535.9) ; C264.2@2338.77,1527.95 2358.45,1527.95 2366.4,1535.9 v1(2366.97,1535.9) ; v1(2370.73,519.51) 2370.73,496.04 R394.1@2371.16,495.6
  Top Layer w6: U34.2@665,2146.97 665.03,2173.45 671.3,2179.72 v1(671.3,2182.96)
  Top Layer w7: U18.10@508.07,374.61 508.24,374.78 508.24,404.06 v1(508.42,404.23)
  Top Layer w8: SW2.1@366.76,2153.54 367.46,2154.23 397.7,2154.23 405,2161.53 v1(405,2187.74) ; 2689.81,279 2690.11,279.3 2696.47,279.3 C187.1@2700.34,283.17 2704.22,279.3 2710.6,279.3 2710.87,279.03 2734.47,279.03 2736.27,277.24 C188.2@2749.27,277.24 ; C188.2@2759.34,284 2757.76,285.25 2753.58,288.59 C188.2@2760.42,288.59 2760.42,284 2767.41,277 2789.78,277 2811.47,255.32 2811.47,255.26 2812.39,254.33 U36.1@2817.31,254.33 ; U36.11@2839.09,254.33 U36.11@2840.48,255.72 ; U3.6@3403.17,408.86 3403.9,409.58 3415.71,409.58 3430.61,424.49 3430.61,429.67 v1(3432.52,431.58) ; v1(5854.25,1065.8) v1@5858.68,1065.8 ; U30.6@5854.25,1089.06 5854.97,1088.34 5866.31,1088.34 5871,1083.65 5871,1070
  Top Layer w10: U10.4@321.92,594.53 v1@349.55,594.53 ; v1(414.16,627.73) 416.32,627.73 424.05,620 U11.5@452.76,620 ; v1(775,302.93) U21.3@774.98,335.87 ; U47.3@933.63,568.4 963.4,568.4 v1(981.5,586.5) ; v1(998.27,216.05) J5.B12@998.27,245.67 ; R299.2@1047.12,512.5 1067.87,512.5 1077.28,521.91 v1(1077.28,538.81) ; v1(1238.42,216.05) J5.B1@1238.42,245.67 ; v1(1664.85,633.79) 1664.85,635.95 1668.62,639.73 R98.2@1668.62,663.27 ; U19.9@1676.92,755.91 1676.92,742.13 1689.64,729.41 1699.16,729.41 1700.3,728.27 1707.67,728.27 1709.56,726.38 U19.5@1714.33,726.38 ; v1(1745.55,643.44) 1771.58,669.46 C109.2@1771.58,686.38 ; v1(2344.33,872.28) 2345.86,873.81 2345.86,877.71 2356.36,888.2 U29.7@2356.36,905.26 ; U29.4@2358.33,971.21 2358.33,982.27 2373.01,996.96 2376.89,996.96 v1(2378.42,998.49) ; v1(2787.39,1408.27) 2788.93,1409.8 2795.77,1409.8 2808.03,1422.06 U32.7@2808.03,1432.06 ; U36.1@2817.31,254.33 U36.11@2839.09,254.33 ; v1(3529.07,1396.22) 3530.6,1394.69 3535.23,1394.69 U1.A1@3547.13,1382.8 ; v1(3648.81,585) 3668.06,585 3674.25,578.8 R307.1@3674.25,555 ; v1(3752.57,896.59) 3753.21,896.59 3766.97,910.35 U1.T8@3767.61,910.35 ; v1(3765.46,823.78) 3766.53,824.85 3766.53,846.29 U1.V8@3767.61,847.36 ; v1(3787.57,776.42) 3787.57,777.36 3799.31,789.1 U1.V9@3799.31,847.15 ; U1.V9@3799.1,847.36 U1.U9@3799.1,878.86 ; U1.R12@3893.59,941.85 v1(3909.34,957.6) ; v1(3940.83,957.6) U1.R14@3956.58,941.85 ; U1.A18@4082.57,1382.8 v1(4098.31,1398.54) ; U51.8@4318.06,1522.09 4354.54,1522.09 v1(4387.02,1554.58) ; v1(5465.31,851.27) R289.1@5465.31,887.92 ; U49.8@5652.8,735.66 v1(5695.59,735.66) ; v1(5854.25,1484.99) U31.6@5854.25,1508.25 ; v1(6124.18,545) 6124.18,504.64 6134.15,494.67 C221.2@6165.63,494.67
  Top Layer w11: J5.A1@1000.24,312.6 1000.24,337.35 v1(1001.77,338.88) ; J5.A12@1236.46,312.6 1236.86,313 1236.86,346.53 v1(1237.41,347.08)
  Top Layer w12: C262.2@144.61,1971.27 144.61,2002.52 v1(145.12,2003.03) ; v1(335,312.6) R95.1@372.78,312.6 ; C101.2@389.29,454.11 v1(389.29,493.25) ; R97.1@523.29,487.03 524.23,487.97 557.56,487.97 v1(558.5,488.91) ; SW2.3@587.24,2153.54 600.69,2166.99 620.01,2166.99 623.01,2170 v1(624.64,2170) ; U58.9@609.99,1969.48 609.99,1917.26 623.38,1903.88 635.79,1903.88 643.9,1911.99 643.9,1941.79 635.79,1949.9 v1(635.79,1976.35) ; C181.1@680.93,2065 680.93,2028.16 v1(698.21,2010.88) ; C110.2@740,525.04 v1(777.78,525.04) ; v1@740.56,1993.93 750.57,2003.94 761.11,2003.94 766.92,2009.75 C182.1@766.92,2013.69 ; SW3.1@840.41,2154.18 878.18,2154.18 v1(890,2166) ; v1@852,2096 863.41,2084.59 U33.3@906.29,2084.59 ; v1(1020,2169) 1021.62,2169 1027.05,2163.58 1054.52,2163.58 SW3.3@1063.9,2154.2 ; v1(1048,2112) 1048,2113.62 1051.64,2117.26 1051.64,2141.94 SW3.3@1060.24,2150.54 ; Q2.3@1068.24,2038 1068.24,2062.13 1089.85,2083.73 1089.85,2094.85 v1(1091,2096) ; Q3.3@1163,2036.76 1163,2108.1 1165.05,2110.14 v1(1165.05,2111.77) ; U57.4@1184.51,751.17 1188.57,747.12 1188.57,710.5 1191.75,707.32 v1(1191.75,705.69) ; SW4.1@1266.53,2153.54 1273.84,2160.85 1300.85,2160.85 v1(1302,2162) ; SW4.3@1487,2152 1487.5,2152.5 1523.5,2152.5 v1(1524,2153) ; U27.4@1503.27,1315.27 1536.17,1315.27 v1(1551.63,1330.73) ; U26.4@1503.89,1526.5 1506.61,1523.78 1539.62,1523.78 v1(1540.77,1522.63) ; U25.5@1507.47,1585.47 1552.32,1585.47 1553.94,1583.85 v1(1555.57,1583.85) ; R21.1@1545,1806 1545,1802.07 1550.81,1796.26 1565.44,1796.26 1568.34,1793.36 v1(1569.96,1793.36) ; v1(1719.23,623.55) 1720.38,622.4 1722.1,622.4 1745,599.51 C72.2@1745,595.57 ; v1(1742.92,1590.2) 1742.92,1591.83 1747.56,1596.47 1747.56,1610.76 1753.37,1616.57 R276.1@1757.31,1616.57 ; R274.1@1757.31,1739.85 1760.49,1743.03 1760.49,1770.26 v1(1761.63,1771.41) ; v1(1795.5,637.09) 1795.5,635.47 1803.94,627.02 1803.94,596.63 C73.2@1805,595.57 ; U12.3@1835,448.04 U12.8@1835,480.91 v1(1835,509.48) ; v1(1847.78,1411.32) 1847.78,1430.31 1862.48,1445 U48.16@1902.72,1445 ; C74.2@1865,595.57 v1(1865,629.98) ; C65.1@1915.6,1024.86 1916.08,1025.34 1916.08,1058.05 v1(1916.55,1058.53) ; C75.2@1924,595.57 v1(1924,629.98) ; v1(1930.96,1273.46) 1932.58,1273.46 1938.57,1279.45 U2.2@1967.11,1279.45 ; v1(1960,485.1) D16.2@1984.92,485.1 ; v1(1965.5,771.98) 1966.44,771.04 2016.63,771.04 C64.1@2017.57,770.1 ; v1(1986.81,1082.99) 1997.89,1094.07 R20.2@2027.18,1094.07 ; C97.2@2010,595 2010.45,595.45 2010.45,628.63 v1(2010.89,629.08) ; v1(2015.15,900) 2028.71,886.44 U5.3@2028.71,857.27 ; C81.2@2090,596.09 2090,617.84 2104.14,631.98 2116.65,631.98 v1(2117.8,633.13) ; C82.2@2150,596.09 v1(2150,630.5) ; v1(2151.9,805.52) 2152.43,804.99 2152.43,778.51 U6.3@2152.96,777.98 2153.12,778.14 2177.21,778.14 2185.16,786.09 C63.1@2207.84,786.09 ; U13.3@2180,448.56 U13.8@2180,481.44 v1(2180,510) ; C57.1@2186.02,1279.45 2191.01,1284.43 2213.85,1284.43 v1(2215,1285.58) ; C237.2@2195.94,1407.76 2241.18,1407.76 2255.95,1392.99 2255.95,1392.01 2293.18,1392.01 2297.51,1387.67 v1(2299.14,1387.67) ; C83.2@2210,598.51 v1(2210,630.5) ; R278.1@2232.77,1859.15 2278.4,1859.15 v1(2279.47,1860.22) ; R275.1@2272.16,1759.04 2276.1,1759.04 2299.98,1782.92 v1(2300.31,1782.92) ; v1(2437.41,711.81) 2437.41,711.6 2451.64,697.37 U54.8@2451.64,681.41 ; D4.1@2526.43,2176.81 2550.34,2176.81 2560.06,2167.09 v1(2561.68,2167.09) ; v1(2531.09,117.94) 2532.24,119.09 2543.34,119.09 2558.18,133.94 R304.1@2558.18,137.88 ; v1(2591.72,319.49) C261.2@2591.72,354.8 ; v1(2671.2,456.8) 2671.34,456.94 2671.34,489.85 R398.1@2671.47,489.98 ; R397.1@2671.48,653.56 v1(2671.5,681.41) ; C260.2@2686.21,404.5 2686.21,377.76 2688.99,374.99 v1(2688.99,373.36) ; v1(2713.43,1070.75) 2714.58,1069.61 2719.12,1069.61 U7.C1@2733.91,1054.81 ; U7.B3@2813.29,1093.92 2831.23,1111.86 v1(2831.71,1111.86) ; C185.2@2828.49,386.3 2828.49,353.9 v1(2843.49,338.9) 2844.18,338.21 2844.18,313.96 C186.2@2844.87,313.27 ; D6.1@2836.99,47.06 v1(2836.99,97.25) ; R392.1@2838.84,1934.22 2838.84,1952.04 2858.05,1971.24 2858.31,1970.98 2871.9,1970.98 v1(2873.05,1969.83) ; v1(2856.17,1768.47) 2856.17,1770.1 2859.06,1772.98 Q10.3@2859.06,1814.63 ; v1(2880.51,150.25) 2882.13,150.25 v1@2884.56,152.67 ; U7.E5@2892.03,975.81 v1(2905.22,964.72) ; R391.1@3120.96,1964.83 3122.09,1965.95 3152.42,1965.95 3155.99,1969.52 v1(3157.61,1969.52) ; v1(3280.93,752.16) 3282.08,753.31 3292.04,753.31 3301.99,763.26 Y1.2@3301.99,782.59 ; R23.1@3943.62,169.51 R22.1@3943.62,119.51 3946.02,121.9 3970.24,121.9 3979.12,130.78 v1(3979.12,137.82) ; R25.1@3943.62,269.51 R24.1@3943.62,219.51 3947.56,219.51 3961.94,205.12 3972.02,205.12 v1(3973.16,203.98) ; D15.1@4364.37,466.66 v1(4395.17,466.66) ; v1(4526.3,1367.86) 4526.37,1367.93 R290.1@4558.11,1367.93 ; v1(4720.59,608.97) 4720.69,608.87 4747.01,608.87 C85.2@4747.11,608.78 ; C86.2@4802.11,607.56 v1@4802.11,641.97 ; C86.2@4802.11,608.78 v1(4802.11,643.18) ; U14.3@4825,467.68 U14.8@4825,500.55 v1(4825,527.91) ; C87.2@4857.11,607.56 v1(4857.11,641.97) ; C88.2@4911.11,607.56 v1(4911.11,641.97) ; C92.2@4965,609.62 v1(4965,644.03) ; C93.2@5017.97,608.92 v1(5017.97,643.32) ; v1(5035.24,527.66) 5035.32,527.58 5035.32,500.78 U15.8@5035.4,500.69 U15.3@5035.4,467.82 ; v1(5071.14,640.2) 5072.07,639.27 5072.07,609.85 C94.2@5073,608.92 ; v1(5117.66,647.46) 5118.74,647.46 5128.54,637.65 C95.2@5128.54,608.92 ; R294.1@5525,992.02 5562.09,992.02 v1(5562.51,991.6) ; v1(5694.94,607.56) 5726.52,639.14 U16.4@5760.08,639.14 ; R323.1@5892.56,615 R321.1@5892.56,556.99 5916.9,556.99 v1(5924.91,565) ; v1(5989.5,680.45) 5990.65,681.6 6001.16,681.6 6017.95,698.38 C248.2@6032.6,698.38 ; v1(6054.41,820.59) U46.3@6054.41,859.29 ; v1(6895,335.87) 6919.4,335.87 6940,315.27 C222.2@6940,288.62 ; C226.1@7033.62,60.4 7055.4,60.4 7072.8,77.8 v2(7072.8,99.05) ; v1(7087.71,2028.68) 7102.48,2043.44 C247.1@7102.48,2106.97 ; Q5.2@7361.4,66.42 v1(7400,66.42) ; R255.2@7364.16,2186.97 7371.98,2194.79 v1(7407.45,2194.79)
  Top Layer w13: U1.P12@3893.59,973.35 v1(3909.34,957.6) ; U1.P13@3925.09,973.35 v1(3940.83,957.6) ; U1.P14@3956.58,973.35 v1(3972.33,957.6)
  Top Layer w15: v1(610.92,746.73) 611.03,746.63 C67.2@611.03,704.19 ; U8.2@795.16,678.6 823.99,678.6 830.8,685.41 C69.2@862.1,685.41 880.37,685.41 896.06,701.1 924.7,701.1 C68.2@924.76,701.16 ; R39.1@886.92,754.8 889.27,752.46 905.39,752.46 918.36,739.48 918.36,735.82 v1(918.93,735.24) 918.93,734.43 924.76,728.61 C68.2@924.76,701.16 ; C249.2@888.36,425.41 v1(888.36,465.6) ; v1(965,701.1) 964.95,701.16 C68.2@924.76,701.16 ; U20.8@1038.54,420.56 U20.3@1038.54,453.43 1038.54,475.02 1047.12,483.6 R299.2@1047.12,512.5 ; v1(1596.89,1719.27) 1597.46,1719.85 1610.88,1719.85 1627.39,1736.35 C138.1@1627.39,1753.19 ; J17.1@1618.62,1023.77 1631.5,1036.64 C136.1@1631.5,1117.23 ; C137.1@1630.71,1340 1630.71,1368.41 1639.5,1377.2 1658.08,1377.2 1664.84,1370.45 v1(1665.65,1370.45) ; v1@1676.92,837.99 v1@1678.1,839.17 ; v1(1774.82,1050.69) 1775.01,1050.5 1810.75,1050.5 D2.1@1810.94,1050.3 ; Q13.2@1892.6,97.8 v1(1921.18,97.8) ; C83.2@2207.63,598.51 2210.05,596.09 C84.2@2269,596.09 ; C160.2@2322.84,770.19 2323.13,769.9 2323.13,741.5 v1(2323.42,741.22) ; v1(2378.24,742.85) 2378.24,743.66 2382.33,747.75 R154.1@2382.33,783.06 ; v1(2595.72,909.64) 2595.72,869.86 R148.1@2602.66,862.92 ; v1(2625.2,97.8) 2627.7,95.31 Q11.2@2655.13,95.31 ; R438.1@2667.19,1199.96 2667.19,1314.82 2672.19,1319.82 v1(2672.19,1320.63) ; v1@2672.19,1325.12 2685.11,1338.05 C177.2@2713.6,1338.05 2716.8,1334.84 R437.1@2716.8,1284.43 ; v1(2803.06,1299.58) 2819.16,1315.68 R163.1@2834,1315.68 ; v1(3190.08,472.6) 3190.08,471.79 3191.38,470.49 C60.1@3191.38,418.33 ; v1(3195,830) 3195.16,829.84 Y1.4@3238.01,829.84 ; C48.2@3287.47,609.62 3287.47,586.74 3290.44,583.78 v1(3290.44,582.96) ; R2.1@3337.66,609.62 3368.46,609.62 v1(3369.27,608.82) ; R360.1@3489.29,736.82 3489.29,751.47 v1(3507.82,770) ; v1(3529.08,834.18) 3529.66,834.76 3529.66,837.28 3539.6,847.22 3546.99,847.22 U1.V1@3547.13,847.36 ; v1(3538.64,668.76) 3538.64,667.95 3548.66,657.93 TP34.1@3548.66,637.21 ; v1(3562.88,894.61) U1.T2@3578.63,910.35 ; C91.2@3590,571.38 3590,543.54 v1(3595,538.54) ; U1.V3@3610.13,847.36 3610.27,847.22 3610.27,837.35 3620.8,826.82 v1(3620.8,826) ; v1(3657.37,926.1) U1.R5@3673.12,941.85 ; v1(3657.37,957.6) U1.P5@3673.12,973.35 ; v1(3657.37,1020.59) U1.M5@3673.12,1036.34 ; v1(3657.37,1052.09) U1.L5@3673.12,1067.84 ; v1(3657.37,1146.57) U1.J5@3673.12,1130.83 ; v1(3657.37,1178.07) U1.H5@3673.12,1162.32 ; v1(3657.37,1241.06) U1.F5@3673.12,1225.32 ; v1(3657.37,1272.56) U1.E5@3673.12,1256.81 ; v1(3688.87,957.6) U1.P6@3704.61,973.35 ; v1(3688.87,1020.59) U1.M6@3704.61,1036.34 ; v1(3688.87,1052.09) U1.L6@3704.61,1067.84 ; v1(3688.87,1146.57) U1.J6@3704.61,1130.83 ; v1(3688.87,1178.07) U1.H6@3704.61,1162.32 ; v1(3688.87,1241.06) U1.F6@3704.61,1225.32 ; v1(3688.87,1272.56) U1.E6@3704.61,1256.81 ; v1(3720.36,989.09) U1.N7@3736.11,1004.84 ; v1(3720.36,1020.59) U1.M7@3736.11,1036.34 ; v1(3720.36,1052.09) U1.L7@3736.11,1067.84 ; v1(3720.36,1083.58) U1.K7@3736.11,1099.33 ; v1(3720.36,1178.07) U1.H7@3736.11,1162.32 ; v1(3720.36,1241.06) U1.F7@3736.11,1225.32 ; v1(3720.36,1272.56) U1.E7@3736.11,1256.81 U1.E8@3767.61,1256.81 ; U1.J7@3736.11,1130.83 U1.J8@3767.61,1130.83 v1(3783.35,1146.57) U1.J9@3799.1,1130.83 ; U1.G7@3736.11,1193.82 v1(3751.86,1178.07) ; U1.H7@3739,1163 3739,1164.4 3751.86,1177.26 v1(3751.86,1178.07) ; v1(3751.86,957.6) U1.P8@3767.61,973.35 ; v1(3751.86,989.09) U1.N8@3767.61,1004.84 ; v1(3751.86,1020.59) U1.M8@3767.61,1036.34 ; v1(3751.86,1052.09) U1.L8@3767.61,1067.84 ; v1(3751.86,1083.58) U1.K8@3767.61,1099.33 ; v1(3751.86,1209.57) U1.G8@3767.61,1193.82 3783.79,1210 v1@3784,1210 ; U1.F8@3767.61,1225.32 v1(3783.35,1209.57) U1.G9@3799.1,1193.82 ; v1@3781,1149 3767.68,1162.32 U1.H8@3767.61,1162.32 v1(3751.86,1178.07) ; v1(3783.35,989.09) U1.N9@3799.1,1004.84 ; v1(3783.35,1020.59) U1.M9@3799.1,1036.34 ; v1(3783.35,1052.09) U1.L9@3799.1,1067.84 ; v1(3783.35,1083.58) U1.K9@3799.1,1099.33 ; v1(3783.35,1146.57) U1.H9@3799.1,1162.32 ; U1.P10@3830.6,973.35 v1(3846.35,957.6) ; U1.N10@3830.6,1004.84 v1(3846.35,989.09) ; U1.M10@3830.6,1036.34 v1(3846.35,1020.59) ; U1.L10@3830.6,1067.84 v1(3846.35,1052.09) ; U1.K10@3830.6,1099.33 v1(3846.35,1083.58) ; U1.J10@3830.6,1130.83 v1(3846.35,1146.57) ; U1.H10@3830.6,1162.32 v1(3846.35,1178.07) ; U1.G10@3830.6,1193.82 v1(3846.35,1209.57) 3861,1194.91 U1.G11@3861,1194 ; U1.F10@3830.6,1225.32 v1(3846.35,1241.06) ; v1(3841.4,579.33) 3841.4,558.12 3850.27,549.25 3867.19,549.25 3869.54,546.91 R44.1@3869.54,545.05 ; v1@3846,1244 3843.61,1244 3830.8,1256.81 U1.E10@3830.6,1256.81 v1(3846.35,1272.56) ; U1.N11@3862.09,1004.84 v1(3877.84,989.09) ; U1.M11@3862.09,1036.34 v1(3877.84,1020.59) ; U1.L11@3862.09,1067.84 v1(3877.84,1052.09) ; U1.K11@3862.09,1099.33 v1(3877.84,1083.58) ; U1.J11@3862.09,1130.83 v1(3877.84,1146.57) ; U1.H11@3862.09,1162.32 v1(3877.84,1178.07) ; U1.G11@3862.09,1193.82 v1(3877.84,1209.57) ; U1.U12@3893.59,878.86 v1(3909.34,863.11) ; U1.N12@3893.59,1004.84 v1(3909.34,989.09) ; U1.M12@3893.59,1036.34 v1(3909.34,1020.59) ; U1.L12@3893.59,1067.84 v1(3909.34,1052.09) ; U1.K12@3893.59,1099.33 v1(3909.34,1083.58) ; U1.J12@3893.59,1130.83 v1(3909.34,1146.57) ; U1.H12@3893.59,1162.32 v1(3909.34,1178.07) ; U1.G12@3893.59,1193.82 v1(3909.34,1209.57) ; U1.F12@3893.59,1225.32 v1(3909.34,1241.06) ; U1.E12@3893.59,1256.81 v1(3909.34,1272.56) ; U1.U13@3925.09,878.86 v1(3940.83,863.11) ; U1.R13@3925.09,941.85 v1(3940.83,926.1) ; U1.M13@3925.09,1036.34 v1(3940.83,1020.59) ; U1.L13@3925.09,1067.84 v1(3940.83,1052.09) ; U1.J13@3925.09,1130.83 v1(3940.83,1146.57) ; U1.H13@3925.09,1162.32 v1(3940.83,1178.07) ; U1.F13@3925.09,1225.32 v1(3940.83,1241.06) ; U1.E13@3925.09,1256.81 v1(3940.83,1272.56) ; U1.M14@3956.58,1036.34 v1(3972.33,1020.59) ; U1.L14@3956.58,1067.84 v1(3972.33,1052.09) ; U1.J14@3956.58,1130.83 v1(3972.33,1146.57) ; U1.H14@3956.58,1162.32 v1(3972.33,1178.07) ; U1.F14@3956.58,1225.32 v1(3972.33,1241.06) ; U1.E14@3956.58,1256.81 v1(3972.33,1272.56) ; v1(4019.57,825) U1.V16@4019.57,847.36 ; v1(4082.57,825) U1.V18@4082.57,847.36 ; v1(4310.56,573.56) C96.2@4339.72,573.56 ; v1(4617.41,1497.45) 4617.41,1498.26 4631.56,1512.41 4631.56,1538.48 C241.1@4635.87,1542.79 ; C246.1@4663.62,1702.53 4663.43,1702.34 4663.43,1675.3 v1(4664.01,1674.73) ; C240.1@4670.38,1213.22 4670.5,1213.11 4700.95,1213.11 v1(4701.07,1212.99) ; C245.1@4715,864.8 4716.1,865.9 v1(4745,865.9) 4763.67,865.9 4776.02,853.55 4776.02,828.46 4790.08,814.4 R256.1@4816.77,814.4 ; C111.1@4985.38,992.82 4985.38,969.7 v1(5000,955.08) ; v1(5060,1426.35) C242.1@5060,1451.95 ; C239.1@5339.88,741.15 C239.1@5339.88,741.15 5339.94,717.44 v1(5340,717.37) ; v1@5375.14,1269.35 5375.46,1269.35 5376.11,1268.69 C238.1@5376.11,1233.4 ; v1(5880.69,1035) 5881.5,1035 5885.23,1038.74 R152.1@5914.13,1038.74 ; v1(5880.69,1454.19) 5881.5,1454.19 5885.23,1457.92 R161.1@5914.13,1457.92 ; v1(5968.5,882.8) 5981.65,882.8 5986.5,877.96 R96.1@5986.5,843.62 ; v1(5994.69,941.85) 5998.62,937.91 C43.1@5998.62,914.8 ; C122.2@6210,1035.15 6210,1062.33 6222.15,1074.49 6232.21,1074.49 v1(6232.78,1075.06) ; v1(6240,1382.25) 6240.57,1381.67 6275.94,1381.67 C114.2@6279,1378.61 ; v1(6240,1517.45) 6240.74,1516.71 C191.2@6279,1516.71 ; C199.2@6278.93,1125.48 v1(6278.93,1089.06) 6278.93,1007 C123.1@6280.09,1005.85 ; v1(6300,682.33) 6312.71,695.04 C133.2@6355.51,695.04 ; v1(6300,1632.33) 6312.71,1645.04 C210.2@6355.51,1645.04 ; v1(6313.62,721.81) 6313.62,735 6323.66,745.04 C119.2@6350.51,745.04 ; v1(6313.62,1671.81) 6313.62,1684.62 6324.04,1695.04 C196.2@6355.51,1695.04 ; C200.1@6334,1131.36 6334,1108.26 v1(6344,1098.26) ; C115.1@6344,1366.9 6348.72,1371.62 6374.43,1371.62 v1(6375,1372.2) ; C192.1@6344,1505 6374.83,1505 v1(6375,1505.17) ; TP16.1@6471.65,1308.13 6488.28,1308.13 v1(6517.76,1337.61) ; C132.2@6517.56,695.04 6551.07,695.04 6553.04,693.07 v2(6554.31,693.07) ; C118.2@6517.56,745.04 6552.34,745.04 v2(6554.31,747.01) ; C209.2@6522.56,1645.04 6552.34,1645.04 v2(6554.31,1643.07) ; C195.2@6522.56,1695.04 6552.34,1695.04 v2(6554.31,1697.01) ; C116.2@6556.28,968.7 v1(6556.28,1005) ; C193.2@6556.28,1915.34 6586.92,1915.34 v1(6588.38,1916.8) ; v1(6570.85,431.38) R126.1@6570.85,471.38 ; R221.1@6570.97,1421.26 6570.97,1343.94 v1(6575,1339.91) ; C130.2@6625,644.09 6647.07,644.09 v2(6652.14,649.17) ; C207.2@6625,1594.09 6647.07,1594.09 v2(6652.14,1599.17) ; v2(6652.14,790.91) 6654.11,788.94 C126.2@6731.79,788.94 ; v2(6652.14,1740.91) 6654.11,1738.94 C203.2@6727.79,1738.94 ; v2(6696.04,693.07) 6696.04,680.77 6705.98,670.83 C124.2@6731.79,670.83 ; v2(6696.04,747.01) 6696.94,746.11 6696.94,744.43 6707.17,734.19 6727.48,734.19 C120.2@6731.79,729.88 ; v2(6696.04,1643.07) 6696.04,1630.77 6705.98,1620.83 C201.2@6731.79,1620.83 ; v2(6696.04,1697.01) 6713.17,1679.88 C197.2@6727.79,1679.88 ; v1(7377.27,1235) 7377.27,1206.56 7388.83,1195 R254.2@7430.57,1195
  Top Layer w20: v2(1676.92,777.56) v1@1676.92,837.99 ; R123.1@6848,973.31 v1(6848,1009.61) ; R218.1@6848,1923.31 v1(6848,1959.61) ; v1(7090,1115) C235.1@7152.32,1115
  Bottom Layer w3.4: U61.N2@2454.6,1713.07 2464.43,1722.89 2464.43,1742.38 2461.36,1745.45 ; U61.P4@2474.29,1673.7 2514.92,1673.7 2521.94,1680.71 v1(2523.3,1680.71)
  Bottom Layer w4: 2461.36,1745.45 2461.36,1746.56
  Bottom Layer w5.3: v1(2176.67,1578.48) 2176.67,1592.62 U61.A6@2218.38,1634.33 ; v3(2587.35,583.47) 2587.35,586.12 2594.54,593.32 U63.9@2623.77,593.32
  Bottom Layer w7: v1@3658.2,198.58 U4.10@3658.2,219.28 ; 3673.95,202.09 U4.11@3673.95,219.28
  Bottom Layer w8: U61.C4@2257.75,1673.7 2275.47,1655.98 v1(2275.47,1654.43) ; v1(2426.35,1756.52) 2451.4,1756.52 2461.36,1746.56 ; U61.N5@2454.6,1654.01 U61.P6@2474.29,1634.33 2492.03,1616.58 2510.77,1616.58 v1(2512.68,1614.67) ; C49.2@3477,1372.99 3477,1397 ; v1@3658.2,198.58 v1@3664.32,192.46 ; v1(3664.32,192.41) v1@3664.32,192.46 ; 3673.95,202.09 v1@3664.32,192.46 ; v1(4628.69,1043.6) U17.3@4679.93,1043.6 ; R250.1@6895,307.24 v1(6895,335.87) ; v1(6930,1609.6) U41.8@6972.87,1609.6 U41.3@7005.75,1609.6
  Bottom Layer w10: J6.7@679.88,2053.35 679.88,2018.27 685.74,2012.41 696.68,2012.41 v1(698.21,2010.88) ; v1(852.49,2096.78) 852.49,2094.61 857.05,2090.06 J6.16@857.05,2053.35 ; v1(1208.3,2092) 1208.3,2089.84 1210.47,2087.67 1210.47,2054.25 J6.34@1211.38,2053.35 ; J6.40@1329.49,2053.35 1329.49,2094.14 1338,2102.66 v1(1338,2104) ; v1(1502.48,1764.15) 1502.48,1761.99 1504.02,1760.44 U56.5@1504.02,1723.36 ; v1(2283.46,1611.64) 2284.99,1613.17 2295.65,1613.17 U61.E7@2297.12,1614.64 ; U61.G5@2336.49,1654.01 2336.49,1645.97 2345.81,1636.65 v1(2372.52,1636.65) 2375.86,1639.99 U61.J5@2375.86,1654.01 ; U61.H10@2356.18,1555.59 2356.18,1546.58 2364.88,1537.88 v1@2364.88,1535.99 ; U61.K8@2395.55,1594.96 2400.08,1594.96 2416.56,1611.44 2416.56,1624.66 v1(2417.34,1625.44) ; v1(2714.99,962.66) 2714.99,979.91 2725.83,990.75 U35.3@2764.38,990.75 ; C40.1@3395.84,1120.03 3395.84,1172.31 ; v1@3406.92,1384.68 3410.48,1381.12 3410.48,1367.87 3411.39,1366.97 C42.1@3412.37,1366.97 ; C29.1@3446.46,1121.9 3446.46,1150.31 ; C30.1@3827.99,1273.75 3829.18,1272.56 v1(3846.35,1272.56) ; v1(3940.83,957.6) 3943.24,960.01 3969.92,960.01 v1(3972.33,957.6) ; v1(3940.83,1052.09) 3954.27,1052.09 C47.1@3956.58,1049.77 3958.9,1052.09 v1(3972.33,1052.09) ; R442.1@4805.46,586.3 4805.46,547.44 v1(4825,527.91) ; C211.2@5880,261.5 v1(5880,295) ; C216.2@6000,261.5 v1(6000,295) ; C219.2@6000,511.5 v1(6000,545) ; C218.1@6124.18,511.5 v1(6124.18,545) ; C214.2@6199.18,261.5 v1(6199.18,295) ; C217.2@6199.18,511.5 v1(6199.18,545) ; v1(6893.84,643.12) C125.2@6893.84,670.83 ; C121.2@6893.84,729.88 v1(6930,729.88) ; C127.2@6893.84,788.94 v1(6930,788.94) U38.8@6973.14,788.94 U38.3@7006.02,788.94 ; C202.2@6893.84,1620.83 6905.06,1609.6 v1(6930,1609.6) ; C198.2@6893.84,1679.88 v1(6930,1679.88) ; C204.2@6893.84,1738.94 v1(6930,1738.94) U40.8@6973.14,1738.94 U40.3@7006.02,1738.94 ; v1(6935,621.55) 6937.16,621.55 6939.12,619.6 U39.8@6972.87,619.6 U39.3@7005.75,619.6
  Bottom Layer w11: v1(6696.04,471.38) 6716.56,491.89 6732.43,491.89 C113.1@6733.44,492.9 6773.97,492.9 6774.82,493.75 6808.95,493.75 6813.1,497.91 v1(6815,497.91)
  Bottom Layer w12: v1(279.76,504.25) J2.S2@321.97,504.25 v1(321.97,462.05) ; J2.10@355.43,673.54 v1(355.43,723.39) ; v1(405,2187.74) 406.62,2187.74 413.07,2181.3 J6.42@486.97,2181.3 ; J2.6@479.45,669.61 v1(479.45,719.45) ; v1(480.11,2024.27) 481.26,2023.12 481.26,2010.78 494.99,1997.05 C184.1@498.92,1997.05 C183.1@498.92,1944.88 ; C71.1@611.42,785.43 612.12,786.14 641.08,786.14 v1(641.79,786.84) ; v1(635.79,1976.35) 635.79,1934.68 666.36,1904.12 Q1.3@748.38,1904.12 ; v1(733.18,675) 734.81,675 740.2,669.61 J2.S1@770.79,669.61 770.79,709.21 v1(755,725) ; v1(888.36,465.6) 888.42,465.66 888.42,479.73 914.14,505.45 D1.1@962.64,505.45 ; v1(1016,2104) 1034.21,2085.79 J6.25@1034.21,2053.35 ; v1(1349,2190) 1350.62,2190 1355.27,2185.36 1400.23,2185.36 J6.41@1404.29,2181.3 ; v1(1501.17,1116.71) 1500.02,1115.56 1491.25,1115.56 1481.79,1106.1 1481.79,1093.88 v1(1480.81,1092.9) 1480.81,1025.73 C234.2@1481.54,1025 ; U59.5@1503.89,1490 1506.11,1492.22 1531.96,1492.22 1540.77,1501.03 v1(1540.77,1522.63) ; C252.2@1508.47,1242.98 1539.15,1242.98 1546.55,1235.58 1546.55,1220.23 v1(1547.7,1219.08) ; v1@1541.04,986.12 1519.76,1007.4 1499.14,1007.4 C234.2@1481.54,1025 ; v1(1542.64,1024.9) 1541.02,1024.9 1534.51,1031.4 1487.94,1031.4 C234.2@1481.54,1025 ; R428.1@1633.91,1437.67 1634.06,1437.83 1634.06,1466.95 v1(1634.22,1467.11) ; v1(1810.37,1548.28) 1824.86,1533.78 1824.86,1520.61 1830.67,1514.8 U9.3@1834.48,1514.8 ; U62.3@1834.48,1653.97 1834.48,1683.66 v1(1841.93,1691.11) ; v1(1993,1427.06) 1993,1425.43 1998.44,1420 C70.1@1998.44,1395.84 ; C267.2@2060.15,1577 2060.15,1555.49 2063.84,1551.8 v1(2063.84,1550.18) ; v1(2330.76,637.61) 2332.38,637.61 2337.45,642.68 C269.2@2367.35,642.68 ; C268.2@2365.38,548.03 2370.73,542.68 v1(2370.73,519.51) ; v1(2409.39,463.51) 2410.73,463.51 2415.4,468.17 R423.1@2452.78,468.17 ; v1(2751.85,1190.24) 2751.85,1188.61 2754.67,1185.8 C258.2@2754.67,1141.98 ; C66.2@2800.7,1143.69 2800.7,1185.06 2807.73,1192.09 v1(2823.73,1192.09) ; C259.2@2870.35,804.97 2870.9,805.52 2902.95,805.52 2911.91,814.48 v1(2913.35,814.48) ; v1@3374.31,1381.2 v1(3375.93,1381.2) ; C45.1@3395.84,981.57 3404.81,981.57 3412.02,974.36 ; C21.1@3443.33,1366.97 3443.33,1389.12 3446.24,1392.04 v1(3446.24,1393.66) ; C38.2@3531.39,533.27 v1(3531.39,564.07) ; C61.1@3653.69,58.35 3677.84,58.35 3686.49,67.01 3686.49,71.63 v1(3687.64,72.77) ; C54.2@3654.78,1128.1 3654.78,1143.99 v1(3657.37,1146.57) ; v1(3657.37,1020.59) 3669.78,1020.59 C56.2@3673,1017.37 3676.22,1020.59 v1(3688.87,1020.59) ; v1(3657.37,1178.07) 3659.37,1180.07 3686.86,1180.07 v1(3688.87,1178.07) ; v1(3688.87,1146.57) 3693.17,1142.27 C46.1@3693.17,1128.1 ; C34.2@3760,658.97 v1(3805.01,658.97) C27.2@3851.69,658.97 ; C36.2@3760,708.97 v1(3805.01,708.97) C28.2@3851.69,708.97 ; v1(3805.01,608.97) C26.2@3851.69,608.97 ; C50.2@3814.85,959.09 3844.85,959.09 v1(3846.35,957.6) ; C31.1@3827.84,1239.57 v1@3844.04,1239.57 ; C22.1@3904.97,1115.08 3904.97,1087.95 v1(3909.34,1083.58) ; v1(3909.34,1241.06) 3909.34,1253.99 C51.2@3905.95,1257.37 3905.95,1269.18 v1(3909.34,1272.56) ; v1(3940.83,1178.07) 3942.84,1180.07 3970.33,1180.07 v1(3972.33,1178.07) ; v1(3972.33,1146.57) 3977.01,1141.9 C55.2@3977.01,1115.08 ; C24.2@4124.58,554.26 4124.86,554.54 4153.3,554.54 v1(4153.58,554.83) ; v1(4229.53,1428.16) 4228.94,1427.57 4228.94,1384.37 C4.2@4230.23,1383.08 ; R300.1@4362.13,1652.52 v1(4384.19,1652.52) ; R293.1@4638.88,1215.33 4641.22,1212.99 v1(4701.07,1212.99) 4701.07,1195.96 4674.13,1169.03 4674.13,1159.09 4681.16,1152.06 C100.1@4711.38,1152.06 ; v1(5452.83,116.42) C223.1@5483.66,116.42 ; v1(5560,75) 5578.47,93.47 C224.2@5610.55,93.47 ; R316.2@5593.62,545.04 C99.1@5593.62,487.03 v1(5630,487.03) ; U43.11@5633.19,325.27 v1(5633.19,361.28) ; v2(5821.77,1128.43) 5836.87,1143.54 5853.6,1143.54 C166.1@5854.25,1144.18 ; R322.1@5858.93,611.02 5903.98,611.02 5924.91,590.09 v1(5924.91,565) 5895.93,565 5880,549.07 C212.2@5880,511.5 ; v1(6227.6,770.73) 6227.68,770.81 R120.1@6227.68,802.65 ; v1(6227.6,1720.73) 6227.68,1720.81 R215.1@6227.68,1752.65 ; v1(6227.68,849.04) 6227.76,849.12 R121.1@6227.76,880.96 ; v1(6227.68,1799.04) 6227.76,1799.12 R216.1@6227.76,1830.96 ; v1(6280,1571.55) v1@6280.31,1571.24 ; v1(6300,1632.33) v1@6300.37,1631.97 ; R127.1@6383.01,1086.59 6413.24,1086.59 v1(6413.32,1086.51) ; R222.1@6383.01,2036.59 6413.24,2036.59 v1(6413.32,2036.51) ; R128.1@6443.01,1086.59 6473.24,1086.59 v1(6473.32,1086.51) ; R223.1@6443.01,2036.59 6473.24,2036.59 v1(6473.32,2036.51) ; R125.1@6506.28,1086.67 6536.51,1086.67 v1(6536.59,1086.59) ; R217.1@6506.28,2036.67 6524.09,2036.67 6532.54,2045.12 6532.54,2060.19 6530.42,2062.31 v1(6530.42,2063.93) ; C117.2@6556.28,968.7 v1(6556.28,1005) ; C194.2@6556.28,1918.7 6584.85,1918.7 6586.75,1916.8 v1(6588.38,1916.8) ; v1(6570.85,431.38) 6601.5,400.73 6657.27,400.73 6706.87,351.13 6866.57,351.13 6907.61,392.17 6907.61,479.05 6887.97,498.69 v1(6861.77,498.69) ; v1(6575,1339.91) 6575,1301.78 Y4.2@6576.38,1300.4 ; Y4.4@6623.62,1236.42 6623.81,1236.24 v1(6658.19,1236.24) ; C131.2@6670,471.38 v1(6696.04,471.38) ; C208.2@6670,1421.38 v1(6701.84,1421.38) ; R124.1@6674.39,973.7 v1(6674.39,1010) ; R219.1@6674.39,1923.7 v1(6674.39,1960) ; R122.1@6729.39,973.7 v1(6729.39,1010) ; R220.1@6729.39,1923.7 v1(6729.39,1960) ; C112.1@6730.7,406.51 6732.67,406.51 6734.55,408.39 6734.55,408.47 6741.57,415.5 v1(6758.1,415.5) 6796.23,415.5 Y2.2@6797.61,416.88 ; R107.1@6815,529.75 v1(6815,497.91) 6860.99,497.91 v1(6861.77,498.69) ; v1(6815,1447.91) R202.1@6815,1479.75 ; Y2.4@6861.59,464.12 6861.77,464.31 v1(6861.77,498.69) ; U42.2@7127.91,149.25 7153.38,149.25 7160.27,156.14 v1(7213.78,156.14) ; v1(7285,105) 7285,103.38 7286.6,101.78 Q6.2@7286.6,66.42 ; v1(7310.69,1224.19) 7311.5,1223.38 Q4.2@7311.5,1187.24 ; v1(7377.27,1235) 7396.47,1215.8 Q8.2@7396.47,1093.42 ; Q7.2@7377.4,2212.24 7395.21,2212.24 7406.3,2201.16 7406.3,2195.94 v1(7407.45,2194.79) ; Q9.2@7542.92,1092.15 v1(7542.92,1140)
  Bottom Layer w13: C20.1@3445.84,981.57 3445.84,959.07 v1(3446.77,958.15)
  Bottom Layer w15: v1(321.97,201.12) J2.S3@321.97,118.43 378.36,118.43 379.19,119.25 v1(380,119.25) ; C272.2@2667.72,1083.52 2667.72,1082.97 2672.03,1078.66 2704.72,1078.66 2712.62,1070.75 v1(2713.43,1070.75) ; v1(2831.71,1111.86) 2832.29,1112.44 2832.29,1114.36 2842,1124.08 2858.12,1124.08 2862.44,1128.39 C271.2@2862.44,1132.32 ; v1(3193.21,952.93) 3194.03,952.93 3197.67,949.29 C2.2@3262.14,949.29 ; C1.2@3338.57,949.29 3338.57,910.13 3340.56,908.15 v1(3340.56,907.34) ; 3395.84,1172.31 v1(3408.05,1184.51) 3396.24,1196.32 C44.1@3396.24,1221.06 ; v1(3444.28,1183.99) 3444.86,1183.42 3444.86,1151.91 3446.46,1150.31 ; v1@3444.86,1183.87 3444.86,1214.68 3446.24,1216.07 C32.1@3446.24,1221.33 ; v1(3538.64,668.76) 3553.63,683.75 C15.2@3553.63,720.13 C7.2@3603.63,720.13 ; v1(3581.64,1531.16) 3582.03,1531.55 C6.2@3619.13,1531.55 ; C257.2@3593.49,851 3597.42,851 3613.48,834.94 3613.48,834.43 3619.3,828.61 3619.3,828.32 3620.23,827.39 v1@3620.23,826.58 ; v1(3595,538.54) C90.2@3595,571.29 ; C16.2@3688.87,1523.53 3688.87,1545.59 3693.8,1550.52 v1(3693.8,1551.34) ; C62.1@3713.69,58.35 3733,58.35 3747.75,73.1 3747.75,82.8 v1(3748.33,83.37) ; C10.2@3756.08,1523.53 v1(3790,1523.53) ; J23.9@3804.17,1950 3827.68,1973.5 C213.2@3890,1973.5 ; C11.2@3831.66,1523.53 3831.66,1548.36 3834.29,1550.99 v1(3834.29,1551.8) ; v1@3844.04,1239.57 3845.53,1241.06 v1(3846.35,1241.06) ; C5.2@3896.57,1532.99 3940.63,1532.99 v1(3940.74,1532.88) ; C12.2@4100.67,1521.84 v1(4133.42,1521.84) ; C18.2@4209.8,1254.06 v1(4242.55,1254.06) ; C13.2@4209.8,1317.07 v1(4242.33,1317.07) ; C17.2@4214.47,1013.32 4214.64,1013.16 4243.69,1013.16 4252.48,1004.37 4252.48,962.79 4243.47,953.78 v1(4243.47,952.97) C8.2@4215.8,952.97 ; C9.2@4217.29,890 v1(4250.04,890) ; C243.1@4495.23,601.69 4521.34,601.69 4532.15,590.89 4532.15,581.48 4534.49,579.14 v2(4534.49,577.87) ; v2(4595.51,577.87) 4609.31,564.07 C244.1@4635,564.07 ; v2(5799.13,1585.02) 5832.59,1585.02 5851.9,1565.71 5851.9,1563.74 5852.28,1563.37 C178.1@5854.25,1563.37 ; C215.1@6124.18,260.51 6198.19,260.51 C214.2@6199.18,261.5 ; v1@6280.31,1571.24 C205.2@6319.86,1571.24 ; v1(6286.36,621.24) C128.2@6319.86,621.24 ; v1(6300,682.33) 6300.37,681.97 C129.1@6331.89,681.97 ; v1@6300.37,1631.97 C206.1@6336.81,1631.97 ; C220.2@6523.66,290.82 6614.35,290.82 6654.17,250.99 J33.2@6654.17,183.86 ; v1(6560.13,2004.17) 6560.95,2004.17 6567.35,1997.77 6584.9,1997.77 6589.21,1993.46 C263.2@6589.21,1989.52 ; v1(6664.61,2171.09) U60.3@6664.61,2212.95 ; v1(6721.89,1304.51) 6722.7,1304.51 6724.08,1305.89 C270.2@6753.73,1305.89 ; U65.3@6969.94,1219.85 7010.15,1219.85 v1(7013.89,1216.11)
  Bottom Layer w20: C89.2@3015,691.5 3023.7,700.2 3023.7,739.93 v1(3025.51,741.74) ; C35.2@4139.44,693.51 4139.44,596.22 v1(4144.81,590.85)
  other v1: 655,50.5 655,100.5 608.25,102 2831.99,148.76 605,178.5 2816.4,325.88 2764.97,328.47 2790.18,328.33 2745.17,328.82 1342.41,363.08 1273.41,370.08 1314.41,379.08 2033.93,473.43 1745.98,490.87 3835.26,504.32 4415,512.52 3793.42,521.68 348.98,594.35 1673.48,700.51 1264.13,706.3 1327.12,706.3 3450,776.33 1679.96,840.73 3484.5,872.02 3492.53,918.09 1541.04,985.16 5777.2,1040 5827.2,1040 2219.21,1070 2265,1070 2219.21,1120 2265,1120 2215,1184.9 2265,1184.9 2315,1220 2215,1223.95 2265,1223.95 2954.63,1230.24 5775,1235 5825,1235 5875,1250 5590,1252.62 5743.28,1253.72 5376.36,1270.08 6080,1275 2915.01,1287.34 5590,1302.62 5640,1302.62 5690,1302.62 5740,1302.62 5953.33,1332.62 6003.33,1332.62 6053.33,1332.62 6103.33,1332.62 3402.06,1386.18 3298.88,1438.86 5777.2,1459.19 5827.2,1459.19 2810,1527.63 2783.08,1528.94 2945.36,1592.43 2975.95,1592.43 5775,1654.19 5825,1654.19 5875,1669.19 5590,1686.81 5740,1690 5903.33,1701.81 3110.01,1703.91 2668.05,1707.4 2696.84,1707.11 2723.75,1707.4 5590,1731.81 5640,1731.81 5690,1731.81 5740,1731.81 6101.09,1749.57 5903.33,1751.81 5953.33,1751.81 6003.33,1751.81 6051.44,1751.81 6897,1990 740.54,1993.93 7041,2004 6038,2024 7040.71,2053.68 6706,2166 7139.57,2174.59 7099.71,2182.68 6020,2233 4903,2238.3 5106,2238.3 5451,2238.3
  other v2: 7050.16,136.46 7095.43,136.46 7072.8,173.86 2854.71,177.56 5603.66,190.43 2854.71,214.96 5573.15,240.62 5634.17,240.62 2854.71,252.37 5603.66,290.82 3329.35,400 3366.75,400 3329.35,437.4 3366.75,437.4 4565,531.81 4565,577.87 4534.49,623.94 4565,623.94 4595.51,623.94 6598.21,649.17 4534.49,670 4565,670 4595.51,670 6598.21,693.07 6652.14,693.07 4534.49,716.06 4565,716.06 4595.51,716.06 1676.92,734.25 6598.21,747.01 6652.14,747.01 4534.49,762.13 4565,762.13 4595.51,762.13 6598.21,790.91 4565,808.19 5238.39,881.85 5207.87,927.91 5238.39,927.91 5268.9,927.91 5207.87,973.97 5238.39,973.97 5268.9,973.97 5207.87,1020.04 5238.39,1020.04 5268.9,1020.04 5207.87,1066.1 5238.39,1066.1 5268.9,1066.1 5799.13,1091.03 5207.87,1112.16 5238.39,1112.16 5268.9,1112.16 5776.49,1128.43 5238.39,1158.22 5799.13,1165.84 4827.2,1318.31 4796.69,1364.37 4827.2,1364.37 4857.72,1364.37 4796.69,1410.44 4827.2,1410.44 4857.72,1410.44 4796.69,1456.5 4827.2,1456.5 4857.72,1456.5 4796.69,1502.56 4827.2,1502.56 4857.72,1502.56 5799.13,1510.22 5776.49,1547.62 5821.77,1547.62 4796.69,1548.62 4827.2,1548.62 4857.72,1548.62 4827.2,1594.69 6598.21,1599.17 6598.21,1643.07 6652.14,1643.07 6598.21,1697.01 6652.14,1697.01 6598.21,1740.91
  other v3: 2548.96,545.09 2510.58,583.47 2548.96,583.47 2548.96,621.86 3080.26,1596.35 3080.26,1639.66 2767.66,2060.52 2813.73,2060.52 2859.79,2060.52 2905.85,2060.52 2951.92,2060.52 2721.6,2091.04 2767.66,2091.04 2813.73,2091.04 2859.79,2091.04 2905.85,2091.04 2951.92,2091.04 2997.98,2091.04 2767.66,2121.55 2813.73,2121.55 2859.79,2121.55 2905.85,2121.55 2951.92,2121.55
GND_XDS: C134.1 C135.2 C139.1 C140.1 C141.1 C142.2 C143.2 C144.2 C145.1 C146.1 C147.1 C148.1 C149.1 C150.1 C151.1 C152.2 C153.1 C154.1 C155.1 C156.1 C227.2 C230.1 C231.2 C232.1 C233.1 C234.1 C250.2 C251.2 D3.1 DS3.1 J34.5 R137.1 R145.1 R252.1 R253.2 R261.2 R308.2 R309.2 R310.2 R416.2 R427.2 TP24.1 TP26.1 U24.10 U24.17 U24.48 U24.55 U24.58 U24.64 U24.66 U24.80 U24.114 U25.4 U26.5 U27.5 U28.2 U44.3@271.44,1060.81 U44.8@238.56,1060.81 U45.6 U45.9@468.69,998.32 U56.4 U58.8 U59.4 Y3.2 Y3.4 | length 3363.2
  Top Layer w8: J34.5@161.81,1095.26 208.68,1095.26 v1(208.94,1095) v1@210,1095
  Top Layer w12: v1@97.31,1490.28 115.08,1508.05 DS3.1@115.08,1551.98 D3.1@178.23,1551.98 ; U44.8@238.56,1060.81 U44.3@271.44,1060.81 272.22,1061.59 289.96,1061.59 304.98,1076.61 325.28,1076.61 v1(345.24,1056.66) ; U28.2@304.1,1363.89 v1(304.1,1401.55) ; v1(306.14,1473.29) 306.61,1473.76 306.61,1505.79 C250.2@307.09,1506.27 ; C231.2@352.83,985.89 352.83,1011.2 366.63,1025 v1(395,1025) ; v1(424.78,1505.36) 424.93,1505.51 456.73,1505.51 C150.1@456.88,1505.66 ; v1(441.26,1170) 459.73,1188.47 C145.1@471.69,1188.47 ; U45.9@468.69,998.32 481.48,1011.12 U45.6@481.48,1053.44 ; v1(545,976.17) 554.72,985.89 C233.1@577.56,985.89 ; v1(603.99,1688.07) 603.99,1686.45 610.25,1680.18 U58.8@610.25,1603.6 ; C232.1@660,1055.9 691.53,1055.9 719.77,1084.14 733.96,1084.14 v1(734.23,1083.87) 734.23,1082.25 740.38,1076.1 C155.1@740.38,1044.84 ; v1(691.97,1274.26) R252.1@691.97,1240.79 692.81,1239.95 755.19,1239.95 TP26.1@756.03,1239.11 ; TP24.1@748.48,1160.35 v1(748.48,1193.83) ; C147.1@787.63,997.6 789.2,996.03 789.2,968.8 v1(790.35,967.65) ; C148.1@848.81,1533.69 848.81,1556.98 855.06,1563.22 v1(855.06,1564.85) ; v1(965,1579.87) R261.2@965,1630.31 ; v1(1016.99,1579.87) R308.2@1016.99,1630.31 ; v1(1052.43,1330.87) 1062.66,1341.1 C149.1@1098.65,1341.1 ; v1(1095.89,1603.83) R309.2@1095.89,1630.31 ; C156.1@1120.75,1270 1144.96,1270 1151.37,1263.59 v1(1152.99,1263.59) ; C153.1@1128.62,1221.57 1129.04,1221.99 1157.48,1221.99 v1(1157.9,1222.41) ; v1(1142.79,1169.59) 1143.93,1168.44 1166.24,1168.44 C139.1@1169.42,1165.27 ; v1(1145.93,1358.38) 1147.08,1359.62 1147.08,1361.59 1155.96,1370.47 1170.03,1370.47 C140.1@1176.4,1376.84 ; v1(1170.52,1706.78) C141.1@1170.52,1733.64 ; R310.2@1206.46,1656.39 1208.06,1654.79 1208.06,1630.82 v1(1209.21,1629.67) ; v1(1236.65,1299.95) 1238.28,1299.95 1253.6,1315.27 U27.5@1286.73,1315.27 ; v4(1243.67,1600.47) 1258.67,1585.47 U25.4@1290.47,1585.47 ; v1(1248.81,1551) 1249.96,1549.86 1249.96,1548.14 1271.61,1526.5 U26.5@1287.35,1526.5 ; v1(1273.74,1102.71) 1274.85,1101.6 1274.85,1070.76 R416.2@1275.96,1069.65
  Bottom Layer w7: v1@444.89,1332.24 U24.17@492.35,1332.24 ; U24.10@492.35,1222.01 v1@539.81,1222.01 ; 771.88,986.12 U24.114@771.88,1021.22 ; U24.48@787.63,1627.52 787.63,1661.88 ; v1(897.86,1590.29) U24.55@897.86,1627.52 ; 945.11,1585.01 U24.58@945.11,1627.52 ; v1(1052.43,1330.87) 1053.64,1332.08 1098.48,1332.08 U24.80@1098.65,1332.24 ; v1(1057.51,1548.71) 1060.48,1548.71 1064.48,1552.72 U24.66@1098.65,1552.72
  Bottom Layer w8: v1(444.7,1332.06) v1@444.89,1332.24 ; v1@539.81,1222.01 545,1227.2 v1(545,1228.07) ; 771.88,986.12 v1(790.35,967.65) ; 787.63,1661.88 787.63,1694.06 v1(789.53,1695.97) ; 945.11,1585.01 950.25,1579.87 v1(965,1579.87) ; U24.64@1039.59,1627.52 1039.59,1593.96 1046.34,1587.22 1058.23,1587.22 1074.84,1603.83 v1(1095.89,1603.83)
  Bottom Layer w12: v1(325,1160.27) C135.2@325,1124.08 348.12,1124.08 350.65,1121.55 370.98,1121.55 R137.1@371.47,1121.06 ; C151.1@360.82,1249.29 390.07,1249.29 394.99,1244.37 C152.2@415.82,1244.37 ; v1(393.98,991.38) 393.98,926.52 374.15,906.68 C227.2@325,906.68 325,989.45 360.55,1025 v1(395,1025) ; C152.2@416.45,1245 v1@416.45,1279.37 ; C154.1@798.6,941.85 824.39,941.85 833.02,933.22 v1(834.64,933.22) ; R145.1@892.1,1713.62 892.1,1698.15 898.65,1691.6 v1(898.65,1689.97) ; v1(950.25,969.22) 951.4,968.07 962.78,968.07 970.06,960.79 C146.1@970.06,942.52 ; v1(1142.79,1169.59) 1142.79,1134.55 1149.82,1127.52 C143.2@1193.21,1127.52 ; v1(1145.08,1458.6) 1145.48,1458.6 1164.52,1439.56 R427.2@1168.46,1439.56 ; v1(1147.7,1398.2) 1149.33,1398.2 1156.11,1391.41 C251.2@1197.04,1391.41 ; v1(1152.99,1263.59) 1154.58,1263.59 1163.02,1272.03 C144.2@1193.07,1272.03 ; C142.2@1214.98,1554.93 1244.89,1554.93 v1(1248.81,1551) ; v1(1228.73,938.98) 1228.93,939.17 1228.93,974.03 C134.1@1229.12,974.22 ; v1(1236.65,1299.95) 1237.8,1298.8 1247.85,1298.8 1255.64,1291.01 Y3.4@1255.64,1247.63 ; U59.4@1286.89,1490 v1(1340,1490) ; U56.4@1291.42,1723.36 1337.77,1723.36 v1(1338.71,1724.3) ; v1(1307.46,1094.67) 1307.46,1093.05 1316.18,1084.33 C234.1@1316.18,1025 1309.67,1018.49 v1(1309.67,948.4) ; Y3.2@1318.63,1161.01 1318.63,1126.37 v1(1335,1110)
  other v1: 415.82,1280 97.5,1439.98 147.5,1439.98 97.5,1489.98 147.5,1489.98
  other v2: 468.69,975.68 431.29,998.32 506.09,998.32 468.69,1020.96
INT1_PB: Q3.2 R181.1 SW4.2 SW4.4 U34.3 | length 1099.8
  Top Layer w4: v1(642,2206) 642,2190.16 651.21,2180.95 U34.3@651.22,2146.97
  Top Layer w5.3: Q3.2@1125.6,2135.24 1125.6,2160.4 1130,2164.8 R181.1@1130,2189.38 1158.08,2189.38 1160.8,2192.1 v1(1193.78,2192.1) 1222.14,2220.46 SW4.2@1266.53,2220.46 1301.65,2220.46 1311.43,2210.69 1442.01,2210.69 1450.25,2218.93 1485.46,2218.93 SW4.4@1487,2220.46
  SIG 1 w4.75: v1(642,2206) 675.49,2206 696.64,2184.85 735.75,2184.85 768.28,2152.32 864.95,2152.32 880.17,2137.1 1138.77,2137.1 v1(1193.78,2192.1)
IO_ADDR: R422.1 R423.2 U63.18 | length 86.3
  Bottom Layer w8: U63.18@2499.75,508.67 2499.75,468.45 R423.2@2500.03,468.17
  Bottom Layer w15: R423.2@2500.03,468.17 2500.03,427.27 R422.1@2503.41,423.89
IO_INT: R426.1 U63.22 | length 62.3
  Bottom Layer w8: R426.1@2412.62,595.1 2440.11,595.1 2441.89,593.32 U63.22@2474.16,593.32
LED_A0: R271.2 R274.2 U48.9 | length 166.8
  Top Layer w5.3: R274.2@1804.55,1739.85 R271.2@1804.55,1804.54 1840.19,1804.54 1849.73,1795 U48.9@1902.72,1795
LED_A1: R270.2 R276.2 U48.10 | length 197.4
  Top Layer w5.3: R276.2@1804.55,1616.57 1804.55,1695.18 1854.37,1745 U48.10@1902.72,1745
LED_A2: R269.2 R275.2 U48.7 | length 161.7
  Top Layer w5.3: U48.7@2117.28,1745 2117.49,1745.2 2169.96,1745.2 2183.79,1759.04 R275.2@2224.92,1759.04 R269.2@2224.92,1807.28
LED_ANODE0: D7.2 R262.1 | length 58.1
  Top Layer w5.3: R262.1@2367.5,2231 2368.5,2230 2386.37,2230 2396.17,2239.8 D7.2@2421.16,2239.8
LED_ANODE1: D8.2 R263.1 | length 58.6
  Top Layer w5.3: R263.1@2257.41,2231 2277.4,2231 2286.21,2239.8 D8.2@2312.35,2239.8
LED_ANODE2: D9.2 R264.1 | length 61.8
  Top Layer w5.3: R264.1@2142.37,2231 2167.26,2231 2176.07,2239.8 D9.2@2200.52,2239.8
LED_ANODE3: D10.2 R266.1 | length 59.2
  Top Layer w5.3: R266.1@2033.08,2231 2057.73,2231 2066.54,2239.8 D10.2@2088.59,2239.8
LED_ANODE4: D11.2 R267.1 | length 58.8
  Top Layer w5.3: R267.1@1925,2231 1944.04,2231 1952.85,2239.8 D11.2@1980.11,2239.8
LED_ANODE5: D12.2 R273.1 | length 67
  Top Layer w5.3: R273.1@1807.38,2231 1829.84,2231 1838.65,2239.8 D12.2@1870.7,2239.8
LED_ANODE6: D13.2 R277.1 | length 60.2
  Top Layer w5.3: R277.1@1696.59,2231 1697.65,2232.05 1713.25,2232.05 1721,2239.8 D13.2@1753.16,2239.8
LED_ANODE7: D14.2 R279.1 | length 62.2
  Top Layer w5.3: R279.1@1583.17,2232.12 1604.79,2232.12 1612.47,2239.8 D14.2@1642.17,2239.8
LED_DRAIN0: D7.1 U48.3 | length 853.2
  Top Layer w5.3: U48.3@2117.28,1545 2143.18,1545 2153.97,1545 2173.73,1525.24 2207.84,1525.24 2251.99,1569.39 2251.99,1607.78 2279.52,1635.31 2289.01,1635.31 2370.11,1716.4 2370.11,1833.15 2370.11,1906.42 2359.32,1917.21 2359.32,2093.71 2421.16,2155.55 D7.1@2421.16,2176.81
LED_DRAIN1: D8.1 U48.4 | length 780.8
  Top Layer w5.3: U48.4@2117.28,1595 2164.94,1595 2176.53,1606.59 2231.08,1606.59 2255.95,1631.45 2255.95,1662.52 2267.38,1673.96 2300.31,1673.96 2359.51,1733.15 2359.51,1902.03 2348.72,1912.82 2348.72,2119.64 2312.35,2156.01 D8.1@2312.35,2176.81
LED_DRAIN2: D9.1 U48.5 | length 764.1
  Top Layer w5.3: U48.5@2117.28,1645 2177.3,1645 2193.59,1661.29 2239.72,1661.29 2268.09,1689.66 2289.74,1689.66 2348.91,1748.82 2348.91,1833.15 2348.91,1847.23 2301,1895.14 2258.97,1937.17 2258.97,2082.01 2200.52,2140.46 D9.1@2200.52,2176.81
LED_DRAIN3: D10.1 U48.6 | length 842
  Top Layer w5.3: D10.1@2088.59,2176.81 2088.59,2128.02 2099,2117.61 2208.38,2117.61 2248.37,2077.62 2248.37,1932.78 2296.6,1884.54 2338.31,1842.84 2338.31,1753.21 2285.35,1700.26 2250.83,1700.26 2243.91,1707.18 2204.59,1707.18 2192.41,1695 U48.6@2117.28,1695
LED_DRAIN4: D11.1 U48.11 | length 531.7
  Top Layer w5.3: U48.11@1902.72,1695 1933.18,1695 1941.31,1703.13 1941.31,1886.63 1953.64,1898.96 1953.64,2092.52 1980.11,2118.99 D11.1@1980.11,2176.81
LED_DRAIN5: D12.1 U48.12 | length 897.8
  Top Layer w5.3: D12.1@1870.7,2176.81 1870.7,2091.81 1850.57,2071.68 1850.57,1930.3 1823.9,1903.62 1811.08,1903.62 1731.51,1824.05 1731.51,1698.75 1715.8,1683.04 1715.8,1586.8 1734.8,1567.8 1799.73,1567.8 1845.23,1613.3 1845.23,1629.2 1861.03,1645 U48.12@1902.72,1645
LED_DRAIN6: D13.1 U48.13 | length 887.2
  Top Layer w5.3: D13.1@1753.16,2176.81 1753.16,1902.54 1719.74,1869.12 1719.74,1701.97 1703.28,1685.51 1703.28,1576.61 1756.29,1523.59 1813.29,1523.59 1842.41,1552.71 1842.41,1578.94 1858.47,1595 U48.13@1902.72,1595
LED_DRAIN7: D14.1 U48.14 | length 890.4
  Top Layer w5.3: D14.1@1642.17,2176.81 1642.17,2104.55 1653.12,2093.6 1653.12,1900.74 1708,1845.86 1708,1705.22 1692.68,1689.9 1692.68,1564.83 1744.51,1512.99 1826.85,1512.99 1858.85,1545 U48.14@1902.72,1545
MDIO_CLOCK: U17.10 U22.42 U37.42 | length 3395.2
  SIG 1 w4.75: v1(4904.79,994.9) 4963.87,935.83 5007.97,935.83 5013.01,940.86 5170.43,940.86 5187.78,958.21 5187.78,1177.47 5243.35,1233.04 5472.76,1233.04 5572.54,1332.83 5866.41,1332.83 5979.23,1220 6461.19,1220 v1(6512.27,1168.92) 6566.85,1114.35 6610.77,1114.35 6631.01,1134.59 6631.01,1479.02 6610,1500.03 6610,1565.56 6628.35,1583.91 6628.35,1753.39 6615.77,1765.97 6615.77,1831.8 v1(6615.49,1832.08)
  Bottom Layer w5.3: U17.10@4855.28,1004.38 4895.34,1004.38 v1(4904.79,994.9) ; v1(6512.27,1168.92) 6514.79,1168.92 6521.73,1175.85 6622.5,1175.85 6639.52,1158.82 6639.52,1001.91 6624.42,986.81 6624.42,881.65 6615.33,872.57 U22.42@6615.33,853.9 ; U37.42@6615.33,1803.9 v1@6615.33,1831.92
MDIO_DATA: U17.6 U22.41 U37.41 | length 3001.5
  SIG 1 w4.75: v1(4906.98,1100.33) 4922.4,1089.58 5049.06,1089.58 5078.8,1059.84 5120,1059.84 5155,1094.84 5155,1166.39 5231.71,1243.09 5468.59,1243.09 5568.38,1342.88 5870.57,1342.88 5983.39,1230.05 6494.27,1230.05 v1(6574.53,1149.79) 6591.66,1149.79 6605.92,1164.06 6605.92,1431.3 6578.11,1459.11 6578.11,1760.77 v1(6595.65,1778.31)
  Bottom Layer w5.3: U17.6@4855.28,1083.12 4903.87,1083.12 4906.98,1086.22 v1(4906.98,1100.33) ; v1(6574.53,1149.79) 6574.53,1027.86 6609.52,992.86 6609.52,886.91 6595.65,873.04 U22.41@6595.65,853.9 ; v1(6595.65,1778.31) U37.41@6595.65,1803.9
NetC222_1: C222.1 R246.1 R247.1 | length 238.7
  Top Layer w5.3: v1(6921.84,201.12) 6940,219.27 C222.1@6940,241.38
  SIG 1 w5.3: v1(6921.84,72.38) v1(6921.84,201.12)
  Bottom Layer w5.3: v1(6921.84,72.38) 6922.14,72.09 R246.1@6952.8,72.09 ; v1(6921.84,201.12) 6922.14,200.83 R247.1@6952.8,200.83
NetC257_1: C257.1 R189.1 R190.1 U1.N3 | length 234.1
  Top Layer w5.3: v1(3594.38,989.09) U1.N3@3610.13,1004.84
  Top Layer w15: R190.1@3535,736.82 R189.1@3586.2,736.82 3586.2,738.78 3588.54,741.13 3617.5,741.13 3648.19,771.82 v1(3648.19,796.75)
  Bottom Layer w15: C257.1@3640.19,850.46 3641.99,850.46 3645.76,846.69 3645.76,826.66 3648.19,824.23 v1(3648.19,796.75)
NetC266_1: C266.1 U61.C2 | length 497.7
  Bottom Layer w3.4: 2249.26,1757.01 2247.89,1755.65 2247.89,1722.93 U61.C2@2257.75,1713.07
  Bottom Layer w5.3: 2249.14,1757.13 2253.98,1761.97 2319.33,1761.97 2414.7,1857.34 2541.86,1857.34 2560.4,1838.8 2578.96,1820.24 C266.1@2641.33,1820.24
NetD2_2: D2.2 R257.1 | length 130.1
  Top Layer w5.3: D2.2@1810.94,987.31 1837.57,987.31 1853.71,971.16 R257.1@1853.71,890.52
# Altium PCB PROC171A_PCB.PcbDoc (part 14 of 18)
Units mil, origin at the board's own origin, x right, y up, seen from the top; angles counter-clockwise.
Board outline 7700 x 2300 mil, 6 copper layers (Top Layer, GND 1, SIG 1, SIG 2, GND 2, Bottom Layer), stack 61.062 mil thick; 945 components, 692 nets, 11945 pads, 1734 vias.

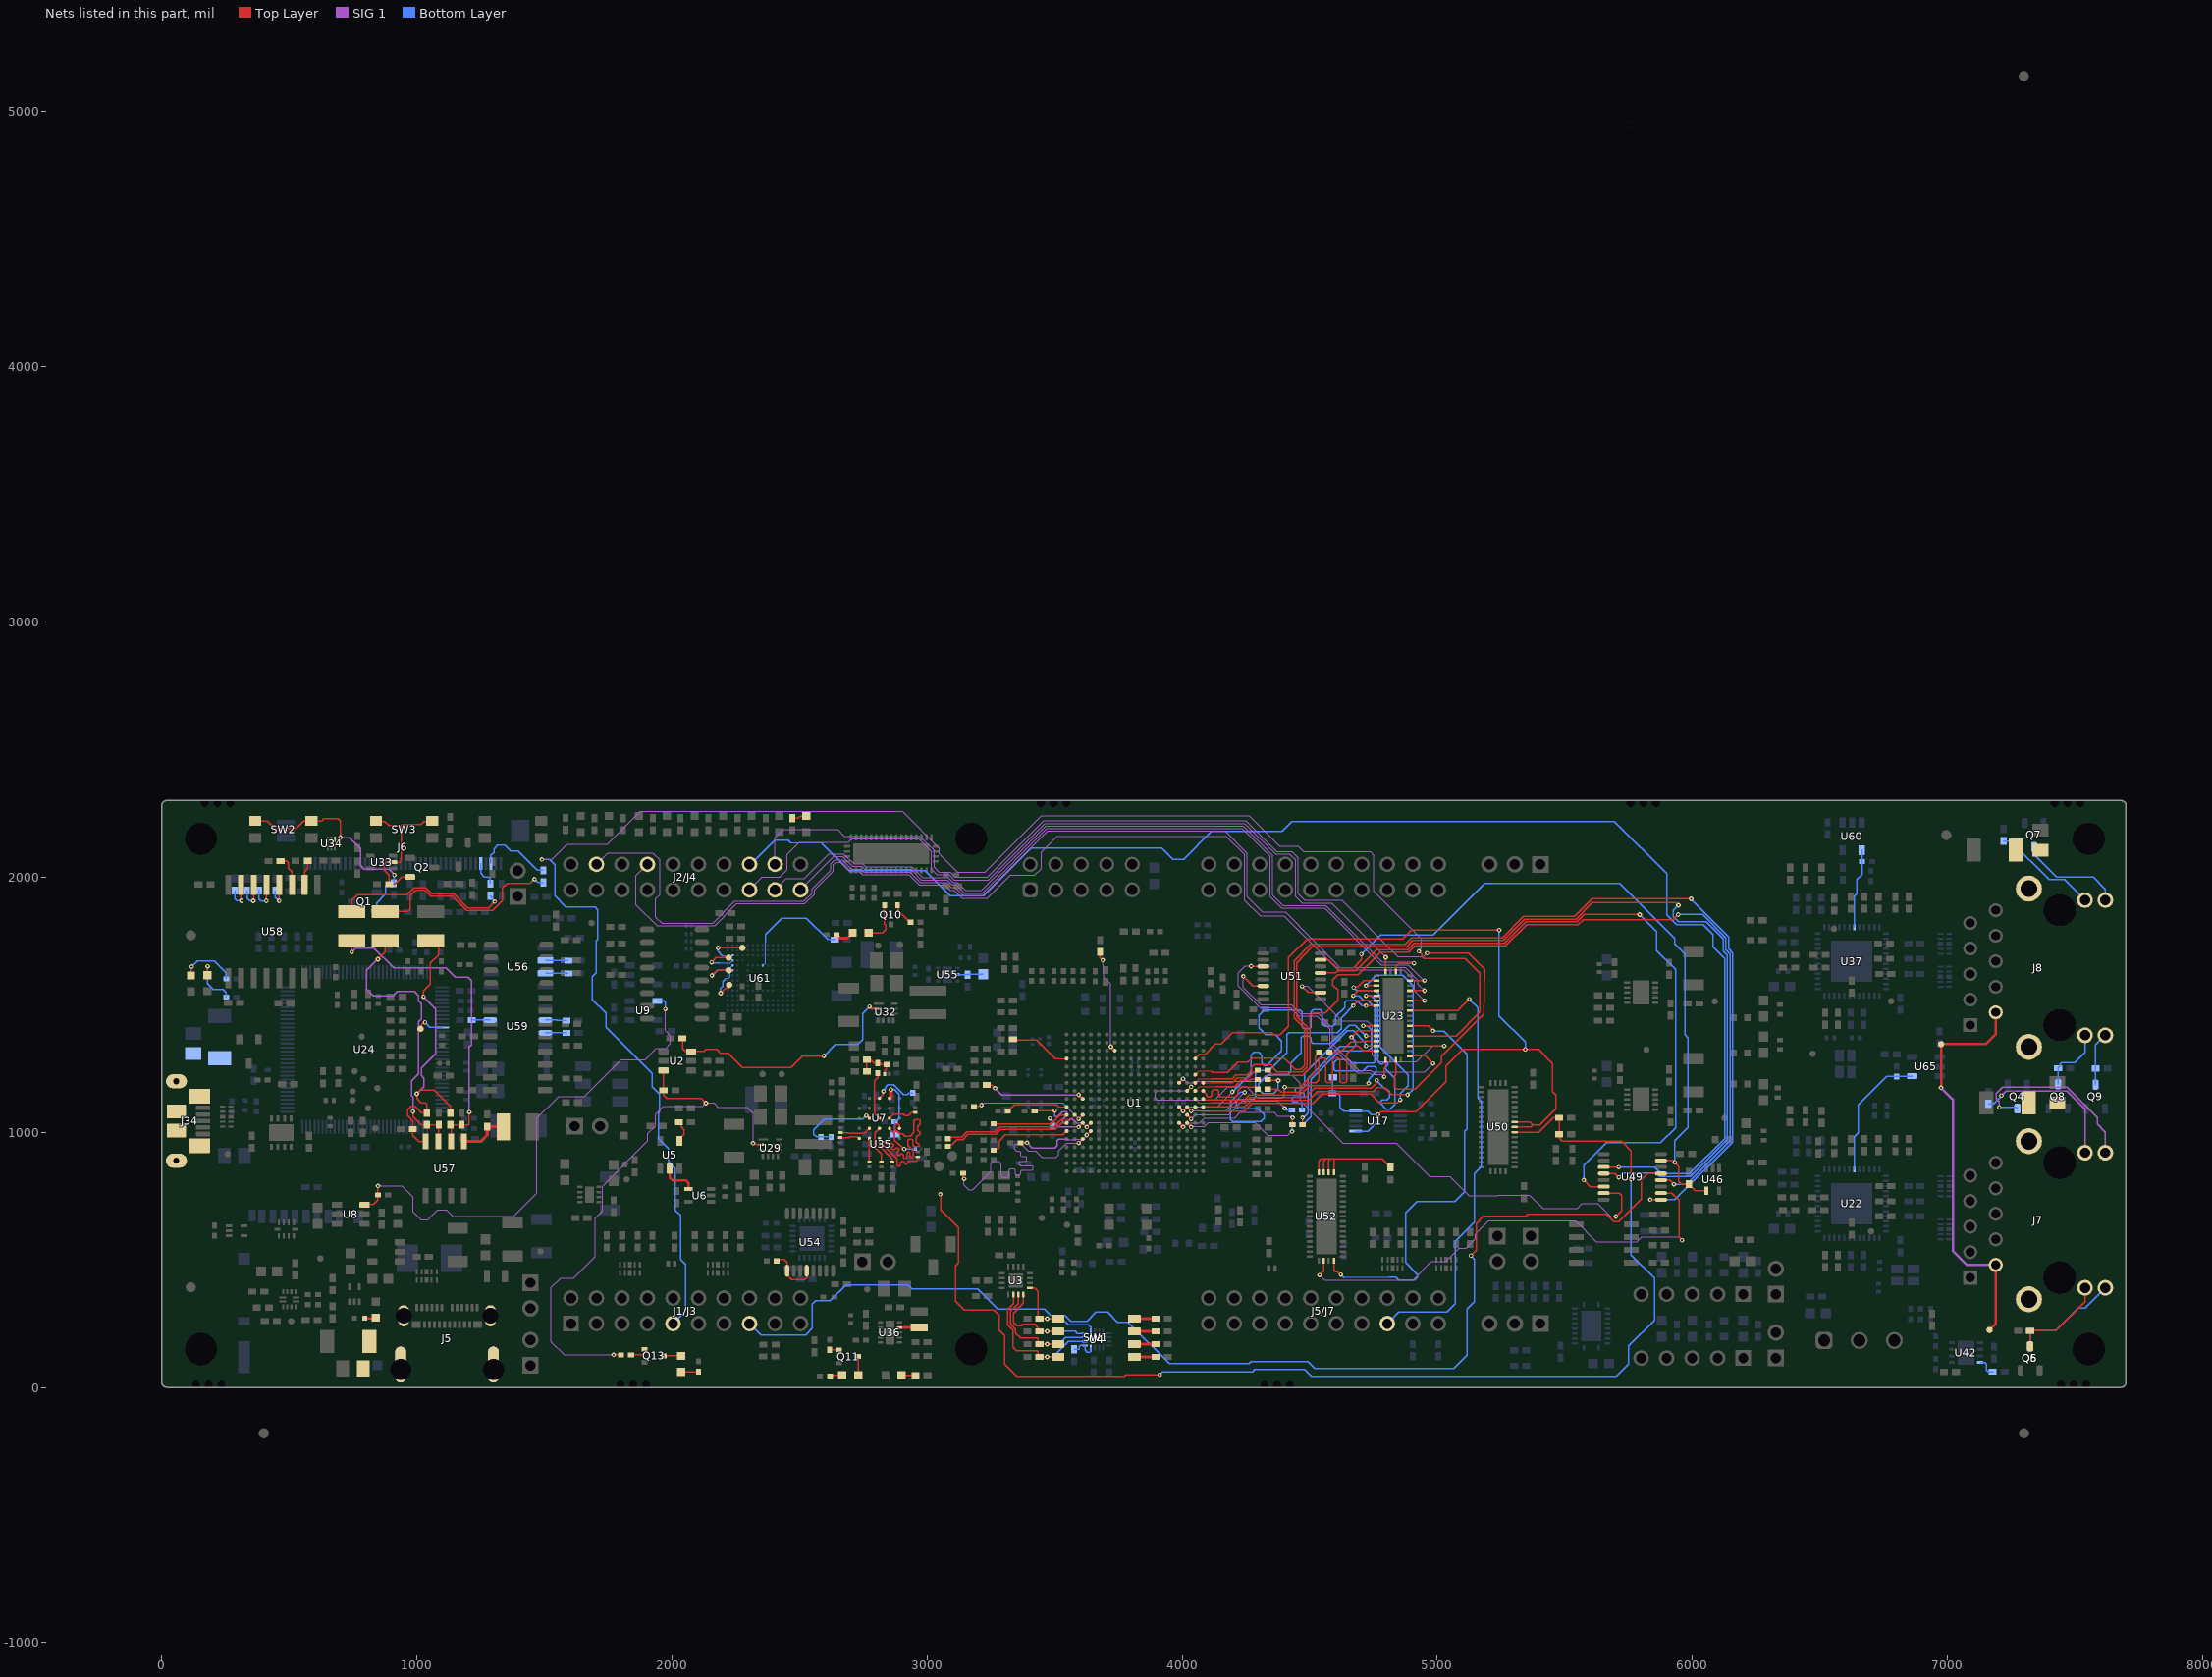
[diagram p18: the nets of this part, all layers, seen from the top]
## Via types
v1: diameter 18, hole 8, Top Layer to Bottom Layer, tented both sides, 1603 vias
v2: diameter 19.68, hole 7.87, Top Layer to Bottom Layer, tented both sides, 104 vias
v3: diameter 19.68, hole 7.87, Top Layer to Bottom Layer, 24 vias
v4: diameter 18, hole 8, Top Layer to Bottom Layer, 3 vias

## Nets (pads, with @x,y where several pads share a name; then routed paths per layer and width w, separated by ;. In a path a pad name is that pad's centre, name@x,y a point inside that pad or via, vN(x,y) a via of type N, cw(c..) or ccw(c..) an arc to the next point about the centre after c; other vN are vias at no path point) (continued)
NetD3_2: D3.2 R259.1 | length 209.3
  Top Layer w5.3: D3.2@178.78,1615.52 179.85,1616.59 v1(179.85,1650.66)
  Bottom Layer w5.3: v1(179.85,1650.66) 179.85,1581.92 201.82,1559.94 240.7,1559.94 252.92,1547.73 R259.1@252.92,1530
NetD4_2: D4.2 R313.1 | length 58.7
  Top Layer w5.3: R313.1@2471.37,2231 2494.33,2231 2503.13,2239.8 D4.2@2526.43,2239.8
NetD5_1: D5.1 Q13.3 | length 68.9
  Top Layer w5.3: Q13.3@1967.4,123.39 D5.1@2036.27,123.39
NetD5_2: D5.2 R314.1 | length 68
  Top Layer w5.3: D5.2@2036.27,60.4 2101.71,60.4 R314.1@2103.52,62.21
NetD6_2: D6.2 R315.1 | length 55
  Top Layer w5.3: D6.2@2899.99,47.06 2900.24,47.31 R315.1@2954.87,47.31
NetDS1_1: DS1.1 Q10.2 | length 169.1
  Top Layer w5.3: DS1.1@2770.91,1781.37 2824.91,1781.37 2837.72,1794.18 2837.72,1810.86 2833.47,1815.12 Q10.2@2833.47,1889.43
NetDS1_2: DS1.2 R265.1 | length 76.4
  Top Layer w12: R265.1@2645.6,1774.32 2647.57,1774.32 2661.07,1760.82 2687.37,1760.82 DS1.2@2707.92,1781.37
NetDS2_1: DS2.1 Q11.3 | length 73.1
  Top Layer w5.3: Q11.3@2729.93,120.9 2729.93,48.41 DS2.1@2730.37,47.97
NetDS2_2: DS2.2 R302.1 | length 49.3
  Top Layer w5.3: R302.1@2619.3,45 2622.27,47.97 DS2.2@2667.38,47.97
NetDS3_2: DS3.2 R260.1 | length 224.4
  Top Layer w5.3: DS3.2@115.08,1614.97 115.08,1646.45 v1@118.65,1650.03
  Bottom Layer w5.3: v1(117.38,1649.19) 139.6,1671.41 206.46,1671.41 252.92,1624.95 R260.1@252.92,1601.11
NetDS4_2: DS4.2 R434.1 | length 43.2
  Top Layer w10: R434.1@796.23,270.76 836.78,270.76 DS4.2@838.68,272.66
NetJ6_36: J6.36 R355.2 | length 104.3
  Bottom Layer w5.3: J6.36@1250.75,2053.35 1250.75,2014.96 1264.74,2000.97 1282.05,2000.97 1287.75,1995.27 1287.75,1975.03 R355.2@1288.1,1974.68
NetJ6_38: J6.38 R357.2 | length 303.1
  Bottom Layer w5.3: J6.38@1290.12,2053.35 1290.12,2084.87 1301.96,2096.72 1301.96,2110.9 1316.06,2125 1344.61,2125 1368.1,2101.52 1396.54,2101.52 1471.43,2026.62 R357.2@1496,2026.62
NetL4_1: L4.1 U36.9 | length 58.3
  Top Layer w10: U36.9@2892.11,234.65 2943.72,234.65 L4.1@2948.45,239.38
NetQ10_1: Q10.1 R272.2 | length 88.2
  Top Layer w5.3: Q10.1@2884.65,1889.43 2887.02,1887.06 2887.02,1869.67 2933.35,1823.35 R272.2@2935.31,1823.35
NetQ11_1: Q11.1 R303.2 | length 37.9
  Top Layer w5.3: R303.2@2617.63,147.36 2618.5,146.49 Q11.1@2655.13,146.49
NetQ13_1: Q13.1 R317.2 | length 70.3
  Top Layer w5.3: R317.2@1839.67,127.49 1885.59,127.49 1892.6,134.5 Q13.1@1892.6,148.98
NetR8_2: R8.2 U4.4 U4.5 | length 114.7
  Bottom Layer w5.3: R8.2@3576.64,148.9 3594.32,148.9 3597.42,152.01 3597.42,159.85 3601.73,164.16 U4.5@3618.83,164.16 3618.83,146.31 3627.93,137.2 3637.86,137.2 3642.45,141.79 U4.4@3642.45,156.28
NetR22_2: R22.2 SW1.1 | length 84.4
  Top Layer w12: SW1.1@3812.01,119.51 R22.2@3896.38,119.51
NetR23_2: R23.2 SW1.2 | length 84.4
  Top Layer w12: SW1.2@3812.01,169.51 R23.2@3896.38,169.51
NetR24_2: R24.2 SW1.3 | length 84.4
  Top Layer w12: SW1.3@3812.01,219.51 R24.2@3896.38,219.51
NetR25_2: R25.2 SW1.4 | length 84.4
  Top Layer w12: SW1.4@3812.01,269.51 R25.2@3896.38,269.51
NetR165_2: R165.2 U1.M3 | length 178.3
  Top Layer w5.3: v1(3594.38,1020.59) U1.M3@3610.13,1036.34
  SIG 1 w5.3: v1(3481.61,1054.11) 3515.13,1020.59 v1(3594.38,1020.59)
  Bottom Layer w5.3: v1(3481.61,1054.11) 3481.61,1053.87 3490.83,1044.65 3490.83,1030.45 R165.2@3492.19,1029.09
NetR167_2: R167.2 U1.L1 | length 302.3
  Top Layer w5.3: R167.2@3260.59,1034.08 3262.76,1031.91 3487.02,1031.91 3515.64,1060.52 3522.95,1067.84 U1.L1@3547.13,1067.84
NetR168_2: R168.2 U1.K1 | length 242.4
  Top Layer w4: 3515.64,1099.42 3547.05,1099.42 U1.K1@3547.13,1099.33
  Top Layer w5.3: R168.2@3317.18,1083.59 3319.15,1083.59 3342.09,1106.53 3508.44,1106.53 3515.55,1099.42 3515.64,1099.42
NetR249_2: R249.2 U42.4 | length 81.8
  Bottom Layer w5.3: U42.4@7127.91,98.07 7147.67,98.07 7153.38,92.36 7153.38,68.08 7160,61.46 R249.2@7180.31,61.46
NetR256_2: R256.2 U52.18 U52.19 U52.20 U52.21 | length 504.7
  Top Layer w5.3: U52.21@4535.47,843.23 4535.47,885.47 4545.28,895.28 4565,895.28 ; U52.20@4555.16,843.23 4555.16,885.44 4565,895.28 ; U52.19@4574.84,843.23 4574.84,888.3 4581.82,895.28 ; U52.18@4594.53,843.23 4594.53,895.28 ; R256.2@4816.77,861.65 4783.14,895.28 4594.53,895.28 ; 4565,895.28 4581.82,895.28 ; 4581.82,895.28 4594.53,895.28
NetR342_1: R342.1 U58.15 | length 123.7
  Top Layer w5.3: U58.15@310.43,1969.57 310.43,1908.57 v1(312,1907)
  Bottom Layer w5.3: R342.1@287,1947.38 287,1915.29 295.29,1907 v1(312,1907)
NetR343_1: R343.1 U58.14 | length 124.6
  Top Layer w5.3: v1(359,1907) 360.25,1905.75 U58.14@360.25,1969.74
  Bottom Layer w5.3: R343.1@334.13,1947.37 334.13,1917.87 345,1907 v1(359,1907)
NetR344_1: R344.1 U58.13 | length 125.3
  Top Layer w5.3: v1@410.25,1907.25 U58.13@410.25,1969.74
  Bottom Layer w5.3: R344.1@381.31,1947.65 381.31,1913.69 389,1906 v1@407,1906
  other v1: 410,1907
NetR345_1: R345.1 U58.12 | length 111
  Top Layer w5.3: U58.12@460.25,1969.74 v1(460.25,1906.75) v1@461,1906
  Bottom Layer w5.3: R345.1@445,1947.38 445,1922 v1(460.25,1906.75)
NetR349_1: R349.1 U58.11 | length 124.9
  Top Layer w5.3: R349.1@466,2063 489.74,2063 496.35,2056.39 496.35,2035.22 510.51,2021.06 U58.11@510.51,1970.49
NetR353_1: R353.1 U58.10 | length 99.1
  Top Layer w5.3: U58.10@560.25,1969.74 560.25,2021.11 572,2032.86 R353.1@572,2064
NetR359_1: R359.1 U59.7 | length 82.7
  Bottom Layer w5.3: U59.7@1503.89,1390 R359.1@1586.63,1390
NetR362_1: R362.1 R363.2 U55.2 | length 102.1
  Bottom Layer w5.3: U55.2@3118.68,1617.97 3158.86,1617.97 R363.2@3159.18,1617.65 3160.81,1619.28 R362.1@3220.04,1619.32
NetR377_2: R377.2 U1.N1 | length 332.9
  Top Layer w5.3: R377.2@3260.59,929.6 3265.73,934.74 3277.24,934.74 3282.45,939.94 3282.45,965.9 3306.05,989.51 3515.64,989.51 3531.8,989.51 U1.N1@3547.13,1004.84
NetR378_2: R378.2 U1.N4 | length 326.5
  Top Layer w5.3: R378.2@3366.16,958.84 v1(3391.73,958.83) ; v1(3625.87,989.09) 3627.77,989.09 3641.62,1002.95 U1.N4@3641.62,1004.84
  SIG 1 w4: 3556.48,970.8 3582.97,970.8 3584.78,972.6 3611.27,972.6 3625.87,987.2 v1(3625.87,989.09)
  SIG 1 w5.3: v1(3391.73,958.83) 3411.94,938.62 3491,938.62 3499.95,938.62 3509.35,948.02 3509.35,967.43 3514.79,972.86 3546.91,972.86 3548.98,970.8 3556.48,970.8
NetR379_2: R379.2 U1.M4 | length 348.2
  Top Layer w5.3: R379.2@3415.53,1083.59 R379.2@3421.62,1083.62 3497.17,1083.62 v1@3498.06,1084.5 ; v1@3498.06,1084.68 v1(3500.62,1084.68) ; v1(3625.87,1020.59) U1.M4@3641.62,1036.34
  SIG 1 w4: 3586.18,1035.59 3610.87,1035.59 v1(3625.87,1020.59)
  SIG 1 w5.3: v1(3500.62,1084.68) 3500.62,1064.93 3503.72,1061.82 3511.26,1061.82 3530.85,1081.41 3543.79,1081.41 3547.95,1077.25 3547.95,1066.47 3530.45,1048.97 3530.45,1041.29 3538.21,1033.53 3543.39,1033.53 3561.61,1051.75 3570.02,1051.75 3584.7,1037.07 3586.18,1035.59
NetR380_2: R380.2 U1.P3 | length 1040.9
  Top Layer w5.3: R380.2@3140.83,838.71 3140.83,825.06 3145.01,820.88 v1(3145.01,817.45) ; v1(3594.38,957.6) U1.P3@3610.13,973.35
  SIG 1 w4: 3546.86,957.6 v1(3594.38,957.6)
  SIG 1 w4.75: v1(3145.01,817.45) 3145.01,794.47 3164.47,775.01 3179.66,775.01 3249.46,844.82 3249.46,877.71 3257.49,885.74 3280.43,885.74 3291.38,874.79 3291.38,826.69 3294.84,823.24 3316.37,823.24 3321.97,828.84 3321.97,851.68 3327.83,857.55 3341.45,857.55 3346.92,852.08 3346.92,836.72 3350.58,833.06 3364.26,833.06 3364.48,833.28 3367.04,835.85 3367.04,847.84 3370.59,851.39 3412.44,851.39 3415.99,854.94 3415.99,865.59 3412.44,869.14 3365.88,869.14 3362.33,872.69 3362.33,883.34 3365.88,886.89 3386.62,886.89 3390.17,890.44 3390.17,901.09 3386.62,904.64 3370.59,904.64 3367.04,908.19 3367.04,910.57 3367.04,921.09 3361.55,926.59 3349.39,926.59 3342.22,933.77 3342.22,947.05 3349.15,953.98 3368.87,953.98 3395.67,927.18 3424.51,927.18 3450.87,900.82 3506.02,900.82 3516.64,911.43 3516.64,927.37 3546.86,957.6
NetR393_2: R393.2 U1.J3 | length 398.6
  Top Layer w5.3: R393.2@3233.83,1184.7 3234.77,1183.76 3254.05,1183.76 3265.45,1172.36 v1(3266.28,1172.36)
  Top Layer w10: v1(3594.38,1146.58) U1.J3@3610.13,1130.83
  SIG 1 w5: v1(3266.28,1172.36) 3292.07,1146.58 v1(3594.38,1146.58)
NetR394_2: R394.2 U54.9 U54.12 | length 208.6
  Top Layer w5.3: R394.2@2410.52,501.44 2440.5,501.44 2451.64,490.31 U54.9@2451.64,457 2451.64,441.25 2469.56,423.33 2521.51,423.33 2528.41,430.22 U54.12@2528.41,457
NetR401_2: R401.2 U1.C7 | length 411.3
  Top Layer w5.3: R401.2@3678.01,1706.38 3678.01,1685.26 v1(3688.64,1674.63)
  Top Layer w10: v1(3720.36,1335.55) U1.C7@3736.11,1319.8
  SIG 1 w4.75: v1(3688.64,1674.63) 3687.54,1674.63 3686.15,1673.24 3691.8,1609.1 3693.19,1607.71 3720.36,1580.54 v1(3720.36,1335.55)
NetR402_2: R402.2 U1.L3 | length 464.1
  Top Layer w5.3: R402.2@3184.32,1100.9 3185.48,1102.05 3205.1,1102.05 3209.8,1106.75 v1(3213.23,1106.75) ; v1(3594.38,1052.09) U1.L3@3610.13,1067.84
  SIG 1 w4.75: v1(3213.23,1106.75) 3214.59,1106.75 3222.64,1114.8 3491,1114.8 3531.66,1114.8 3556.79,1089.67 v1(3594.38,1052.09)
NetR403_2: R403.2 U1.M1 | length 502.7
  Top Layer w5.3: R403.2@3082.47,944.62 3089.01,951.16 3098.22,951.16 3117.51,970.45 3139.8,970.45 3160.61,991.26 3269.76,991.26 3289.21,1010.7 3502.16,1010.7 3515.64,1024.19 3527.79,1036.34 U1.M1@3547.13,1036.34
NetR404_2: R404.2 U1.L2 | length 534.7
  Top Layer w4: 3537.53,1052.09 3562.88,1052.09 U1.L2@3578.63,1067.84
  Top Layer w5.3: R404.2@3082.47,974.88 3088.64,981.05 3135.41,981.05 3156.64,1002.28 3265.79,1002.28 3284.82,1021.3 3497.77,1021.3 3515.64,1039.18 3528.55,1052.09 3537.53,1052.09
NetR405_1: R405.1 R406.1 R407.2 R408.2 U57.8 | length 1249.3
  Top Layer w5.3: v1(1026.05,1531.2) 1026.05,1553.4 1052.73,1580.07 1052.73,1662.86 1085.04,1695.17 1085.04,1727.55 1062.1,1750.49 R406.1@1054.16,1750.49 ; U57.8@1034.51,963.77 1008.25,963.77 984.16,987.86 R405.1@984.16,1011.75 984.16,1045.27 964.95,1064.48 964.95,1088.93 976.75,1100.72 992.92,1100.72 1017.44,1076.19 R408.2@1039.15,1076.19 1039.15,1108.53 1032.63,1115.05 1016.49,1115.05 999.85,1131.69 v1(999.85,1150.84) 1014.08,1165.07 1068.66,1165.07 1131.33,1102.4 R407.2@1131.33,1076.19
  SIG 1 w5.3: v1(999.85,1150.84) 1028.06,1179.05 1028.06,1212.27 1018.28,1222.05 1018.28,1251.98 1074.7,1308.4 1074.7,1482.55 v1(1026.05,1531.2)
NetR407_1: R407.1 R412.1 R414.1 U57.6 | length 1279.9
  Top Layer w5.3: v1(745.15,1706.15) 745.15,1750.25 R412.1@745.39,1750.49 ; U57.6@1134.51,963.77 1134.51,1025.77 R407.1@1131.33,1028.95 R414.1@1174.89,1028.95 1201.32,1028.95 1205.5,1033.13 v1(1205.5,1078.98)
  SIG 1 w5.3: v1(745.15,1706.15) 760.84,1721.84 831.48,1721.84 909.35,1643.97 1114.77,1643.97 1150.04,1608.7 1200.21,1608.7 1213.8,1595.11 1213.8,1342.91 1205.5,1334.61 v1(1205.5,1078.98)
NetR408_1: R408.1 R410.1 R413.1 U57.7 | length 1122.1
  Top Layer w5.3: v1(847.55,1678.16) 875.14,1705.75 R410.1@875.14,1750.49 ; v1(984.83,1081.19) 984.83,1061.83 1017.71,1028.95 R408.1@1039.15,1028.95 R413.1@1085.82,1028.95 1084.51,1027.65 U57.7@1084.51,963.77
  SIG 1 w5.3: v1(847.55,1678.16) 803.37,1633.98 803.37,1562.05 830.36,1535.07 906.82,1535.07 923.1,1551.34 990.75,1551.34 1006.53,1535.56 1006.53,1516.06 1017.84,1504.74 1017.84,1444.4 1005.85,1432.41 1005.85,1355.96 1006.12,1355.69 1006.12,1228.3 980.32,1202.51 980.32,1142.95 984.48,1138.8 984.48,1081.55 v1(984.83,1081.19)
NetR409_1: R409.1 U56.7 | length 90
  Bottom Layer w5.3: U56.7@1504.02,1623.36 1593.16,1623.36 R409.1@1593.78,1622.73
NetR411_1: R411.1 U56.6 | length 90.4
  Bottom Layer w5.3: U56.6@1504.02,1673.36 1504.54,1672.84 R411.1@1594.25,1672.84
NetR415_1: R415.1 R416.1 U57.5 | length 199.1
  Top Layer w12: U57.5@1184.51,963.77 1250.92,963.77 1275.96,988.81 R416.1@1275.96,1022.41 1337.63,1022.41 R415.1@1339.03,1021.01
NetR419_1: R419.1 U61.H5 | length 458.6
  Bottom Layer w3.4: U61.H5@2356.18,1654.01 2366.01,1663.84 2366.01,1746.56
  Bottom Layer w5.3: 2366.01,1746.56 2366.01,1774.99 2429.91,1838.89 2526.88,1838.89 2526.97,1838.8 2610.76,1755.01 R419.1@2638.32,1755.01
NetR427_1: R427.1 U59.3 | length 71.4
  Bottom Layer w5.3: R427.1@1215.7,1439.56 1216.14,1440 U59.3@1286.89,1440
NetR428_2: R428.2 U59.6 | length 83.7
  Bottom Layer w5.3: U59.6@1503.89,1440 1547.21,1440 1549.54,1437.67 R428.2@1586.66,1437.67
NetR433_2: R433.2 U1.D1 | length 242.2
  Top Layer w4: 3515.64,1288.31 U1.D1@3547.13,1288.31
  Top Layer w5.3: R433.2@3336.43,1364.34 3339.71,1361.06 3429.27,1361.06 3491,1299.33 3502.02,1288.31 3515.64,1288.31
NetR440_1: R440.1 U7.C3 | length 190.6
  Top Layer w5.3: R440.1@2807.13,1231.42 2807.13,1215.67 2793.59,1202.13 2793.59,1074.25 U7.C3@2813.29,1054.55
NetR443_1: R443.1 U7.A3 | length 183.3
  Top Layer w5.3: U7.A3@2813.29,1133.73 2813.72,1133.73 2826.95,1146.95 2826.95,1158.01 v1(2829.38,1160.44)
  Bottom Layer w5.3: v1(2829.38,1160.44) 2829.38,1163.88 2838.4,1172.89 2838.4,1179.15 2845.76,1186.51 2869.55,1186.51 2907.85,1148.21 2924.02,1148.21 2929.57,1153.76 R443.1@2944.38,1153.76
NetR444_1: R444.1 R445.1 U7.C2 | length 336.1
  Top Layer w5.3: v1(2762.3,1065.44) 2762.66,1065.44 2773.55,1054.55 U7.C2@2773.92,1054.55
  Bottom Layer w5.3: R444.1@2624.41,981.57 2566.85,981.57 2555.68,992.73 2555.68,1009.61 2597.3,1051.23 2748.09,1051.23 v1(2762.3,1065.44)
NetTP31_1: TP31.1 U24.75 | length 109.6
  Top Layer w5.3: TP31.1@1014.53,1405.29 1018.3,1409.06 1018.3,1420.62 1028.41,1430.74 v1(1031.79,1430.74)
  Bottom Layer w5.3: v1(1031.79,1430.74) 1051.54,1410.98 U24.75@1098.65,1410.98
NetTP35_1: TP35.1 U61.B3 | length 181.3
  Top Layer w5.3: v1(2180.49,1722.55) 2228.58,1722.55 2228.84,1722.81 TP35.1@2276.01,1722.81
  Bottom Layer w3.4: 2196.29,1693.38 2204.63,1693.38 2208.56,1689.45 2208.56,1689.31 2214.31,1683.56 2228.24,1683.56 U61.B3@2238.07,1693.38
  Bottom Layer w5.3: v1(2180.49,1722.55) 2180.49,1709.18 2196.29,1693.38
NetTP36_1: TP36.1 U61.B4 | length 162.9
  Top Layer w5.3: v1(2155.31,1665.99) 2173.16,1683.84 TP36.1@2223.1,1683.84
  Bottom Layer w3.4: 2186.57,1664.16 2214.03,1664.16 2214.31,1663.87 2228.24,1663.87 U61.B4@2238.07,1673.7
  Bottom Layer w5.3: v1(2155.31,1665.99) 2157.15,1664.16 2186.57,1664.16
NetTP37_1: TP37.1 U61.B5 | length 172.3
  Top Layer w5.3: v1(2156.62,1614.76) 2157.09,1614.76 2176.6,1634.27 TP37.1@2223.1,1634.27
  Bottom Layer w3.4: 2204.33,1634.27 2214.25,1644.19 2228.24,1644.19 U61.B5@2238.07,1654.01
  Bottom Layer w5.3: v1(2156.62,1614.76) 2159.74,1614.76 2179.25,1634.27 2204.33,1634.27
NetTP38_1: TP38.1 U61.B6 | length 161.4
  Top Layer w5.3: v1(2190.84,1545.39) 2191.4,1545.39 2223.62,1577.6 TP38.1@2224.18,1577.6
  Bottom Layer w3.4: 2209.63,1600.53 2213.89,1604.78 2222.41,1604.78 2228.11,1610.48 2228.2,1610.57 2228.2,1618.71 2228.11,1618.8 2228.11,1624.38 U61.B6@2238.07,1634.33
  Bottom Layer w4: 2209.17,1600.99 2210.09,1600.99
  Bottom Layer w5.3: v1(2190.84,1545.39) 2190.84,1562.59 2198.63,1570.39 2198.63,1590.45 2209.17,1600.99
OSPI0_D0: R27.2 U7.D3 | length 148.7
  Top Layer w5.3: U7.D3@2813.29,1015.18 2796.54,998.44 2796.54,939.84 2820.72,915.66 R27.2@2820.72,883.42
OSPI0_D1: R28.2 U7.D2 | length 122.8
  Top Layer w5.3: R28.2@2660.72,998.28 2691.13,998.28 2694.28,995.13 2753.86,995.13 U7.D2@2773.92,1015.18
OSPI0_D2: R29.2 U7.C4 | length 116.8
  Top Layer w5.3: U7.C4@2852.66,1054.55 2869.4,1071.29 2907.58,1071.29 2914.32,1064.55 2927.75,1064.55 2940.91,1077.7 2954.1,1077.7 R29.2@2954.22,1077.82
OSPI0_D3: R30.2 U7.D4 | length 151.9
  Top Layer w5.3: U7.D4@2852.66,1015.18 2873.36,994.48 2873.36,966.48 v1(2910.59,934.25)
  Bottom Layer w5.3: v1(2910.59,934.25) 2911.25,934.91 2954.78,934.91 R30.2@2955.43,935.56
OSPI0_D4: R361.2 U7.D5 | length 963.5
  Top Layer w5.3: U7.D5@2892.03,1015.18 2892.47,1015.62 2892.47,1025.73 2886.56,1031.64 2879.58,1031.64 2874.49,1026.55 2874.49,1012.18 2892.21,994.45 2903.1,994.45 2913.39,984.16 2933.81,984.16 2948.67,999.02 2948.67,1044.81 2953.89,1050.03 2969.71,1050.03 2972.82,1046.92 2972.82,1032.21 2963.89,1023.28 2963.89,1007.11 2972.19,998.81 2972.19,994.42 2957.88,980.12 2957.88,961.49 2968.74,950.63 2968.74,946.24 2965.64,943.14 2950.86,943.14 2944.37,949.63 2944.37,970.13 2941.27,973.23 2930.12,973.23 2925.25,968.36 2925.25,947.71 2945.52,927.44 2945.52,904.83 2942.42,901.72 2936.45,901.72 2933.34,904.83 2933.34,918.78 2930.24,921.89 2925.85,921.89 2920.92,916.97 2920.92,900.18 2917.82,897.07 2911.63,897.07 2908.52,900.18 2908.52,909.72 2903.52,914.73 2898.06,914.73 2891.8,908.46 2886.38,908.46 2882.02,912.82 2882.02,922.41 2889.76,930.16 2889.76,934.74 2886.08,938.42 2878.37,938.42 2871.8,931.84 2864,931.84 2860.89,934.94 2860.89,939.33 2868.68,947.12 2868.68,951.51 2863.91,956.27 2857.23,956.27 2852.66,951.7 2846.34,951.7 2834.67,963.36 2827.61,963.36 2824.31,960.06 2824.31,953.75 2882.43,895.63 2882.43,871.93 2886.85,867.5 2892.31,867.5 2896.81,872.01 2896.81,882.48 2900.95,886.62 2907.49,886.62 2910.59,883.51 2910.59,877.83 2913.81,874.61 2918.59,874.61 2929.67,885.69 2957.19,885.69 2964.2,892.7 R361.2@2964.2,903.68
OSPI0_D5: R365.2 U7.E3 | length 113.4
  Top Layer w5.3: U7.E3@2813.29,975.81 2813.29,947.02 2863.91,896.4 R365.2@2863.91,883.42
OSPI0_D6: R366.2 U7.E2 | length 92.4
  Top Layer w5.3: R366.2@2773.92,883.42 U7.E2@2773.92,975.81
OSPI0_D7: R376.2 U7.E1 | length 77.2
  Top Layer w5.3: R376.2@2661.56,978.93 2661.83,978.66 2694.02,978.66 2697.55,982.19 2725.98,982.19 2732.36,975.81 U7.E1@2734.55,975.81
OSPI0_DQS: R375.1 R381.2 R382.2 R437.2 R440.2 | length 171.1
  Top Layer w5.3: R382.2@2764.05,1238.46 R437.2@2764.05,1284.43 2778.38,1284.43 2792.01,1270.8 2795.25,1270.8 R440.2@2807.13,1270.79 ; R440.2@2807.13,1270.79 2814.67,1270.79 2817.72,1270.79 2823.42,1265.09 2840.27,1265.09 R375.1@2840.63,1265.09 2840.63,1248.47 2833.13,1240.96 R381.2@2833.13,1227.68
OSPI0_RST: R388.1 U7.A4 U35.4 | length 245.2
  Top Layer w15: U7.A4@2852.66,1133.29 2858.09,1138.72 2858.09,1166.41 v1(2858.66,1166.99)
  Bottom Layer w5.3: v1(2858.66,1166.99) 2873.97,1166.99 2890.73,1150.22 2890.73,1053.96 2885.42,1048.66 2880.24,1048.66 2872.65,1041.06 U35.4@2872.65,990.75
PG_VDD_1V2: R295.1 R317.1 U2.3 U29.5 | length 2233.7
  Top Layer w5.3: v1(1771.58,127.81) 1771.9,127.49 R317.1@1800.3,127.49 ; U2.3@1967.11,1242.05 1967.11,1164.31 R295.1@1966.38,1163.59 1966.38,1146.84 1979.93,1133.29 2114.03,1133.29 v1(2133.03,1114.29) ; v1(2318.17,956.75) 2321.61,956.75 2326.83,951.52 U29.5@2351.44,951.52
  SIG 1 w4.75: v1(1771.58,127.81) 1577.19,127.81 1526.18,178.82 1526.18,391.43 1563.84,429.08 1615.48,429.08 1699.92,513.53 1699.92,663.23 1728.51,691.82 1728.51,788.94 1905.93,966.36 1905.93,995.2 1936.08,1025.35 1936.08,1071.8 1966.79,1102.51 2121.25,1102.51 v1(2133.03,1114.29) 2164.62,1114.29 2180.23,1098.68 2294.53,1098.68 2318.17,1075.03 v1(2318.17,956.75)
PG_VSYS_3V3: R296.1 U2.6 U32.5 | length 999.9
  Top Layer w5.3: R296.1@2041.1,1367.85 2041.1,1329.7 2053.94,1316.85 U2.6@2075.37,1316.85 2126.3,1316.85 2133.9,1324.45 2175.67,1324.45 2190.08,1310.03 2220.88,1310.03 2276.42,1254.49 2466.27,1254.49 2510.68,1298.9 v1(2595.37,1298.9)
  Top Layer w10: v1(2774.69,1492.62) 2783.16,1484.14 U32.5@2803.11,1484.14
  Bottom Layer w5.3: v1(2595.37,1298.9) 2640.19,1343.72 2728.42,1343.72 2747.31,1362.61 2747.31,1465.24 v1(2774.69,1492.62)
PHY1_RST: R425.1 U22.43 U65.4 | length 517.5
  Bottom Layer w5.3: U22.43@6635.02,853.9 6635.02,982.42 6650.65,998.04 6650.65,1107.31 6761.52,1218.19 6860.01,1218.19 U65.4@6861.67,1219.85
PHY2_RST: R418.1 U37.43 U60.4 | length 314.9
  Bottom Layer w5.3: U37.43@6635.02,1803.9 6635.02,1924.8 6644.66,1934.45 6644.66,1989.76 6665.24,2010.34 6665.24,2104.05 U60.4@6663.66,2105.64
PORZ_DELAY: U5.2 U6.4 | length 140.4
  Top Layer w10: U5.2@1991.31,857.27 1991.31,822.6 2002.28,811.63 2054.88,811.63 2064.38,802.13 U6.4@2064.38,777.98
PORZ_PB: Q1.2 R177.1 SW2.2 SW2.4 U34.1 | length 948.8
  Top Layer w4: U34.1@678.78,2146.97 691.97,2146.97 v1(700,2155)
  Top Layer w5.3: SW2.2@366.76,2220.46 414.3,2220.46 443.92,2190.85 526.58,2190.85 556.2,2220.46 SW2.4@587.24,2220.46 626.93,2220.46 635.47,2229 691,2229 700,2220 v1(700,2155)
  SIG 1 w5.3: v1(700,2155) 736.01,2155 765,2126 765,2124.81 778.65,2111.16 778.65,2045.78 793.43,2031 891,2031 v1@913,2009
  Bottom Layer w5.3: Q1.2@842.87,1866.72 842.87,1899.27 878.13,1934.53 878.13,1965.75 889.17,1976.79 R177.1@909.28,1976.79 909.28,2001.85 912,2004.56 v1(912,2008)
PR0_PRU0_GPIO0: U1.K17 U23.2 | length 1542.8
  Top Layer w4: U1.K17@4051.07,1099.33 4068.69,1081.71 4114.06,1081.71
  Top Layer w5.3: 4114.06,1081.71 4242.57,1081.71 4274.35,1113.49 4512.67,1113.49 4548.71,1149.54 4738.98,1149.54 4772.52,1116 4843.09,1116 4854.33,1127.24 v1(4854.62,1127.24) ; v1(4672.15,1567.23) 4674.58,1569.66 4688.03,1569.66 4712.66,1594.29 U23.2@4762.24,1594.29
  Bottom Layer w5.3: v1(4672.15,1567.23) 4684.3,1555.09 4757.29,1555.09 4776.23,1536.14 4776.23,1334.57 4885.49,1225.31 4885.49,1181.94 4854.47,1150.93 4854.47,1127.38 v1(4854.62,1127.24)
PR0_PRU0_GPIO0_MUX: J2/J4.33 U23.42 | length 3168.8
  Top Layer w5.3: U23.42@4797.68,1629.73 4797.87,1629.92 4797.87,1685.74 v1(4798.05,1685.93)
  SIG 1 w4.75: J2/J4.33@2304.17,1950 2354.15,1999.98 2423.45,1999.98 2451.78,2028.31 2451.78,2089.76 2499.16,2137.13 2691.64,2137.13 2704.72,2150.21 2967.7,2150.21 3018.07,2099.84 3018.07,2030.75 3039.37,2009.45 3086.64,2009.45 3106.66,1989.43 3240.53,1989.43 3461.82,2210.72 4245.54,2210.72 4365.5,2090.76 4421.06,2090.76 4444.93,2066.88 4444.93,1924.26 4470,1899.19 4584.75,1899.19 v1(4798.05,1685.93)
PR0_PRU0_GPIO1: U1.K18 U23.3 | length 1538.3
  Top Layer w5.3: U1.K18@4082.57,1099.33 4245.2,1099.33 4271.31,1125.44 4494.4,1125.44 4529.1,1160.14 4748.73,1160.14 4762.56,1173.97 4792.9,1173.97 4819.92,1146.95 4883.59,1146.95 v1(4883.66,1147.02) ; v1(4720.59,1574.61) U23.3@4762.24,1574.61
  Bottom Layer w5.3: v1(4720.59,1574.61) 4761.04,1615.05 4864.12,1615.05 4904.17,1575 4904.17,1167.53 v1(4883.66,1147.02)
PR0_PRU0_GPIO1_MUX: J2/J4.32 U23.40 | length 3138.3
  Top Layer w5.3: U23.40@4837.05,1629.73 4837.05,1649.49 4849.4,1661.84 v1@4909.05,1661.84
  SIG 1 w4.75: J2/J4.32@2404.17,1950 2448.22,1994.04 2519.19,1995.39 2615.04,2091.24 2673.21,2091.24 2712.56,2051.9 2747.88,2051.9 2759.34,2040.43 2941.21,2040.43 2982.72,1998.92 3082.95,1998.92 3102.5,1979.38 3118.1,1979.38 3149.83,1947.64 3212.96,1947.64 3465.99,2200.67 4238.82,2200.67 4355.09,2084.39 4355.09,1929.05 4395,1889.14 4562.3,1889.14 4784.79,1666.65 4900.7,1666.65 4905.53,1661.82 v1(4909.07,1661.82)
PR0_PRU0_GPIO2: U1.J18 U23.4 | length 1542.5
  Top Layer w5.3: U1.J18@4082.57,1130.83 4086.86,1126.53 4242.42,1126.53 4262.53,1146.64 4462.97,1146.64 4499.01,1182.68 4722.08,1182.68 v1(4731.01,1191.61) ; v1(4670.59,1535.24) 4690.28,1554.92 U23.4@4762.24,1554.92
  Bottom Layer w5.3: v1(4670.59,1535.24) 4692.98,1535.24 4712.83,1515.39 4728.68,1515.39 4755,1489.07 4755,1275.07 4751.15,1271.22 4663.78,1271.22 4650.2,1284.8 4606.38,1284.8 4595,1273.42 4595,1246.63 4600.67,1240.95 4708.91,1240.95 4725.3,1257.35 4754.48,1257.35 4760.72,1251.1 4760.72,1238.11 4731.01,1208.4 v1(4731.01,1191.61)
PR0_PRU0_GPIO2_MUX: J2/J4.31 U23.37 | length 3060
  Top Layer w5.3: U23.37@4892.17,1594.29 4901.33,1594.84 v1(4949.69,1594.84)
  SIG 1 w4.75: J2/J4.31@2504.17,1950 2635.37,2081.19 2667.65,2081.19 2707,2041.85 2743.71,2041.85 2755.18,2030.38 2936.23,2030.38 2977.74,1988.87 3078.79,1988.87 3098.34,1969.32 3113.93,1969.32 3145.67,1937.59 3217.12,1937.59 3470.15,2190.62 4234.65,2190.62 4345.04,2080.23 4345.04,1924.05 4390,1879.09 4558.12,1879.09 4780.76,1656.45 4886.24,1656.45 4947.84,1594.84 v1(4949.69,1594.84)
PR0_PRU0_GPIO3: U1.J17 U23.5 | length 1538.9
  Top Layer w4: U1.J17@4051.07,1130.83 4065.96,1115.93 4114.06,1115.93
  Top Layer w5.3: 4114.06,1115.93 4246.81,1115.93 4266.92,1136.04 4481.8,1136.04 4517.85,1172.08 4742.26,1172.08 4761.6,1191.43 4761.6,1202.61 v1(4762.69,1203.71) ; v1(4720.59,1535.24) U23.5@4762.24,1535.24
  Bottom Layer w5.3: v1(4720.59,1535.24) 4741.8,1535.24 4765.63,1511.4 4765.63,1279.25 4776.56,1268.33 4778.43,1266.45 4783.61,1266.45 4794.49,1277.33 4799.66,1277.33 4807.43,1269.57 4807.43,1264.39 4796.55,1253.51 4796.55,1248.34 4812.73,1232.16 4833.4,1211.49 4833.4,1109.22 4814.59,1090.42 4799.52,1090.42 4777.36,1112.58 4777.36,1120.11 4783.84,1126.6 4802.39,1126.6 4812.61,1136.82 4812.61,1158.59 4800,1171.21 4792.65,1171.21 4762.69,1201.16 v1(4762.69,1203.71)
PR0_PRU0_GPIO3_MUX: J2/J4.19 U23.35 | length 4247.1
  Top Layer w5.3: U23.35@4892.17,1554.92 v1@4949.62,1554.92
  SIG 1 w4.75: J2/J4.19@1704.17,2050 1749.17,2095 1925,2095 1952.52,2067.48 1952.52,1931.18 1936.83,1915.5 1936.83,1843.2 1960.52,1819.52 2160.17,1819.52 2246.34,1905.69 2517.51,1905.69 2549.29,1937.47 2549.29,1953.8 2623.09,2027.6 2623.09,2051.69 2639.18,2067.78 2666.75,2067.78 2702.73,2031.8 2739.55,2031.8 2751.02,2020.33 2932.07,2020.33 2973.58,1978.82 3074.63,1978.82 3094.17,1959.28 3109.77,1959.28 3141.51,1927.54 3221.28,1927.54 3474.31,2180.57 4167.16,2180.57 4255,2092.73 4255,1924.04 4315.04,1864 4404.5,1864 4407.28,1861.22 4604.67,1658.91 4617.18,1646.4 4873.41,1646.4 4925.12,1594.69 4925.12,1579.73 4949.69,1555.16 v1(4949.69,1554.85)
PR0_PRU0_GPIO4: U1.K16 U23.6 | length 1536.3
  Top Layer w5.3: v1(4670.59,1495.87) 4690.28,1515.55 U23.6@4762.24,1515.55
  Top Layer w10: U1.K16@4019.57,1099.33 v1(4035.32,1083.58)
  SIG 1 w4.75: v1(4035.32,1083.58) 4171.86,1083.58 v1(4244.93,1156.66)
  Bottom Layer w5.3: v1(4244.93,1156.66) 4226.95,1156.66 4190.1,1119.81 4190.1,1050.34 4198.67,1041.77 4308.27,1041.77 4321.85,1055.35 4321.85,1068.6 4297.69,1092.76 4219.07,1092.76 4211.79,1100.03 4211.79,1121.09 4220.2,1129.5 4278.94,1129.5 4286.76,1137.33 4286.76,1231.25 4298.19,1242.68 4341.65,1242.68 4409.71,1310.74 4409.71,1382.72 4417.75,1390.76 4609.04,1390.76 4623.28,1405 4623.28,1448.28 v1@4670.59,1495.59
PR0_PRU0_GPIO4_MUX: J2/J4.17 U23.33 | length 4078.9
  Top Layer w5.3: U23.33@4892.17,1515.55 4892.29,1515.68 4949.57,1515.68 v1(4949.69,1515.8)
  SIG 1 w4.75: J2/J4.17@1904.17,2050 1859.69,2005.52 1859.69,1890.49 1940.72,1809.47 2168.12,1809.47 2254.29,1895.64 2521.67,1895.64 2559.5,1933.47 2559.5,1949.8 2633.33,2023.63 2633.33,2047.72 2643.34,2057.73 2661.8,2057.73 2697.78,2021.75 2735.39,2021.75 2746.85,2010.28 2927.9,2010.28 2969.41,1968.77 3070.46,1968.77 3090.01,1949.22 3105.61,1949.22 3137.34,1917.49 3236.7,1917.49 3326.48,2007.27 3421.87,2007.27 3448.18,2033.57 3448.18,2099.21 3509.93,2160.97 4172.55,2160.97 4244.93,2088.58 4244.93,1908.32 4305.75,1847.5 4399,1847.5 4610.15,1636.35 4868.39,1636.35 4911.11,1593.63 4911.11,1554.7 4949.69,1516.11 v1(4949.69,1515.8)
PR0_PRU0_GPIO5: U1.G17 U49.4 | length 4166
  Top Layer w4: U1.G17@4051.07,1193.82 4066.82,1209.57 4114.06,1209.57
  Top Layer w5.3: 4114.06,1209.57 4196.83,1209.57 4211.2,1223.93 4255.03,1223.93 4272.68,1241.58 4272.68,1255.67 4282.71,1265.71 4349.14,1265.71 4358.99,1255.86 4358.99,1249.6 4372.91,1235.68 4469.28,1235.68 4490.12,1256.53 4490.12,1412.6 4449.41,1453.32 4449.41,1663.92 4508.97,1726.7 4879.55,1726.7 4904.07,1751.23 5258.95,1751.23 5342.82,1835.1 5543.35,1835.1 5608,1899.74 5935.26,1899.74 v1(5945,1890) ; U49.4@5652.8,838.02 5696.58,838.02 v1(5711.38,823.23)
  Bottom Layer w5.3: v1(5711.38,823.23) 5728.96,840.81 5860.01,840.81 5873.54,827.28 5993.25,827.28 6136.91,970.94 6136.91,1693.98 6120.62,1710.28 6120.62,1757.66 6053.94,1824.33 5945.45,1824.33 5924.62,1845.16 5924.62,1869.62 v1(5945,1890)
PR0_PRU0_GPIO5_MUX: J2/J4.13 U49.3 | length 5700.4
  Top Layer w5.3: U49.3@5652.8,863.61 v1(5711.38,863.61)
  Bottom Layer w5.3: J2/J4.13@2304.17,2050 2308.74,2050 2403.79,2145.05 2455,2145.05 2465.02,2135.03 2465.57,2134.48 2587.45,2133.48 2589.01,2131.93 2695.95,2024.98 2992.53,2024.98 3089.78,1927.73 3220.73,1927.73 3407.38,2114.38 3919.77,2114.38 3963.61,2070.53 4005.48,2070.53 4113.29,2178.34 4390.92,2178.34 4430.26,2217.68 5690.5,2218.3 5694.89,2218.3 5696.45,2216.75 5899.18,2014.02 5899.18,1852.75 5938.19,1813.73 6043.16,1813.73 6081.57,1775.32 6081.57,1726.55 6126.31,1681.81 6126.31,975.33 5988.86,837.88 5877.94,837.88 5852.2,863.61 v1(5711.38,863.61)
PR0_PRU0_GPIO6: U1.K15 U23.7 | length 1538
  Top Layer w5.3: v1(4720.59,1495.87) U23.7@4762.24,1495.87
  Top Layer w10: U1.K15@3988.08,1099.33 v1(4003.83,1083.58)
  SIG 1 w4.75: v1(4003.83,1083.58) 4020.24,1100 4140.09,1100 4196.74,1156.66 v1(4196.74,1158.55)
  Bottom Layer w5.3: v1(4196.74,1158.55) 4198.64,1158.55 4270.24,1230.15 4270.24,1302.02 4281.65,1313.43 4300,1313.43 4312.89,1300.54 4312.89,1270.44 4321.85,1261.48 4331.72,1261.48 4390,1319.76 4390,1358.24 4366.43,1381.81 4328.12,1381.81 4300.95,1408.98 4300.95,1457.87 4322.2,1479.12 4461.67,1479.12 4469.35,1471.45 4469.35,1413.42 4477.77,1405 4496.97,1405 4504.23,1412.26 4504.23,1470.81 4513.5,1480.07 4540.45,1480.07 4550,1470.52 4550,1425.91 4560.91,1415 4590,1415 4600.62,1425.62 4600.62,1453.05 4636.94,1489.37 4636.94,1508.86 4643.48,1515.39 4685.27,1515.39 4704.79,1495.87 v1(4720.59,1495.87)
PR0_PRU0_GPIO6_MUX: J5/J7.48 U23.31 | length 1805.7
  Top Layer w5.3: U23.31@4892.17,1476.18 5037.8,1476.18 5040,1476.18 5079.97,1476.18 v1(5125.37,1521.58)
  Bottom Layer w5.3: J5/J7.48@4804.17,250 4849.17,295 5036.96,295 5070.13,328.17 5070.13,572.32 5145.92,648.11 5145.92,838.79 5172.5,865.37 5172.5,1121.18 5159.37,1134.31 5159.37,1487.58 v1(5125.37,1521.58)
PR0_PRU0_GPIO8: U1.G15 U49.7 | length 2188.7
  Top Layer w5.3: U49.7@5652.8,761.25 5713.35,761.25 5722.21,752.39 5722.21,691.43 v1(5700.39,669.61)
  Top Layer w10: U1.G15@3988.08,1193.82 v1(4003.83,1209.57)
  SIG 1 w4.75: v1(4003.83,1209.57) 4019.2,1194.19 4041.69,1194.19 4047.02,1199.52 4302.96,1199.52 4327.29,1223.85 4431.06,1223.85 4462.51,1192.39 4462.51,1125.71 4630.59,957.64 4839.34,957.64 4971.11,825.87 5050.22,825.87 5125.06,751.03 5235.51,751.03 5238.39,753.91 5361.91,753.91 5414.07,701.76 5549.05,701.76 5567.7,720.41 5628.94,720.41 5679.74,669.61 v1@5700.18,669.61
PR0_PRU0_GPIO8_MUX: U49.6 U51.13 | length 2806.1
  Top Layer w5.3: U51.13@4542.46,1624.46 4601.64,1624.46 4610.25,1633.06 4679.56,1633.06 4762.6,1716.1 4883.94,1716.1 4908.46,1740.63 5263.34,1740.63 5347.21,1824.5 5547.74,1824.5 5576.49,1853.25 v1(5793.08,1853.25) ; v1(5574.59,812.43) 5600.18,786.84 U49.6@5652.8,786.84
  Bottom Layer w5.3: v1(5574.59,812.43) 5574.59,869.86 5663.53,958.8 5875.3,958.8 5933.8,1017.3 5933.8,1638 5860.24,1711.56 5860.24,1786.09 v1(5793.08,1853.25)
PR0_PRU0_GPIO9: U1.F17 U49.9 | length 4050
  Top Layer w4: U1.F17@4051.07,1225.32 4066.82,1241.06 4113.02,1241.06 4114.06,1240.02
  Top Layer w5.3: 4114.06,1240.02 4119.55,1234.53 4178.39,1234.53 4218.26,1274.39 4257.46,1274.39 4273.91,1290.84 4399.4,1290.84 4414.17,1276.07 4443.95,1246.28 4464.89,1246.28 4479.52,1260.92 4479.52,1408.03 4438.73,1448.82 4438.73,1671.33 4503.08,1737.3 4875.16,1737.3 4899.68,1761.83 5254.56,1761.83 5338.43,1845.7 5538.96,1845.7 5608.26,1915 v1(5995,1915) ; v1(5835,735.66) U49.9@5877.2,735.66
  Bottom Layer w5.3: v1(5835,735.66) 5931.61,735.66 6158.11,962.16 6158.11,1702.77 6141.82,1719.06 6141.82,1766.44 5995,1913.26 v1(5995,1915)
PR0_PRU0_GPIO9_MUX: U49.10 U52.40 | length 1891.3
  Top Layer w5.3: v1(4538.82,440) 4555.16,456.34 U52.40@4555.16,496.77 ; U49.10@5877.2,761.25 5920,761.25 5948,733.25 5948,589.04 5959.13,577.91 v1(5959.13,576.2)
  SIG 1 w4.75: v1(4538.82,440) 4558.07,420.75 4904.54,420.75 4976.46,492.67 5033.8,492.67 5086.84,545.71 5113.55,545.71 5150.1,582.26 5150.1,601.97 5200.65,652.52 5541.15,652.52 5623.29,570.39 5782.28,570.39 5801.9,590 5945.32,590 v1(5959.13,576.2)
PR0_PRU0_GPIO10: R286.1 U49.12 | length 3436.8
  Top Layer w5.3: R286.1@4342.07,1238.88 4357.1,1223.85 4472.43,1223.85 4500.72,1252.14 4500.72,1455.1 4513.72,1468.1 4560.16,1468.1 4610.25,1518.19 4610.25,1557.58 4590.19,1577.64 4590.19,1596.57 4610.61,1616.99 4689.13,1616.99 4777.64,1705.5 4888.33,1705.5 4912.85,1730.03 5267.73,1730.03 5351.6,1813.9 5552.13,1813.9 5571.96,1833.72 5924.62,1833.72 v1(5944.14,1853.25) ; U49.12@5877.2,812.43 5911.5,812.43 v1(5927.62,796.31)
  Bottom Layer w5.3: v1(5927.62,796.31) 5977.28,796.31 6147.51,966.55 6147.51,1698.37 6131.22,1714.67 6131.22,1762.05 6040.02,1853.25 v1(5944.14,1853.25)
PR0_PRU0_GPIO10_MUX: J1/J3.8 U49.13 | length 4577.8
  Top Layer w5.3: v1(5132.07,516.58) 5152.54,537.05 5152.54,642.33 5180.89,670.67 5346.76,670.67 5354.68,678.6 5663.79,678.6 5692.3,650.08 5711.46,650.08 5800,738.62 5800,812.74 5825.28,838.02 U49.13@5877.2,838.02
  Bottom Layer w5.3: J1/J3.8@2304.17,250 2349.17,205 2524.5,205 2550.5,231 2550.5,325.58 2563.93,339.01 2619.95,339.01 2682.55,401.61 2925.52,401.61 2940.54,386.6 3198.21,386.6 3277.43,307.38 3460.04,307.38 3485.63,281.79 3540.87,281.79 3563.43,259.22 3626.49,259.22 3662.38,295.11 3707.4,295.11 3746.93,255.57 3787.27,255.57 3950.32,92.53 4262.19,92.53 4270.88,101.22 4492.79,101.22 4519.56,74.45 5065.51,74.45 5117.53,126.47 5117.53,306.35 5146.42,335.24 5146.42,502.23 v1(5132.07,516.58)
PR0_PRU0_GPIO10_R: R286.2 U1.G18 | length 234.2
  Top Layer w4: U1.G18@4082.57,1193.82 4114.06,1193.82
  Top Layer w5.3: 4114.06,1193.82 4196.07,1193.82 4215.59,1213.33 4259.42,1213.33 4282.27,1236.18 4289.05,1236.18 R286.2@4296.24,1243.37
PR0_PRU0_GPIO11: R75.1 U23.11 | length 638.6
  Top Layer w5.3: v1(4709.76,1417.13) U23.11@4762.24,1417.13
  Bottom Layer w5.3: R75.1@4473.25,1029.85 4504.23,1060.84 4504.23,1207.24 4615.86,1318.86 4728.68,1318.86 4740.77,1330.96 4740.77,1401.6 4725.24,1417.13 v1(4709.76,1417.13)
PR0_PRU0_GPIO11_MUX: U23.28 U52.42 | length 1738.7
  Top Layer w5.3: U52.42@4594.53,496.77 4594.53,459.12 4600.58,453.07 4609.07,453.07 4620.23,441.91 v1(4621.87,441.91) ; U23.28@4892.17,1417.13 4964.13,1417.13 v1(4983.82,1397.44)
  Bottom Layer w5.3: v1(4621.87,441.91) 4634.32,429.8 4636.5,429.8 4809.99,432.13 4837.04,432.13 4849.17,420 4911.01,420 4923.28,432.27 4923.28,442.2 4876.63,488.85 4876.63,683.54 4921.08,727.99 5068.68,727.99 5107.63,766.94 5107.63,1004.43 5117.27,1014.07 5117.27,1305.63 5026.09,1396.81 4984.45,1396.81 v1(4983.82,1397.44)
PR0_PRU0_GPIO11_R: R75.2 U1.M16 | length 479.1
  Top Layer w10: U1.M16@4019.57,1036.34 v1(4035.32,1020.59)
  SIG 1 w4.75: v1(4035.32,1020.59) 4037.24,1022.5 4088.1,1022.5 4103.59,1037.99 4131,1037.99 4285.09,1037.99 4335.31,987.77 4415.09,987.77 v1(4430.48,1003.15)
  Bottom Layer w5.3: v1(4430.48,1003.15) 4431.93,1004.61 R75.2@4431.93,1029.87
PR0_PRU0_GPIO12: R76.1 U23.12 | length 580.8
  Top Layer w5.3: R76.1@4471.93,1029.87 v1(4471.93,1056.95) ; v1(4663.66,1372.52) 4663.66,1372.68 4688.42,1397.44 U23.12@4762.24,1397.44
  Bottom Layer w5.3: v1(4471.93,1056.95) 4475.96,1056.95 4493.63,1074.62 4493.63,1211.63 4618.27,1336.26 4675.8,1336.26 4680.2,1340.66 4680.2,1355.97 v1(4663.66,1372.52)
PR0_PRU0_GPIO12_MUX: J1/J3.5 U23.26 | length 6990.5
  Top Layer w5.3: U23.26@4892.17,1377.76 5073.49,1377.76 5166.86,1471.13 5166.86,1623.64 5109.78,1680.73 4948.15,1680.73 4939.73,1689.14 4939.73,1697.65 v1(4927.84,1709.54)
  SIG 1 w4.75: v1(1489.72,2069.3) 1530.54,2069.3 1589.63,2128.39 1746.63,2128.39 1875.87,2257.63 2903.7,2257.63 3048.77,2112.55 3048.77,2090.73 3102.04,2037.46 3119.38,2020.12 3227.82,2020.12 3449.11,2241.42 4262.19,2241.42 4382.1,2121.51 4455.19,2121.51 4476.57,2100.13 4737.18,2100.13 4751.81,2085.51 4751.81,1944.72 4937.95,1758.57 4937.95,1722.23 4927.84,1712.11 v1(4927.84,1709.54)
  Bottom Layer w5.3: v1(1489.72,2069.3) 1520.7,2069.3 1541,2049 1541,1926.77 1584.27,1883.5 1698.53,1883.5 1709.72,1872.31 1709.72,1756.13 1703.86,1750.27 1703.86,1624.59 1688.32,1609.05 1688.32,1519.37 1741.2,1466.49 1741.2,1411.65 1922.76,1230.09 1922.76,1178.81 1951.78,1149.78 1951.78,1080.22 1946.68,1075.11 1946.68,974.63 1985.02,936.28 1985.02,885.23 2013.47,856.79 2013.47,694.19 2033.93,673.73 2033.93,501.04 2053.45,481.52 2053.45,299.28 J1/J3.5@2004.17,250
PR0_PRU0_GPIO12_R: R76.2 U1.M15 | length 510.6
  Top Layer w5.3: R76.2@4432.56,1029.87 v1(4432.56,1056.95)
  Top Layer w10: U1.M15@3988.08,1036.34 v1(4003.83,1020.59)
  SIG 1 w4.75: v1(4003.83,1020.59) 4019.95,1036.71 4067.17,1036.71 4086.9,1056.44 4131,1056.44 4206.03,1056.44 4227.64,1078.06 4360.2,1078.06 4374.14,1064.13 4423.15,1064.13 4430.32,1056.95 v1(4432.56,1056.95)
PR0_PRU0_GPIO13: R77.1 U23.13 | length 844.4
  Top Layer w5.3: R77.1@4339.94,1204.08 4375.01,1204.08 v1(4376.57,1202.52) ; v1(4720.59,1377.76) U23.13@4762.24,1377.76
  Bottom Layer w5.3: v1(4376.57,1202.52) 4376.57,1169.89 4358.12,1151.45 4315.65,1151.45 4299.61,1167.49 4299.61,1187.73 4338.75,1226.88 4414.8,1226.88 4426.83,1238.91 4426.83,1270.64 4467.17,1310.97 4467.17,1370.24 4473.67,1376.74 4497.43,1376.74 4504.17,1370 4504.17,1354.93 4511.92,1347.18 4582.69,1347.18 4655.52,1420 4678.35,1420 v1(4720.59,1377.76)
PR0_PRU0_GPIO13_MUX: U23.24 U51.10 | length 989.1
  Top Layer w5.3: v1(4470.07,1571.63) 4471.02,1571.63 4494.97,1547.68 U51.10@4542.46,1547.68 ; U23.24@4892.17,1338.39 5026.38,1338.39 v1(5026.97,1338.98)
  SIG 1 w4.75: v1(4470.07,1571.63) 4471.72,1573.27 4490.97,1573.27 4627,1437.25 4724.12,1437.25 4744.99,1416.37 4744.99,1304.17 4772.21,1276.95 4919.29,1276.95 4981.16,1338.82 5026.82,1338.82 v1(5026.97,1338.98)
PR0_PRU0_GPIO13_R: R77.2 U1.H17 | length 259.5
  Top Layer w4: U1.H17@4051.07,1162.32 4067.21,1178.46 4131,1178.46
  Top Layer w5.3: 4131,1178.46 4206.06,1178.46 4230.33,1202.73 4263.81,1202.73 4268.54,1207.47 R77.2@4291.91,1207.47
PR0_PRU0_GPIO14: R78.1 U23.14 | length 204
  Top Layer w5.3: R78.1@4576.85,1313.21 4620,1313.21 4659.79,1353 4703.9,1353 4708.97,1358.07 U23.14@4762.24,1358.07
PR0_PRU0_GPIO14_MUX: U23.22 U51.6 | length 1173
  Top Layer w5.3: v1(4239.85,1611.24) 4277.82,1573.27 U51.6@4318.06,1573.27 ; U23.22@4892.17,1299.02 4954.13,1299.02 v1(4983.82,1269.33)
  SIG 1 w4.75: v1(4239.85,1611.24) 4239.85,1567.71 4308.18,1499.38 4428.1,1499.38 4461.79,1465.69 4532.88,1465.69 4590.05,1408.51 4590.05,1345.34 4693.11,1242.29 4739.17,1242.29 4744.7,1236.75 4951.24,1236.75 v1(4983.82,1269.33)
PR0_PRU0_GPIO14_R: R78.2 U1.H16 | length 1011.2
  Top Layer w5.3: v1(4401.72,1176.77) 4403.2,1175.29 4459.85,1175.29 4522.9,1238.33 4522.9,1298.64 4528.32,1304.05 4528.32,1306.02 4535.51,1313.21 R78.2@4537.48,1313.21
  Top Layer w10: U1.H16@4019.57,1162.32 v1(4035.32,1178.07)
  SIG 1 w4.75: v1(4035.32,1178.07) 4034.58,1178.07 4019.14,1162.63 3903.65,1162.63 3893.96,1152.94 3893.96,1132.7 3900.35,1126.31 4127.48,1126.31 4179.53,1178.36 4252.63,1178.36 4296.03,1134.95 4393.56,1134.95 4401.72,1143.11 v1(4401.72,1176.77)
PR0_PRU0_GPIO15: R79.1 U23.15 | length 654.8
  Top Layer w5.3: v1(4720.59,1338.39) U23.15@4762.24,1338.39
  Bottom Layer w5.3: R79.1@4469.35,1086.88 4469.35,1109.11 4465.69,1112.77 4458.22,1112.77 4451.91,1119.08 4436.05,1119.08 4432.39,1122.74 4432.39,1133.72 4436.05,1137.38 4473.8,1137.38 4477.46,1141.04 4477.46,1152.02 4473.8,1155.68 4447.13,1155.68 4443.47,1159.34 4443.47,1170.32 4447.13,1173.98 4473.43,1173.98 4480.2,1180.75 4480.2,1229.69 4647.79,1397.28 4672.05,1397.28 4719.08,1350.25 4719.08,1339.9 v1(4720.59,1338.39)
PR0_PRU0_GPIO15_MUX: J2/J4.12 U23.20 | length 4215.2
  Top Layer w5.3: U23.20@4837.05,1283.27 4837.05,1224.74 4832.02,1219.72 4832.02,1176.5 4839.56,1168.96 4912.18,1168.96 5017.02,1273.8 5017.02,1297.5 5183.1,1463.58 5185.43,1636.37 5185.43,1638.64 5183.88,1640.19 5122.13,1701.95 v1(4959.25,1701.95)
  SIG 1 w4.75: J2/J4.12@2404.17,2050 2404.17,2154.21 2436.31,2186.34 2649.69,2186.34 2675.77,2160.26 2971.86,2160.26 3028.12,2104 3028.12,2037.89 3046.51,2019.5 3090.8,2019.5 3110.83,1999.47 3236.37,1999.47 3457.66,2220.77 4249.7,2220.77 4359.86,2110.61 4369.66,2100.81 4429.98,2100.81 4454.98,2075.81 4454.98,1934.26 4480,1909.24 4625.45,1909.24 4845.46,1689.24 4945.8,1689.24 4958.51,1701.95 v1(4959.25,1701.95)
PR0_PRU0_GPIO15_R: R79.2 U1.L16 | length 460.6
  Top Layer w10: U1.L16@4019.57,1067.84 v1(4035.32,1052.09)
  SIG 1 w4.75: v1(4035.32,1052.09) 4051.87,1068.64 4131,1068.64 4182.78,1068.64 4236.39,1122.24 4373.25,1122.24 v1(4401.9,1093.59)
  Bottom Layer w5.3: v1(4401.9,1093.59) 4404.16,1093.59 4410.87,1086.88 R79.2@4429.98,1086.88
PR0_PRU0_GPIO16: R80.1 U23.16 | length 937.9
  Top Layer w5.3: R80.1@4335.8,1168.86 4376.75,1168.86 4388.37,1157.24 4409.81,1157.24 4409.88,1157.32 4458.65,1157.32 4494.62,1193.28 4523.26,1193.28 4535.6,1205.63 4535.6,1287.55 4538.7,1290.65 4560.03,1290.65 4563.14,1287.55 4563.14,1200.44 4569.39,1194.19 4582.16,1194.19 4589.07,1201.1 4589.07,1285.11 4596.81,1292.85 4611,1292.85 4619.2,1284.65 4619.2,1200.29 4625.94,1193.54 4639.04,1193.54 4645.5,1200 4645.5,1307.42 4677.27,1339.2 4689.83,1339.2 4710.32,1318.7 U23.16@4762.24,1318.7
PR0_PRU0_GPIO16_MUX: U23.18 U51.3 | length 986.2
  Top Layer w5.3: v1(4270,1651.25) 4270.6,1650.65 4317.45,1650.65 U51.3@4318.06,1650.05 ; v1(4792.12,1217.48) 4792.12,1250.21 4797.68,1255.76 U23.18@4797.68,1283.27
  SIG 1 w4.75: v1(4270,1651.25) 4269.83,1651.43 4246.11,1651.43 4220,1625.32 4220,1573.35 4304.43,1488.92 4424.34,1488.92 4457.63,1455.64 4528.71,1455.64 4580,1404.35 4580,1340.81 4688.58,1232.24 4734.62,1232.24 4740.67,1226.19 4782.71,1226.19 4791.42,1217.48 v1(4792.12,1217.48)
PR0_PRU0_GPIO16_R: R80.2 U1.H18 | length 299.9
  Top Layer w5.3: U1.H18@4082.57,1162.32 4095.14,1149.75 4095.14,1144.63 4101.63,1138.15 4110.01,1138.15 4116.5,1144.63 4116.5,1159.86 4123.97,1167.33 4138.17,1167.33 4143.61,1161.89 4143.61,1144.42 4149,1139.03 4207.64,1139.03 4218.28,1149.66 4218.28,1162.95 4232.64,1177.32 4284.16,1177.32 4285.43,1176.05 4290.03,1176.05 R80.2@4298.75,1167.33
PRU/BP_MUX_EN_INV: R96.2 U46.4 U49.15 U51.15 | length 2823.9
  Top Layer w5.3: U51.15@4542.46,1675.64 4574.84,1675.64 4606.1,1644.38 4671.38,1644.38 4703.5,1676.5 4703.5,1697.3 v1(4702.61,1698.19) ; U49.15@5877.2,889.2 5924.04,889.2 v1(5931,882.24) 5946.5,866.74 5946.5,808.04 5958.17,796.38 R96.2@5986.5,796.38 6012.17,770.71 U46.4@6054.41,770.71
  Bottom Layer w5.3: v1(4702.61,1698.19) 4778.54,1774.13 4984.84,1774.13 5186.78,1976.07 5714.42,1976.07 5931,1759.49 5931,1739.41 5971.25,1699.16 5971.25,1381.75 5983.45,1369.55 5983.45,1019.45 5931,967 v1(5931,882.24)
RESETN_PB: Q2.2 R178.1 SW3.2 SW3.4 U33.2 | length 621.3
  Top Layer w5.3: SW3.2@839.76,2217.46 874.32,2217.46 890.11,2201.68 939,2201.68 ; U33.2@906,2058 880,2058 872.04,2050.04 872.04,2026.96 891.62,2007.38 R178.1@891.62,1973 914.05,1973 941.61,2000.56 Q2.2@973.72,2000.56 ; U33.2@906.29,2059 933,2059 939,2065 939,2201.68 ; SW3.4@1060.19,2217.42 1027.11,2217.42 1015.42,2205.72 943.04,2205.72 939,2201.68
RGMII1_ICSSM_MUX_EN: R292.2 R294.2 U50.8 | length 4851.1
  Top Layer w5.3: v1(3051.66,756.89) 3052.96,755.6 3052.96,695.53 3122.73,625.75 3122.73,487.03 3112.25,476.55 3112.25,337.83 3146.85,303.23 3261.21,303.23 3282.52,281.92 3282.52,224.72 3304.54,202.69 3304.54,91 3352.89,42.65 3772.8,42.65 3779.15,49 v1(3912.22,49) ; U50.8@5303.35,1000.35 5397.83,1000.35 5454.5,1057.02 R292.2@5477.76,1057.02 R294.2@5477.76,992.02 5477.76,976.31 5489.74,964.33 5722.88,964.33 5760,927.2 v1(5760,815.75)
  Bottom Layer w5.3: v1(3912.22,49) 3923.94,60.73 4275.36,60.73 4284.05,69.42 4479.62,69.42 4506.39,42.65 5701.65,42.65 5750,91 5750,162.32 5851.25,263.57 5851.25,427.9 5760,519.15 v1(5760,815.75)
RGMII1_ICSSM_MUX_SEL_GPIO105: R291.2 R293.2 U1.D17 U17.1 U17.5 U50.9 U50.10 | length 3810.2
  Top Layer w5.3: U1.D17@4051.07,1288.31 4068.04,1305.28 4090.41,1305.28 4130.23,1345.1 4152.34,1345.1 4197.79,1390.55 4350.21,1390.55 4358.46,1382.3 4383.42,1382.3 4417.15,1416.02 4417.15,1684.11 4491.53,1758.5 4864.93,1758.5 4898.79,1792.36 v1(5242.49,1792.36) ; v1(4767.36,1069.03) 4779.14,1080.8 4917.18,1080.8 5034.52,1198.14 5034.52,1259.78 5099.74,1325 v1(5345,1325) 5397.09,1325 5452.19,1269.9 5452.19,1158.84 5465.31,1145.71 5465.31,1092.03 5401.72,1028.43 5374.87,1028.43 ; U50.9@5303.35,1020.04 5366.48,1020.04 5374.87,1028.43 ; U50.10@5303.35,1039.72 5363.57,1039.72 5374.87,1028.43
  Bottom Layer w5.3: R293.2@4591.64,1215.33 4588.62,1212.32 R291.2@4588.62,1152.36 4610,1152.36 4618.69,1143.67 4618.69,1097.35 4632.92,1083.12 U17.5@4680.08,1083.12 4728.04,1083.12 4742.13,1069.03 v1(4767.36,1069.03) ; U17.1@4680.08,1004.38 4728.43,1004.38 4767.36,1043.3 v1@4767.36,1070.5 ; v1(5242.49,1792.36) 5242.49,1455.76 5345,1353.25 v1(5345,1325)
RJ45_1_LED1_GREEN: J7.11 R224.2 | length 600.5
  SIG 1 w5.3: v1(7211.61,1143.99) 7228.7,1161.08 7468.28,1161.08 7539.08,1090.28 J7.11@7539.08,919.76
  Bottom Layer w5.3: R224.2@7160.2,1111.38 7181.03,1111.38 7211.61,1141.96 v1(7211.61,1143.99)
RJ45_1_LED1_YELLOW: J7.12 Q4.3 | length 737.4
  SIG 1 w5.3: v1(7203.26,1097.87) 7203.26,1121.11 7192.09,1132.28 7192.09,1152.08 7216.65,1176.63 7467.72,1176.63 7587.58,1056.77 7587.58,1031.72 7619,1000.29 J7.12@7619,919.76
  Bottom Layer w5.3: v1(7203.26,1097.87) 7203.65,1098.26 7268.59,1098.26 Q4.3@7274.1,1092.76
RJ45_1_LED2_GREEN: J7.13 Q5.3 R226.1 | length 377.3
  Top Layer w5.3: Q5.3@7324,160.9 R226.1@7324,221.46 7424.43,221.46 7539.08,336.1 J7.13@7539.08,390.24
RJ45_1_LED2_YELLOW: J7.14 Q6.3 R228.1 | length 425.5
  Bottom Layer w5.3: Q6.3@7324,160.9 R228.1@7324,221.46 7424.43,221.46 7512.97,310 7538.76,310 J7.14@7619,390.24
RJ45_1_VCC: J7.2 J8.2 TP21.1 TP22.1 | length 1601.1
  Top Layer w10: v1(6975,1174.56) TP21.1@6975,1345.45 7150.65,1345.45 7189.08,1383.88 J8.2@7189.08,1470 ; TP22.1@7165,225 7189.08,249.08 J7.2@7189.08,480
  SIG 1 w10: v1(6975,1174.56) 7021.66,1127.91 7021.66,535 7076.66,480 J7.2@7189.08,480
RJ45_2_LED1_GREEN: J8.11 R230.2 | length 415
  Bottom Layer w5.3: R230.2@7220,2141.38 7247.83,2141.38 7399.21,1990 7458.84,1990 J8.11@7539.08,1909.76
RJ45_2_LED1_YELLOW: J8.12 Q7.3 | length 407.6
  Bottom Layer w5.3: Q7.3@7340,2117.76 7340,2088.61 7428.01,2000.6 7571.54,2000.6 7619,1953.14 J8.12@7619,1909.76
RJ45_2_LED2_GREEN: J8.13 Q8.3 R232.1 | length 266.4
  Bottom Layer w5.3: Q8.3@7433.87,1187.91 R232.1@7433.87,1251.28 7441.88,1259.29 7441.88,1267.93 7447.09,1273.14 7499.14,1273.14 7539.08,1313.08 J8.13@7539.08,1380.24
RJ45_2_LED2_YELLOW: J8.14 Q9.3 R234.1 | length 209.6
  Bottom Layer w5.3: Q9.3@7580.33,1186.64 R234.1@7580.33,1250 7580.33,1341.56 J8.14@7619,1380.24
SD_PWR_EN: R39.2 U8.3 U9.4 | length 2034.1
  Top Layer w5.3: U8.3@795.16,716 829.3,716 847.55,734.25 v1(847.55,789.62)
  SIG 1 w4.75: v1(847.55,789.62) 940.38,789.62 985,745 985,687.63 1016.38,656.24 1042.7,656.24 1081.59,695.13 1115.43,695.13 1140.89,669.68 1378.96,669.68 1469.98,760.7 1469.98,1054.85 1556.1,1140.97 1657.08,1140.97 1801.54,1285.44 1894.86,1285.44 1938.67,1329.24 1976.1,1329.24 1994.22,1347.36 1994.22,1376.74 1973.75,1397.21 v1(1973.75,1482.88)
  Bottom Layer w5.3: U9.4@1942.75,1514.8 1968.02,1514.8 1973.75,1509.08 v1(1973.75,1482.88)
SHIELD1: C229.2 J5.1 J5.2 J5.3 J5.4 R32.1
SHIELD2: C235.2 J7.15 J7.16 R254.1
SHIELD3: C247.2 J8.15 J8.16 R255.1
SHIELD4: C230.2 J34.6 J34.7 J34.8 J34.9 J34.10 J34.11 R253.1
SOC_TA_I2C3_SCL: R355.1 R412.2 | length 698.5
  Top Layer w5.3: R412.2@745.39,1864.66 745.39,1909.34 767.43,1931.38 960.78,1931.38 988.32,1958.92 1035.12,1958.92 1058.97,1935.07 1144.2,1935.07 1199.61,1879.65 1280.94,1879.65 v1(1305.16,1903.88)
  Bottom Layer w5.3: R355.1@1288.1,1927.43 1297.26,1918.27 1297.26,1913.33 1305.16,1905.44 v1(1305.16,1903.88)
SOC_TA_I2C3_SDA: R357.1 R410.2 | length 805.7
  Top Layer w5.3: R410.2@875.14,1864.66 965.17,1864.66 973,1872.5 973,1927.11 994.21,1948.32 1030.73,1948.32 1054.58,1924.47 1139.81,1924.47 1195.22,1869.05 1297.95,1869.05 1336.26,1907.36 1336.26,1957.2 1354.12,1975.06 1444.06,1975.06 v1(1461,1992)
  Bottom Layer w5.3: v1(1461,1992) 1473.62,1979.38 R357.1@1496,1979.38
SOP0_SW: R14.2 SW1.8 U3.2 U4.6 | length 599.7
  Top Layer w5.3: U3.2@3338.21,363.58 3338.21,327.25 3316.37,305.4 3316.37,244.56 3336.34,224.58 3336.34,158.06 3350.83,143.58 3430.94,143.58 3435.55,138.97 3435.55,119.51 v1(3470.3,119.51) SW1.8@3512.3,119.51
  Bottom Layer w5.3: v1(3470.3,119.51) 3494.01,119.51 3554.41,179.91 U4.6@3618.83,179.91
SOP1_SW: R15.2 SW1.7 U3.3 U4.7 | length 525.3
  Top Layer w5.3: U3.3@3357.9,363.58 3357.9,328.98 3327.48,298.56 3327.48,248.43 3346.94,228.97 3346.94,213.09 3366.87,193.16 3431.35,193.16 3435.55,188.97 3435.55,169.51 v1(3470.3,169.51) SW1.7@3512.3,169.51
  Bottom Layer w5.3: v1(3470.3,169.51) 3516.01,169.51 3542.15,195.65 U4.7@3618.83,195.65
SOP2_SW: R16.2 SW1.6 U3.4 U4.8 | length 478.7
  Top Layer w5.3: U3.4@3377.58,363.58 3377.58,329.95 3338.08,290.44 3338.08,255.65 3352.36,241.37 3353.34,241.37 3353.88,240.83 3370.06,240.83 3375.93,246.7 3422.82,246.7 3435.55,233.97 3435.55,219.51 v1(3470.3,219.51) SW1.6@3512.3,219.51
  Bottom Layer w5.3: v1(3470.3,219.51) 3581.42,219.51 3589.52,211.4 U4.8@3618.83,211.4
SOP3_SW: R17.2 SW1.5 U3.5 U4.9 | length 423.2
  Top Layer w5.3: U3.5@3403.17,389.17 3422,389.17 3435.55,375.62 3435.55,269.51 v1(3470.3,269.51) SW1.5@3512.3,269.51
  Bottom Layer w5.3: v1@3470.66,269.15 3529.92,269.15 3553.3,245.77 3632.8,245.77 3642.45,236.12 U4.9@3642.45,219.28
SOP_DRIVE_OEN_R: R18.1 U5.4 | length 88.4
  Top Layer w5.3: U5.4@2028.71,965.53 2028.71,973.41 2047.77,992.46 2047.77,1010.18 2035.53,1022.42 2035.53,1034.66 R18.1@2031.05,1039.14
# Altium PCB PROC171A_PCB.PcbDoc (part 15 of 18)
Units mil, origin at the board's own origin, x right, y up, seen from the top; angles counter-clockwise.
Board outline 7700 x 2300 mil, 6 copper layers (Top Layer, GND 1, SIG 1, SIG 2, GND 2, Bottom Layer), stack 61.062 mil thick; 945 components, 692 nets, 11945 pads, 1734 vias.

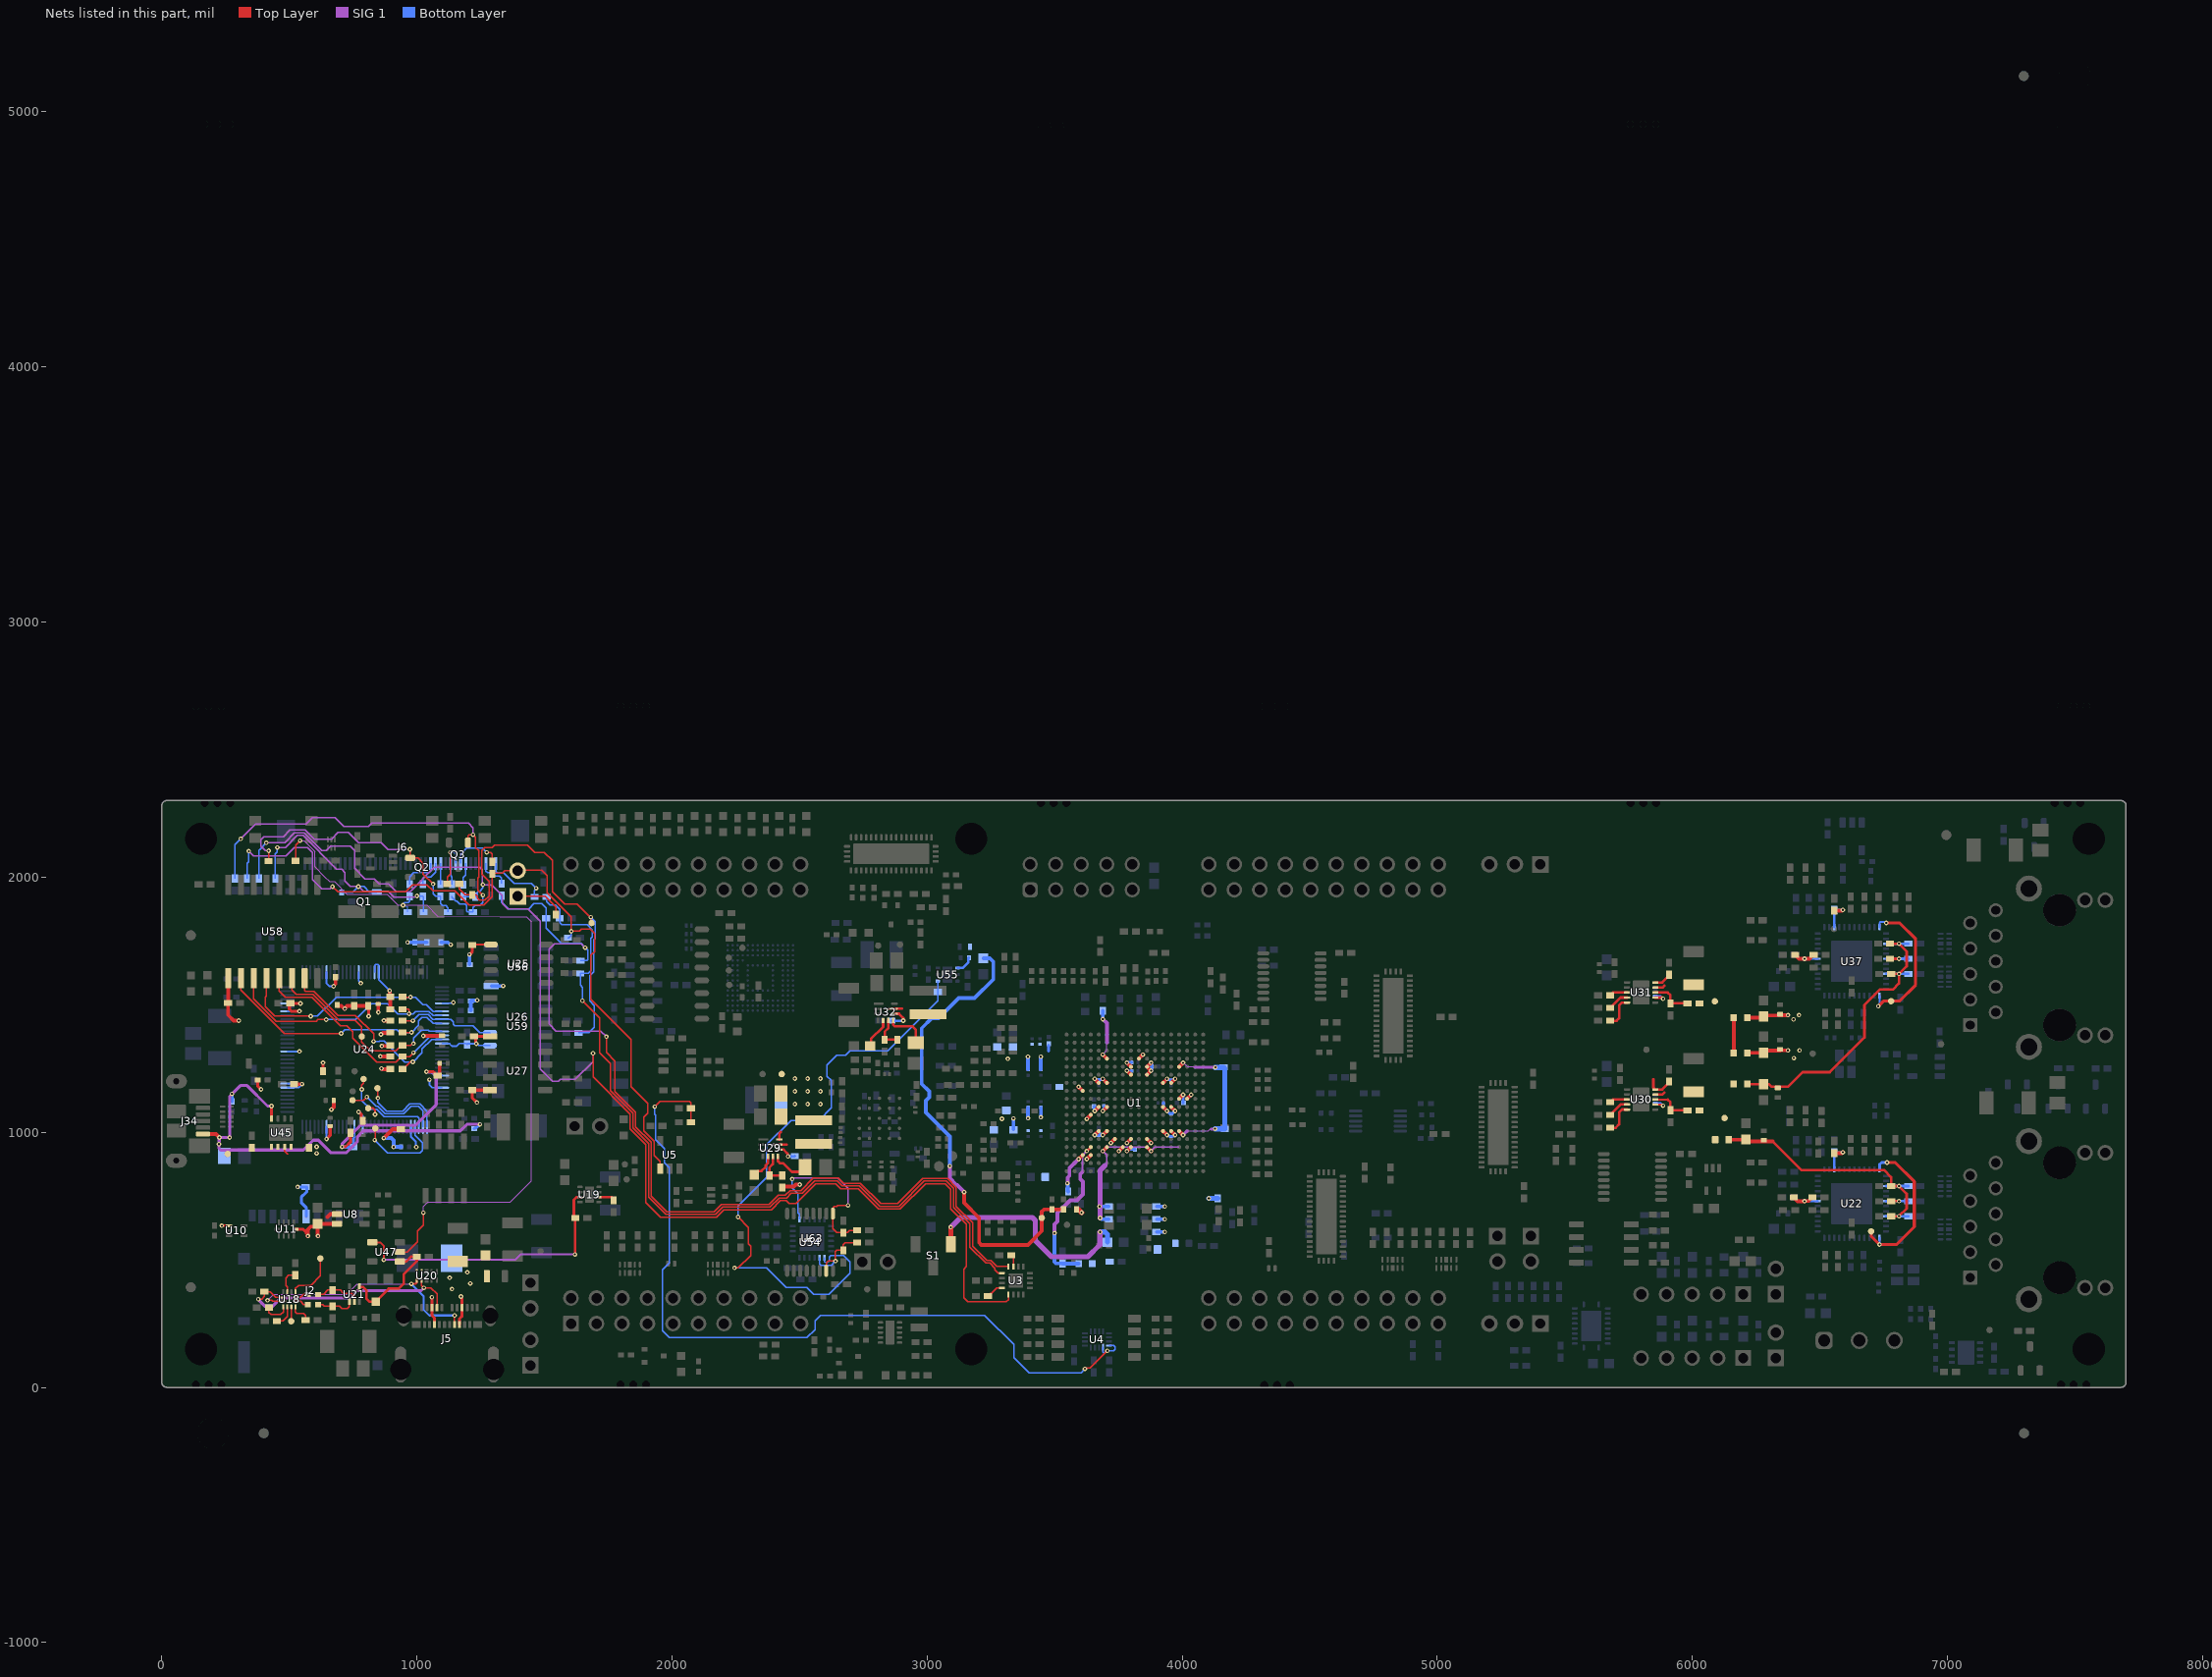
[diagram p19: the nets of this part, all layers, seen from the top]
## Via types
v1: diameter 18, hole 8, Top Layer to Bottom Layer, tented both sides, 1603 vias
v2: diameter 19.68, hole 7.87, Top Layer to Bottom Layer, tented both sides, 104 vias
v3: diameter 19.68, hole 7.87, Top Layer to Bottom Layer, 24 vias
v4: diameter 18, hole 8, Top Layer to Bottom Layer, 3 vias

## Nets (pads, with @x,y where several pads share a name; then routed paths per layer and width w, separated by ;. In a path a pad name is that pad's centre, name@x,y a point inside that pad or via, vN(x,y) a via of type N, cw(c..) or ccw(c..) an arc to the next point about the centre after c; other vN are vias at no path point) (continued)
SOP_DRIVER_OEN: R18.2 R20.1 U4.1 U4.16 | length 3221.3
  Top Layer w5.3: v1(1932.26,1100.31) 1953.49,1121.54 2068.83,1121.54 2074.3,1116.08 2074.3,1094.2 R20.1@2074.43,1094.07 R18.2@2074.43,1039.07 ; v1(3618.62,72.77) 3621.05,75.2 3638.62,75.2 v1(3706.65,143.24)
  Bottom Layer w5.3: v1(1932.26,1100.31) 1932.26,1070.44 1936.08,1066.62 1936.08,970.24 1970.28,936.04 1970.28,880.37 1989.78,860.87 1989.78,487.27 1963.14,460.63 1963.14,221.49 1990.23,194.4 2528.89,194.4 2561.1,226.61 2561.1,260.35 2583.08,282.33 3225.85,282.33 3340.56,167.63 3340.56,116.68 3399.76,57.47 3603.32,57.47 v1(3618.62,72.77) ; U4.1@3689.69,158.25 3689.69,139.37 3692.92,136.14 3696.55,136.14 3703.64,143.24 v1(3706.65,143.24) 3731.15,143.24 3736.68,148.76 3736.68,158.78 3731.31,164.16 U4.16@3713.32,164.16
TA_GPIO1: Q3.1 R185.2 R342.2 R350.1 | length 1688.9
  Top Layer w5.3: Q3.1@1200.4,2131.24 1200.4,2162.49 1203.68,2165.77 1219.77,2165.77 v1(1220,2166) 1230.58,2155.42 1230.58,2116.21 1243.13,2103.67 1243.13,2000.32 1239.14,1996.33 1239.14,1949.08 v1(1258.92,1929.29)
  SIG 1 w5.3: v1(309.92,2150.15) 367.03,2207.27 564.96,2207.27 591.69,2234 679,2234 713.7,2199.3 810.49,2199.3 822.82,2211.63 1201.87,2211.63 1220,2193.49 v1(1220,2166)
  Bottom Layer w5.3: R342.2@287,1994.62 287,2127.23 v1(309.92,2150.15) ; R350.1@1138.11,1924.76 1138.11,1920.82 1152.55,1906.38 1157.26,1906.38 1168.85,1894.79 1188.87,1894.79 1194.73,1888.93 1194.73,1867.7 1199.5,1862.94 R185.2@1220.2,1862.94 1220.2,1880.57 1228.12,1888.49 1247.43,1888.49 1258.92,1899.99 v1(1258.92,1929.29)
TA_GPIO1_R: J6.30 R350.2 | length 83.6
  Bottom Layer w5.3: J6.30@1132.64,2053.35 1132.64,2005.47 1138.11,2000 R350.2@1138.11,1972
TA_GPIO1_XDS: R341.2 U24.74 U58.2 | length 997.1
  Top Layer w5.3: U58.2@310.25,1603.6 310.25,1557.91 480.85,1387.32 v1(703.3,1387.32) ; R341.2@943.31,1390.96 v1(979.22,1390.96)
  Bottom Layer w5.3: v1(703.3,1387.32) 718.75,1402.77 921.32,1402.77 933.13,1390.96 v1(979.22,1390.96) 1007.06,1418.8 1007.06,1437.32 1020,1450.26 1039.87,1450.26 1063.4,1426.73 U24.74@1098.65,1426.73
TA_GPIO2: R184.2 R351.1 R359.2 TP18.1 | length 1532.5
  Top Layer w5.3: R351.1@1166.36,1973.49 1166.36,1953.41 1189.34,1930.42 R184.2@1216.66,1930.42 1232.5,1930.42 1237.64,1925.28 1237.64,1917.62 1245.49,1909.77 1267.07,1909.77 1283.1,1925.8 1283.1,1983.24 1253.73,2012.61 1253.73,2104.63 1265.78,2116.68 1294.68,2116.68 1304,2126 1434,2126 1463,2097 1500,2097 1531,2066 1531,1943 1579.9,1894.1 1627.88,1894.1 1679.09,1842.89 v1(1681.82,1842.89) 1683.41,1841.29 1683.41,1821.59 TP18.1@1685,1820
  Bottom Layer w5.3: R359.2@1633.91,1389.97 1673.34,1389.97 1695.59,1412.23 1695.59,1497.11 1677.72,1514.98 1677.72,1613.44 1693.26,1628.98 1693.26,1754.66 1699.12,1760.52 1699.12,1825.58 v1(1681.82,1842.89)
TA_GPIO2_R: J6.31 R351.2 | length 190.1
  Top Layer w5.3: R351.2@1119.11,1973.49 1119.11,2000.89 1131,2012.78 v1(1131,2097)
  Bottom Layer w5.3: v1(1131,2097) 1146.59,2097 1152.32,2091.27 J6.31@1152.32,2053.35
TA_GPIO2_XDS: R301.2 U24.73 U59.2 | length 389.1
  Top Layer w5.3: R301.2@943.31,1437.81 944.33,1436.79 v1(984.31,1436.79)
  Bottom Layer w5.3: v1(984.31,1436.79) 1008.38,1460.86 1044.26,1460.86 1062.65,1442.48 U24.73@1098.79,1442.48 ; U24.73@1098.79,1442.34 1133.79,1442.34 1142.66,1433.47 1142.66,1423.59 1148.55,1417.7 1219.63,1417.7 1247.33,1390 U59.2@1286.89,1390
TA_GPIO3: J1.2 R183.2 R343.2 R352.1 U5.1 | length 3048.5
  Top Layer w5.3: v1(669.14,1962.79) 669.86,1962.79 690.3,1942.36 956.76,1942.36 983.93,1969.52 1039.51,1969.52 1063.36,1945.67 1148.59,1945.67 1204,1890.25 1262.85,1890.25 1296,1923.4 1296,2015.84 1335.71,2015.84 1344.87,2025 J1.2@1395.54,2025 ; J1.2@1398,2025 1400.3,2027.3 1488.7,2027.3 1510.7,2005.3 1510.7,1937.82 1604.02,1844.5 1604.02,1789.16 v1@1604.76,1788.41 ; v1(1605.23,1787.95) v1@1604.76,1788.41 ; U5.1@1953.91,857.27 1953.91,885.43 1929.68,909.66 1929.68,964.87 1889.8,1004.74 1889.8,1059.39 1906.02,1075.61 1906.02,1113.19 1839.67,1179.54 1839.67,1362.97 1682.08,1520.57 1682.08,1694.29 1696.34,1708.55 1696.34,1779.78 1680.12,1796 1645.13,1796 1637.55,1788.41 v1@1604.76,1788.41
  SIG 1 w5.3: v1(341,2102) 359.52,2083.48 486.48,2083.48 518.82,2115.82 571.75,2115.82 590.67,2096.9 590.67,1991.22 627.7,1954.18 659.31,1954.18 667.92,1962.79 v1(669.14,1962.79)
  Bottom Layer w5.3: R343.2@334.13,1994.62 334.13,2054.02 340.81,2060.71 v1@340.81,2101.81 ; R183.2@1592.38,1762 1594.93,1762 1604.09,1771.16 1604.09,1786.8 v1(1605.23,1787.95)
TA_GPIO3_PD: J1.1 R21.2 | length 196.4
  Top Layer w5.3: J1.1@1395.54,1925 1502.6,1925 1545,1882.6 R21.2@1545,1853.25
TA_GPIO3_R: J6.32 R352.2 | length 212.4
  Top Layer w5.3: v1(1273.87,2097.16) 1290.05,2097.16 1296,2091.2 R352.2@1296,2059.62
  Bottom Layer w5.3: J6.32@1172.01,2053.35 1172.01,2091.11 1195.11,2114.22 1256.81,2114.22 v1(1273.87,2097.16)
TA_GPIO3_XDS: R340.2 U24.72 U58.3 | length 952.2
  Top Layer w5.3: U58.3@360.25,1603.6 360.25,1522.91 447.68,1435.48 605.4,1435.48 611.43,1441.5 v1(644.66,1441.5) ; R340.2@943.31,1481.93 966.39,1481.93 969.49,1478.83 v1(969.49,1464.27)
  Bottom Layer w5.3: v1(644.66,1441.5) 760.46,1441.5 822.55,1503.59 885.84,1503.59 925.15,1464.27 986.23,1464.27 995.73,1473.77 1047.7,1473.77 1063.24,1458.23 U24.72@1098.65,1458.23
TA_GPIO4: R182.2 R344.2 R354.1 U3.1 | length 5253
  Top Layer w5.3: v1(1690.74,1309.56) 1690.74,1216.22 1836.74,1070.21 1836.74,1012.83 1897.88,951.7 1897.88,724.83 1955.31,667.4 2174.55,667.4 2203.31,696.16 2389.14,696.16 2425.13,732.14 2448.04,732.14 2459.62,720.56 2485.61,720.56 2563.24,798.19 2642.28,798.19 2661.41,779.07 2730.19,779.07 2809.98,699.28 2895.07,699.28 2993.41,797.62 3071.26,797.62 3093.09,775.78 3093.09,700.37 3154.53,638.93 3154.53,473.86 3144.05,463.38 3144.05,351 3160.02,335.03 3310.03,335.03 3318.53,343.53 U3.1@3318.53,363.58
  SIG 1 w5.3: v1(410.03,2134.55) 411.01,2135.52 482.52,2135.52 520.53,2173.53 558.23,2173.53 627.58,2104.19 645.19,2104.19 662,2121 739.61,2121 756,2104.61 756,2034.1 796.57,1993.52 833.02,1993.52 852.28,1974.27 888.73,1974.27 920,1943 973,1943 1068.42,2038.42 1247.4,2038.42 1257.17,2028.65 1257.17,1971.95 v1(1258.92,1970.19) ; v1@1259.42,1970.19 1292.52,1970.19 1336.26,1926.46 1336.26,1895.72 1356.8,1875.17 1435.31,1875.17 1482.95,1827.52 1482.95,1248.59 1531.98,1199.56 1555.79,1199.56 1563.23,1207 1620.77,1207 1690.74,1276.97 v1(1690.74,1309.56)
  Bottom Layer w5.3: R344.2@381.31,1994.9 381.31,2105.9 384.41,2109 384.48,2109 v1(410.03,2134.55) ; R354.1@1182.29,1923.75 1228.05,1923.75 R182.2@1228.48,1923.32 1237.64,1932.48 1237.64,1941.66 1240.75,1944.76 1246.14,1944.76 1258.56,1957.18 1258.56,1969.83 v1(1258.92,1970.19)
TA_GPIO4_R: J6.33 R354.2 | length 86.2
  Bottom Layer w5.3: R354.2@1182.29,1971 1182.29,1998.23 1191.69,2007.63 J6.33@1191.69,2053.35
TA_GPIO4_XDS: R339.2 U24.71 U58.4 | length 907.3
  Top Layer w5.3: U58.4@410.25,1603.6 410.25,1534.58 405.26,1529.58 405.26,1492.89 443.15,1455 v1(584.18,1455) ; R339.2@943.31,1530.84 944.65,1529.5 v1(975.48,1529.5)
  Bottom Layer w5.3: v1(584.18,1455) 610.75,1455 684.44,1528.69 974.68,1528.69 v1(975.48,1529.5) ; v1@976.28,1528.69 995.85,1528.69 1023.96,1500.59 1036.63,1500.59 1063.24,1473.98 U24.71@1098.65,1473.98
TA_I2C_SCL: R191.1 R356.1 R411.2 U3.12 | length 3765.8
  Top Layer w5.3: v1(1742.84,1374.31) 1742.84,1313.39 1776.91,1279.32 1776.91,1160.02 1857.94,1079 1857.94,1021.61 1919.08,960.48 1919.08,749.65 1980.13,688.6 2165.77,688.6 2194.53,717.36 2380.36,717.36 2416.35,753.34 2444.39,753.34 2462.45,771.41 2501.24,771.41 2505.35,771.41 2554,820.06 2652.61,820.06 2672.4,800.27 2738.97,800.27 2818.76,720.48 2883.63,720.48 2981.97,818.82 3080.04,818.82 3114.29,784.57 3114.29,709.15 3178.1,645.34 3178.1,554.05 3234.61,497.54 3250.35,497.54 3274.08,473.82 U3.12@3318.53,473.82
  SIG 1 w5.3: v1(1659.51,1723.8) 1644.52,1738.8 1539.94,1738.8 1517.66,1716.52 1517.66,1424.19 1545.3,1396.55 1720.59,1396.55 v1(1742.84,1374.31)
  Bottom Layer w5.3: R356.1@1331.93,1927.43 1331.93,1902.93 1358.91,1875.95 1438.86,1875.95 1459.13,1896.23 1490.16,1896.23 1507,1879.39 R191.1@1507,1838.89 1507,1800 1567.1,1739.9 1643.41,1739.9 v1(1659.51,1723.8) 1659.51,1723.14 1669.94,1712.72 1669.94,1676.92 1665.86,1672.84 R411.2@1641.49,1672.84
TA_I2C_SCL_R: J6.37 R356.2 | length 124.2
  Bottom Layer w5.3: J6.37@1270.43,2053.35 1270.43,2024.27 1277.2,2017.5 1288.05,2017.5 1300.5,2005.04 1323.93,2005.04 1331.93,1997.04 R356.2@1331.93,1974.68
TA_I2C_SDA: R192.1 R358.1 R409.2 U3.13 | length 3270.8
  Top Layer w5.3: v1(1649.12,1515.38) 1716.8,1447.7 1716.8,1311.11 1759.04,1268.88 1759.04,1162.91 1847.34,1074.61 1847.34,1017.22 1908.48,956.09 1908.48,745.26 1975.74,678 2170.16,678 2198.92,706.76 2384.75,706.76 2420.74,742.74 2448.78,742.74 2466.84,760.81 2510.87,760.81 2559.52,809.46 2647.76,809.46 2667.55,789.67 2734.58,789.67 2814.37,709.88 2890.68,709.88 2989.02,808.22 3075.65,808.22 3103.69,780.17 3103.69,704.76 3167.5,640.94 3167.5,549.66 3230.22,486.94 3245.96,486.94 3266.36,466.54 3266.36,460.34 3278.47,448.23 U3.13@3292.94,448.23
  Bottom Layer w5.3: R358.1@1508.62,1923 1508.62,1904.02 1522.89,1889.75 1544.24,1889.75 1559.77,1874.22 R192.1@1559.77,1838.79 1559.77,1821.34 1568.22,1812.89 1667.66,1812.89 1688.52,1792.03 1688.52,1764.91 1682.66,1759.05 1682.66,1633.37 1672.02,1622.73 R409.2@1641.03,1622.73 1641.03,1576.31 1649.12,1568.22 v1(1649.12,1515.38)
TA_I2C_SDA_R: J6.39 R358.2 | length 252.5
  Bottom Layer w5.3: J6.39@1309.87,2053.28 1309.87,2022.43 1315.88,2016.43 1340.9,2016.43 1381.83,1975.5 1448.95,1975.5 v1@1467.99,1956.46 ; R358.2@1461.38,1923 1461.38,1947.01 1468.12,1953.75 v1(1468.12,1956.46)
TA_PORZ: Q1.1 R180.1 R187.2 R345.2 R347.1 | length 1056.5
  SIG 1 w5.3: v1@454,2115 484,2115 531.93,2162.93 553.84,2162.93 685.77,2031 705.7,2031 718.24,2018.47 718.24,1984.67 739.91,1963 v1(771,1963) 790.12,1943.88 887.12,1943.88 910,1921 991.91,1921 996.99,1926.07 v1(1000.42,1926.07)
  Bottom Layer w5.3: R345.2@445,1994.62 445,2090.39 453,2098.39 v1@453,2115.55 ; R180.1@706,1940.32 748.32,1940.32 v1(771,1963) 792.23,1963 813.71,1941.52 Q1.1@842.87,1941.52 ; v1(1000.42,1926.07) R347.1@1022.7,1926.07 ; R347.1@1024.02,1924.76 R347.1@1022.7,1926.07 ; R187.2@1026.05,1862.94 1026.05,1922.73 R347.1@1022.7,1926.07
  other v1: 453,2116
TA_PORZ_R: J6.27 R347.2 | length 115.6
  Bottom Layer w5.3: R347.2@1024.02,1972 1024.02,1993.66 1030.26,1999.91 1053.74,1999.91 1073.58,2019.75 J6.27@1073.58,2053.35
TA_PORZn_XDS: R338.2 U24.77 U58.5 | length 861.4
  Top Layer w5.3: U58.5@460.25,1603.6 460.25,1554.54 485.54,1529.25 588.68,1529.25 700.83,1417.11 725.42,1417.11 748.62,1393.9 748.62,1369.04 842.97,1274.7 917.51,1274.7 939.37,1296.56 R338.2@943.31,1296.56 971.67,1296.56 986.6,1311.49 v1(986.6,1311.61)
  Bottom Layer w5.3: v1(986.6,1311.61) 1053.98,1379 1098.16,1379 U24.77@1098.65,1379.49
TA_POWERDOWNZ: R188.2 R346.1 R353.2 U47.2 | length 2965.4
  Top Layer w5.3: R353.2@524.76,2064 524.76,2125.76 v1@541.85,2142.85 ; U47.2@933.63,531 962.79,531 1002.6,570.81 1002.6,612.76 1025.82,635.98 v1(1025.82,684.4)
  SIG 1 w4.75: v1(542.32,2143) v1@543,2143 ; v1@543,2143.41 558.76,2143.41 600.99,2101.18 600.99,2041.05 637.7,2003 658.05,1982.65 676.5,1982.65 725.6,1933.55 882.45,1933.55 926.25,1889.75 v1(945.6,1889.75) ; v1@948.76,1889.75 1039.1,1889.75 1082.45,1846.39 1326.11,1843.51 ccw(c1326.34,1862.76) 1326.59,1843.51 1424.3,1845 1428.24,1845 1429.63,1843.61 1448.63,1824.61 1448.63,808.22 1366.23,725.82 1043,725.82 1025.82,708.65 v1(1025.82,684.4)
  Bottom Layer w4.75: v1(945.6,1889.75) 947.82,1887.53 961.11,1887.53 963.89,1884.75 R188.2@963.89,1862.94
  Bottom Layer w5.3: v1(945.6,1889.75) 945.59,1892.58 953.18,1900.17 966.47,1900.17 971.74,1905.44 R346.1@971.74,1924.76
TA_POWERDOWNZ_R: J6.26 R346.2 | length 150.5
  Bottom Layer w5.3: R346.2@971.74,1972 971.74,2000.76 987.68,2016.7 1047.72,2016.7 1053.9,2022.88 J6.26@1053.9,2053.35
TA_PWRDNz_XDS: R336.2 U24.78 U58.7 | length 819.2
  Top Layer w5.3: U58.7@560.25,1603.6 560.25,1554.96 563.36,1551.86 596.06,1551.86 690.35,1457.57 758.75,1457.57 830.55,1385.77 v1(830.55,1356.24) ; R336.2@943.31,1248.06 947.24,1248.06 975.17,1275.98 984.23,1275.98 v1(984.54,1275.67)
  Bottom Layer w5.3: v1(830.55,1356.24) 852.9,1356.24 854.12,1357.47 870.85,1357.47 952.65,1275.67 v1(984.54,1275.67) ; v1(984.54,1275.67) 1019.82,1310.98 1019.82,1325.87 1057.69,1363.74 U24.78@1098.65,1363.74
TA_RESETZ: Q2.1 R186.2 R348.1 R349.2 | length 1097.3
  Top Layer w5.3: R349.2@418.76,2063 418.76,2102.76 v1(419,2103) ; v1(973,2109) 973.76,2108.24 Q2.1@973.76,2075.4 ; Q2.1@975,2075 1004.27,2075 1024.64,2054.63 1024.64,2012 v1(1063.57,1973.07)
  SIG 1 w5.3: v1(419,2103) 418.31,2103.69 406.31,2103.69 388.48,2121.52 388.48,2147.09 399.91,2158.52 477.52,2158.52 503.13,2184.13 562.62,2184.13 597.75,2149 664.95,2149 690.47,2174.52 731.48,2174.52 771,2135 860.51,2135 886.51,2109 v1(973,2109)
  Bottom Layer w5.3: v1(1063.57,1973.07) 1063.57,1935.42 1074.23,1924.76 R348.1@1092.26,1924.76 ; R348.1@1092.26,1924.51 1092.26,1897.03 1101.18,1888.1 1113.34,1888.1 1121.59,1879.86 R186.2@1121.59,1862.94
TA_RESETZ_R: J6.28 R348.2 | length 81.7
  Bottom Layer w5.3: R348.2@1092.26,1972 1093.25,1973 J6.28@1093.27,2053.35
TA_RESETz_XDS: R337.2 TP32.1 U24.76 U58.6 | length 816.7
  Top Layer w5.3: U58.6@510.25,1603.6 510.25,1557.01 527.42,1539.85 593.07,1539.85 693.91,1439.02 758.07,1439.02 784.17,1412.91 TP32.1@784.17,1375 784.17,1354.09 819.85,1318.42 917.26,1318.42 939.37,1340.53 R337.2@943.31,1340.53 976.2,1340.53 983.28,1347.61 v1(986.59,1347.61)
  Bottom Layer w5.3: v1(986.59,1347.61) 986.59,1368.63 1018.36,1400.4 1044.54,1400.4 1049.71,1395.24 U24.76@1098.65,1395.24
TCA_ADDR: R10.2 U3.16 | length 67
  Top Layer w5.3: R10.2@3238.62,358.58 3247.78,367.74 3252.17,367.74 3273.6,389.17 U3.16@3292.94,389.17
TCA_INTN: R11.2 U3.11 | length 46.5
  Top Layer w5.3: R11.2@3330.46,517.07 3338.21,509.32 U3.11@3338.21,473.82
TM4C129_TCK: TP27.1 U24.100 | length 361.4
  Top Layer w5.3: v1(834.93,969.22) 834.93,972.65 837.5,975.22 TP27.1@837.5,1014.87
  Bottom Layer w5.3: v1(834.93,969.22) 884.44,919.71 1011.99,919.71 1021.04,928.76 1021.04,959.02 992.35,987.71 U24.100@992.35,1021.22
TM4C129_TDI: TP29.1 U24.98 | length 389.7
  Top Layer w5.3: TP29.1@747.83,1125.66 791.27,1125.66 v1(803.8,1138.19)
  Bottom Layer w5.3: v1(803.8,1138.19) 840.65,1101.33 847.64,1101.33 876.46,1072.51 948.54,1072.51 976.75,1100.72 1007,1100.72 1023.85,1083.87 U24.98@1023.85,1021.22
TM4C129_TDO: TP30.1 U24.97 | length 348.3
  Top Layer w5.3: TP30.1@845.57,1172.78 846.44,1171.91 846.44,1135.02 v1(847.31,1134.15)
  Bottom Layer w5.3: v1(847.31,1134.15) 847.35,1134.1 847.35,1116.6 880.85,1083.11 944.15,1083.11 972.36,1111.32 1011.39,1111.32 1039.59,1083.11 U24.97@1039.59,1021.22
TM4C129_TMS: TP28.1 U24.99 | length 373
  Top Layer w5.3: v1(784.17,1168.37) 784.17,1185.32 790.12,1191.27 790.12,1207.5 TP28.1@791.17,1208.54
  Bottom Layer w5.3: v1(784.17,1168.37) 784.17,1125.66 819.11,1090.73 843.25,1090.73 872.31,1061.67 1001.81,1061.67 1008.1,1055.38 U24.99@1008.1,1021.22
TPS62913_1_EN_SYNC: R146.1 U29.1 | length 78.1
  Top Layer w10: U29.1@2420.33,931.84 2438.13,931.84 2453.47,916.5 2453.47,906.8 v1(2455,905.27)
  Bottom Layer w10: v1(2455,905.27) 2455.56,905.83 2480.69,905.83 R146.1@2481.25,906.39
TPS62913_1_FB: R153.1 R154.2 U29.9 | length 130.5
  Top Layer w10: U29.9@2395.73,905.26 2395.73,874.96 2382.33,861.57 R154.2@2382.33,830.3 R153.1@2432.33,830.3
TPS62913_1_NR_SS: C160.1 U29.8 | length 102.5
  Top Layer w10: C160.1@2322.84,833.18 2322.84,834.16 2336.54,847.86 2350.85,847.86 2367.03,864.05 2367.03,870.42 2376.04,879.44 U29.8@2376.04,905.26
TPS62913_1_SCONF: R148.2 U29.10 | length 127.9
  Top Layer w10: U29.10@2415.41,905.26 2415.41,886.62 2423.84,878.19 2436.49,878.19 2470,844.68 R148.2@2507.33,844.68
TPS62913_1_SW: L2.1 U29.2 | length 36.6
  Top Layer w10: U29.2@2413.45,951.52 2450,951.52
TPS62913_2_EN_SYNC: R156.1 U32.1 | length 95.8
  Top Layer w10: U32.1@2872.01,1464.46 2889.83,1464.46 2906.67,1447.62 v1(2906.67,1437.62)
  Bottom Layer w10: R156.1@2861.31,1436.47 v1@2905.52,1436.47
TPS62913_2_FB: R162.1 R163.2 U32.9 | length 130.5
  Top Layer w10: U32.9@2847.4,1437.88 2847.4,1407.58 2834,1394.19 R163.2@2834,1362.92 R162.1@2884,1362.92
TPS62913_2_NR_SS: C177.1 U32.8 | length 121
  Top Layer w10: C177.1@2776.59,1338.05 2780.43,1341.89 2780.43,1365.89 2827.72,1413.18 U32.8@2827.72,1437.88
TPS62913_2_SCONF: R160.2 U32.10 | length 164.5
  Top Layer w10: U32.10@2867.09,1437.88 2867.09,1422.06 2874.55,1414.59 2943.56,1414.59 2956.47,1401.68 R160.2@2956.47,1350.85
TPS62913_2_SW: L3.1 U32.2 | length 36.6
  Top Layer w10: U32.2@2865.12,1484.14 2901.67,1484.14
TPS74801_1_BIAS: R150.2 U30.4 | length 83.3
  Top Layer w10: R150.2@5677.75,1067.63 5718.86,1108.75 U30.4@5744.01,1108.75
TPS74801_1_EN: R149.2 U30.5 | length 123.2
  Top Layer w10: R149.2@5677.75,1017.63 5699.82,1017.63 5712.84,1030.65 5712.84,1077.3 5724.6,1089.06 U30.5@5744.01,1089.06
TPS74801_1_FB: R151.1 R152.2 U30.8 | length 162.4
  Top Layer w8: U30.8@5854.25,1128.43 5903.33,1128.43
  Top Layer w10: 5903.33,1128.43 5914.13,1117.63 R152.2@5914.13,1085.98 R151.1@5980.51,1085.98
TPS74801_1_PG: R147.1 U30.3 | length 70.7
  Top Layer w10: R147.1@5677.75,1117.63 5688.55,1128.43 U30.3@5744.01,1128.43
TPS74801_1_SS: C166.2 U30.7 | length 68.3
  Top Layer w8: U30.7@5854.25,1108.75 5877.91,1108.75 v1@5883.57,1103.09
  Top Layer w10: v1@5882.84,1103.83 v1(5885,1103.83)
  Bottom Layer w10: C166.2@5854.25,1112.69 5875.45,1112.69 5884.3,1103.83 v1(5885,1103.83)
TPS74801_2_BIAS: R158.2 U31.4 | length 83.3
  Top Layer w10: R158.2@5677.75,1486.82 5718.86,1527.94 U31.4@5744.01,1527.94
TPS74801_2_EN: R157.2 U31.5 | length 125.2
  Top Layer w10: R157.2@5677.75,1436.82 5703.29,1436.82 5712.84,1446.37 5712.84,1496.49 5724.6,1508.25 U31.5@5744.01,1508.25
TPS74801_2_FB: R159.1 R161.2 U31.8 | length 162.4
  Top Layer w10: U31.8@5854.25,1547.62 5903.33,1547.62 5914.13,1536.82 R161.2@5914.13,1505.17 R159.1@5980.51,1505.17
TPS74801_2_PG: R155.1 U31.3 | length 70.7
  Top Layer w10: R155.1@5677.75,1536.82 5688.55,1547.62 U31.3@5744.01,1547.62
TPS74801_2_SS: C178.2 U31.7 | length 67.2
  Top Layer w10: U31.7@5854.25,1527.94 5880.08,1527.94 v1(5885,1523.02)
  Bottom Layer w10: C178.2@5854.25,1531.87 5875.45,1531.87 5884.3,1523.02 v1(5885,1523.02)
TPS_CT: C109.1 U19.6 | length 64.7
  Top Layer w10: U19.6@1714.33,746.06 1763.07,746.06 1771.58,737.56 C109.1@1771.58,733.62
TPS_VSYS_5V0_ON: R98.1 U19.3 U47.4 | length 1108.3
  Top Layer w8: U47.4@825.37,568.4 856.6,568.4 870,555 v1(870,499.73)
  Top Layer w10: v1(1620,520.76) 1620,664.65 1615.61,669.04 1615.61,734.29 1627.39,746.06 U19.3@1639.52,746.06
  SIG 1 w8: v1(870,499.73) 1384.73,499.73 1405.76,520.76 v1(1620,520.76)
TUSB_ADDR: TP5.1 U18.5 | length 56.5
  Top Layer w5.3: TP5.1@507.51,259.31 508.07,259.87 U18.5@508.07,315.56
TUSB_EN_N: R97.2 U18.11 | length 98.2
  Top Layer w5.3: U18.11@492.32,374.61 492.24,374.69 492.24,393.2 486.21,399.23 486.21,428.62 497.39,439.79 R97.2@523.29,439.79
TUSB_ID: TP3.1 U18.9 | length 199.6
  Top Layer w5.3: U18.9@523.82,374.61 523.9,374.69 523.9,387.72 536.18,400 584.4,400 621.55,437.15 TP3.1@621.55,505.45
TUSB_OUT: DS4.1 R299.1 U21.4 U47.1 | length 447.5
  Top Layer w10: U21.4@774.98,394.13 788.32,394.13 801.98,380.48 801.98,347.94 814.26,335.65 DS4.1@838.68,335.65 890.03,387 929,387 948,406 948,442.5 999.88,494.38 R299.1@999.88,512.5 977.5,512.5 958.6,493.6 U47.1@933.63,493.6
TUSB_OUT1: R89.2 R93.2 U21.1 | length 152.9
  Top Layer w5.3: R89.2@612.51,324.31 630.69,324.31 637.07,317.93 R93.2@669.95,317.93 696.07,317.93 705.97,308.03 727.47,308.03 735.61,316.17 U21.1@735.61,335.87
TUSB_OUT1_R: R89.1 U18.7 | length 52.7
  Top Layer w5.3: U18.7@525.79,337.21 543.76,337.21 556.48,324.49 572.95,324.49 R89.1@573.14,324.31
TUSB_OUT2: R90.2 R92.2 U21.2 | length 181.4
  Top Layer w5.3: R90.2@612.51,364.41 634.16,364.41 650.82,381.07 R92.2@669.95,381.07 700,381.07 712.8,368.26 745,368.26 755.3,357.97 U21.2@755.3,335.87
TUSB_OUT2_R: R90.1 U18.8 | length 52.1
  Top Layer w5.3: U18.8@525.79,352.96 544.38,352.96 555.83,364.41 R90.1@573.14,364.41
TUSB_OUT3: R91.1 U18.6 | length 84.4
  Top Layer w5.3: U18.6@523.82,315.56 523.82,295 529.23,289.59 556.44,289.59 563.88,282.15 R91.1@563.88,263.69
TUSB_PORT: R95.2 U18.3 | length 103.4
  Top Layer w5.3: R95.2@420.03,312.6 420.03,294.23 429.26,285 466.48,285 476.58,295.1 U18.3@476.58,315.56
TUSB_VBUS_DET: R94.1 U18.4 | length 86.2
  Top Layer w5.3: R94.1@451.47,260.08 475.08,260.08 492.32,277.32 U18.4@492.32,315.56
UART/EPWM_MUX_EN: R396.1 R398.2 U54.15 U63.14 | length 315.7
  Top Layer w5.3: U54.15@2605.18,457 2605.18,487.19 2613.22,495.22 v1(2641.13,495.22) 2641.13,533 2645.36,537.23 R398.2@2671.47,537.23 2671.47,559.66 2679.39,567.58 R396.1@2725.68,567.58
  Bottom Layer w5.3: U63.14@2578.49,508.67 2578.49,484.23 2584.41,478.31 2624.47,478.31 v1@2641.13,494.97
UART/EPWM_MUX_SEL: R395.1 R397.2 U54.1 U63.1 | length 725
  Top Layer w5.3: v1(2690.18,713.16) 2650.73,713.16 2646.73,709.16 2636.22,709.16 2632.77,705.71 2632.77,683.41 U54.1@2630.77,681.41 2630.77,621.86 2646.33,606.3 R397.2@2671.47,606.3 2671.53,606.36 2688.13,606.36 2696.94,615.17 R395.1@2725.69,615.17
  SIG 1 w5.3: v1(2471.32,816.48) 2474.76,816.48 2479.48,821.2 2649.19,821.2 2690.18,780.2 v1(2690.18,713.16)
  Bottom Layer w5.3: v1(2471.32,816.48) 2471.32,781.93 2493.81,759.44 2493.81,684.37 2499.75,678.43 U63.1@2499.75,658.28
USBTYPEC_CC1: J5.A5 R439.2 U18.1 U20.4 U20.7 | length 999.7
  Top Layer w5.3: v1(378.93,345.42) 379.34,345.82 391.9,345.82 402.52,356.44 R439.2@402.52,374.61 ; R439.2@402.64,374.61 425.1,374.61 446.75,352.96 U18.1@474.61,352.96 ; U20.4@1018.85,453.43 U20.7@1018.85,420.56 1018.85,399.45 1027.76,390.54 v1(1027.76,390) 1055,390 1079.12,365.88 1079.12,312.74 J5.A5@1078.98,312.6
  SIG 1 w12: v1(378.93,345.42) 378.93,343.79 404.31,318.42 434.72,318.42 466.95,350.65 736.61,350.65 765.01,379.05 1016.82,379.05 v1(1027.76,390)
USBTYPEC_CC2: J5.B5 U18.2 U20.5 U20.6 | length 1005.2
  Top Layer w5.3: v1(414.99,341.29) 415.52,340.76 431.94,340.76 435.48,337.21 U18.2@474.61,337.21 ; J5.B5@1147.87,245.67 v1(1147.87,281.86)
  Top Layer w8: v1(978.53,405.47) 994.48,405.47 999.17,410.16 U20.5@999.17,453.43
  SIG 1 w4.75: v1(414.99,341.29) 438.02,364.33 725.24,364.33 766.42,405.5 v1(978.53,405.47)
  Bottom Layer w8: v1(978.53,405.47) 1026,358.01 1026,304.86 1049,281.86 v1(1147.87,281.86)
VBUS_TYPEC_5V0: C102.2 C103.1 D1.2 J5.A4 J5.A9 J5.B4 J5.B9 L1.1 | length 218.1
  Top Layer w11: v1(1058.97,353) 1059.13,352.84 1059.13,312.76 J5.A4@1059.29,312.6 1059.29,281.86 1069.13,272.02 J5.B9@1069.13,245.67 ; J5.B4@1167.56,245.67 1167.56,269.9 1177.4,279.74 J5.A9@1177.4,312.6 1177.4,348.15
  other v1: 1172.7,356 1137.49,385.39 1209.25,407.5 1128.42,429.5 1197.98,451
VBUS_XDS_5V0: C227.1 C231.1 J34.1 R132.2 R136.2 TP23.1 U45.1 U45.2 U45.8 | length 1755.9
  Top Layer w12: v1(430.11,1102.74) 430.11,1053.63 U45.8@430.3,1053.44
  Top Layer w15: J34.1@161.81,992.9 212.95,992.9 v1(226.14,979.71)
  SIG 1 w12: v1(430.11,1102.74) 414.87,1102.74 334.47,1183.14 308.39,1183.14 v1(275.25,1150) 275.25,1148.38 266.14,1139.26 v1(266.14,979.71) v1(226.14,979.71) 225.24,978.81 225.24,954.38 v1(224.34,953.48) 224.34,937.28 231.36,930.25 555.25,930.25 593.83,968.83 614.51,968.83 663.99,919.35 722.9,919.35 767.47,963.92 767.47,982.73 790.03,1005.29 1170.07,1005.29 1195.76,1030.99 v1(1247.27,1030.99)
  Bottom Layer w12: R136.2@275.17,1121.06 275.17,1149.93 v1(275.25,1150) ; R132.2@1225.19,1014.22 1229.03,1018.06 1234.35,1018.06 v1(1247.27,1030.99)
VDD_AM263P_1V2: C1.1 C2.1 C3.1 C19.2 C20.2 C21.2 C22.2 C29.2 C30.2 C31.2 C32.2 C39.2 C40.2 C41.2 C42.2 C44.2 C45.2 C46.2 C47.2 C49.1 C50.1 C51.1 C52.1 C53.1 C54.1 C55.1 C56.1 C157.1 C158.1 C159.1 L2.2 R153.2 TP10.1 U1.D10 U1.E9 U1.E11 U1.F9 U1.F11 U1.G5 U1.G6 U1.G13 U1.G14 U1.H3 U1.J15 U1.J16 U1.K5 U1.K6 U1.K13 U1.K14 U1.N5 U1.N6 U1.N13 U1.N14 U1.R9 U1.T4 U29.3 | length 1249.2
  Top Layer w10: U29.3@2420.33,971.21 2420.33,995.01 2426.7,1001.38
  Top Layer w15: R153.2@2432.33,783.06 2436.13,786.86 2477.26,786.86 2484.74,794.34 2500.67,794.34 v1(2501.24,794.91) ; v1(3594.38,1178.07) U1.H3@3610.13,1162.32 ; v1(3625.87,894.61) U1.T4@3641.62,910.35 ; v1(3657.37,989.09) U1.N5@3673.12,1004.84 ; v1(3657.37,1083.58) U1.K5@3673.12,1099.33 ; v1(3657.37,1209.57) U1.G5@3673.12,1193.82 ; v1(3688.87,989.09) U1.N6@3704.61,1004.84 ; v1(3688.87,1083.58) U1.K6@3704.61,1099.33 ; v1(3688.87,1209.57) U1.G6@3704.61,1193.82 ; v1(3783.35,926.1) U1.R9@3799.1,941.85 ; v1(3783.35,1241.06) U1.F9@3799.1,1225.32 ; v1(3783.35,1272.56) U1.E9@3799.1,1256.81 ; U1.D10@3830.6,1288.31 v1(3846.35,1304.06) ; U1.F11@3862.09,1225.32 v1@3876.89,1240.11 ; v1@3875,1242 3875,1243.7 3862.09,1256.61 U1.E11@3862.09,1256.81 v1(3877.84,1272.56) ; U1.N13@3925.09,1004.84 v1(3940.83,989.09) ; U1.K13@3925.09,1099.33 v1(3940.83,1083.58) ; U1.G13@3925.09,1193.82 v1(3940.83,1209.57) ; U1.N14@3956.58,1004.84 v1(3972.33,989.09) ; U1.K14@3956.58,1099.33 v1(3972.33,1083.58) ; U1.G14@3956.58,1193.82 v1(3972.33,1209.57) ; U1.J15@3988.08,1130.83 v1(4003.83,1146.57) ; U1.J16@4019.57,1130.83 v1(4035.32,1146.57)
  Bottom Layer w10: v1(3657.37,989.09) 3670.71,989.09 C56.1@3673,991.38 3675.29,989.09 v1(3688.87,989.09) ; v1(3783.35,1272.56) 3784.54,1273.75 C30.2@3802.01,1273.75 ; v1@3785.66,1239.57 C31.2@3801.86,1239.57 ; v1(3940.83,989.09) 3942.36,987.56 3946.71,987.56 3949.24,985.03 3955.68,985.03 C39.2@3956.58,984.12 ; v1(3940.83,1209.57) 3944.25,1206.15 C19.2@3956.58,1206.15 ; C39.2@3955.6,984.12 3956.5,985.03 3966.1,985.03 3970.17,989.09 v1(3972.33,989.09) ; C19.2@3956.58,1206.06 C19.2@3956.58,1206.15 ; v1(3972.33,1209.57) 3968.91,1206.15 C19.2@3956.58,1206.15
  Bottom Layer w12: 3476.56,1318.63 C49.1@3476.56,1341.5 ; C54.1@3654.78,1102.11 3654.78,1086.17 v1(3657.37,1083.58) ; v1(3657.37,1209.57) 3660.78,1206.15 C41.2@3673,1206.15 ; C41.2@3673,1206.06 C41.2@3673,1206.15 ; v1(3688.87,1083.58) 3693.17,1087.89 C46.2@3693.17,1102.11 ; v1(3688.87,1209.57) 3685.45,1206.15 C41.2@3673,1206.15 ; v1(3783.35,926.1) 3790.36,933.11 C50.1@3814.85,933.11 ; C22.2@3927.21,1115.08 3927.21,1097.2 v1(3940.83,1083.58) 3950.53,1073.89 3962.64,1073.89 v1(3972.33,1083.58) ; C55.1@4002.99,1115.08 4002.99,1145.74 v1(4003.83,1146.57)
  Bottom Layer w15: C1.1@3338.57,1012.28 v1(3338.57,1054.11) ; v1(3395.62,1295.92) 3395.84,1295.7 C44.2@3395.84,1247.05 ; C40.2@3395.84,1095.92 3395.84,1055.42 v1(3396.03,1055.23) ; C32.2@3445.84,1247.31 3445.84,1295.52 v1(3446.24,1295.92) ; v1(3445.92,1058.83) 3446.46,1059.38 C29.2@3446.46,1095.92 ; v1(3783.35,1241.06) 3784.17,1241.06 v1@3785.66,1239.57 ; v1(3877.84,1241.06) 3878.42,1241.64 3878.42,1256.6 C51.1@3879.18,1257.37 ; v1(3877.84,1272.56) 3878.42,1271.99 3878.42,1258.14 C51.1@3879.18,1257.37 ; C51.1@3879.97,1257.37 C51.1@3879.18,1257.37
  other v1: 3293.32,1052.71 2482.18,1110.22 2532.18,1110.22 2582.19,1110.22 2482.18,1160.22 2532.18,1160.22 2582.19,1160.22 2482.18,1210.22 2532.18,1210.22 2582.19,1210.22 3316.37,1288.07
VDD_ETH1_1V1_FILT: C114.1 C115.2 C116.1 C117.1 C118.1 C119.1 C120.1 C121.1 FB3.2 U22.6 U22.31 U22.39 | length 589.9
  Top Layer w10: C120.1@6779.03,729.88 v1(6810,729.88)
  Top Layer w15: FB3.2@6215.25,1311.34 6274.72,1311.34 6283.04,1319.66 6344,1319.66 6345.46,1321.12 v1(6375,1321.12) ; C119.1@6397.76,745.04 6412.91,729.88 v1(6440,729.88) 6440.57,730.46 6455.73,730.46 C118.1@6470.32,745.04 ; C116.1@6556.28,918.09 6586.71,918.09 v1(6590,921.38)
  Bottom Layer w8: U22.39@6556.28,853.9 6556.28,886.71
  Bottom Layer w10: v1(6440,729.88) U22.31@6491.32,729.88 ; 6556.28,886.71 C117.1@6556.28,921.46 6589.92,921.46 v1(6590,921.38) ; U22.6@6759.03,729.88 v1(6810,729.88) C121.1@6846.59,729.88 ; 6791.84,729.88 6826.59,729.88
  other v1: 6397.76,1290.74 6420,1321.12
VDD_ETH1_2V5_FILT: C122.1 C123.2 C124.1 C125.1 C126.1 C127.1 FB4.2 U22.3 U22.9 | length 1183.3
  Top Layer w10: 6315,963.52 6426.67,851.86 6751.7,851.86 6779.03,824.52 C126.1@6779.03,788.94 v1(6810,788.94) 6840,758.94 6840,700.83 v1(6810,670.83) C124.1@6779.03,670.83
  Top Layer w15: FB4.2@6142.49,970.9 6208.74,970.9 C122.1@6210,972.16 6218.63,963.52 6280.09,963.52 6315,963.52
  Bottom Layer w10: U22.9@6759.03,670.83 6791.84,670.83 ; U22.3@6759.03,788.94 v1(6810,788.94) C127.1@6846.59,788.94 ; 6791.84,788.94 6826.59,788.94 ; 6826.59,670.83 6791.84,670.83 ; C125.1@6846.59,670.83 v1(6810,670.83) 6791.84,670.83
VDD_ETH2_1V1_FILT: C191.1 C192.2 C193.1 C194.1 C195.1 C196.1 C197.1 C198.1 FB5.2 U37.6 U37.31 U37.39 | length 559.8
  Top Layer w10: C197.1@6775.03,1679.88 v1(6810,1679.88)
  Top Layer w15: FB5.2@6215.25,1449.44 6274.72,1449.44 C191.1@6279,1453.72 6283.04,1457.76 6344,1457.76 6345.46,1459.22 v1(6375,1459.22) ; C196.1@6402.76,1695.04 6417.91,1679.88 v1(6440,1679.88) 6458.71,1679.88 C195.1@6475.32,1696.49 ; C193.1@6556.28,1868.09 6586.71,1868.09 v1(6590,1871.38)
  Bottom Layer w9: v1(6440,1679.88) U37.31@6491.32,1679.88 ; U37.39@6556.28,1803.9 C194.1@6556.28,1871.46 ; U37.6@6759.03,1679.88 v1(6810,1679.88)
  Bottom Layer w10: C194.1@6556.28,1871.46 6589.92,1871.46 v1(6590,1871.38) ; v1(6810,1679.88) C198.1@6846.59,1679.88
  other v1: 6396.3,1442.33 6418.08,1459.11
VDD_ETH2_2V5_FILT: C199.1 C200.2 C201.1 C202.1 C203.1 C204.1 FB6.2 U37.3 U37.9 | length 1263
  Top Layer w10: FB6.2@6215.25,1188.64 6278.76,1188.64 C199.1@6278.93,1188.47 6300,1188.47 6309.86,1178.61 6334,1178.61 6374.64,1178.61 6375,1178.25 6432.19,1235.44 6538.39,1235.44 6674.39,1371.44 6674.39,1499.1 6734.47,1559.19 6785.59,1559.19 6810,1583.6 v1(6810,1620.83) ; C203.1@6775.03,1738.94 v1(6810,1738.94) 6840,1708.94 6840,1650.83 v1(6810,1620.83) ; C201.1@6779.03,1620.83 v1(6810,1620.83)
  Bottom Layer w9: U37.9@6759.03,1620.83 v1(6810,1620.83) ; U37.3@6759.03,1738.94 v1(6810,1738.94)
  Bottom Layer w10: v1(6810,1620.83) C202.1@6846.59,1620.83 ; v1(6810,1738.94) C204.1@6846.59,1738.94
VDD_ETH_1V1: C175.2 C176.1 FB3.1 FB5.1 R159.2 TP11.1 U31.9 U31.10 | length 247.4
  Top Layer w10: U31.9@5854.25,1567.31 5883.12,1567.31 5890,1574.19 ; U31.10@5854.25,1586.99 5882.39,1586.99 5909.13,1613.73 C176.1@5909.13,1617.67
  Top Layer w15: FB3.1@6162.1,1310.55 FB5.1@6162.1,1449.44
VDD_ETH_2V5: C164.2 C165.1 FB4.1 FB6.1 R151.2 TP12.1 U30.9 U30.10 | length 150.9
  Top Layer w10: 5847,1207.18 5847,1175.05 U30.10@5854.25,1167.8 5882.39,1167.8 5909.13,1194.55 C165.1@5909.13,1198.48 ; U30.9@5854.25,1148.12 5883.12,1148.12 5890,1155
VDD_XDS3V3: C139.2 C140.2 C141.2 C145.2 C146.2 C147.2 C148.2 C149.2 C150.2 C228.2 C232.2 C233.2 C250.1 C251.1 R138.2 R139.2 R140.2 R141.2 R142.2 R143.2 R144.2 R251.2 R301.1 R311.2 R312.2 R336.1 R337.1 R338.1 R339.1 R340.1 R341.1 R399.2 R400.2 R405.2 TP25.1 U24.7 U24.8 U24.16 U24.26 U24.28 U24.39 U24.47 U24.51 U24.52 U24.69 U24.79 U24.90 U24.101 U24.113 U24.122 U25.1 U26.8 U27.8 U45.3 U45.4 U56.1 U58.1 U59.1 | length 3053.8
  Top Layer w7: U45.3@481.48,943.2 481.29,943.01 481.29,926.06 492.56,914.8 493.85,914.8 ; C141.2@1217.76,1733.64 1219.59,1735.47 U25.1@1290.47,1735.47
  Top Layer w8: TP25.1@809.21,1094.23 828.41,1094.23 836.23,1086.41 v1(836.23,1070.13)
  Top Layer w12: R144.2@375.63,1204.12 375.63,1181.32 v1(389.15,1167.8) ; C145.2@518.94,1188.47 v1(550,1188.47) ; v1(540,1474.52) 539.64,1474.16 507.96,1474.16 500.19,1481.93 500.19,1505.66 C150.2@504.12,1505.66 504.62,1505.16 543.17,1505.16 v1(543.66,1504.67) ; R251.2@631.97,1238.85 v1(631.97,1272.33) ; v1(646.08,973.57) 660,987.49 C232.2@660,1020.15 ; v1@772.11,1078.76 773.46,1078.76 783,1069.23 783,1049.47 C147.2@787.63,1044.84 ; R400.2@809.19,1495.05 811.08,1493.16 v1(811.08,1455) ; v1(1206.01,1696.73) 1217.76,1708.48 C141.2@1217.76,1733.64 ; C140.2@1224.21,1376.28 1224.42,1376.5 1229.93,1376.5 U26.8@1287.35,1376.5 ; C140.2@1224.21,1376.28 1230.04,1370.47 1230.04,1352.08 1233.33,1348.78 v1(1233.33,1347.16) ; v1(1235.44,1116.58) 1216.66,1135.36 C139.2@1216.66,1165.27 U27.8@1286.73,1165.27
  Top Layer w15: U58.1@260.25,1603.6 260.05,1603.4 260.05,1506.47 C250.1@259.85,1506.27 259.85,1459.6 281.95,1437.5 v1(302.21,1437.5) ; v1(665.14,1088.76) 674.39,1098.01 C228.2@674.39,1124.76 ; v1(673.66,1572.4) 673.66,1573.21 681.33,1580.88 R311.2@681.33,1607.83 ; R312.2@688.16,1499.3 688.16,1497.34 690.51,1494.99 704.32,1494.99 v1@715.7,1483.61 ; v1@719.19,1487.09 727.14,1495.05 R399.2@754.13,1495.05 R400.2@809.19,1495.05 ; v1(848.81,1470.18) C148.2@848.81,1502.2 ; v1@857.71,1297.63 895,1297.63 R338.1@895.87,1296.76 ; v1(859.36,1383.25) 860.18,1383.25 866.63,1389.7 894.81,1389.7 R341.1@896.06,1390.96 ; v1(861.32,1249.98) 862.13,1249.98 865.29,1246.82 894.82,1246.82 R336.1@896.06,1248.06 ; v1(862.52,1337.94) 863.09,1338.52 894.05,1338.52 R337.1@896.06,1340.53 ; v1(870.05,977.12) 904.69,1011.75 R405.2@936.92,1011.75 ; v1(870.47,1437.81) R301.1@896.06,1437.81 ; v1(893.24,1554.59) 893.81,1554.02 893.81,1533.09 R339.1@896.06,1530.84 R340.1@896.06,1481.93 ; v1@1025.88,1378.5 C149.2@1098.65,1378.5
  Bottom Layer w7: U24.7@492.35,1174.76 536.3,1174.76 v1(550,1188.47) 547.96,1190.51 U24.8@492.35,1190.51 ; U24.16@492.35,1316.5 v1@539.81,1316.5 ; U24.26@492.35,1473.98 539.45,1473.98 v1(540,1474.52) ; U24.28@492.35,1505.47 542.86,1505.47 v1(543.66,1504.67) ; v1@645.89,973.76 U24.122@645.89,1021.22 ; U24.39@645.89,1627.52 645.89,1582.93 656.42,1572.4 v1(673.66,1572.4) ; U24.47@771.88,1627.52 771.88,1593.48 780.62,1584.74 v1(780.62,1584.3) ; U24.113@787.63,1021.22 787.63,1063.24 ; U24.51@834.87,1627.52 835.04,1627.69 835.04,1653.41 839.41,1657.78 846.08,1657.78 850.45,1653.41 850.45,1627.69 850.79,1627.35 850.79,1597.93 893.24,1555.48 v1(893.24,1554.59) ; v1(1049.22,1205.81) 1049.22,1186.13 1060.59,1174.76 U24.90@1098.65,1174.76 ; U24.79@1098.65,1347.99 1098.82,1347.82 1127.67,1347.82 1128.42,1347.08 1137.49,1338 1156.89,1338 1166.88,1347.99 1193.21,1347.99 C251.1@1197.04,1344.17 1200.03,1347.16 1236.31,1347.16 1243.47,1340 U59.1@1286.89,1340 ; U24.69@1098.65,1505.47 1136.69,1505.47 1140.01,1508.8 v1(1142.99,1508.8)
  Bottom Layer w8: v1@539.81,1316.5 v1(540,1316.68) ; v1@645.89,973.76 v1(646.08,973.57) ; v1(771.61,1079.26) 787.63,1063.24 ; U24.101@976.6,1021.22 976.6,981.92 995.81,962.71 995.81,944.01 v1(997.73,942.09)
  Bottom Layer w12: v1(963.57,1744.5) 963.63,1744.44 R141.2@992.24,1744.37 R141.2@992.24,1744.37 R140.2@1039.13,1744.37 ; R139.2@1093.35,1744.37 1122.36,1744.37 1131.6,1735.13 v1(1133.22,1735.13) ; v1(1206.01,1696.73) 1206.66,1696.08 1206.66,1657.04 R138.2@1207.31,1656.39 ; U56.1@1291.49,1573.29 v1(1338.45,1573.29)
  Bottom Layer w15: v1(870.05,977.12) 899.85,977.12 908.85,968.11 v1(908.85,942.03) 909.03,942.22 C146.2@938.26,942.22 ; R143.2@1211.05,1476.93 R142.2@1211.05,1514.93 1212.84,1516.72 1235.59,1516.72 v1(1236.17,1517.3)
  other v1: 606.84,917.37 607.1,943.18 856.9,1297.63 1025.37,1377.99 717.77,1484.06
VDDA18_AM263P_OSC_PLL: C38.1 FB2.2 U1.R4 | length 630.9
  Top Layer w10: v1(3625.87,926.1) U1.R4@3641.62,941.85
  SIG 1 w5: 3609.88,885.13 3609.88,910.11 v1(3625.87,926.1)
  SIG 1 w8: 3607.6,841.79 3609.88,844.07 3609.88,885.13
  SIG 1 w15: v1(3500,605) 3500,639.55 3511.53,651.08 3511.53,684.82 3560.5,733.79 3587.94,733.79 3611.05,756.9 3611.05,806.77 3601.95,815.87 3600.3,817.51 3600.3,834.5 3607.6,841.79
  Bottom Layer w15: v1(3500,605) 3500,491.86 3505.84,486.02 C38.1@3531.39,486.02 3532.41,485 FB2.2@3594.44,485
VDDA_AM263P_1V8_LDO: C33.1 C34.1 C35.1 C36.1 C37.1 FB2.1 R189.2 S1.1 U1.R6 U1.R8 U1.R11 | length 1732.4
  Top Layer w15: v1(3688.87,926.1) U1.R6@3704.61,941.85 ; v1(3751.86,926.1) U1.R8@3767.61,941.85 ; U1.R11@3862.09,941.85 v1(3877.84,926.1)
  Top Layer w20: S1.1@3093,561.06 v1(3093,627.88) ; R189.2@3586.2,697.45 3586.2,695.79 3586.36,695.63 3595.42,695.63 v1(3605.81,685.24)
  SIG 1 w5: v1(3688.87,926.1) 3704.61,941.85 3767.61,941.85 ; 3698.11,869.25 3704.49,875.62 3704.49,910.48 ; v1(3751.86,926.1) 3767.61,941.85 ; 3988.08,941.85 3893.59,941.85 v1(3877.84,926.1) 3862.09,941.85 3767.61,941.85
  SIG 1 w5.5: v1(3688.87,926.1) 3704.49,910.48
  SIG 1 w20: v1(3093,627.88) 3131.36,666.24 3412.98,666.24 3424.7,654.52 3424.7,575.28 3488.08,511.9 3494.42,511.9 3494.66,511.66 3629.74,511.66 3677.43,559.36 3677.43,608.39 v1(3678.01,608.97) ; v1(3678.01,663.97) 3678.01,850.65 3697.36,870
  Bottom Layer w12: v1@3676.49,708.97 C36.1@3712.76,708.97 ; v1(3678.01,663.97) 3683.01,658.97 C34.1@3712.76,658.97
  Bottom Layer w20: v1(3678.01,608.97) 3698.15,608.97 3707.39,599.73 C33.1@3707.39,569.08 ; v1(4104.69,740.75) C35.1@4139.44,740.75
  other v1: 3676.01,708.97
VDDA_AM263P_3V3: C25.1 C26.1 C27.1 C28.1 FB1.2 U1.P7 U1.P9 U1.P11 | length 165.1
  Top Layer w15: v1(3720.36,957.6) U1.P7@3736.11,973.35 ; v1(3783.35,957.6) U1.P9@3799.1,973.35 ; U1.P11@3862.09,973.35 v1(3877.84,957.6)
  Bottom Layer w12: C26.1@3898.93,608.97 v1(3931.68,608.97) ; C27.1@3898.93,658.97 v1(3931.68,658.97) ; C28.1@3898.93,708.97 v1(3931.68,708.97)
VDDA_ETH1_1V8: TP7.1 U22.13 U22.48 | length 622.8
  Top Layer w12: TP7.1@6700.57,611.5 6700.82,611.24 6700.82,592.62 v1(6733.44,560) 6800.59,560 6870,629.41 6870,806.84 6795.28,881.56 v1(6762.73,881.56)
  Bottom Layer w8: U22.13@6733.44,586.18 6733.44,563.47 v1@6734.74,562.17
  Bottom Layer w12: U22.48@6733.44,853.9 6733.44,873.44 6741.56,881.56 v1(6762.73,881.56)
VDDA_ETH2_1V8: TP19.1 U37.13 U37.48 | length 589.7
  Top Layer w12: v1(6729.08,1494.18) 6748.82,1513.91 TP19.1@6779.03,1513.91 6811.27,1513.91 6875,1577.64 6875,1757.84 6812.36,1820.48 v1(6760.22,1820.48)
  Bottom Layer w8: v1@6729.57,1497.3 6729.57,1497.36 6733.44,1501.24 U37.13@6733.44,1536.18 ; U37.48@6733.44,1803.9 6733.44,1819.71 6738.13,1824.39 6753.6,1824.39 6757.52,1820.48 v1(6760.22,1820.48)
  Bottom Layer w12: v1(6729.08,1494.18) v1@6729.08,1495.8
VDDC_XDS_1V0: C153.2 C154.2 C155.2 C156.2 U24.87 U24.115 | length 976.1
  Top Layer w12: v1(706.78,942.22) 707.34,942.78 720.4,942.78 740.38,962.76 C155.2@740.38,997.6 ; v1(1037.8,1237.05) 1064.6,1237.05 1071.63,1230.02 1071.63,1227.39 1077.44,1221.57 1083.44,1221.57 1089.25,1227.39 C156.2@1089.25,1270
  SIG 1 w12: v1(706.78,942.22) 707.59,943.03 707.59,955.6 779.46,1027.47 995.06,1027.47 1075.56,1107.97 1075.56,1219.85 1059.51,1235.9 1038.95,1235.9 v1(1037.8,1237.05)
  Bottom Layer w7: 751.36,975.88 756.13,980.65 U24.115@756.13,1021.22 ; v1(1037.8,1237.05) 1054.75,1237.05 1069.63,1222.18 1098.48,1222.18 U24.87@1098.65,1222.01
  Bottom Layer w12: v1(706.78,942.22) 706.97,942.04 751.17,942.04 C154.2@751.36,941.85 751.36,975.88
VDDS_AM263P_LDO_1V8: C14.1 C15.1 C16.1 C17.1 C18.1 C98.1 U1.D6 U1.E15 U1.L4 U1.N15 U1.T3 | length 1026.9
  Top Layer w15: v1(3594.38,894.61) U1.T3@3610.13,910.35 ; v1(3625.87,1052.09) U1.L4@3641.62,1067.84 ; v1(3688.87,1304.06) U1.D6@3704.61,1288.31 ; U1.N15@3988.08,1004.84 v1(4003.83,989.09) ; U1.E15@3988.08,1256.81 v1(4003.83,1272.56)
  SIG 1 w4: v1(3688.87,1304.06) 3705,1320.19 3705,1352.62
  SIG 1 w4.75: v1(4003.83,1272.56) 4019.57,1256.82 4046.43,1256.82 4049.19,1254.06 ; 4019.95,1005.22 4102.59,1005.22 4109.9,1012.53 4114.06,1012.53
  SIG 1 w12: v1(4003.83,989.09) 4019.95,1005.22 ; 4049.19,1254.06 v1(4129.81,1254.06) ; 4114.06,1012.53 4127.88,1012.53 v1(4129.02,1013.68)
  SIG 1 w15: v1(3550.2,800.12) 3550.78,800.69 3550.78,821.4 3557.88,828.51 3557.88,858.11 v1(3594.38,894.61) ; v1(3688.87,1443.54) 3705,1427.4 3705,1352.62
  Bottom Layer w15: v1(3550.2,800.12) 3550.78,799.54 3550.78,770.22 C15.1@3553.63,767.37 ; v1(3688.87,1443.54) C16.1@3688.87,1476.28
  Bottom Layer w20: v1(4129.02,1013.68) 4129.38,1013.32 C17.1@4167.23,1013.32 4167.23,1249.74 4162.92,1254.06 C18.1@4162.56,1254.06 v1(4129.81,1254.06)
VPP_AM263P_1V7: C255.2 C256.1 R190.2 R360.2 R362.2 TP33.1 U55.1 | length 1927.7
  Top Layer w15: v1(3145.44,765.54) 3145.44,722.88 3204.15,664.16 3204.15,567.38 3212.94,558.59 3395.53,558.59 3449.69,612.75 3449.69,688.66 3458.48,697.45 R190.2@3535,697.45
  SIG 1 w15: v1(3089.05,867.26) 3089.05,819.04 3115.52,792.58 3118.4,792.58 v1(3145.44,765.54)
  Bottom Layer w10: U55.1@3118.65,1643.59 3140.03,1643.59 3161.17,1664.74 3161.17,1681.51 C255.2@3164.05,1684.38
  Bottom Layer w15: v1(3089.05,867.26) 3089.05,983.01 2994.6,1077.46 2994.6,1123.45 3009,1137.86 3009,1159.93 2979.01,1189.92 2979.01,1407.79 3018.84,1447.62 3045.57,1447.62 3123.92,1525.97 3186.15,1525.97 3259.91,1599.73 3259.91,1668.64 3246.24,1682.31 R362.2@3223.04,1682.31
VPP_LDO_EN: R364.2 U55.4 U63.13 | length 2415.1
  Top Layer w5.3: v1(2245.22,468.12) 2245.71,467.63 2259.06,467.63 2308.93,517.5 2308.93,553.54 2300.47,562 2300.47,626.55 v1(2259.12,667.89)
  Bottom Layer w5.3: v1(2245.22,468.12) 2371.54,468.12 2448.62,391.04 2528.13,391.04 2555.45,363.71 2614.45,363.71 2698.7,447.96 2698.7,492.24 2673.31,517.62 2622.88,517.62 2616.36,511.1 2616.36,495.03 2610.24,488.91 2601.28,488.91 2598.18,492.02 U63.13@2598.18,508.67 ; v1(2259.12,667.89) 2259.12,711.91 2370.73,823.52 2370.73,951.21 2466.04,1046.53 2575.79,1046.53 2624.36,1095.1 2624.36,1203.34 2608.12,1219.59 2608.12,1262.95 2646.28,1301.11 2680.27,1301.11 2698.26,1319.1 2845.58,1319.1 3042.63,1516.14 R364.2@3042.63,1550.16 3041.88,1550.91 U55.4@3041.88,1592.41
VSD_3V3: C67.1 C71.2 J2.4 U8.5 U8.6 U10.1 U11.10 | length 498.8
  Top Layer w10: v1(235,633.9) U10.1@263.65,633.9
  Top Layer w12: U11.10@523.63,620 553.44,620 569.16,604.28
  Top Layer w15: 569.16,604.28 569.16,614.57 584.83,630.23 600.07,630.23 C67.1@611.03,641.19 ; 569.16,612.85 572.43,609.58 572.43,593.76 v1(573.01,593.18) ; v1(612.25,593.18) 612.25,594 611.03,595.22 C67.1@611.03,641.19 ; 650,667.85 660.75,678.6 U8.5@686.89,678.6 ; U8.6@686.89,641.19 C67.1@611.03,641.19
  Bottom Layer w12: v1(532.67,785.81) 567.73,785.81 568.11,785.43 568.11,766.13 547.13,745.14 547.13,723.87 566.06,704.93 J2.4@566.06,669.61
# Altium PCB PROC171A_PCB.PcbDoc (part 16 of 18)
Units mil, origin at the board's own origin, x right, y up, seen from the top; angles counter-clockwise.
Board outline 7700 x 2300 mil, 6 copper layers (Top Layer, GND 1, SIG 1, SIG 2, GND 2, Bottom Layer), stack 61.062 mil thick; 945 components, 692 nets, 11945 pads, 1734 vias.

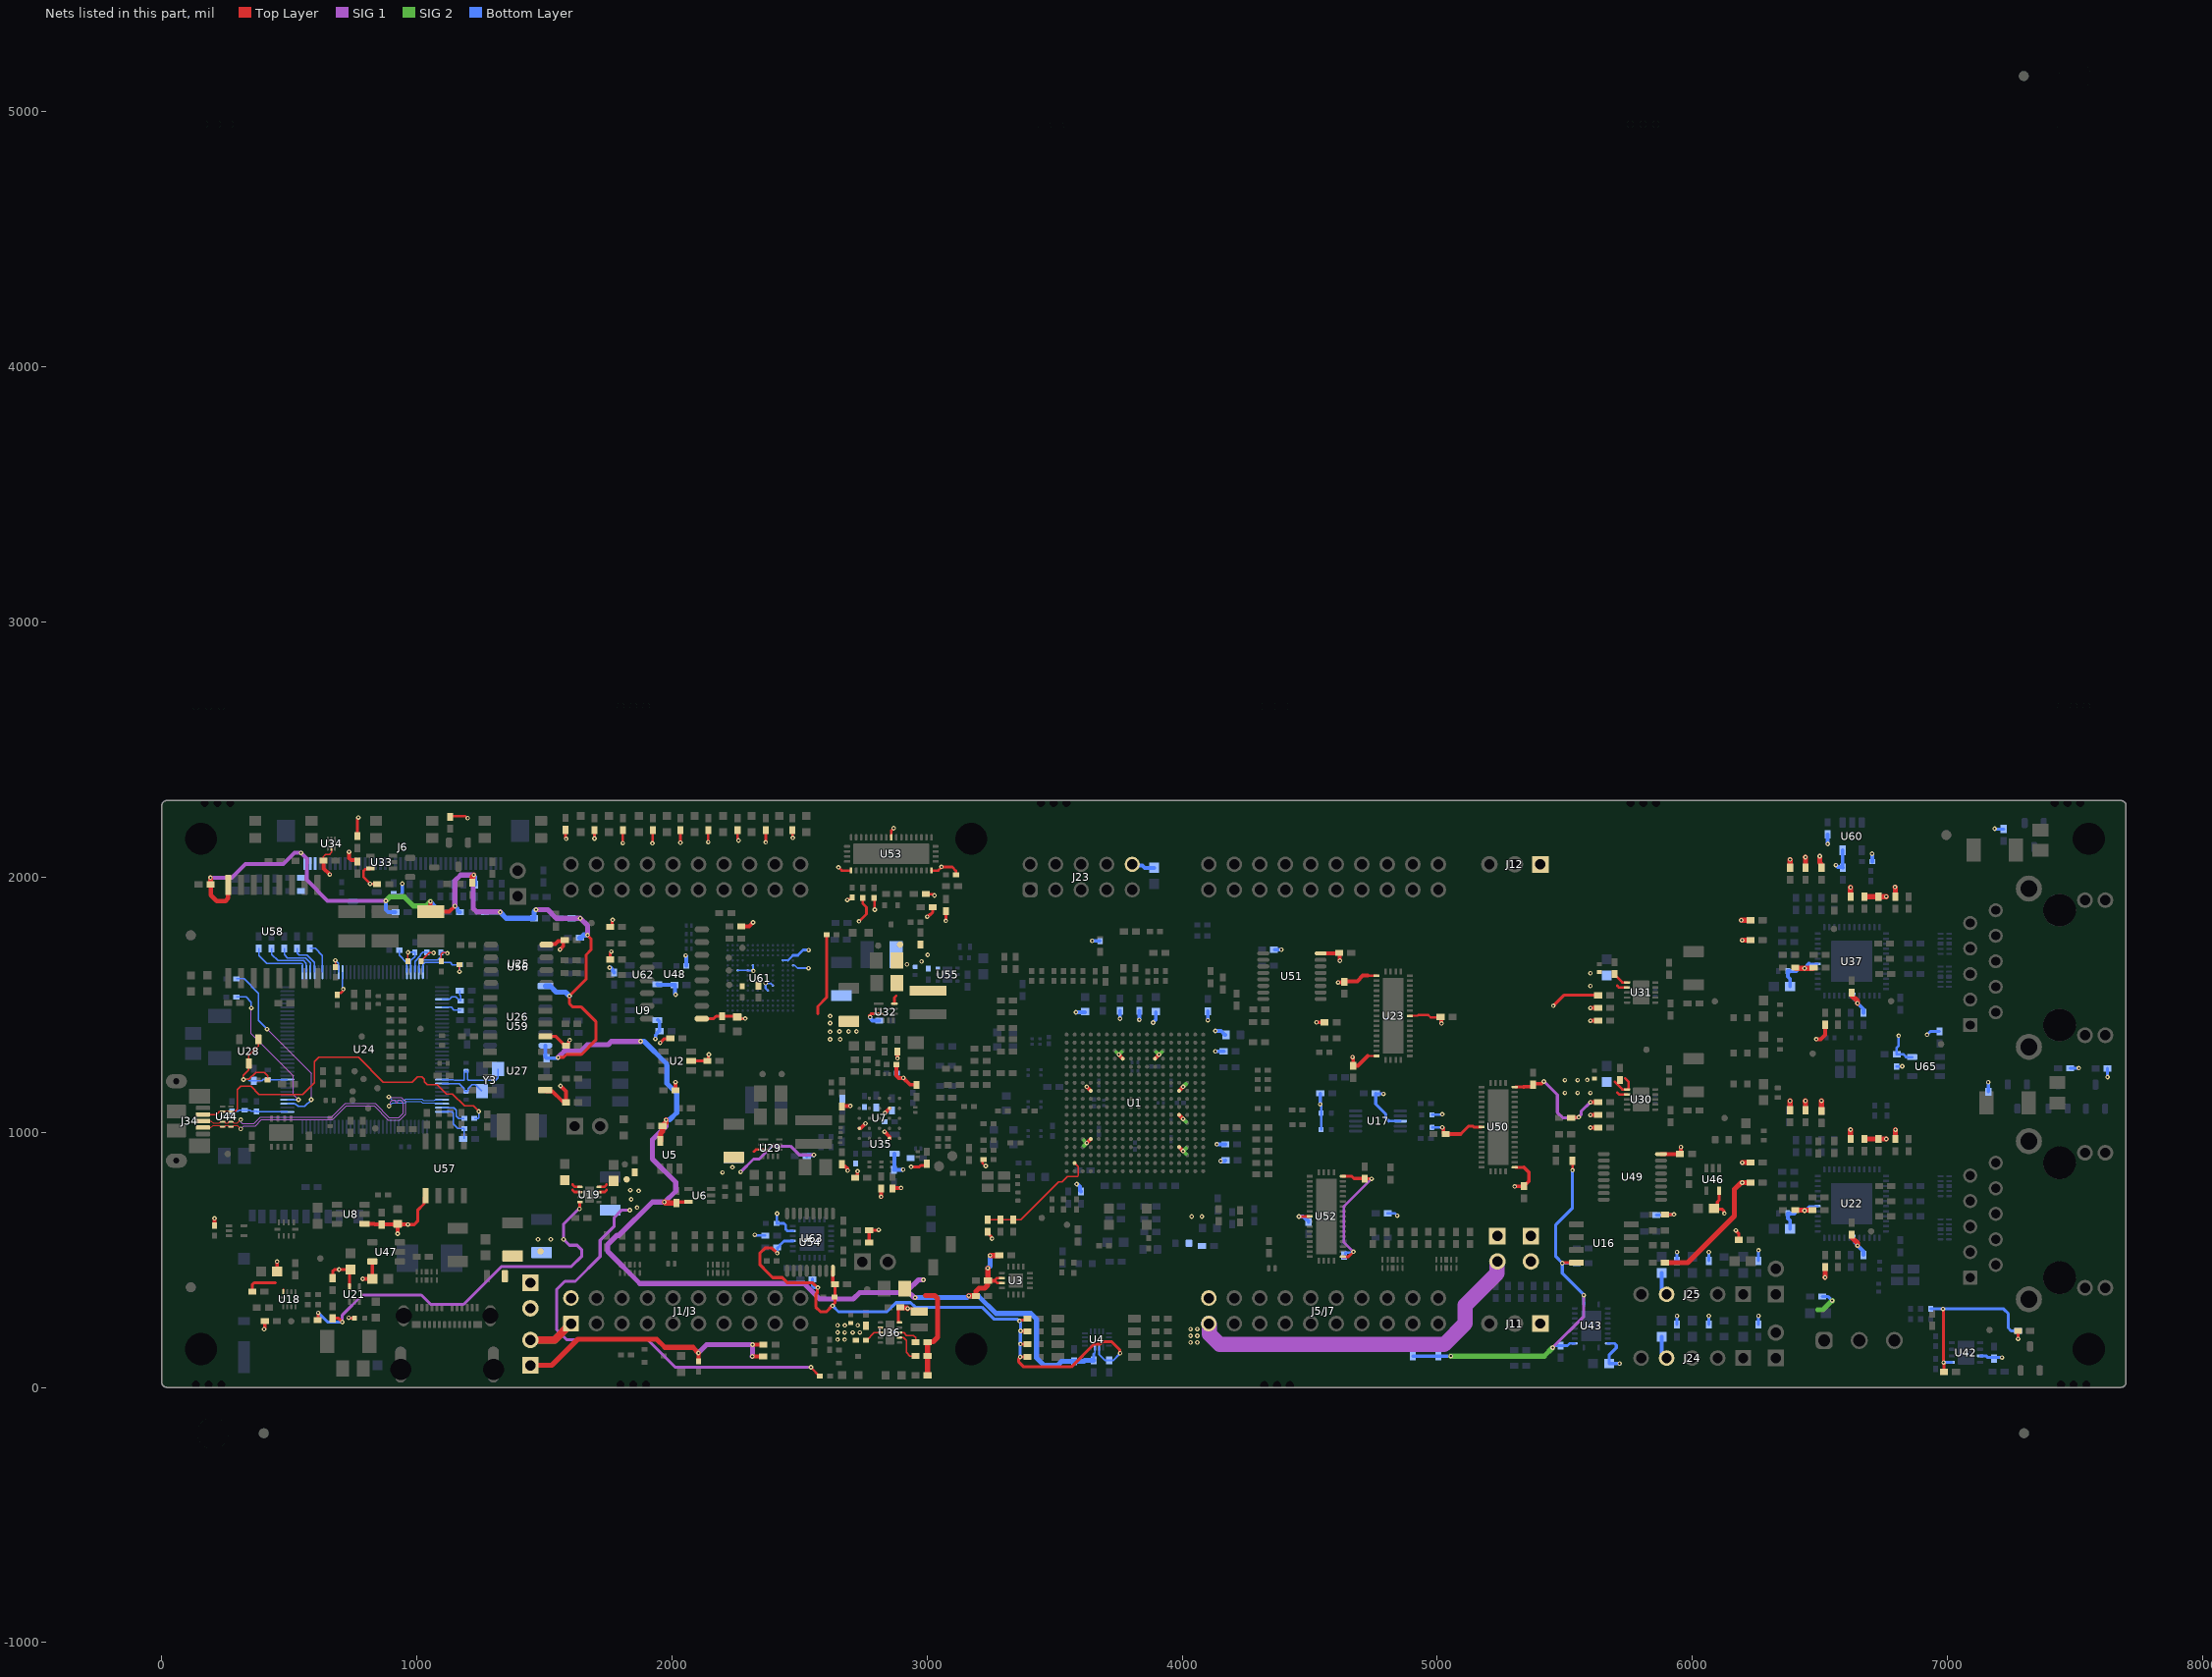
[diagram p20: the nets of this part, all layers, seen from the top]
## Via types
v1: diameter 18, hole 8, Top Layer to Bottom Layer, tented both sides, 1603 vias
v2: diameter 19.68, hole 7.87, Top Layer to Bottom Layer, tented both sides, 104 vias
v3: diameter 19.68, hole 7.87, Top Layer to Bottom Layer, 24 vias
v4: diameter 18, hole 8, Top Layer to Bottom Layer, 3 vias

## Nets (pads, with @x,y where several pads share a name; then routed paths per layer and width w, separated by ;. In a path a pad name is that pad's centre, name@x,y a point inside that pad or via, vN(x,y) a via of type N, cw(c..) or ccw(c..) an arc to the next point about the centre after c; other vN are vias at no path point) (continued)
VSYS_3V3: C4.1 C5.1 C6.1 C7.1 C8.1 C9.1 C10.1 C11.1 C12.1 C13.1 C24.1 C43.2 C57.2 C62.2 C66.1 C68.1 C69.1 C70.2 C99.2 C100.2 C111.2 C128.1 C129.2 C130.1 C131.1 C132.1 C133.1 C136.2 C137.2 C138.2 C169.1 C170.1 C171.1 C181.2 C182.2 C205.1 C206.2 C207.1 C208.1 C209.1 C210.1 C213.1 C223.2 C226.2 C236.1 C237.1 C238.2 C239.2 C240.2 C241.2 C242.2 C243.2 C244.2 C245.2 C246.2 C248.1 C253.2 C254.1 C258.1 C259.1 C260.1 C261.1 C263.1 C264.1 C265.1 C267.1 C268.1 C269.1 C270.1 C271.1 C272.1 FB1.1 J9.1 J12.1 J13.1 J23.10 L3.2 R14.1 R15.1 R16.1 R17.1 R31.1 R40.2 R41.2 R55.2 R56.2 R63.2 R64.2 R73.2 R74.2 R108.2 R109.2 R110.2 R111.2 R112.2 R113.2 R114.2 R115.2 R116.2 R147.2 R155.2 R162.2 R175.2 R176.2 R177.2 R178.2 R179.2 R181.2 R203.2 R204.2 R205.2 R206.2 R207.2 R208.2 R209.2 R210.2 R211.2 R224.1 R226.2 R228.2 R230.1 R232.2 R234.2 R244.2 R258.2 R262.2 R263.2 R264.2 R266.2 R267.2 R268.2 R269.1 R270.1 R271.1 R273.2 R277.2 R279.2 R287.1 R288.1 R291.1 R292.1 R295.2 R296.2 R298.1 R305.1 R306.1 R313.2 R314.2 R318.1 R319.1 R320.1 R367.1 R368.1 R369.1 R370.1 R371.1 R372.2 R373.1 R374.1 R375.2 R383.2 R384.2 R385.2 R386.2 R387.2 R388.2 R389.1 R390.1 R395.2 R396.2 R417.1 R418.2 R420.1 R421.2 R422.2 R424.1 R425.2 R426.2 R435.2 R441.1 TP9.1 U1.D8 U1.D12 U1.H4 U1.H15 U1.L15 U1.P4 U1.R15 U2.5 U4.2 U7.B4 U7.D1 U7.E4 U8.1 U9.5 U16.8 U17.8 U22.18 U22.30 U23.1 U23.17 U23.30 U25.8 U26.1 U27.1 U32.3 U33.5 U34.5 U35.5 U37.18 U37.30 U42.5 U43.2 U43.10 U46.5 U48.1 U49.16 U50.1 U50.17 U50.30 U51.16 U52.1 U52.17 U52.30 U53.1 U53.17 U53.30 U54.16 U55.6 U57.1 U60.5 U61.C6 U61.E6 U61.F5 U61.J10 U61.K9 U61.M4 U61.N4 U61.P3 U61.P5 U62.5 U63.21 U63.23 U65.5 | length 16821.4
  Top Layer w5.3: R373.1@2666.41,1100.18 R373.1@2669.26,1103.03
  Top Layer w6: C181.2@633.69,2065 633.69,2080.21 642.62,2089.14 657.83,2089.14 665,2096.31 U34.5@665,2115.47
  Top Layer w9: v1(816.9,1974) 817.4,1973.5 843.88,1973.5 R178.2@844.38,1973 ; R181.2@1141,2239.24 1189.42,2239.24 1196.67,2232 v1@1198,2232 ; R31.1@3221.22,893.53 3217.83,890.14 3217.83,878.19 3228.11,867.9 v1(3230,867.9) ; 4727.19,1299.02 U23.17@4762.24,1299.02 ; 4727.19,1613.98 U23.1@4762.24,1613.98 ; U23.30@4892.17,1456.5 4922.54,1456.5 4925.88,1459.84 4964.3,1459.84 4974.18,1449.96 C242.2@5007.48,1449.96
  Top Layer w10: v1(816.9,1974) 791.14,1999.77 791.14,2024.68 796.99,2030.54 814.83,2030.54 U33.5@817.71,2033.41 ; v1(1807.17,2133.55) 1807.38,2133.76 R273.2@1807.38,2183.75 ; v1(1923.65,2132.86) 1925,2134.21 R267.2@1925,2183.75 ; v1(2033.04,2135.03) 2033.08,2135.07 R266.2@2033.08,2183.75 ; v1(2142.37,2137.13) R264.2@2142.37,2183.75 ; R263.2@2257.41,2183.75 2257.81,2183.35 2257.81,2148.83 2261.11,2145.53 v1(2261.11,2143.37) ; R313.2@2471.37,2183.75 2472.52,2182.61 2472.52,2155.15 v1(2473.66,2154) ; v1(2652.85,2038.48) 2665.26,2026.07 U53.1@2702.31,2026.07 ; v1(2687.45,1910.15) 2689.61,1910.15 2692.65,1913.19 2702.12,1913.19 2706.97,1918.03 R386.2@2706.97,1920 ; v1(2733.03,1826.55) 2762.3,1855.82 2762.3,1881.69 2748.06,1895.93 R385.2@2748.06,1918.73 ; R384.2@2792.16,1918.73 2793.47,1917.43 2793.47,1873.66 v1(2794.77,1872.35) ; U53.30@2859.79,2156 2859.79,2182.2 v1(2869.12,2191.54) ; U32.3@2872.01,1503.83 2872.01,1527.63 2878.37,1534 ; R390.1@2995.07,1933.65 2996.23,1932.49 3022.24,1932.49 3026.68,1928.05 v1(3028.85,1928.05) ; U53.17@3017.27,2026.07 3044.09,2026.07 3056.34,2038.32 v1(3056.34,2040.18) ; v1@3058.41,2037.88 3060.47,2039.94 3098.44,2039.94 3113.43,2024.96 R383.2@3113.43,2009.27 ; v1(5530,851.27) R287.1@5530,887.92
  Top Layer w11: v1(4457.78,670) U52.30@4500.04,670 ; U52.1@4629.96,512.52 4652.57,512.52 v1(4671.54,531.49) ; 5118.5,1020.04 5121.84,1023.38 5140,1023.38 5143.35,1020.04 U50.30@5173.43,1020.04 ; U50.1@5306.3,862.56 5340,862.56 ; U50.17@5306.3,1177.52 5335,1177.52
  Top Layer w12: R179.2@766.92,2161.01 766.92,2227.63 771.01,2231.71 v1(771.01,2233.34) ; v1(965,638.11) 990.19,638.11 1002.95,650.87 1002.95,693.88 1028.7,719.63 1028.7,745.36 U57.1@1034.51,751.17 ; U26.1@1503.89,1376.5 1543.82,1376.5 1580.31,1340 C137.2@1584.25,1340 ; R279.2@1583.17,2184.88 1583.17,2153.94 1585.36,2151.76 v1(1585.36,2150.13) ; C137.2@1588.19,1340 1594,1345.81 1594,1354.54 1599.12,1359.66 v1(1599.12,1361.29) ; v1(1696.59,2151.19) R277.2@1696.59,2183.75 ; R270.1@1757.31,1676.88 1757.31,1701.41 1762.48,1706.58 v1(1762.48,1708.2) ; R271.1@1757.31,1804.54 1760.49,1804.54 1766.3,1810.35 1766.3,1831.24 v1(1767.45,1832.38) ; v1(1953.67,1350.09) 1970.55,1366.97 1992.98,1366.97 R296.2@1993.85,1367.85 ; U2.5@2075.37,1279.45 C57.2@2138.78,1279.45 2143.37,1284.04 2143.37,1303.78 v1(2144.52,1304.92) ; U48.1@2117.28,1445 2163.57,1445 2173.16,1454.6 2195.54,1454.6 C237.1@2195.94,1455 2255.94,1455 2265.36,1445.59 v1(2287.13,1445.59) ; v1(2367.5,2136.37) R262.2@2367.5,2183.75 ; v1(2412.62,526) 2392.46,546.16 2365.03,546.16 2344.33,525.47 2344.33,481.83 2357.28,468.89 2357.28,467.5 2394.56,430.22 2432.58,430.22 2453.42,409.38 2551.9,409.38 2570.18,391.1 v1(2571.79,391.09) 2570.66,389.95 2570.66,371.21 2563.85,364.41 2563.85,315.01 2582.25,296.61 2606.09,296.61 v1(2629.26,319.79) 2629.26,321.41 2638.97,331.12 C260.1@2638.97,404.5 2636.58,404.5 2630.77,410.31 U54.16@2630.77,457 ; R396.2@2772.92,567.58 R395.2@2772.93,615.17 2773.17,615.41 2807.31,615.41 2808.83,616.92 v1(2810.45,616.92) ; v1(2937.48,864.39) 2969.8,864.39 2975.46,870.05 2993.6,870.05 2999.42,875.86 R370.1@2999.42,876.56 ; v1(3000.45,1844.7) 3002.07,1844.7 3009.35,1851.98 3011.79,1851.98 3021.93,1862.12 R258.2@3021.93,1881.79 ; v1(3073.76,1828.84) 3073.88,1828.96 3073.88,1866.45 R389.1@3074.01,1866.58 ; v1(3361.97,260.35) 3363.59,260.35 3367.31,264.06 3388.22,264.06 R17.1@3393.58,269.43 ; v1(3366.13,170.12) 3366.43,169.81 3388,169.81 R15.1@3388.31,169.51 ; v1(3366.47,221.17) 3367.3,220.34 3387.47,220.34 R16.1@3388.31,219.51 ; R14.1@3388.31,119.51 3388.25,119.57 v1(3365.28,119.57) 3365.28,117.94 3359.46,112.12 3359.46,99.6 3378.75,80.31 3565.24,80.31 3654.46,169.53 3679.02,169.53 3688.87,179.37 3722.55,179.37 3755.75,146.17 3755.75,135 v1(3756.9,133.85) ; v1(4526.3,1430.83) 4526.37,1430.9 R288.1@4558.11,1430.9 ; U52.17@4629.96,827.48 4664.88,827.48 4673.74,818.62 4713.94,818.62 C245.2@4715,817.56 4715.22,817.34 4742.34,817.34 v1(4742.56,817.13) ; 5091.28,992.82 5118.5,1020.04 ; v1(5454.93,1495.58) 5496.17,1536.82 R155.2@5630.51,1536.82 ; v1(5490,487.03) 5492.11,489.14 U16.8@5545.51,489.14 ; R292.1@5525,1057.02 5525.95,1057.96 5553.8,1057.96 v1(5554.74,1058.91) ; R320.1@5892.56,676.73 5893.19,677.36 5926.99,677.36 v1(5927.62,677.99) ; C248.1@6084.69,701.15 6095.59,701.15 C248.1@6096.97,699.77 ; C248.1@6095.59,698.38 C248.1@6096.97,699.77 ; U46.5@6105.59,770.71 6105.59,735.19 6098.04,727.64 6098.04,700.83 C248.1@6096.97,699.77 ; v1(6125.61,681.8) 6124.46,682.95 6124.46,689.73 6115.35,698.84 6097.9,698.84 C248.1@6096.97,699.77 ; v1@6985,305 v1(6982.5,307.5) 6982.5,305.88 6985,303.38 v1(6985,97.8) 6985,96.18 6986.38,94.8 C226.2@6986.38,60.4 ; v1(7276.76,190) R226.2@7276.76,221.46
  Top Layer w13: R368.1@2718.18,822.18 2721.52,822.18 2726.83,827.49 2726.83,846.51 v1(2727.79,847.46)
  Top Layer w15: R40.2@206.73,633.9 v1(206.73,662.32) ; C181.2@633.69,2065 633.69,2061.63 634.63,2060.69 634.63,2034.3 v1(658.51,2010.42) ; v1(734,2099) 734,2074.96 742.79,2066.17 762.61,2066.17 766.92,2061.86 C182.2@766.92,2060.93 ; U8.1@795.16,641.19 831.92,641.19 835,638.11 862.05,638.11 C69.1@862.1,638.16 C68.1@924.76,638.16 ; v1(924.76,602.5) C68.1@924.76,638.16 ; v1(965,638.11) 964.95,638.16 C68.1@924.76,638.16 ; U27.1@1503.27,1165.27 1507.58,1160.95 1530.75,1160.95 1570.17,1121.54 1579.94,1121.54 C136.2@1584.25,1117.23 1584.25,1160.18 v1(1563.02,1181.42) ; U25.8@1507.47,1735.47 1509.12,1737.12 1542.72,1737.12 1554.49,1748.88 C138.2@1574.14,1748.88 ; v1(1561.05,1715.89) 1561.05,1716.29 1574.14,1729.38 C138.2@1574.14,1748.88 ; R295.2@2013.62,1163.59 v1(2013.62,1196.23) ; R314.2@2103.52,101.58 v1(2103.52,135) ; R269.1@2271.43,1807.3 2302.39,1807.3 v1(2317.76,1822.66) ; v1(2315.03,121.54) 2315.3,121.27 2357.07,121.27 R56.2@2357.34,121 ; v1(2315.95,167.34) R55.2@2358.71,167.34 ; R367.1@2666.59,874.69 2666.59,870.75 2670.9,866.44 2678.45,866.44 2687.24,857.65 2687.24,851.9 2688.74,850.4 v1(2688.74,849.59) ; R373.1@2669.26,1103.03 v1(2699.61,1103.03) ; U7.D1@2734.55,1015.18 2739.69,1015.18 v1(2758.71,1034.2) ; v1(2819.63,747.21) 2819.86,747.45 2819.86,778.85 R374.1@2820.1,779.08 ; v1(2832.97,1002.22) 2852.66,982.54 U7.E4@2852.66,975.81 ; v1(2834.92,1076.01) 2834.92,1076.18 U7.B4@2852.66,1093.92 ; R369.1@2863.91,779.08 2866.18,781.35 2897.42,781.35 v1(2897.99,781.92) ; R375.2@2880,1265.09 2880,1221.72 2888.79,1212.93 v1@2906.97,1212.93 ; v1(2884,1290.09) R162.2@2884,1315.68 ; v1(2907.27,1213.38) 2907.27,1212.73 2933.67,1186.32 2958.56,1186.32 R372.2@2959.2,1185.69 ; v1(3625.87,957.6) U1.P4@3641.62,973.35 ; v1(3625.87,1178.07) U1.H4@3641.62,1162.32 ; v1(3751.86,1304.06) U1.D8@3767.61,1288.31 ; U1.D12@3893.59,1288.31 v1(3909.34,1304.06) ; U1.R15@3988.08,941.85 v1(4003.83,926.1) ; U1.L15@3988.08,1067.84 v1(4003.83,1052.09) ; U1.H15@3988.08,1162.32 v1(4003.83,1178.07) ; U51.16@4542.46,1701.23 4542.61,1701.37 4614.26,1701.37 C246.2@4615.42,1702.53 4617.88,1700.07 4617.88,1672.92 v1(4618.45,1672.35) ; v1(4611.01,1586.96) 4631.56,1586.96 C241.2@4635.87,1590.04 ; C241.2@4636.62,1591.6 4685.93,1591.6 4708.31,1613.98 4727.19,1613.98 ; v1(4668.09,1294.53) 4668.09,1293.72 4670.38,1291.42 C240.2@4670.38,1260.47 4688.64,1260.47 4727.19,1299.02 ; C242.2@5013.22,1449.96 5013.95,1449.96 5016.27,1447.64 5016.27,1426.92 v1(5016.84,1426.35) ; v1(5019.79,1018.97) 5019.79,1018.15 5024.37,1013.57 5024.37,997.13 5028.69,992.82 C111.2@5032.62,992.82 5091.28,992.82 ; v1(5303.35,787.43) 5303.83,787.91 5339.4,787.91 C239.2@5339.88,788.39 5359.07,807.58 5359.07,843.49 5340,862.56 ; 5338.41,1177.52 5339.58,1178.69 5376.11,1178.69 C238.2@5376.11,1186.15 5376.11,1190.09 5408.34,1190.09 5417.33,1199.07 v1(5418.14,1199.07) ; v1(5600,1117.63) R147.2@5630.51,1117.63 ; U49.16@5877.2,914.8 C43.2@5951.38,914.8 5955.31,918.73 v1(5955.31,941.85) ; v1(6485.13,1364.7) 6502.57,1364.7 6520,1382.14 R209.2@6520,1421.38 ; C138.2@1574.14,1748.88 1575.83,1748.88 C138.2@1580.15,1753.19 1578.45,1753.19 C138.2@1574.14,1748.88
  Top Layer w20: J9.1@1445,86.05 1528.4,86.05 1631.19,188.84 1939.95,188.84 1972.25,156.54 2081.98,156.54 v1(2103.52,135) ; R318.1@5892.56,488.21 5981.22,488.21 6165,672 6165,776.17 6191.38,802.54 v1(6195.06,802.54) ; v1@6191.49,802.65 R108.2@6227.68,802.65 ; v1(6195.06,1752.54) 6195.16,1752.65 R203.2@6227.76,1752.65 ; v1(6195.24,880.85) 6195.35,880.96 R109.2@6227.76,880.96 ; v1@6196.38,1830.85 v1(6191.38,1830.85) 6191.49,1830.96 R204.2@6227.76,1830.96 ; v1@6382.9,1117.97 v1(6382.9,1122.97) 6383.01,1122.86 R115.2@6383.01,1086.58 ; v1(6382.9,2069.21) 6383.01,2069.11 R210.2@6383.01,2036.59 ; C133.1@6402.76,695.04 6437.44,695.04 v1(6440,692.48) 6442.56,695.04 C132.1@6470.32,695.04 ; C210.1@6402.76,1645.04 6405.32,1642.48 v1(6440,1642.48) 6472.76,1642.48 C209.1@6475.32,1645.04 ; v1@6442.9,1117.97 v1(6442.9,1122.97) 6443.01,1122.86 R116.2@6443.01,1086.59 ; v1(6442.9,2077.97) 6443.01,2077.86 R211.2@6443.01,2036.59 ; v1(6499.43,2082.26) 6499.43,2056.92 6504.47,2051.88 6504.47,2042.42 6506.28,2040.61 R205.2@6506.28,2036.67 ; v1@6506.17,1118.05 v1(6506.17,1123.05) 6506.28,1122.94 R113.2@6506.28,1086.67 ; v1(6520,431.38) 6519.24,431.38 6520,432.14 R114.2@6520,471.38 ; R305.1@6620,973.7 v1(6620,1010) ; R306.1@6620,1923.7 v1(6620,1960) ; C130.1@6625,596.85 6626.81,595.04 6626.81,585.74 6647.07,565.48 v1(6647.07,555.66) ; C207.1@6625,1546.85 6625,1536 6647.07,1513.93 v1(6647.07,1505.66) ; R112.2@6674.39,973.7 v1(6760,973.7) ; R207.2@6674.39,1923.7 R208.2@6729.39,1923.7 v1(6760,1923.7) ; v1(6794.53,1961.36) 6796.28,1959.61 R206.2@6796.28,1923.31 ; R111.2@6796.28,973.31 v1(6796.28,1009.61)
  SIG 1 w10: v1(4671.54,531.49) 4633.46,569.57 4633.46,708.03 v1(4742.56,817.13)
  SIG 1 w12: v1(5418.14,1199.07) 5418.86,1199.07 5471.05,1146.88 5471.05,1077.3 5491.75,1056.6 5548.19,1056.6 5549.35,1057.76 5553.6,1057.76 v1(5554.74,1058.91) 5554.74,1060.03 5563.65,1068.94 5563.65,1081.29 v1(5600,1117.63) ; v1@5452.71,154.87 v1(5452.71,156.2) 5574.13,277.62 v1(5574.13,361.28)
  SIG 1 w20: v1(2103.52,135) 2135.87,167.34 v1(2315.95,167.34) 2315.95,122.47 v1(2315.03,121.54)
  SIG 2 w15: 3614.77,946.5 v1(3625.87,957.6) 3614.77,968.7 ; 3740.76,1315.16 v1(3751.86,1304.06) 3762.96,1315.16 ; 3898.24,1315.16 v1(3909.34,1304.06) 3920.44,1315.16 ; v1(4003.83,1052.09) 4014.93,1040.98 ; v1(4003.83,1178.07) 4014.93,1189.17 ; 4014.93,915 v1(4003.83,926.1) 4014.93,937.2
  SIG 2 w20: v1(5053.23,122.41) 5418.92,122.41 v1(5452.71,156.2)
  Bottom Layer w5.3: U61.C6@2257.75,1634.33 U61.E6@2297.12,1634.33 U61.E6@2297.91,1633.53 ; U61.F5@2316.81,1654.01 U61.F5@2317.6,1653.22 ; v1@2317.6,1633.53 2318.23,1633.53 v1(2319.2,1632.56)
  Bottom Layer w6: U61.P5@2474.29,1654.01 2474.57,1653.73 2481.41,1653.73 2492.26,1642.89
  Bottom Layer w7: U4.2@3673.95,156.28 3673.95,130.44 3698.79,105.6
  Bottom Layer w8: U61.E6@2297.91,1633.53 2317.6,1633.53 U61.F5@2317.6,1653.22 ; U61.J10@2375.86,1555.59 2375.86,1556.11 2375.33,1556.11 2366.93,1564.51 v1(2366.93,1584.34) 2386.48,1584.34 U61.K9@2395.55,1575.27 ; U61.M4@2434.92,1673.7 U61.N4@2454.6,1673.7 U61.P3@2474.29,1693.38 ; 2492.26,1642.89 v1(2535.03,1642.89) ; 3698.79,105.6 C62.2@3713.69,105.6 3729.5,105.6 3756.9,132.99 v1(3756.9,133.85) ; v1@6440.82,692.98 6458.04,710.2 U22.30@6491.32,710.2 ; U22.18@6635.02,586.18 6635.02,565.57 v1@6644.43,556.16
  Bottom Layer w9: R63.2@4979.39,1019.06 v1@5019.7,1019.06 ; R64.2@4979.39,1068.43 5015.45,1068.43 5017.36,1070.34 v1(5019.79,1070.34) ; 5510,163.66 5518.06,171.73 U43.2@5538.7,171.73 ; 6457.72,1660.2 U37.30@6491.32,1660.2 ; U37.18@6635.02,1536.18 6635.02,1517.71 v1(6647.07,1505.66)
  Bottom Layer w10: v1(2324.7,597.7) 2326.86,597.7 2329.46,595.1 R426.2@2365.38,595.1 ; v1(2412.13,681.01) 2410.65,679.54 C269.1@2410.65,642.68 2439.11,642.68 2446.27,635.51 2446.27,619.38 2452.65,613 U63.23@2474.16,613 ; v1(2412.62,526) C268.1@2412.62,548.03 ; C268.1@2413.39,548.03 2416.56,548.03 2423.37,554.84 2423.37,558.01 2438.99,573.63 U63.21@2474.16,573.63 ; U61.P3@2474.29,1693.38 2493.25,1693.38 2514.43,1714.56 2535.55,1714.56 v1(2536.05,1714.07) ; v1(4541.17,1109.9) 4541.17,1107.74 4545,1103.91 R73.2@4545,1011.58 ; C244.2@4635,516.83 4639.5,512.33 4639.5,525.26 4641.81,527.58 4665.47,527.58 4669.38,531.49 v1(4671.54,531.49) ; R441.1@4806.05,682.33 4833.73,682.33 v1(4843.09,672.97) ; 4810.22,1043.75 U17.8@4855.28,1043.75 ; R425.2@6800.32,1257.56 6821.47,1257.56 v1(6822.33,1258.42) ; v1(6808.77,1378.61) 6808.77,1338.61 6800.97,1330.8 C270.1@6800.97,1305.89 6826.26,1305.89 6837.49,1294.66 U65.5@6861.67,1294.66
  Bottom Layer w12: v1(2629.26,319.79) 2652.77,296.28 2842.98,296.28 2878.66,331.96 2935.47,331.96 2953.21,314.22 3215.08,314.22 3261.17,268.13 3352.57,268.13 3360.35,260.35 v1(3361.97,260.35) 3361.97,258.73 3366.47,254.23 v1(3366.47,221.17) 3365.64,220.34 v1@3365.64,170.12 ; v1(3365.28,119.57) 3365.28,169.27 v1(3366.13,170.12) ; v1(3583.43,1469.95) v1@3583.47,1470 ; v1(3647.07,1750.16) R41.2@3677.53,1750.16 ; R298.1@4362.13,1715.49 v1(4389.19,1715.49) ; v1(4541.17,1109.9) 4541.38,1110.11 R291.1@4541.38,1152.36 ; v1(4789.17,1150.09) 4788.19,1151.07 4759.61,1151.07 C100.2@4758.62,1152.06 4758.62,1110.11 4798.48,1070.25 4798.48,1055.48 4810.22,1043.75 ; R175.2@4904.17,122.41 R176.2@5004.17,122.41 v1(5053.23,122.41) ; v1(5452.71,156.2) 5454.34,156.2 5461.8,163.66 C223.2@5483.66,163.66 5510,163.66 ; v1(5530,851.27) 5530,702.8 5464.74,637.54 5464.74,512.29 v1(5490,487.03) ; C99.2@5546.38,487.03 v1(5490,487.03) ; U43.10@5574.13,325.27 v1(5574.13,361.28) 5574.13,362.9 5490,447.03 v1(5490,487.03) ; R319.1@5858.93,675 5894.62,675 5897.6,677.99 v1(5927.62,677.99) ; v1(6919.71,1382.14) 6932.88,1395.31 R424.1@6968.46,1395.31 ; R244.2@6935,307.24 6935.26,307.5 v1(6982.5,307.5) ; v1@6982.5,307.24 7220.02,307.24 7238.09,289.17 7238.09,232.92 7249.55,221.46 R228.2@7276.76,221.46 v1(7276.76,190) ; v1(6985,97.8) 6985.27,98.07 U42.5@7017.68,98.07 ; R224.1@7160.2,1158.62 v1(7160.2,1195.94) ; v1(7185,2189.61) 7185.98,2188.62 R230.1@7220,2188.62 ; R232.2@7481.11,1251.28 v1(7515,1251.28) ; v1(7627.57,1216.11) R234.2@7627.57,1250
  Bottom Layer w13: R177.2@909.28,1929.54 934.38,1929.51 942.9,1938.03 v1(942.9,1974.25) ; v1(1934.62,1365.72) 1935.58,1366.68 1935.58,1380.23 1941.94,1386.59 1941.94,1390.53 1947.26,1395.84 C70.2@1951.19,1395.84 1951.19,1434.69 1945.88,1440 U9.5@1942.75,1440 ; R422.2@2550.51,423.74 2550.51,399.07 2558.12,391.46 2571.43,391.46 v1(2571.79,391.09)
  Bottom Layer w15: v1(1755.19,1645.25) 1755.76,1644.68 1759.27,1644.68 1769.21,1634.73 1769.21,1630.8 R420.1@1773.53,1626.49 ; U62.5@1942.75,1579.17 1943.83,1578.08 2011.82,1578.08 2012.91,1577 2012.91,1573 2012.59,1572.69 2012.59,1542.11 2014.19,1540.5 v1(2014.19,1539.69) ; v1(2053.62,1692.59) 2053.62,1691.78 2055.84,1689.55 2055.84,1654.55 2056.51,1653.88 R421.2@2056.51,1652.21 ; U35.5@2872.65,915.95 2871.5,914.8 2871.5,853.36 C259.1@2870.35,852.21 2903.82,852.21 2905.14,853.53 v1(2905.95,853.53) ; v1@3583.47,1470 C6.1@3619.13,1470 ; v1(3586.67,796.67) 3587.25,796.1 3589.61,796.1 3599.32,786.39 3599.32,771.68 C7.1@3603.63,767.37 ; C10.1@3756.08,1476.28 3756.37,1475.99 v1(3756.37,1445.16) ; J23.10@3804.17,2050 3808.42,2045.76 3843.51,2045.76 3852.77,2036.5 C213.1@3890,2036.5 ; C11.1@3831.66,1476.28 3831.73,1476.22 3831.73,1440.66 v1(3831.8,1440.59) ; v1(3886.11,1430) 3896.79,1440.72 3896.79,1465.69 3896.57,1465.91 C5.1@3896.57,1470 ; v1(4100.67,1438.62) C12.1@4100.67,1474.6 ; v1(4129.81,1317.07) C13.1@4162.56,1317.07 ; v1(4129.81,1396.81) 4152.52,1396.81 4167.52,1381.81 C4.1@4168.5,1381.81 ; v1(4135.81,952.97) C8.1@4168.56,952.97 ; v1(4150.81,887.07) 4151.38,887.64 4167.69,887.64 C9.1@4170.05,890 ; v1(4457.78,670) 4474.17,670 4486.98,657.19 4490.92,657.19 4495.23,652.87 C243.2@4495.23,648.94 ; C128.1@6382.85,621.24 6382.85,653.79 6374.21,662.43 C129.2@6374.21,681.97 6398.77,681.97 6408.71,691.91 6439.43,691.91 v1(6440,692.48) ; C205.1@6382.85,1571.24 6382.85,1601.14 6374.21,1609.78 C206.2@6374.21,1631.97 6374.28,1631.9 6406.28,1631.9 6416.28,1641.91 6439.43,1641.91 v1(6440,1642.48) 6457.72,1660.2 ; v1(6530.67,2129.99) R417.1@6530.67,2167.66 ; v1(6562.17,2046.96) 6569.9,2039.24 6586.73,2039.24 C263.1@6589.21,2036.76 ; C263.1@6588.86,2037.12 U60.5@6588.86,2105.64 ; v1(6647.07,555.66) 6670,532.72 C131.1@6670,518.62 ; v1(6647.07,1505.66) 6670,1482.72 C208.1@6670,1468.62 ; v1(6704.27,2091.94) 6704.61,2091.59 R418.2@6704.61,2060.88
  other v1: 4037.34,669.61 4077.34,669.61 2921.16,1657.85 2978.62,1669.48 3002.33,1695.21 1199.19,2231.29
VSYS_3V3_BP: J1/J3.1 J5/J7.41 J9.2 J13.2 | length 1762.3
  Top Layer w30: J9.2@1445,186.05 1540.23,186.05 J1/J3.1@1604.17,250
  SIG 1 w60: J5/J7.41@4104.17,250 4104.17,249.72 4106.07,247.82 4106.07,209.78 4147.91,167.95 5026.77,167.95 5109.64,250.82 5109.64,322.19 5234.88,447.42 5234.88,492.3 J13.2@5235.83,493.25
  SIG 2 w30: J9.2@1445,186.05 1540.23,186.05 J1/J3.1@1604.17,250
VSYS_5V0: C107.2 C108.1 C161.1 C162.2 C163.1 C167.2 C168.2 C172.1 C173.2 C174.1 C179.2 C180.2 C211.1 C212.1 C224.1 C225.2 J11.1 J24.4 J25.4 R1.2 R146.2 R149.1 R150.1 R156.2 R157.1 R158.1 R236.2 R237.2 R238.2 R239.2 R240.2 R241.2 R242.2 R243.2 R257.2 R265.2 R302.2 TP8.1 U19.7 U19.8 U29.6 U30.1 U30.2 U31.1 U31.2 U32.6 U42.3 U43.19 | length 3840.8
  Top Layer w10: U19.7@1714.33,765.75 1736.08,765.75 1743.85,773.51 ; U19.8@1714.33,785.43 1734.28,785.43 1743.85,795 ; 2321.63,923.91 2329.56,931.84 U29.6@2358.33,931.84 ; v1(2545,79) 2545,77.96 2577.96,45 R302.2@2579.93,45 ; v1@2773.3,1456.53 2781.23,1464.46 U32.6@2810,1464.46 ; 5695.21,1198.48 5725.89,1167.8 U30.1@5744.01,1167.8 5750,1173.81 5750,1197.56 5736.85,1210.7 ; C174.1@5695.21,1617.67 5725.89,1586.99 U31.1@5744.01,1586.99 ; 5705.96,1155 5712.84,1148.12 U30.2@5744.01,1148.12 ; 5705.96,1574.19 5712.84,1567.31 U31.2@5744.01,1567.31
  Top Layer w12: 2571.67,1464.46 2571.67,1493.55 2606.51,1528.38 2606.51,1752.81 2606.23,1753.09 R265.2@2606.23,1774.32 ; R1.2@3237.47,609.62 3237.47,605.68 3253.29,589.87 3253.29,584.26 v1(3254.44,583.11) ; v1(6170,615) 6181.38,603.62 R243.2@6181.38,578.2
  Top Layer w15: v1(5600,1017.63) R149.1@5630.51,1017.63 ; v1(5600,1067.63) R150.1@5630.51,1067.63 ; v1(5600,1436.82) R157.1@5630.51,1436.82 ; v1(5600,1486.82) R158.1@5630.51,1486.82
  SIG 1 w12: v1(1835,695) 1803.73,695 1772.62,663.89 1772.62,630.22 1718.62,576.22 1718.62,512.89 1621.15,415.41 1580.41,415.41 1547.79,382.79 1547.79,226.81 1588.55,186.05 1905.94,186.05 2012.99,79 v1(2545,79) ; v1(2269,844.07) 2320.02,895.08 2342.51,895.08 2392.9,945.47 2464.65,945.47 2499.03,911.09 v1(2556.35,911.09)
  SIG 2 w20: 6492.17,303.97 6512.09,303.97 v1(6548.12,340)
  Bottom Layer w9: U43.19@5668.62,171.73 5694.74,171.73
  Bottom Layer w12: 5694.74,171.73 5701.77,164.7 5701.77,154.76 5673.54,126.53 C224.1@5673.54,93.47 v1(5715,93.47) ; R238.2@5940,245.75 v1(5940,280) ; R241.2@5940,495.75 v1(5940,530) ; R237.2@6064.18,245.75 v1(6064.18,280) ; R240.2@6064.18,495.75 v1(6064.18,530) ; R236.2@6259.18,245.75 v1(6259.18,280) ; R239.2@6259.18,495.75 v1(6259.18,537.58) ; R242.2@6508.76,355.53 6532.59,355.53 v1(6548.12,340) ; U42.3@7127.91,123.66 7151.15,123.66 7158.04,116.77 v1(7213.78,116.77)
  Bottom Layer w15: R146.2@2528.5,906.39 2532.62,910.52 2555.77,910.52 v1(2556.35,911.09) ; v1(2776.69,1451.62) 2777.27,1451.05 2777.27,1446 2785.39,1437.88 R156.2@2812.95,1437.88 ; C211.1@5880,198.5 5880,134.18 J24.4@5899.18,115 ; C212.1@5880,448.5 5880,384.18 J25.4@5899.18,365
  other v1: 1863.17,704.77 1839.83,736.93 1869.74,770.49 1836.84,773.15 2198.19,842.08 2237.24,862.86 5500,1153.83 5550,1153.83 5600,1153.83 5500,1203.83 5550,1203.83 5587.86,1205.26 2620.12,1364.46 2659.5,1364.46 2620.12,1393.79 2656.84,1394.83 2692.36,1394.83 2723.16,1394.83 2620.12,1428.04 2620.12,1455.45 5600,1573.02 5600,1623.02
VSYS_5V0_BP_1: J1/J3.21 J10.2
VSYS_5V0_BP_2: J5/J7.61 J14.2
  other v1: 4032.97,175.96 4059.2,175.96 4032.97,202.19 4059.2,202.19 4032.97,228.41 4059.2,228.41
VSYS_MON_AM263P_: C48.1 R1.1 R2.2 U1.U2 | length 482
  Top Layer w5.3: R1.1@3237.47,656.87 C48.1@3287.47,656.87 R2.2@3337.66,656.87 3367.08,656.87 3516.13,805.92 3528.4,805.92 3538.34,815.87 3549.85,827.38 3590.05,827.38 3593.15,830.49 3593.15,864.33 U1.U2@3578.63,878.86
VSYS_TA_3V3: C60.2 C61.2 C64.2 C65.2 C183.2 C184.2 C185.1 C186.1 C252.1 C262.1 J6.1 J6.2 J6.3 L4.2 R8.1 R10.1 R11.1 R182.1 R183.1 R184.1 R185.1 R186.1 R187.1 R188.1 R191.2 R192.2 R194.2 R195.2 R315.2 R406.2 U3.14 U3.15 U4.3 U5.5 U6.5 U36.10 U56.8 U58.16 U59.8 | length 8411.5
  Top Layer w10: U36.10@2892.11,254.33 2887.59,254.33 2887.51,254.41 2887.51,307.19 2893.28,312.96 2894.33,314 C186.1@2895.62,314 ; v1(2924.13,309.09) 2924.82,308.39 2940.03,308.39 2949.35,299.06 L4.2@2949.35,294.92 ; 3263.33,418.33 3265,420 ; U3.15@3292.94,408.86 3276.14,408.86 3265,420 ; U3.14@3292.94,428.54 3273.54,428.54 3265,420
  Top Layer w12: v1(1553.43,1292.59) 1554.57,1293.74 1575.24,1293.74 1586.43,1304.92 1645.05,1304.92 1701.78,1361.65 1701.78,1434.02 1644.94,1490.86 1611.71,1490.86 1598.12,1504.45 v1(1598.12,1534.26) 1663.33,1599.47 1663.33,1695.28 1682.39,1714.33 1682.39,1758.91 v1@1668.65,1772.65
  Top Layer w14: C64.2@2017.57,726.8 U6.5@2064.38,726.8
  Top Layer w15: v1(1053.23,1904.6) 1053.23,1865.6 R406.2@1054.16,1864.66 1126.89,1864.66 v1(1149.09,1886.86) ; C60.2@3238.62,418.33 3263.33,418.33
  Top Layer w18: v1(191,1998) 191.43,1997.57 191.43,1971.7 C262.1@191.86,1971.27 191.86,1929.7 215.11,1906.45 249.71,1906.45 260.25,1916.99 U58.16@260.25,1969.74
  Top Layer w20: R184.1@1216.66,1977.67 1216.66,2001.47 v1(1223.49,2008.29) ; U5.5@1953.91,965.53 1955.72,967.35 1955.72,995.1 1962.85,1002.22 C65.2@1962.85,1024.86 1966.78,1024.86 1968.59,1026.67 1968.59,1030.61 1976.8,1038.82 v1(1976.8,1048.4) ; v1(1970.25,726.52) 1973.91,722.86 C64.2@2017.57,722.86 ; C186.1@2892.97,313.27 2893.28,312.96 2894.05,312.19 2921.02,312.19 v1(2924.13,309.09) ; 2994.12,360.33 3029.75,360.33 3041.46,348.61 3041.46,196.88 3023.96,179.37 3003.92,179.37 R194.2@3002.11,177.56 R195.2@3002.11,122.56 R315.2@3002.11,47.31 ; v1(3163.57,359.08) 3190.88,359.08 R10.1@3191.38,358.58 3191.38,375.86 3203.78,388.27 3226.3,388.27 3238.01,399.98 3238.01,417.72 C60.2@3238.62,418.33 3238.62,466.67 v1(3238.36,466.94) ; v1@3247.05,516.86 R11.1@3283.01,516.86
  SIG 1 w15: v1(191,1998) 275,1998 328,2051 477,2051 521,2095 v1(546,2095) 568,2073 568,1989.09 649.97,1907.13 v1(878.34,1907.13)
  SIG 1 w20: v1(1149.09,1886.86) 1149.09,1985.63 1171.75,2008.29 v1(1223.49,2008.29) 1223.49,1996.91 1221.45,1994.87 1221.45,1877.34 1235.2,1863.59 v1@1325.51,1863.59 ; v1(1467.1,1872.5) 1512.89,1872.5 1546.59,1838.79 v1(1640.2,1838.79) ; v1(1553.43,1292.59) 1561.63,1300.79 1561.79,1300.79 1577.88,1316.89 1641.76,1316.89 1668.45,1343.57 1750.11,1343.57 1761.99,1355.45 1876.21,1355.45 v1(1877.14,1356.38) ; v1@1640.56,1838.79 1669,1810.36 v1(1669,1773) ; v1(1970.25,726.52) 1922.93,726.52 1792.36,595.94 1784.61,595.94 1748.13,559.46 1748.13,532.83 1874.02,406.94 2517.94,406.94 2578.39,346.49 2626.21,346.49 cw(c2629.26,319.79) 2632.32,346.49 2710.93,346.49 2736.39,371.95 2916.74,371.95 2923.22,378.43 ; v1@1972.1,726.52 2014.6,769.02 2014.6,804.45 1923.88,895.17 1923.88,970.66 1976.8,1023.59 v1(1976.8,1048.4) ; v1(2953.49,352.31) 2949.34,352.31 2923.22,378.43 ; v1(2985.63,421.62) 2966.41,421.62 2923.22,378.43
  SIG 2 w20: v1(878.34,1907.13) 878.34,1907.56 893.77,1922.99 950.36,1922.99 986.47,1886.89 1035.52,1886.89 v1(1053.23,1904.6)
  Bottom Layer w7: 3653.69,131.2 3658.2,135.71 U4.3@3658.2,156.28
  Bottom Layer w12: C61.2@3653.69,105.6 3653.69,131.2
  Bottom Layer w15: v1(878.34,1907.13) 878.34,1871.24 887.13,1862.45 R188.1@916.16,1862.45 ; v1(1053.23,1904.6) 1073.3,1884.53 R187.1@1073.3,1862.94 ; v1(1149.09,1886.86) 1149.09,1886.51 1160.58,1875.02 1160.58,1867.25 1164.89,1862.94 R186.1@1168.83,1862.94 ; v1(1223.49,2008.29) 1223.49,2007.48 1228.7,2002.26 1228.7,1970.78 R182.1@1228.48,1970.56 ; U59.8@1503.89,1340 1503.89,1294.53 1508.21,1290.21 1550.24,1290.21 1552.61,1292.59 v1(1553.43,1292.59) ; R192.2@1607.01,1838.79 v1(1640.2,1838.79)
  Bottom Layer w20: R185.1@1267.44,1862.94 1326.16,1862.94 v1(1326.34,1862.76) 1350.21,1838.89 R191.2@1459.76,1838.89 1459.76,1865.15 v1(1467.1,1872.5) ; U56.8@1504.02,1573.36 1522.72,1573.36 1546.58,1549.5 1582.88,1549.5 v1(1598.12,1534.26) ; R183.1@1639.62,1762 1643.56,1762 1654.56,1773 v1(1669,1773) ; v1(1877.14,1356.38) 1890.97,1356.38 1980.33,1267.02 1980.33,1191.52 2018.68,1153.17 2018.68,1076.86 1990.23,1048.4 v1(1976.8,1048.4) ; v1(2953.49,352.31) 3156.8,352.31 v1(3163.57,359.08) 3200.34,359.08 3270,289.43 3407.35,289.43 3429.14,267.64 3429.14,115.52 3457.96,86.69 3512.26,86.69 3527.23,101.66 R8.1@3576.64,101.66 3614.59,101.66 3618.53,105.6 C61.2@3653.69,105.6 ; v1(3238.36,466.94) 3246.84,475.42 v1(3246.84,517.07)
VSYS_TA_3V3_EN: R193.1 U36.3 | length 69.5
  Top Layer w5.3: R193.1@2760.51,184.29 2762.48,184.29 2793.15,214.96 U36.3@2817.31,214.96
VSYS_TA_3V3_PG: R195.1 U36.7 | length 120.1
  Top Layer w5.3: U36.7@2892.11,195.28 2906.91,195.28 2918.49,183.7 2918.49,137.31 2933.24,122.56 R195.1@2954.87,122.56
VSYS_TA_3V3_SLEEP: R194.1 U36.8 | length 88.5
  Top Layer w5.3: U36.8@2892.11,214.96 2908.63,214.96 2919.9,203.69 2946.3,203.69 2954.87,195.12 R194.1@2954.87,177.56
VUSB_5V0: C101.1 C104.2 C105.2 C106.1 C110.1 C187.2 C188.1 C249.1 J10.1 J14.1 L1.2 R91.2 R92.1 R93.1 R94.2 R193.2 R434.2 R439.1 TP4.1 U18.12 U19.1 U19.2 U19.4 U21.5 U36.2 U47.5 | length 2133.3
  Top Layer w6: U18.12@476.96,375 476.96,386.02
  Top Layer w10: 1610,773.51 1617.76,765.75 U19.2@1639.52,765.75 ; 1610,795 1619.57,785.43 U19.1@1639.52,785.43 ; v1(1637.49,699.6) 1638.5,700.61 1638.5,726.3 1638.58,726.38 U19.4@1639.52,726.38
  Top Layer w12: R439.1@355.28,374.61 355.28,403.13 362.31,410.16 444.7,410.16 ; v1(401.32,228.18) 401.32,229.81 404.22,232.71 R94.2@404.22,260.08 ; C101.1@452.28,454.11 v1(452.28,493.25) ; R91.2@611.13,263.69 613.55,266.1 v1(613.55,292.1) ; R93.1@669.95,270.68 692.73,270.68 v1(707.73,255.68) ; R92.1@669.95,428.31 670.03,428.39 670.03,455.02 677.06,462.05 v1(695,462.05) C110.1@740,462.05 735.61,457.66 U21.5@735.61,394.13 ; v1(733.18,272.89) 735.32,270.76 R434.2@755.88,270.76
  Top Layer w15: v1(787.3,425.41) C249.1@825.37,425.41 U47.5@825.37,493.6
  SIG 1 w12: v1(707.73,255.68) 707.73,283.55 785.93,361.75 1017.63,361.75 1054.42,324.96 1182.95,324.96 1331.42,473.43 1605.56,473.43 1646.97,514.85 1646.97,538.03 1627.88,557.12 1597.92,557.12 v1(1575,580.04) 1575,639.78 1631.81,696.6 1632.86,696.6 1635.86,699.6 v1(1637.49,699.6)
  Bottom Layer w12: v1(613.55,292.1) 649.97,255.68 v1(707.73,255.68)
  other v1: 2649.2,187.18 2677.28,187.1 2649.28,215.26 2677.36,215.18 2708.42,215.02 2736.5,214.94 2649.36,243.34 2677.44,243.25 2728.23,243.34 1475,580.04 1525,580.04
XDS_DEBUG_ID4: R138.1 R310.1 U24.63 | length 236.7
  Top Layer w5.3: v1(1167.09,1629.18) R310.1@1167.09,1656.39
  Bottom Layer w5.3: U24.63@1023.85,1627.52 1023.85,1657.73 1031.25,1665.13 1131.26,1665.13 1140,1656.39 R138.1@1167.94,1656.39 1167.94,1632.21 v1@1164.91,1629.18
XDS_DEBUG_ID5: R139.1 R309.1 U24.62 | length 235.3
  Top Layer w5.3: R309.1@1095.89,1669.68 1095.89,1698.95 1100.19,1703.25 1118.27,1703.25 v1(1119.79,1701.73)
  Bottom Layer w5.3: U24.62@1008.1,1627.52 1008.1,1669.19 1014.63,1675.73 1081.48,1675.73 1093.35,1687.6 R139.1@1093.35,1705 1113.08,1705 1116.35,1701.73 v1(1119.79,1701.73)
XDS_DEBUG_ID6: R140.1 R308.1 U24.61 | length 197
  Top Layer w5.3: R308.1@1016.99,1669.68 1016.99,1671.65 1048.6,1703.26 v1(1065.51,1703.26)
  Bottom Layer w5.3: U24.61@992.35,1627.52 992.35,1669.24 1014.62,1691.52 1014.62,1696.62 1023,1705 R140.1@1039.13,1705 1040.87,1703.26 v1(1065.51,1703.26)
XDS_DEBUG_ID7: R141.1 R261.1 U24.60 | length 146.1
  Top Layer w5.3: R261.1@965,1669.68 965,1704.32 v1(965.68,1705)
  Bottom Layer w5.3: v1(965.68,1705) R141.1@992.24,1705 992.24,1689.23 976.6,1673.59 U24.60@976.6,1627.52
XDS_EMU0: R311.1 U24.42 | length 78
  Top Layer w5.3: v1(680.39,1673.54) 680.39,1648.14 R311.1@681.33,1647.2
  Bottom Layer w5.3: v1(680.39,1673.54) 693.14,1660.79 U24.42@693.14,1627.52
XDS_EMU1: R312.1 U24.43 | length 104.7
  Top Layer w10: R312.1@688.16,1538.67 688.16,1540.64 693.01,1545.49 701.73,1545.49 709.98,1553.74 709.98,1559.83 v1(711.51,1561.36)
  Bottom Layer w5.3: U24.43@708.89,1627.52 708.89,1567.42 711.51,1564.8 v1(711.51,1561.36)
XDS_PROGSTAZ1: R259.2 U24.4 | length 569.5
  SIG 1 w4.75: v1(351.07,1487.15) 351.07,1385.61 515.42,1221.27 515.42,1148.28 v1(536.18,1127.52)
  Bottom Layer w5.3: R259.2@292.29,1530 330.07,1530 351.07,1508.99 v1(351.07,1487.15) ; U24.4@492.35,1127.52 v1(536.18,1127.52)
XDS_PROGSTAZ2: R260.2 U24.3 | length 720.9
  SIG 1 w4.75: v1(413,1404.05) 586.18,1230.87 v1(586.18,1127.52)
  Bottom Layer w5.3: R260.2@292.29,1601.11 322.39,1601.11 379.82,1543.69 379.82,1437.73 v1@413,1404.54 ; U24.3@492.35,1111.77 524.31,1111.77 534.1,1101.99 560.64,1101.99 v1(586.18,1127.52)
XDS_VBUS_DETECT: C135.1 R136.1 R137.2 U24.1 | length 221.9
  Bottom Layer w5.3: R136.1@275.17,1081.69 299.11,1081.69 304.1,1086.68 C135.1@325,1086.68 346.09,1086.68 351.07,1081.69 R137.2@371.47,1081.69 372.88,1080.28 U24.1@492.35,1080.28
XDSET_1_D_N: J34.2 U24.93 U44.1 U44.10 | length 1225.9
  Top Layer w4.2: J34.2@161.81,1018.49 193.09,1018.49 201.29,1026.68 226.14,1026.68 231.38,1021.44 U44.10@238.56,1021.44 244.8,1021.44 250.05,1026.68 259.01,1026.68 264.25,1021.44 U44.1@271.44,1021.44 278.62,1021.44 283.86,1026.68 296.6,1026.68 v1(310,1013.28)
  SIG 1 w4: v1(310,1013.28) 321.72,1025 366.63,1025 391.11,1049.48 669.86,1049.48 723.12,1102.74 832.46,1102.74 887.74,1047.46 933.75,1047.46 956.24,1069.96 956.24,1120.15 939.95,1136.44 904.57,1136.44 892.15,1136.44 v1(889.97,1138.62)
  Bottom Layer w4.2: v1(889.97,1138.62) 890.53,1138.62 903.92,1125.23 951.16,1125.23 956.5,1130.57 1019.37,1130.57 1025.69,1124.25 1067.83,1124.25 1070.4,1126.82 1097.95,1126.82 U24.93@1098.65,1127.52
XDSET_1_D_P: J34.3 U24.94 U44.2 U44.9 | length 1227
  Top Layer w4.2: J34.3@161.81,1044.08 192.99,1044.08 201.19,1035.88 226.14,1035.88 231.38,1041.12 U44.9@238.56,1041.12 245.75,1041.12 250.99,1035.88 259.01,1035.88 264.25,1041.12 U44.2@271.44,1041.12 278.62,1041.12 278.62,1040.18 282.92,1035.88 296.6,1035.88 v1(310,1049.28)
  SIG 1 w4: v1(310,1049.28) 310,1040 315,1035 362.49,1035 386.97,1059.48 665.72,1059.48 718.98,1112.74 836.6,1112.74 891.88,1057.46 929.6,1057.46 946.24,1074.1 946.24,1116.01 935.81,1126.44 927.8,1126.44 924.76,1123.39 924.76,1118.25 922.41,1115.9 918.41,1115.9 916.07,1118.25 916.07,1122.21 911.84,1126.44 904.57,1126.44 896.41,1118.28 896.41,1111.76 891.08,1106.42 v1(891.08,1102.63)
  Bottom Layer w4.2: v1(891.08,1102.63) 891.08,1103.19 903.92,1116.03 954.97,1116.03 960.31,1121.37 1015.55,1121.37 1021.88,1115.05 1067.83,1115.05 1070.4,1112.47 1097.95,1112.47 U24.94@1098.65,1111.77
XDSET_1_ID: J34.4 R130.1 U44.4 U44.7 | length 1448.8
  Top Layer w5.3: J34.4@161.81,1069.67 214.17,1069.67 225,1080.49 U44.7@238.56,1080.49 U44.4@271.44,1080.49 286.73,1080.49 295.48,1089.24 295.48,1166.19 309.08,1179.79 349.55,1179.79 381.06,1148.28 553.25,1148.28 598.65,1193.68 598.65,1277.44 615,1293.79 770.88,1293.79 868.39,1196.28 980.91,1196.28 1002.64,1218.01 1019.17,1218.01 1029.7,1207.47 1029.7,1197.73 1041.14,1186.29 1051.77,1186.29 ; 1051.79,1186.27 1079.74,1186.27 1115.94,1150.07 1140.04,1150.07 1187.2,1102.91 1221.51,1102.91 1242.75,1081.66 v1(1242.75,1081.33)
  Bottom Layer w5.3: R130.1@1225.19,1054.21 1239.65,1054.21 1242.75,1057.32 v1(1242.75,1081.33)
XDSET_1_ID_R: R130.2 U24.95 | length 117.4
  Bottom Layer w5.3: U24.95@1098.65,1096.02 1145.21,1096.02 1155,1086.23 1155,1064.12 1164.91,1054.21 R130.2@1185.82,1054.21
XDSET_NRST: R143.1 U24.70 | length 78.2
  Bottom Layer w5.3: U24.70@1098.65,1489.72 1134.45,1489.72 1145.04,1479.14 1169.46,1479.14 R143.1@1171.62,1476.98
XDSET_OSC0: C144.1 U24.88 Y3.1 | length 324.1
  Bottom Layer w5.3: U24.88@1098.65,1206.26 1143.56,1206.26 1146.94,1202.88 1182.99,1202.88 1186.1,1205.99 1186.1,1235.32 1191.32,1240.54 1195.04,1240.54 1199.81,1235.77 1199.81,1207.31 1203.29,1203.83 1308.86,1203.83 1318.63,1213.6 Y3.1@1318.63,1247.63
XDSET_OSC1: C143.1 U24.89 Y3.3 | length 201.2
  Bottom Layer w5.3: U24.89@1098.65,1190.51 1166.9,1190.51 1186.02,1171.39 1186.02,1164.24 1191.24,1159.01 1195.18,1159.01 1200.41,1164.24 1200.41,1171.8 1215.85,1187.24 1229.41,1187.24 Y3.3@1255.64,1161.01
XDSET_RBIAS: R145.2 U24.59 | length 98.3
  Bottom Layer w5.3: R145.2@931.47,1713.62 931.47,1693.52 960.85,1664.13 U24.59@960.85,1627.52
XDSET_TCK: R133.2 U24.35 | length 176
  Bottom Layer w5.3: R133.2@480.5,1720.39 480.5,1696.19 493.61,1683.08 563.16,1683.08 582.9,1663.34 U24.35@582.9,1627.52
XDSET_TDI: R135.2 U24.38 | length 126
  Bottom Layer w5.3: R135.2@580.5,1720.39 601.89,1720.39 630.15,1692.13 U24.38@630.15,1627.52
XDSET_TMS: R134.2 U24.36 | length 139.6
  Bottom Layer w5.3: R134.2@530.5,1720.39 530.5,1702.31 538.33,1694.48 569.96,1694.48 598.65,1665.8 U24.36@598.65,1627.52
XDSET_UARTA_RX: R129.2 U24.33 | length 243.6
  Bottom Layer w5.3: R129.2@380.5,1720.39 380.5,1693.19 411.81,1661.88 548.3,1661.88 551.41,1658.78 U24.33@551.41,1627.52
XDSET_UARTA_TX: R131.2 U24.34 | length 209
  Bottom Layer w5.3: R131.2@430.5,1720.39 430.5,1697.12 455.14,1672.48 556.68,1672.48 566.66,1662.5 566.66,1628.01 U24.34@567.15,1627.52
XDSET_VBAT: C142.1 R142.1 U24.68 | length 125.4
  Bottom Layer w5.3: U24.68@1098.65,1521.22 1099.14,1521.71 1127.65,1521.71 1137.03,1531.1 1153.54,1531.1 1169.71,1514.93 R142.1@1171.68,1514.93 1171.68,1534.93 1167.74,1538.87 C142.1@1167.74,1554.93
XDSET_VREFA: C151.2 C152.1 R144.1 U24.9 U28.1 U28.3 | length 487.7
  Top Layer w5.3: U28.1@378.9,1363.89 378.9,1339.07 341.5,1301.67 U28.3@341.5,1269.4 341.5,1244.79 320.23,1223.52 v1(320.23,1206.78) 340.93,1206.78 369.47,1235.33 401.47,1235.33 415,1221.79 R144.1@415,1204.12
  Bottom Layer w5.3: v1(320.23,1206.78) 339.46,1206.78 344.16,1202.09 360.77,1202.09 C151.2@360.82,1202.04 392.65,1202.04 397.57,1206.97 C152.1@415.82,1206.97 416.52,1206.26 U24.9@492.35,1206.26
XDSUSB0VBUS: C134.2 R132.1 U24.96 | length 179.6
  Bottom Layer w5.3: U24.96@1098.65,1080.28 1137.32,1080.28 1142.6,1075 1142.6,1032.15 1160.53,1014.22 R132.1@1185.82,1014.22 C134.2@1185.82,974.22
pads on no net: 1. 2. 3. 4. ?. C23.1 D15.1S D15.2S D16.1S D16.2S Designator2. Designator2_1. Designator3. Designator4. Designator4_1. Designator5. Designator6. Designator7. Designator7_1. Designator8. Designator9. Designator9_1. Designator10. Designator11. Designator12. Designator13. FID1.1 FID2.1 FID3.1 FID4.1 FID5.1 FID6.1 FID7.1 FID8.1 FID9.1 FID10.1 FID11.1 FID12.1 J5.A2 J5.A3 J5.A6 J5.A7 J5.A8 J5.A10 J5.A11 J5.B2 J5.B3 J5.B6 J5.B7 J5.B8 J5.B10 J5.B11 J6.4 J6.5 J6.6 J6.8 J6.9 J6.10 J6.11 J6.12 J6.13 J6.14 J6.15 J6.17 J6.18 J6.19 J6.20 J6.21 J6.22 J6.23 J6.24 J6.29 J6.35 J7. J8. LBL1.0 S2.1 S2.4 U1.U1 U1.U3 U1.V2 U3.7 U3.8 U3.9 U3.10 U3.17@3348.05,418.7 U6.1 U7.A2 U7.B1 U7.B5 U7.C5 U8.4 U10.2 U10.5 U11.4 U11.9 U12.3@1835,448.04 U12.8@1835,480.91 U13.3@2180,448.56 U13.8@2180,481.44 U14.3@4825,467.68 U14.8@4825,500.55 U15.3@5035.4,467.82 U15.8@5035.4,500.69 U19.0 U20.1 U20.2 U20.3@1038.54,453.43 U20.8@1038.54,420.56 U20.9 U20.10 U22.14 U22.15 U22.16 U22.17 U22.21 U22.23 U22.24 U24.2 U24.5 U24.6 U24.11 U24.12 U24.13 U24.14 U24.15 U24.18 U24.19 U24.20 U24.21 U24.22 U24.23 U24.24 U24.25 U24.27 U24.29 U24.30 U24.31 U24.32 U24.40 U24.41 U24.44 U24.45 U24.46 U24.53 U24.54 U24.56 U24.57 U24.65 U24.67 U24.83 U24.84 U24.85 U24.86 U24.91 U24.92 U24.102 U24.103 U24.104 U24.105 U24.106 U24.107 U24.108 U24.109 U24.110 U24.111 U24.112 U24.116 U24.117 U24.118 U24.119 U24.120 U24.121 U24.123 U24.124 U24.125 U24.126 U24.127 U24.128 U33.1 U36.4 U36.11@2854.71,189.77 U36.11@2854.71,240.16 U37.14 U37.15 U37.16 U37.17 U37.21 U37.23 U37.24 U38.3@7006.02,788.94 U38.8@6973.14,788.94 U39.3@7005.75,619.6 U39.8@6972.87,619.6 U40.3@7006.02,1738.94 U40.8@6973.14,1738.94 U41.3@7005.75,1609.6 U41.8@6972.87,1609.6 U44.3@271.44,1060.81 U44.5 U44.6 U44.8@238.56,1060.81 U45.7 U45.9@443.89,998.32 U45.9@493.49,998.32 U46.1 U52.15 U52.16 U53.12 U53.13 U53.14 U53.15 U53.16 U53.18 U53.19 U53.20 U53.21 U53.22 U53.23 U53.24 U53.25 U53.26 U53.27 U53.42 U54.10 U54.11 U54.13 U54.14 U55.5 U55.7@3080.26,1600.29 U55.7@3080.26,1635.72 U61.A1 U61.A2 U61.A7 U61.A8 U61.A9 U61.A10 U61.A11 U61.A12 U61.A13 U61.A14 U61.B1 U61.B7 U61.B8 U61.B9 U61.B10 U61.B11 U61.B12 U61.B13 U61.B14 U61.C1 U61.C3 U61.C5 U61.C7 U61.C8 U61.C9 U61.C10 U61.C11 U61.C12 U61.C13 U61.C14 U61.D1 U61.D2 U61.D3 U61.D4 U61.D12 U61.D13 U61.D14 U61.E1 U61.E2 U61.E3 U61.E5 U61.E8 U61.E9 U61.E10 U61.E12 U61.E13 U61.E14 U61.F1 U61.F2 U61.F3 U61.F10 U61.F12 U61.F13 U61.F14 U61.G1 U61.G2 U61.G3 U61.G10 U61.G12 U61.G13 U61.G14 U61.H1 U61.H2 U61.H3 U61.H12 U61.H13 U61.H14 U61.J1 U61.J2 U61.J3 U61.J12 U61.J13 U61.J14 U61.K1 U61.K2 U61.K3 U61.K6 U61.K7 U61.K10 U61.K12 U61.K13 U61.K14 U61.L1 U61.L2 U61.L3 U61.L12 U61.L13 U61.L14 U61.M1 U61.M2 U61.M3 U61.M7 U61.M8 U61.M9 U61.M10 U61.M11 U61.M12 U61.M13 U61.M14 U61.N1 U61.N3 U61.N6 U61.N7 U61.N8 U61.N9 U61.N10 U61.N11 U61.N12 U61.N13 U61.N14 U61.P1 U61.P2 U61.P7 U61.P8 U61.P9 U61.P10 U61.P11 U61.P12 U61.P13 U61.P14 U63.17

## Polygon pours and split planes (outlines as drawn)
VSYS_5V0 on Top Layer "NONET_L-01_P-001" (solid, remove dead copper, pour order 299): 5759.02,1216.48 5489.5,1216.48 5489.5,1140.55 5759.02,1140.55
GND on Top Layer "NONET_L-01_P-001" (solid, remove dead copper, pour order 298): 3647.12,1288.31 3988.08,1288.31 3988.08,926.1 3647.02,926.1
GND on Top Layer "Top Layer-GND 10" (solid, pour order 253): 22 vertices, not listed, extent 3170,678.6 3688.87,968.81
VDD_ETH1_2V5_FILT on Top Layer "Top Layer-VDD_ETH1_2V5_FILT" (solid, remove dead copper, pour order 255): 26 vertices, not listed, extent 6130,641.19 6855,993.7
VSYS_5V0_BP_2 on Top Layer "NONET_L-01_P-001" (solid, remove dead copper, pour order 294): 4016.88,384.4 4214.28,384.4 4214.28,217 5025.74,217 5090.8,282.07 5090.8,418.7 5213.39,541.29 5449.31,541.29 5460.6,530 5460.6,85.19 5384.15,8.74 4035.32,8.74 4016.88,27.19
VDD_AM263P_1V2 on Top Layer "Top Layer-VDD_AM263_1V2" (solid, pour order 38): 2641.93,1093.92 2605.02,1130.83 2605.02,1240 2399.37,1240 2399.37,965 2439.19,965 2502.29,1028.1 2641.93,1028.1
TPS62913_1_SW on Top Layer "Top Layer-TPS62913_1_SW" (solid, pour order 36): 2440,950 2455.21,934.79 2628.59,934.79 2628.59,973.37 2458.37,973.37 2440,955
GND on Top Layer "TOP_LAYER_GND_P277" (solid, pour order 277): 2892.33,1271.14 2917.03,1295.85 2987.97,1295.85 2987.97,1245.85 2966.18,1245.85 2964.08,1243.75 2964.08,1215.24 2958.56,1209.72 2913.32,1209.72 2892.11,1230.93 2892.11,1269.14
GND on Top Layer "Top Layer-GND 7" (solid, pour order 130): 20 vertices, not listed, extent 2638.49,137.19 2905.5,432.13
NetL4_1 on Top Layer "Top Layer-NetL4_1" (solid, pour order 132): 2930.65,251.07 2924.08,244.49 2885.14,244.49 2881.99,241.34 2881.99,230.69 2886.14,226.55 2923.29,226.55 2932.41,217.42 3021.76,217.42 3023.49,219.15 3023.49,247.11 3019.54,251.07
VSYS_5V0_BP_1 on Top Layer "NONET_L-01_P-001" (solid, remove dead copper, pour order 290): 1379.76,352.96 1365.28,338.47 1365.28,241.67 1375.96,230.99 1497.29,230.99 1560.47,294.17 1629.37,294.17 1648.79,313.59 1648.79,368.98 1620.95,396.81 1522.11,396.81 1478.26,352.96
VSYS_5V0 on Top Layer "Top Layer-VSYS_5V0" (solid, pour order 28): 1719.62,829.78 1719.47,829.78 1702.92,813.02 1702.92,757.91 1804.17,757.91 1804.17,671.76 1887.22,671.76 1887.22,813.18 1887.22,851.62 1879.82,859.03 1841.9,859.03 1841.9,848.78 1822.91,829.79
VUSB_5V0 on Top Layer "NONET_L-01_P-001" (solid, pour order 8): 432.58,504.82 432.58,393.48 463.44,362.62 479.66,362.62 485.18,368.14 485.18,502.73 475.65,512.26 435.43,512.26
FB_VDD_XDS3V3 on Top Layer "NONET_L-01_P-001" (solid, pour order 281): 501.17,1129.68 510.65,1139.16 562.37,1139.16 562.37,1149.57 622.09,1209.29 703.78,1209.29 703.78,1101.07 680.34,1077.63 636.55,1077.63 602.49,1043.58 501.17,1043.58
GND on Top Layer "TOP_LAYER_GND_P269" (solid, remove dead copper, pour order 269): 1115.94,590.09 1221.1,590.09 1250.4,560.79 1287.8,560.79 1287.8,600.16 1298.89,611.25 1428.56,611.25 1428.75,611.43 1428.75,701.75 1404.68,725.82 1244.27,725.82 1193.44,675 1127.9,675 1115.94,663.04
VBUS_TYPEC_5V0 on Top Layer "TOP_LAYER_VBUS_TYPEC_5V0_P267" (solid, remove dead copper, pour order 267): 1294.67,404.12 1226.94,404.12 1188.54,365.73 1188.54,356 1177.4,344.86 1134.43,344.86 1107.27,372.02 1107.27,527.1 1240.33,527.1 1250.4,537.17 1287.8,537.17 1287.8,473.99 1294.67,467.12
VDD_ETH1_1V1_FILT on Top Layer "Top Layer-VDD_ETH1_1V1_FILT" (solid, remove dead copper, pour order 266): 6202.73,1336.32 6202.73,1276.79 6435,1276.79 6435,1336.32
VDD_ETH2_1V1_FILT on Top Layer "Top Layer-VDD_ETH2_1V1_FILT" (solid, pour order 259): 6202.73,1475.21 6202.73,1405 6432.19,1405 6432.19,1475.21
VDD_ETH2_2V5_FILT on Top Layer "Top Layer-VDD_ETH2_2V5_FILT" (solid, remove dead copper, pour order 257): 31 vertices, not listed, extent 6200,1161.86 6855,1770
VUSB_5V0 on Top Layer "Top Layer-VSYS_5V0 5" (solid, pour order 128): 2827.83,242.31 2793.49,242.31 2776.81,258.99 2638.49,258.99 2638.49,173.43 2731.83,173.43 2765.71,207.31 2778.49,207.31 2794.32,223.13 2828.32,223.13 2832.49,227.31 2832.49,238.2 2827.83,242.87
VSYS_5V0 on Top Layer "Top Layer-VSYS_5V0 1" (solid, pour order 98): 5749.01,1632.33 5749.01,1559.19 5590,1559.19 5590,1632.33
VDD_ETH_1V1 on Top Layer "Top Layer-VDD_ETH_1V1" (solid, pour order 78): 6180,1280.86 6135,1280.86 6135,1394.59 6101.86,1427.72 6010,1427.72 6010,1530.63 5996.44,1544.19 5927.62,1544.19 5912.62,1559.19 5849.18,1559.19 5849.18,1631.81 5935,1631.81 5955,1611.81 6180,1611.81
GND on Top Layer "Top Layer-GND 2" (solid, pour order 76): 5571.46,1653.41 5571.46,1789.19 6120,1789.19 6120,1671.81 5954.23,1671.81 5929.53,1647.1 5831.61,1647.1 5831.61,1520.09 5864.09,1520.09 5875,1509.19 5875,1475.21 5945,1475.21 5945,1424.19 5765,1424.19 5765,1653.41
GND on Top Layer "Top Layer-GND 3" (solid, pour order 74): 17 vertices, not listed, extent 5548.66,1005 6115,1370
VDD_ETH_2V5 on Top Layer "Top Layer-VDD_ETH_2V5" (solid, pour order 68): 21 vertices, not listed, extent 5842,947.13 6175,1216.93
VSYS_5V0 on Top Layer "Top Layer-VSYS_5V0 3" (solid, pour order 52): 2744.71,1367.03 2744.71,1395.36 2798.1,1448.75 2798.1,1453.53 2830.96,1453.53 2830.96,1474.47 2562.33,1474.47 2558.59,1470.56 2558.59,1353.13 2730.81,1353.13
GND on Top Layer "Top Layer-GND 4" (solid, pour order 50): 2637.54,1747.26 2827.72,1747.26 2827.72,1637.62 2827.72,1497.62 2789.37,1497.62 2757.41,1529.58 2637.54,1529.58
GND on Top Layer "Top Layer-GND 5" (solid, pour order 48): 2376.04,1245 2170.59,1245 2170.59,996.97 2305.73,996.97 2337.7,965 2376.04,965
VSYS_5V0 on Top Layer "Top Layer-VSYS_5V0 4" (solid, pour order 40): 2279.14,820.52 2290,831.38 2289.53,847.83 2340.32,898.61 2340.31,914.8 2346.43,920.91 2379.29,920.91 2379.29,941.85 2180.61,941.85 2180.61,820.52
VUSB_5V0 on Top Layer "Top Layer-VUSB_5V0" (solid, pour order 24): 17 vertices, not listed, extent 1322.45,377.44 1650,833.18
VSYS_3V3 on Top Layer "Top Layer-VSYS_3V3" (solid, pour order 54): 3017.63,1636.14 3017.63,1743.68 3009.66,1751.65 2882.95,1751.65 2851.04,1719.74 2851.04,1497.62 2880.55,1497.62 2919.19,1536.27 3076.61,1536.27 3076.61,1577.16
TPS62913_2_SW on Top Layer "Top Layer-TPS62913_2_SW" (solid, pour order 62): 2891.67,1482.62 2931.33,1442.96 3076.88,1442.96 3076.88,1488.84 2891.67,1488.84
GND on Top Layer "Top Layer-GND" (solid, pour order 34): 35 vertices, not listed, extent 1427.61,575.44 1969,1132.12
VSYS_3V3 on Top Layer "TOP_LAYER_VSYS_3V3_P280" (solid, remove dead copper, pour order 280): 6799.03,1245.75 6789.52,1255.26 6789.52,1394.59 6805.5,1410.56 6945.22,1410.56 6945.22,1330.88 6860.09,1245.75 6800.03,1245.75
VSYS_3V3 on Top Layer "TOP_LAYER_VSYS_3V3_P271" (solid, pour order 271): 2297.23,1603.6 2297.23,1635.05 2312.16,1649.99 2332.47,1649.99 2342.8,1639.66 2378.87,1603.59 2378.87,1558.52 2262.97,1558.52 2262.97,1590.02 2283.65,1590.02
SHIELD3 on Top Layer "Top Layer-SHIELD3" (solid, pour order 102): 18 vertices, not listed, extent 7210,1277.87 7650,2165
GND on Top Layer "Top Layer-GND 8" (solid, pour order 108): 696.02,230 582.48,230 582.48,36.5 738.53,36.5 738.53,104.22 696.02,146.73
NetR256_2 on Top Layer "Top Layer-NetR256_2" (solid, pour order 231): 4528.38,829.74 4600.43,829.74 4600.43,903.1 4528.38,903.1
SHIELD1 on Top Layer "Top Layer-SHIELD1" (solid, pour order 106): 973.99,331.76 973.99,174.87 1262.25,174.87 1264.76,177.39 1264.76,331.76 1335,331.76 1335,33.93 765.04,33.93 765.04,118.97 779.9,133.83 779.9,233.19 881.02,233.19 881.02,331.76
SHIELD4 on Top Layer "Bottom Layer-SHIELD4" (solid, pour order 176): 15,850 190,850 190,1209.07 270,1289.07 270,1333.26 15,1333.26
GND_XDS on Top Layer "Top Layer-GND_XDS" (solid, pour order 126): 341.8,970.68 589.58,970.68 589.58,1035.94 340.03,1035.94 334.13,1030.03 334.13,977 338.86,972.27
SHIELD2 on Top Layer "Top Layer-SHIELD2" (solid, pour order 100): 7370.4,1140 7370.4,1178.69 7285,1178.69 7285,1050 7250,1050 7250,329.68 7306.81,272.87 7361.33,272.87 7505,416.54 7528.25,439.79 7650,439.79 7650,853.43 7535,853.43 7470,918.43 7470,1140
VSYS_TA_3V3 on Top Layer "Top Layer-VSYS_TA_3V3 1" (solid, pour order 156): 2886.14,347.65 2875.8,337.31 2875.8,293.68 2881.99,287.48 2881.99,253.86 2918.38,253.86 2946.74,282.23 3013.49,282.23 3013.49,431.56 2886.14,431.56
VDD_XDS3V3 on Top Layer "Top Layer-VDD_XDS3V3" (solid, pour order 124): 638.15,905.38 638.15,955.61 475.59,955.61 475.59,905.38
VBUS_XDS_5V0 on Top Layer "Top Layer-VBUS_XDS5V0" (solid, pour order 122): 283.58,998.32 208.94,998.32 208.94,884.78 212.21,880.96 420,880.96 420,912.23 462.24,912.27 462.24,956.17 325.73,956.17
VSD_3V3 on Top Layer "Top Layer-VSD_3V3" (solid, pour order 120): 662.48,692.48 630,660 570.07,660 555.83,645.76 555.83,591.18 563.88,583.13 698.13,583.13 715,600 715,683.1 705.62,692.48
VSYS_5V0_BP_2 on Bottom Layer "NONET_L-01_P-001" (solid, remove dead copper, pour order 291): 4005.65,359.08 4005.65,163.51 4012.88,156.28 4164.52,156.28 4174.91,166.67 4174.91,366.05 4157.88,383.08 4029.72,383.08 4005.73,359.08
GND on Bottom Layer "Bottom Layer-GND 9" (solid, pour order 180): 6654.01,1190.62 6695,1231.61 6695,1340.89 6723.27,1369.16 6723.27,1436.02 6650,1436.02 6650,1508.25 6545,1508.25 6545,1471.48 6545,1468.62 6545,1396.17 6473.24,1396.17 6473.24,1190.62
VDDS_AM263P_LDO_1V8 on Bottom Layer "Bottom Layer-VDDS_AM263_LDO_1V8" (solid, pour order 174): 29 vertices, not listed, extent 3446.81,751.21 4069.75,1493.61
